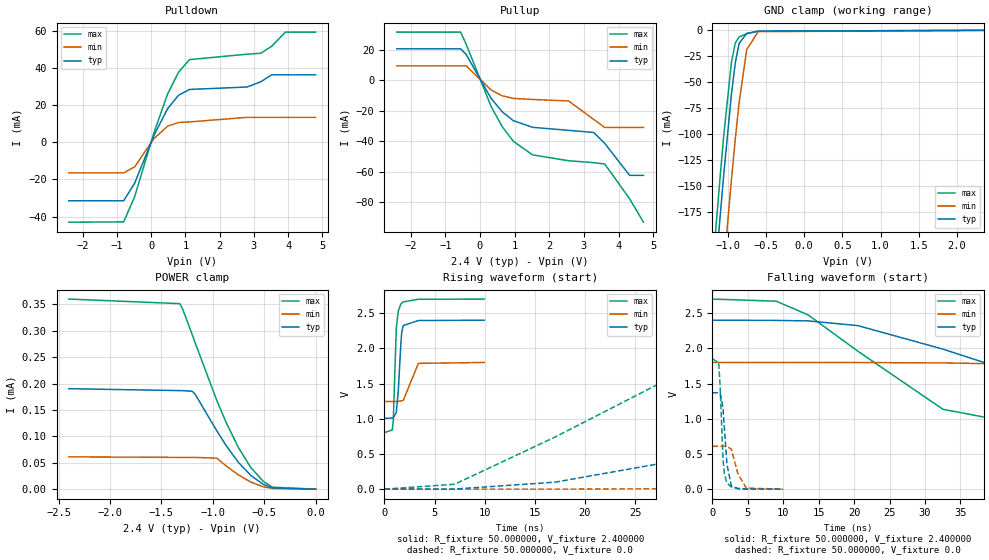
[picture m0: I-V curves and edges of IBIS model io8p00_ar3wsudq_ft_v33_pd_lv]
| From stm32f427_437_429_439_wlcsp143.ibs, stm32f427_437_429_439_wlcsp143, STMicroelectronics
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|   Model io8p00_ar3wsudq_ft_v33_pd_lv
[Model]  io8p00_ar3wsudq_ft_v33_pd_lv
Model_type I/O
Polarity   Non-Inverting
Enable   Active-Low
Vinl =   0.720000V
Vinh =   1.680000V
Vmeas =  1.200000V
Cref =   50.000000pF
Rref =   100.000000M
Vref =   0.0V
C_comp   3.737300pF   3.690400pF   3.817400pF
[Temperature Range]   25.000000   0.125000k   -40.000000
[Pullup Reference]   2.400000V   1.800000V   2.700000V
[Pulldown Reference]   0.0V   0.0V   0.0V
[POWER Clamp Reference]   2.400000V   1.800000V   2.700000V
[GND Clamp Reference]   0.0V   0.0V   0.0V
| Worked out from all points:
|   slope of the pulldown table from 0 to 0.36 V, typ, clamps not added: 25 ohm
|   slope of the pullup table from 0 to 0.36 V, typ, clamps not added: 27.7 ohm
|   GND clamp passes 1 mA (typ) near -0.62 V on its own axis
|   rising waveform, R_fixture 50.000000, V_fixture 2.400000: 20-80 % time 349ps typ, 697ps min, 262ps max; typ from 1 V to 2.4 V
|   rising waveform, R_fixture 50.000000, V_fixture 0.0: 20-80 % time 30.9ns typ, 81.8ns min, 14.6ns max; typ from 0 V to 1.37 V
|   falling waveform, R_fixture 50.000000, V_fixture 2.400000: 20-80 % time 28.8ns typ, 81.1ns min, 15.9ns max; typ from 2.4 V to 1 V
|   falling waveform, R_fixture 50.000000, V_fixture 0.0: 20-80 % time 598ps typ, 1.08ns min, 460ps max; typ from 1.37 V to 0 V
[Pulldown]
|Voltage   I(typ)   I(min)   I(max)
-2.4V     -31.47mA   -16.45mA   -43.01mA
-800mV    -31.47mA   -16.45mA   -42.85mA
-480mV    -21.98mA   -13.17mA   -29.2mA
80mV      3.63mA     1.966mA    5.014mA
480mV     18.15mA    8.738mA    26.02mA
800mV     25.38mA    10.72mA    37.77mA
1.12V     28.53mA    11.02mA    44.6mA
2.8V      29.84mA    13.49mA    47.53mA
3.2V      32.65mA    13.49mA    48.04mA
3.52V     36.4mA     13.49mA    51.82mA
3.92V     36.4mA     13.49mA    59.44mA
4.8V      36.4mA     13.49mA    59.44mA
[Pullup]
|Voltage   I(typ)   I(min)   I(max)
-2.4V     20.88mA    9.66mA     31.89mA
-560mV    20.88mA    9.66mA     31.89mA
-400mV    17.28mA    9.66mA     24.06mA
320mV     -11.75mA   -6.207mA   -17.08mA
640mV     -20.52mA   -10.1mA    -30.35mA
960mV     -26.47mA   -11.82mA   -40.02mA
1.52V     -30.88mA   -12.51mA   -49.05mA
2.56V     -32.88mA   -13.52mA   -52.9mA
3.28V     -34.25mA   -25.62mA   -54.18mA
3.6V      -41.44mA   -30.97mA   -55.03mA
4.32V     -62.55mA   -30.97mA   -77.98mA
4.72V     -62.55mA   -30.97mA   -93.4mA
[GND_clamp]
|Voltage   I(typ)   I(min)   I(max)
-2.4V     -1.437A    -1.518A    -1.411A
-1.25V    -315.9mA   -407.2mA   -278.2mA
-1.2V     -270.1mA   -361.3mA   -232.1mA
-1.15V    -225mA     -316mA     -186.8mA
-1.1V     -180.9mA   -271.3mA   -142.7mA
-1.05V    -138.2mA   -227.5mA   -100.5mA
-950mV    -61.14mA   -143.6mA   -30.44mA
-900mV    -31.24mA   -104.7mA   -12.15mA
-850mV    -12.5mA    -69.41mA   -6.236mA
-750mV    -2.91mA    -18.35mA   -3.195mA
-600mV    -761.5uA   -1.227mA   -751.9uA
2.35V     58.09uA    37.93uA    67.25uA
[POWER_clamp]
|Voltage   I(typ)   I(min)   I(max)
-2.4V     190.2uA    61.19uA    359.9uA
-1.32V    186.6uA    60.14uA    351.2uA
-1.29V    186.5uA    60.13uA    339.6uA
-1.2V     185.4uA    60.11uA    292.6uA
-1.17V    179.2uA    60.11uA    276.3uA
-960mV    110.2uA    58.62uA    167.5uA
-870mV    82.44uA    43.99uA    126.3uA
-750mV    50.58uA    26.92uA    78.64uA
-630mV    25.94uA    13.41uA    41.02uA
-510mV    9.22uA     4.527uA    14.97uA
-420mV    2.425uA    1.38uA     3.75uA
0V        0A         0A         0A
[Ramp]
| variable   typ   min   max
dV/dt_r  0.82164/30.91891n   0.36271/83.80163n   1.11042/14.59118n
dV/dt_f  0.83676/28.74717n   0.32712/81.50714n   1.13681/15.90763n
R_load = 50.000000
[Rising Waveform]
R_fixture= 50.000000
V_fixture= 2.400000
V_fixture_min= 1.800000
V_fixture_max= 2.700000
|time   V(typ)   V(min)   V(max)
0s        1.005V     1.245V     804.1mV
780.8ps   1.01V      1.245V     840.3mV
880.9ps   1.014V     1.245V     966.4mV
1.181ns   1.089V     1.245V     2.284V
1.381ns   1.4V       1.245V     2.531V
1.642ns   2.075V     1.252V     2.629V
1.722ns   2.227V     1.255V     2.641V
1.882ns   2.323V     1.261V     2.659V
3.383ns   2.394V     1.786V     2.696V
9.97ns    2.399V     1.799V     2.699V
[Rising Waveform]
R_fixture= 50.000000
V_fixture= 0.0
V_fixture_min= 0.0
V_fixture_max= 0.0
|time   V(typ)   V(min)   V(max)
0s        9.761nV    346.6nV    28.47nV
7.007ns   1.54mV     -64.27uV   70.11mV
17.02ns   99.44mV    83.53uV    740.5mV
28.03ns   376.7mV    6.55mV     1.543V
34.53ns   556.3mV    13.9mV     1.715V
42.04ns   772.7mV    39.34mV    1.788V
59.56ns   1.171V     98.7mV     1.837V
79.08ns   1.312V     190.1mV    1.847V
153.2ns   1.367V     509.6mV    1.851V
249.2ns   1.369V     608.5mV    1.851V
[Falling Waveform]
R_fixture= 50.000000
V_fixture= 2.400000
V_fixture_min= 1.800000
V_fixture_max= 2.700000
|time   V(typ)   V(min)   V(max)
0s        2.399V     1.799V     2.699V
9.009ns   2.396V     1.798V     2.669V
13.51ns   2.389V     1.798V     2.474V
20.52ns   2.322V     1.798V     1.959V
32.53ns   1.988V     1.793V     1.134V
44.54ns   1.595V     1.771V     904.7mV
58.06ns   1.268V     1.726V     851.9mV
82.58ns   1.086V     1.593V     820.1mV
156.2ns   1.012V     1.324V     804.6mV
249.2ns   1.005V     1.245V     804.1mV
[Falling Waveform]
R_fixture= 50.000000
V_fixture= 0.0
V_fixture_min= 0.0
V_fixture_max= 0.0
|time   V(typ)   V(min)   V(max)
0s        1.369V     608.5mV    1.851V
900.9ps   1.37V      608.3mV    1.796V
1.101ns   1.366V     608.2mV    1.449V
1.502ns   1.15V      607.9mV    430mV
1.702ns   857.3mV    608.1mV    212.3mV
2.062ns   350.1mV    607.9mV    85.53mV
2.683ns   43.62mV    566.1mV    31.54mV
3.584ns   7.834mV    224.6mV    10.48mV
4.785ns   2.189mV    14.68mV    3.209mV
9.97ns    9.761nV    346.6nV    28.47nV
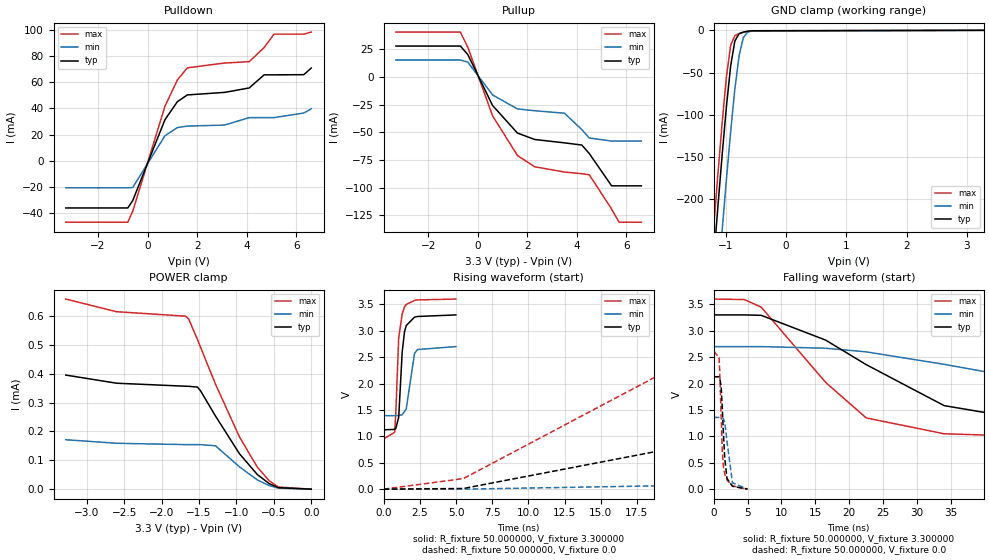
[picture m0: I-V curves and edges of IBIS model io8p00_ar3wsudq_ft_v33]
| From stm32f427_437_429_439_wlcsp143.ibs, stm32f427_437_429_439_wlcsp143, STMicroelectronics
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|   Model io8p00_ar3wsudq_ft_v33
[Model]  io8p00_ar3wsudq_ft_v33
Model_type I/O
Polarity   Non-Inverting
Enable   Active-Low
Vinl =   0.990000V
Vinh =   2.310000V
Vmeas =  1.650000V
Cref =   50.000000pF
Rref =   100.000000M
Vref =   0.0V
C_comp   3.857500pF   3.762100pF   3.941700pF
[Temperature Range]   25.000000   0.125000k   -40.000000
[Pullup Reference]   3.300000V   2.700000V   3.600000V
[Pulldown Reference]   0.0V   0.0V   0.0V
[POWER Clamp Reference]   3.300000V   2.700000V   3.600000V
[GND Clamp Reference]   0.0V   0.0V   0.0V
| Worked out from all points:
|   slope of the pulldown table from 0 to 0.495 V, typ, clamps not added: 20.9 ohm
|   slope of the pullup table from 0 to 0.495 V, typ, clamps not added: 22.6 ohm
|   GND clamp passes 1 mA (typ) near -0.62 V on its own axis
|   rising waveform, R_fixture 50.000000, V_fixture 3.300000: 20-80 % time 277ps typ, 397ps min, 273ps max; typ from 1.12 V to 3.3 V
|   rising waveform, R_fixture 50.000000, V_fixture 0.0: 20-80 % time 19.7ns typ, 51.8ns min, 10.4ns max; typ from 0 V to 2.13 V
|   falling waveform, R_fixture 50.000000, V_fixture 3.300000: 20-80 % time 18.7ns typ, 38.4ns min, 11.3ns max; typ from 3.3 V to 1.12 V
|   falling waveform, R_fixture 50.000000, V_fixture 0.0: 20-80 % time 513ps typ, 709ps min, 438ps max; typ from 2.13 V to 0 V
[Pulldown]
|Voltage   I(typ)   I(min)   I(max)
-3.3V     -36.18mA   -20.77mA   -47.07mA
-800mV    -36.18mA   -20.77mA   -47.07mA
-600mV    -30.5mA    -20.52mA   -38.69mA
700mV     31.4mA     19.11mA    41.71mA
1.2V      45.15mA    25.37mA    61.75mA
1.6V      50.35mA    26.5mA     71.06mA
3.1V      52.28mA    27.26mA    74.76mA
4.1V      55.7mA     32.99mA    75.8mA
4.7V      65.72mA    32.99mA    86.64mA
5.1V      65.72mA    32.99mA    96.89mA
6.3V      65.85mA    36.5mA     96.89mA
6.6V      70.91mA    39.71mA    98.45mA
[Pullup]
|Voltage   I(typ)   I(min)   I(max)
-3.3V     28.03mA    15.43mA    40.67mA
-700mV    28.03mA    15.43mA    40.67mA
-400mV    20.31mA    13.47mA    26.93mA
600mV     -25.77mA   -16.23mA   -35.14mA
1.6V      -50.64mA   -28.81mA   -70.96mA
2.3V      -56.49mA   -30.48mA   -81.16mA
3.5V      -59.53mA   -32.72mA   -85.92mA
4.2V      -61.52mA   -47.6mA    -87.46mA
4.5V      -69.21mA   -55.14mA   -88.43mA
5.4V      -98.4mA    -57.9mA    -119.4mA
5.7V      -98.4mA    -57.9mA    -131.3mA
6.6V      -98.4mA    -57.9mA    -131.3mA
[GND_clamp]
|Voltage   I(typ)   I(min)   I(max)
-3.3V     -2.333A    -2.407A    -2.313A
-1.2V     -270.2mA   -361.4mA   -232.1mA
-1.13V    -207.3mA   -298.1mA   -169mA
-1.06V    -146.7mA   -236.2mA   -108.8mA
-990mV    -90.18mA   -176.4mA   -54.96mA
-920mV    -42.21mA   -120mA     -17.68mA
-850mV    -12.57mA   -69.47mA   -6.265mA
-780mV    -3.971mA   -30.01mA   -3.886mA
-710mV    -2.1mA     -8.615mA   -2.382mA
-640mV    -1.148mA   -2.283mA   -1.22mA
-570mV    -524uA     -821.5uA   -476.8uA
3.28V     0A         0A         0A
[POWER_clamp]
|Voltage   I(typ)   I(min)   I(max)
-3.28V    395.3uA    171.3uA    658.7uA
-2.6V     367.1uA    159uA      614.9uA
-1.68V    356.7uA    154.4uA    599.4uA
-1.64V    356.5uA    154.4uA    590.8uA
-1.52V    353.6uA    154.3uA    518.3uA
-1.48V    341.1uA    154.2uA    492.3uA
-1.28V    253.6uA    150.4uA    364.2uA
-960mV    123.1uA    77.55uA    181.6uA
-720mV    50.52uA    32.03uA    76.18uA
-560mV    18.94uA    12.27uA    28.65uA
-440mV    5.104uA    3.69uA     7.327uA
0V        0A         0A         0A
[Ramp]
| variable   typ   min   max
dV/dt_r  1.27746/19.65175n   0.81588/51.88811n   1.56732/10.37905n
dV/dt_f  1.30614/18.70701n   0.78516/38.53888n   1.58789/11.29546n
R_load = 50.000000
[Rising Waveform]
R_fixture= 50.000000
V_fixture= 3.300000
V_fixture_min= 2.700000
V_fixture_max= 3.600000
|time   V(typ)   V(min)   V(max)
0s        1.124V     1.392V     953.5mV
760.8ps   1.132V     1.392V     1.076V
840.8ps   1.151V     1.391V     1.456V
1.041ns   1.364V     1.395V     2.868V
1.281ns   2.596V     1.409V     3.319V
1.441ns   2.981V     1.47V      3.453V
1.562ns   3.099V     1.521V     3.499V
2.132ns   3.257V     2.57V      3.573V
2.332ns   3.27V      2.644V     3.584V
4.985ns   3.3V       2.7V       3.6V
[Rising Waveform]
R_fixture= 50.000000
V_fixture= 0.0
V_fixture_min= 0.0
V_fixture_max= 0.0
|time   V(typ)   V(min)   V(max)
0s        123nV      341.2nV    642.2nV
5.506ns   12.51mV    -98.27uV   200.2mV
19.02ns   723.2mV    63.71mV    2.159V
24.52ns   1.102V     131.1mV    2.43V
32.03ns   1.585V     254.6mV    2.545V
40.04ns   1.897V     386.3mV    2.579V
55.06ns   2.058V     671.8mV    2.605V
87.09ns   2.117V     1.114V     2.612V
117.6ns   2.129V     1.302V     2.612V
249.2ns   2.129V     1.359V     2.612V
[Falling Waveform]
R_fixture= 50.000000
V_fixture= 3.300000
V_fixture_min= 2.700000
V_fixture_max= 3.600000
|time   V(typ)   V(min)   V(max)
0s        3.3V       2.7V       3.6V
4.505ns   3.3V       2.7V       3.591V
7.007ns   3.292V     2.7V       3.446V
16.52ns   2.823V     2.669V     2.022V
22.52ns   2.358V     2.6V       1.349V
34.03ns   1.582V     2.364V     1.049V
49.55ns   1.246V     2.005V     988.1mV
63.06ns   1.182V     1.721V     967.3mV
90.59ns   1.144V     1.508V     956.1mV
249.2ns   1.124V     1.392V     953.5mV
[Falling Waveform]
R_fixture= 50.000000
V_fixture= 0.0
V_fixture_min= 0.0
V_fixture_max= 0.0
|time   V(typ)   V(min)   V(max)
0s        2.129V     1.359V     2.612V
780.8ps   2.127V     1.358V     2.49V
860.9ps   2.119V     1.358V     2.294V
1.091ns   1.943V     1.358V     1.362V
1.261ns   1.524V     1.354V     724.3mV
1.411ns   1.094V     1.342V     441mV
1.622ns   576.2mV    1.263V     285.2mV
1.962ns   200.1mV    894.1mV    172.1mV
2.763ns   54.16mV    120.1mV    64.24mV
4.985ns   123nV      341.2nV    642.2nV
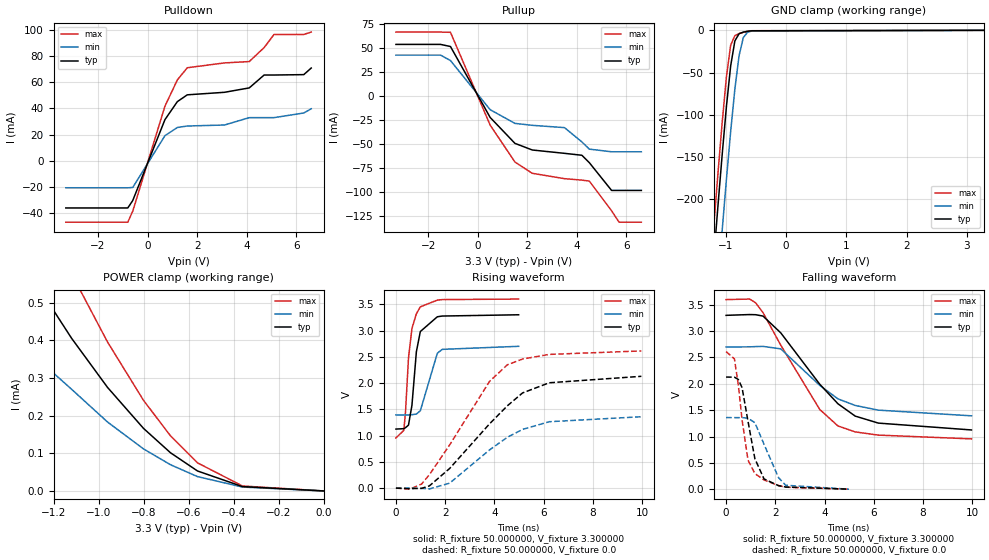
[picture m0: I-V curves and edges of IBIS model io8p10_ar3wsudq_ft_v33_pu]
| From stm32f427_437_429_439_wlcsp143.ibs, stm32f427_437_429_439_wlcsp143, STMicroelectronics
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|   Model io8p10_ar3wsudq_ft_v33_pu
[Model]  io8p10_ar3wsudq_ft_v33_pu
Model_type I/O
Polarity   Non-Inverting
Enable   Active-Low
Vinl =   0.990000V
Vinh =   2.310000V
Vmeas =  1.650000V
Cref =   40.000000pF
Rref =   100.000000M
Vref =   0.0V
C_comp   3.857500pF   3.760500pF   3.941700pF
[Temperature Range]   25.000000   0.125000k   -40.000000
[Pullup Reference]   3.300000V   2.700000V   3.600000V
[Pulldown Reference]   0.0V   0.0V   0.0V
[POWER Clamp Reference]   3.300000V   2.700000V   3.600000V
[GND Clamp Reference]   0.0V   0.0V   0.0V
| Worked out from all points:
|   slope of the pulldown table from 0 to 0.495 V, typ, clamps not added: 20.9 ohm
|   slope of the pullup table from 0 to 0.495 V, typ, clamps not added: 22.6 ohm
|   GND clamp passes 1 mA (typ) near -0.62 V on its own axis
|   POWER clamp passes 1 mA (typ) near -1.88 V on its own axis
|   rising waveform, R_fixture 50.000000, V_fixture 3.300000: 20-80 % time 276ps typ, 399ps min, 273ps max; typ from 1.12 V to 3.3 V
|   rising waveform, R_fixture 50.000000, V_fixture 0.0: 20-80 % time 2.56ns typ, 2.3ns min, 2.13ns max; typ from 0.001 V to 2.13 V
|   falling waveform, R_fixture 50.000000, V_fixture 3.300000: 20-80 % time 2.28ns typ, 2.12ns min, 2.02ns max; typ from 3.3 V to 1.12 V
|   falling waveform, R_fixture 50.000000, V_fixture 0.0: 20-80 % time 517ps typ, 710ps min, 442ps max; typ from 2.13 V to 0.001 V
[Pulldown]
|Voltage   I(typ)   I(min)   I(max)
-3.3V     -36.18mA   -20.77mA   -47.07mA
-800mV    -36.18mA   -20.77mA   -47.07mA
-600mV    -30.5mA    -20.52mA   -38.69mA
700mV     31.4mA     19.11mA    41.71mA
1.2V      45.15mA    25.37mA    61.75mA
1.6V      50.35mA    26.5mA     71.06mA
3.1V      52.28mA    27.26mA    74.76mA
4.1V      55.65mA    32.9mA     75.79mA
4.7V      65.5mA     32.9mA     86.49mA
5.1V      65.5mA     32.9mA     96.53mA
6.3V      65.8mA     36.47mA    96.53mA
6.6V      70.85mA    39.68mA    98.34mA
[Pullup]
|Voltage   I(typ)   I(min)   I(max)
-3.3V     54.04mA    42.87mA    66.88mA
-1.5V     54.04mA    42.87mA    66.88mA
-1.1V     51.84mA    37.21mA    66.66mA
500mV     -22.06mA   -14mA      -30.03mA
1.5V      -49.1mA    -28.3mA    -68.56mA
2.2V      -56.04mA   -30.32mA   -80.35mA
3.5V      -59.52mA   -32.72mA   -85.91mA
4.2V      -61.52mA   -47.6mA    -87.45mA
4.5V      -69.2mA    -55.14mA   -88.43mA
5.4V      -98.2mA    -57.9mA    -119.4mA
5.7V      -98.2mA    -57.9mA    -131.3mA
6.6V      -98.2mA    -57.9mA    -131.3mA
[GND_clamp]
|Voltage   I(typ)   I(min)   I(max)
-3.3V     -2.333A    -2.407A    -2.313A
-1.2V     -270.2mA   -361.4mA   -232.1mA
-1.13V    -207.3mA   -298.1mA   -169mA
-1.06V    -146.7mA   -236.2mA   -108.8mA
-990mV    -90.18mA   -176.4mA   -54.96mA
-920mV    -42.21mA   -120mA     -17.68mA
-850mV    -12.57mA   -69.47mA   -6.265mA
-780mV    -3.971mA   -30.01mA   -3.886mA
-710mV    -2.1mA     -8.615mA   -2.382mA
-640mV    -1.148mA   -2.283mA   -1.22mA
-570mV    -524uA     -821.5uA   -476.8uA
3.28V     0A         0A         0A
[POWER_clamp]
|Voltage   I(typ)   I(min)   I(max)
-3.28V    1.18mA     571.5uA    1.791mA
-3.08V    1.154mA    558.1uA    1.753mA
-1.84V    973.4uA    557.7uA    1.433mA
-1.32V    593.1uA    370.2uA    831.6uA
-1.28V    553.9uA    355.9uA    778.7uA
-1.12V    406uA      270.4uA    577.3uA
-960mV    275.2uA    183.2uA    395.9uA
-800mV    166.2uA    111.7uA    240.7uA
-680mV    101.4uA    69.6uA     146.3uA
-560mV    53.02uA    38.04uA    74.62uA
-360mV    11.49uA    10.29uA    13.1uA
0V        0A         0A         0A
[Ramp]
| variable   typ   min   max
dV/dt_r  1.26865/2.56356n   0.81309/2.32076n   1.56544/2.13478n
dV/dt_f  1.28424/2.27464n   0.77712/2.11344n   1.57500/2.02473n
R_load = 50.000000
[Rising Waveform]
R_fixture= 50.000000
V_fixture= 3.300000
V_fixture_min= 2.700000
V_fixture_max= 3.600000
|time   V(typ)   V(min)   V(max)
0s        1.125V     1.393V     955.5mV
320.3ps   1.133V     1.393V     1.1V
390.4ps   1.152V     1.393V     1.457V
510.5ps   1.201V     1.394V     2.481V
650.7ps   1.578V     1.399V     3.039V
830.8ps   2.596V     1.411V     3.319V
991ps     2.981V     1.473V     3.451V
1.682ns   3.262V     2.568V     3.579V
1.882ns   3.276V     2.642V     3.589V
4.985ns   3.3V       2.7V       3.599V
[Rising Waveform]
R_fixture= 50.000000
V_fixture= 0.0
V_fixture_min= 0.0
V_fixture_max= 0.0
|time   V(typ)   V(min)   V(max)
0s        1.284mV    1.127mV    1.85mV
560.6ps   -8.608mV   984.2uV    -18.37mV
1.041ns   -3.407mV   -3.558mV   78.58mV
1.361ns   44.45mV    -13.92mV   256.9mV
2.182ns   375.2mV    95.85mV    823.6mV
3.804ns   1.225V     728.9mV    2.033V
4.525ns   1.567V     968.2mV    2.348V
5.145ns   1.813V     1.119V     2.458V
6.226ns   2.006V     1.265V     2.546V
9.97ns    2.129V     1.36V      2.612V
[Falling Waveform]
R_fixture= 50.000000
V_fixture= 3.300000
V_fixture_min= 2.700000
V_fixture_max= 3.600000
|time   V(typ)   V(min)   V(max)
0s        3.3V       2.7V       3.599V
961ps     3.315V     2.702V     3.609V
1.201ns   3.312V     2.707V     3.538V
1.502ns   3.286V     2.711V     3.352V
2.222ns   2.968V     2.664V     2.734V
3.804ns   1.994V     1.972V     1.515V
4.545ns   1.622V     1.715V     1.201V
5.245ns   1.388V     1.59V      1.088V
6.186ns   1.255V     1.501V     1.027V
9.97ns    1.125V     1.393V     955.5mV
[Falling Waveform]
R_fixture= 50.000000
V_fixture= 0.0
V_fixture_min= 0.0
V_fixture_max= 0.0
|time   V(typ)   V(min)   V(max)
0s        2.129V     1.36V      2.612V
340.3ps   2.126V     1.359V     2.474V
500.5ps   2.082V     1.359V     1.971V
650.7ps   1.927V     1.359V     1.316V
890.9ps   1.293V     1.348V     553.2mV
1.171ns   578.3mV    1.263V     297.1mV
1.542ns   196mV      853.8mV    175.2mV
2.132ns   67.97mV    220.1mV    69.64mV
2.422ns   41.74mV    74.93mV    38.22mV
4.985ns   1.284mV    1.127mV    1.85mV
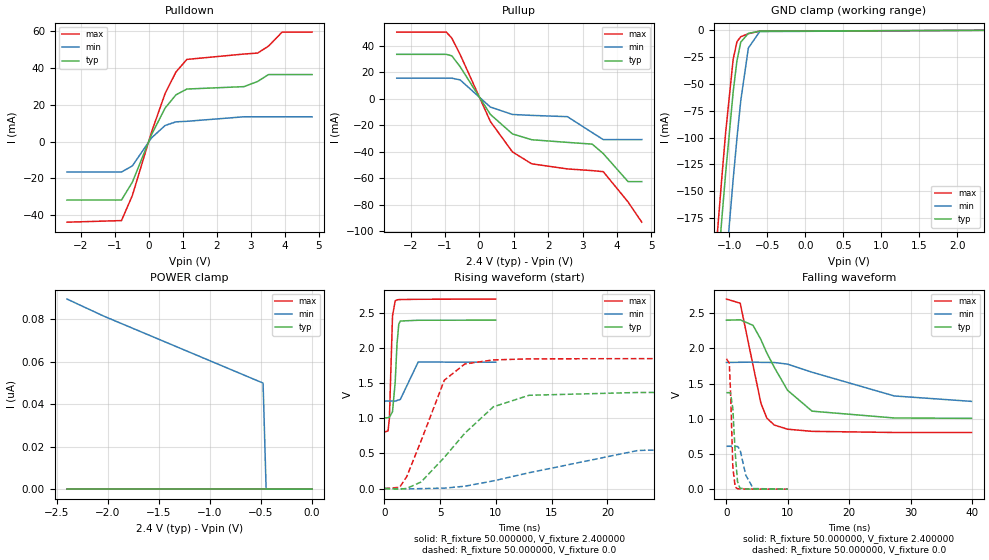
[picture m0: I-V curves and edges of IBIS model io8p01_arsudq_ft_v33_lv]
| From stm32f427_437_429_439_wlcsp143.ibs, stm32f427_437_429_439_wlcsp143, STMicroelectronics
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|   Model io8p01_arsudq_ft_v33_lv
[Model]  io8p01_arsudq_ft_v33_lv
Model_type I/O
Polarity   Non-Inverting
Enable   Active-Low
Vinl =   0.720000V
Vinh =   1.680000V
Vmeas =  1.200000V
Cref =   50.000000pF
Rref =   100.000000M
Vref =   0.0V
C_comp   2.238700pF   2.180600pF   2.332300pF
[Temperature Range]   25.000000   0.125000k   -40.000000
[Pullup Reference]   2.400000V   1.800000V   2.700000V
[Pulldown Reference]   0.0V   0.0V   0.0V
[POWER Clamp Reference]   2.400000V   1.800000V   2.700000V
[GND Clamp Reference]   0.0V   0.0V   0.0V
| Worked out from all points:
|   slope of the pulldown table from 0 to 0.36 V, typ, clamps not added: 25 ohm
|   slope of the pullup table from 0 to 0.36 V, typ, clamps not added: 27.7 ohm
|   GND clamp passes 1 mA (typ) near -0.62 V on its own axis
|   rising waveform, R_fixture 50.000000, V_fixture 2.400000: 20-80 % time 302ps typ, 741ps min, 199ps max; typ from 1.01 V to 2.4 V
|   rising waveform, R_fixture 50.000000, V_fixture 0.0: 20-80 % time 4.9ns typ, 9.96ns min, 2.66ns max; typ from 0 V to 1.37 V
|   falling waveform, R_fixture 50.000000, V_fixture 2.400000: 20-80 % time 5.51ns typ, 12.6ns min, 2.64ns max; typ from 2.4 V to 1.01 V
|   falling waveform, R_fixture 50.000000, V_fixture 0.0: 20-80 % time 534ps typ, 1.03ns min, 386ps max; typ from 1.37 V to 0 V
[Pulldown]
|Voltage   I(typ)   I(min)   I(max)
-2.4V     -31.73mA   -16.51mA   -43.74mA
-800mV    -31.73mA   -16.51mA   -42.87mA
-480mV    -21.98mA   -13.17mA   -29.21mA
80mV      3.63mA     1.966mA    5.014mA
480mV     18.16mA    8.738mA    26.02mA
800mV     25.38mA    10.72mA    37.77mA
1.12V     28.53mA    11.02mA    44.6mA
2.8V      29.84mA    13.47mA    47.53mA
3.2V      32.64mA    13.47mA    48.05mA
3.52V     36.39mA    13.47mA    51.83mA
3.92V     36.39mA    13.47mA    59.44mA
4.8V      36.39mA    13.47mA    59.44mA
[Pullup]
|Voltage   I(typ)   I(min)   I(max)
-2.4V     33.56mA    15.56mA    50.34mA
-960mV    33.56mA    15.56mA    50.34mA
-800mV    32.44mA    15.56mA    45.79mA
-560mV    24.29mA    14.3mA     33.55mA
320mV     -11.75mA   -6.207mA   -17.08mA
960mV     -26.47mA   -11.82mA   -40.02mA
1.52V     -30.88mA   -12.51mA   -49.05mA
2.56V     -32.88mA   -13.48mA   -52.9mA
3.28V     -34.19mA   -25.51mA   -54.18mA
3.6V      -41.31mA   -30.75mA   -54.97mA
4.32V     -62.47mA   -30.75mA   -77.8mA
4.72V     -62.47mA   -30.75mA   -93.1mA
[GND_clamp]
|Voltage   I(typ)   I(min)   I(max)
-2.4V     -1.424A    -1.508A    -1.394A
-1.25V    -311.2mA   -401.9mA   -273.3mA
-1.2V     -265.4mA   -356.1mA   -227.2mA
-1.15V    -220.4mA   -310.8mA   -181.9mA
-1.1V     -176.3mA   -266.2mA   -137.9mA
-1.05V    -133.8mA   -222.5mA   -95.87mA
-950mV    -57.3mA    -138.9mA   -26.98mA
-900mV    -28.27mA   -100.4mA   -10.59mA
-850mV    -11.01mA   -65.54mA   -5.958mA
-750mV    -2.834mA   -16.5mA    -3.178mA
-600mV    -750uA     -1.164mA   -738.3uA
2.35V     0A         0A         0A
[POWER_clamp]
|Voltage   I(typ)   I(min)   I(max)
-2.4V     0A         89.62nA    0A
-2.04V    0A         81.57nA    0A
-480mV    0A         50.01nA    0A
-450mV    0A         0A         0A
0V        0A         0A         0A
[Ramp]
| variable   typ   min   max
dV/dt_r  0.82230/4.90012n   0.36466/9.97943n   1.11102/2.65313n
dV/dt_f  0.83742/5.51561n   0.32238/12.65743n   1.13729/2.63895n
R_load = 50.000000
[Rising Waveform]
R_fixture= 50.000000
V_fixture= 2.400000
V_fixture_min= 1.800000
V_fixture_max= 2.700000
|time   V(typ)   V(min)   V(max)
0s        1.006V     1.247V     804.9mV
320.3ps   1.01V      1.247V     823.1mV
440.4ps   1.016V     1.247V     998.4mV
720.7ps   1.095V     1.247V     2.461V
961ps     1.515V     1.246V     2.674V
1.121ns   2.055V     1.255V     2.689V
1.281ns   2.341V     1.263V     2.692V
1.421ns   2.387V     1.27V      2.693V
3.023ns   2.398V     1.803V     2.697V
9.97ns    2.4V       1.8V       2.7V
[Rising Waveform]
R_fixture= 50.000000
V_fixture= 0.0
V_fixture_min= 0.0
V_fixture_max= 0.0
|time   V(typ)   V(min)   V(max)
0s        85.02uV    35.48uV    197.3uV
1.361ns   -8.671mV   -381.4uV   17.59mV
2.002ns   2.237mV    -5.156mV   171.2mV
3.283ns   93.41mV    -544.3uV   679.4mV
5.365ns   443mV      5.672mV    1.543V
7.207ns   788.6mV    33.23mV    1.775V
9.77ns    1.165V     109.4mV    1.833V
12.97ns   1.329V     225.1mV    1.848V
22.74ns   1.369V     542.9mV    1.851V
39.88ns   1.37V      609.1mV    1.851V
[Falling Waveform]
R_fixture= 50.000000
V_fixture= 2.400000
V_fixture_min= 1.800000
V_fixture_max= 2.700000
|time   V(typ)   V(min)   V(max)
0s        2.4V       1.8V       2.7V
2.242ns   2.405V     1.802V     2.641V
4.324ns   2.327V     1.804V     1.761V
5.606ns   2.125V     1.801V     1.222V
6.567ns   1.936V     1.8V       1.01V
7.768ns   1.733V     1.799V     911.5mV
9.93ns    1.406V     1.776V     851.8mV
13.93ns   1.108V     1.661V     821.1mV
27.31ns   1.011V     1.324V     805mV
39.88ns   1.006V     1.247V     804.9mV
[Falling Waveform]
R_fixture= 50.000000
V_fixture= 0.0
V_fixture_min= 0.0
V_fixture_max= 0.0
|time   V(typ)   V(min)   V(max)
0s        1.37V      609.1mV    1.851V
460.5ps   1.371V     609mV      1.79V
660.7ps   1.366V     608.9mV    1.398V
1.041ns   1.145V     608.6mV    311.2mV
1.421ns   522.3mV    609.5mV    31.05mV
1.802ns   107.2mV    606.2mV    6.965mV
2.202ns   14.25mV    565mV      3.617mV
3.143ns   1.993mV    199.7mV    2.02mV
4.364ns   1.129mV    8.676mV    1.136mV
9.97ns    85.02uV    35.48uV    197.3uV
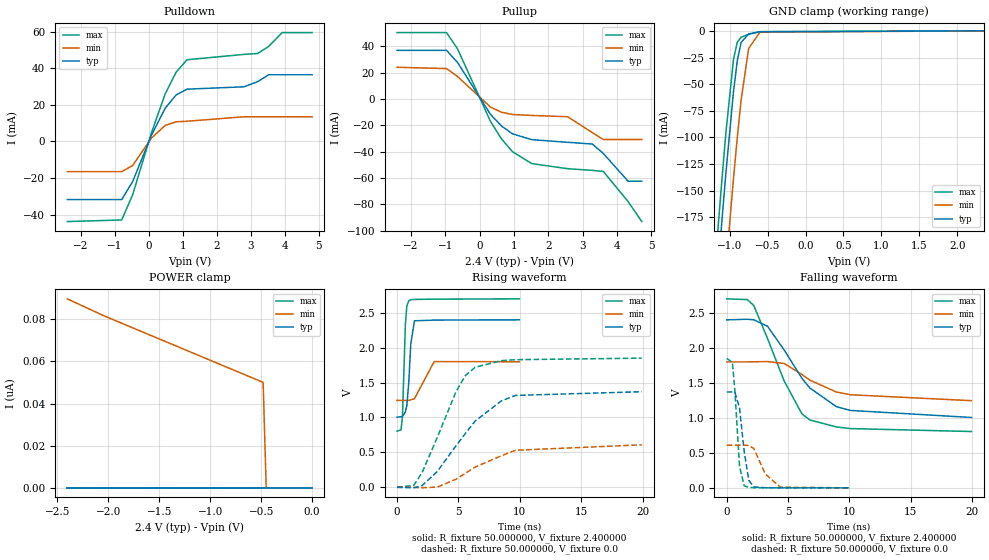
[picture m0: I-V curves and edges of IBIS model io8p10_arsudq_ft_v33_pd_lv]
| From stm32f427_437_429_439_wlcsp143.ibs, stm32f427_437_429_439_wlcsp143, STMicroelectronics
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|   Model io8p10_arsudq_ft_v33_pd_lv
[Model]  io8p10_arsudq_ft_v33_pd_lv
Model_type I/O
Polarity   Non-Inverting
Enable   Active-Low
Vinl =   0.720000V
Vinh =   1.680000V
Vmeas =  1.200000V
Cref =   40.000000pF
Rref =   100.000000M
Vref =   0.0V
C_comp   2.238700pF   2.180600pF   2.332300pF
[Temperature Range]   25.000000   0.125000k   -40.000000
[Pullup Reference]   2.400000V   1.800000V   2.700000V
[Pulldown Reference]   0.0V   0.0V   0.0V
[POWER Clamp Reference]   2.400000V   1.800000V   2.700000V
[GND Clamp Reference]   0.0V   0.0V   0.0V
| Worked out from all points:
|   slope of the pulldown table from 0 to 0.36 V, typ, clamps not added: 25 ohm
|   slope of the pullup table from 0 to 0.36 V, typ, clamps not added: 27.7 ohm
|   GND clamp passes 1 mA (typ) near -0.62 V on its own axis
|   rising waveform, R_fixture 50.000000, V_fixture 2.400000: 20-80 % time 303ps typ, 746ps min, 199ps max; typ from 1 V to 2.4 V
|   rising waveform, R_fixture 50.000000, V_fixture 0.0: 20-80 % time 3.77ns typ, 4.16ns min, 2.69ns max; typ from 0 V to 1.37 V
|   falling waveform, R_fixture 50.000000, V_fixture 2.400000: 20-80 % time 3.57ns typ, 3.55ns min, 2.74ns max; typ from 2.4 V to 1 V
|   falling waveform, R_fixture 50.000000, V_fixture 0.0: 20-80 % time 534ps typ, 1.04ns min, 386ps max; typ from 1.37 V to 0 V
[Pulldown]
|Voltage   I(typ)   I(min)   I(max)
-2.4V     -31.73mA   -16.51mA   -43.74mA
-800mV    -31.73mA   -16.51mA   -42.87mA
-480mV    -21.98mA   -13.17mA   -29.2mA
80mV      3.63mA     1.966mA    5.014mA
480mV     18.15mA    8.738mA    26.02mA
800mV     25.38mA    10.72mA    37.77mA
1.12V     28.53mA    11.02mA    44.6mA
2.8V      29.84mA    13.47mA    47.53mA
3.2V      32.64mA    13.47mA    48.04mA
3.52V     36.39mA    13.47mA    51.82mA
3.92V     36.39mA    13.47mA    59.43mA
4.8V      36.39mA    13.47mA    59.43mA
[Pullup]
|Voltage   I(typ)   I(min)   I(max)
-2.4V     36.88mA    24.03mA    50.34mA
-960mV    36.88mA    23.04mA    50.34mA
-640mV    27.65mA    17.03mA    37.99mA
320mV     -11.75mA   -6.207mA   -17.08mA
640mV     -20.52mA   -10.1mA    -30.35mA
960mV     -26.47mA   -11.82mA   -40.02mA
1.52V     -30.88mA   -12.51mA   -49.05mA
2.56V     -32.88mA   -13.48mA   -52.9mA
3.28V     -34.19mA   -25.5mA    -54.18mA
3.6V      -41.31mA   -30.74mA   -54.97mA
4.32V     -62.39mA   -30.74mA   -77.8mA
4.72V     -62.39mA   -30.74mA   -93mA
[GND_clamp]
|Voltage   I(typ)   I(min)   I(max)
-2.4V     -1.424A    -1.508A    -1.394A
-1.25V    -311.2mA   -401.9mA   -273.3mA
-1.2V     -265.4mA   -356.1mA   -227.2mA
-1.15V    -220.4mA   -310.8mA   -181.9mA
-1.1V     -176.3mA   -266.2mA   -137.9mA
-1.05V    -133.8mA   -222.5mA   -95.87mA
-950mV    -57.3mA    -138.9mA   -26.99mA
-900mV    -28.28mA   -100.4mA   -10.6mA
-850mV    -11.02mA   -65.54mA   -5.972mA
-750mV    -2.846mA   -16.51mA   -3.192mA
-600mV    -761.3uA   -1.173mA   -751.9uA
2.35V     58.09uA    37.92uA    67.25uA
[POWER_clamp]
|Voltage   I(typ)   I(min)   I(max)
-2.4V     0A         89.62nA    0A
-2.04V    0A         81.57nA    0A
-480mV    0A         50.01nA    0A
-450mV    0A         0A         0A
0V        0A         0A         0A
[Ramp]
| variable   typ   min   max
dV/dt_r  0.82152/3.76780n   0.36550/4.16535n   1.11354/2.69964n
dV/dt_f  0.83376/3.57769n   0.33414/3.59897n   1.13623/2.74074n
R_load = 50.000000
[Rising Waveform]
R_fixture= 50.000000
V_fixture= 2.400000
V_fixture_min= 1.800000
V_fixture_max= 2.700000
|time   V(typ)   V(min)   V(max)
0s        1.005V     1.245V     804.5mV
320.3ps   1.01V      1.245V     822.5mV
440.4ps   1.015V     1.245V     1.001V
680.7ps   1.08V      1.245V     2.331V
800.8ps   1.171V     1.245V     2.598V
961ps     1.513V     1.245V     2.672V
1.121ns   2.054V     1.253V     2.687V
1.421ns   2.385V     1.269V     2.691V
3.023ns   2.395V     1.8V       2.695V
9.97ns    2.399V     1.799V     2.699V
[Rising Waveform]
R_fixture= 50.000000
V_fixture= 0.0
V_fixture_min= 0.0
V_fixture_max= 0.0
|time   V(typ)   V(min)   V(max)
0s        75.03uV    35.24uV    234.9uV
1.361ns   -7.739mV   -507.1uV   28.08mV
2.042ns   23.59mV    -6.464mV   210.7mV
3.283ns   227.4mV    3.255mV    716.1mV
4.805ns   595.4mV    116mV      1.37V
5.566ns   770.1mV    200.9mV    1.601V
6.366ns   948.7mV    290.4mV    1.719V
8.488ns   1.237V     450.2mV    1.814V
9.65ns    1.316V     530.7mV    1.828V
19.94ns   1.369V     608.5mV    1.85V
[Falling Waveform]
R_fixture= 50.000000
V_fixture= 2.400000
V_fixture_min= 1.800000
V_fixture_max= 2.700000
|time   V(typ)   V(min)   V(max)
0s        2.399V     1.799V     2.699V
1.682ns   2.408V     1.799V     2.689V
2.202ns   2.4V       1.801V     2.604V
3.323ns   2.308V     1.803V     2.133V
4.685ns   1.967V     1.776V     1.524V
6.126ns   1.565V     1.619V     1.056V
6.767ns   1.427V     1.538V     969.7mV
8.929ns   1.16V      1.369V     870.1mV
10.05ns   1.106V     1.33V      846.5mV
19.94ns   1.005V     1.245V     804.5mV
[Falling Waveform]
R_fixture= 50.000000
V_fixture= 0.0
V_fixture_min= 0.0
V_fixture_max= 0.0
|time   V(typ)   V(min)   V(max)
0s        1.369V     608.5mV    1.85V
460.5ps   1.37V      608.3mV    1.789V
660.7ps   1.365V     608.2mV    1.395V
1.041ns   1.144V     608mV      311.2mV
1.421ns   520.2mV    608.9mV    29mV
1.802ns   105.6mV    604.9mV    5.493mV
2.202ns   13.52mV    562.8mV    2.496mV
3.143ns   1.822mV    198.3mV    1.459mV
4.364ns   959.6uV    9.504mV    935.4uV
9.97ns    75.03uV    35.24uV    234.9uV
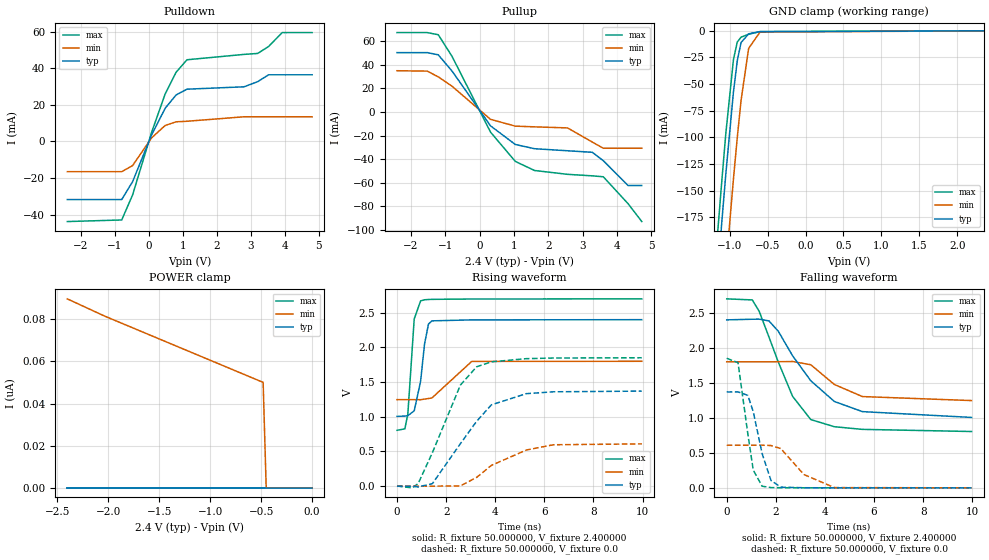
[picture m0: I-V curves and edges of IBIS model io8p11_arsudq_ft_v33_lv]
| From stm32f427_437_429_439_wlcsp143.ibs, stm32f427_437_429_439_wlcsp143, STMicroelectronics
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|   Model io8p11_arsudq_ft_v33_lv
[Model]  io8p11_arsudq_ft_v33_lv
Model_type I/O
Polarity   Non-Inverting
Enable   Active-Low
Vinl =   0.720000V
Vinh =   1.680000V
Vmeas =  1.200000V
Cref =   30.000000pF
Rref =   100.000000M
Vref =   0.0V
C_comp   2.238700pF   2.180600pF   2.332300pF
[Temperature Range]   25.000000   0.125000k   -40.000000
[Pullup Reference]   2.400000V   1.800000V   2.700000V
[Pulldown Reference]   0.0V   0.0V   0.0V
[POWER Clamp Reference]   2.400000V   1.800000V   2.700000V
[GND Clamp Reference]   0.0V   0.0V   0.0V
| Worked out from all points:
|   slope of the pulldown table from 0 to 0.36 V, typ, clamps not added: 25 ohm
|   slope of the pullup table from 0 to 0.36 V, typ, clamps not added: 27.7 ohm
|   GND clamp passes 1 mA (typ) near -0.62 V on its own axis
|   rising waveform, R_fixture 50.000000, V_fixture 2.400000: 20-80 % time 304ps typ, 753ps min, 197ps max; typ from 1.01 V to 2.4 V
|   rising waveform, R_fixture 50.000000, V_fixture 0.0: 20-80 % time 1.7ns typ, 1.57ns min, 1.32ns max; typ from 0 V to 1.37 V
|   falling waveform, R_fixture 50.000000, V_fixture 2.400000: 20-80 % time 1.93ns typ, 1.44ns min, 1.38ns max; typ from 2.4 V to 1.01 V
|   falling waveform, R_fixture 50.000000, V_fixture 0.0: 20-80 % time 535ps typ, 997ps min, 390ps max; typ from 1.37 V to 0 V
[Pulldown]
|Voltage   I(typ)   I(min)   I(max)
-2.4V     -31.73mA   -16.51mA   -43.74mA
-800mV    -31.73mA   -16.51mA   -42.87mA
-480mV    -21.98mA   -13.17mA   -29.21mA
80mV      3.63mA     1.966mA    5.014mA
480mV     18.16mA    8.738mA    26.02mA
800mV     25.38mA    10.72mA    37.77mA
1.12V     28.53mA    11.02mA    44.6mA
2.8V      29.84mA    13.47mA    47.53mA
3.2V      32.64mA    13.47mA    48.05mA
3.52V     36.39mA    13.47mA    51.83mA
3.92V     36.39mA    13.47mA    59.44mA
4.8V      36.39mA    13.47mA    59.44mA
[Pullup]
|Voltage   I(typ)   I(min)   I(max)
-2.4V     50.45mA    35.08mA    67.47mA
-1.52V    50.45mA    34.74mA    67.47mA
-1.2V     48.6mA     29.87mA    65.63mA
-800mV    34.81mA    21.93mA    47.29mA
320mV     -11.75mA   -6.207mA   -17.08mA
1.04V     -27.54mA   -11.97mA   -41.91mA
1.6V      -31.14mA   -12.58mA   -49.63mA
2.56V     -32.88mA   -13.48mA   -52.9mA
3.28V     -34.19mA   -25.5mA    -54.18mA
3.6V      -41.31mA   -30.74mA   -54.97mA
4.32V     -62.39mA   -30.74mA   -77.8mA
4.72V     -62.39mA   -30.74mA   -93mA
[GND_clamp]
|Voltage   I(typ)   I(min)   I(max)
-2.4V     -1.424A    -1.508A    -1.394A
-1.25V    -311.2mA   -401.9mA   -273.3mA
-1.2V     -265.4mA   -356.1mA   -227.2mA
-1.15V    -220.4mA   -310.8mA   -181.9mA
-1.1V     -176.3mA   -266.2mA   -137.9mA
-1.05V    -133.8mA   -222.5mA   -95.87mA
-950mV    -57.3mA    -138.9mA   -26.98mA
-900mV    -28.27mA   -100.4mA   -10.59mA
-850mV    -11.01mA   -65.54mA   -5.958mA
-750mV    -2.834mA   -16.5mA    -3.178mA
-600mV    -750uA     -1.164mA   -738.3uA
2.35V     0A         0A         0A
[POWER_clamp]
|Voltage   I(typ)   I(min)   I(max)
-2.4V     0A         89.62nA    0A
-2.04V    0A         81.57nA    0A
-480mV    0A         50.01nA    0A
-450mV    0A         0A         0A
0V        0A         0A         0A
[Ramp]
| variable   typ   min   max
dV/dt_r  0.82188/1.69587n   0.36891/1.63504n   1.11222/1.31799n
dV/dt_f  0.83652/1.93802n   0.33210/1.44193n   1.13632/1.38141n
R_load = 50.000000
[Rising Waveform]
R_fixture= 50.000000
V_fixture= 2.400000
V_fixture_min= 1.800000
V_fixture_max= 2.700000
|time   V(typ)   V(min)   V(max)
0s        1.006V     1.247V     804.9mV
320.3ps   1.01V      1.247V     826.5mV
440.4ps   1.016V     1.247V     1.039V
700.7ps   1.086V     1.247V     2.411V
961ps     1.512V     1.246V     2.671V
1.121ns   2.051V     1.255V     2.687V
1.281ns   2.336V     1.263V     2.691V
1.421ns   2.383V     1.271V     2.693V
3.043ns   2.397V     1.798V     2.698V
9.97ns    2.4V       1.8V       2.7V
[Rising Waveform]
R_fixture= 50.000000
V_fixture= 0.0
V_fixture_min= 0.0
V_fixture_max= 0.0
|time   V(typ)   V(min)   V(max)
0s        75.44uV    35uV       229.7uV
620.6ps   -2.456mV   18.45uV    -24.79mV
860.9ps   -11.41mV   62.07uV    36.42mV
1.441ns   35.93mV    -774.6uV   483mV
2.583ns   612.8mV    3.807mV    1.458V
3.243ns   935.1mV    125.6mV    1.721V
3.844ns   1.172V     299.2mV    1.792V
5.265ns   1.333V     520.3mV    1.838V
6.366ns   1.36V      596.4mV    1.847V
9.97ns    1.37V      609.1mV    1.851V
[Falling Waveform]
R_fixture= 50.000000
V_fixture= 2.400000
V_fixture_min= 1.800000
V_fixture_max= 2.700000
|time   V(typ)   V(min)   V(max)
0s        2.4V       1.8V       2.7V
1.041ns   2.409V     1.8V       2.685V
1.321ns   2.41V      1.8V       2.523V
1.722ns   2.385V     1.8V       2.153V
2.102ns   2.236V     1.802V     1.796V
2.683ns   1.887V     1.805V     1.307V
3.423ns   1.53V      1.759V     975.8mV
4.384ns   1.234V     1.477V     873.3mV
5.526ns   1.089V     1.304V     835.5mV
9.97ns    1.006V     1.247V     804.9mV
[Falling Waveform]
R_fixture= 50.000000
V_fixture= 0.0
V_fixture_min= 0.0
V_fixture_max= 0.0
|time   V(typ)   V(min)   V(max)
0s        1.37V      609.1mV    1.851V
460.5ps   1.371V     609mV      1.788V
860.9ps   1.321V     608.8mV    767.7mV
1.081ns   1.088V     608.7mV    252.8mV
1.441ns   490.1mV    609.6mV    23.51mV
1.802ns   106mV      604.6mV    3.648mV
2.202ns   9.859mV    561.3mV    1.961mV
3.143ns   1.587mV    190.4mV    1.152mV
4.384ns   780.8uV    3.86mV     738.3uV
9.97ns    75.44uV    35uV       229.7uV
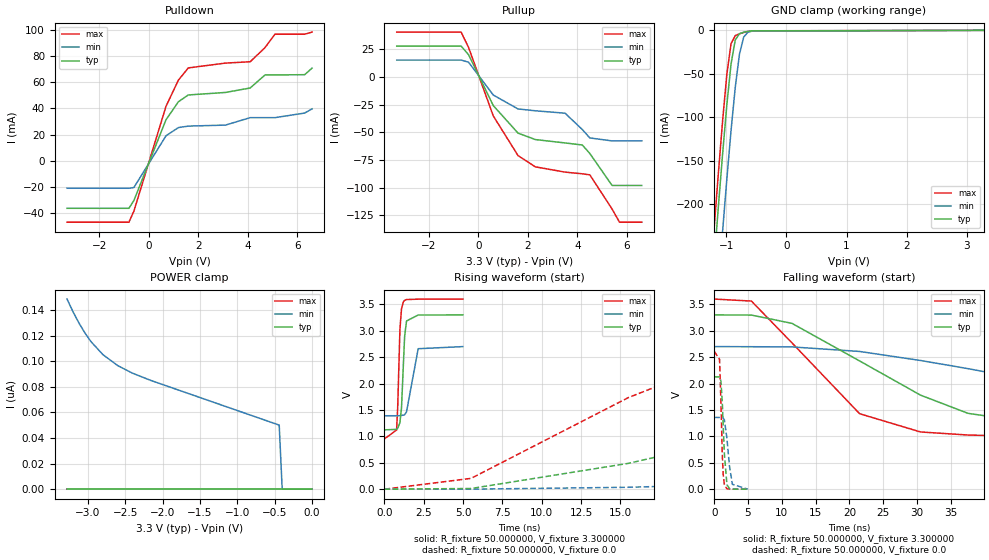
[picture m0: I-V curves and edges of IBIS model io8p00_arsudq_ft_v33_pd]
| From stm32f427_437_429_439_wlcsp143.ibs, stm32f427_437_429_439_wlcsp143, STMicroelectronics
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|   Model io8p00_arsudq_ft_v33_pd
[Model]  io8p00_arsudq_ft_v33_pd
Model_type I/O
Polarity   Non-Inverting
Enable   Active-Low
Vinl =   0.990000V
Vinh =   2.310000V
Vmeas =  1.650000V
Cref =   50.000000pF
Rref =   100.000000M
Vref =   0.0V
C_comp   2.292100pF   2.219400pF   2.369900pF
[Temperature Range]   25.000000   0.125000k   -40.000000
[Pullup Reference]   3.300000V   2.700000V   3.600000V
[Pulldown Reference]   0.0V   0.0V   0.0V
[POWER Clamp Reference]   3.300000V   2.700000V   3.600000V
[GND Clamp Reference]   0.0V   0.0V   0.0V
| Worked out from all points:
|   slope of the pulldown table from 0 to 0.495 V, typ, clamps not added: 20.9 ohm
|   slope of the pullup table from 0 to 0.495 V, typ, clamps not added: 22.6 ohm
|   GND clamp passes 1 mA (typ) near -0.62 V on its own axis
|   rising waveform, R_fixture 50.000000, V_fixture 3.300000: 20-80 % time 191ps typ, 344ps min, 161ps max; typ from 1.12 V to 3.3 V
|   rising waveform, R_fixture 50.000000, V_fixture 0.0: 20-80 % time 19.7ns typ, 51.8ns min, 10.4ns max; typ from 0 V to 2.13 V
|   falling waveform, R_fixture 50.000000, V_fixture 3.300000: 20-80 % time 18.7ns typ, 39.1ns min, 11.4ns max; typ from 3.3 V to 1.12 V
|   falling waveform, R_fixture 50.000000, V_fixture 0.0: 20-80 % time 433ps typ, 651ps min, 337ps max; typ from 2.13 V to 0 V
[Pulldown]
|Voltage   I(typ)   I(min)   I(max)
-3.3V     -36.46mA   -21.1mA    -47.09mA
-800mV    -36.46mA   -21.1mA    -47.09mA
-600mV    -30.5mA    -20.54mA   -38.69mA
700mV     31.4mA     19.11mA    41.71mA
1.2V      45.15mA    25.37mA    61.75mA
1.6V      50.35mA    26.5mA     71.06mA
3.1V      52.27mA    27.26mA    74.75mA
4.1V      55.69mA    32.97mA    75.8mA
4.7V      65.7mA     32.97mA    86.63mA
5.1V      65.7mA     32.97mA    96.89mA
6.3V      65.87mA    36.5mA     96.89mA
6.6V      70.93mA    39.71mA    98.5mA
[Pullup]
|Voltage   I(typ)   I(min)   I(max)
-3.3V     28.03mA    15.43mA    40.69mA
-700mV    28.03mA    15.43mA    40.69mA
-400mV    20.31mA    13.47mA    26.93mA
600mV     -25.77mA   -16.23mA   -35.13mA
1.6V      -50.64mA   -28.81mA   -70.96mA
2.3V      -56.49mA   -30.48mA   -81.16mA
3.5V      -59.53mA   -32.65mA   -85.92mA
4.2V      -61.43mA   -47.47mA   -87.46mA
4.5V      -69.06mA   -55.01mA   -88.38mA
5.4V      -98mA      -57.7mA    -119.3mA
5.7V      -98mA      -57.7mA    -131.2mA
6.6V      -98mA      -57.7mA    -131.2mA
[GND_clamp]
|Voltage   I(typ)   I(min)   I(max)
-3.3V     -2.314A    -2.394A    -2.288A
-1.2V     -265.5mA   -356.1mA   -227.2mA
-1.13V    -202.7mA   -292.9mA   -164.1mA
-1.06V    -142.2mA   -231.2mA   -104.1mA
-990mV    -85.98mA   -171.6mA   -50.73mA
-920mV    -38.81mA   -115.5mA   -15.29mA
-850mV    -11.09mA   -65.61mA   -6.016mA
-780mV    -3.793mA   -27.42mA   -3.89mA
-710mV    -2.098mA   -7.698mA   -2.396mA
-640mV    -1.159mA   -2.127mA   -1.234mA
-570mV    -535.1uA   -807.4uA   -490.2uA
3.28V     81.28uA    57.87uA    93.98uA
[POWER_clamp]
|Voltage   I(typ)   I(min)   I(max)
-3.28V    0A         148.5nA    0A
-3.2V     0A         138.6nA    0A
-3.12V    0A         129.7nA    0A
-3.04V    0A         122nA      0A
-2.96V    0A         115.3nA    0A
-2.8V     0A         105.1nA    0A
-2.6V     0A         96.44nA    0A
-2.4V     0A         90.52nA    0A
-2.16V    0A         84.97nA    0A
-440mV    0A         50.04nA    0A
-400mV    0A         0A         0A
0V        0A         0A         0A
[Ramp]
| variable   typ   min   max
dV/dt_r  1.27668/19.67233n   0.81528/51.88624n   1.56654/10.37508n
dV/dt_f  1.30596/18.64574n   0.78534/39.22600n   1.58741/11.41067n
R_load = 50.000000
[Rising Waveform]
R_fixture= 50.000000
V_fixture= 3.300000
V_fixture_min= 2.700000
V_fixture_max= 3.600000
|time   V(typ)   V(min)   V(max)
0s        1.123V     1.39V      953.1mV
770.8ps   1.132V     1.39V      1.12V
840.8ps   1.154V     1.39V      1.557V
981ps     1.257V     1.392V     3.023V
1.081ns   1.535V     1.396V     3.41V
1.201ns   2.361V     1.402V     3.547V
1.281ns   2.895V     1.409V     3.575V
1.401ns   3.184V     1.463V     3.59V
2.142ns   3.297V     2.659V     3.597V
4.985ns   3.299V     2.699V     3.599V
[Rising Waveform]
R_fixture= 50.000000
V_fixture= 0.0
V_fixture_min= 0.0
V_fixture_max= 0.0
|time   V(typ)   V(min)   V(max)
0s        120.4nV    240.1nV    640.2nV
5.506ns   12.32mV    -92.65uV   204.6mV
15.52ns   489.3mV    35.77mV    1.736V
19.52ns   762.6mV    68.3mV     2.202V
33.03ns   1.649V     271.8mV    2.55V
40.04ns   1.896V     387.2mV    2.577V
54.55ns   2.054V     662.9mV    2.604V
87.09ns   2.115V     1.113V     2.611V
117.1ns   2.127V     1.298V     2.611V
249.2ns   2.128V     1.358V     2.611V
[Falling Waveform]
R_fixture= 50.000000
V_fixture= 3.300000
V_fixture_min= 2.700000
V_fixture_max= 3.600000
|time   V(typ)   V(min)   V(max)
0s        3.299V     2.699V     3.599V
5.506ns   3.296V     2.697V     3.561V
11.51ns   3.139V     2.693V     2.769V
21.52ns   2.427V     2.607V     1.428V
30.53ns   1.78V      2.436V     1.083V
37.54ns   1.436V     2.282V     1.025V
46.05ns   1.276V     2.077V     997.9mV
65.07ns   1.178V     1.693V     967.6mV
84.58ns   1.148V     1.532V     957mV
249.2ns   1.123V     1.39V      953.1mV
[Falling Waveform]
R_fixture= 50.000000
V_fixture= 0.0
V_fixture_min= 0.0
V_fixture_max= 0.0
|time   V(typ)   V(min)   V(max)
0s        2.128V     1.358V     2.611V
790.8ps   2.124V     1.357V     2.459V
1.001ns   2.045V     1.357V     1.62V
1.211ns   1.602V     1.356V     608.3mV
1.341ns   1.174V     1.345V     260.5mV
1.512ns   661.7mV    1.311V     82.65mV
1.882ns   85.4mV     962.6mV    7.695mV
2.272ns   9.748mV    426mV      1.061mV
2.693ns   1.83mV     91.97mV    74.93uV
4.985ns   120.4nV    240.1nV    640.2nV
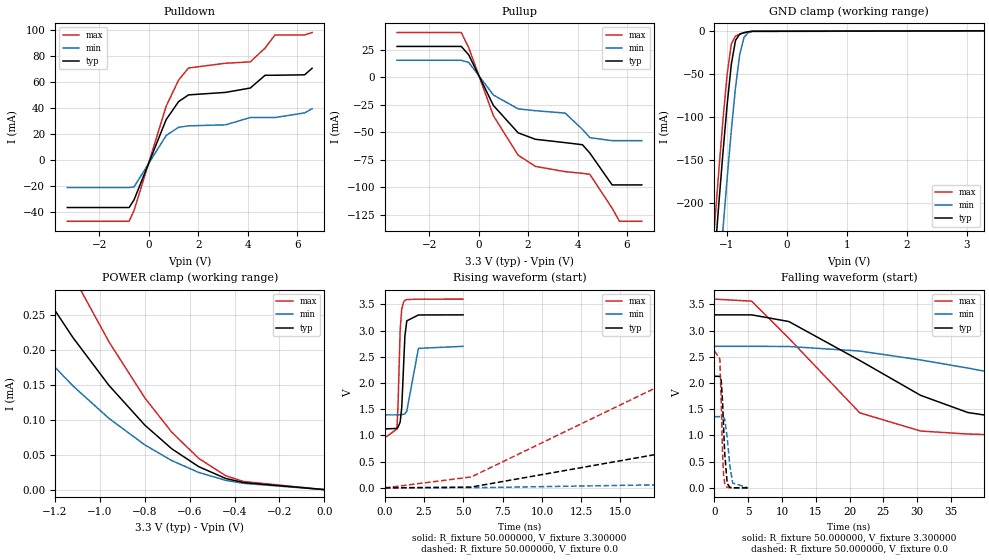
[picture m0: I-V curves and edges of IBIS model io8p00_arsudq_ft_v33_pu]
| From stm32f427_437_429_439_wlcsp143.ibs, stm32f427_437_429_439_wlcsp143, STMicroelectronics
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|   Model io8p00_arsudq_ft_v33_pu
[Model]  io8p00_arsudq_ft_v33_pu
Model_type I/O
Polarity   Non-Inverting
Enable   Active-Low
Vinl =   0.990000V
Vinh =   2.310000V
Vmeas =  1.650000V
Cref =   50.000000pF
Rref =   100.000000M
Vref =   0.0V
C_comp   2.292100pF   2.219400pF   2.369900pF
[Temperature Range]   25.000000   0.125000k   -40.000000
[Pullup Reference]   3.300000V   2.700000V   3.600000V
[Pulldown Reference]   0.0V   0.0V   0.0V
[POWER Clamp Reference]   3.300000V   2.700000V   3.600000V
[GND Clamp Reference]   0.0V   0.0V   0.0V
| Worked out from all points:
|   slope of the pulldown table from 0 to 0.495 V, typ, clamps not added: 20.9 ohm
|   slope of the pullup table from 0 to 0.495 V, typ, clamps not added: 22.6 ohm
|   GND clamp passes 1 mA (typ) near -0.62 V on its own axis
|   rising waveform, R_fixture 50.000000, V_fixture 3.300000: 20-80 % time 190ps typ, 344ps min, 160ps max; typ from 1.12 V to 3.3 V
|   rising waveform, R_fixture 50.000000, V_fixture 0.0: 20-80 % time 19.7ns typ, 51.8ns min, 10.4ns max; typ from 0.001 V to 2.13 V
|   falling waveform, R_fixture 50.000000, V_fixture 3.300000: 20-80 % time 18.4ns typ, 39.3ns min, 11.4ns max; typ from 3.3 V to 1.12 V
|   falling waveform, R_fixture 50.000000, V_fixture 0.0: 20-80 % time 433ps typ, 651ps min, 336ps max; typ from 2.13 V to 0.001 V
[Pulldown]
|Voltage   I(typ)   I(min)   I(max)
-3.3V     -36.46mA   -21.09mA   -47.09mA
-800mV    -36.46mA   -21.09mA   -47.09mA
-600mV    -30.5mA    -20.55mA   -38.69mA
700mV     31.4mA     19.11mA    41.71mA
1.2V      45.15mA    25.37mA    61.75mA
1.6V      50.35mA    26.5mA     71.06mA
3.1V      52.28mA    27.26mA    74.76mA
4.1V      55.64mA    32.89mA    75.8mA
4.7V      65.5mA     32.89mA    86.49mA
5.1V      65.5mA     32.89mA    96.54mA
6.3V      65.83mA    36.48mA    96.54mA
6.6V      70.88mA    39.69mA    98.4mA
[Pullup]
|Voltage   I(typ)   I(min)   I(max)
-3.3V     28.01mA    15.42mA    40.63mA
-700mV    28.01mA    15.42mA    40.63mA
-400mV    20.31mA    13.47mA    26.93mA
600mV     -25.77mA   -16.23mA   -35.13mA
1.6V      -50.64mA   -28.8mA    -70.96mA
2.3V      -56.49mA   -30.48mA   -81.16mA
3.5V      -59.52mA   -32.65mA   -85.91mA
4.2V      -61.43mA   -47.46mA   -87.45mA
4.5V      -69.06mA   -55.01mA   -88.37mA
5.4V      -98mA      -57.7mA    -119.2mA
5.7V      -98mA      -57.7mA    -131.1mA
6.6V      -98mA      -57.7mA    -131.1mA
[GND_clamp]
|Voltage   I(typ)   I(min)   I(max)
-3.3V     -2.315A    -2.394A    -2.288A
-1.2V     -265.5mA   -356.1mA   -227.2mA
-1.13V    -202.6mA   -292.9mA   -164.1mA
-1.06V    -142.2mA   -231.2mA   -104.1mA
-990mV    -85.98mA   -171.6mA   -50.72mA
-920mV    -38.8mA    -115.5mA   -15.28mA
-850mV    -11.08mA   -65.6mA    -6.001mA
-780mV    -3.782mA   -27.42mA   -3.876mA
-710mV    -2.086mA   -7.69mA    -2.381mA
-640mV    -1.147mA   -2.118mA   -1.22mA
-570mV    -523.9uA   -798.4uA   -476.8uA
3.28V     0A         0A         0A
[POWER_clamp]
|Voltage   I(typ)   I(min)   I(max)
-3.28V    785.2uA    403.2uA    1.133mA
-1.56V    448.2uA    307.3uA    613.5uA
-1.32V    315.9uA    216.2uA    438.6uA
-1.28V    295.2uA    201.9uA    411uA
-1.12V    217.7uA    148.5uA    306.1uA
-960mV    149.4uA    102.1uA    211.9uA
-800mV    92.4uA     64.03uA    131.4uA
-680mV    58.5uA     41.61uA    82.28uA
-560mV    32.91uA    24.62uA    44.81uA
-440mV    16uA       13.27uA    19.94uA
-360mV    10.09uA    8.954uA    11.61uA
0V        0A         0A         0A
[Ramp]
| variable   typ   min   max
dV/dt_r  1.27711/19.67173n   0.81585/51.86660n   1.56688/10.40391n
dV/dt_f  1.30668/18.36963n   0.78438/39.41635n   1.58713/11.35679n
R_load = 50.000000
[Rising Waveform]
R_fixture= 50.000000
V_fixture= 3.300000
V_fixture_min= 2.700000
V_fixture_max= 3.600000
|time   V(typ)   V(min)   V(max)
0s        1.125V     1.393V     954.7mV
770.8ps   1.134V     1.393V     1.122V
840.8ps   1.156V     1.393V     1.56V
981ps     1.259V     1.394V     3.028V
1.081ns   1.538V     1.399V     3.414V
1.201ns   2.364V     1.405V     3.549V
1.281ns   2.898V     1.411V     3.577V
1.401ns   3.186V     1.466V     3.592V
2.142ns   3.298V     2.661V     3.599V
4.985ns   3.3V       2.7V       3.6V
[Rising Waveform]
R_fixture= 50.000000
V_fixture= 0.0
V_fixture_min= 0.0
V_fixture_max= 0.0
|time   V(typ)   V(min)   V(max)
0s        1.089mV    1.043mV    1.137mV
5.506ns   16.31mV    2.83mV     209.4mV
19.02ns   731.2mV    67.1mV     2.166V
24.52ns   1.112V     134.4mV    2.432V
32.53ns   1.626V     266.3mV    2.548V
40.04ns   1.899V     390mV      2.579V
53.55ns   2.051V     646.6mV    2.605V
86.59ns   2.116V     1.111V     2.612V
117.1ns   2.129V     1.301V     2.613V
249.2ns   2.13V      1.36V      2.613V
[Falling Waveform]
R_fixture= 50.000000
V_fixture= 3.300000
V_fixture_min= 2.700000
V_fixture_max= 3.600000
|time   V(typ)   V(min)   V(max)
0s        3.3V       2.7V       3.6V
5.506ns   3.3V       2.7V       3.561V
11.01ns   3.173V     2.697V     2.854V
21.52ns   2.43V      2.61V      1.431V
30.53ns   1.765V     2.44V      1.085V
37.54ns   1.437V     2.285V     1.027V
45.55ns   1.284V     2.09V      1.001V
64.06ns   1.182V     1.709V     970.2mV
85.09ns   1.147V     1.532V     958.7mV
249.2ns   1.125V     1.393V     954.7mV
[Falling Waveform]
R_fixture= 50.000000
V_fixture= 0.0
V_fixture_min= 0.0
V_fixture_max= 0.0
|time   V(typ)   V(min)   V(max)
0s        2.13V      1.36V      2.613V
790.8ps   2.126V     1.359V     2.461V
1.001ns   2.046V     1.359V     1.619V
1.211ns   1.603V     1.358V     607.4mV
1.341ns   1.175V     1.347V     260.4mV
1.512ns   662.1mV    1.313V     83.27mV
1.882ns   86.39mV    963.8mV    8.87mV
2.272ns   10.83mV    427.1mV    2.162mV
2.693ns   2.932mV    93.36mV    1.232mV
4.985ns   1.089mV    1.043mV    1.137mV
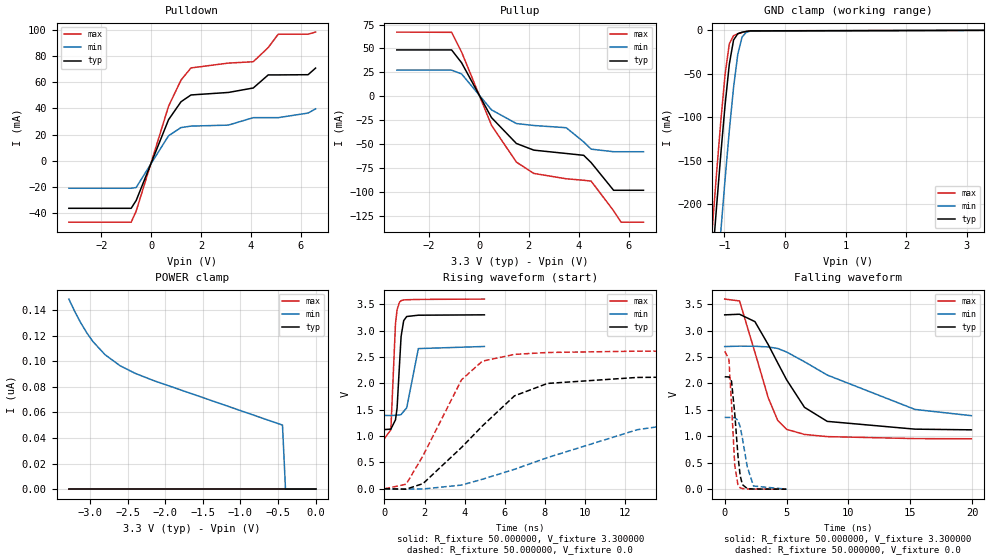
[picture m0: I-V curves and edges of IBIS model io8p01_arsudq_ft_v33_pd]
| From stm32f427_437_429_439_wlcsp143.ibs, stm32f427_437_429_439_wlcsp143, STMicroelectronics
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|   Model io8p01_arsudq_ft_v33_pd
[Model]  io8p01_arsudq_ft_v33_pd
Model_type I/O
Polarity   Non-Inverting
Enable   Active-Low
Vinl =   0.990000V
Vinh =   2.310000V
Vmeas =  1.650000V
Cref =   50.000000pF
Rref =   100.000000M
Vref =   0.0V
C_comp   2.292100pF   2.219400pF   2.369900pF
[Temperature Range]   25.000000   0.125000k   -40.000000
[Pullup Reference]   3.300000V   2.700000V   3.600000V
[Pulldown Reference]   0.0V   0.0V   0.0V
[POWER Clamp Reference]   3.300000V   2.700000V   3.600000V
[GND Clamp Reference]   0.0V   0.0V   0.0V
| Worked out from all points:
|   slope of the pulldown table from 0 to 0.495 V, typ, clamps not added: 20.9 ohm
|   slope of the pullup table from 0 to 0.495 V, typ, clamps not added: 22.6 ohm
|   GND clamp passes 1 mA (typ) near -0.62 V on its own axis
|   rising waveform, R_fixture 50.000000, V_fixture 3.300000: 20-80 % time 191ps typ, 344ps min, 162ps max; typ from 1.12 V to 3.3 V
|   rising waveform, R_fixture 50.000000, V_fixture 0.0: 20-80 % time 3.33ns typ, 6.63ns min, 2.1ns max; typ from 0 V to 2.13 V
|   falling waveform, R_fixture 50.000000, V_fixture 3.300000: 20-80 % time 3.18ns typ, 7.05ns min, 2.02ns max; typ from 3.3 V to 1.12 V
|   falling waveform, R_fixture 50.000000, V_fixture 0.0: 20-80 % time 434ps typ, 650ps min, 337ps max; typ from 2.13 V to 0 V
[Pulldown]
|Voltage   I(typ)   I(min)   I(max)
-3.3V     -36.46mA   -21.1mA    -47.09mA
-800mV    -36.46mA   -21.1mA    -47.09mA
-600mV    -30.5mA    -20.54mA   -38.69mA
700mV     31.4mA     19.11mA    41.71mA
1.2V      45.15mA    25.37mA    61.75mA
1.6V      50.35mA    26.5mA     71.06mA
3.1V      52.27mA    27.26mA    74.75mA
4.1V      55.69mA    32.97mA    75.8mA
4.7V      65.7mA     32.97mA    86.63mA
5.1V      65.7mA     32.97mA    96.89mA
6.3V      65.87mA    36.5mA     96.89mA
6.6V      70.93mA    39.71mA    98.5mA
[Pullup]
|Voltage   I(typ)   I(min)   I(max)
-3.3V     48.5mA     27.42mA    67.11mA
-1.1V     48.5mA     27.42mA    66.85mA
-700mV    35.13mA    23.47mA    46.35mA
500mV     -22.07mA   -14mA      -30.03mA
1.5V      -49.1mA    -28.3mA    -68.56mA
2.2V      -56.04mA   -30.32mA   -80.35mA
3.5V      -59.53mA   -32.65mA   -85.92mA
4.2V      -61.43mA   -47.47mA   -87.46mA
4.5V      -69.06mA   -55.01mA   -88.38mA
5.4V      -97.9mA    -57.7mA    -119.3mA
5.7V      -97.9mA    -57.7mA    -131.2mA
6.6V      -97.9mA    -57.7mA    -131.2mA
[GND_clamp]
|Voltage   I(typ)   I(min)   I(max)
-3.3V     -2.314A    -2.394A    -2.288A
-1.2V     -265.5mA   -356.1mA   -227.2mA
-1.13V    -202.7mA   -292.9mA   -164.1mA
-1.06V    -142.2mA   -231.2mA   -104.1mA
-990mV    -85.98mA   -171.6mA   -50.73mA
-920mV    -38.81mA   -115.5mA   -15.29mA
-850mV    -11.09mA   -65.61mA   -6.016mA
-780mV    -3.793mA   -27.42mA   -3.89mA
-710mV    -2.098mA   -7.698mA   -2.396mA
-640mV    -1.159mA   -2.127mA   -1.234mA
-570mV    -535.1uA   -807.4uA   -490.2uA
3.28V     81.28uA    57.87uA    93.98uA
[POWER_clamp]
|Voltage   I(typ)   I(min)   I(max)
-3.28V    0A         148.5nA    0A
-3.2V     0A         138.6nA    0A
-3.12V    0A         129.7nA    0A
-3.04V    0A         122nA      0A
-2.96V    0A         115.3nA    0A
-2.8V     0A         105.1nA    0A
-2.6V     0A         96.44nA    0A
-2.4V     0A         90.52nA    0A
-2.16V    0A         84.97nA    0A
-440mV    0A         50.04nA    0A
-400mV    0A         0A         0A
0V        0A         0A         0A
[Ramp]
| variable   typ   min   max
dV/dt_r  1.27692/3.32542n   0.80034/6.65666n   1.56636/2.09448n
dV/dt_f  1.30230/3.18469n   0.74388/7.04330n   1.58741/2.02192n
R_load = 50.000000
[Rising Waveform]
R_fixture= 50.000000
V_fixture= 3.300000
V_fixture_min= 2.700000
V_fixture_max= 3.600000
|time   V(typ)   V(min)   V(max)
0s        1.123V     1.391V     953.8mV
320.3ps   1.132V     1.39V      1.121V
550.6ps   1.308V     1.393V     3.129V
630.6ps   1.532V     1.396V     3.399V
750.8ps   2.357V     1.402V     3.538V
830.8ps   2.89V      1.409V     3.567V
961ps     3.19V      1.468V     3.582V
1.111ns   3.267V     1.537V     3.585V
1.692ns   3.292V     2.659V     3.591V
4.985ns   3.299V     2.699V     3.598V
[Rising Waveform]
R_fixture= 50.000000
V_fixture= 0.0
V_fixture_min= 0.0
V_fixture_max= 0.0
|time   V(typ)   V(min)   V(max)
0s        195.8uV    84.5uV     747.4uV
1.081ns   -6.551mV   -5.321mV   86.62mV
1.922ns   98.61mV    -3.131mV   625.6mV
3.844ns   784.1mV    70.93mV    2.067V
4.885ns   1.192V     181.5mV    2.421V
6.486ns   1.763V     370.1mV    2.549V
8.128ns   1.998V     591.5mV    2.585V
12.61ns   2.112V     1.121V     2.61V
15.54ns   2.121V     1.282V     2.611V
19.94ns   2.127V     1.358V     2.611V
[Falling Waveform]
R_fixture= 50.000000
V_fixture= 3.300000
V_fixture_min= 2.700000
V_fixture_max= 3.600000
|time   V(typ)   V(min)   V(max)
0s        3.299V     2.699V     3.598V
1.201ns   3.311V     2.707V     3.562V
2.442ns   3.171V     2.705V     2.591V
3.524ns   2.733V     2.692V     1.726V
4.284ns   2.39V      2.663V     1.302V
5.005ns   2.07V      2.596V     1.132V
6.446ns   1.549V     2.412V     1.036V
8.288ns   1.283V     2.16V      994.6mV
15.38ns   1.136V     1.509V     957mV
19.94ns   1.123V     1.391V     953.8mV
[Falling Waveform]
R_fixture= 50.000000
V_fixture= 0.0
V_fixture_min= 0.0
V_fixture_max= 0.0
|time   V(typ)   V(min)   V(max)
0s        2.127V     1.358V     2.611V
340.3ps   2.124V     1.357V     2.457V
550.6ps   2.044V     1.357V     1.621V
810.8ps   1.436V     1.352V     454.1mV
1.071ns   634.6mV    1.305V     80.38mV
1.251ns   257.7mV    1.183V     26.57mV
1.431ns   86.4mV     961.7mV    12.02mV
1.822ns   11mV       425.2mV    4.445mV
2.332ns   2.397mV    59.28mV    2.315mV
4.985ns   195.8uV    84.5uV     747.4uV
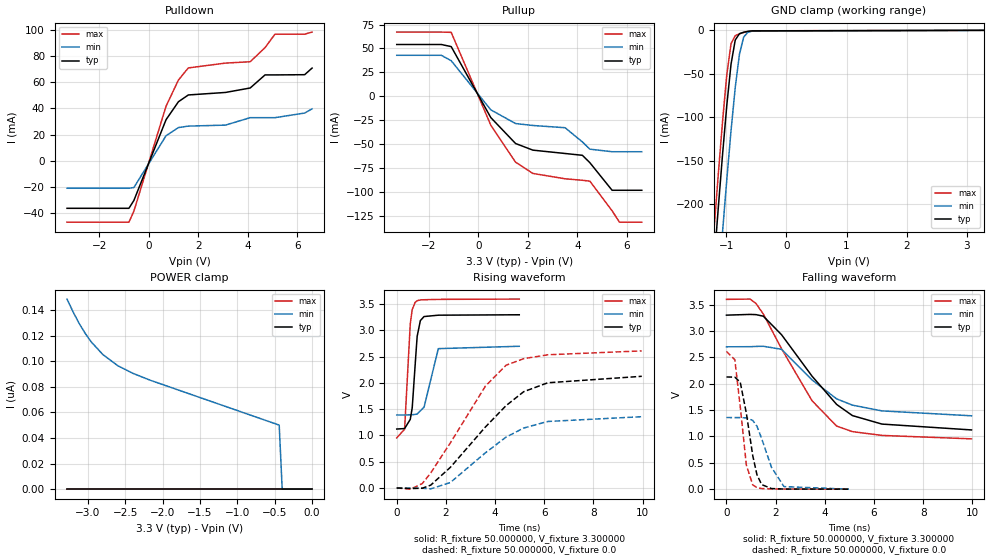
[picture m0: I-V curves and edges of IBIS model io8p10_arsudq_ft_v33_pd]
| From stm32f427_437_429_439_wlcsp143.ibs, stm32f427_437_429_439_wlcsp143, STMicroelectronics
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|   Model io8p10_arsudq_ft_v33_pd
[Model]  io8p10_arsudq_ft_v33_pd
Model_type I/O
Polarity   Non-Inverting
Enable   Active-Low
Vinl =   0.990000V
Vinh =   2.310000V
Vmeas =  1.650000V
Cref =   40.000000pF
Rref =   100.000000M
Vref =   0.0V
C_comp   2.292100pF   2.219400pF   2.369900pF
[Temperature Range]   25.000000   0.125000k   -40.000000
[Pullup Reference]   3.300000V   2.700000V   3.600000V
[Pulldown Reference]   0.0V   0.0V   0.0V
[POWER Clamp Reference]   3.300000V   2.700000V   3.600000V
[GND Clamp Reference]   0.0V   0.0V   0.0V
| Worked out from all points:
|   slope of the pulldown table from 0 to 0.495 V, typ, clamps not added: 20.9 ohm
|   slope of the pullup table from 0 to 0.495 V, typ, clamps not added: 22.6 ohm
|   GND clamp passes 1 mA (typ) near -0.62 V on its own axis
|   rising waveform, R_fixture 50.000000, V_fixture 3.300000: 20-80 % time 191ps typ, 347ps min, 162ps max; typ from 1.12 V to 3.3 V
|   rising waveform, R_fixture 50.000000, V_fixture 0.0: 20-80 % time 2.5ns typ, 2.23ns min, 2.11ns max; typ from 0 V to 2.13 V
|   falling waveform, R_fixture 50.000000, V_fixture 3.300000: 20-80 % time 2.25ns typ, 2.08ns min, 2ns max; typ from 3.3 V to 1.12 V
|   falling waveform, R_fixture 50.000000, V_fixture 0.0: 20-80 % time 434ps typ, 651ps min, 337ps max; typ from 2.13 V to 0 V
[Pulldown]
|Voltage   I(typ)   I(min)   I(max)
-3.3V     -36.46mA   -21.1mA    -47.09mA
-800mV    -36.46mA   -21.1mA    -47.09mA
-600mV    -30.5mA    -20.54mA   -38.69mA
700mV     31.4mA     19.11mA    41.71mA
1.2V      45.15mA    25.37mA    61.75mA
1.6V      50.35mA    26.5mA     71.06mA
3.1V      52.27mA    27.26mA    74.75mA
4.1V      55.69mA    32.97mA    75.8mA
4.7V      65.7mA     32.97mA    86.63mA
5.1V      65.7mA     32.97mA    96.89mA
6.3V      65.87mA    36.5mA     96.89mA
6.6V      70.93mA    39.71mA    98.5mA
[Pullup]
|Voltage   I(typ)   I(min)   I(max)
-3.3V     54.18mA    42.91mA    67.11mA
-1.5V     54.18mA    42.91mA    67.11mA
-1.1V     51.95mA    37.26mA    66.85mA
500mV     -22.07mA   -14mA      -30.03mA
1.5V      -49.1mA    -28.3mA    -68.56mA
2.2V      -56.04mA   -30.32mA   -80.35mA
3.5V      -59.53mA   -32.65mA   -85.92mA
4.2V      -61.43mA   -47.47mA   -87.46mA
4.5V      -69.06mA   -55.01mA   -88.38mA
5.4V      -97.9mA    -57.7mA    -119.3mA
5.7V      -97.9mA    -57.7mA    -131.2mA
6.6V      -97.9mA    -57.7mA    -131.2mA
[GND_clamp]
|Voltage   I(typ)   I(min)   I(max)
-3.3V     -2.314A    -2.394A    -2.288A
-1.2V     -265.5mA   -356.1mA   -227.2mA
-1.13V    -202.7mA   -292.9mA   -164.1mA
-1.06V    -142.2mA   -231.2mA   -104.1mA
-990mV    -85.98mA   -171.6mA   -50.73mA
-920mV    -38.81mA   -115.5mA   -15.29mA
-850mV    -11.09mA   -65.61mA   -6.016mA
-780mV    -3.793mA   -27.42mA   -3.89mA
-710mV    -2.098mA   -7.698mA   -2.396mA
-640mV    -1.159mA   -2.127mA   -1.234mA
-570mV    -535.1uA   -807.4uA   -490.2uA
3.28V     81.28uA    57.87uA    93.98uA
[POWER_clamp]
|Voltage   I(typ)   I(min)   I(max)
-3.28V    0A         148.5nA    0A
-3.2V     0A         138.6nA    0A
-3.12V    0A         129.7nA    0A
-3.04V    0A         122nA      0A
-2.96V    0A         115.3nA    0A
-2.8V     0A         105.1nA    0A
-2.6V     0A         96.44nA    0A
-2.4V     0A         90.52nA    0A
-2.16V    0A         84.97nA    0A
-440mV    0A         50.04nA    0A
-400mV    0A         0A         0A
0V        0A         0A         0A
[Ramp]
| variable   typ   min   max
dV/dt_r  1.26888/2.50918n   0.81174/2.23457n   1.56432/2.11078n
dV/dt_f  1.28538/2.23859n   0.77994/2.08031n   1.57565/2.00680n
R_load = 50.000000
[Rising Waveform]
R_fixture= 50.000000
V_fixture= 3.300000
V_fixture_min= 2.700000
V_fixture_max= 3.600000
|time   V(typ)   V(min)   V(max)
0s        1.123V     1.391V     953.8mV
320.3ps   1.132V     1.39V      1.121V
550.6ps   1.307V     1.393V     3.128V
630.6ps   1.53V      1.396V     3.399V
750.8ps   2.355V     1.402V     3.538V
830.8ps   2.888V     1.409V     3.566V
961ps     3.188V     1.469V     3.582V
1.111ns   3.265V     1.538V     3.585V
1.692ns   3.291V     2.654V     3.592V
4.985ns   3.299V     2.699V     3.598V
[Rising Waveform]
R_fixture= 50.000000
V_fixture= 0.0
V_fixture_min= 0.0
V_fixture_max= 0.0
|time   V(typ)   V(min)   V(max)
0s        195.2uV    84.8uV     739.8uV
560.6ps   -10.5mV    -67.49uV   -22.18mV
1.041ns   -4.656mV   -5.015mV   84.83mV
1.381ns   54.17mV    -16.96mV   285.3mV
2.182ns   393.7mV    104.5mV    859.9mV
3.604ns   1.16V      669mV      1.938V
4.444ns   1.567V     968mV      2.337V
5.165ns   1.834V     1.142V     2.463V
6.146ns   2.004V     1.267V     2.537V
9.97ns    2.127V     1.358V     2.611V
[Falling Waveform]
R_fixture= 50.000000
V_fixture= 3.300000
V_fixture_min= 2.700000
V_fixture_max= 3.600000
|time   V(typ)   V(min)   V(max)
0s        3.299V     2.699V     3.598V
961ps     3.313V     2.701V     3.604V
1.201ns   3.309V     2.706V     3.521V
1.502ns   3.279V     2.709V     3.318V
2.242ns   2.928V     2.652V     2.662V
3.483ns   2.142V     2.07V      1.676V
4.484ns   1.606V     1.712V     1.196V
5.125ns   1.395V     1.593V     1.091V
6.326ns   1.234V     1.484V     1.019V
9.97ns    1.123V     1.391V     953.8mV
[Falling Waveform]
R_fixture= 50.000000
V_fixture= 0.0
V_fixture_min= 0.0
V_fixture_max= 0.0
|time   V(typ)   V(min)   V(max)
0s        2.127V     1.358V     2.611V
340.3ps   2.124V     1.357V     2.455V
560.6ps   2.029V     1.357V     1.569V
810.8ps   1.437V     1.351V     454.2mV
1.071ns   634.1mV    1.304V     80.48mV
1.241ns   273.9mV    1.195V     28.32mV
1.431ns   87.45mV    961.3mV    11.98mV
1.832ns   11.59mV    414.6mV    4.249mV
2.342ns   2.491mV    48.81mV    2.105mV
4.985ns   195.2uV    84.8uV     739.8uV
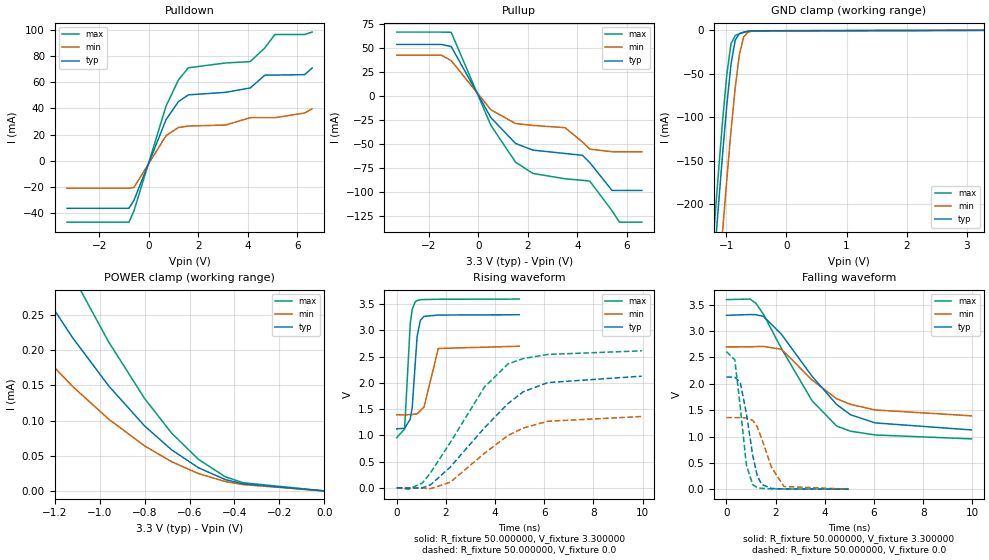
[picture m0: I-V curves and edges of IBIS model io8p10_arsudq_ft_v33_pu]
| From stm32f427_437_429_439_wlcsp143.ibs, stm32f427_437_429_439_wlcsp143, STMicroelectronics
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|   Model io8p10_arsudq_ft_v33_pu
[Model]  io8p10_arsudq_ft_v33_pu
Model_type I/O
Polarity   Non-Inverting
Enable   Active-Low
Vinl =   0.990000V
Vinh =   2.310000V
Vmeas =  1.650000V
Cref =   40.000000pF
Rref =   100.000000M
Vref =   0.0V
C_comp   2.292100pF   2.219400pF   2.369900pF
[Temperature Range]   25.000000   0.125000k   -40.000000
[Pullup Reference]   3.300000V   2.700000V   3.600000V
[Pulldown Reference]   0.0V   0.0V   0.0V
[POWER Clamp Reference]   3.300000V   2.700000V   3.600000V
[GND Clamp Reference]   0.0V   0.0V   0.0V
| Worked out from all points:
|   slope of the pulldown table from 0 to 0.495 V, typ, clamps not added: 20.9 ohm
|   slope of the pullup table from 0 to 0.495 V, typ, clamps not added: 22.6 ohm
|   GND clamp passes 1 mA (typ) near -0.62 V on its own axis
|   rising waveform, R_fixture 50.000000, V_fixture 3.300000: 20-80 % time 190ps typ, 346ps min, 161ps max; typ from 1.12 V to 3.3 V
|   rising waveform, R_fixture 50.000000, V_fixture 0.0: 20-80 % time 2.51ns typ, 2.23ns min, 2.11ns max; typ from 0.001 V to 2.13 V
|   falling waveform, R_fixture 50.000000, V_fixture 3.300000: 20-80 % time 2.25ns typ, 2.08ns min, 2.01ns max; typ from 3.3 V to 1.12 V
|   falling waveform, R_fixture 50.000000, V_fixture 0.0: 20-80 % time 435ps typ, 653ps min, 337ps max; typ from 2.13 V to 0.001 V
[Pulldown]
|Voltage   I(typ)   I(min)   I(max)
-3.3V     -36.46mA   -21.09mA   -47.09mA
-800mV    -36.46mA   -21.09mA   -47.09mA
-600mV    -30.5mA    -20.55mA   -38.69mA
700mV     31.4mA     19.11mA    41.71mA
1.2V      45.15mA    25.37mA    61.75mA
1.6V      50.35mA    26.5mA     71.06mA
3.1V      52.28mA    27.26mA    74.76mA
4.1V      55.64mA    32.89mA    75.8mA
4.7V      65.5mA     32.89mA    86.49mA
5.1V      65.5mA     32.89mA    96.54mA
6.3V      65.83mA    36.48mA    96.54mA
6.6V      70.88mA    39.69mA    98.4mA
[Pullup]
|Voltage   I(typ)   I(min)   I(max)
-3.3V     54.05mA    42.87mA    66.91mA
-1.5V     54.05mA    42.87mA    66.91mA
-1.1V     51.85mA    37.2mA     66.69mA
500mV     -22.06mA   -14mA      -30.03mA
1.5V      -49.1mA    -28.3mA    -68.56mA
2.2V      -56.04mA   -30.32mA   -80.35mA
3.5V      -59.52mA   -32.65mA   -85.91mA
4.2V      -61.43mA   -47.47mA   -87.45mA
4.5V      -69.06mA   -55.01mA   -88.37mA
5.4V      -98mA      -57.7mA    -119.2mA
5.7V      -98mA      -57.7mA    -131.1mA
6.6V      -98mA      -57.7mA    -131.1mA
[GND_clamp]
|Voltage   I(typ)   I(min)   I(max)
-3.3V     -2.314A    -2.394A    -2.288A
-1.2V     -265.5mA   -356.1mA   -227.2mA
-1.13V    -202.6mA   -292.9mA   -164.1mA
-1.06V    -142.2mA   -231.2mA   -104.1mA
-990mV    -85.98mA   -171.6mA   -50.72mA
-920mV    -38.8mA    -115.5mA   -15.28mA
-850mV    -11.08mA   -65.6mA    -6.001mA
-780mV    -3.782mA   -27.42mA   -3.876mA
-710mV    -2.086mA   -7.69mA    -2.381mA
-640mV    -1.147mA   -2.118mA   -1.22mA
-570mV    -523.9uA   -798.4uA   -476.8uA
3.28V     0A         0A         0A
[POWER_clamp]
|Voltage   I(typ)   I(min)   I(max)
-3.28V    785.2uA    403.2uA    1.133mA
-1.56V    448.2uA    307.3uA    613.5uA
-1.32V    315.9uA    216.2uA    438.6uA
-1.28V    295.2uA    201.9uA    411uA
-1.12V    217.7uA    148.5uA    306.1uA
-960mV    149.4uA    102.1uA    211.9uA
-800mV    92.4uA     64.03uA    131.4uA
-680mV    58.5uA     41.61uA    82.28uA
-560mV    32.91uA    24.62uA    44.81uA
-440mV    16uA       13.27uA    19.94uA
-360mV    10.09uA    8.954uA    11.61uA
0V        0A         0A         0A
[Ramp]
| variable   typ   min   max
dV/dt_r  1.26937/2.51284n   0.81237/2.23849n   1.56550/2.11727n
dV/dt_f  1.28490/2.24146n   0.77904/2.08084n   1.57531/2.00629n
R_load = 50.000000
[Rising Waveform]
R_fixture= 50.000000
V_fixture= 3.300000
V_fixture_min= 2.700000
V_fixture_max= 3.600000
|time   V(typ)   V(min)   V(max)
0s        1.125V     1.393V     955.5mV
320.3ps   1.134V     1.393V     1.123V
550.6ps   1.31V      1.395V     3.136V
630.6ps   1.533V     1.399V     3.405V
750.8ps   2.36V      1.405V     3.544V
830.8ps   2.894V     1.411V     3.572V
961ps     3.193V     1.472V     3.587V
1.111ns   3.269V     1.541V     3.59V
1.692ns   3.294V     2.657V     3.595V
4.985ns   3.3V       2.7V       3.599V
[Rising Waveform]
R_fixture= 50.000000
V_fixture= 0.0
V_fixture_min= 0.0
V_fixture_max= 0.0
|time   V(typ)   V(min)   V(max)
0s        1.283mV    1.128mV    1.875mV
480.5ps   -4.269mV   1.244mV    -25.68mV
1.041ns   -784.9uV   -3.901mV   90.41mV
1.381ns   58.53mV    -15.27mV   291.2mV
2.182ns   398.4mV    108.1mV    866.1mV
3.564ns   1.142V     656.4mV    1.919V
4.525ns   1.606V     997.8mV    2.362V
5.145ns   1.831V     1.14V      2.464V
6.146ns   2.006V     1.269V     2.543V
9.97ns    2.129V     1.36V      2.612V
[Falling Waveform]
R_fixture= 50.000000
V_fixture= 3.300000
V_fixture_min= 2.700000
V_fixture_max= 3.600000
|time   V(typ)   V(min)   V(max)
0s        3.3V       2.7V       3.599V
961ps     3.315V     2.702V     3.609V
1.201ns   3.312V     2.707V     3.527V
1.502ns   3.282V     2.711V     3.322V
2.242ns   2.937V     2.655V     2.667V
3.483ns   2.144V     2.073V     1.68V
4.484ns   1.608V     1.716V     1.199V
5.045ns   1.414V     1.611V     1.102V
6.046ns   1.259V     1.505V     1.03V
9.97ns    1.125V     1.393V     955.5mV
[Falling Waveform]
R_fixture= 50.000000
V_fixture= 0.0
V_fixture_min= 0.0
V_fixture_max= 0.0
|time   V(typ)   V(min)   V(max)
0s        2.129V     1.36V      2.612V
340.3ps   2.126V     1.359V     2.457V
560.6ps   2.03V      1.359V     1.57V
810.8ps   1.439V     1.353V     457.1mV
1.071ns   636.5mV    1.306V     84.91mV
1.251ns   262.2mV    1.185V     31.46mV
1.431ns   91.06mV    963mV      16.78mV
1.832ns   15.3mV     416.9mV    7.953mV
2.342ns   5.006mV    51.68mV    4.519mV
4.985ns   1.283mV    1.128mV    1.875mV
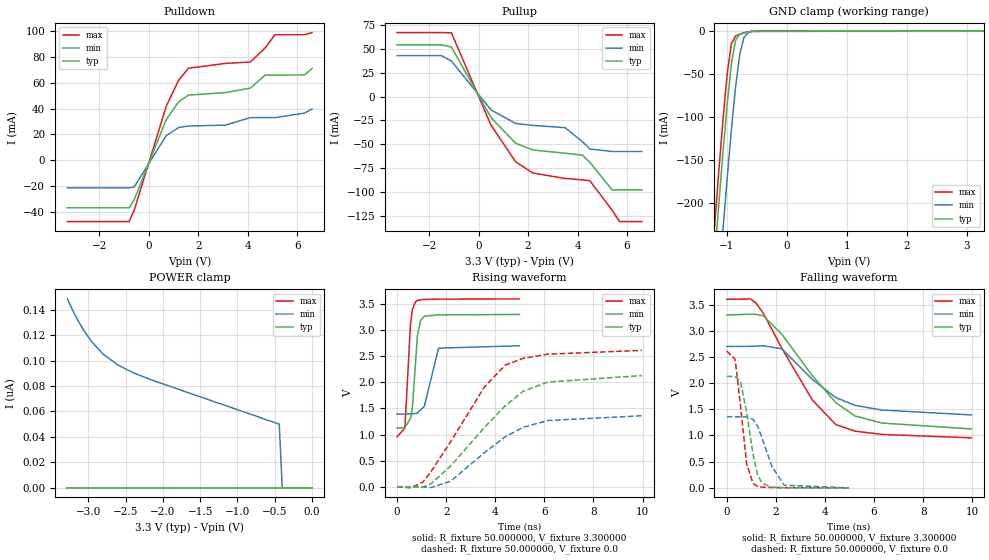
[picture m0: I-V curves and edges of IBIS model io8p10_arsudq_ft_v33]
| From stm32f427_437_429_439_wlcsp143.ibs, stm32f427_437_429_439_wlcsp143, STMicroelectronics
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|   Model io8p10_arsudq_ft_v33
[Model]  io8p10_arsudq_ft_v33
Model_type I/O
Polarity   Non-Inverting
Enable   Active-Low
Vinl =   0.990000V
Vinh =   2.310000V
Vmeas =  1.650000V
Cref =   40.000000pF
Rref =   100.000000M
Vref =   0.0V
C_comp   2.292100pF   2.219400pF   2.369900pF
[Temperature Range]   25.000000   0.125000k   -40.000000
[Pullup Reference]   3.300000V   2.700000V   3.600000V
[Pulldown Reference]   0.0V   0.0V   0.0V
[POWER Clamp Reference]   3.300000V   2.700000V   3.600000V
[GND Clamp Reference]   0.0V   0.0V   0.0V
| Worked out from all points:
|   slope of the pulldown table from 0 to 0.495 V, typ, clamps not added: 20.9 ohm
|   slope of the pullup table from 0 to 0.495 V, typ, clamps not added: 22.6 ohm
|   GND clamp passes 1 mA (typ) near -0.62 V on its own axis
|   rising waveform, R_fixture 50.000000, V_fixture 3.300000: 20-80 % time 191ps typ, 346ps min, 162ps max; typ from 1.12 V to 3.3 V
|   rising waveform, R_fixture 50.000000, V_fixture 0.0: 20-80 % time 2.51ns typ, 2.23ns min, 2.11ns max; typ from 0 V to 2.13 V
|   falling waveform, R_fixture 50.000000, V_fixture 3.300000: 20-80 % time 2.24ns typ, 2.08ns min, 2.04ns max; typ from 3.3 V to 1.12 V
|   falling waveform, R_fixture 50.000000, V_fixture 0.0: 20-80 % time 435ps typ, 652ps min, 337ps max; typ from 2.13 V to 0 V
[Pulldown]
|Voltage   I(typ)   I(min)   I(max)
-3.3V     -36.46mA   -21.09mA   -47.09mA
-800mV    -36.46mA   -21.09mA   -47.09mA
-600mV    -30.5mA    -20.54mA   -38.69mA
700mV     31.4mA     19.11mA    41.71mA
1.2V      45.15mA    25.37mA    61.75mA
1.6V      50.35mA    26.5mA     71.06mA
3.1V      52.28mA    27.26mA    74.76mA
4.1V      55.7mA     32.97mA    75.81mA
4.7V      65.71mA    32.97mA    86.64mA
5.1V      65.71mA    32.97mA    96.9mA
6.3V      65.88mA    36.51mA    96.9mA
6.6V      70.94mA    39.72mA    98.51mA
[Pullup]
|Voltage   I(typ)   I(min)   I(max)
-3.3V     54.18mA    42.91mA    67.12mA
-1.5V     54.18mA    42.91mA    67.12mA
-1.1V     51.96mA    37.26mA    66.85mA
500mV     -22.07mA   -14mA      -30.03mA
1.5V      -49.1mA    -28.3mA    -68.56mA
2.2V      -56.05mA   -30.32mA   -80.35mA
3.5V      -59.53mA   -32.65mA   -85.92mA
4.2V      -61.43mA   -47.47mA   -87.46mA
4.5V      -69.06mA   -55.01mA   -88.38mA
5.4V      -98mA      -57.7mA    -119.3mA
5.7V      -98mA      -57.7mA    -131.2mA
6.6V      -98mA      -57.7mA    -131.2mA
[GND_clamp]
|Voltage   I(typ)   I(min)   I(max)
-3.3V     -2.314A    -2.394A    -2.288A
-1.2V     -265.5mA   -356.1mA   -227.2mA
-1.13V    -202.6mA   -292.9mA   -164.1mA
-1.06V    -142.2mA   -231.2mA   -104.1mA
-990mV    -85.98mA   -171.6mA   -50.72mA
-920mV    -38.8mA    -115.5mA   -15.28mA
-850mV    -11.08mA   -65.6mA    -6.001mA
-780mV    -3.782mA   -27.42mA   -3.876mA
-710mV    -2.086mA   -7.69mA    -2.381mA
-640mV    -1.147mA   -2.118mA   -1.22mA
-570mV    -523.9uA   -798.4uA   -476.8uA
3.28V     0A         0A         0A
[POWER_clamp]
|Voltage   I(typ)   I(min)   I(max)
-3.28V    0A         148.5nA    0A
-3.2V     0A         138.6nA    0A
-3.12V    0A         129.7nA    0A
-3.04V    0A         122nA      0A
-2.96V    0A         115.3nA    0A
-2.8V     0A         105.1nA    0A
-2.6V     0A         96.44nA    0A
-2.4V     0A         90.52nA    0A
-2.16V    0A         84.97nA    0A
-440mV    0A         50.04nA    0A
-400mV    0A         0A         0A
0V        0A         0A         0A
[Ramp]
| variable   typ   min   max
dV/dt_r  1.26960/2.50946n   0.81234/2.23693n   1.56552/2.11472n
dV/dt_f  1.28568/2.23663n   0.77982/2.08098n   1.57611/2.03887n
R_load = 50.000000
[Rising Waveform]
R_fixture= 50.000000
V_fixture= 3.300000
V_fixture_min= 2.700000
V_fixture_max= 3.600000
|time   V(typ)   V(min)   V(max)
0s        1.124V     1.392V     954.2mV
320.3ps   1.133V     1.392V     1.122V
550.6ps   1.308V     1.394V     3.13V
630.6ps   1.531V     1.398V     3.4V
750.8ps   2.356V     1.403V     3.54V
830.8ps   2.89V      1.41V      3.568V
961ps     3.19V      1.47V      3.583V
1.111ns   3.267V     1.539V     3.587V
1.692ns   3.293V     2.655V     3.594V
4.985ns   3.3V       2.7V       3.599V
[Rising Waveform]
R_fixture= 50.000000
V_fixture= 0.0
V_fixture_min= 0.0
V_fixture_max= 0.0
|time   V(typ)   V(min)   V(max)
0s        194.8uV    84.8uV     739.9uV
560.6ps   -10.5mV    -67.39uV   -22.19mV
1.041ns   -4.663mV   -5.016mV   84.85mV
1.381ns   54.16mV    -16.97mV   285.4mV
2.182ns   393.8mV    104.5mV    860.3mV
3.564ns   1.138V     652.9mV    1.914V
4.404ns   1.55V      954.8mV    2.328V
5.145ns   1.83V      1.139V     2.461V
6.146ns   2.005V     1.268V     2.539V
9.97ns    2.129V     1.359V     2.612V
[Falling Waveform]
R_fixture= 50.000000
V_fixture= 3.300000
V_fixture_min= 2.700000
V_fixture_max= 3.600000
|time   V(typ)   V(min)   V(max)
0s        3.3V       2.7V       3.599V
961ps     3.315V     2.702V     3.608V
1.201ns   3.312V     2.707V     3.526V
1.502ns   3.282V     2.711V     3.323V
2.242ns   2.932V     2.654V     2.667V
3.483ns   2.145V     2.073V     1.679V
4.444ns   1.625V     1.722V     1.207V
5.225ns   1.373V     1.576V     1.083V
6.306ns   1.238V     1.486V     1.021V
9.97ns    1.124V     1.392V     954.2mV
[Falling Waveform]
R_fixture= 50.000000
V_fixture= 0.0
V_fixture_min= 0.0
V_fixture_max= 0.0
|time   V(typ)   V(min)   V(max)
0s        2.129V     1.359V     2.612V
340.3ps   2.125V     1.358V     2.457V
560.6ps   2.03V      1.358V     1.572V
810.8ps   1.439V     1.352V     457.7mV
1.071ns   636.6mV    1.305V     83.51mV
1.251ns   261mV      1.184V     29.37mV
1.431ns   89.56mV    962.6mV    14.32mV
1.832ns   13.23mV    416mV      5.676mV
2.342ns   3.295mV    49.88mV    2.776mV
4.985ns   194.8uV    84.8uV     739.9uV
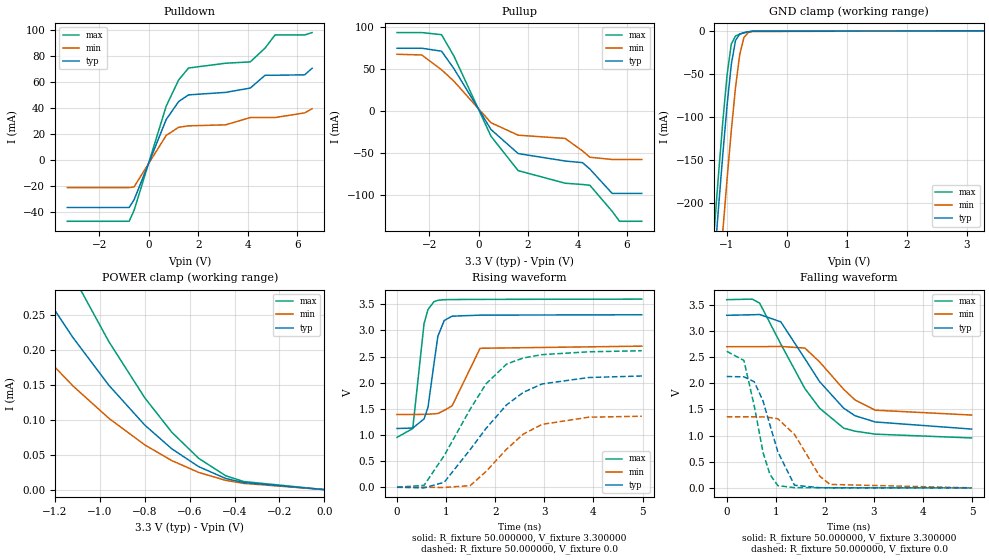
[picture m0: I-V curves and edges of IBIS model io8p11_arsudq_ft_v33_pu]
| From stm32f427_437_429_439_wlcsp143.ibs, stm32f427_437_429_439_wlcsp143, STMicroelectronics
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|   Model io8p11_arsudq_ft_v33_pu
[Model]  io8p11_arsudq_ft_v33_pu
Model_type I/O
Polarity   Non-Inverting
Enable   Active-Low
Vinl =   0.990000V
Vinh =   2.310000V
Vmeas =  1.650000V
Cref =   30.000000pF
Rref =   100.000000M
Vref =   0.0V
C_comp   2.292100pF   2.219400pF   2.369900pF
[Temperature Range]   25.000000   0.125000k   -40.000000
[Pullup Reference]   3.300000V   2.700000V   3.600000V
[Pulldown Reference]   0.0V   0.0V   0.0V
[POWER Clamp Reference]   3.300000V   2.700000V   3.600000V
[GND Clamp Reference]   0.0V   0.0V   0.0V
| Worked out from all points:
|   slope of the pulldown table from 0 to 0.495 V, typ, clamps not added: 20.9 ohm
|   slope of the pullup table from 0 to 0.495 V, typ, clamps not added: 22.6 ohm
|   GND clamp passes 1 mA (typ) near -0.62 V on its own axis
|   rising waveform, R_fixture 50.000000, V_fixture 3.300000: 20-80 % time 191ps typ, 343ps min, 162ps max; typ from 1.12 V to 3.3 V
|   rising waveform, R_fixture 50.000000, V_fixture 0.0: 20-80 % time 1.14ns typ, 932ps min, 1ns max; typ from 0.001 V to 2.13 V
|   falling waveform, R_fixture 50.000000, V_fixture 3.300000: 20-80 % time 1ns typ, 804ps min, 996ps max; typ from 3.3 V to 1.12 V
|   falling waveform, R_fixture 50.000000, V_fixture 0.0: 20-80 % time 416ps typ, 531ps min, 331ps max; typ from 2.13 V to 0.001 V
[Pulldown]
|Voltage   I(typ)   I(min)   I(max)
-3.3V     -36.46mA   -21.09mA   -47.09mA
-800mV    -36.46mA   -21.09mA   -47.09mA
-600mV    -30.5mA    -20.55mA   -38.69mA
700mV     31.4mA     19.11mA    41.71mA
1.2V      45.15mA    25.37mA    61.75mA
1.6V      50.35mA    26.5mA     71.06mA
3.1V      52.28mA    27.26mA    74.76mA
4.1V      55.64mA    32.89mA    75.8mA
4.7V      65.5mA     32.89mA    86.49mA
5.1V      65.5mA     32.89mA    96.54mA
6.3V      65.83mA    36.48mA    96.54mA
6.6V      70.88mA    39.69mA    98.4mA
[Pullup]
|Voltage   I(typ)   I(min)   I(max)
-3.3V     74.6mA     67.42mA    93.23mA
-2.3V     74.6mA     66.59mA    93.23mA
-1.5V     71.11mA    49mA       90.72mA
-1V       50.42mA    35.44mA    65.37mA
500mV     -22.06mA   -14mA      -30.03mA
1.6V      -50.64mA   -28.81mA   -70.96mA
3.5V      -59.52mA   -32.65mA   -85.91mA
4.2V      -61.43mA   -47.47mA   -87.45mA
4.5V      -69.06mA   -55.01mA   -88.37mA
5.4V      -98mA      -57.7mA    -119.3mA
5.7V      -98mA      -57.7mA    -131.2mA
6.6V      -98mA      -57.7mA    -131.2mA
[GND_clamp]
|Voltage   I(typ)   I(min)   I(max)
-3.3V     -2.314A    -2.394A    -2.288A
-1.2V     -265.5mA   -356.1mA   -227.2mA
-1.13V    -202.6mA   -292.9mA   -164.1mA
-1.06V    -142.2mA   -231.2mA   -104.1mA
-990mV    -85.98mA   -171.6mA   -50.72mA
-920mV    -38.8mA    -115.5mA   -15.28mA
-850mV    -11.08mA   -65.6mA    -6.001mA
-780mV    -3.782mA   -27.42mA   -3.876mA
-710mV    -2.086mA   -7.69mA    -2.381mA
-640mV    -1.147mA   -2.118mA   -1.22mA
-570mV    -523.9uA   -798.4uA   -476.8uA
3.28V     0A         0A         0A
[POWER_clamp]
|Voltage   I(typ)   I(min)   I(max)
-3.28V    785.2uA    403.2uA    1.133mA
-1.56V    448.2uA    307.3uA    613.5uA
-1.32V    315.9uA    216.2uA    438.6uA
-1.28V    295.2uA    201.9uA    411uA
-1.12V    217.7uA    148.5uA    306.1uA
-960mV    149.4uA    102.1uA    211.9uA
-800mV    92.4uA     64.03uA    131.4uA
-680mV    58.5uA     41.61uA    82.28uA
-560mV    32.91uA    24.62uA    44.81uA
-440mV    16uA       13.27uA    19.94uA
-360mV    10.09uA    8.954uA    11.61uA
0V        0A         0A         0A
[Ramp]
| variable   typ   min   max
dV/dt_r  1.26661/1.13051n   0.80985/0.92830n   1.56238/1.00124n
dV/dt_f  1.28280/0.99100n   0.77766/0.79586n   1.57213/0.99435n
R_load = 50.000000
[Rising Waveform]
R_fixture= 50.000000
V_fixture= 3.300000
V_fixture_min= 2.700000
V_fixture_max= 3.600000
|time   V(typ)   V(min)   V(max)
0s        1.125V     1.393V     955.5mV
320.3ps   1.134V     1.393V     1.124V
550.6ps   1.308V     1.395V     3.132V
630.6ps   1.529V     1.399V     3.4V
750.8ps   2.353V     1.405V     3.549V
830.8ps   2.885V     1.412V     3.577V
961ps     3.19V      1.472V     3.588V
1.121ns   3.273V     1.557V     3.591V
1.692ns   3.293V     2.659V     3.594V
4.985ns   3.3V       2.7V       3.599V
[Rising Waveform]
R_fixture= 50.000000
V_fixture= 0.0
V_fixture_min= 0.0
V_fixture_max= 0.0
|time   V(typ)   V(min)   V(max)
0s        1.299mV    1.126mV    1.768mV
550.6ps   -10.07mV   920.5uV    38.02mV
961ps     96.81mV    -3.153mV   607.5mV
1.491ns   723.2mV    32.86mV    1.497V
1.812ns   1.125V     301.8mV    1.978V
2.232ns   1.578V     730.5mV    2.358V
2.573ns   1.817V     1.018V     2.474V
2.953ns   1.977V     1.204V     2.537V
3.904ns   2.1V       1.341V     2.592V
4.985ns   2.129V     1.36V      2.612V
[Falling Waveform]
R_fixture= 50.000000
V_fixture= 3.300000
V_fixture_min= 2.700000
V_fixture_max= 3.600000
|time   V(typ)   V(min)   V(max)
0s        3.3V       2.7V       3.599V
520.5ps   3.31V      2.7V       3.609V
670.7ps   3.315V     2.7V       3.532V
1.101ns   3.175V     2.705V     2.751V
1.592ns   2.47V      2.673V     1.898V
1.892ns   2.031V     2.408V     1.523V
2.382ns   1.524V     1.885V     1.142V
2.613ns   1.38V      1.682V     1.085V
3.023ns   1.261V     1.486V     1.028V
4.985ns   1.125V     1.393V     955.5mV
[Falling Waveform]
R_fixture= 50.000000
V_fixture= 0.0
V_fixture_min= 0.0
V_fixture_max= 0.0
|time   V(typ)   V(min)   V(max)
0s        2.129V     1.36V      2.612V
350.4ps   2.124V     1.359V     2.436V
560.6ps   2.029V     1.359V     1.566V
740.7ps   1.659V     1.358V     674.5mV
880.9ps   1.2V       1.344V     256.4mV
1.041ns   690.5mV    1.322V     43.51mV
1.381ns   50.99mV    1.022V     4.881mV
1.892ns   4.1mV      226.9mV    3.225mV
2.102ns   3.224mV    66.79mV    3mV
4.985ns   1.299mV    1.126mV    1.768mV
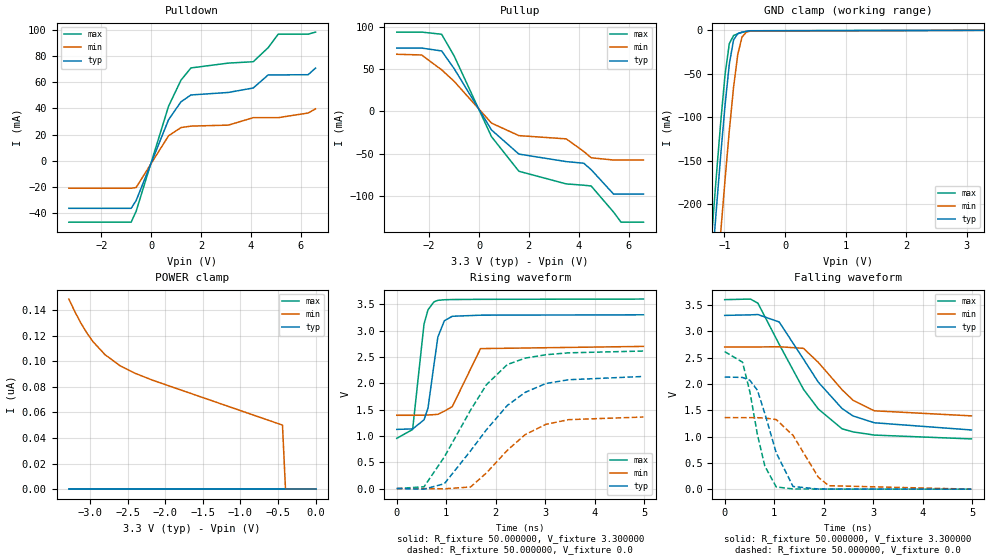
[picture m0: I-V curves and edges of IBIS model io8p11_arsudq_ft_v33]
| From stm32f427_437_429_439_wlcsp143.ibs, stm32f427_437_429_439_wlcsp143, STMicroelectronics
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|   Model io8p11_arsudq_ft_v33
[Model]  io8p11_arsudq_ft_v33
Model_type I/O
Polarity   Non-Inverting
Enable   Active-Low
Vinl =   0.990000V
Vinh =   2.310000V
Vmeas =  1.650000V
Cref =   30.000000pF
Rref =   100.000000M
Vref =   0.0V
C_comp   2.292100pF   2.219400pF   2.369900pF
[Temperature Range]   25.000000   0.125000k   -40.000000
[Pullup Reference]   3.300000V   2.700000V   3.600000V
[Pulldown Reference]   0.0V   0.0V   0.0V
[POWER Clamp Reference]   3.300000V   2.700000V   3.600000V
[GND Clamp Reference]   0.0V   0.0V   0.0V
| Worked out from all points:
|   slope of the pulldown table from 0 to 0.495 V, typ, clamps not added: 20.9 ohm
|   slope of the pullup table from 0 to 0.495 V, typ, clamps not added: 22.6 ohm
|   GND clamp passes 1 mA (typ) near -0.62 V on its own axis
|   rising waveform, R_fixture 50.000000, V_fixture 3.300000: 20-80 % time 192ps typ, 344ps min, 163ps max; typ from 1.12 V to 3.3 V
|   rising waveform, R_fixture 50.000000, V_fixture 0.0: 20-80 % time 1.13ns typ, 940ps min, 1ns max; typ from 0 V to 2.13 V
|   falling waveform, R_fixture 50.000000, V_fixture 3.300000: 20-80 % time 1ns typ, 800ps min, 996ps max; typ from 3.3 V to 1.12 V
|   falling waveform, R_fixture 50.000000, V_fixture 0.0: 20-80 % time 415ps typ, 530ps min, 333ps max; typ from 2.13 V to 0 V
[Pulldown]
|Voltage   I(typ)   I(min)   I(max)
-3.3V     -36.46mA   -21.09mA   -47.09mA
-800mV    -36.46mA   -21.09mA   -47.09mA
-600mV    -30.5mA    -20.54mA   -38.69mA
700mV     31.4mA     19.11mA    41.71mA
1.2V      45.15mA    25.37mA    61.75mA
1.6V      50.35mA    26.5mA     71.06mA
3.1V      52.28mA    27.26mA    74.76mA
4.1V      55.7mA     32.97mA    75.81mA
4.7V      65.71mA    32.97mA    86.64mA
5.1V      65.71mA    32.97mA    96.9mA
6.3V      65.88mA    36.51mA    96.9mA
6.6V      70.94mA    39.72mA    98.51mA
[Pullup]
|Voltage   I(typ)   I(min)   I(max)
-3.3V     74.74mA    67.41mA    93.64mA
-2.3V     74.74mA    66.57mA    93.64mA
-1.5V     71.36mA    49mA       91.06mA
-1V       50.51mA    35.49mA    65.51mA
500mV     -22.07mA   -14mA      -30.03mA
1.6V      -50.64mA   -28.81mA   -70.96mA
3.5V      -59.53mA   -32.65mA   -85.92mA
4.2V      -61.43mA   -47.47mA   -87.46mA
4.5V      -69.06mA   -55.01mA   -88.38mA
5.4V      -98mA      -57.7mA    -119.3mA
5.7V      -98mA      -57.7mA    -131.2mA
6.6V      -98mA      -57.7mA    -131.2mA
[GND_clamp]
|Voltage   I(typ)   I(min)   I(max)
-3.3V     -2.314A    -2.394A    -2.288A
-1.2V     -265.5mA   -356.1mA   -227.2mA
-1.13V    -202.6mA   -292.9mA   -164.1mA
-1.06V    -142.2mA   -231.2mA   -104.1mA
-990mV    -85.98mA   -171.6mA   -50.72mA
-920mV    -38.8mA    -115.5mA   -15.28mA
-850mV    -11.08mA   -65.6mA    -6.001mA
-780mV    -3.782mA   -27.42mA   -3.876mA
-710mV    -2.086mA   -7.69mA    -2.381mA
-640mV    -1.147mA   -2.118mA   -1.22mA
-570mV    -523.9uA   -798.4uA   -476.8uA
3.28V     0A         0A         0A
[POWER_clamp]
|Voltage   I(typ)   I(min)   I(max)
-3.28V    0A         148.5nA    0A
-3.2V     0A         138.6nA    0A
-3.12V    0A         129.7nA    0A
-3.04V    0A         122nA      0A
-2.96V    0A         115.3nA    0A
-2.8V     0A         105.1nA    0A
-2.6V     0A         96.44nA    0A
-2.4V     0A         90.52nA    0A
-2.16V    0A         84.97nA    0A
-440mV    0A         50.04nA    0A
-400mV    0A         0A         0A
0V        0A         0A         0A
[Ramp]
| variable   typ   min   max
dV/dt_r  1.26672/1.12429n   0.80970/0.93528n   1.56264/1.00109n
dV/dt_f  1.28346/0.99070n   0.77808/0.79187n   1.57283/0.99427n
R_load = 50.000000
[Rising Waveform]
R_fixture= 50.000000
V_fixture= 3.300000
V_fixture_min= 2.700000
V_fixture_max= 3.600000
|time   V(typ)   V(min)   V(max)
0s        1.124V     1.392V     954.2mV
320.3ps   1.133V     1.392V     1.122V
550.6ps   1.306V     1.394V     3.125V
630.6ps   1.527V     1.398V     3.394V
750.8ps   2.35V      1.404V     3.546V
830.8ps   2.881V     1.41V      3.575V
961ps     3.187V     1.47V      3.586V
1.121ns   3.272V     1.556V     3.59V
1.692ns   3.293V     2.658V     3.594V
4.985ns   3.3V       2.7V       3.599V
[Rising Waveform]
R_fixture= 50.000000
V_fixture= 0.0
V_fixture_min= 0.0
V_fixture_max= 0.0
|time   V(typ)   V(min)   V(max)
0s        211.3uV    82.92uV    632.2uV
550.6ps   -11.3mV    -125.6uV   33.62mV
961ps     92.15mV    -4.258mV   600.1mV
1.491ns   716.4mV    30.14mV    1.49V
1.812ns   1.118V     297.2mV    1.973V
2.232ns   1.577V     724.9mV    2.355V
2.593ns   1.827V     1.024V     2.477V
3.013ns   1.995V     1.22V      2.542V
3.473ns   2.067V     1.309V     2.578V
4.985ns   2.129V     1.359V     2.612V
[Falling Waveform]
R_fixture= 50.000000
V_fixture= 3.300000
V_fixture_min= 2.700000
V_fixture_max= 3.600000
|time   V(typ)   V(min)   V(max)
0s        3.3V       2.7V       3.599V
520.5ps   3.31V      2.7V       3.61V
670.7ps   3.316V     2.7V       3.532V
1.101ns   3.175V     2.705V     2.751V
1.592ns   2.469V     2.674V     1.897V
1.892ns   2.031V     2.407V     1.522V
2.372ns   1.531V     1.888V     1.146V
2.593ns   1.39V      1.688V     1.088V
3.023ns   1.261V     1.488V     1.027V
4.985ns   1.124V     1.392V     954.2mV
[Falling Waveform]
R_fixture= 50.000000
V_fixture= 0.0
V_fixture_min= 0.0
V_fixture_max= 0.0
|time   V(typ)   V(min)   V(max)
0s        2.129V     1.359V     2.612V
360.4ps   2.122V     1.358V     2.411V
510.5ps   2.066V     1.358V     1.841V
660.7ps   1.879V     1.357V     1.039V
810.8ps   1.438V     1.351V     437.9mV
1.041ns   690.7mV    1.321V     42.65mV
1.381ns   50.06mV    1.021V     3.996mV
1.892ns   3.193mV    225.9mV    2.275mV
2.102ns   2.302mV    65.5mV     2.032mV
4.985ns   211.3uV    82.92uV    632.2uV
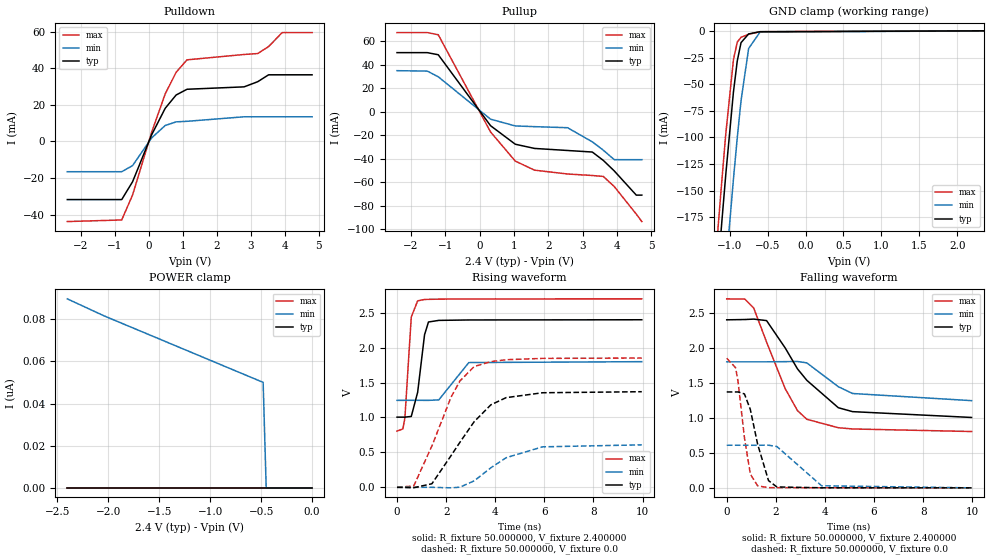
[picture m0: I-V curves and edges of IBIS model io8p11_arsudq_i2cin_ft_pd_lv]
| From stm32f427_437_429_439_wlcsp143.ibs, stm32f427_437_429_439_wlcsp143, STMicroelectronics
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|   Model io8p11_arsudq_i2cin_ft_pd_lv
[Model]  io8p11_arsudq_i2cin_ft_pd_lv
Model_type I/O
Polarity   Non-Inverting
Enable   Active-Low
Vinl =   0.720000V
Vinh =   1.680000V
Vmeas =  1.200000V
Cref =   30.000000pF
Rref =   100.000000M
Vref =   0.0V
C_comp   2.230300pF   2.174000pF   2.332300pF
[Temperature Range]   25.000000   0.125000k   -40.000000
[Pullup Reference]   2.400000V   1.800000V   2.700000V
[Pulldown Reference]   0.0V   0.0V   0.0V
[POWER Clamp Reference]   2.400000V   1.800000V   2.700000V
[GND Clamp Reference]   0.0V   0.0V   0.0V
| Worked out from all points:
|   slope of the pulldown table from 0 to 0.36 V, typ, clamps not added: 25 ohm
|   slope of the pullup table from 0 to 0.36 V, typ, clamps not added: 27.7 ohm
|   GND clamp passes 1 mA (typ) near -0.62 V on its own axis
|   rising waveform, R_fixture 50.000000, V_fixture 2.400000: 20-80 % time 284ps typ, 605ps min, 184ps max; typ from 1 V to 2.4 V
|   rising waveform, R_fixture 50.000000, V_fixture 0.0: 20-80 % time 1.7ns typ, 1.69ns min, 1.31ns max; typ from 0 V to 1.37 V
|   falling waveform, R_fixture 50.000000, V_fixture 2.400000: 20-80 % time 1.81ns typ, 1.28ns min, 1.38ns max; typ from 2.4 V to 1 V
|   falling waveform, R_fixture 50.000000, V_fixture 0.0: 20-80 % time 534ps typ, 922ps min, 383ps max; typ from 1.37 V to 0 V
[Pulldown]
|Voltage   I(typ)   I(min)   I(max)
-2.4V     -31.73mA   -16.51mA   -43.74mA
-800mV    -31.73mA   -16.51mA   -42.87mA
-480mV    -21.98mA   -13.17mA   -29.2mA
80mV      3.63mA     1.966mA    5.014mA
480mV     18.15mA    8.738mA    26.02mA
800mV     25.38mA    10.72mA    37.77mA
1.12V     28.53mA    11.02mA    44.6mA
2.8V      29.84mA    13.49mA    47.53mA
3.2V      32.65mA    13.49mA    48.04mA
3.52V     36.42mA    13.49mA    51.83mA
3.92V     36.42mA    13.49mA    59.49mA
4.8V      36.42mA    13.49mA    59.49mA
[Pullup]
|Voltage   I(typ)   I(min)   I(max)
-2.4V     50.45mA    35.08mA    67.53mA
-1.52V    50.45mA    34.74mA    67.53mA
-1.2V     48.64mA    29.87mA    65.68mA
320mV     -11.75mA   -6.207mA   -17.08mA
1.04V     -27.54mA   -11.97mA   -41.91mA
1.6V      -31.13mA   -12.58mA   -49.63mA
2.56V     -32.88mA   -13.48mA   -52.9mA
3.28V     -34.19mA   -25.52mA   -54.18mA
3.6V      -41.31mA   -32.62mA   -54.97mA
3.92V     -50.32mA   -40.7mA    -63.63mA
4.56V     -70.9mA    -40.7mA    -87.07mA
4.72V     -70.9mA    -40.7mA    -93.4mA
[GND_clamp]
|Voltage   I(typ)   I(min)   I(max)
-2.4V     -1.424A    -1.508A    -1.393A
-1.25V    -311.2mA   -401.9mA   -273.3mA
-1.2V     -265.4mA   -356.1mA   -227.2mA
-1.15V    -220.4mA   -310.8mA   -181.9mA
-1.1V     -176.3mA   -266.2mA   -137.9mA
-1.05V    -133.8mA   -222.5mA   -95.87mA
-950mV    -57.3mA    -138.9mA   -26.99mA
-900mV    -28.28mA   -100.4mA   -10.6mA
-850mV    -11.02mA   -65.54mA   -5.972mA
-750mV    -2.846mA   -16.51mA   -3.192mA
-600mV    -761.3uA   -1.173mA   -751.9uA
2.35V     58.09uA    37.92uA    67.25uA
[POWER_clamp]
|Voltage   I(typ)   I(min)   I(max)
-2.4V     0A         89.62nA    0A
-2.04V    0A         81.57nA    0A
-480mV    0A         50.01nA    0A
-450mV    0A         0A         0A
0V        0A         0A         0A
[Ramp]
| variable   typ   min   max
dV/dt_r  0.82104/1.69531n   0.36368/1.67298n   1.11036/1.31213n
dV/dt_f  0.83256/1.80268n   0.33300/1.30012n   1.13522/1.37457n
R_load = 50.000000
[Rising Waveform]
R_fixture= 50.000000
V_fixture= 2.400000
V_fixture_min= 1.800000
V_fixture_max= 2.700000
|time   V(typ)   V(min)   V(max)
0s        1.005V     1.245V     804.2mV
240.2ps   1.005V     1.245V     837.3mV
320.3ps   1.005V     1.246V     992.8mV
580.6ps   1.015V     1.246V     2.439V
840.8ps   1.361V     1.246V     2.67V
1.121ns   2.184V     1.245V     2.689V
1.281ns   2.367V     1.245V     2.691V
1.702ns   2.39V      1.252V     2.694V
2.923ns   2.396V     1.786V     2.697V
9.97ns    2.399V     1.799V     2.698V
[Rising Waveform]
R_fixture= 50.000000
V_fixture= 0.0
V_fixture_min= 0.0
V_fixture_max= 0.0
|time   V(typ)   V(min)   V(max)
0s        169.9uV    66.45uV    532.9uV
680.7ps   -5.552mV   52.83uV    19.4mV
1.421ns   51.52mV    131.2uV    592.7mV
2.202ns   454.7mV    -7.203mV   1.292V
2.563ns   645.7mV    2.343mV    1.523V
3.143ns   940.2mV    93.01mV    1.729V
3.824ns   1.182V     280.4mV    1.8V
4.444ns   1.284V     424.2mV    1.827V
5.926ns   1.354V     579.9mV    1.846V
9.97ns    1.369V     608.3mV    1.851V
[Falling Waveform]
R_fixture= 50.000000
V_fixture= 2.400000
V_fixture_min= 1.800000
V_fixture_max= 2.700000
|time   V(typ)   V(min)   V(max)
0s        2.399V     1.799V     2.698V
740.7ps   2.403V     1.799V     2.695V
1.101ns   2.409V     1.799V     2.565V
1.622ns   2.388V     1.799V     2.082V
2.382ns   1.997V     1.802V     1.416V
2.883ns   1.698V     1.804V     1.102V
3.263ns   1.535V     1.784V     978.9mV
4.545ns   1.144V     1.444V     858.4mV
5.125ns   1.088V     1.347V     840.8mV
9.97ns    1.005V     1.245V     804.2mV
[Falling Waveform]
R_fixture= 50.000000
V_fixture= 0.0
V_fixture_min= 0.0
V_fixture_max= 0.0
|time   V(typ)   V(min)   V(max)
0s        1.369V     608.3mV    1.851V
360.4ps   1.369V     608.4mV    1.715V
460.5ps   1.369V     608.3mV    1.519V
720.7ps   1.341V     608.3mV    718.2mV
961ps     1.119V     608.1mV    197.2mV
1.261ns   619.6mV    608mV      28.02mV
1.702ns   103.3mV    609mV      2.832mV
2.042ns   12.76mV    589.7mV    2.038mV
3.864ns   1.017mV    29.84mV    1.276mV
9.97ns    169.9uV    66.45uV    532.9uV
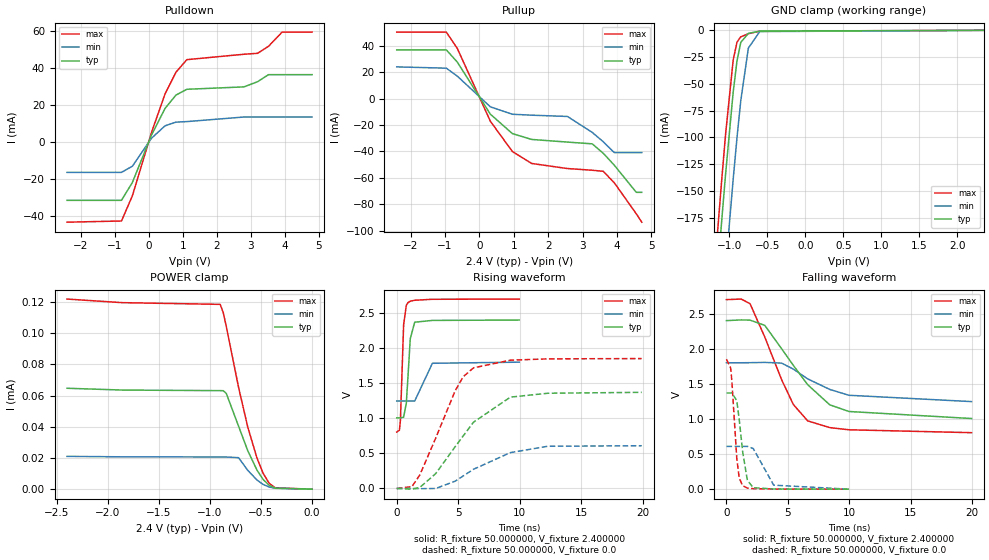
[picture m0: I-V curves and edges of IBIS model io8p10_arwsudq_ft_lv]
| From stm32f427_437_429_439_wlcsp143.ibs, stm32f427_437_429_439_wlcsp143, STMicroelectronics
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|   Model io8p10_arwsudq_ft_lv
[Model]  io8p10_arwsudq_ft_lv
Model_type I/O
Polarity   Non-Inverting
Enable   Active-Low
Vinl =   0.720000V
Vinh =   1.680000V
Vmeas =  1.200000V
Cref =   40.000000pF
Rref =   100.000000M
Vref =   0.0V
C_comp   2.828000pF   2.774700pF   2.917100pF
[Temperature Range]   25.000000   0.125000k   -40.000000
[Pullup Reference]   2.400000V   1.800000V   2.700000V
[Pulldown Reference]   0.0V   0.0V   0.0V
[POWER Clamp Reference]   2.400000V   1.800000V   2.700000V
[GND Clamp Reference]   0.0V   0.0V   0.0V
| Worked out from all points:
|   slope of the pulldown table from 0 to 0.36 V, typ, clamps not added: 25 ohm
|   slope of the pullup table from 0 to 0.36 V, typ, clamps not added: 27.7 ohm
|   GND clamp passes 1 mA (typ) near -0.62 V on its own axis
|   rising waveform, R_fixture 50.000000, V_fixture 2.400000: 20-80 % time 291ps typ, 617ps min, 206ps max; typ from 1.01 V to 2.4 V
|   rising waveform, R_fixture 50.000000, V_fixture 0.0: 20-80 % time 3.81ns typ, 3.99ns min, 2.68ns max; typ from 0 V to 1.37 V
|   falling waveform, R_fixture 50.000000, V_fixture 2.400000: 20-80 % time 3.84ns typ, 3.97ns min, 2.74ns max; typ from 2.4 V to 1.01 V
|   falling waveform, R_fixture 50.000000, V_fixture 0.0: 20-80 % time 548ps typ, 1.01ns min, 410ps max; typ from 1.37 V to 0 V
[Pulldown]
|Voltage   I(typ)   I(min)   I(max)
-2.4V     -31.67mA   -16.51mA   -43.52mA
-800mV    -31.67mA   -16.51mA   -42.87mA
-480mV    -21.98mA   -13.17mA   -29.21mA
80mV      3.63mA     1.966mA    5.013mA
480mV     18.16mA    8.738mA    26.02mA
800mV     25.38mA    10.72mA    37.77mA
1.12V     28.53mA    11.02mA    44.6mA
2.8V      29.84mA    13.5mA     47.53mA
3.2V      32.66mA    13.5mA     48.04mA
3.52V     36.46mA    13.5mA     51.85mA
3.92V     36.46mA    13.5mA     59.54mA
4.8V      36.46mA    13.5mA     59.54mA
[Pullup]
|Voltage   I(typ)   I(min)   I(max)
-2.4V     36.92mA    24.04mA    50.37mA
-960mV    36.92mA    23.06mA    50.37mA
-640mV    27.65mA    17.04mA    37.98mA
320mV     -11.75mA   -6.207mA   -17.08mA
960mV     -26.47mA   -11.82mA   -40.02mA
1.52V     -30.88mA   -12.51mA   -49.05mA
2.56V     -32.88mA   -13.49mA   -52.9mA
3.28V     -34.2mA    -25.53mA   -54.18mA
3.6V      -41.33mA   -32.62mA   -54.99mA
3.92V     -50.33mA   -40.8mA    -63.66mA
4.56V     -70.9mA    -40.8mA    -87.12mA
4.72V     -70.9mA    -40.8mA    -93.5mA
[GND_clamp]
|Voltage   I(typ)   I(min)   I(max)
-2.4V     -1.425A    -1.509A    -1.395A
-1.25V    -311.8mA   -402mA     -274.5mA
-1.2V     -266mA     -356.2mA   -228.4mA
-1.15V    -220.9mA   -310.9mA   -183.1mA
-1.1V     -176.9mA   -266.3mA   -139mA
-1.05V    -134.3mA   -222.6mA   -97.01mA
-950mV    -57.81mA   -139.1mA   -27.86mA
-900mV    -28.73mA   -100.5mA   -11.04mA
-850mV    -11.29mA   -65.69mA   -6.054mA
-750mV    -2.852mA   -16.6mA    -3.179mA
-600mV    -750uA     -1.167mA   -738.5uA
2.35V     0A         0A         0A
[POWER_clamp]
|Voltage   I(typ)   I(min)   I(max)
-2.4V     64.71uA    21.03uA    121.9uA
-1.86V    63.55uA    20.74uA    119.6uA
-900mV    63.18uA    20.63uA    118.5uA
-870mV    63.14uA    20.63uA    113.2uA
-840mV    61.36uA    20.62uA    104.3uA
-720mV    40.37uA    20.18uA    65.28uA
-630mV    24.69uA    12.08uA    39.85uA
-540mV    12.26uA    5.907uA    20uA
-480mV    6.236uA    3.061uA    10.23uA
-420mV    2.4uA      1.365uA    3.726uA
-360mV    667.9nA    564nA      839.6nA
0V        0A         0A         0A
[Ramp]
| variable   typ   min   max
dV/dt_r  0.82212/3.80705n   0.36571/3.99442n   1.11311/2.68906n
dV/dt_f  0.83358/3.84105n   0.33264/4.02532n   1.13655/2.74517n
R_load = 50.000000
[Rising Waveform]
R_fixture= 50.000000
V_fixture= 2.400000
V_fixture_min= 1.800000
V_fixture_max= 2.700000
|time   V(typ)   V(min)   V(max)
0s        1.006V     1.247V     804.5mV
220.2ps   1.006V     1.247V     830.3mV
300.3ps   1.006V     1.247V     975.3mV
560.6ps   1.016V     1.247V     2.334V
780.8ps   1.218V     1.247V     2.611V
920.9ps   1.611V     1.247V     2.65V
1.101ns   2.134V     1.247V     2.668V
1.461ns   2.369V     1.246V     2.682V
2.903ns   2.395V     1.784V     2.696V
9.97ns    2.4V       1.8V       2.699V
[Rising Waveform]
R_fixture= 50.000000
V_fixture= 0.0
V_fixture_min= 0.0
V_fixture_max= 0.0
|time   V(typ)   V(min)   V(max)
0s        171uV      66.46uV    601.9uV
1.241ns   -9.652mV   180.7uV    26.67mV
1.882ns   15.55mV    -3.26mV    194.6mV
3.163ns   210.3mV    79.57uV    715mV
4.765ns   597.5mV    105.1mV    1.396V
5.405ns   747.8mV    178.1mV    1.592V
6.246ns   944.7mV    273.8mV    1.719V
9.249ns   1.302V     511.2mV    1.828V
12.29ns   1.357V     601.9mV    1.847V
19.94ns   1.37V      609mV      1.851V
[Falling Waveform]
R_fixture= 50.000000
V_fixture= 2.400000
V_fixture_min= 1.800000
V_fixture_max= 2.700000
|time   V(typ)   V(min)   V(max)
0s        2.4V       1.8V       2.699V
1.201ns   2.41V      1.8V       2.707V
1.922ns   2.407V     1.801V     2.641V
3.123ns   2.332V     1.805V     2.164V
4.484ns   2.001V     1.795V     1.561V
5.445ns   1.762V     1.71V      1.205V
6.607ns   1.488V     1.571V     972.7mV
8.408ns   1.201V     1.42V      876.6mV
9.97ns    1.106V     1.337V     845.6mV
19.94ns   1.006V     1.247V     804.5mV
[Falling Waveform]
R_fixture= 50.000000
V_fixture= 0.0
V_fixture_min= 0.0
V_fixture_max= 0.0
|time   V(typ)   V(min)   V(max)
0s        1.37V      609mV      1.851V
340.3ps   1.37V      609mV      1.729V
440.4ps   1.37V      609mV      1.542V
840.8ps   1.261V     608.8mV    438.8mV
1.041ns   990.2mV    608.6mV    156.8mV
1.321ns   531mV      608.7mV    49.05mV
1.702ns   126.2mV    609.5mV    16.04mV
2.182ns   21.09mV    578.2mV    7.157mV
3.844ns   2.63mV     56.77mV    2.119mV
9.97ns    171uV      66.46uV    601.9uV
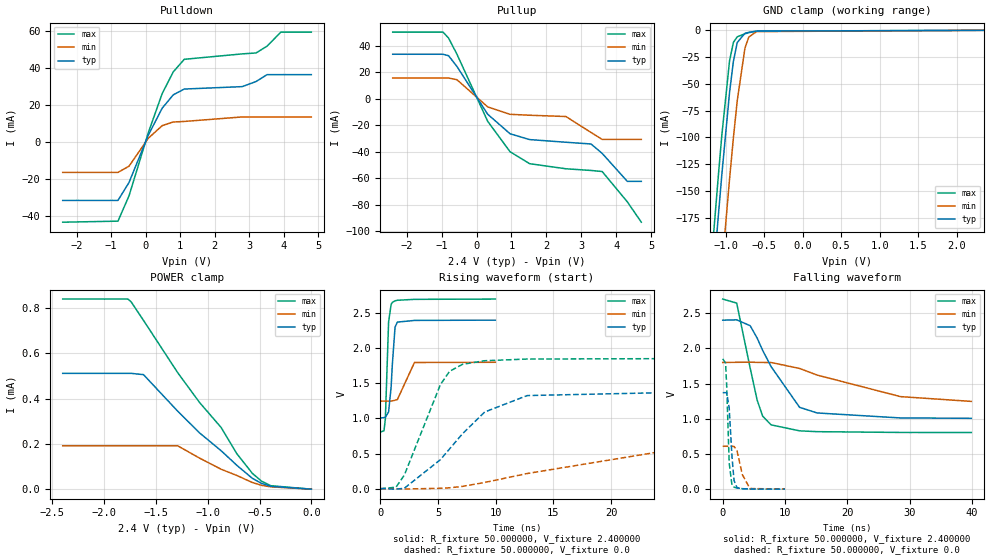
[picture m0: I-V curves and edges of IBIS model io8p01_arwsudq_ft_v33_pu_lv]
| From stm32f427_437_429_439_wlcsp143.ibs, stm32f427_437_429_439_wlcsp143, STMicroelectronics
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|   Model io8p01_arwsudq_ft_v33_pu_lv
[Model]  io8p01_arwsudq_ft_v33_pu_lv
Model_type I/O
Polarity   Non-Inverting
Enable   Active-Low
Vinl =   0.720000V
Vinh =   1.680000V
Vmeas =  1.200000V
Cref =   50.000000pF
Rref =   100.000000M
Vref =   0.0V
C_comp   2.828400pF   2.771400pF   2.910300pF
[Temperature Range]   25.000000   0.125000k   -40.000000
[Pullup Reference]   2.400000V   1.800000V   2.700000V
[Pulldown Reference]   0.0V   0.0V   0.0V
[POWER Clamp Reference]   2.400000V   1.800000V   2.700000V
[GND Clamp Reference]   0.0V   0.0V   0.0V
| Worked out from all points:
|   slope of the pulldown table from 0 to 0.36 V, typ, clamps not added: 25 ohm
|   slope of the pullup table from 0 to 0.36 V, typ, clamps not added: 27.7 ohm
|   GND clamp passes 1 mA (typ) near -0.62 V on its own axis
|   rising waveform, R_fixture 50.000000, V_fixture 2.400000: 20-80 % time 323ps typ, 711ps min, 221ps max; typ from 1.01 V to 2.4 V
|   rising waveform, R_fixture 50.000000, V_fixture 0.0: 20-80 % time 4.72ns typ, 12.1ns min, 2.67ns max; typ from 0.001 V to 1.37 V
|   falling waveform, R_fixture 50.000000, V_fixture 2.400000: 20-80 % time 5.51ns typ, 13.1ns min, 2.68ns max; typ from 2.4 V to 1.01 V
|   falling waveform, R_fixture 50.000000, V_fixture 0.0: 20-80 % time 553ps typ, 1.05ns min, 408ps max; typ from 1.37 V to 0.001 V
[Pulldown]
|Voltage   I(typ)   I(min)   I(max)
-2.4V     -31.66mA   -16.51mA   -43.42mA
-800mV    -31.66mA   -16.51mA   -42.86mA
-480mV    -21.98mA   -13.17mA   -29.21mA
80mV      3.63mA     1.966mA    5.014mA
480mV     18.16mA    8.738mA    26.02mA
800mV     25.38mA    10.72mA    37.77mA
1.12V     28.53mA    11.02mA    44.6mA
2.8V      29.84mA    13.46mA    47.53mA
3.2V      32.6mA     13.46mA    48.03mA
3.52V     36.33mA    13.46mA    51.75mA
3.92V     36.33mA    13.46mA    59.31mA
4.8V      36.33mA    13.46mA    59.31mA
[Pullup]
|Voltage   I(typ)   I(min)   I(max)
-2.4V     33.5mA     15.56mA    50.22mA
-960mV    33.5mA     15.56mA    50.22mA
-800mV    32.39mA    15.56mA    45.7mA
-560mV    24.27mA    14.3mA     33.51mA
320mV     -11.75mA   -6.207mA   -17.08mA
960mV     -26.47mA   -11.82mA   -40.02mA
1.52V     -30.88mA   -12.51mA   -49.05mA
2.56V     -32.88mA   -13.48mA   -52.9mA
3.28V     -34.2mA    -25.51mA   -54.17mA
3.6V      -41.33mA   -30.75mA   -54.99mA
4.32V     -62.42mA   -30.75mA   -77.88mA
4.72V     -62.42mA   -30.75mA   -93.2mA
[GND_clamp]
|Voltage   I(typ)   I(min)   I(max)
-2.4V     -1.428A    -1.51A     -1.401A
-1.2V     -266.4mA   -356.3mA   -229.4mA
-1.15V    -221.3mA   -311mA     -184.1mA
-1.1V     -177.3mA   -266.4mA   -140mA
-1.05V    -134.8mA   -222.7mA   -97.97mA
-950mV    -58.22mA   -139.2mA   -28.55mA
-900mV    -29.03mA   -100.6mA   -11.27mA
-850mV    -11.41mA   -65.77mA   -6.067mA
-750mV    -2.852mA   -16.63mA   -3.179mA
-700mV    -1.914mA   -6.318mA   -2.181mA
-600mV    -750uA     -1.167mA   -738.3uA
2.35V     0A         0A         0A
[POWER_clamp]
|Voltage   I(typ)   I(min)   I(max)
-2.4V     511uA      191.4uA    838.7uA
-1.77V    511uA      191.4uA    838.7uA
-1.74V    511uA      191.4uA    826.9uA
-1.62V    505.2uA    191.4uA    744.6uA
-1.29V    344.1uA    191.4uA    514uA
-1.08V    248.7uA    137.3uA    383.1uA
-870mV    169.3uA    87.75uA    271.7uA
-720mV    105.7uA    60.5uA     157.1uA
-570mV    47.98uA    29.54uA    70.06uA
-480mV    25.17uA    16.94uA    35.08uA
-390mV    12.49uA    10.17uA    15.15uA
0V        0A         0A         0A
[Ramp]
| variable   typ   min   max
dV/dt_r  0.82213/4.71909n   0.38211/12.87722n   1.11071/2.67150n
dV/dt_f  0.83634/5.51810n   0.32208/13.14629n   1.13674/2.68016n
R_load = 50.000000
[Rising Waveform]
R_fixture= 50.000000
V_fixture= 2.400000
V_fixture_min= 1.800000
V_fixture_max= 2.700000
|time   V(typ)   V(min)   V(max)
0s        1.007V     1.247V     806mV
320.3ps   1.012V     1.247V     824.8mV
440.4ps   1.017V     1.247V     993.2mV
720.7ps   1.093V     1.247V     2.373V
940.9ps   1.447V     1.247V     2.624V
1.041ns   1.758V     1.25V      2.652V
1.281ns   2.301V     1.26V      2.675V
1.481ns   2.372V     1.269V     2.683V
2.963ns   2.396V     1.797V     2.696V
9.97ns    2.4V       1.8V       2.7V
[Rising Waveform]
R_fixture= 50.000000
V_fixture= 0.0
V_fixture_min= 0.0
V_fixture_max= 0.0
|time   V(typ)   V(min)   V(max)
0s        966.8uV    875.4uV    1.111mV
1.361ns   -6.412mV   487.1uV    20.92mV
2.082ns   6.104mV    -4.762mV   192.3mV
5.205ns   412.5mV    6.246mV    1.48V
6.006ns   566.7mV    13mV       1.671V
7.127ns   782.5mV    33.2mV     1.771V
9.049ns   1.092V     88.99mV    1.822V
12.73ns   1.326V     216.3mV    1.846V
25.23ns   1.37V      553.3mV    1.852V
39.88ns   1.371V     610.3mV    1.852V
[Falling Waveform]
R_fixture= 50.000000
V_fixture= 2.400000
V_fixture_min= 1.800000
V_fixture_max= 2.700000
|time   V(typ)   V(min)   V(max)
0s        2.4V       1.8V       2.7V
2.242ns   2.405V     1.802V     2.643V
4.404ns   2.322V     1.804V     1.721V
5.526ns   2.146V     1.801V     1.265V
6.406ns   1.972V     1.8V       1.038V
7.768ns   1.74V      1.799V     913.8mV
12.33ns   1.163V     1.715V     829.1mV
15.14ns   1.083V     1.621V     817.3mV
28.51ns   1.012V     1.315V     806.2mV
39.88ns   1.007V     1.247V     806mV
[Falling Waveform]
R_fixture= 50.000000
V_fixture= 0.0
V_fixture_min= 0.0
V_fixture_max= 0.0
|time   V(typ)   V(min)   V(max)
0s        1.371V     610.3mV    1.852V
460.5ps   1.371V     610.1mV    1.791V
640.6ps   1.368V     610mV      1.462V
1.041ns   1.154V     609.8mV    370.3mV
1.481ns   470.5mV    610.9mV    61.25mV
1.822ns   122.7mV    607.5mV    29.46mV
2.302ns   21.19mV    544.3mV    16.32mV
3.143ns   6.538mV    208.3mV    7.662mV
4.364ns   4.133mV    10.42mV    3.164mV
9.97ns    966.8uV    875.4uV    1.111mV
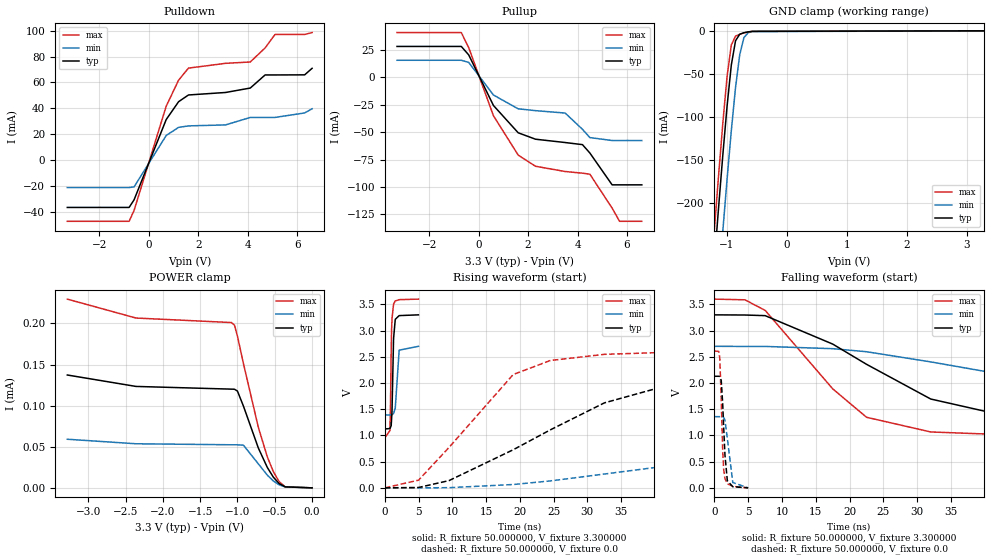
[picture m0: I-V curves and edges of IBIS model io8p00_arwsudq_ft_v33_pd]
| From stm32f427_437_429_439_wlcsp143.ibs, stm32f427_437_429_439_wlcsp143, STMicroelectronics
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|   Model io8p00_arwsudq_ft_v33_pd
[Model]  io8p00_arwsudq_ft_v33_pd
Model_type I/O
Polarity   Non-Inverting
Enable   Active-Low
Vinl =   0.990000V
Vinh =   2.310000V
Vmeas =  1.650000V
Cref =   50.000000pF
Rref =   100.000000M
Vref =   0.0V
C_comp   2.911600pF   2.826500pF   2.975800pF
[Temperature Range]   25.000000   0.125000k   -40.000000
[Pullup Reference]   3.300000V   2.700000V   3.600000V
[Pulldown Reference]   0.0V   0.0V   0.0V
[POWER Clamp Reference]   3.300000V   2.700000V   3.600000V
[GND Clamp Reference]   0.0V   0.0V   0.0V
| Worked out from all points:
|   slope of the pulldown table from 0 to 0.495 V, typ, clamps not added: 20.9 ohm
|   slope of the pullup table from 0 to 0.495 V, typ, clamps not added: 22.6 ohm
|   GND clamp passes 1 mA (typ) near -0.62 V on its own axis
|   rising waveform, R_fixture 50.000000, V_fixture 3.300000: 20-80 % time 220ps typ, 367ps min, 188ps max; typ from 1.12 V to 3.3 V
|   rising waveform, R_fixture 50.000000, V_fixture 0.0: 20-80 % time 19.7ns typ, 51.6ns min, 10.4ns max; typ from 0 V to 2.13 V
|   falling waveform, R_fixture 50.000000, V_fixture 3.300000: 20-80 % time 18.6ns typ, 38.4ns min, 11.4ns max; typ from 3.3 V to 1.12 V
|   falling waveform, R_fixture 50.000000, V_fixture 0.0: 20-80 % time 462ps typ, 671ps min, 373ps max; typ from 2.13 V to 0 V
[Pulldown]
|Voltage   I(typ)   I(min)   I(max)
-3.3V     -36.38mA   -21.07mA   -47.08mA
-800mV    -36.38mA   -21.07mA   -47.08mA
-600mV    -30.5mA    -20.54mA   -38.69mA
700mV     31.4mA     19.11mA    41.71mA
1.2V      45.15mA    25.37mA    61.75mA
1.6V      50.35mA    26.5mA     71.06mA
3.1V      52.27mA    27.26mA    74.75mA
4.1V      55.7mA     33.02mA    75.8mA
4.7V      65.79mA    33.02mA    86.63mA
5.1V      65.79mA    33.02mA    97.02mA
6.3V      65.87mA    36.5mA     97.02mA
6.6V      70.92mA    39.71mA    98.48mA
[Pullup]
|Voltage   I(typ)   I(min)   I(max)
-3.3V     28.03mA    15.43mA    40.67mA
-700mV    28.03mA    15.43mA    40.67mA
-400mV    20.31mA    13.47mA    26.93mA
600mV     -25.77mA   -16.23mA   -35.13mA
1.6V      -50.64mA   -28.81mA   -70.96mA
2.3V      -56.49mA   -30.48mA   -81.16mA
3.5V      -59.53mA   -32.66mA   -85.92mA
4.2V      -61.45mA   -47.47mA   -87.46mA
4.5V      -69.1mA    -55.02mA   -88.4mA
5.4V      -98.1mA    -57.7mA    -119.3mA
5.7V      -98.1mA    -57.7mA    -131.3mA
6.6V      -98.1mA    -57.7mA    -131.3mA
[GND_clamp]
|Voltage   I(typ)   I(min)   I(max)
-3.3V     -2.32A     -2.397A    -2.297A
-1.2V     -266.4mA   -356.3mA   -229.4mA
-1.13V    -203.6mA   -293.1mA   -166.3mA
-1.06V    -143.2mA   -231.4mA   -106.2mA
-990mV    -86.95mA   -171.8mA   -52.65mA
-920mV    -39.66mA   -115.8mA   -16.37mA
-850mV    -11.5mA    -65.84mA   -6.125mA
-780mV    -3.846mA   -27.59mA   -3.894mA
-710mV    -2.102mA   -7.761mA   -2.396mA
-640mV    -1.159mA   -2.138mA   -1.234mA
-570mV    -535.1uA   -809uA     -490.2uA
3.28V     81.28uA    57.87uA    93.98uA
[POWER_clamp]
|Voltage   I(typ)   I(min)   I(max)
-3.28V    137.3uA    59.14uA    229.6uA
-2.36V    123.4uA    53.65uA    206.6uA
-1.08V    120.1uA    52.41uA    201.1uA
-1.04V    120uA      52.41uA    198uA
-1V       117.7uA    52.4uA     184.5uA
-920mV    99.46uA    51.91uA    151.2uA
-720mV    48.42uA    29.12uA    73.51uA
-600mV    24.82uA    15.47uA    37.72uA
-520mV    13.1uA     8.45uA     19.84uA
-440mV    5.058uA    3.61uA     7.276uA
-360mV    1.193uA    1.129uA    1.311uA
0V        0A         0A         0A
[Ramp]
| variable   typ   min   max
dV/dt_r  1.27686/19.65481n   0.81522/51.74264n   1.56654/10.38495n
dV/dt_f  1.30566/18.61545n   0.78504/38.46390n   1.58746/11.43225n
R_load = 50.000000
[Rising Waveform]
R_fixture= 50.000000
V_fixture= 3.300000
V_fixture_min= 2.700000
V_fixture_max= 3.600000
|time   V(typ)   V(min)   V(max)
0s        1.123V     1.39V      953.1mV
760.8ps   1.131V     1.39V      1.092V
840.8ps   1.152V     1.39V      1.531V
951ps     1.187V     1.39V      2.645V
1.011ns   1.324V     1.393V     3.025V
1.071ns   1.469V     1.395V     3.225V
1.301ns   2.848V     1.417V     3.506V
1.552ns   3.213V     1.52V      3.564V
2.132ns   3.285V     2.626V     3.589V
4.985ns   3.299V     2.699V     3.599V
[Rising Waveform]
R_fixture= 50.000000
V_fixture= 0.0
V_fixture_min= 0.0
V_fixture_max= 0.0
|time   V(typ)   V(min)   V(max)
0s        121nV      271.2nV    640.7nV
5.005ns   7.052mV    -122.2uV   146.9mV
9.51ns    138.2mV    3.283mV    770.1mV
19.02ns   726.4mV    63.78mV    2.161V
24.52ns   1.106V     132.2mV    2.429V
32.53ns   1.621V     263.5mV    2.546V
40.54ns   1.906V     396.6mV    2.579V
55.56ns   2.059V     687mV      2.604V
108.6ns   2.124V     1.267V     2.611V
249.2ns   2.128V     1.358V     2.611V
[Falling Waveform]
R_fixture= 50.000000
V_fixture= 3.300000
V_fixture_min= 2.700000
V_fixture_max= 3.600000
|time   V(typ)   V(min)   V(max)
0s        3.299V     2.699V     3.599V
4.505ns   3.296V     2.697V     3.586V
7.508ns   3.284V     2.697V     3.384V
17.52ns   2.741V     2.654V     1.887V
22.52ns   2.356V     2.596V     1.346V
32.03ns   1.694V     2.402V     1.066V
46.55ns   1.272V     2.074V     996.6mV
63.06ns   1.182V     1.718V     968.3mV
84.58ns   1.144V     1.534V     955.7mV
249.2ns   1.123V     1.39V      953.1mV
[Falling Waveform]
R_fixture= 50.000000
V_fixture= 0.0
V_fixture_min= 0.0
V_fixture_max= 0.0
|time   V(typ)   V(min)   V(max)
0s        2.128V     1.358V     2.611V
640.6ps   2.128V     1.357V     2.601V
790.8ps   2.124V     1.357V     2.463V
1.001ns   2.046V     1.357V     1.674V
1.221ns   1.592V     1.355V     693.5mV
1.361ns   1.156V     1.344V     348.8mV
1.552ns   624.3mV    1.289V     174.4mV
1.902ns   136.3mV    944.3mV    79.81mV
2.713ns   21.71mV    102.3mV    28.39mV
4.985ns   121nV      271.2nV    640.7nV
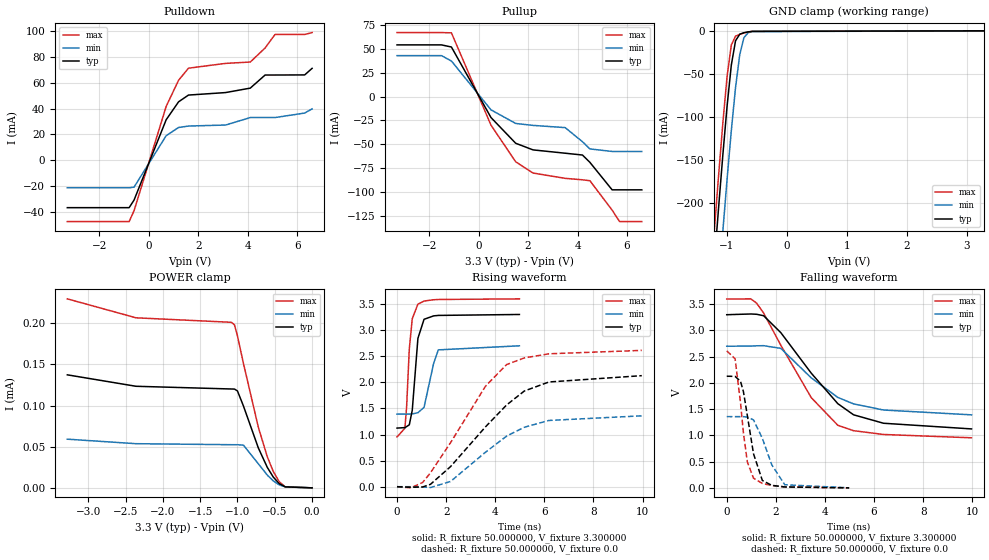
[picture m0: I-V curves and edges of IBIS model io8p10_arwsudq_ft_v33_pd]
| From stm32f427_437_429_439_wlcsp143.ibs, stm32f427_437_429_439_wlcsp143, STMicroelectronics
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|   Model io8p10_arwsudq_ft_v33_pd
[Model]  io8p10_arwsudq_ft_v33_pd
Model_type I/O
Polarity   Non-Inverting
Enable   Active-Low
Vinl =   0.990000V
Vinh =   2.310000V
Vmeas =  1.650000V
Cref =   40.000000pF
Rref =   100.000000M
Vref =   0.0V
C_comp   2.911600pF   2.823500pF   2.988000pF
[Temperature Range]   25.000000   0.125000k   -40.000000
[Pullup Reference]   3.300000V   2.700000V   3.600000V
[Pulldown Reference]   0.0V   0.0V   0.0V
[POWER Clamp Reference]   3.300000V   2.700000V   3.600000V
[GND Clamp Reference]   0.0V   0.0V   0.0V
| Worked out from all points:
|   slope of the pulldown table from 0 to 0.495 V, typ, clamps not added: 20.9 ohm
|   slope of the pullup table from 0 to 0.495 V, typ, clamps not added: 22.6 ohm
|   GND clamp passes 1 mA (typ) near -0.62 V on its own axis
|   rising waveform, R_fixture 50.000000, V_fixture 3.300000: 20-80 % time 220ps typ, 370ps min, 189ps max; typ from 1.12 V to 3.3 V
|   rising waveform, R_fixture 50.000000, V_fixture 0.0: 20-80 % time 2.51ns typ, 2.25ns min, 2.11ns max; typ from 0 V to 2.13 V
|   falling waveform, R_fixture 50.000000, V_fixture 3.300000: 20-80 % time 2.26ns typ, 2.15ns min, 2.03ns max; typ from 3.3 V to 1.12 V
|   falling waveform, R_fixture 50.000000, V_fixture 0.0: 20-80 % time 464ps typ, 672ps min, 371ps max; typ from 2.13 V to 0 V
[Pulldown]
|Voltage   I(typ)   I(min)   I(max)
-3.3V     -36.38mA   -21.07mA   -47.08mA
-800mV    -36.38mA   -21.07mA   -47.08mA
-600mV    -30.5mA    -20.54mA   -38.69mA
700mV     31.4mA     19.11mA    41.71mA
1.2V      45.15mA    25.37mA    61.75mA
1.6V      50.35mA    26.5mA     71.06mA
3.1V      52.27mA    27.26mA    74.75mA
4.1V      55.7mA     33.02mA    75.8mA
4.7V      65.79mA    33.02mA    86.63mA
5.1V      65.79mA    33.02mA    97.02mA
6.3V      65.87mA    36.5mA     97.02mA
6.6V      70.92mA    39.71mA    98.48mA
[Pullup]
|Voltage   I(typ)   I(min)   I(max)
-3.3V     54.2mA     42.91mA    67.13mA
-1.5V     54.2mA     42.91mA    67.13mA
-1.1V     51.97mA    37.28mA    66.86mA
500mV     -22.07mA   -14mA      -30.03mA
1.5V      -49.1mA    -28.3mA    -68.56mA
2.2V      -56.04mA   -30.32mA   -80.35mA
3.5V      -59.53mA   -32.66mA   -85.92mA
4.2V      -61.45mA   -47.47mA   -87.46mA
4.5V      -69.1mA    -55.02mA   -88.4mA
5.4V      -98mA      -57.7mA    -119.3mA
5.7V      -98mA      -57.7mA    -131.3mA
6.6V      -98mA      -57.7mA    -131.3mA
[GND_clamp]
|Voltage   I(typ)   I(min)   I(max)
-3.3V     -2.32A     -2.397A    -2.297A
-1.2V     -266.4mA   -356.3mA   -229.4mA
-1.13V    -203.6mA   -293.1mA   -166.3mA
-1.06V    -143.2mA   -231.4mA   -106.2mA
-990mV    -86.95mA   -171.8mA   -52.65mA
-920mV    -39.66mA   -115.8mA   -16.37mA
-850mV    -11.5mA    -65.84mA   -6.125mA
-780mV    -3.846mA   -27.59mA   -3.894mA
-710mV    -2.102mA   -7.761mA   -2.396mA
-640mV    -1.159mA   -2.138mA   -1.234mA
-570mV    -535.1uA   -809uA     -490.2uA
3.28V     81.28uA    57.87uA    93.98uA
[POWER_clamp]
|Voltage   I(typ)   I(min)   I(max)
-3.28V    137.3uA    59.14uA    229.6uA
-2.36V    123.4uA    53.65uA    206.6uA
-1.08V    120.1uA    52.41uA    201.1uA
-1.04V    120uA      52.41uA    198uA
-1V       117.7uA    52.4uA     184.5uA
-920mV    99.46uA    51.91uA    151.2uA
-720mV    48.42uA    29.12uA    73.51uA
-600mV    24.82uA    15.47uA    37.72uA
-520mV    13.1uA     8.45uA     19.84uA
-440mV    5.058uA    3.61uA     7.276uA
-360mV    1.193uA    1.129uA    1.311uA
0V        0A         0A         0A
[Ramp]
| variable   typ   min   max
dV/dt_r  1.26876/2.51669n   0.81150/2.25931n   1.56516/2.12126n
dV/dt_f  1.28508/2.25366n   0.77856/2.15032n   1.57558/2.03137n
R_load = 50.000000
[Rising Waveform]
R_fixture= 50.000000
V_fixture= 3.300000
V_fixture_min= 2.700000
V_fixture_max= 3.600000
|time   V(typ)   V(min)   V(max)
0s        1.123V     1.391V     953.8mV
320.3ps   1.132V     1.39V      1.12V
390.4ps   1.152V     1.39V      1.528V
500.5ps   1.186V     1.39V      2.64V
620.6ps   1.464V     1.395V     3.218V
850.9ps   2.842V     1.417V     3.497V
1.101ns   3.207V     1.521V     3.556V
1.491ns   3.272V     2.362V     3.581V
1.682ns   3.281V     2.621V     3.586V
4.985ns   3.299V     2.699V     3.598V
[Rising Waveform]
R_fixture= 50.000000
V_fixture= 0.0
V_fixture_min= 0.0
V_fixture_max= 0.0
|time   V(typ)   V(min)   V(max)
0s        198.7uV    84.69uV    714.9uV
560.6ps   -10.43mV   -60.37uV   -21.76mV
1.041ns   -5.662mV   -4.935mV   80.91mV
1.361ns   45.49mV    -16.25mV   265.1mV
2.182ns   385.7mV    100.6mV    844.8mV
3.604ns   1.147V     661.6mV    1.926V
4.464ns   1.566V     969.2mV    2.34V
5.185ns   1.833V     1.139V     2.467V
6.186ns   2.006V     1.269V     2.546V
9.97ns    2.127V     1.358V     2.611V
[Falling Waveform]
R_fixture= 50.000000
V_fixture= 3.300000
V_fixture_min= 2.700000
V_fixture_max= 3.600000
|time   V(typ)   V(min)   V(max)
0s        3.299V     2.699V     3.598V
981ps     3.313V     2.701V     3.601V
1.221ns   3.307V     2.707V     3.518V
1.502ns   3.28V      2.709V     3.331V
2.202ns   2.958V     2.658V     2.718V
3.443ns   2.185V     2.095V     1.719V
4.525ns   1.604V     1.723V     1.192V
5.165ns   1.392V     1.6V       1.089V
6.386ns   1.231V     1.483V     1.017V
9.97ns    1.123V     1.391V     953.8mV
[Falling Waveform]
R_fixture= 50.000000
V_fixture= 0.0
V_fixture_min= 0.0
V_fixture_max= 0.0
|time   V(typ)   V(min)   V(max)
0s        2.127V     1.358V     2.611V
340.3ps   2.124V     1.357V     2.459V
560.6ps   2.031V     1.357V     1.627V
680.7ps   1.832V     1.356V     1.043V
840.8ps   1.374V     1.349V     491.3mV
1.091ns   649.2mV    1.294V     184.4mV
1.451ns   140.9mV    943.6mV    83.59mV
1.832ns   48.53mV    440.9mV    44.37mV
2.362ns   16.82mV    59.14mV    17.8mV
4.985ns   198.7uV    84.69uV    714.9uV
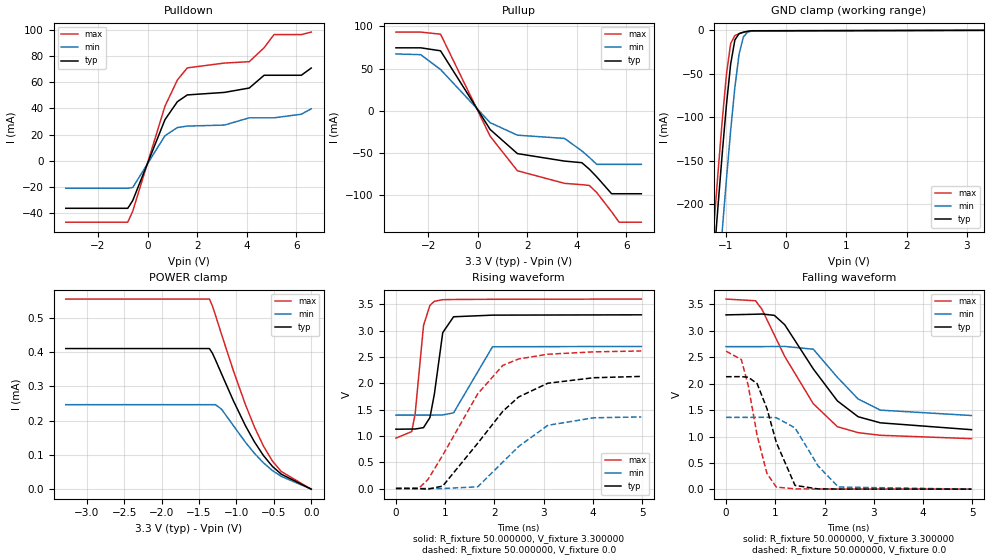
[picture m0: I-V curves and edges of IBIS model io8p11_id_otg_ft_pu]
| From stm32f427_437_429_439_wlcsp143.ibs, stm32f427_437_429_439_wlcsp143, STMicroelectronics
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|   Model io8p11_id_otg_ft_pu
[Model]  io8p11_id_otg_ft_pu
Model_type I/O
Polarity   Non-Inverting
Enable   Active-Low
Vinl =   0.990000V
Vinh =   2.310000V
Vmeas =  1.650000V
Cref =   30.000000pF
Rref =   100.000000M
Vref =   0.0V
C_comp   2.283100pF   2.214400pF   2.357400pF
[Temperature Range]   25.000000   0.125000k   -40.000000
[Pullup Reference]   3.300000V   2.700000V   3.600000V
[Pulldown Reference]   0.0V   0.0V   0.0V
[POWER Clamp Reference]   3.300000V   2.700000V   3.600000V
[GND Clamp Reference]   0.0V   0.0V   0.0V
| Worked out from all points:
|   slope of the pulldown table from 0 to 0.495 V, typ, clamps not added: 20.9 ohm
|   slope of the pullup table from 0 to 0.495 V, typ, clamps not added: 22.6 ohm
|   GND clamp passes 1 mA (typ) near -0.62 V on its own axis
|   rising waveform, R_fixture 50.000000, V_fixture 3.300000: 20-80 % time 196ps typ, 343ps min, 160ps max; typ from 1.13 V to 3.3 V
|   rising waveform, R_fixture 50.000000, V_fixture 0.0: 20-80 % time 1.13ns typ, 969ps min, 1ns max; typ from 0.005 V to 2.13 V
|   falling waveform, R_fixture 50.000000, V_fixture 3.300000: 20-80 % time 1.01ns typ, 790ps min, 984ps max; typ from 3.3 V to 1.13 V
|   falling waveform, R_fixture 50.000000, V_fixture 0.0: 20-80 % time 417ps typ, 536ps min, 333ps max; typ from 2.13 V to 0.005 V
[Pulldown]
|Voltage   I(typ)   I(min)   I(max)
-3.3V     -36.46mA   -21.09mA   -47.09mA
-800mV    -36.46mA   -21.09mA   -47.09mA
-600mV    -30.5mA    -20.54mA   -38.69mA
700mV     31.4mA     19.11mA    41.71mA
1.2V      45.15mA    25.37mA    61.75mA
1.6V      50.35mA    26.5mA     71.05mA
3.1V      52.28mA    27.26mA    74.75mA
4.1V      55.64mA    32.83mA    75.8mA
4.7V      65.4mA     32.83mA    86.49mA
5.1V      65.4mA     32.83mA    96.56mA
6.2V      65.4mA     35.57mA    96.56mA
6.6V      70.92mA    39.71mA    98.46mA
[Pullup]
|Voltage   I(typ)   I(min)   I(max)
-3.3V     74.7mA     67.42mA    93.33mA
-2.3V     74.7mA     66.58mA    93.33mA
-1.5V     71.17mA    49mA       90.85mA
500mV     -22.06mA   -13.99mA   -30.02mA
1.6V      -50.63mA   -28.8mA    -70.94mA
3.5V      -59.51mA   -32.64mA   -85.89mA
4.2V      -61.41mA   -47.47mA   -87.43mA
4.5V      -69.05mA   -55.11mA   -88.35mA
4.8V      -78.2mA    -63.4mA    -96.8mA
5.4V      -98.2mA    -63.4mA    -119.5mA
5.7V      -98.2mA    -63.4mA    -131.9mA
6.6V      -98.2mA    -63.4mA    -131.9mA
[GND_clamp]
|Voltage   I(typ)   I(min)   I(max)
-3.3V     -2.316A    -2.396A    -2.289A
-1.2V     -265.5mA   -356.1mA   -227.2mA
-1.13V    -202.7mA   -292.9mA   -164.1mA
-1.06V    -142.2mA   -231.2mA   -104.1mA
-990mV    -85.98mA   -171.6mA   -50.73mA
-920mV    -38.81mA   -115.5mA   -15.3mA
-850mV    -11.1mA    -65.61mA   -6.021mA
-780mV    -3.796mA   -27.43mA   -3.892mA
-710mV    -2.096mA   -7.699mA   -2.393mA
-640mV    -1.154mA   -2.125mA   -1.227mA
-570mV    -528.1uA   -803.6uA   -480.7uA
3.28V     0A         0A         0A
[POWER_clamp]
|Voltage   I(typ)   I(min)   I(max)
-3.28V    410.1uA    246.5uA    554.5uA
-1.36V    410.1uA    246.5uA    554.5uA
-1.32V    396.3uA    246.5uA    534.1uA
-1.28V    377.3uA    246.5uA    507.5uA
-1.2V     337.1uA    233.5uA    452.5uA
-1.04V    257.7uA    185.3uA    345.3uA
-880mV    185.4uA    137uA      247uA
-760mV    138.3uA    104.8uA    181.8uA
-640mV    98.44uA    77.14uA    126.4uA
-520mV    66.65uA    54.47uA    82.45uA
-400mV    43.68uA    37.32uA    51.43uA
0V        0A         0A         0A
[Ramp]
| variable   typ   min   max
dV/dt_r  1.26036/1.11787n   0.80586/0.96032n   1.55901/0.99901n
dV/dt_f  1.27386/0.99597n   0.77610/0.78717n   1.56673/0.97708n
R_load = 50.000000
[Rising Waveform]
R_fixture= 50.000000
V_fixture= 3.300000
V_fixture_min= 2.700000
V_fixture_max= 3.600000
|time   V(typ)   V(min)   V(max)
0s        1.129V     1.397V     959.6mV
320.3ps   1.132V     1.397V     1.084V
390.4ps   1.133V     1.397V     1.42V
560.6ps   1.159V     1.397V     3.097V
690.7ps   1.35V      1.397V     3.48V
780.8ps   1.796V     1.397V     3.557V
951ps     2.962V     1.4V       3.587V
1.171ns   3.263V     1.44V      3.591V
1.962ns   3.294V     2.694V     3.595V
4.985ns   3.3V       2.7V       3.599V
[Rising Waveform]
R_fixture= 50.000000
V_fixture= 0.0
V_fixture_min= 0.0
V_fixture_max= 0.0
|time   V(typ)   V(min)   V(max)
0s        4.839mV    4.389mV    5.393mV
470.5ps   1.735mV    4.328mV    12.4mV
650.7ps   -8.846mV   4.391mV    174.7mV
951ps     50.38mV    3.2mV      635.9mV
1.662ns   863.2mV    35.9mV     1.801V
2.172ns   1.47V      506.4mV    2.341V
2.492ns   1.741V     800.9mV    2.462V
3.083ns   2.001V     1.202V     2.552V
4.014ns   2.106V     1.346V     2.597V
4.985ns   2.131V     1.362V     2.614V
[Falling Waveform]
R_fixture= 50.000000
V_fixture= 3.300000
V_fixture_min= 2.700000
V_fixture_max= 3.600000
|time   V(typ)   V(min)   V(max)
0s        3.3V       2.7V       3.599V
600.6ps   3.312V     2.7V       3.567V
730.7ps   3.316V     2.7V       3.403V
981ps     3.291V     2.701V     2.92V
1.191ns   3.115V     2.704V     2.515V
1.772ns   2.278V     2.651V     1.62V
2.262ns   1.673V     2.119V     1.185V
2.683ns   1.374V     1.709V     1.073V
3.133ns   1.259V     1.499V     1.023V
4.985ns   1.129V     1.397V     959.6mV
[Falling Waveform]
R_fixture= 50.000000
V_fixture= 0.0
V_fixture_min= 0.0
V_fixture_max= 0.0
|time   V(typ)   V(min)   V(max)
0s        2.131V     1.362V     2.614V
310.3ps   2.132V     1.362V     2.455V
450.5ps   2.121V     1.362V     1.963V
630.6ps   2.001V     1.362V     1.025V
830.8ps   1.528V     1.364V     301.6mV
1.021ns   887.2mV    1.356V     44.08mV
1.401ns   75.18mV    1.163V     9.139mV
1.872ns   8.945mV    441.1mV    7.354mV
2.282ns   6.876mV    44.94mV    6.756mV
4.985ns   4.839mV    4.389mV    5.393mV
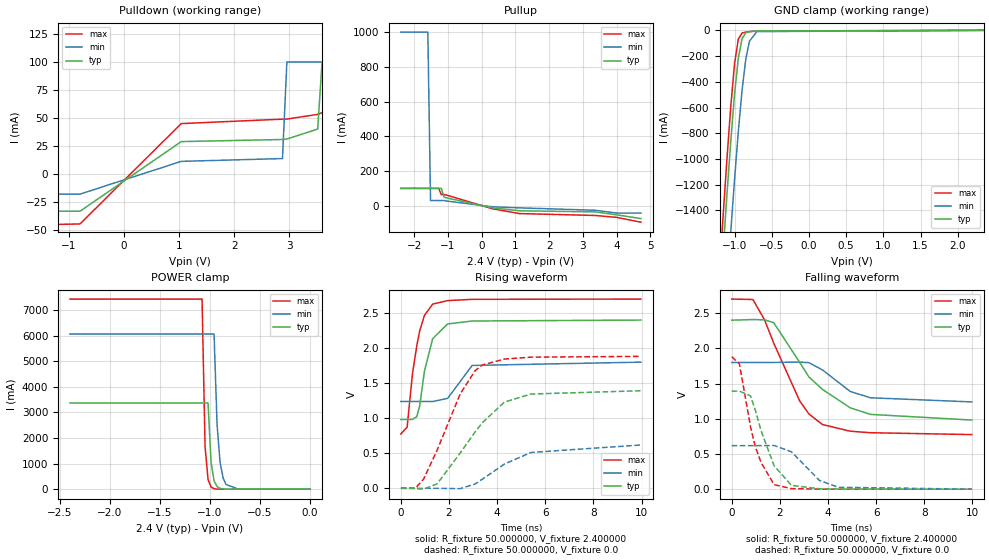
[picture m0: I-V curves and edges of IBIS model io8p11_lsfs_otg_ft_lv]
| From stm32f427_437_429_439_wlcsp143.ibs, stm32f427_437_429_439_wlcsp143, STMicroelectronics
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|   Model io8p11_lsfs_otg_ft_lv
[Model]  io8p11_lsfs_otg_ft_lv
Model_type I/O
Polarity   Non-Inverting
Enable   Active-Low
Vinl =   0.720000V
Vinh =   1.680000V
Vmeas =  1.200000V
Cref =   30.000000pF
Rref =   100.000000M
Vref =   0.0V
C_comp   7.971100pF   7.737700pF   8.264100pF
[Temperature Range]   25.000000   0.125000k   -40.000000
[Pullup Reference]   2.400000V   1.800000V   2.700000V
[Pulldown Reference]   0.0V   0.0V   0.0V
[POWER Clamp Reference]   2.400000V   1.800000V   2.700000V
[GND Clamp Reference]   0.0V   0.0V   0.0V
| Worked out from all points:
|   slope of the pulldown table from 0 to 0.36 V, typ, clamps not added: 24.1 ohm
|   slope of the pullup table from 0 to 0.36 V, typ, clamps not added: 26.8 ohm
|   GND clamp passes 1 mA (typ) near -0.52 V on its own axis
|   POWER clamp passes 1 mA (typ) near -0.81 V on its own axis
|   rising waveform, R_fixture 50.000000, V_fixture 2.400000: 20-80 % time 480ps typ, 591ps min, 481ps max; typ from 0.981 V to 2.4 V
|   rising waveform, R_fixture 50.000000, V_fixture 0.0: 20-80 % time 1.81ns typ, 1.82ns min, 1.43ns max; typ from 0 V to 1.39 V
|   falling waveform, R_fixture 50.000000, V_fixture 2.400000: 20-80 % time 1.98ns typ, 1.47ns min, 1.53ns max; typ from 2.4 V to 0.981 V
|   falling waveform, R_fixture 50.000000, V_fixture 0.0: 20-80 % time 864ps typ, 1.06ns min, 755ps max; typ from 1.39 V to 0 V
[Pulldown]
|Voltage   I(typ)   I(min)   I(max)
-2.4V     -33.44mA   -18.12mA   -46.52mA
-800mV    -33.44mA   -18.12mA   -44.78mA
1.04V     28.81mA    11.14mA    44.91mA
2.88V     30.71mA    13.65mA    48.89mA
2.96V     31.11mA    100mA      48.94mA
3.52V     40mA       100mA      53.15mA
3.6V      100mA      100mA      54.66mA
3.92V     100mA      100mA      60mA
4V        100mA      100mA      100mA
4.4V      100mA      100mA      100mA
4.48V     100mA      100mA      1A
4.8V      100mA      100mA      1A
[Pullup]
|Voltage   I(typ)   I(min)   I(max)
-2.4V     100mA      1A         100mA
-1.6V     100mA      1A         100mA
-1.52V    100mA      30mA       100mA
-1.28V    100mA      30mA       100mA
-1.2V     100mA      30mA       64mA
-1.12V    50mA       30mA       64mA
-1.04V    44.9mA     27mA       61.1mA
320mV     -12.14mA   -6.322mA   -17.91mA
1.12V     -29.18mA   -12.28mA   -45.16mA
3.36V     -35.34mA   -26.1mA    -56.1mA
4V        -52.4mA    -42mA      -67mA
4.72V     -74mA      -42mA      -94.8mA
[GND_clamp]
|Voltage   I(typ)   I(min)   I(max)
-2.4V     -9.765A    -9.942A    -9.572A
-1.2V     -2.124A    -2.851A    -1.855A
-1.15V    -1.682A    -2.408A    -1.408A
-1.1V     -1.256A    -1.975A    -979.8mA
-1.05V    -854.9mA   -1.556A    -584.5mA
-1V       -496.5mA   -1.158A    -257.5mA
-950mV    -217.7mA   -789.6mA   -69.52mA
-900mV    -65.57mA   -469.8mA   -21.5mA
-850mV    -19.64mA   -226.4mA   -13.56mA
-800mV    -9.753mA   -84.21mA   -10.47mA
-700mV    -4.923mA   -9.884mA   -5.807mA
2.35V     0A         0A         0A
[POWER_clamp]
|Voltage   I(typ)   I(min)   I(max)
-2.4V     3.365A     6.064A     7.43A
-1.08V    3.365A     6.064A     7.43A
-1.05V    3.365A     6.064A     1.669A
-1.02V    3.365A     6.064A     375mA
-990mV    1.047A     6.064A     84.24mA
-960mV    325.6mA    6.064A     18.93mA
-930mV    101.3mA    2.529A     4.252mA
-900mV    31.51mA    1.055A     955.2uA
-870mV    9.804mA    440.1mA    214.6uA
-840mV    3.05mA     183.6mA    74uA
-720mV    28.58uA    5.557mA    74uA
0V        0A         0A         0A
[Ramp]
| variable   typ   min   max
dV/dt_r  0.83454/1.81098n   0.36936/1.81412n   1.12842/1.42755n
dV/dt_f  0.84826/1.98515n   0.33504/1.46610n   1.15338/1.53062n
R_load = 50.000000
[Rising Waveform]
R_fixture= 50.000000
V_fixture= 2.400000
V_fixture_min= 1.800000
V_fixture_max= 2.700000
|time   V(typ)   V(min)   V(max)
0s        981.5mV    1.239V     775.1mV
260.3ps   981.1mV    1.239V     872.8mV
480.5ps   983.1mV    1.239V     1.63V
660.7ps   1.022V     1.239V     2.033V
780.8ps   1.174V     1.239V     2.245V
981ps     1.675V     1.239V     2.468V
1.321ns   2.135V     1.238V     2.628V
1.942ns   2.345V     1.283V     2.678V
2.963ns   2.387V     1.753V     2.696V
9.97ns    2.4V       1.8V       2.7V
[Rising Waveform]
R_fixture= 50.000000
V_fixture= 0.0
V_fixture_min= 0.0
V_fixture_max= 0.0
|time   V(typ)   V(min)   V(max)
0s        15.64uV    7.251uV    -171.9uV
600.6ps   -3.263mV   4.315uV    1.324mV
940.9ps   -12.43mV   24.09uV    129.4mV
1.502ns   61.97mV    -112.4uV   541.2mV
2.462ns   502.5mV    -5.532mV   1.345V
3.083ns   804.3mV    61.72mV    1.678V
3.383ns   935.6mV    130mV      1.759V
4.304ns   1.231V     346.6mV    1.844V
5.405ns   1.345V     511.4mV    1.871V
9.97ns    1.392V     617.9mV    1.882V
[Falling Waveform]
R_fixture= 50.000000
V_fixture= 2.400000
V_fixture_min= 1.800000
V_fixture_max= 2.700000
|time   V(typ)   V(min)   V(max)
0s        2.4V       1.8V       2.7V
880.9ps   2.409V     1.8V       2.694V
1.361ns   2.405V     1.8V       2.407V
1.742ns   2.366V     1.8V       2.077V
2.823ns   1.802V     1.805V     1.253V
3.203ns   1.596V     1.797V     1.07V
3.764ns   1.418V     1.695V     918.3mV
4.925ns   1.155V     1.387V     823mV
5.766ns   1.062V     1.298V     801.6mV
9.97ns    981.5mV    1.239V     775.1mV
[Falling Waveform]
R_fixture= 50.000000
V_fixture= 0.0
V_fixture_min= 0.0
V_fixture_max= 0.0
|time   V(typ)   V(min)   V(max)
0s        1.392V     617.9mV    1.882V
320.3ps   1.393V     617.9mV    1.78V
780.8ps   1.325V     617.9mV    887.8mV
981ps     1.122V     617.7mV    602.2mV
1.221ns   829.7mV    617.7mV    377.7mV
1.762ns   331.3mV    620.4mV    63.54mV
2.482ns   53.54mV    530.2mV    7.805mV
3.644ns   5.245mV    123.6mV    344.5uV
4.424ns   1.615mV    26.44mV    318uV
9.97ns    15.64uV    7.251uV    -171.9uV
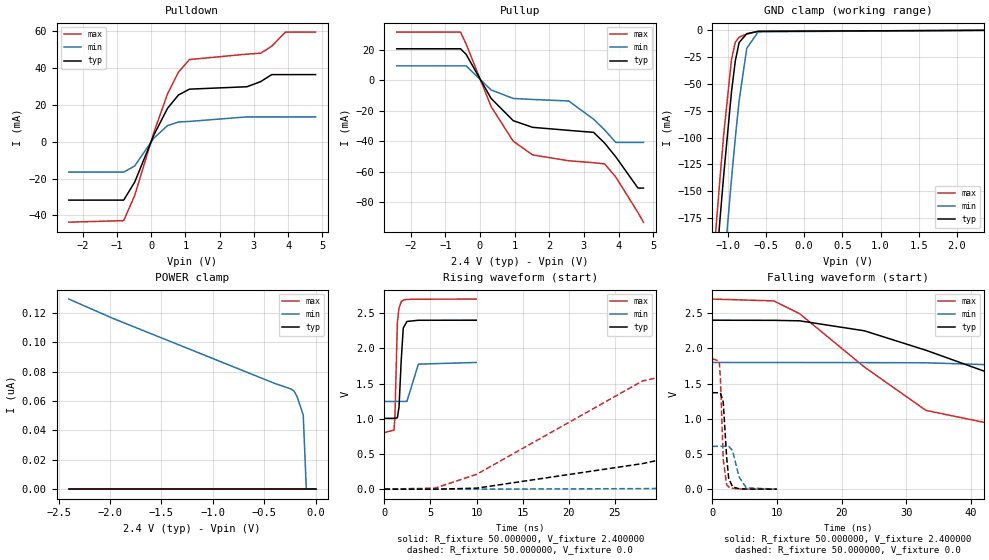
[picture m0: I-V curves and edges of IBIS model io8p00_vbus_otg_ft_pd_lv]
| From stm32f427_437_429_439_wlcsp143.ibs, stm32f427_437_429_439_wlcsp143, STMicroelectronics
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|   Model io8p00_vbus_otg_ft_pd_lv
[Model]  io8p00_vbus_otg_ft_pd_lv
Model_type I/O
Polarity   Non-Inverting
Enable   Active-Low
Vinl =   0.720000V
Vinh =   1.680000V
Vmeas =  1.200000V
Cref =   50.000000pF
Rref =   100.000000M
Vref =   0.0V
C_comp   3.193600pF   3.100000pF   3.332000pF
[Temperature Range]   25.000000   0.125000k   -40.000000
[Pullup Reference]   2.400000V   1.800000V   2.700000V
[Pulldown Reference]   0.0V   0.0V   0.0V
[POWER Clamp Reference]   2.400000V   1.800000V   2.700000V
[GND Clamp Reference]   0.0V   0.0V   0.0V
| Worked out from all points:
|   slope of the pulldown table from 0 to 0.36 V, typ, clamps not added: 25 ohm
|   slope of the pullup table from 0 to 0.36 V, typ, clamps not added: 27.7 ohm
|   GND clamp passes 1 mA (typ) near -0.61 V on its own axis
|   rising waveform, R_fixture 50.000000, V_fixture 2.400000: 20-80 % time 308ps typ, 629ps min, 213ps max; typ from 1 V to 2.4 V
|   rising waveform, R_fixture 50.000000, V_fixture 0.0: 20-80 % time 30.9ns typ, 73.2ns min, 14.3ns max; typ from 0 V to 1.37 V
|   falling waveform, R_fixture 50.000000, V_fixture 2.400000: 20-80 % time 29.2ns typ, 72.4ns min, 15.9ns max; typ from 2.4 V to 1 V
|   falling waveform, R_fixture 50.000000, V_fixture 0.0: 20-80 % time 573ps typ, 1.04ns min, 435ps max; typ from 1.37 V to 0 V
[Pulldown]
|Voltage   I(typ)   I(min)   I(max)
-2.4V     -31.69mA   -16.5mA    -43.66mA
-800mV    -31.69mA   -16.5mA    -42.82mA
-480mV    -21.96mA   -13.17mA   -29.19mA
80mV      3.63mA     1.966mA    5.014mA
480mV     18.15mA    8.738mA    26.02mA
800mV     25.38mA    10.72mA    37.77mA
1.12V     28.53mA    11.02mA    44.6mA
2.8V      29.84mA    13.49mA    47.53mA
3.2V      32.65mA    13.49mA    48.04mA
3.52V     36.42mA    13.49mA    51.83mA
3.92V     36.42mA    13.49mA    59.49mA
4.8V      36.42mA    13.49mA    59.49mA
[Pullup]
|Voltage   I(typ)   I(min)   I(max)
-2.4V     20.89mA    9.659mA    31.9mA
-560mV    20.89mA    9.659mA    31.9mA
-400mV    17.28mA    9.659mA    24.07mA
320mV     -11.75mA   -6.207mA   -17.08mA
960mV     -26.47mA   -11.82mA   -40.02mA
1.52V     -30.88mA   -12.51mA   -49.05mA
2.56V     -32.88mA   -13.49mA   -52.9mA
3.28V     -34.19mA   -25.52mA   -54.18mA
3.6V      -41.31mA   -32.61mA   -54.99mA
3.92V     -50.32mA   -40.8mA    -63.62mA
4.56V     -70.9mA    -40.8mA    -87.08mA
4.72V     -70.9mA    -40.8mA    -93.4mA
[GND_clamp]
|Voltage   I(typ)   I(min)   I(max)
-2.4V     -1.425A    -1.509A    -1.394A
-1.25V    -311.3mA   -401.9mA   -273.4mA
-1.2V     -265.5mA   -356.1mA   -227.3mA
-1.15V    -220.5mA   -310.9mA   -182mA
-1.1V     -176.4mA   -266.2mA   -138mA
-1.05V    -133.9mA   -222.5mA   -96.06mA
-950mV    -57.51mA   -139mA     -27.36mA
-900mV    -28.55mA   -100.5mA   -11.04mA
-850mV    -11.34mA   -65.68mA   -6.337mA
-750mV    -3.08mA    -16.7mA    -3.439mA
-600mV    -875.9uA   -1.303mA   -865.8uA
2.35V     58.09uA    37.92uA    67.25uA
[POWER_clamp]
|Voltage   I(typ)   I(min)   I(max)
-2.4V     0A         129.4nA    0A
-1.98V    0A         116.5nA    0A
-390mV    0A         71.78nA    0A
-240mV    0A         68.22nA    0A
-210mV    0A         66.81nA    0A
-180mV    0A         62.95nA    0A
-120mV    0A         50.47nA    0A
-90mV     0A         0A         0A
0V        0A         0A         0A
[Ramp]
| variable   typ   min   max
dV/dt_r  0.82260/30.94244n   0.36140/74.97211n   1.11030/14.32896n
dV/dt_f  0.83676/29.17719n   0.32730/74.00893n   1.13690/15.88912n
R_load = 50.000000
[Rising Waveform]
R_fixture= 50.000000
V_fixture= 2.400000
V_fixture_min= 1.800000
V_fixture_max= 2.700000
|time   V(typ)   V(min)   V(max)
0s        1.005V     1.245V     804.1mV
1.041ns   1.005V     1.245V     837.6mV
1.141ns   1.005V     1.246V     1.038V
1.401ns   1.014V     1.246V     2.36V
1.582ns   1.161V     1.246V     2.571V
1.822ns   1.827V     1.246V     2.661V
2.042ns   2.287V     1.245V     2.685V
2.442ns   2.381V     1.247V     2.694V
3.684ns   2.398V     1.775V     2.697V
9.97ns    2.399V     1.799V     2.699V
[Rising Waveform]
R_fixture= 50.000000
V_fixture= 0.0
V_fixture_min= 0.0
V_fixture_max= 0.0
|time   V(typ)   V(min)   V(max)
0s        6.131nV    367.2nV    2.475nV
5.506ns   -152.7uV   -164.9uV   14.98mV
10.01ns   13.97mV    -63.46uV   210.4mV
28.03ns   362.8mV    7.604mV    1.537V
34.03ns   533.3mV    17.5mV     1.705V
41.04ns   755.7mV    29.04mV    1.78V
60.56ns   1.184V     78.77mV    1.835V
80.58ns   1.317V     190.3mV    1.849V
149.6ns   1.367V     510.1mV    1.851V
249.2ns   1.369V     608.5mV    1.851V
[Falling Waveform]
R_fixture= 50.000000
V_fixture= 2.400000
V_fixture_min= 1.800000
V_fixture_max= 2.700000
|time   V(typ)   V(min)   V(max)
0s        2.399V     1.799V     2.699V
9.51ns    2.397V     1.798V     2.673V
13.51ns   2.39V      1.798V     2.49V
23.52ns   2.248V     1.797V     1.733V
33.03ns   1.972V     1.794V     1.118V
44.04ns   1.609V     1.763V     910mV
59.56ns   1.247V     1.712V     849mV
87.09ns   1.073V     1.557V     817mV
137.6ns   1.017V     1.35V      805.4mV
249.2ns   1.005V     1.245V     804.1mV
[Falling Waveform]
R_fixture= 50.000000
V_fixture= 0.0
V_fixture_min= 0.0
V_fixture_max= 0.0
|time   V(typ)   V(min)   V(max)
0s        1.369V     608.5mV    1.851V
1.061ns   1.369V     608.4mV    1.819V
1.241ns   1.369V     608.4mV    1.583V
1.682ns   1.236V     608.2mV    421.6mV
2.202ns   462.8mV    608.3mV    66.22mV
2.523ns   155.8mV    609.2mV    30.85mV
3.123ns   31.84mV    546.8mV    11.48mV
4.124ns   6.454mV    173.6mV    2.831mV
5.245ns   1.556mV    18.75mV    236.3uV
9.97ns    6.131nV    367.2nV    2.475nV
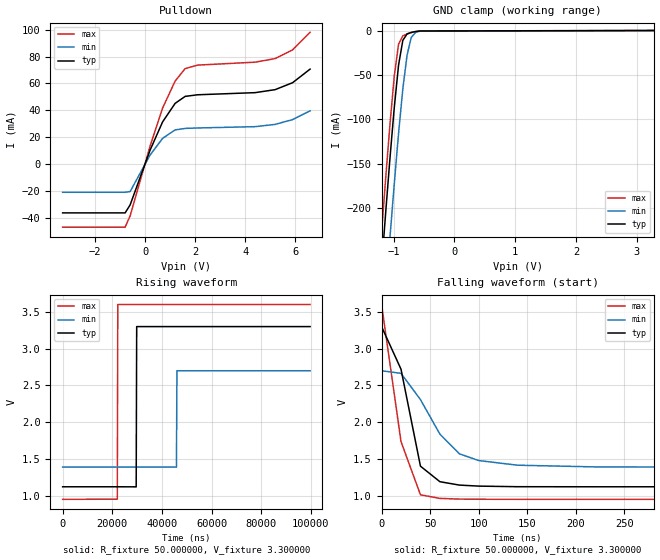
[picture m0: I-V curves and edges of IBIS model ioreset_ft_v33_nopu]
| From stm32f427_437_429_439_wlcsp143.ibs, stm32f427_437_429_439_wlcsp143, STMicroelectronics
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|   Model ioreset_ft_v33_nopu
[Model]  ioreset_ft_v33_nopu
Model_type I/O_open_drain
Polarity   Inverting
Enable   Active-High
Vinl =   0.990000V
Vinh =   2.310000V
Vmeas =  1.650000V
Cref =   1.0000000000000001E-7F
Rref =   1.000000k
Vref =   3.300000V
C_comp   2.072900pF   1.973900pF   2.107400pF
[Temperature Range]   25.000000   0.125000k   -40.000000
[Pullup Reference]   3.300000V   2.700000V   3.600000V
[Pulldown Reference]   0.0V   0.0V   0.0V
[POWER Clamp Reference]   3.300000V   2.700000V   3.600000V
[GND Clamp Reference]   0.0V   0.0V   0.0V
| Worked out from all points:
|   slope of the pulldown table from 0 to 0.495 V, typ, clamps not added: 20.9 ohm
|   GND clamp passes 1 mA (typ) near -0.62 V on its own axis
|   rising waveform, R_fixture 50.000000, V_fixture 3.300000: 20-80 % time 120ns typ, 120ns min, 120ns max; typ from 1.12 V to 3.3 V
|   falling waveform, R_fixture 50.000000, V_fixture 3.300000: 20-80 % time 22.6ns typ, 41.3ns min, 21.4ns max; typ from 3.3 V to 1.12 V
[Pulldown]
|Voltage   I(typ)   I(min)   I(max)
-3.3V     -36.46mA   -21.09mA   -47.09mA
-800mV    -36.46mA   -21.09mA   -47.09mA
-600mV    -30.5mA    -20.54mA   -38.69mA
200mV     10.38mA    6.711mA    13.48mA
700mV     31.4mA     19.11mA    41.71mA
1.2V      45.15mA    25.37mA    61.75mA
1.6V      50.35mA    26.5mA     71.06mA
2.1V      51.56mA    26.83mA    73.67mA
4.4V      53.15mA    27.8mA     75.86mA
5.2V      55.37mA    29.49mA    78.52mA
5.9V      60.56mA    33.07mA    85.02mA
6.6V      70.69mA    39.59mA    98.1mA
[GND_clamp]
|Voltage   I(typ)   I(min)   I(max)
-3.3V     -2.311A    -2.392A    -2.282A
-1.2V     -265.5mA   -356.1mA   -227.2mA
-1.13V    -202.7mA   -292.9mA   -164.1mA
-1.06V    -142.2mA   -231.2mA   -104.1mA
-990mV    -85.98mA   -171.6mA   -50.72mA
-920mV    -38.8mA    -115.5mA   -15.28mA
-850mV    -11.08mA   -65.61mA   -6.001mA
-780mV    -3.782mA   -27.42mA   -3.876mA
-710mV    -2.086mA   -7.69mA    -2.381mA
-640mV    -1.147mA   -2.118mA   -1.22mA
-570mV    -523.9uA   -798.4uA   -476.8uA
3.28V     0A         0A         0A
[POWER_clamp]
|Voltage   I(typ)   I(min)   I(max)
-3.28V    0A         0A         0A
0V        0A         0A         0A
[Ramp]
| variable   typ   min   max
dV/dt_r  1.30584/59.99724n   0.78504/59.98166n   1.58792/60.04583n
dV/dt_f  1.30584/60.25193n   0.78504/64.35809n   1.58792/60.02291n
R_load = 50.000000
[Rising Waveform]
R_fixture= 50.000000
V_fixture= 3.300000
V_fixture_min= 2.700000
V_fixture_max= 3.600000
|time   V(typ)   V(min)   V(max)
0s        1.124V     1.392V     953.5mV
22.02us   1.124V     1.392V     955.5mV
22.22us   1.124V     1.392V     3.6V
29.63us   1.123V     1.392V     3.6V
29.83us   3.3V       1.392V     3.6V
45.85us   3.3V       1.391V     3.6V
46.05us   3.3V       2.7V       3.6V
99.7us    3.3V       2.7V       3.6V
[Falling Waveform]
R_fixture= 50.000000
V_fixture= 3.300000
V_fixture_min= 2.700000
V_fixture_max= 3.600000
|time   V(typ)   V(min)   V(max)
0s        3.3V       2.7V       3.6V
20.02ns   2.721V     2.665V     1.738V
40.04ns   1.404V     2.308V     1.015V
60.06ns   1.193V     1.839V     966.3mV
80.08ns   1.147V     1.572V     956.6mV
100.1ns   1.133V     1.48V      954.5mV
140.1ns   1.125V     1.417V     953.6mV
220.2ns   1.124V     1.394V     953.5mV
320.3ns   1.124V     1.392V     953.5mV
9.97us    1.124V     1.392V     953.5mV
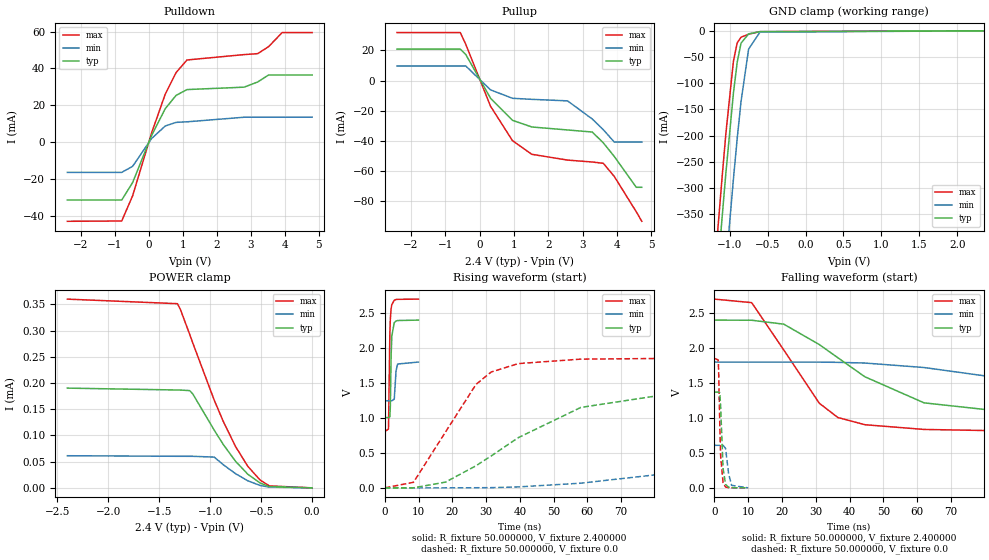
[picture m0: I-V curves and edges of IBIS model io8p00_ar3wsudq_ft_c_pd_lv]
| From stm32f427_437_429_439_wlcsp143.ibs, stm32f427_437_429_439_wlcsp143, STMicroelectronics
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|   Model io8p00_ar3wsudq_ft_c_pd_lv
[Model]  io8p00_ar3wsudq_ft_c_pd_lv
Model_type I/O
Polarity   Non-Inverting
Enable   Active-Low
Vinl =   0.720000V
Vinh =   1.680000V
Vmeas =  1.200000V
Cref =   50.000000pF
Rref =   100.000000M
Vref =   0.0V
C_comp   5.917500pF   5.759700pF   6.094700pF
[Temperature Range]   25.000000   0.125000k   -40.000000
[Pullup Reference]   2.400000V   1.800000V   2.700000V
[Pulldown Reference]   0.0V   0.0V   0.0V
[POWER Clamp Reference]   2.400000V   1.800000V   2.700000V
[GND Clamp Reference]   0.0V   0.0V   0.0V
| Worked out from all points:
|   slope of the pulldown table from 0 to 0.36 V, typ, clamps not added: 25 ohm
|   slope of the pullup table from 0 to 0.36 V, typ, clamps not added: 27.7 ohm
|   GND clamp passes 1 mA (typ) near -0.56 V on its own axis
|   rising waveform, R_fixture 50.000000, V_fixture 2.400000: 20-80 % time 337ps typ, 395ps min, 351ps max; typ from 1 V to 2.4 V
|   rising waveform, R_fixture 50.000000, V_fixture 0.0: 20-80 % time 29.2ns typ, 72.3ns min, 14.2ns max; typ from 0 V to 1.37 V
|   falling waveform, R_fixture 50.000000, V_fixture 2.400000: 20-80 % time 28.2ns typ, 58.9ns min, 15.4ns max; typ from 2.4 V to 1 V
|   falling waveform, R_fixture 50.000000, V_fixture 0.0: 20-80 % time 678ps typ, 1.01ns min, 579ps max; typ from 1.37 V to 0 V
[Pulldown]
|Voltage   I(typ)   I(min)   I(max)
-2.4V     -31.47mA   -16.45mA   -43.01mA
-800mV    -31.47mA   -16.45mA   -42.85mA
-480mV    -21.98mA   -13.17mA   -29.21mA
80mV      3.63mA     1.966mA    5.014mA
480mV     18.15mA    8.738mA    26.02mA
800mV     25.38mA    10.72mA    37.77mA
1.12V     28.53mA    11.02mA    44.6mA
2.8V      29.84mA    13.51mA    47.53mA
3.2V      32.66mA    13.51mA    48.04mA
3.52V     36.44mA    13.51mA    51.84mA
3.92V     36.44mA    13.51mA    59.49mA
4.8V      36.44mA    13.51mA    59.49mA
[Pullup]
|Voltage   I(typ)   I(min)   I(max)
-2.4V     20.89mA    9.66mA     31.89mA
-560mV    20.89mA    9.66mA     31.89mA
-400mV    17.28mA    9.66mA     24.06mA
320mV     -11.75mA   -6.207mA   -17.08mA
960mV     -26.47mA   -11.82mA   -40.02mA
1.52V     -30.88mA   -12.51mA   -49.05mA
2.56V     -32.88mA   -13.52mA   -52.9mA
3.28V     -34.25mA   -25.6mA    -54.18mA
3.6V      -41.44mA   -32.7mA    -55.03mA
3.92V     -50.5mA    -40.9mA    -63.79mA
4.56V     -71mA      -40.9mA    -87.3mA
4.72V     -71mA      -40.9mA    -93.6mA
[GND_clamp]
|Voltage   I(typ)   I(min)   I(max)
-2.4V     -2.854A    -3.022A    -2.793A
-1.25V    -627.1mA   -809.1mA   -551.5mA
-1.2V     -535.5mA   -717.4mA   -459.3mA
-1.15V    -445.4mA   -626.8mA   -368.7mA
-1.1V     -357.2mA   -537.5mA   -280.5mA
-1.05V    -272mA     -449.9mA   -196.4mA
-950mV    -118.4mA   -282.5mA   -57.42mA
-900mV    -59.51mA   -205.1mA   -22.74mA
-850mV    -23.51mA   -134.9mA   -12.19mA
-750mV    -5.744mA   -34.86mA   -6.372mA
-600mV    -1.511mA   -2.391mA   -1.49mA
2.35V     58.09uA    37.93uA    67.25uA
[POWER_clamp]
|Voltage   I(typ)   I(min)   I(max)
-2.4V     190.2uA    61.28uA    359.9uA
-1.32V    186.6uA    60.21uA    351.2uA
-1.29V    186.5uA    60.2uA     339.6uA
-1.2V     185.4uA    60.18uA    292.6uA
-1.17V    179.2uA    60.17uA    276.3uA
-960mV    110.2uA    58.68uA    167.5uA
-870mV    82.45uA    44.05uA    126.3uA
-750mV    50.58uA    26.98uA    78.64uA
-630mV    25.95uA    13.47uA    41.02uA
-510mV    9.222uA    4.578uA    14.97uA
-420mV    2.426uA    1.429uA    3.75uA
0V        0A         0A         0A
[Ramp]
| variable   typ   min   max
dV/dt_r  0.82158/29.12216n   0.36047/72.33748n   1.11042/14.21107n
dV/dt_f  0.83640/28.15888n   0.32676/59.32167n   1.13692/15.36709n
R_load = 50.000000
[Rising Waveform]
R_fixture= 50.000000
V_fixture= 2.400000
V_fixture_min= 1.800000
V_fixture_max= 2.700000
|time   V(typ)   V(min)   V(max)
0s        1.005V     1.245V     804.1mV
1.101ns   1.005V     1.245V     840.6mV
1.502ns   1.016V     1.246V     2.211V
1.642ns   1.154V     1.246V     2.408V
1.882ns   1.899V     1.246V     2.564V
2.082ns   2.172V     1.245V     2.619V
2.803ns   2.363V     1.268V     2.683V
3.343ns   2.385V     1.676V     2.694V
3.804ns   2.393V     1.771V     2.696V
9.97ns    2.399V     1.799V     2.699V
[Rising Waveform]
R_fixture= 50.000000
V_fixture= 0.0
V_fixture_min= 0.0
V_fixture_max= 0.0
|time   V(typ)   V(min)   V(max)
0s        9.694nV    598.2nV    3.699nV
8.509ns   248uV      -64.88uV   79.53mV
18.02ns   82.62mV    33.72uV    801.1mV
27.03ns   316.4mV    1.687mV    1.48V
31.53ns   456.5mV    2.896mV    1.657V
39.54ns   717.8mV    13.48mV    1.777V
58.06ns   1.15V      66.62mV    1.841V
81.08ns   1.319V     191.2mV    1.85V
152.2ns   1.369V     515.6mV    1.851V
249.2ns   1.369V     608.5mV    1.851V
[Falling Waveform]
R_fixture= 50.000000
V_fixture= 2.400000
V_fixture_min= 1.800000
V_fixture_max= 2.700000
|time   V(typ)   V(min)   V(max)
0s        2.399V     1.799V     2.699V
11.01ns   2.397V     1.798V     2.649V
20.52ns   2.341V     1.798V     1.972V
31.03ns   2.05V      1.798V     1.211V
36.54ns   1.861V     1.795V     1.006V
44.54ns   1.589V     1.785V     903mV
62.06ns   1.216V     1.721V     835.5mV
91.59ns   1.06V      1.525V     810.1mV
140.1ns   1.013V     1.324V     804.5mV
249.2ns   1.005V     1.245V     804.1mV
[Falling Waveform]
R_fixture= 50.000000
V_fixture= 0.0
V_fixture_min= 0.0
V_fixture_max= 0.0
|time   V(typ)   V(min)   V(max)
0s        1.369V     608.5mV    1.851V
1.101ns   1.369V     608.4mV    1.829V
1.241ns   1.37V      608.4mV    1.653V
1.582ns   1.363V     608.4mV    882.3mV
1.822ns   1.158V     608.1mV    452.8mV
2.543ns   277.7mV    609.7mV    73.36mV
3.283ns   49.14mV    563.2mV    12.77mV
4.184ns   8.416mV    201mV      2.61mV
5.065ns   2.287mV    35.72mV    796.1uV
9.97ns    9.694nV    598.2nV    3.699nV
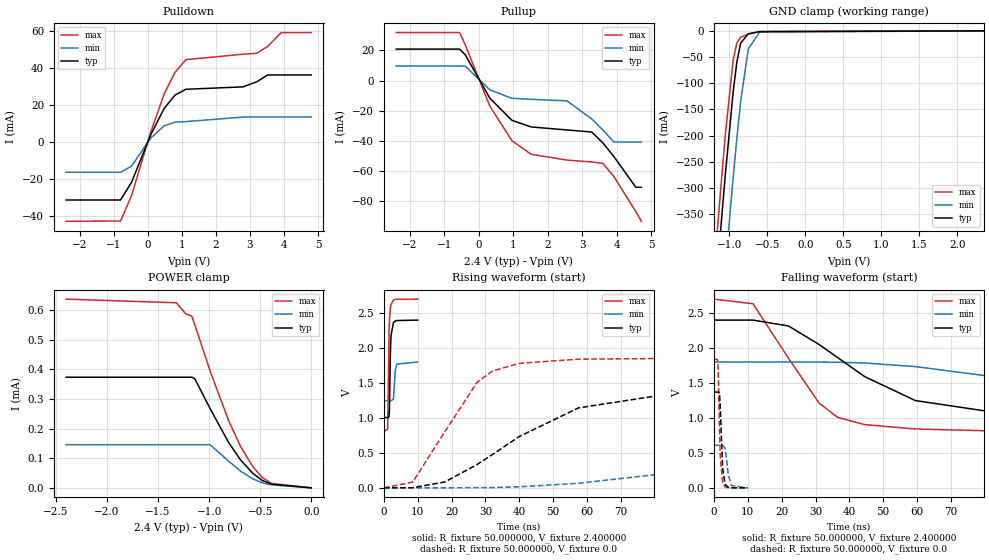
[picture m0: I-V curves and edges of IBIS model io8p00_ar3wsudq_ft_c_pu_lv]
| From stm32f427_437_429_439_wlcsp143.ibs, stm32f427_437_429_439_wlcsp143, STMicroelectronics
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|   Model io8p00_ar3wsudq_ft_c_pu_lv
[Model]  io8p00_ar3wsudq_ft_c_pu_lv
Model_type I/O
Polarity   Non-Inverting
Enable   Active-Low
Vinl =   0.720000V
Vinh =   1.680000V
Vmeas =  1.200000V
Cref =   50.000000pF
Rref =   100.000000M
Vref =   0.0V
C_comp   5.917500pF   5.759700pF   6.094700pF
[Temperature Range]   25.000000   0.125000k   -40.000000
[Pullup Reference]   2.400000V   1.800000V   2.700000V
[Pulldown Reference]   0.0V   0.0V   0.0V
[POWER Clamp Reference]   2.400000V   1.800000V   2.700000V
[GND Clamp Reference]   0.0V   0.0V   0.0V
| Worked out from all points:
|   slope of the pulldown table from 0 to 0.36 V, typ, clamps not added: 25 ohm
|   slope of the pullup table from 0 to 0.36 V, typ, clamps not added: 27.7 ohm
|   GND clamp passes 1 mA (typ) near -0.56 V on its own axis
|   rising waveform, R_fixture 50.000000, V_fixture 2.400000: 20-80 % time 337ps typ, 396ps min, 351ps max; typ from 1.01 V to 2.4 V
|   rising waveform, R_fixture 50.000000, V_fixture 0.0: 20-80 % time 29.2ns typ, 72.4ns min, 14.2ns max; typ from 0.001 V to 1.37 V
|   falling waveform, R_fixture 50.000000, V_fixture 2.400000: 20-80 % time 28.2ns typ, 59.3ns min, 15.4ns max; typ from 2.4 V to 1.01 V
|   falling waveform, R_fixture 50.000000, V_fixture 0.0: 20-80 % time 679ps typ, 1.02ns min, 579ps max; typ from 1.37 V to 0.001 V
[Pulldown]
|Voltage   I(typ)   I(min)   I(max)
-2.4V     -31.47mA   -16.45mA   -43.01mA
-800mV    -31.47mA   -16.45mA   -42.85mA
-480mV    -21.98mA   -13.17mA   -29.21mA
80mV      3.63mA     1.966mA    5.014mA
480mV     18.16mA    8.738mA    26.02mA
800mV     25.38mA    10.72mA    37.77mA
1.12V     28.53mA    11.02mA    44.6mA
2.8V      29.84mA    13.47mA    47.53mA
3.2V      32.6mA     13.47mA    48.03mA
3.52V     36.29mA    13.47mA    51.75mA
3.92V     36.29mA    13.47mA    59.26mA
4.8V      36.29mA    13.47mA    59.26mA
[Pullup]
|Voltage   I(typ)   I(min)   I(max)
-2.4V     20.87mA    9.66mA     31.87mA
-560mV    20.87mA    9.66mA     31.87mA
-400mV    17.27mA    9.66mA     24.06mA
320mV     -11.75mA   -6.207mA   -17.08mA
960mV     -26.47mA   -11.82mA   -40.02mA
1.52V     -30.88mA   -12.51mA   -49.05mA
2.56V     -32.88mA   -13.52mA   -52.9mA
3.28V     -34.25mA   -25.6mA    -54.17mA
3.6V      -41.44mA   -32.8mA    -55.02mA
3.92V     -50.5mA    -40.9mA    -63.79mA
4.56V     -71mA      -40.9mA    -87.2mA
4.72V     -71mA      -40.9mA    -93.6mA
[GND_clamp]
|Voltage   I(typ)   I(min)   I(max)
-2.4V     -2.854A    -3.023A    -2.793A
-1.25V    -627.1mA   -809.1mA   -551.5mA
-1.2V     -535.5mA   -717.4mA   -459.3mA
-1.15V    -445.4mA   -626.8mA   -368.7mA
-1.1V     -357.2mA   -537.5mA   -280.5mA
-1.05V    -272mA     -449.9mA   -196.4mA
-950mV    -118.4mA   -282.5mA   -57.41mA
-900mV    -59.51mA   -205.1mA   -22.73mA
-850mV    -23.5mA    -134.9mA   -12.18mA
-750mV    -5.732mA   -34.85mA   -6.358mA
-600mV    -1.5mA     -2.382mA   -1.477mA
2.35V     0A         0A         0A
[POWER_clamp]
|Voltage   I(typ)   I(min)   I(max)
-2.4V     373.1uA    145.5uA    636.5uA
-1.32V    373.1uA    145.5uA    624.2uA
-1.23V    373.1uA    145.5uA    587.2uA
-1.17V    373.1uA    145.5uA    579uA
-1.14V    368.3uA    145.5uA    550.7uA
-990mV    267.3uA    145.5uA    393.9uA
-810mV    153.6uA    90.35uA    227.7uA
-690mV    93.37uA    56.03uA    138.2uA
-570mV    48.37uA    29.99uA    70.44uA
-480mV    25.27uA    17.09uA    35.17uA
-390mV    12.5uA     10.23uA    15.16uA
0V        0A         0A         0A
[Ramp]
| variable   typ   min   max
dV/dt_r  0.82207/29.12084n   0.36106/72.41985n   1.11083/14.21718n
dV/dt_f  0.83574/28.17069n   0.32616/59.46250n   1.13660/15.36748n
R_load = 50.000000
[Rising Waveform]
R_fixture= 50.000000
V_fixture= 2.400000
V_fixture_min= 1.800000
V_fixture_max= 2.700000
|time   V(typ)   V(min)   V(max)
0s        1.007V     1.247V     805.7mV
1.101ns   1.007V     1.247V     842.2mV
1.502ns   1.018V     1.247V     2.214V
1.642ns   1.157V     1.248V     2.41V
1.882ns   1.901V     1.247V     2.566V
2.082ns   2.174V     1.247V     2.621V
2.803ns   2.364V     1.27V      2.685V
3.343ns   2.386V     1.678V     2.696V
3.804ns   2.394V     1.772V     2.698V
9.97ns    2.4V       1.8V       2.7V
[Rising Waveform]
R_fixture= 50.000000
V_fixture= 0.0
V_fixture_min= 0.0
V_fixture_max= 0.0
|time   V(typ)   V(min)   V(max)
0s        880.4uV    840.5uV    911.2uV
8.509ns   3.187mV    1.874mV    83.16mV
18.02ns   85.46mV    1.973mV    804.4mV
27.53ns   334.3mV    3.753mV    1.51V
32.03ns   475.2mV    4.955mV    1.671V
40.04ns   735.9mV    16.15mV    1.782V
57.56ns   1.145V     66.4mV     1.841V
81.58ns   1.323V     196mV      1.851V
151.7ns   1.371V     516.2mV    1.852V
249.2ns   1.371V     610.3mV    1.852V
[Falling Waveform]
R_fixture= 50.000000
V_fixture= 2.400000
V_fixture_min= 1.800000
V_fixture_max= 2.700000
|time   V(typ)   V(min)   V(max)
0s        2.4V       1.8V       2.7V
11.51ns   2.4V       1.8V       2.634V
22.02ns   2.316V     1.8V       1.854V
31.03ns   2.052V     1.8V       1.214V
36.54ns   1.864V     1.797V     1.009V
44.54ns   1.592V     1.787V     905mV
59.56ns   1.249V     1.735V     842.7mV
81.58ns   1.091V     1.597V     816mV
136.6ns   1.017V     1.334V     806.2mV
249.2ns   1.007V     1.247V     805.7mV
[Falling Waveform]
R_fixture= 50.000000
V_fixture= 0.0
V_fixture_min= 0.0
V_fixture_max= 0.0
|time   V(typ)   V(min)   V(max)
0s        1.371V     610.3mV    1.852V
1.101ns   1.37V      610.2mV    1.83V
1.241ns   1.372V     610.2mV    1.655V
1.582ns   1.365V     610.2mV    883.5mV
1.822ns   1.159V     609.9mV    453.7mV
2.543ns   279.2mV    611.5mV    74.23mV
3.283ns   50.11mV    564.8mV    13.67mV
4.184ns   9.273mV    202mV      3.516mV
5.085ns   3.119mV    35.36mV    1.685mV
9.97ns    880.4uV    840.5uV    911.2uV
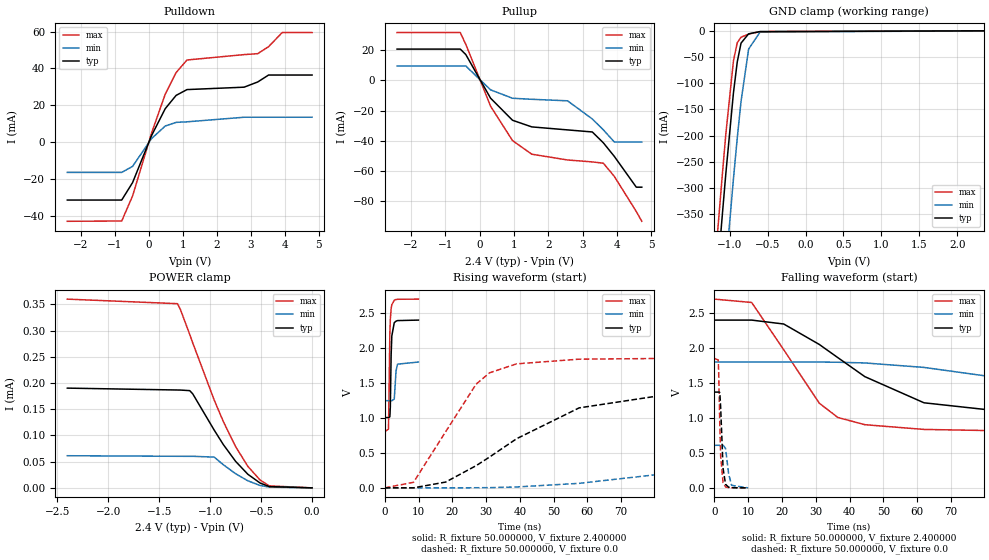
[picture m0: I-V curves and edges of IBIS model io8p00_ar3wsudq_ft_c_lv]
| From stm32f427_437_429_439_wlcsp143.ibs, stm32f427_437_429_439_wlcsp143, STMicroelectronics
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|   Model io8p00_ar3wsudq_ft_c_lv
[Model]  io8p00_ar3wsudq_ft_c_lv
Model_type I/O
Polarity   Non-Inverting
Enable   Active-Low
Vinl =   0.720000V
Vinh =   1.680000V
Vmeas =  1.200000V
Cref =   50.000000pF
Rref =   100.000000M
Vref =   0.0V
C_comp   5.917500pF   5.759700pF   6.094700pF
[Temperature Range]   25.000000   0.125000k   -40.000000
[Pullup Reference]   2.400000V   1.800000V   2.700000V
[Pulldown Reference]   0.0V   0.0V   0.0V
[POWER Clamp Reference]   2.400000V   1.800000V   2.700000V
[GND Clamp Reference]   0.0V   0.0V   0.0V
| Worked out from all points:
|   slope of the pulldown table from 0 to 0.36 V, typ, clamps not added: 25 ohm
|   slope of the pullup table from 0 to 0.36 V, typ, clamps not added: 27.7 ohm
|   GND clamp passes 1 mA (typ) near -0.56 V on its own axis
|   rising waveform, R_fixture 50.000000, V_fixture 2.400000: 20-80 % time 339ps typ, 396ps min, 352ps max; typ from 1.01 V to 2.4 V
|   rising waveform, R_fixture 50.000000, V_fixture 0.0: 20-80 % time 29.1ns typ, 72.3ns min, 14.2ns max; typ from 0 V to 1.37 V
|   falling waveform, R_fixture 50.000000, V_fixture 2.400000: 20-80 % time 28.2ns typ, 58.9ns min, 15.4ns max; typ from 2.4 V to 1.01 V
|   falling waveform, R_fixture 50.000000, V_fixture 0.0: 20-80 % time 680ps typ, 1.02ns min, 581ps max; typ from 1.37 V to 0 V
[Pulldown]
|Voltage   I(typ)   I(min)   I(max)
-2.4V     -31.47mA   -16.45mA   -43.01mA
-800mV    -31.47mA   -16.45mA   -42.85mA
-480mV    -21.98mA   -13.17mA   -29.21mA
80mV      3.63mA     1.966mA    5.014mA
480mV     18.16mA    8.738mA    26.02mA
800mV     25.38mA    10.72mA    37.77mA
1.12V     28.53mA    11.02mA    44.6mA
2.8V      29.84mA    13.51mA    47.53mA
3.2V      32.66mA    13.51mA    48.04mA
3.52V     36.44mA    13.51mA    51.84mA
3.92V     36.44mA    13.51mA    59.5mA
4.8V      36.44mA    13.51mA    59.5mA
[Pullup]
|Voltage   I(typ)   I(min)   I(max)
-2.4V     20.89mA    9.661mA    31.89mA
-560mV    20.89mA    9.661mA    31.89mA
-400mV    17.28mA    9.661mA    24.06mA
320mV     -11.75mA   -6.207mA   -17.08mA
960mV     -26.47mA   -11.82mA   -40.02mA
1.52V     -30.88mA   -12.51mA   -49.05mA
2.56V     -32.88mA   -13.52mA   -52.9mA
3.28V     -34.25mA   -25.6mA    -54.18mA
3.6V      -41.44mA   -32.8mA    -55.02mA
3.92V     -50.5mA    -40.9mA    -63.79mA
4.56V     -71mA      -40.9mA    -87.2mA
4.72V     -71mA      -40.9mA    -93.7mA
[GND_clamp]
|Voltage   I(typ)   I(min)   I(max)
-2.4V     -2.854A    -3.023A    -2.793A
-1.25V    -627.1mA   -809.1mA   -551.5mA
-1.2V     -535.5mA   -717.4mA   -459.3mA
-1.15V    -445.4mA   -626.8mA   -368.7mA
-1.1V     -357.2mA   -537.5mA   -280.5mA
-1.05V    -272mA     -449.9mA   -196.4mA
-950mV    -118.4mA   -282.5mA   -57.41mA
-900mV    -59.51mA   -205.1mA   -22.73mA
-850mV    -23.5mA    -134.9mA   -12.18mA
-750mV    -5.732mA   -34.85mA   -6.358mA
-600mV    -1.5mA     -2.382mA   -1.477mA
2.35V     0A         0A         0A
[POWER_clamp]
|Voltage   I(typ)   I(min)   I(max)
-2.4V     190.2uA    61.28uA    359.9uA
-1.32V    186.6uA    60.21uA    351.2uA
-1.29V    186.5uA    60.2uA     339.6uA
-1.2V     185.4uA    60.18uA    292.6uA
-1.17V    179.2uA    60.17uA    276.3uA
-960mV    110.2uA    58.68uA    167.5uA
-870mV    82.45uA    44.05uA    126.3uA
-750mV    50.58uA    26.98uA    78.64uA
-630mV    25.95uA    13.47uA    41.02uA
-510mV    9.222uA    4.578uA    14.97uA
-420mV    2.426uA    1.429uA    3.75uA
0V        0A         0A         0A
[Ramp]
| variable   typ   min   max
dV/dt_r  0.82218/29.10515n   0.36085/72.34260n   1.11108/14.20236n
dV/dt_f  0.83652/28.14765n   0.32652/59.26000n   1.13727/15.35425n
R_load = 50.000000
[Rising Waveform]
R_fixture= 50.000000
V_fixture= 2.400000
V_fixture_min= 1.800000
V_fixture_max= 2.700000
|time   V(typ)   V(min)   V(max)
0s        1.006V     1.247V     804.6mV
1.101ns   1.006V     1.247V     841mV
1.502ns   1.016V     1.247V     2.211V
1.642ns   1.155V     1.247V     2.407V
1.882ns   1.899V     1.247V     2.564V
2.082ns   2.172V     1.246V     2.619V
2.803ns   2.363V     1.27V      2.684V
3.343ns   2.385V     1.677V     2.695V
3.784ns   2.393V     1.77V      2.698V
9.97ns    2.4V       1.8V       2.7V
[Rising Waveform]
R_fixture= 50.000000
V_fixture= 0.0
V_fixture_min= 0.0
V_fixture_max= 0.0
|time   V(typ)   V(min)   V(max)
0s        9.788nV    603.1nV    3.742nV
8.509ns   247.7uV    -65.41uV   79.56mV
18.02ns   82.67mV    33.72uV    801.9mV
27.03ns   316.6mV    1.688mV    1.482V
31.03ns   440.8mV    2.763mV    1.646V
39.04ns   702.7mV    12.72mV    1.774V
57.56ns   1.144V     64.57mV    1.841V
82.08ns   1.323V     197.4mV    1.851V
151.7ns   1.37V      514.9mV    1.852V
249.2ns   1.37V      609.1mV    1.852V
[Falling Waveform]
R_fixture= 50.000000
V_fixture= 2.400000
V_fixture_min= 1.800000
V_fixture_max= 2.700000
|time   V(typ)   V(min)   V(max)
0s        2.4V       1.8V       2.7V
11.01ns   2.4V       1.8V       2.652V
20.52ns   2.344V     1.8V       1.975V
31.03ns   2.052V     1.8V       1.212V
36.54ns   1.863V     1.797V     1.007V
44.54ns   1.591V     1.787V     903.6mV
62.06ns   1.217V     1.723V     836mV
91.59ns   1.061V     1.526V     810.6mV
140.1ns   1.014V     1.326V     804.9mV
249.2ns   1.006V     1.247V     804.6mV
[Falling Waveform]
R_fixture= 50.000000
V_fixture= 0.0
V_fixture_min= 0.0
V_fixture_max= 0.0
|time   V(typ)   V(min)   V(max)
0s        1.37V      609.1mV    1.852V
1.101ns   1.37V      609mV      1.83V
1.241ns   1.371V     609.1mV    1.655V
1.582ns   1.364V     609.1mV    884.4mV
1.822ns   1.159V     608.7mV    454.8mV
2.543ns   279.2mV    610.3mV    75.1mV
3.283ns   50.31mV    563.8mV    13.88mV
4.184ns   9.128mV    201.6mV    3.216mV
5.065ns   2.725mV    36.16mV    1.121mV
9.97ns    9.788nV    603.1nV    3.742nV
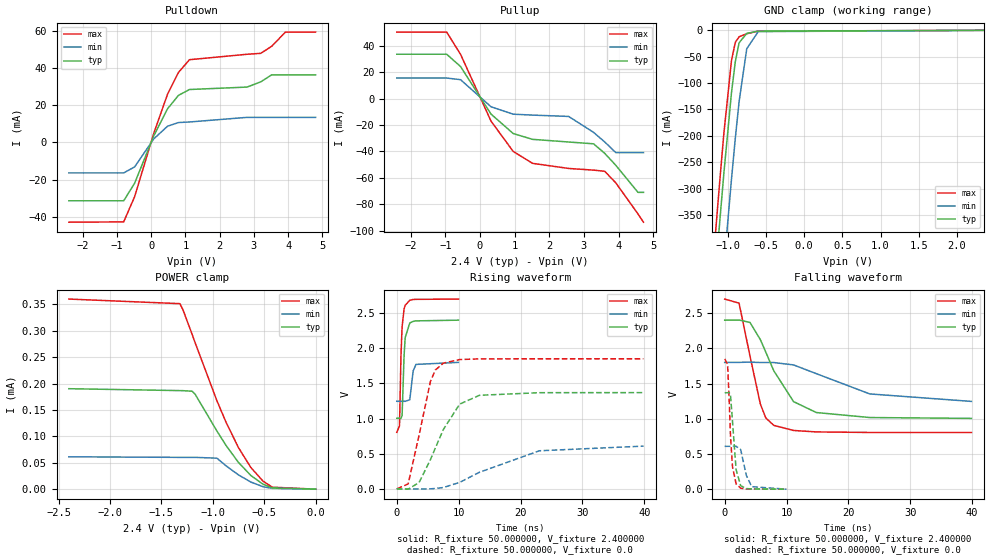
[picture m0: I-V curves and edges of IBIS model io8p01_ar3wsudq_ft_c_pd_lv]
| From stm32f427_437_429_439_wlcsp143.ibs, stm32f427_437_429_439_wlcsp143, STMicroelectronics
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|   Model io8p01_ar3wsudq_ft_c_pd_lv
[Model]  io8p01_ar3wsudq_ft_c_pd_lv
Model_type I/O
Polarity   Non-Inverting
Enable   Active-Low
Vinl =   0.720000V
Vinh =   1.680000V
Vmeas =  1.200000V
Cref =   50.000000pF
Rref =   100.000000M
Vref =   0.0V
C_comp   5.917500pF   5.759700pF   6.094700pF
[Temperature Range]   25.000000   0.125000k   -40.000000
[Pullup Reference]   2.400000V   1.800000V   2.700000V
[Pulldown Reference]   0.0V   0.0V   0.0V
[POWER Clamp Reference]   2.400000V   1.800000V   2.700000V
[GND Clamp Reference]   0.0V   0.0V   0.0V
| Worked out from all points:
|   slope of the pulldown table from 0 to 0.36 V, typ, clamps not added: 25 ohm
|   slope of the pullup table from 0 to 0.36 V, typ, clamps not added: 27.7 ohm
|   GND clamp passes 1 mA (typ) near -0.56 V on its own axis
|   rising waveform, R_fixture 50.000000, V_fixture 2.400000: 20-80 % time 340ps typ, 396ps min, 354ps max; typ from 1 V to 2.4 V
|   rising waveform, R_fixture 50.000000, V_fixture 0.0: 20-80 % time 4.4ns typ, 9.16ns min, 2.57ns max; typ from 0 V to 1.37 V
|   falling waveform, R_fixture 50.000000, V_fixture 2.400000: 20-80 % time 4.92ns typ, 9.69ns min, 2.66ns max; typ from 2.4 V to 1 V
|   falling waveform, R_fixture 50.000000, V_fixture 0.0: 20-80 % time 679ps typ, 1.02ns min, 580ps max; typ from 1.37 V to 0 V
[Pulldown]
|Voltage   I(typ)   I(min)   I(max)
-2.4V     -31.47mA   -16.45mA   -43.01mA
-800mV    -31.47mA   -16.45mA   -42.85mA
-480mV    -21.98mA   -13.17mA   -29.21mA
80mV      3.63mA     1.966mA    5.014mA
480mV     18.15mA    8.738mA    26.02mA
800mV     25.38mA    10.72mA    37.77mA
1.12V     28.53mA    11.02mA    44.6mA
2.8V      29.84mA    13.51mA    47.53mA
3.2V      32.66mA    13.51mA    48.04mA
3.52V     36.44mA    13.51mA    51.84mA
3.92V     36.44mA    13.51mA    59.49mA
4.8V      36.44mA    13.51mA    59.49mA
[Pullup]
|Voltage   I(typ)   I(min)   I(max)
-2.4V     33.58mA    15.57mA    50.35mA
-960mV    33.58mA    15.57mA    50.35mA
-560mV    24.28mA    14.31mA    33.53mA
320mV     -11.75mA   -6.207mA   -17.08mA
960mV     -26.47mA   -11.82mA   -40.02mA
1.52V     -30.88mA   -12.51mA   -49.05mA
2.56V     -32.88mA   -13.52mA   -52.9mA
3.28V     -34.25mA   -25.6mA    -54.18mA
3.6V      -41.44mA   -32.8mA    -55.03mA
3.92V     -50.5mA    -40.9mA    -63.79mA
4.56V     -71mA      -40.9mA    -87.3mA
4.72V     -71mA      -40.9mA    -93.6mA
[GND_clamp]
|Voltage   I(typ)   I(min)   I(max)
-2.4V     -2.854A    -3.022A    -2.792A
-1.25V    -627.1mA   -809.1mA   -551.5mA
-1.2V     -535.5mA   -717.4mA   -459.3mA
-1.15V    -445.4mA   -626.8mA   -368.7mA
-1.1V     -357.2mA   -537.5mA   -280.5mA
-1.05V    -272mA     -449.9mA   -196.4mA
-950mV    -118.4mA   -282.5mA   -57.42mA
-900mV    -59.51mA   -205.1mA   -22.74mA
-850mV    -23.51mA   -134.9mA   -12.19mA
-750mV    -5.744mA   -34.86mA   -6.372mA
-600mV    -1.511mA   -2.391mA   -1.49mA
2.35V     58.09uA    37.93uA    67.25uA
[POWER_clamp]
|Voltage   I(typ)   I(min)   I(max)
-2.4V     190.2uA    61.28uA    359.9uA
-1.32V    186.6uA    60.21uA    351.2uA
-1.29V    186.5uA    60.2uA     339.6uA
-1.2V     185.4uA    60.18uA    292.6uA
-1.17V    179.2uA    60.17uA    276.3uA
-960mV    110.2uA    58.68uA    167.5uA
-870mV    82.45uA    44.05uA    126.3uA
-750mV    50.58uA    26.98uA    78.64uA
-630mV    25.95uA    13.47uA    41.02uA
-510mV    9.222uA    4.578uA    14.97uA
-420mV    2.426uA    1.429uA    3.75uA
0V        0A         0A         0A
[Ramp]
| variable   typ   min   max
dV/dt_r  0.82152/4.39387n   0.36406/9.15504n   1.11042/2.57235n
dV/dt_f  0.83628/4.91360n   0.32208/9.65457n   1.13692/2.65702n
R_load = 50.000000
[Rising Waveform]
R_fixture= 50.000000
V_fixture= 2.400000
V_fixture_min= 1.800000
V_fixture_max= 2.700000
|time   V(typ)   V(min)   V(max)
0s        1.005V     1.246V     804.6mV
440.4ps   1.005V     1.245V     896.3mV
680.7ps   1.001V     1.246V     1.905V
860.9ps   1.046V     1.246V     2.306V
1.181ns   1.898V     1.246V     2.559V
1.361ns   2.152V     1.245V     2.61V
2.102ns   2.359V     1.268V     2.683V
2.643ns   2.381V     1.676V     2.693V
3.103ns   2.389V     1.77V      2.695V
9.97ns    2.399V     1.799V     2.699V
[Rising Waveform]
R_fixture= 50.000000
V_fixture= 0.0
V_fixture_min= 0.0
V_fixture_max= 0.0
|time   V(typ)   V(min)   V(max)
0s        197.6uV    95.59uV    300.6uV
1.842ns   -3.586mV   -66.58uV   71.02mV
3.604ns   91mV       -1.361mV   764.2mV
5.445ns   417.1mV    959uV      1.529V
6.246ns   584.3mV    6.918mV    1.691V
7.528ns   844.2mV    19.55mV    1.788V
10.17ns   1.206V     93.09mV    1.839V
13.37ns   1.331V     236.7mV    1.849V
23.06ns   1.368V     542.3mV    1.85V
39.88ns   1.369V     608.4mV    1.85V
[Falling Waveform]
R_fixture= 50.000000
V_fixture= 2.400000
V_fixture_min= 1.800000
V_fixture_max= 2.700000
|time   V(typ)   V(min)   V(max)
0s        2.399V     1.799V     2.699V
2.322ns   2.401V     1.8V       2.641V
4.084ns   2.368V     1.804V     1.892V
5.766ns   2.123V     1.798V     1.208V
6.647ns   1.945V     1.798V     1.011V
7.928ns   1.682V     1.798V     906.1mV
11.13ns   1.243V     1.764V     833.5mV
14.81ns   1.088V     1.64V      812.8mV
23.46ns   1.017V     1.352V     805.1mV
39.88ns   1.005V     1.246V     804.6mV
[Falling Waveform]
R_fixture= 50.000000
V_fixture= 0.0
V_fixture_min= 0.0
V_fixture_max= 0.0
|time   V(typ)   V(min)   V(max)
0s        1.369V     608.4mV    1.85V
460.5ps   1.369V     608.4mV    1.775V
700.7ps   1.375V     608.4mV    1.323V
940.9ps   1.333V     608.4mV    748.1mV
1.261ns   961mV      607.9mV    317.5mV
1.842ns   277.5mV    609.7mV    75.02mV
2.583ns   49.94mV    561.9mV    13.96mV
3.504ns   9.369mV    194.6mV    2.181mV
4.364ns   3.236mV    35.71mV    949.1uV
9.97ns    197.6uV    95.59uV    300.6uV
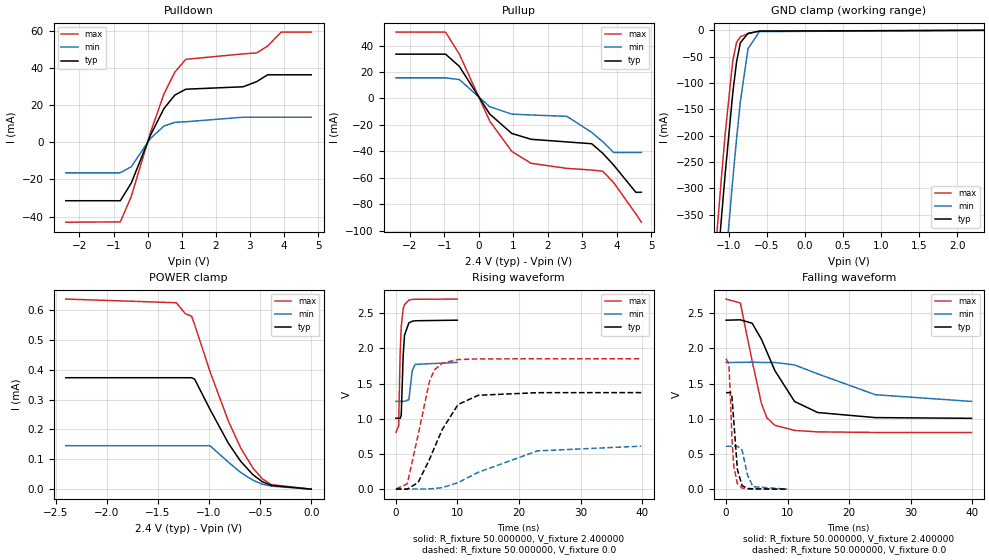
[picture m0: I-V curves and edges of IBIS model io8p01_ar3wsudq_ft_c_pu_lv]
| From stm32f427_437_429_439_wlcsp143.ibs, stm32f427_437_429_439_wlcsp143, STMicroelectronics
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|   Model io8p01_ar3wsudq_ft_c_pu_lv
[Model]  io8p01_ar3wsudq_ft_c_pu_lv
Model_type I/O
Polarity   Non-Inverting
Enable   Active-Low
Vinl =   0.720000V
Vinh =   1.680000V
Vmeas =  1.200000V
Cref =   50.000000pF
Rref =   100.000000M
Vref =   0.0V
C_comp   5.917500pF   5.759700pF   6.094700pF
[Temperature Range]   25.000000   0.125000k   -40.000000
[Pullup Reference]   2.400000V   1.800000V   2.700000V
[Pulldown Reference]   0.0V   0.0V   0.0V
[POWER Clamp Reference]   2.400000V   1.800000V   2.700000V
[GND Clamp Reference]   0.0V   0.0V   0.0V
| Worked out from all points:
|   slope of the pulldown table from 0 to 0.36 V, typ, clamps not added: 25 ohm
|   slope of the pullup table from 0 to 0.36 V, typ, clamps not added: 27.7 ohm
|   GND clamp passes 1 mA (typ) near -0.56 V on its own axis
|   rising waveform, R_fixture 50.000000, V_fixture 2.400000: 20-80 % time 338ps typ, 396ps min, 352ps max; typ from 1.01 V to 2.4 V
|   rising waveform, R_fixture 50.000000, V_fixture 0.0: 20-80 % time 4.4ns typ, 9.18ns min, 2.58ns max; typ from 0.001 V to 1.37 V
|   falling waveform, R_fixture 50.000000, V_fixture 2.400000: 20-80 % time 4.92ns typ, 9.7ns min, 2.66ns max; typ from 2.4 V to 1.01 V
|   falling waveform, R_fixture 50.000000, V_fixture 0.0: 20-80 % time 682ps typ, 1.02ns min, 582ps max; typ from 1.37 V to 0.001 V
[Pulldown]
|Voltage   I(typ)   I(min)   I(max)
-2.4V     -31.47mA   -16.45mA   -43.01mA
-800mV    -31.47mA   -16.45mA   -42.85mA
-480mV    -21.98mA   -13.17mA   -29.21mA
80mV      3.63mA     1.966mA    5.014mA
480mV     18.16mA    8.738mA    26.02mA
800mV     25.38mA    10.72mA    37.77mA
1.12V     28.53mA    11.02mA    44.6mA
2.8V      29.84mA    13.47mA    47.53mA
3.2V      32.6mA     13.47mA    48.03mA
3.52V     36.29mA    13.47mA    51.75mA
3.92V     36.29mA    13.47mA    59.26mA
4.8V      36.29mA    13.47mA    59.26mA
[Pullup]
|Voltage   I(typ)   I(min)   I(max)
-2.4V     33.5mA     15.56mA    50.2mA
-960mV    33.5mA     15.56mA    50.2mA
-560mV    24.27mA    14.3mA     33.51mA
320mV     -11.75mA   -6.207mA   -17.08mA
960mV     -26.47mA   -11.82mA   -40.02mA
1.52V     -30.88mA   -12.51mA   -49.05mA
2.56V     -32.88mA   -13.52mA   -52.9mA
3.28V     -34.25mA   -25.7mA    -54.17mA
3.6V      -41.44mA   -32.7mA    -55.02mA
3.92V     -50.5mA    -40.9mA    -63.79mA
4.56V     -71mA      -40.9mA    -87.3mA
4.72V     -71mA      -40.9mA    -93.6mA
[GND_clamp]
|Voltage   I(typ)   I(min)   I(max)
-2.4V     -2.854A    -3.022A    -2.793A
-1.25V    -627.1mA   -809.1mA   -551.5mA
-1.2V     -535.5mA   -717.4mA   -459.3mA
-1.15V    -445.4mA   -626.8mA   -368.7mA
-1.1V     -357.2mA   -537.5mA   -280.5mA
-1.05V    -272mA     -449.9mA   -196.4mA
-950mV    -118.4mA   -282.5mA   -57.41mA
-900mV    -59.51mA   -205.1mA   -22.73mA
-850mV    -23.5mA    -134.9mA   -12.18mA
-750mV    -5.732mA   -34.85mA   -6.358mA
-600mV    -1.5mA     -2.382mA   -1.477mA
2.35V     0A         0A         0A
[POWER_clamp]
|Voltage   I(typ)   I(min)   I(max)
-2.4V     373.1uA    145.5uA    636.5uA
-1.32V    373.1uA    145.5uA    624.2uA
-1.23V    373.1uA    145.5uA    587.2uA
-1.17V    373.1uA    145.5uA    579uA
-1.14V    368.3uA    145.5uA    550.7uA
-990mV    267.3uA    145.5uA    393.9uA
-810mV    153.6uA    90.35uA    227.7uA
-690mV    93.37uA    56.03uA    138.2uA
-570mV    48.37uA    29.99uA    70.44uA
-480mV    25.27uA    17.09uA    35.17uA
-390mV    12.5uA     10.23uA    15.16uA
0V        0A         0A         0A
[Ramp]
| variable   typ   min   max
dV/dt_r  0.82207/4.39719n   0.36465/9.17219n   1.11077/2.57514n
dV/dt_f  0.83562/4.91230n   0.32142/9.66827n   1.13660/2.65626n
R_load = 50.000000
[Rising Waveform]
R_fixture= 50.000000
V_fixture= 2.400000
V_fixture_min= 1.800000
V_fixture_max= 2.700000
|time   V(typ)   V(min)   V(max)
0s        1.007V     1.247V     806.2mV
440.4ps   1.007V     1.247V     898.1mV
680.7ps   1.003V     1.247V     1.909V
860.9ps   1.048V     1.247V     2.31V
1.181ns   1.901V     1.247V     2.563V
1.401ns   2.188V     1.247V     2.621V
2.102ns   2.362V     1.27V      2.685V
2.643ns   2.384V     1.678V     2.695V
3.103ns   2.392V     1.772V     2.697V
9.97ns    2.4V       1.8V       2.7V
[Rising Waveform]
R_fixture= 50.000000
V_fixture= 0.0
V_fixture_min= 0.0
V_fixture_max= 0.0
|time   V(typ)   V(min)   V(max)
0s        1.078mV    935.5uV    1.211mV
1.842ns   -850.9uV   770.3uV    75.05mV
3.604ns   94.09mV    516uV      767.4mV
5.445ns   419.9mV    2.888mV    1.531V
6.246ns   586.9mV    8.778mV    1.693V
7.528ns   846.7mV    21.26mV    1.789V
10.09ns   1.201V     92.1mV     1.84V
13.37ns   1.333V     238.4mV    1.85V
22.98ns   1.37V      542.9mV    1.851V
39.88ns   1.371V     610.2mV    1.852V
[Falling Waveform]
R_fixture= 50.000000
V_fixture= 2.400000
V_fixture_min= 1.800000
V_fixture_max= 2.700000
|time   V(typ)   V(min)   V(max)
0s        2.4V       1.8V       2.7V
2.322ns   2.405V     1.801V     2.645V
4.244ns   2.357V     1.805V     1.819V
5.766ns   2.126V     1.8V       1.211V
6.647ns   1.948V     1.8V       1.013V
7.928ns   1.685V     1.8V       907.9mV
11.13ns   1.246V     1.765V     835.1mV
14.89ns   1.089V     1.638V     814.2mV
24.26ns   1.017V     1.342V     806.5mV
39.88ns   1.007V     1.247V     806.2mV
[Falling Waveform]
R_fixture= 50.000000
V_fixture= 0.0
V_fixture_min= 0.0
V_fixture_max= 0.0
|time   V(typ)   V(min)   V(max)
0s        1.371V     610.2mV    1.852V
460.5ps   1.371V     610.2mV    1.776V
700.7ps   1.377V     610.2mV    1.325V
940.9ps   1.335V     610.2mV    751mV
1.261ns   962.6mV    609.7mV    320.7mV
1.842ns   280.5mV    611.5mV    78.73mV
2.603ns   50.61mV    556.4mV    17.27mV
3.483ns   11.71mV    201.5mV    4.074mV
4.384ns   5.797mV    35.54mV    2.145mV
9.97ns    1.078mV    935.5uV    1.211mV
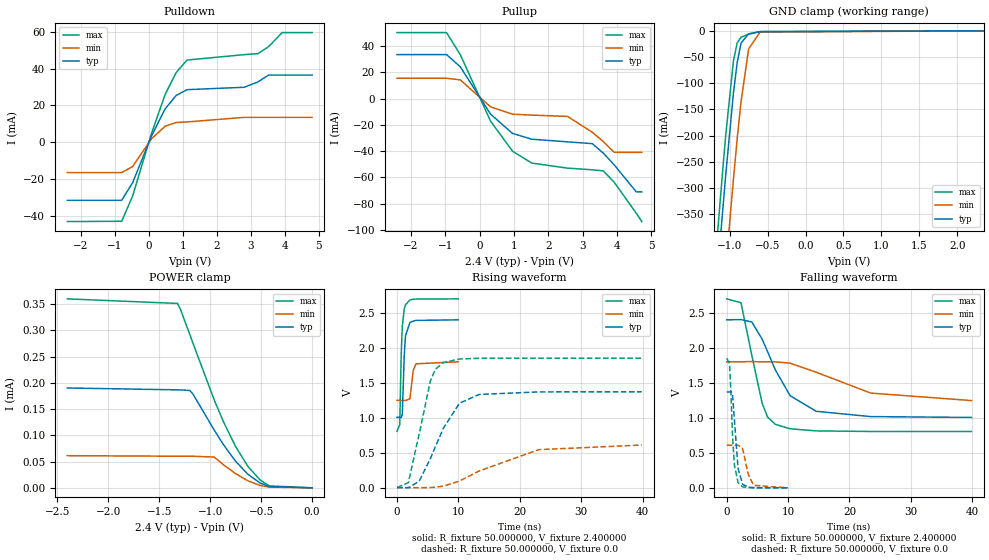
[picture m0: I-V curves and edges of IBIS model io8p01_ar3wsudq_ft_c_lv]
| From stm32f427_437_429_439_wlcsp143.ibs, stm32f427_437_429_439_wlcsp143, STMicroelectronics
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|   Model io8p01_ar3wsudq_ft_c_lv
[Model]  io8p01_ar3wsudq_ft_c_lv
Model_type I/O
Polarity   Non-Inverting
Enable   Active-Low
Vinl =   0.720000V
Vinh =   1.680000V
Vmeas =  1.200000V
Cref =   50.000000pF
Rref =   100.000000M
Vref =   0.0V
C_comp   5.917500pF   5.759700pF   6.094700pF
[Temperature Range]   25.000000   0.125000k   -40.000000
[Pullup Reference]   2.400000V   1.800000V   2.700000V
[Pulldown Reference]   0.0V   0.0V   0.0V
[POWER Clamp Reference]   2.400000V   1.800000V   2.700000V
[GND Clamp Reference]   0.0V   0.0V   0.0V
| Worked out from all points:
|   slope of the pulldown table from 0 to 0.36 V, typ, clamps not added: 25 ohm
|   slope of the pullup table from 0 to 0.36 V, typ, clamps not added: 27.7 ohm
|   GND clamp passes 1 mA (typ) near -0.56 V on its own axis
|   rising waveform, R_fixture 50.000000, V_fixture 2.400000: 20-80 % time 340ps typ, 396ps min, 354ps max; typ from 1.01 V to 2.4 V
|   rising waveform, R_fixture 50.000000, V_fixture 0.0: 20-80 % time 4.4ns typ, 9.17ns min, 2.57ns max; typ from 0 V to 1.37 V
|   falling waveform, R_fixture 50.000000, V_fixture 2.400000: 20-80 % time 4.92ns typ, 9.67ns min, 2.66ns max; typ from 2.4 V to 1.01 V
|   falling waveform, R_fixture 50.000000, V_fixture 0.0: 20-80 % time 680ps typ, 1.02ns min, 581ps max; typ from 1.37 V to 0 V
[Pulldown]
|Voltage   I(typ)   I(min)   I(max)
-2.4V     -31.47mA   -16.45mA   -43.01mA
-800mV    -31.47mA   -16.45mA   -42.85mA
-480mV    -21.98mA   -13.17mA   -29.21mA
80mV      3.63mA     1.966mA    5.014mA
480mV     18.16mA    8.738mA    26.02mA
800mV     25.38mA    10.72mA    37.77mA
1.12V     28.53mA    11.02mA    44.6mA
2.8V      29.84mA    13.51mA    47.53mA
3.2V      32.66mA    13.51mA    48.04mA
3.52V     36.44mA    13.51mA    51.84mA
3.92V     36.44mA    13.51mA    59.5mA
4.8V      36.44mA    13.51mA    59.5mA
[Pullup]
|Voltage   I(typ)   I(min)   I(max)
-2.4V     33.58mA    15.57mA    50.35mA
-960mV    33.58mA    15.57mA    50.35mA
-560mV    24.29mA    14.31mA    33.53mA
320mV     -11.75mA   -6.207mA   -17.08mA
960mV     -26.47mA   -11.82mA   -40.02mA
1.52V     -30.88mA   -12.51mA   -49.05mA
2.56V     -32.88mA   -13.52mA   -52.9mA
3.28V     -34.25mA   -25.6mA    -54.18mA
3.6V      -41.44mA   -32.7mA    -55.02mA
3.92V     -50.5mA    -40.9mA    -63.79mA
4.56V     -71mA      -40.9mA    -87.3mA
4.72V     -71mA      -40.9mA    -93.6mA
[GND_clamp]
|Voltage   I(typ)   I(min)   I(max)
-2.4V     -2.854A    -3.022A    -2.793A
-1.25V    -627.1mA   -809.1mA   -551.5mA
-1.2V     -535.5mA   -717.4mA   -459.3mA
-1.15V    -445.4mA   -626.8mA   -368.7mA
-1.1V     -357.2mA   -537.5mA   -280.5mA
-1.05V    -272mA     -449.9mA   -196.4mA
-950mV    -118.4mA   -282.5mA   -57.41mA
-900mV    -59.51mA   -205.1mA   -22.73mA
-850mV    -23.5mA    -134.9mA   -12.18mA
-750mV    -5.732mA   -34.85mA   -6.358mA
-600mV    -1.5mA     -2.382mA   -1.477mA
2.35V     0A         0A         0A
[POWER_clamp]
|Voltage   I(typ)   I(min)   I(max)
-2.4V     190.2uA    61.28uA    359.9uA
-1.32V    186.6uA    60.21uA    351.2uA
-1.29V    186.5uA    60.2uA     339.6uA
-1.2V     185.4uA    60.18uA    292.6uA
-1.17V    179.2uA    60.17uA    276.3uA
-960mV    110.2uA    58.68uA    167.5uA
-870mV    82.45uA    44.05uA    126.3uA
-750mV    50.58uA    26.98uA    78.64uA
-630mV    25.95uA    13.47uA    41.02uA
-510mV    9.222uA    4.578uA    14.97uA
-420mV    2.426uA    1.429uA    3.75uA
0V        0A         0A         0A
[Ramp]
| variable   typ   min   max
dV/dt_r  0.82218/4.39437n   0.36443/9.15814n   1.11108/2.57214n
dV/dt_f  0.83634/4.91183n   0.32184/9.64014n   1.13726/2.65505n
R_load = 50.000000
[Rising Waveform]
R_fixture= 50.000000
V_fixture= 2.400000
V_fixture_min= 1.800000
V_fixture_max= 2.700000
|time   V(typ)   V(min)   V(max)
0s        1.006V     1.247V     805mV
440.4ps   1.006V     1.247V     896.8mV
680.7ps   1.002V     1.247V     1.906V
860.9ps   1.047V     1.247V     2.307V
1.181ns   1.899V     1.247V     2.56V
1.381ns   2.171V     1.246V     2.615V
2.102ns   2.361V     1.27V      2.685V
2.643ns   2.383V     1.677V     2.695V
3.103ns   2.392V     1.771V     2.697V
9.97ns    2.4V       1.8V       2.7V
[Rising Waveform]
R_fixture= 50.000000
V_fixture= 0.0
V_fixture_min= 0.0
V_fixture_max= 0.0
|time   V(typ)   V(min)   V(max)
0s        197.4uV    95.52uV    300.6uV
1.842ns   -3.591mV   -66.54uV   71.02mV
3.604ns   91mV       -1.364mV   764.4mV
5.445ns   417.2mV    956.9uV    1.53V
6.246ns   584.5mV    6.918mV    1.692V
7.528ns   844.7mV    19.55mV    1.789V
10.17ns   1.207V     93.12mV    1.84V
13.37ns   1.332V     236.9mV    1.85V
23.06ns   1.369V     542.7mV    1.851V
39.88ns   1.37V      609mV      1.851V
[Falling Waveform]
R_fixture= 50.000000
V_fixture= 2.400000
V_fixture_min= 1.800000
V_fixture_max= 2.700000
|time   V(typ)   V(min)   V(max)
0s        2.4V       1.8V       2.7V
2.322ns   2.404V     1.801V     2.645V
4.084ns   2.37V      1.805V     1.895V
5.766ns   2.126V     1.8V       1.21V
6.647ns   1.947V     1.8V       1.012V
7.928ns   1.684V     1.8V       906.8mV
10.33ns   1.316V     1.781V     844mV
14.57ns   1.094V     1.652V     813.8mV
23.46ns   1.018V     1.354V     805.5mV
39.88ns   1.006V     1.247V     805mV
[Falling Waveform]
R_fixture= 50.000000
V_fixture= 0.0
V_fixture_min= 0.0
V_fixture_max= 0.0
|time   V(typ)   V(min)   V(max)
0s        1.37V      609mV      1.851V
460.5ps   1.37V      609mV      1.776V
700.7ps   1.376V     609.1mV    1.325V
940.9ps   1.334V     609mV      750.1mV
1.261ns   962.3mV    608.5mV    319.6mV
1.842ns   279mV      610.3mV    76.85mV
2.583ns   51.19mV    562.6mV    15.23mV
3.504ns   9.754mV    195.2mV    2.45mV
4.364ns   3.607mV    36.17mV    1.036mV
9.97ns    197.4uV    95.52uV    300.6uV
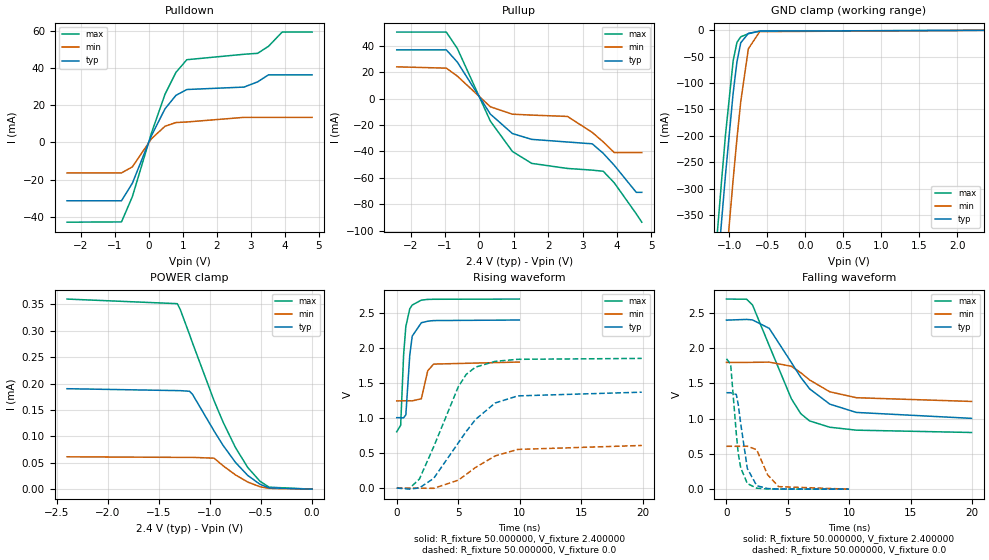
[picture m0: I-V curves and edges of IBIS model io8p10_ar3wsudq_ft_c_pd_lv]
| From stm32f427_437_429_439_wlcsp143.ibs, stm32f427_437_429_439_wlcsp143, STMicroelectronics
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|   Model io8p10_ar3wsudq_ft_c_pd_lv
[Model]  io8p10_ar3wsudq_ft_c_pd_lv
Model_type I/O
Polarity   Non-Inverting
Enable   Active-Low
Vinl =   0.720000V
Vinh =   1.680000V
Vmeas =  1.200000V
Cref =   40.000000pF
Rref =   100.000000M
Vref =   0.0V
C_comp   5.917500pF   5.759700pF   6.094700pF
[Temperature Range]   25.000000   0.125000k   -40.000000
[Pullup Reference]   2.400000V   1.800000V   2.700000V
[Pulldown Reference]   0.0V   0.0V   0.0V
[POWER Clamp Reference]   2.400000V   1.800000V   2.700000V
[GND Clamp Reference]   0.0V   0.0V   0.0V
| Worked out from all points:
|   slope of the pulldown table from 0 to 0.36 V, typ, clamps not added: 25 ohm
|   slope of the pullup table from 0 to 0.36 V, typ, clamps not added: 27.7 ohm
|   GND clamp passes 1 mA (typ) near -0.56 V on its own axis
|   rising waveform, R_fixture 50.000000, V_fixture 2.400000: 20-80 % time 340ps typ, 400ps min, 354ps max; typ from 1 V to 2.4 V
|   rising waveform, R_fixture 50.000000, V_fixture 0.0: 20-80 % time 3.47ns typ, 3.35ns min, 2.61ns max; typ from 0 V to 1.37 V
|   falling waveform, R_fixture 50.000000, V_fixture 2.400000: 20-80 % time 3.55ns typ, 3.07ns min, 2.72ns max; typ from 2.4 V to 1 V
|   falling waveform, R_fixture 50.000000, V_fixture 0.0: 20-80 % time 679ps typ, 1.02ns min, 580ps max; typ from 1.37 V to 0 V
[Pulldown]
|Voltage   I(typ)   I(min)   I(max)
-2.4V     -31.47mA   -16.45mA   -43.01mA
-800mV    -31.47mA   -16.45mA   -42.85mA
-480mV    -21.98mA   -13.17mA   -29.21mA
80mV      3.63mA     1.966mA    5.014mA
480mV     18.15mA    8.738mA    26.02mA
800mV     25.38mA    10.72mA    37.77mA
1.12V     28.53mA    11.02mA    44.6mA
2.8V      29.84mA    13.51mA    47.53mA
3.2V      32.66mA    13.51mA    48.04mA
3.52V     36.44mA    13.51mA    51.84mA
3.92V     36.44mA    13.51mA    59.49mA
4.8V      36.44mA    13.51mA    59.49mA
[Pullup]
|Voltage   I(typ)   I(min)   I(max)
-2.4V     36.91mA    24.04mA    50.35mA
-960mV    36.91mA    23.05mA    50.35mA
-640mV    27.65mA    17.04mA    37.98mA
320mV     -11.75mA   -6.207mA   -17.08mA
960mV     -26.47mA   -11.82mA   -40.02mA
1.52V     -30.88mA   -12.51mA   -49.05mA
2.56V     -32.88mA   -13.52mA   -52.9mA
3.28V     -34.25mA   -25.6mA    -54.18mA
3.6V      -41.44mA   -32.8mA    -55.03mA
3.92V     -50.5mA    -40.9mA    -63.79mA
4.56V     -71mA      -40.9mA    -87.3mA
4.72V     -71mA      -40.9mA    -93.6mA
[GND_clamp]
|Voltage   I(typ)   I(min)   I(max)
-2.4V     -2.854A    -3.022A    -2.792A
-1.25V    -627.1mA   -809.1mA   -551.5mA
-1.2V     -535.5mA   -717.4mA   -459.3mA
-1.15V    -445.4mA   -626.8mA   -368.7mA
-1.1V     -357.2mA   -537.5mA   -280.5mA
-1.05V    -272mA     -449.9mA   -196.4mA
-950mV    -118.4mA   -282.5mA   -57.42mA
-900mV    -59.51mA   -205.1mA   -22.74mA
-850mV    -23.51mA   -134.9mA   -12.19mA
-750mV    -5.744mA   -34.86mA   -6.372mA
-600mV    -1.511mA   -2.391mA   -1.49mA
2.35V     58.09uA    37.93uA    67.25uA
[POWER_clamp]
|Voltage   I(typ)   I(min)   I(max)
-2.4V     190.2uA    61.28uA    359.9uA
-1.32V    186.6uA    60.21uA    351.2uA
-1.29V    186.5uA    60.2uA     339.6uA
-1.2V     185.4uA    60.18uA    292.6uA
-1.17V    179.2uA    60.17uA    276.3uA
-960mV    110.2uA    58.68uA    167.5uA
-870mV    82.45uA    44.05uA    126.3uA
-750mV    50.58uA    26.98uA    78.64uA
-630mV    25.95uA    13.47uA    41.02uA
-510mV    9.222uA    4.578uA    14.97uA
-420mV    2.426uA    1.429uA    3.75uA
0V        0A         0A         0A
[Ramp]
| variable   typ   min   max
dV/dt_r  0.82134/3.46518n   0.36485/3.34794n   1.11042/2.60991n
dV/dt_f  0.83274/3.53656n   0.33138/3.06265n   1.13576/2.71024n
R_load = 50.000000
[Rising Waveform]
R_fixture= 50.000000
V_fixture= 2.400000
V_fixture_min= 1.800000
V_fixture_max= 2.700000
|time   V(typ)   V(min)   V(max)
0s        1.005V     1.245V     804.5mV
320.3ps   1.005V     1.245V     896.8mV
560.6ps   1.002V     1.246V     1.906V
740.7ps   1.046V     1.246V     2.306V
1.061ns   1.897V     1.246V     2.559V
1.261ns   2.169V     1.245V     2.613V
2.002ns   2.36V      1.275V     2.683V
2.523ns   2.382V     1.675V     2.693V
3.003ns   2.391V     1.77V      2.695V
9.97ns    2.399V     1.799V     2.698V
[Rising Waveform]
R_fixture= 50.000000
V_fixture= 0.0
V_fixture_min= 0.0
V_fixture_max= 0.0
|time   V(typ)   V(min)   V(max)
0s        176.4uV    74.42uV    719.2uV
1.041ns   -15.39mV   84.88uV    -2.46mV
1.842ns   2.733mV    -1.521mV   127.9mV
3.003ns   137.8mV    -3.586mV   588.2mV
5.005ns   644mV      113.1mV    1.444V
5.646ns   806.3mV    194mV      1.622V
6.406ns   978.6mV    294.1mV    1.726V
8.008ns   1.215V     459.3mV    1.809V
9.85ns    1.316V     551.9mV    1.838V
19.94ns   1.369V     608.4mV    1.851V
[Falling Waveform]
R_fixture= 50.000000
V_fixture= 2.400000
V_fixture_min= 1.800000
V_fixture_max= 2.700000
|time   V(typ)   V(min)   V(max)
0s        2.399V     1.799V     2.698V
1.642ns   2.409V     1.799V     2.696V
2.122ns   2.402V     1.8V       2.614V
3.483ns   2.282V     1.803V     2.036V
5.285ns   1.797V     1.744V     1.282V
6.046ns   1.588V     1.653V     1.072V
6.767ns   1.424V     1.55V      968.5mV
8.408ns   1.207V     1.382V     879mV
10.57ns   1.089V     1.298V     837.4mV
19.94ns   1.005V     1.245V     804.5mV
[Falling Waveform]
R_fixture= 50.000000
V_fixture= 0.0
V_fixture_min= 0.0
V_fixture_max= 0.0
|time   V(typ)   V(min)   V(max)
0s        1.369V     608.4mV    1.851V
340.3ps   1.369V     608.4mV    1.775V
800.8ps   1.344V     608.4mV    790.7mV
961ps     1.202V     608.2mV    504.5mV
1.161ns   929.9mV    607.9mV    302.5mV
1.702ns   291.6mV    609.5mV    79.24mV
2.462ns   50.35mV    559.6mV    14.05mV
3.343ns   9.003mV    205.7mV    2.348mV
4.244ns   1.989mV    36.11mV    1.326mV
9.97ns    176.4uV    74.42uV    719.2uV
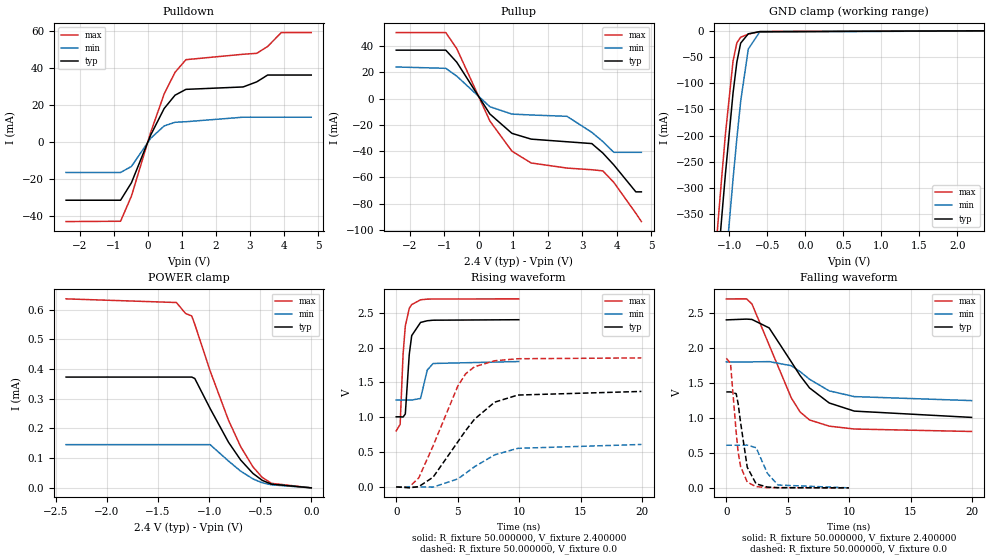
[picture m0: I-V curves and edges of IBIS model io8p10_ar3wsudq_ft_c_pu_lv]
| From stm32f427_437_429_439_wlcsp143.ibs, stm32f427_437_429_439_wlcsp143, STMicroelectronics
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|   Model io8p10_ar3wsudq_ft_c_pu_lv
[Model]  io8p10_ar3wsudq_ft_c_pu_lv
Model_type I/O
Polarity   Non-Inverting
Enable   Active-Low
Vinl =   0.720000V
Vinh =   1.680000V
Vmeas =  1.200000V
Cref =   40.000000pF
Rref =   100.000000M
Vref =   0.0V
C_comp   5.917500pF   5.759700pF   6.094700pF
[Temperature Range]   25.000000   0.125000k   -40.000000
[Pullup Reference]   2.400000V   1.800000V   2.700000V
[Pulldown Reference]   0.0V   0.0V   0.0V
[POWER Clamp Reference]   2.400000V   1.800000V   2.700000V
[GND Clamp Reference]   0.0V   0.0V   0.0V
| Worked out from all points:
|   slope of the pulldown table from 0 to 0.36 V, typ, clamps not added: 25 ohm
|   slope of the pullup table from 0 to 0.36 V, typ, clamps not added: 27.7 ohm
|   GND clamp passes 1 mA (typ) near -0.56 V on its own axis
|   rising waveform, R_fixture 50.000000, V_fixture 2.400000: 20-80 % time 339ps typ, 399ps min, 352ps max; typ from 1.01 V to 2.4 V
|   rising waveform, R_fixture 50.000000, V_fixture 0.0: 20-80 % time 3.47ns typ, 3.36ns min, 2.62ns max; typ from 0.001 V to 1.37 V
|   falling waveform, R_fixture 50.000000, V_fixture 2.400000: 20-80 % time 3.55ns typ, 3.07ns min, 2.71ns max; typ from 2.4 V to 1.01 V
|   falling waveform, R_fixture 50.000000, V_fixture 0.0: 20-80 % time 682ps typ, 1.02ns min, 582ps max; typ from 1.37 V to 0.001 V
[Pulldown]
|Voltage   I(typ)   I(min)   I(max)
-2.4V     -31.47mA   -16.45mA   -43.01mA
-800mV    -31.47mA   -16.45mA   -42.85mA
-480mV    -21.98mA   -13.17mA   -29.21mA
80mV      3.63mA     1.966mA    5.014mA
480mV     18.16mA    8.738mA    26.02mA
800mV     25.38mA    10.72mA    37.77mA
1.12V     28.53mA    11.02mA    44.6mA
2.8V      29.84mA    13.47mA    47.53mA
3.2V      32.6mA     13.47mA    48.03mA
3.52V     36.29mA    13.47mA    51.75mA
3.92V     36.29mA    13.47mA    59.26mA
4.8V      36.29mA    13.47mA    59.26mA
[Pullup]
|Voltage   I(typ)   I(min)   I(max)
-2.4V     36.82mA    24.03mA    50.2mA
-960mV    36.82mA    23mA       50.2mA
-640mV    27.62mA    17.03mA    37.94mA
320mV     -11.75mA   -6.207mA   -17.08mA
960mV     -26.47mA   -11.82mA   -40.02mA
1.52V     -30.88mA   -12.51mA   -49.05mA
2.56V     -32.88mA   -13.52mA   -52.9mA
3.28V     -34.25mA   -25.7mA    -54.17mA
3.6V      -41.44mA   -32.7mA    -55.02mA
3.92V     -50.5mA    -40.9mA    -63.79mA
4.56V     -71mA      -40.9mA    -87.3mA
4.72V     -71mA      -40.9mA    -93.6mA
[GND_clamp]
|Voltage   I(typ)   I(min)   I(max)
-2.4V     -2.854A    -3.022A    -2.793A
-1.25V    -627.1mA   -809.1mA   -551.5mA
-1.2V     -535.5mA   -717.4mA   -459.3mA
-1.15V    -445.4mA   -626.8mA   -368.7mA
-1.1V     -357.2mA   -537.5mA   -280.5mA
-1.05V    -272mA     -449.9mA   -196.4mA
-950mV    -118.4mA   -282.5mA   -57.41mA
-900mV    -59.51mA   -205.1mA   -22.73mA
-850mV    -23.5mA    -134.9mA   -12.18mA
-750mV    -5.732mA   -34.85mA   -6.358mA
-600mV    -1.5mA     -2.382mA   -1.477mA
2.35V     0A         0A         0A
[POWER_clamp]
|Voltage   I(typ)   I(min)   I(max)
-2.4V     373.1uA    145.5uA    636.5uA
-1.32V    373.1uA    145.5uA    624.2uA
-1.23V    373.1uA    145.5uA    587.2uA
-1.17V    373.1uA    145.5uA    579uA
-1.14V    368.3uA    145.5uA    550.7uA
-990mV    267.3uA    145.5uA    393.9uA
-810mV    153.6uA    90.35uA    227.7uA
-690mV    93.37uA    56.03uA    138.2uA
-570mV    48.37uA    29.99uA    70.44uA
-480mV    25.27uA    17.09uA    35.17uA
-390mV    12.5uA     10.23uA    15.16uA
0V        0A         0A         0A
[Ramp]
| variable   typ   min   max
dV/dt_r  0.82189/3.46895n   0.36545/3.35866n   1.11077/2.61238n
dV/dt_f  0.83208/3.53264n   0.33084/3.05249n   1.13543/2.70968n
R_load = 50.000000
[Rising Waveform]
R_fixture= 50.000000
V_fixture= 2.400000
V_fixture_min= 1.800000
V_fixture_max= 2.700000
|time   V(typ)   V(min)   V(max)
0s        1.007V     1.247V     806mV
320.3ps   1.007V     1.247V     898.6mV
560.6ps   1.004V     1.247V     1.91V
740.7ps   1.048V     1.247V     2.31V
1.061ns   1.901V     1.247V     2.563V
1.261ns   2.172V     1.247V     2.617V
1.982ns   2.361V     1.271V     2.686V
2.523ns   2.385V     1.677V     2.695V
3.003ns   2.393V     1.772V     2.697V
9.97ns    2.4V       1.8V       2.699V
[Rising Waveform]
R_fixture= 50.000000
V_fixture= 0.0
V_fixture_min= 0.0
V_fixture_max= 0.0
|time   V(typ)   V(min)   V(max)
0s        1.057mV    914.2uV    1.629mV
1.081ns   -12.22mV   935.1uV    3.873mV
1.842ns   5.791mV    -672.8uV   132mV
3.003ns   141.1mV    -1.782mV   591.8mV
5.005ns   646.5mV    115.3mV    1.446V
5.646ns   808.6mV    196.1mV    1.624V
6.366ns   972.5mV    290.9mV    1.725V
8.008ns   1.217V     461.2mV    1.811V
9.89ns    1.319V     554.5mV    1.84V
19.94ns   1.371V     610.2mV    1.852V
[Falling Waveform]
R_fixture= 50.000000
V_fixture= 2.400000
V_fixture_min= 1.800000
V_fixture_max= 2.700000
|time   V(typ)   V(min)   V(max)
0s        2.4V       1.8V       2.699V
1.642ns   2.411V     1.8V       2.7V
2.082ns   2.406V     1.8V       2.628V
3.483ns   2.285V     1.804V     2.04V
5.285ns   1.8V       1.745V     1.285V
6.006ns   1.603V     1.66V      1.083V
6.767ns   1.428V     1.552V     970.7mV
8.368ns   1.213V     1.386V     882.2mV
10.41ns   1.097V     1.304V     841.1mV
19.94ns   1.007V     1.247V     806mV
[Falling Waveform]
R_fixture= 50.000000
V_fixture= 0.0
V_fixture_min= 0.0
V_fixture_max= 0.0
|time   V(typ)   V(min)   V(max)
0s        1.371V     610.2mV    1.852V
340.3ps   1.371V     610.2mV    1.777V
800.8ps   1.346V     610.2mV    793.5mV
961ps     1.203V     610mV      507.6mV
1.161ns   931.5mV    609.7mV    305.7mV
1.702ns   294.7mV    611.2mV    82.92mV
2.422ns   57.86mV    574.6mV    18.49mV
3.343ns   11.82mV    207.4mV    4.006mV
4.204ns   3.718mV    41.06mV    2.532mV
9.97ns    1.057mV    914.2uV    1.629mV
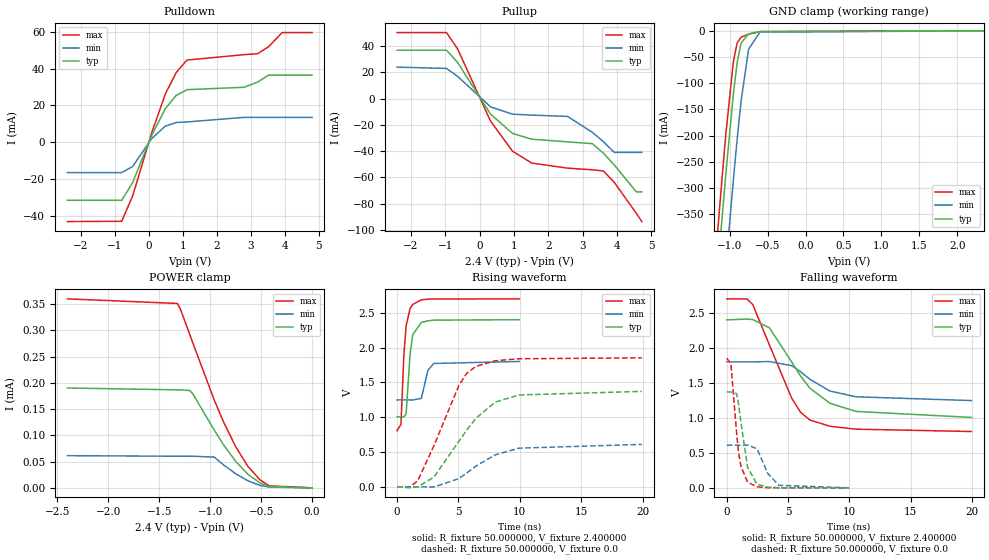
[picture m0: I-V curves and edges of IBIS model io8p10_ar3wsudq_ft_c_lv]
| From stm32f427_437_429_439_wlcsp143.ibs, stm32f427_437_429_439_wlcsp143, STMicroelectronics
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|   Model io8p10_ar3wsudq_ft_c_lv
[Model]  io8p10_ar3wsudq_ft_c_lv
Model_type I/O
Polarity   Non-Inverting
Enable   Active-Low
Vinl =   0.720000V
Vinh =   1.680000V
Vmeas =  1.200000V
Cref =   40.000000pF
Rref =   100.000000M
Vref =   0.0V
C_comp   5.917500pF   5.759700pF   6.094700pF
[Temperature Range]   25.000000   0.125000k   -40.000000
[Pullup Reference]   2.400000V   1.800000V   2.700000V
[Pulldown Reference]   0.0V   0.0V   0.0V
[POWER Clamp Reference]   2.400000V   1.800000V   2.700000V
[GND Clamp Reference]   0.0V   0.0V   0.0V
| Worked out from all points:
|   slope of the pulldown table from 0 to 0.36 V, typ, clamps not added: 25 ohm
|   slope of the pullup table from 0 to 0.36 V, typ, clamps not added: 27.7 ohm
|   GND clamp passes 1 mA (typ) near -0.56 V on its own axis
|   rising waveform, R_fixture 50.000000, V_fixture 2.400000: 20-80 % time 340ps typ, 400ps min, 354ps max; typ from 1.01 V to 2.4 V
|   rising waveform, R_fixture 50.000000, V_fixture 0.0: 20-80 % time 3.47ns typ, 3.36ns min, 2.61ns max; typ from 0 V to 1.37 V
|   falling waveform, R_fixture 50.000000, V_fixture 2.400000: 20-80 % time 3.55ns typ, 3.07ns min, 2.71ns max; typ from 2.4 V to 1.01 V
|   falling waveform, R_fixture 50.000000, V_fixture 0.0: 20-80 % time 681ps typ, 1.02ns min, 581ps max; typ from 1.37 V to 0 V
[Pulldown]
|Voltage   I(typ)   I(min)   I(max)
-2.4V     -31.47mA   -16.45mA   -43.01mA
-800mV    -31.47mA   -16.45mA   -42.85mA
-480mV    -21.98mA   -13.17mA   -29.21mA
80mV      3.63mA     1.966mA    5.014mA
480mV     18.16mA    8.738mA    26.02mA
800mV     25.38mA    10.72mA    37.77mA
1.12V     28.53mA    11.02mA    44.6mA
2.8V      29.84mA    13.51mA    47.53mA
3.2V      32.66mA    13.51mA    48.04mA
3.52V     36.44mA    13.51mA    51.84mA
3.92V     36.44mA    13.51mA    59.5mA
4.8V      36.44mA    13.51mA    59.5mA
[Pullup]
|Voltage   I(typ)   I(min)   I(max)
-2.4V     36.92mA    24.04mA    50.35mA
-960mV    36.92mA    23.05mA    50.35mA
-640mV    27.65mA    17.04mA    37.98mA
320mV     -11.75mA   -6.207mA   -17.08mA
960mV     -26.47mA   -11.82mA   -40.02mA
1.52V     -30.88mA   -12.51mA   -49.05mA
2.56V     -32.88mA   -13.52mA   -52.9mA
3.28V     -34.25mA   -25.6mA    -54.18mA
3.6V      -41.44mA   -32.7mA    -55.02mA
3.92V     -50.5mA    -40.9mA    -63.79mA
4.56V     -71mA      -40.9mA    -87.3mA
4.72V     -71mA      -40.9mA    -93.6mA
[GND_clamp]
|Voltage   I(typ)   I(min)   I(max)
-2.4V     -2.854A    -3.022A    -2.793A
-1.25V    -627.1mA   -809.1mA   -551.5mA
-1.2V     -535.5mA   -717.4mA   -459.3mA
-1.15V    -445.4mA   -626.8mA   -368.7mA
-1.1V     -357.2mA   -537.5mA   -280.5mA
-1.05V    -272mA     -449.9mA   -196.4mA
-950mV    -118.4mA   -282.5mA   -57.41mA
-900mV    -59.51mA   -205.1mA   -22.73mA
-850mV    -23.5mA    -134.9mA   -12.18mA
-750mV    -5.732mA   -34.85mA   -6.358mA
-600mV    -1.5mA     -2.382mA   -1.477mA
2.35V     0A         0A         0A
[POWER_clamp]
|Voltage   I(typ)   I(min)   I(max)
-2.4V     190.2uA    61.28uA    359.9uA
-1.32V    186.6uA    60.21uA    351.2uA
-1.29V    186.5uA    60.2uA     339.6uA
-1.2V     185.4uA    60.18uA    292.6uA
-1.17V    179.2uA    60.17uA    276.3uA
-960mV    110.2uA    58.68uA    167.5uA
-870mV    82.45uA    44.05uA    126.3uA
-750mV    50.58uA    26.98uA    78.64uA
-630mV    25.95uA    13.47uA    41.02uA
-510mV    9.222uA    4.578uA    14.97uA
-420mV    2.426uA    1.429uA    3.75uA
0V        0A         0A         0A
[Ramp]
| variable   typ   min   max
dV/dt_r  0.82200/3.46624n   0.36523/3.35142n   1.11108/2.60942n
dV/dt_f  0.83286/3.53455n   0.33120/3.06193n   1.13611/2.70869n
R_load = 50.000000
[Rising Waveform]
R_fixture= 50.000000
V_fixture= 2.400000
V_fixture_min= 1.800000
V_fixture_max= 2.700000
|time   V(typ)   V(min)   V(max)
0s        1.006V     1.247V     804.9mV
320.3ps   1.006V     1.247V     897.3mV
560.6ps   1.002V     1.247V     1.907V
740.7ps   1.046V     1.247V     2.307V
1.061ns   1.899V     1.247V     2.56V
1.281ns   2.185V     1.246V     2.619V
1.982ns   2.36V      1.27V      2.685V
2.523ns   2.384V     1.676V     2.695V
3.003ns   2.393V     1.771V     2.697V
9.97ns    2.4V       1.8V       2.699V
[Rising Waveform]
R_fixture= 50.000000
V_fixture= 0.0
V_fixture_min= 0.0
V_fixture_max= 0.0
|time   V(typ)   V(min)   V(max)
0s        176.2uV    74.35uV    719.2uV
1.041ns   -15.39mV   84.87uV    -2.467mV
1.682ns   -1.965mV   -125.2uV   84.86mV
3.003ns   137.8mV    -3.59mV    588.3mV
5.045ns   654.7mV    117.8mV    1.458V
5.686ns   816.3mV    199.4mV    1.631V
6.446ns   987.3mV    299.3mV    1.731V
8.008ns   1.216V     459.5mV    1.81V
9.93ns    1.319V     554.3mV    1.839V
19.94ns   1.37V      609mV      1.852V
[Falling Waveform]
R_fixture= 50.000000
V_fixture= 2.400000
V_fixture_min= 1.800000
V_fixture_max= 2.700000
|time   V(typ)   V(min)   V(max)
0s        2.4V       1.8V       2.699V
1.642ns   2.411V     1.8V       2.7V
2.122ns   2.405V     1.8V       2.618V
3.483ns   2.285V     1.804V     2.039V
5.285ns   1.8V       1.746V     1.284V
6.006ns   1.601V     1.66V      1.082V
6.767ns   1.425V     1.552V     969.7mV
8.408ns   1.208V     1.383V     880mV
10.53ns   1.092V     1.301V     838.4mV
19.94ns   1.006V     1.247V     804.9mV
[Falling Waveform]
R_fixture= 50.000000
V_fixture= 0.0
V_fixture_min= 0.0
V_fixture_max= 0.0
|time   V(typ)   V(min)   V(max)
0s        1.37V      609mV      1.852V
340.3ps   1.37V      609mV      1.776V
800.8ps   1.345V     609mV      792.7mV
961ps     1.203V     608.8mV    506.6mV
1.161ns   931.3mV    608.5mV    304.6mV
1.702ns   293.1mV    610.1mV    81.07mV
2.462ns   51.53mV    560.2mV    15.07mV
3.343ns   9.8mV      206.3mV    2.59mV
4.244ns   2.23mV     36.59mV    1.409mV
9.97ns    176.2uV    74.35uV    719.2uV
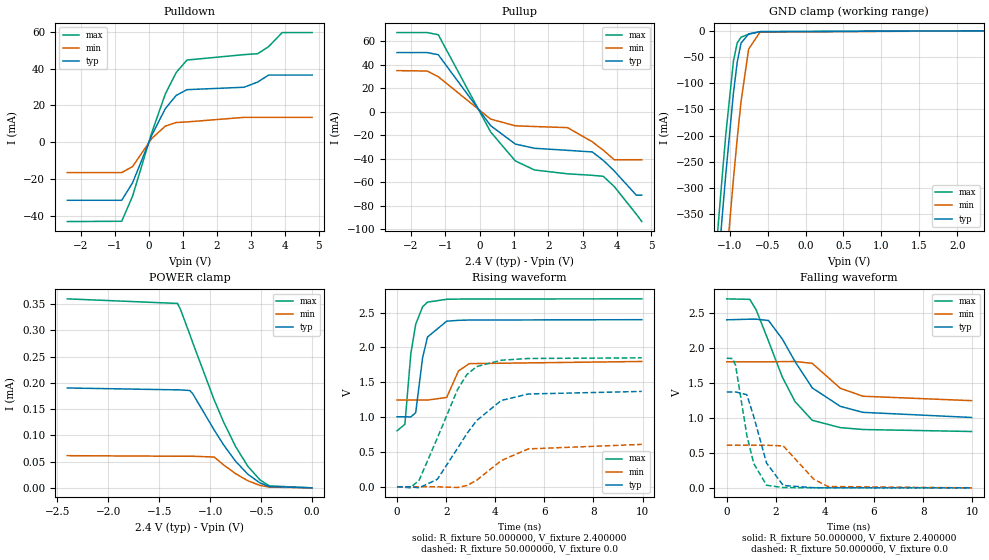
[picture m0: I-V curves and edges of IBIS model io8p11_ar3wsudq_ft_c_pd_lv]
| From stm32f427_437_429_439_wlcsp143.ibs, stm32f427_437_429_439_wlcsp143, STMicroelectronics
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|   Model io8p11_ar3wsudq_ft_c_pd_lv
[Model]  io8p11_ar3wsudq_ft_c_pd_lv
Model_type I/O
Polarity   Non-Inverting
Enable   Active-Low
Vinl =   0.720000V
Vinh =   1.680000V
Vmeas =  1.200000V
Cref =   30.000000pF
Rref =   100.000000M
Vref =   0.0V
C_comp   5.917500pF   5.759700pF   6.094700pF
[Temperature Range]   25.000000   0.125000k   -40.000000
[Pullup Reference]   2.400000V   1.800000V   2.700000V
[Pulldown Reference]   0.0V   0.0V   0.0V
[POWER Clamp Reference]   2.400000V   1.800000V   2.700000V
[GND Clamp Reference]   0.0V   0.0V   0.0V
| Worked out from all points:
|   slope of the pulldown table from 0 to 0.36 V, typ, clamps not added: 25 ohm
|   slope of the pullup table from 0 to 0.36 V, typ, clamps not added: 27.7 ohm
|   GND clamp passes 1 mA (typ) near -0.56 V on its own axis
|   rising waveform, R_fixture 50.000000, V_fixture 2.400000: 20-80 % time 343ps typ, 406ps min, 356ps max; typ from 1 V to 2.4 V
|   rising waveform, R_fixture 50.000000, V_fixture 0.0: 20-80 % time 1.65ns typ, 1.48ns min, 1.31ns max; typ from 0 V to 1.37 V
|   falling waveform, R_fixture 50.000000, V_fixture 2.400000: 20-80 % time 1.66ns typ, 1.22ns min, 1.4ns max; typ from 2.4 V to 1 V
|   falling waveform, R_fixture 50.000000, V_fixture 0.0: 20-80 % time 673ps typ, 909ps min, 578ps max; typ from 1.37 V to 0 V
[Pulldown]
|Voltage   I(typ)   I(min)   I(max)
-2.4V     -31.47mA   -16.45mA   -43.01mA
-800mV    -31.47mA   -16.45mA   -42.85mA
-480mV    -21.98mA   -13.17mA   -29.21mA
80mV      3.63mA     1.966mA    5.014mA
480mV     18.15mA    8.738mA    26.02mA
800mV     25.38mA    10.72mA    37.77mA
1.12V     28.53mA    11.02mA    44.6mA
2.8V      29.84mA    13.51mA    47.53mA
3.2V      32.66mA    13.51mA    48.04mA
3.52V     36.44mA    13.51mA    51.84mA
3.92V     36.44mA    13.51mA    59.49mA
4.8V      36.44mA    13.51mA    59.49mA
[Pullup]
|Voltage   I(typ)   I(min)   I(max)
-2.4V     50.45mA    35.08mA    67.51mA
-1.52V    50.45mA    34.74mA    67.51mA
-1.2V     48.64mA    29.87mA    65.66mA
320mV     -11.75mA   -6.207mA   -17.08mA
1.04V     -27.53mA   -11.97mA   -41.91mA
1.6V      -31.13mA   -12.58mA   -49.63mA
2.56V     -32.88mA   -13.52mA   -52.9mA
3.28V     -34.25mA   -25.6mA    -54.18mA
3.6V      -41.44mA   -32.8mA    -55.03mA
3.92V     -50.5mA    -40.9mA    -63.79mA
4.56V     -71.1mA    -40.9mA    -87.3mA
4.72V     -71.1mA    -40.9mA    -93.6mA
[GND_clamp]
|Voltage   I(typ)   I(min)   I(max)
-2.4V     -2.853A    -3.022A    -2.792A
-1.25V    -627.1mA   -809.1mA   -551.5mA
-1.2V     -535.5mA   -717.4mA   -459.3mA
-1.15V    -445.4mA   -626.8mA   -368.7mA
-1.1V     -357.2mA   -537.5mA   -280.5mA
-1.05V    -272mA     -449.9mA   -196.4mA
-950mV    -118.4mA   -282.5mA   -57.42mA
-900mV    -59.51mA   -205.1mA   -22.74mA
-850mV    -23.51mA   -134.9mA   -12.19mA
-750mV    -5.744mA   -34.86mA   -6.372mA
-600mV    -1.511mA   -2.391mA   -1.49mA
2.35V     58.09uA    37.93uA    67.25uA
[POWER_clamp]
|Voltage   I(typ)   I(min)   I(max)
-2.4V     190.2uA    61.28uA    359.9uA
-1.32V    186.6uA    60.21uA    351.2uA
-1.29V    186.5uA    60.2uA     339.6uA
-1.2V     185.4uA    60.18uA    292.6uA
-1.17V    179.2uA    60.17uA    276.3uA
-960mV    110.2uA    58.68uA    167.5uA
-870mV    82.45uA    44.05uA    126.3uA
-750mV    50.58uA    26.98uA    78.64uA
-630mV    25.95uA    13.47uA    41.02uA
-510mV    9.222uA    4.578uA    14.97uA
-420mV    2.426uA    1.429uA    3.75uA
0V        0A         0A         0A
[Ramp]
| variable   typ   min   max
dV/dt_r  0.82092/1.64691n   0.36361/1.47228n   1.11030/1.31007n
dV/dt_f  0.83190/1.64502n   0.33138/1.21879n   1.13518/1.39742n
R_load = 50.000000
[Rising Waveform]
R_fixture= 50.000000
V_fixture= 2.400000
V_fixture_min= 1.800000
V_fixture_max= 2.700000
|time   V(typ)   V(min)   V(max)
0s        1.005V     1.245V     804.5mV
320.3ps   1.005V     1.245V     896.2mV
560.6ps   1.002V     1.246V     1.904V
760.8ps   1.064V     1.246V     2.332V
1.041ns   1.852V     1.246V     2.584V
1.241ns   2.15V      1.245V     2.651V
2.022ns   2.377V     1.282V     2.692V
2.503ns   2.39V      1.663V     2.695V
2.943ns   2.394V     1.768V     2.696V
9.97ns    2.399V     1.799V     2.698V
[Rising Waveform]
R_fixture= 50.000000
V_fixture= 0.0
V_fixture_min= 0.0
V_fixture_max= 0.0
|time   V(typ)   V(min)   V(max)
0s        173uV      72.57uV    803.3uV
540.5ps   -582.6uV   49.99uV    -14.97mV
900.9ps   -15.59mV   58.79uV    94.38mV
1.642ns   106.9mV    -91.91uV   699.8mV
2.462ns   550.2mV    -10.39mV   1.393V
2.843ns   761.9mV    16.84mV    1.611V
3.243ns   950.1mV    93.38mV    1.725V
4.244ns   1.239V     375.6mV    1.817V
5.345ns   1.332V     543.7mV    1.842V
9.97ns    1.369V     608.3mV    1.851V
[Falling Waveform]
R_fixture= 50.000000
V_fixture= 2.400000
V_fixture_min= 1.800000
V_fixture_max= 2.700000
|time   V(typ)   V(min)   V(max)
0s        2.399V     1.799V     2.698V
940.9ps   2.408V     1.799V     2.691V
1.201ns   2.408V     1.799V     2.54V
1.702ns   2.389V     1.799V     2.095V
2.262ns   2.126V     1.802V     1.583V
2.783ns   1.803V     1.804V     1.231V
3.483ns   1.427V     1.777V     964.6mV
4.625ns   1.164V     1.422V     860mV
5.546ns   1.078V     1.308V     833mV
9.97ns    1.005V     1.245V     804.5mV
[Falling Waveform]
R_fixture= 50.000000
V_fixture= 0.0
V_fixture_min= 0.0
V_fixture_max= 0.0
|time   V(typ)   V(min)   V(max)
0s        1.369V     608.3mV    1.851V
240.2ps   1.369V     608.4mV    1.845V
360.4ps   1.369V     608.4mV    1.749V
820.8ps   1.33V      608.3mV    746.7mV
1.101ns   1.018V     608mV      346.7mV
1.622ns   354.2mV    608.8mV    37.35mV
2.302ns   34.14mV    598.7mV    3.793mV
3.544ns   2.095mV    123.7mV    1.655mV
4.124ns   1.341mV    18.8mV     1.361mV
9.97ns    173uV      72.57uV    803.3uV
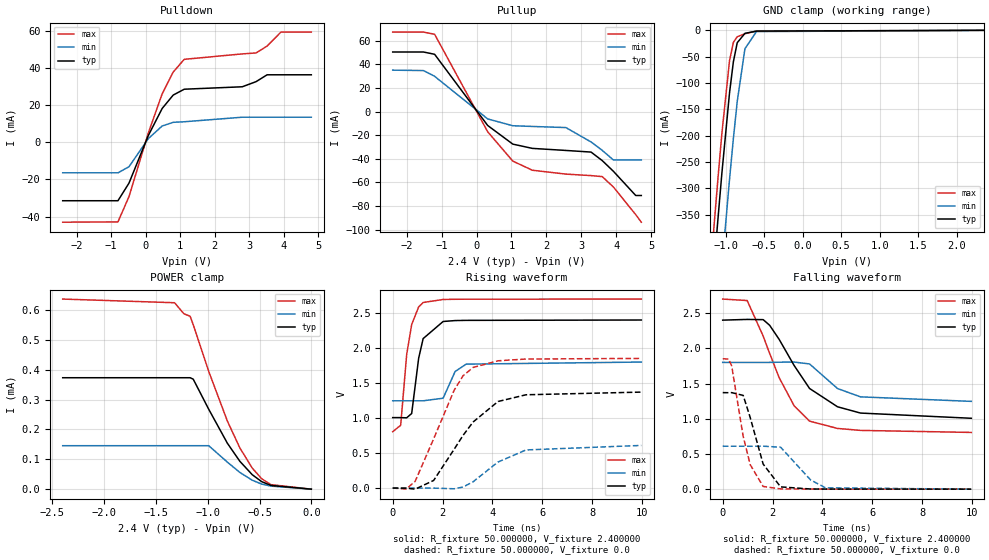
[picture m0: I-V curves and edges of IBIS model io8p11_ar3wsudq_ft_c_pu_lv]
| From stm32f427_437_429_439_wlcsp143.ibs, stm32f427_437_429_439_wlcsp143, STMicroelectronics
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|   Model io8p11_ar3wsudq_ft_c_pu_lv
[Model]  io8p11_ar3wsudq_ft_c_pu_lv
Model_type I/O
Polarity   Non-Inverting
Enable   Active-Low
Vinl =   0.720000V
Vinh =   1.680000V
Vmeas =  1.200000V
Cref =   30.000000pF
Rref =   100.000000M
Vref =   0.0V
C_comp   5.917500pF   5.759700pF   6.094700pF
[Temperature Range]   25.000000   0.125000k   -40.000000
[Pullup Reference]   2.400000V   1.800000V   2.700000V
[Pulldown Reference]   0.0V   0.0V   0.0V
[POWER Clamp Reference]   2.400000V   1.800000V   2.700000V
[GND Clamp Reference]   0.0V   0.0V   0.0V
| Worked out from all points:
|   slope of the pulldown table from 0 to 0.36 V, typ, clamps not added: 25 ohm
|   slope of the pullup table from 0 to 0.36 V, typ, clamps not added: 27.7 ohm
|   GND clamp passes 1 mA (typ) near -0.56 V on its own axis
|   rising waveform, R_fixture 50.000000, V_fixture 2.400000: 20-80 % time 341ps typ, 404ps min, 354ps max; typ from 1.01 V to 2.4 V
|   rising waveform, R_fixture 50.000000, V_fixture 0.0: 20-80 % time 1.65ns typ, 1.48ns min, 1.31ns max; typ from 0.001 V to 1.37 V
|   falling waveform, R_fixture 50.000000, V_fixture 2.400000: 20-80 % time 1.66ns typ, 1.22ns min, 1.4ns max; typ from 2.4 V to 1.01 V
|   falling waveform, R_fixture 50.000000, V_fixture 0.0: 20-80 % time 676ps typ, 913ps min, 580ps max; typ from 1.37 V to 0.001 V
[Pulldown]
|Voltage   I(typ)   I(min)   I(max)
-2.4V     -31.47mA   -16.45mA   -43.01mA
-800mV    -31.47mA   -16.45mA   -42.85mA
-480mV    -21.98mA   -13.17mA   -29.21mA
80mV      3.63mA     1.966mA    5.014mA
480mV     18.16mA    8.738mA    26.02mA
800mV     25.38mA    10.72mA    37.77mA
1.12V     28.53mA    11.02mA    44.6mA
2.8V      29.84mA    13.47mA    47.53mA
3.2V      32.6mA     13.47mA    48.03mA
3.52V     36.29mA    13.47mA    51.75mA
3.92V     36.29mA    13.47mA    59.26mA
4.8V      36.29mA    13.47mA    59.26mA
[Pullup]
|Voltage   I(typ)   I(min)   I(max)
-2.4V     50.45mA    35.08mA    67.3mA
-1.52V    50.45mA    34.74mA    67.3mA
-1.2V     48.51mA    29.88mA    65.47mA
320mV     -11.75mA   -6.207mA   -17.08mA
1.04V     -27.53mA   -11.97mA   -41.91mA
1.6V      -31.13mA   -12.57mA   -49.63mA
2.56V     -32.88mA   -13.52mA   -52.9mA
3.28V     -34.25mA   -25.7mA    -54.17mA
3.6V      -41.44mA   -32.8mA    -55.02mA
3.92V     -50.5mA    -40.9mA    -63.79mA
4.56V     -71mA      -40.9mA    -87.2mA
4.72V     -71mA      -40.9mA    -93.6mA
[GND_clamp]
|Voltage   I(typ)   I(min)   I(max)
-2.4V     -2.854A    -3.022A    -2.792A
-1.25V    -627.1mA   -809.1mA   -551.5mA
-1.2V     -535.5mA   -717.4mA   -459.3mA
-1.15V    -445.4mA   -626.8mA   -368.7mA
-1.1V     -357.2mA   -537.5mA   -280.5mA
-1.05V    -272mA     -449.9mA   -196.4mA
-950mV    -118.4mA   -282.5mA   -57.41mA
-900mV    -59.51mA   -205.1mA   -22.73mA
-850mV    -23.5mA    -134.9mA   -12.18mA
-750mV    -5.732mA   -34.85mA   -6.358mA
-600mV    -1.5mA     -2.382mA   -1.477mA
2.35V     0A         0A         0A
[POWER_clamp]
|Voltage   I(typ)   I(min)   I(max)
-2.4V     373.1uA    145.5uA    636.5uA
-1.32V    373.1uA    145.5uA    624.2uA
-1.23V    373.1uA    145.5uA    587.2uA
-1.17V    373.1uA    145.5uA    579uA
-1.14V    368.3uA    145.5uA    550.7uA
-990mV    267.3uA    145.5uA    393.9uA
-810mV    153.6uA    90.35uA    227.7uA
-690mV    93.37uA    56.03uA    138.2uA
-570mV    48.37uA    29.99uA    70.44uA
-480mV    25.27uA    17.09uA    35.17uA
-390mV    12.5uA     10.23uA    15.16uA
0V        0A         0A         0A
[Ramp]
| variable   typ   min   max
dV/dt_r  0.82147/1.65031n   0.36418/1.47592n   1.11071/1.31221n
dV/dt_f  0.83118/1.64351n   0.33084/1.21972n   1.13486/1.39748n
R_load = 50.000000
[Rising Waveform]
R_fixture= 50.000000
V_fixture= 2.400000
V_fixture_min= 1.800000
V_fixture_max= 2.700000
|time   V(typ)   V(min)   V(max)
0s        1.007V     1.247V     806.1mV
320.3ps   1.007V     1.247V     898mV
560.6ps   1.004V     1.247V     1.909V
760.8ps   1.066V     1.247V     2.336V
1.041ns   1.855V     1.247V     2.587V
1.221ns   2.135V     1.247V     2.65V
2.022ns   2.379V     1.284V     2.693V
2.503ns   2.392V     1.665V     2.696V
2.943ns   2.395V     1.77V      2.697V
9.97ns    2.4V       1.8V       2.699V
[Rising Waveform]
R_fixture= 50.000000
V_fixture= 0.0
V_fixture_min= 0.0
V_fixture_max= 0.0
|time   V(typ)   V(min)   V(max)
0s        1.053mV    912.4uV    1.713mV
540.5ps   301.1uV    889.9uV    -12.61mV
900.9ps   -14.28mV   898.6uV    98.35mV
1.642ns   110.4mV    746uV      704.5mV
2.462ns   554mV      -8.933mV   1.396V
2.823ns   754.4mV    16.14mV    1.605V
3.223ns   944.1mV    91.24mV    1.723V
4.224ns   1.237V     373.1mV    1.818V
5.345ns   1.333V     545.5mV    1.843V
9.97ns    1.371V     610.1mV    1.852V
[Falling Waveform]
R_fixture= 50.000000
V_fixture= 2.400000
V_fixture_min= 1.800000
V_fixture_max= 2.700000
|time   V(typ)   V(min)   V(max)
0s        2.4V       1.8V       2.699V
981ps     2.41V      1.8V       2.678V
1.622ns   2.407V     1.8V       2.174V
1.882ns   2.327V     1.8V       1.928V
2.262ns   2.128V     1.803V     1.585V
2.863ns   1.757V     1.805V     1.185V
3.483ns   1.43V      1.778V     966.7mV
4.605ns   1.17V      1.429V     862.7mV
5.526ns   1.081V     1.311V     835mV
9.97ns    1.007V     1.247V     806.1mV
[Falling Waveform]
R_fixture= 50.000000
V_fixture= 0.0
V_fixture_min= 0.0
V_fixture_max= 0.0
|time   V(typ)   V(min)   V(max)
0s        1.371V     610.1mV    1.852V
240.2ps   1.37V      610.2mV    1.847V
360.4ps   1.371V     610.2mV    1.75V
820.8ps   1.332V     610.1mV    749.7mV
1.101ns   1.02V      609.8mV    349.8mV
1.622ns   357.3mV    610.6mV    39.22mV
2.322ns   33.15mV    596.7mV    4.816mV
3.524ns   3.153mV    131.9mV    2.644mV
4.124ns   2.299mV    19.96mV    2.311mV
9.97ns    1.053mV    912.4uV    1.713mV
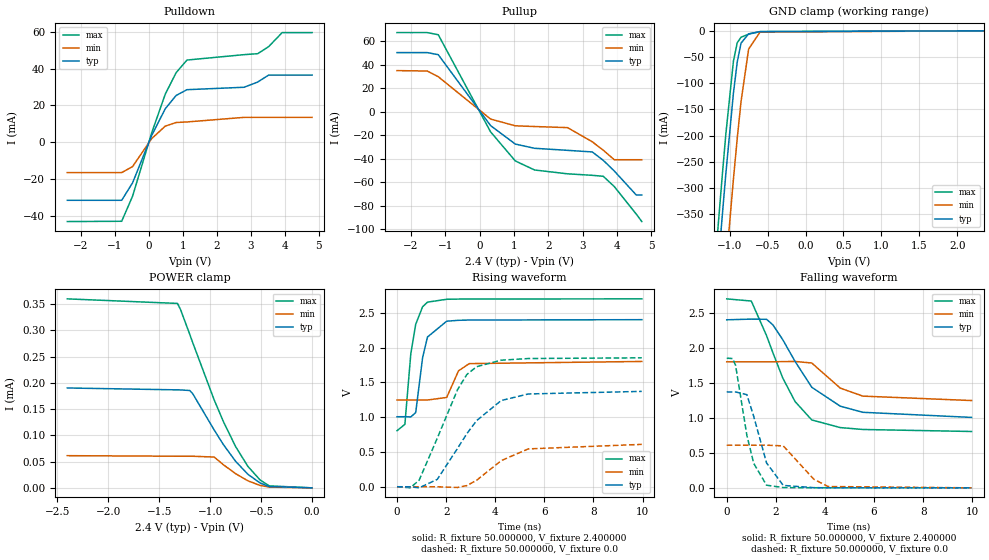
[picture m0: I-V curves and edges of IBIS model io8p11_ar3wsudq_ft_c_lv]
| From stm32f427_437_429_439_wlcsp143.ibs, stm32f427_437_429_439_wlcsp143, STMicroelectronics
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|   Model io8p11_ar3wsudq_ft_c_lv
[Model]  io8p11_ar3wsudq_ft_c_lv
Model_type I/O
Polarity   Non-Inverting
Enable   Active-Low
Vinl =   0.720000V
Vinh =   1.680000V
Vmeas =  1.200000V
Cref =   30.000000pF
Rref =   100.000000M
Vref =   0.0V
C_comp   5.917500pF   5.759700pF   6.094700pF
[Temperature Range]   25.000000   0.125000k   -40.000000
[Pullup Reference]   2.400000V   1.800000V   2.700000V
[Pulldown Reference]   0.0V   0.0V   0.0V
[POWER Clamp Reference]   2.400000V   1.800000V   2.700000V
[GND Clamp Reference]   0.0V   0.0V   0.0V
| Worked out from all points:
|   slope of the pulldown table from 0 to 0.36 V, typ, clamps not added: 25 ohm
|   slope of the pullup table from 0 to 0.36 V, typ, clamps not added: 27.7 ohm
|   GND clamp passes 1 mA (typ) near -0.56 V on its own axis
|   rising waveform, R_fixture 50.000000, V_fixture 2.400000: 20-80 % time 343ps typ, 405ps min, 356ps max; typ from 1.01 V to 2.4 V
|   rising waveform, R_fixture 50.000000, V_fixture 0.0: 20-80 % time 1.65ns typ, 1.48ns min, 1.31ns max; typ from 0 V to 1.37 V
|   falling waveform, R_fixture 50.000000, V_fixture 2.400000: 20-80 % time 1.66ns typ, 1.23ns min, 1.4ns max; typ from 2.4 V to 1.01 V
|   falling waveform, R_fixture 50.000000, V_fixture 0.0: 20-80 % time 675ps typ, 911ps min, 579ps max; typ from 1.37 V to 0 V
[Pulldown]
|Voltage   I(typ)   I(min)   I(max)
-2.4V     -31.47mA   -16.45mA   -43.01mA
-800mV    -31.47mA   -16.45mA   -42.85mA
-480mV    -21.98mA   -13.17mA   -29.21mA
80mV      3.63mA     1.966mA    5.014mA
480mV     18.16mA    8.738mA    26.02mA
800mV     25.38mA    10.72mA    37.77mA
1.12V     28.53mA    11.02mA    44.6mA
2.8V      29.84mA    13.51mA    47.53mA
3.2V      32.66mA    13.51mA    48.04mA
3.52V     36.44mA    13.51mA    51.84mA
3.92V     36.44mA    13.51mA    59.5mA
4.8V      36.44mA    13.51mA    59.5mA
[Pullup]
|Voltage   I(typ)   I(min)   I(max)
-2.4V     50.45mA    35.09mA    67.51mA
-1.52V    50.45mA    34.74mA    67.51mA
-1.2V     48.65mA    29.87mA    65.66mA
320mV     -11.75mA   -6.207mA   -17.08mA
1.04V     -27.54mA   -11.97mA   -41.91mA
1.6V      -31.14mA   -12.58mA   -49.63mA
2.56V     -32.88mA   -13.52mA   -52.9mA
3.28V     -34.25mA   -25.6mA    -54.18mA
3.6V      -41.44mA   -32.8mA    -55.02mA
3.92V     -50.5mA    -40.9mA    -63.79mA
4.56V     -71mA      -40.9mA    -87.3mA
4.72V     -71mA      -40.9mA    -93.6mA
[GND_clamp]
|Voltage   I(typ)   I(min)   I(max)
-2.4V     -2.854A    -3.022A    -2.792A
-1.25V    -627.1mA   -809.1mA   -551.5mA
-1.2V     -535.5mA   -717.4mA   -459.3mA
-1.15V    -445.4mA   -626.8mA   -368.7mA
-1.1V     -357.2mA   -537.5mA   -280.5mA
-1.05V    -272mA     -449.9mA   -196.4mA
-950mV    -118.4mA   -282.5mA   -57.41mA
-900mV    -59.51mA   -205.1mA   -22.73mA
-850mV    -23.5mA    -134.9mA   -12.18mA
-750mV    -5.732mA   -34.85mA   -6.358mA
-600mV    -1.5mA     -2.382mA   -1.477mA
2.35V     0A         0A         0A
[POWER_clamp]
|Voltage   I(typ)   I(min)   I(max)
-2.4V     190.2uA    61.28uA    359.9uA
-1.32V    186.6uA    60.21uA    351.2uA
-1.29V    186.5uA    60.2uA     339.6uA
-1.2V     185.4uA    60.18uA    292.6uA
-1.17V    179.2uA    60.17uA    276.3uA
-960mV    110.2uA    58.68uA    167.5uA
-870mV    82.45uA    44.05uA    126.3uA
-750mV    50.58uA    26.98uA    78.64uA
-630mV    25.95uA    13.47uA    41.02uA
-510mV    9.222uA    4.578uA    14.97uA
-420mV    2.426uA    1.429uA    3.75uA
0V        0A         0A         0A
[Ramp]
| variable   typ   min   max
dV/dt_r  0.82152/1.64783n   0.36394/1.47410n   1.11096/1.31054n
dV/dt_f  0.83190/1.64491n   0.33114/1.22038n   1.13552/1.39713n
R_load = 50.000000
[Rising Waveform]
R_fixture= 50.000000
V_fixture= 2.400000
V_fixture_min= 1.800000
V_fixture_max= 2.700000
|time   V(typ)   V(min)   V(max)
0s        1.006V     1.247V     805mV
320.3ps   1.006V     1.247V     896.7mV
560.6ps   1.003V     1.247V     1.906V
760.8ps   1.065V     1.247V     2.333V
1.041ns   1.853V     1.247V     2.585V
1.241ns   2.151V     1.246V     2.652V
2.022ns   2.378V     1.283V     2.693V
2.503ns   2.391V     1.665V     2.696V
2.943ns   2.395V     1.769V     2.697V
9.97ns    2.4V       1.8V       2.699V
[Rising Waveform]
R_fixture= 50.000000
V_fixture= 0.0
V_fixture_min= 0.0
V_fixture_max= 0.0
|time   V(typ)   V(min)   V(max)
0s        172.9uV    72.5uV     803.3uV
540.5ps   -582.6uV   49.94uV    -14.98mV
900.9ps   -15.59mV   58.78uV    94.37mV
1.642ns   106.9mV    -91.84uV   699.8mV
2.462ns   550.3mV    -10.39mV   1.393V
2.843ns   762.1mV    16.84mV    1.612V
3.243ns   950.4mV    93.38mV    1.725V
4.244ns   1.239V     375.6mV    1.818V
5.345ns   1.333V     543.9mV    1.842V
9.97ns    1.37V      609mV      1.852V
[Falling Waveform]
R_fixture= 50.000000
V_fixture= 2.400000
V_fixture_min= 1.800000
V_fixture_max= 2.700000
|time   V(typ)   V(min)   V(max)
0s        2.4V       1.8V       2.699V
1.001ns   2.41V      1.8V       2.668V
1.622ns   2.407V     1.8V       2.174V
1.882ns   2.327V     1.8V       1.928V
2.282ns   2.116V     1.803V     1.569V
2.783ns   1.806V     1.805V     1.233V
3.463ns   1.437V     1.783V     969.7mV
4.625ns   1.166V     1.424V     860.8mV
5.546ns   1.079V     1.31V      833.6mV
9.97ns    1.006V     1.247V     805mV
[Falling Waveform]
R_fixture= 50.000000
V_fixture= 0.0
V_fixture_min= 0.0
V_fixture_max= 0.0
|time   V(typ)   V(min)   V(max)
0s        1.37V      609mV      1.852V
240.2ps   1.37V      609mV      1.847V
360.4ps   1.37V      609mV      1.75V
820.8ps   1.331V     608.9mV    748.8mV
1.101ns   1.019V     608.7mV    348.7mV
1.622ns   355.7mV    609.5mV    38.26mV
2.302ns   34.92mV    599.3mV    4.098mV
3.544ns   2.284mV    124.3mV    1.761mV
4.124ns   1.465mV    19.09mV    1.428mV
9.97ns    172.9uV    72.5uV     803.3uV
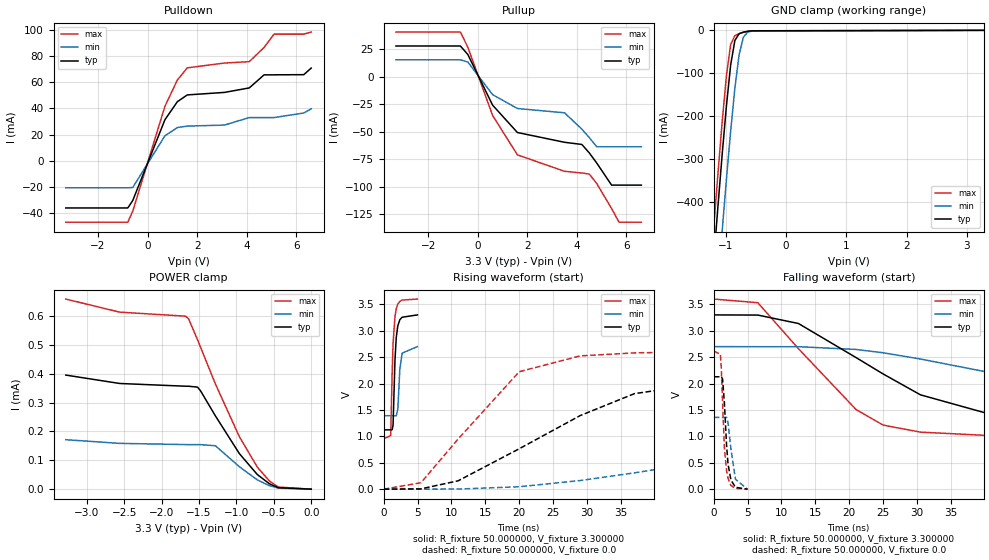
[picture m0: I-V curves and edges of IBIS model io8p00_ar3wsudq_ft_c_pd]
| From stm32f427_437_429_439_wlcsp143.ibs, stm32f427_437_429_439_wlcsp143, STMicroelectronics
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|   Model io8p00_ar3wsudq_ft_c_pd
[Model]  io8p00_ar3wsudq_ft_c_pd
Model_type I/O
Polarity   Non-Inverting
Enable   Active-Low
Vinl =   0.990000V
Vinh =   2.310000V
Vmeas =  1.650000V
Cref =   50.000000pF
Rref =   100.000000M
Vref =   0.0V
C_comp   5.986400pF   5.818600pF   6.191500pF
[Temperature Range]   25.000000   0.125000k   -40.000000
[Pullup Reference]   3.300000V   2.700000V   3.600000V
[Pulldown Reference]   0.0V   0.0V   0.0V
[POWER Clamp Reference]   3.300000V   2.700000V   3.600000V
[GND Clamp Reference]   0.0V   0.0V   0.0V
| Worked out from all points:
|   slope of the pulldown table from 0 to 0.495 V, typ, clamps not added: 20.9 ohm
|   slope of the pullup table from 0 to 0.495 V, typ, clamps not added: 22.6 ohm
|   GND clamp passes 1 mA (typ) near -0.56 V on its own axis
|   rising waveform, R_fixture 50.000000, V_fixture 3.300000: 20-80 % time 369ps typ, 351ps min, 392ps max; typ from 1.12 V to 3.3 V
|   rising waveform, R_fixture 50.000000, V_fixture 0.0: 20-80 % time 19.2ns typ, 45.2ns min, 10.2ns max; typ from 0 V to 2.13 V
|   falling waveform, R_fixture 50.000000, V_fixture 3.300000: 20-80 % time 18.2ns typ, 37.1ns min, 11.3ns max; typ from 3.3 V to 1.12 V
|   falling waveform, R_fixture 50.000000, V_fixture 0.0: 20-80 % time 609ps typ, 776ps min, 542ps max; typ from 2.13 V to 0 V
[Pulldown]
|Voltage   I(typ)   I(min)   I(max)
-3.3V     -36.18mA   -20.77mA   -47.07mA
-800mV    -36.18mA   -20.77mA   -47.07mA
-600mV    -30.5mA    -20.52mA   -38.69mA
700mV     31.4mA     19.11mA    41.71mA
1.2V      45.15mA    25.37mA    61.75mA
1.6V      50.35mA    26.5mA     71.06mA
3.1V      52.27mA    27.26mA    74.75mA
4.1V      55.7mA     33.01mA    75.8mA
4.7V      65.73mA    33.01mA    86.69mA
5.1V      65.73mA    33.01mA    96.89mA
6.3V      65.85mA    36.49mA    96.89mA
6.6V      70.9mA     39.7mA     98.44mA
[Pullup]
|Voltage   I(typ)   I(min)   I(max)
-3.3V     28.03mA    15.43mA    40.67mA
-700mV    28.03mA    15.43mA    40.67mA
-400mV    20.31mA    13.47mA    26.93mA
600mV     -25.77mA   -16.23mA   -35.13mA
1.6V      -50.64mA   -28.81mA   -70.96mA
3.5V      -59.53mA   -32.72mA   -85.92mA
4.2V      -61.52mA   -47.6mA    -87.46mA
4.5V      -69.21mA   -55.3mA    -88.43mA
4.8V      -78.4mA    -63.6mA    -97.01mA
5.4V      -98.5mA    -63.6mA    -119.8mA
5.7V      -98.5mA    -63.6mA    -132.2mA
6.6V      -98.5mA    -63.6mA    -132.2mA
[GND_clamp]
|Voltage   I(typ)   I(min)   I(max)
-3.3V     -4.641A    -4.8A      -4.589A
-1.2V     -535.6mA   -717.5mA   -459.3mA
-1.13V    -409.9mA   -591mA     -333.1mA
-1.06V    -288.9mA   -467.4mA   -212.9mA
-990mV    -176.2mA   -348mA     -105.7mA
-920mV    -81.01mA   -235.5mA   -32.97mA
-850mV    -23.67mA   -135.1mA   -12.28mA
-780mV    -7.764mA   -57.43mA   -7.776mA
-710mV    -4.197mA   -16.31mA   -4.777mA
-640mV    -2.307mA   -4.41mA    -2.453mA
-570mV    -1.059mA   -1.629mA   -967uA
3.28V     81.28uA    57.87uA    93.98uA
[POWER_clamp]
|Voltage   I(typ)   I(min)   I(max)
-3.28V    395.3uA    171.4uA    658.7uA
-2.56V    366.2uA    158.7uA    613.4uA
-1.68V    356.7uA    154.5uA    599.4uA
-1.64V    356.6uA    154.5uA    590.8uA
-1.52V    353.6uA    154.3uA    518.3uA
-1.48V    341.1uA    154.3uA    492.3uA
-1.28V    253.6uA    150.4uA    364.2uA
-960mV    123.1uA    77.62uA    181.6uA
-720mV    50.52uA    32.09uA    76.18uA
-560mV    18.94uA    12.32uA    28.65uA
-440mV    5.105uA    3.74uA     7.327uA
0V        0A         0A         0A
[Ramp]
| variable   typ   min   max
dV/dt_r  1.27680/19.16830n   0.81450/45.16563n   1.56648/10.21799n
dV/dt_f  1.30548/18.22539n   0.78468/37.05043n   1.58744/11.28150n
R_load = 50.000000
[Rising Waveform]
R_fixture= 50.000000
V_fixture= 3.300000
V_fixture_min= 2.700000
V_fixture_max= 3.600000
|time   V(typ)   V(min)   V(max)
0s        1.123V     1.39V      953.1mV
1.041ns   1.123V     1.391V     1.014V
1.261ns   1.126V     1.391V     2.232V
1.391ns   1.213V     1.391V     2.757V
1.672ns   2.442V     1.388V     3.266V
1.862ns   2.872V     1.39V      3.418V
2.092ns   3.093V     1.511V     3.503V
2.392ns   3.208V     2.273V     3.554V
2.733ns   3.255V     2.576V     3.58V
4.985ns   3.299V     2.699V     3.599V
[Rising Waveform]
R_fixture= 50.000000
V_fixture= 0.0
V_fixture_min= 0.0
V_fixture_max= 0.0
|time   V(typ)   V(min)   V(max)
0s        11.29nV    567.1nV    7.392nV
5.506ns   5.682mV    -139uV     121.1mV
11.01ns   158.4mV    1.712mV    950.6mV
20.02ns   764.4mV    45.79mV    2.223V
29.03ns   1.393V     163.1mV    2.523V
37.04ns   1.808V     308.3mV    2.58V
48.05ns   2.014V     534.5mV    2.604V
71.07ns   2.108V     969.2mV    2.61V
98.6ns    2.126V     1.234V     2.611V
249.2ns   2.128V     1.358V     2.611V
[Falling Waveform]
R_fixture= 50.000000
V_fixture= 3.300000
V_fixture_min= 2.700000
V_fixture_max= 3.600000
|time   V(typ)   V(min)   V(max)
0s        3.299V     2.699V     3.599V
6.507ns   3.296V     2.697V     3.53V
12.51ns   3.136V     2.697V     2.659V
21.02ns   2.491V     2.645V     1.507V
25.03ns   2.18V      2.582V     1.212V
30.53ns   1.786V     2.464V     1.08V
44.04ns   1.304V     2.126V     992.8mV
63.06ns   1.181V     1.72V      963.1mV
84.08ns   1.143V     1.537V     955.5mV
249.2ns   1.123V     1.39V      953.1mV
[Falling Waveform]
R_fixture= 50.000000
V_fixture= 0.0
V_fixture_min= 0.0
V_fixture_max= 0.0
|time   V(typ)   V(min)   V(max)
0s        2.128V     1.358V     2.611V
971ps     2.128V     1.358V     2.559V
1.101ns   2.132V     1.357V     2.315V
1.301ns   2.083V     1.357V     1.636V
1.572ns   1.623V     1.359V     772.8mV
1.882ns   845.5mV    1.362V     352.8mV
2.102ns   476.8mV    1.265V     205.9mV
2.533ns   173mV      759mV      69.7mV
3.203ns   35.57mV    188.4mV    13.98mV
4.985ns   11.29nV    567.1nV    7.392nV
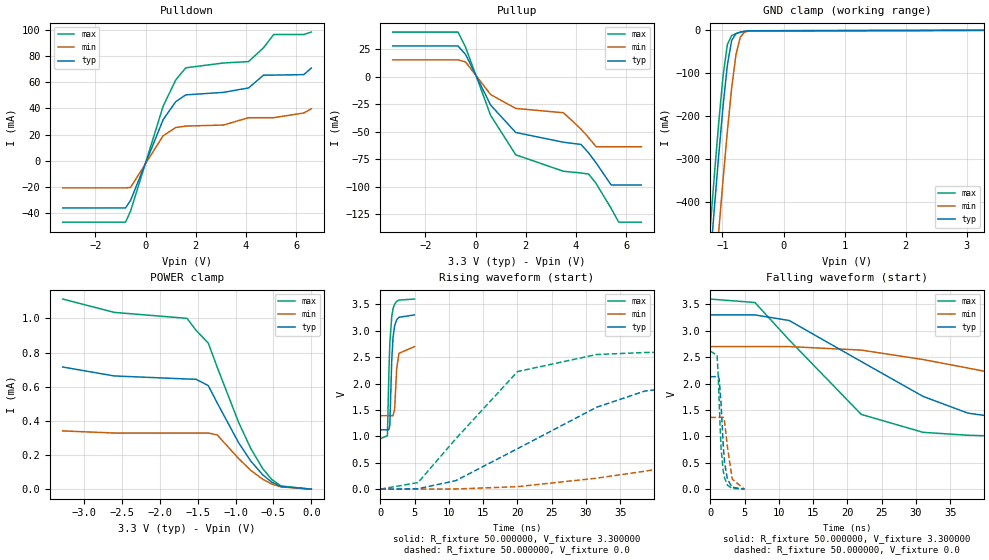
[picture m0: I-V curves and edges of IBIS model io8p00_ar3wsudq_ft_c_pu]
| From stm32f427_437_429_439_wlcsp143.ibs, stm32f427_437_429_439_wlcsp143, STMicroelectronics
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|   Model io8p00_ar3wsudq_ft_c_pu
[Model]  io8p00_ar3wsudq_ft_c_pu
Model_type I/O
Polarity   Non-Inverting
Enable   Active-Low
Vinl =   0.990000V
Vinh =   2.310000V
Vmeas =  1.650000V
Cref =   50.000000pF
Rref =   100.000000M
Vref =   0.0V
C_comp   5.986400pF   5.818600pF   6.191500pF
[Temperature Range]   25.000000   0.125000k   -40.000000
[Pullup Reference]   3.300000V   2.700000V   3.600000V
[Pulldown Reference]   0.0V   0.0V   0.0V
[POWER Clamp Reference]   3.300000V   2.700000V   3.600000V
[GND Clamp Reference]   0.0V   0.0V   0.0V
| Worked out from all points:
|   slope of the pulldown table from 0 to 0.495 V, typ, clamps not added: 20.9 ohm
|   slope of the pullup table from 0 to 0.495 V, typ, clamps not added: 22.6 ohm
|   GND clamp passes 1 mA (typ) near -0.57 V on its own axis
|   rising waveform, R_fixture 50.000000, V_fixture 3.300000: 20-80 % time 369ps typ, 351ps min, 391ps max; typ from 1.12 V to 3.3 V
|   rising waveform, R_fixture 50.000000, V_fixture 0.0: 20-80 % time 19.2ns typ, 45.2ns min, 10.2ns max; typ from 0.001 V to 2.13 V
|   falling waveform, R_fixture 50.000000, V_fixture 3.300000: 20-80 % time 18.2ns typ, 37.1ns min, 11.3ns max; typ from 3.3 V to 1.12 V
|   falling waveform, R_fixture 50.000000, V_fixture 0.0: 20-80 % time 608ps typ, 778ps min, 541ps max; typ from 2.13 V to 0.001 V
[Pulldown]
|Voltage   I(typ)   I(min)   I(max)
-3.3V     -36.18mA   -20.77mA   -47.07mA
-800mV    -36.18mA   -20.77mA   -47.07mA
-600mV    -30.5mA    -20.52mA   -38.69mA
700mV     31.4mA     19.11mA    41.71mA
1.2V      45.15mA    25.37mA    61.75mA
1.6V      50.35mA    26.5mA     71.06mA
3.1V      52.28mA    27.26mA    74.76mA
4.1V      55.65mA    32.89mA    75.79mA
4.7V      65.5mA     32.89mA    86.49mA
5.1V      65.5mA     32.89mA    96.55mA
6.3V      65.83mA    36.49mA    96.55mA
6.6V      70.88mA    39.7mA     98.4mA
[Pullup]
|Voltage   I(typ)   I(min)   I(max)
-3.3V     28mA       15.42mA    40.61mA
-700mV    28mA       15.42mA    40.61mA
-400mV    20.3mA     13.47mA    26.92mA
600mV     -25.77mA   -16.23mA   -35.13mA
1.6V      -50.64mA   -28.8mA    -70.96mA
3.5V      -59.52mA   -32.72mA   -85.91mA
4.2V      -61.52mA   -47.6mA    -87.45mA
4.5V      -69.2mA    -55.3mA    -88.42mA
4.8V      -78.3mA    -63.6mA    -97mA
5.4V      -98.4mA    -63.6mA    -119.7mA
5.7V      -98.4mA    -63.6mA    -132.2mA
6.6V      -98.4mA    -63.6mA    -132.2mA
[GND_clamp]
|Voltage   I(typ)   I(min)   I(max)
-3.3V     -4.643A    -4.801A    -4.591A
-1.2V     -535.6mA   -717.5mA   -459.3mA
-1.13V    -409.9mA   -591mA     -333.1mA
-1.06V    -288.9mA   -467.4mA   -212.9mA
-990mV    -176.2mA   -348mA     -105.7mA
-920mV    -81.01mA   -235.5mA   -32.96mA
-850mV    -23.66mA   -135.1mA   -12.27mA
-780mV    -7.753mA   -57.42mA   -7.762mA
-710mV    -4.185mA   -16.31mA   -4.763mA
-640mV    -2.295mA   -4.401mA   -2.439mA
-570mV    -1.048mA   -1.62mA    -953.6uA
3.28V     0A         0A         0A
[POWER_clamp]
|Voltage   I(typ)   I(min)   I(max)
-3.28V    715.1uA    341uA      1.113mA
-2.6V     662.9uA    328.8uA    1.035mA
-1.64V    645uA      328.8uA    1mA
-1.52V    643.3uA    328.8uA    929.5uA
-1.36V    606.3uA    328.8uA    855.6uA
-1.24V    503.7uA    316.9uA    712.3uA
-960mV    272.5uA    179.5uA    391.9uA
-800mV    165.2uA    110.4uA    239.2uA
-640mV    83.2uA     57.63uA    119.3uA
-520mV    40.52uA    29.88uA    56.09uA
-400mV    15.54uA    13.34uA    18.7uA
0V        0A         0A         0A
[Ramp]
| variable   typ   min   max
dV/dt_r  1.27723/19.17243n   0.81507/45.18225n   1.56682/10.22055n
dV/dt_f  1.30506/18.21905n   0.78378/37.01751n   1.58715/11.28001n
R_load = 50.000000
[Rising Waveform]
R_fixture= 50.000000
V_fixture= 3.300000
V_fixture_min= 2.700000
V_fixture_max= 3.600000
|time   V(typ)   V(min)   V(max)
0s        1.125V     1.393V     954.7mV
1.041ns   1.125V     1.393V     1.015V
1.261ns   1.128V     1.393V     2.234V
1.391ns   1.215V     1.393V     2.76V
1.672ns   2.445V     1.391V     3.268V
1.862ns   2.874V     1.393V     3.42V
2.092ns   3.095V     1.514V     3.504V
2.392ns   3.209V     2.276V     3.556V
2.723ns   3.255V     2.573V     3.581V
4.985ns   3.3V       2.7V       3.6V
[Rising Waveform]
R_fixture= 50.000000
V_fixture= 0.0
V_fixture_min= 0.0
V_fixture_max= 0.0
|time   V(typ)   V(min)   V(max)
0s        1.088mV    1.044mV    1.136mV
5.506ns   9.732mV    2.781mV    125.9mV
11.01ns   162.3mV    4.548mV    955mV
20.02ns   768mV      48.59mV    2.228V
31.53ns   1.551V     208.5mV    2.55V
38.54ns   1.857V     340.6mV    2.588V
48.05ns   2.016V     537.2mV    2.606V
71.07ns   2.11V      971.8mV    2.612V
97.1ns    2.128V     1.227V     2.613V
249.2ns   2.13V      1.36V      2.613V
[Falling Waveform]
R_fixture= 50.000000
V_fixture= 3.300000
V_fixture_min= 2.700000
V_fixture_max= 3.600000
|time   V(typ)   V(min)   V(max)
0s        3.3V       2.7V       3.6V
6.507ns   3.3V       2.7V       3.535V
11.51ns   3.194V     2.7V       2.825V
22.02ns   2.417V     2.634V     1.416V
31.03ns   1.757V     2.455V     1.077V
37.54ns   1.442V     2.295V     1.022V
46.05ns   1.282V     2.077V     989.3mV
63.06ns   1.183V     1.722V     964.8mV
83.08ns   1.146V     1.545V     957.4mV
249.2ns   1.125V     1.393V     954.7mV
[Falling Waveform]
R_fixture= 50.000000
V_fixture= 0.0
V_fixture_min= 0.0
V_fixture_max= 0.0
|time   V(typ)   V(min)   V(max)
0s        2.13V      1.36V      2.613V
991ps     2.131V     1.36V      2.538V
1.181ns   2.133V     1.359V     2.089V
1.301ns   2.085V     1.359V     1.636V
1.572ns   1.624V     1.361V     772.8mV
1.882ns   846.2mV    1.364V     353.2mV
2.082ns   502.4mV    1.282V     217.1mV
2.503ns   186.2mV    797.6mV    76.87mV
3.203ns   37.14mV    189.7mV    14.82mV
4.985ns   1.088mV    1.044mV    1.136mV
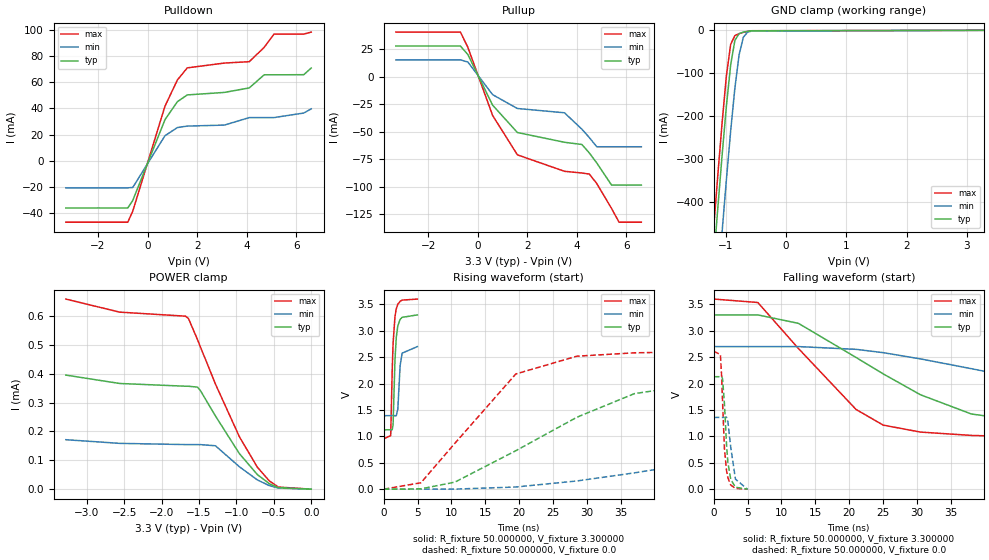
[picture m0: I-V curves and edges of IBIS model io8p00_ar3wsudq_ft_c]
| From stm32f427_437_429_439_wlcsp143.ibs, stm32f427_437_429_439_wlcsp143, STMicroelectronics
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|   Model io8p00_ar3wsudq_ft_c
[Model]  io8p00_ar3wsudq_ft_c
Model_type I/O
Polarity   Non-Inverting
Enable   Active-Low
Vinl =   0.990000V
Vinh =   2.310000V
Vmeas =  1.650000V
Cref =   50.000000pF
Rref =   100.000000M
Vref =   0.0V
C_comp   5.986400pF   5.818600pF   6.191500pF
[Temperature Range]   25.000000   0.125000k   -40.000000
[Pullup Reference]   3.300000V   2.700000V   3.600000V
[Pulldown Reference]   0.0V   0.0V   0.0V
[POWER Clamp Reference]   3.300000V   2.700000V   3.600000V
[GND Clamp Reference]   0.0V   0.0V   0.0V
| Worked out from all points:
|   slope of the pulldown table from 0 to 0.495 V, typ, clamps not added: 20.9 ohm
|   slope of the pullup table from 0 to 0.495 V, typ, clamps not added: 22.6 ohm
|   GND clamp passes 1 mA (typ) near -0.57 V on its own axis
|   rising waveform, R_fixture 50.000000, V_fixture 3.300000: 20-80 % time 371ps typ, 352ps min, 393ps max; typ from 1.12 V to 3.3 V
|   rising waveform, R_fixture 50.000000, V_fixture 0.0: 20-80 % time 19.2ns typ, 45.2ns min, 10.2ns max; typ from 0 V to 2.13 V
|   falling waveform, R_fixture 50.000000, V_fixture 3.300000: 20-80 % time 18.2ns typ, 37ns min, 11.3ns max; typ from 3.3 V to 1.12 V
|   falling waveform, R_fixture 50.000000, V_fixture 0.0: 20-80 % time 609ps typ, 778ps min, 544ps max; typ from 2.13 V to 0 V
[Pulldown]
|Voltage   I(typ)   I(min)   I(max)
-3.3V     -36.18mA   -20.77mA   -47.07mA
-800mV    -36.18mA   -20.77mA   -47.07mA
-600mV    -30.5mA    -20.52mA   -38.69mA
700mV     31.4mA     19.11mA    41.71mA
1.2V      45.15mA    25.37mA    61.75mA
1.6V      50.35mA    26.5mA     71.06mA
3.1V      52.28mA    27.26mA    74.75mA
4.1V      55.71mA    33.01mA    75.8mA
4.7V      65.73mA    33.01mA    86.69mA
5.1V      65.73mA    33.01mA    96.9mA
6.3V      65.85mA    36.5mA     96.9mA
6.6V      70.91mA    39.71mA    98.45mA
[Pullup]
|Voltage   I(typ)   I(min)   I(max)
-3.3V     28.03mA    15.43mA    40.67mA
-700mV    28.03mA    15.43mA    40.67mA
-400mV    20.31mA    13.47mA    26.93mA
600mV     -25.77mA   -16.23mA   -35.14mA
1.6V      -50.64mA   -28.81mA   -70.96mA
3.5V      -59.53mA   -32.72mA   -85.92mA
4.2V      -61.52mA   -47.6mA    -87.46mA
4.5V      -69.2mA    -55.2mA    -88.43mA
4.8V      -78.3mA    -63.6mA    -97.01mA
5.4V      -98.5mA    -63.6mA    -119.8mA
5.7V      -98.5mA    -63.6mA    -132.2mA
6.6V      -98.5mA    -63.6mA    -132.2mA
[GND_clamp]
|Voltage   I(typ)   I(min)   I(max)
-3.3V     -4.643A    -4.801A    -4.591A
-1.2V     -535.6mA   -717.5mA   -459.3mA
-1.13V    -409.9mA   -591mA     -333.1mA
-1.06V    -288.9mA   -467.4mA   -212.9mA
-990mV    -176.2mA   -348mA     -105.7mA
-920mV    -81.01mA   -235.5mA   -32.96mA
-850mV    -23.66mA   -135.1mA   -12.27mA
-780mV    -7.753mA   -57.42mA   -7.762mA
-710mV    -4.185mA   -16.31mA   -4.763mA
-640mV    -2.295mA   -4.401mA   -2.439mA
-570mV    -1.048mA   -1.62mA    -953.6uA
3.28V     0A         0A         0A
[POWER_clamp]
|Voltage   I(typ)   I(min)   I(max)
-3.28V    395.3uA    171.4uA    658.7uA
-2.56V    366.2uA    158.7uA    613.4uA
-1.68V    356.7uA    154.5uA    599.4uA
-1.64V    356.6uA    154.5uA    590.8uA
-1.52V    353.6uA    154.3uA    518.3uA
-1.48V    341.1uA    154.3uA    492.3uA
-1.28V    253.6uA    150.4uA    364.2uA
-960mV    123.1uA    77.62uA    181.6uA
-720mV    50.52uA    32.09uA    76.18uA
-560mV    18.94uA    12.32uA    28.65uA
-440mV    5.105uA    3.74uA     7.327uA
0V        0A         0A         0A
[Ramp]
| variable   typ   min   max
dV/dt_r  1.27752/19.15627n   0.81516/45.15472n   1.56726/10.21029n
dV/dt_f  1.30584/18.21091n   0.78456/37.02258n   1.58791/11.27038n
R_load = 50.000000
[Rising Waveform]
R_fixture= 50.000000
V_fixture= 3.300000
V_fixture_min= 2.700000
V_fixture_max= 3.600000
|time   V(typ)   V(min)   V(max)
0s        1.124V     1.392V     953.5mV
1.041ns   1.124V     1.392V     1.014V
1.261ns   1.126V     1.392V     2.231V
1.391ns   1.214V     1.392V     2.756V
1.672ns   2.442V     1.39V      3.265V
1.862ns   2.871V     1.391V     3.416V
2.092ns   3.093V     1.512V     3.502V
2.432ns   3.215V     2.34V      3.558V
2.733ns   3.254V     2.576V     3.58V
4.985ns   3.3V       2.7V       3.6V
[Rising Waveform]
R_fixture= 50.000000
V_fixture= 0.0
V_fixture_min= 0.0
V_fixture_max= 0.0
|time   V(typ)   V(min)   V(max)
0s        11.41nV    571.6nV    7.475nV
5.506ns   5.681mV    -141uV     121.1mV
10.51ns   132.6mV    750.4uV    866.8mV
19.52ns   727.8mV    40.87mV    2.181V
28.53ns   1.361V     155.1mV    2.518V
37.04ns   1.809V     308.6mV    2.582V
47.55ns   2.01V      524.2mV    2.605V
71.07ns   2.11V      970mV      2.612V
98.6ns    2.127V     1.235V     2.612V
249.2ns   2.129V     1.359V     2.612V
[Falling Waveform]
R_fixture= 50.000000
V_fixture= 3.300000
V_fixture_min= 2.700000
V_fixture_max= 3.600000
|time   V(typ)   V(min)   V(max)
0s        3.3V       2.7V       3.6V
6.507ns   3.3V       2.7V       3.535V
12.51ns   3.14V      2.7V       2.663V
21.02ns   2.494V     2.648V     1.509V
25.03ns   2.183V     2.585V     1.213V
30.53ns   1.788V     2.467V     1.081V
38.04ns   1.424V     2.282V     1.018V
46.05ns   1.281V     2.077V     988mV
83.08ns   1.144V     1.544V     956.2mV
249.2ns   1.124V     1.392V     953.5mV
[Falling Waveform]
R_fixture= 50.000000
V_fixture= 0.0
V_fixture_min= 0.0
V_fixture_max= 0.0
|time   V(typ)   V(min)   V(max)
0s        2.129V     1.359V     2.612V
981ps     2.13V      1.359V     2.549V
1.181ns   2.133V     1.358V     2.09V
1.301ns   2.085V     1.358V     1.639V
1.572ns   1.624V     1.36V      775.4mV
1.882ns   847.3mV    1.363V     355.3mV
2.082ns   503.4mV    1.281V     218.8mV
2.503ns   186.9mV    797.6mV    77.75mV
3.203ns   37.1mV     189.1mV    14.76mV
4.985ns   11.41nV    571.6nV    7.475nV
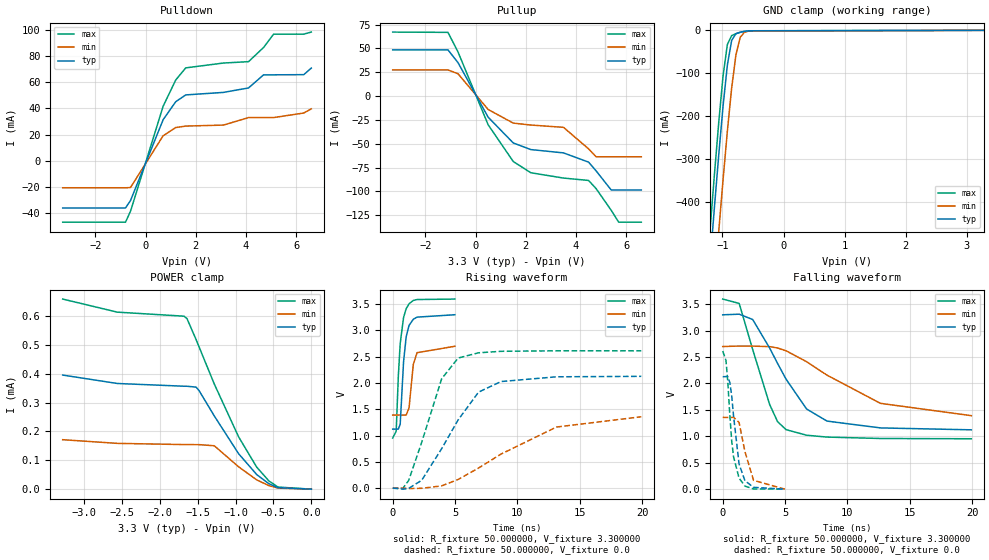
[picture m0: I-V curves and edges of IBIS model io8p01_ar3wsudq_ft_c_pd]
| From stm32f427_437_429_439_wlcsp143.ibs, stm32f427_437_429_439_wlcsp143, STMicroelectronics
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|   Model io8p01_ar3wsudq_ft_c_pd
[Model]  io8p01_ar3wsudq_ft_c_pd
Model_type I/O
Polarity   Non-Inverting
Enable   Active-Low
Vinl =   0.990000V
Vinh =   2.310000V
Vmeas =  1.650000V
Cref =   50.000000pF
Rref =   100.000000M
Vref =   0.0V
C_comp   5.986400pF   5.818600pF   6.191500pF
[Temperature Range]   25.000000   0.125000k   -40.000000
[Pullup Reference]   3.300000V   2.700000V   3.600000V
[Pulldown Reference]   0.0V   0.0V   0.0V
[POWER Clamp Reference]   3.300000V   2.700000V   3.600000V
[GND Clamp Reference]   0.0V   0.0V   0.0V
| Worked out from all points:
|   slope of the pulldown table from 0 to 0.495 V, typ, clamps not added: 20.9 ohm
|   slope of the pullup table from 0 to 0.495 V, typ, clamps not added: 22.6 ohm
|   GND clamp passes 1 mA (typ) near -0.56 V on its own axis
|   rising waveform, R_fixture 50.000000, V_fixture 3.300000: 20-80 % time 372ps typ, 353ps min, 396ps max; typ from 1.12 V to 3.3 V
|   rising waveform, R_fixture 50.000000, V_fixture 0.0: 20-80 % time 3.26ns typ, 6.14ns min, 2.07ns max; typ from 0 V to 2.13 V
|   falling waveform, R_fixture 50.000000, V_fixture 3.300000: 20-80 % time 3.24ns typ, 5.73ns min, 2.04ns max; typ from 3.3 V to 1.12 V
|   falling waveform, R_fixture 50.000000, V_fixture 0.0: 20-80 % time 610ps typ, 780ps min, 544ps max; typ from 2.13 V to 0 V
[Pulldown]
|Voltage   I(typ)   I(min)   I(max)
-3.3V     -36.18mA   -20.77mA   -47.07mA
-800mV    -36.18mA   -20.77mA   -47.07mA
-600mV    -30.5mA    -20.52mA   -38.69mA
700mV     31.4mA     19.11mA    41.71mA
1.2V      45.15mA    25.37mA    61.75mA
1.6V      50.35mA    26.5mA     71.06mA
3.1V      52.27mA    27.26mA    74.75mA
4.1V      55.7mA     33.01mA    75.8mA
4.7V      65.73mA    33.01mA    86.69mA
5.1V      65.73mA    33.01mA    96.89mA
6.3V      65.85mA    36.49mA    96.89mA
6.6V      70.9mA     39.7mA     98.44mA
[Pullup]
|Voltage   I(typ)   I(min)   I(max)
-3.3V     48.54mA    27.45mA    67.15mA
-1.1V     48.54mA    27.45mA    66.87mA
-700mV    35.13mA    23.48mA    46.33mA
500mV     -22.07mA   -14mA      -30.03mA
1.5V      -49.1mA    -28.3mA    -68.56mA
2.2V      -56.04mA   -30.32mA   -80.35mA
3.5V      -59.53mA   -32.72mA   -85.92mA
4.5V      -69.21mA   -55.3mA    -88.43mA
4.8V      -78.4mA    -63.6mA    -97.01mA
5.4V      -98.4mA    -63.6mA    -119.7mA
5.7V      -98.4mA    -63.6mA    -132.2mA
6.6V      -98.4mA    -63.6mA    -132.2mA
[GND_clamp]
|Voltage   I(typ)   I(min)   I(max)
-3.3V     -4.64A     -4.798A    -4.587A
-1.2V     -535.6mA   -717.5mA   -459.3mA
-1.13V    -409.9mA   -591mA     -333.1mA
-1.06V    -288.9mA   -467.4mA   -212.9mA
-990mV    -176.2mA   -348mA     -105.7mA
-920mV    -81.01mA   -235.5mA   -32.97mA
-850mV    -23.67mA   -135.1mA   -12.28mA
-780mV    -7.764mA   -57.43mA   -7.776mA
-710mV    -4.197mA   -16.31mA   -4.777mA
-640mV    -2.307mA   -4.41mA    -2.453mA
-570mV    -1.059mA   -1.629mA   -967uA
3.28V     81.28uA    57.87uA    93.98uA
[POWER_clamp]
|Voltage   I(typ)   I(min)   I(max)
-3.28V    395.3uA    171.4uA    658.7uA
-2.56V    366.2uA    158.7uA    613.4uA
-1.68V    356.7uA    154.5uA    599.4uA
-1.64V    356.6uA    154.5uA    590.8uA
-1.52V    353.6uA    154.3uA    518.3uA
-1.48V    341.1uA    154.3uA    492.3uA
-1.28V    253.6uA    150.4uA    364.2uA
-960mV    123.1uA    77.62uA    181.6uA
-720mV    50.52uA    32.09uA    76.18uA
-560mV    18.94uA    12.32uA    28.65uA
-440mV    5.105uA    3.74uA     7.327uA
0V        0A         0A         0A
[Ramp]
| variable   typ   min   max
dV/dt_r  1.27668/3.25905n   0.79650/6.09934n   1.56648/2.07059n
dV/dt_f  1.30176/3.22887n   0.73860/5.65160n   1.58724/2.03217n
R_load = 50.000000
[Rising Waveform]
R_fixture= 50.000000
V_fixture= 3.300000
V_fixture_min= 2.700000
V_fixture_max= 3.600000
|time   V(typ)   V(min)   V(max)
0s        1.123V     1.391V     953.8mV
280.3ps   1.123V     1.391V     1.083V
450.5ps   1.123V     1.391V     2.127V
600.6ps   1.214V     1.391V     2.752V
870.9ps   2.404V     1.389V     3.247V
1.081ns   2.882V     1.391V     3.415V
1.311ns   3.095V     1.527V     3.507V
1.652ns   3.213V     2.353V     3.571V
1.952ns   3.253V     2.577V     3.588V
4.985ns   3.299V     2.699V     3.597V
[Rising Waveform]
R_fixture= 50.000000
V_fixture= 0.0
V_fixture_min= 0.0
V_fixture_max= 0.0
|time   V(typ)   V(min)   V(max)
0s        312.9uV    185uV      1.351mV
840.8ps   -19.44mV   612.2uV    5.36mV
1.281ns   -4.756mV   -7.752mV   146.3mV
2.322ns   148.6mV    -2.834mV   868.6mV
3.924ns   749.8mV    43.08mV    2.08V
5.245ns   1.297V     164.7mV    2.475V
6.887ns   1.827V     382.4mV    2.575V
8.689ns   2.028V     648.3mV    2.603V
13.13ns   2.118V     1.162V     2.613V
19.94ns   2.127V     1.358V     2.613V
[Falling Waveform]
R_fixture= 50.000000
V_fixture= 3.300000
V_fixture_min= 2.700000
V_fixture_max= 3.600000
|time   V(typ)   V(min)   V(max)
0s        3.299V     2.699V     3.597V
1.321ns   3.311V     2.708V     3.515V
2.402ns   3.211V     2.707V     2.644V
3.764ns   2.67V      2.697V     1.603V
4.404ns   2.378V     2.671V     1.276V
5.085ns   2.08V      2.618V     1.126V
6.727ns   1.517V     2.412V     1.021V
8.368ns   1.288V     2.157V     985.6mV
12.65ns   1.159V     1.624V     959mV
19.94ns   1.123V     1.391V     953.8mV
[Falling Waveform]
R_fixture= 50.000000
V_fixture= 0.0
V_fixture_min= 0.0
V_fixture_max= 0.0
|time   V(typ)   V(min)   V(max)
0s        2.127V     1.358V     2.613V
260.3ps   2.13V      1.357V     2.437V
400.4ps   2.13V      1.357V     2.059V
570.6ps   2.02V      1.357V     1.403V
720.7ps   1.767V     1.358V     915.4mV
870.9ps   1.383V     1.361V     611.9mV
1.311ns   478.4mV    1.263V     210mV
1.782ns   160.5mV    711.8mV    58.51mV
2.472ns   34.39mV    167.6mV    4.261mV
4.985ns   312.9uV    185uV      1.351mV
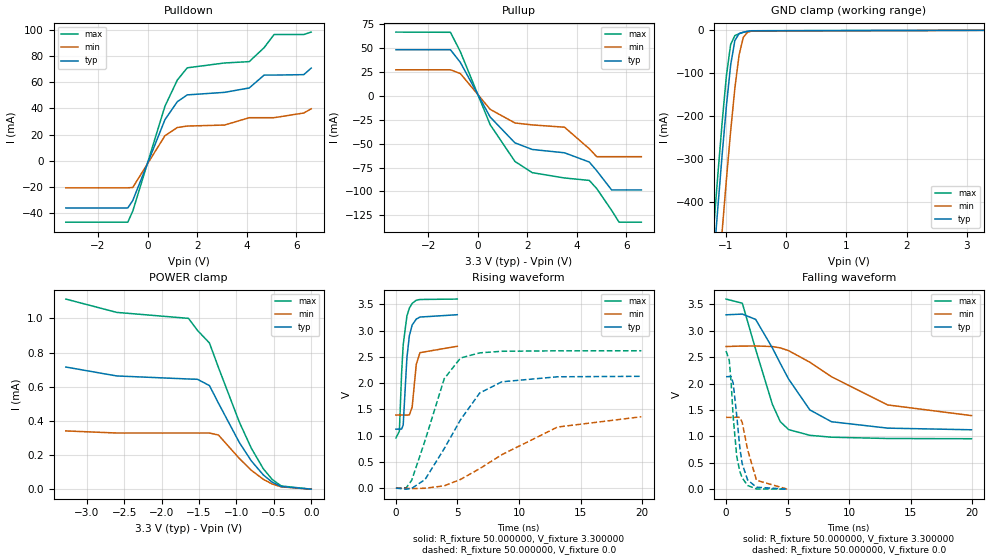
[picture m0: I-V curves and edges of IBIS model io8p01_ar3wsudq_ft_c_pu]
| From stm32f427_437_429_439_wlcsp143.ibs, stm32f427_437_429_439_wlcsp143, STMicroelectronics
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|   Model io8p01_ar3wsudq_ft_c_pu
[Model]  io8p01_ar3wsudq_ft_c_pu
Model_type I/O
Polarity   Non-Inverting
Enable   Active-Low
Vinl =   0.990000V
Vinh =   2.310000V
Vmeas =  1.650000V
Cref =   50.000000pF
Rref =   100.000000M
Vref =   0.0V
C_comp   5.986400pF   5.818600pF   6.191500pF
[Temperature Range]   25.000000   0.125000k   -40.000000
[Pullup Reference]   3.300000V   2.700000V   3.600000V
[Pulldown Reference]   0.0V   0.0V   0.0V
[POWER Clamp Reference]   3.300000V   2.700000V   3.600000V
[GND Clamp Reference]   0.0V   0.0V   0.0V
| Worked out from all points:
|   slope of the pulldown table from 0 to 0.495 V, typ, clamps not added: 20.9 ohm
|   slope of the pullup table from 0 to 0.495 V, typ, clamps not added: 22.6 ohm
|   GND clamp passes 1 mA (typ) near -0.57 V on its own axis
|   rising waveform, R_fixture 50.000000, V_fixture 3.300000: 20-80 % time 371ps typ, 352ps min, 393ps max; typ from 1.12 V to 3.3 V
|   rising waveform, R_fixture 50.000000, V_fixture 0.0: 20-80 % time 3.27ns typ, 6.15ns min, 2.07ns max; typ from 0.001 V to 2.13 V
|   falling waveform, R_fixture 50.000000, V_fixture 3.300000: 20-80 % time 3.23ns typ, 5.71ns min, 2.03ns max; typ from 3.3 V to 1.12 V
|   falling waveform, R_fixture 50.000000, V_fixture 0.0: 20-80 % time 612ps typ, 781ps min, 546ps max; typ from 2.13 V to 0.001 V
[Pulldown]
|Voltage   I(typ)   I(min)   I(max)
-3.3V     -36.18mA   -20.77mA   -47.07mA
-800mV    -36.18mA   -20.77mA   -47.07mA
-600mV    -30.5mA    -20.52mA   -38.69mA
700mV     31.4mA     19.11mA    41.71mA
1.2V      45.15mA    25.37mA    61.75mA
1.6V      50.35mA    26.5mA     71.06mA
3.1V      52.28mA    27.26mA    74.76mA
4.1V      55.65mA    32.89mA    75.79mA
4.7V      65.5mA     32.89mA    86.49mA
5.1V      65.5mA     32.89mA    96.55mA
6.3V      65.83mA    36.49mA    96.55mA
6.6V      70.88mA    39.7mA     98.4mA
[Pullup]
|Voltage   I(typ)   I(min)   I(max)
-3.3V     48.39mA    27.39mA    66.88mA
-1.1V     48.39mA    27.39mA    66.66mA
-700mV    35.09mA    23.45mA    46.27mA
500mV     -22.06mA   -14mA      -30.03mA
1.5V      -49.1mA    -28.3mA    -68.56mA
2.2V      -56.04mA   -30.32mA   -80.35mA
3.5V      -59.52mA   -32.72mA   -85.91mA
4.5V      -69.2mA    -55.3mA    -88.42mA
4.8V      -78.3mA    -63.6mA    -97mA
5.4V      -98.4mA    -63.6mA    -119.8mA
5.7V      -98.4mA    -63.6mA    -132.2mA
6.6V      -98.4mA    -63.6mA    -132.2mA
[GND_clamp]
|Voltage   I(typ)   I(min)   I(max)
-3.3V     -4.641A    -4.8A      -4.589A
-1.2V     -535.6mA   -717.5mA   -459.3mA
-1.13V    -409.9mA   -591mA     -333.1mA
-1.06V    -288.9mA   -467.4mA   -212.9mA
-990mV    -176.2mA   -348mA     -105.7mA
-920mV    -81.01mA   -235.5mA   -32.96mA
-850mV    -23.66mA   -135.1mA   -12.27mA
-780mV    -7.753mA   -57.42mA   -7.762mA
-710mV    -4.185mA   -16.31mA   -4.763mA
-640mV    -2.295mA   -4.401mA   -2.439mA
-570mV    -1.048mA   -1.62mA    -953.6uA
3.28V     0A         0A         0A
[POWER_clamp]
|Voltage   I(typ)   I(min)   I(max)
-3.28V    715.1uA    341uA      1.113mA
-2.6V     662.9uA    328.8uA    1.035mA
-1.64V    645uA      328.8uA    1mA
-1.52V    643.3uA    328.8uA    929.5uA
-1.36V    606.3uA    328.8uA    855.6uA
-1.24V    503.7uA    316.9uA    712.3uA
-960mV    272.5uA    179.5uA    391.9uA
-800mV    165.2uA    110.4uA    239.2uA
-640mV    83.2uA     57.63uA    119.3uA
-520mV    40.52uA    29.88uA    56.09uA
-400mV    15.54uA    13.34uA    18.7uA
0V        0A         0A         0A
[Ramp]
| variable   typ   min   max
dV/dt_r  1.27711/3.26263n   0.79713/6.10702n   1.56682/2.07286n
dV/dt_f  1.30128/3.22846n   0.73764/5.63163n   1.58694/2.03143n
R_load = 50.000000
[Rising Waveform]
R_fixture= 50.000000
V_fixture= 3.300000
V_fixture_min= 2.700000
V_fixture_max= 3.600000
|time   V(typ)   V(min)   V(max)
0s        1.125V     1.393V     955.5mV
280.3ps   1.125V     1.393V     1.085V
460.5ps   1.126V     1.393V     2.183V
590.6ps   1.201V     1.393V     2.727V
890.9ps   2.478V     1.391V     3.274V
1.091ns   2.9V       1.395V     3.425V
1.321ns   3.105V     1.546V     3.516V
1.652ns   3.217V     2.355V     3.576V
1.952ns   3.256V     2.579V     3.59V
4.985ns   3.3V       2.7V       3.598V
[Rising Waveform]
R_fixture= 50.000000
V_fixture= 0.0
V_fixture_min= 0.0
V_fixture_max= 0.0
|time   V(typ)   V(min)   V(max)
0s        1.401mV    1.228mV    2.485mV
840.8ps   -17.07mV   1.653mV    9.912mV
1.281ns   -1.173mV   -6.63mV    151.7mV
2.362ns   164.5mV    269.5uV    904.1mV
3.924ns   753.6mV    46.2mV     2.083V
5.245ns   1.301V     167.8mV    2.477V
6.807ns   1.812V     373.6mV    2.575V
8.609ns   2.025V     639.3mV    2.605V
13.13ns   2.12V      1.164V     2.614V
19.94ns   2.129V     1.36V      2.615V
[Falling Waveform]
R_fixture= 50.000000
V_fixture= 3.300000
V_fixture_min= 2.700000
V_fixture_max= 3.600000
|time   V(typ)   V(min)   V(max)
0s        3.3V       2.7V       3.598V
1.321ns   3.314V     2.709V     3.52V
2.402ns   3.214V     2.71V      2.648V
3.764ns   2.674V     2.7V       1.607V
4.404ns   2.382V     2.674V     1.279V
5.085ns   2.084V     2.621V     1.128V
6.807ns   1.501V     2.403V     1.02V
8.569ns   1.277V     2.128V     984.2mV
13.13ns   1.156V     1.595V     959.9mV
19.94ns   1.125V     1.393V     955.5mV
[Falling Waveform]
R_fixture= 50.000000
V_fixture= 0.0
V_fixture_min= 0.0
V_fixture_max= 0.0
|time   V(typ)   V(min)   V(max)
0s        2.129V     1.36V      2.615V
260.3ps   2.132V     1.36V      2.439V
410.4ps   2.13V      1.359V     2.027V
580.6ps   2.008V     1.359V     1.367V
870.9ps   1.385V     1.363V     615.1mV
1.121ns   785.4mV    1.359V     335.3mV
1.311ns   481.2mV    1.265V     214.3mV
1.752ns   175.2mV    748.4mV    70.45mV
2.472ns   38.18mV    169.2mV    6.01mV
4.985ns   1.401mV    1.228mV    2.485mV
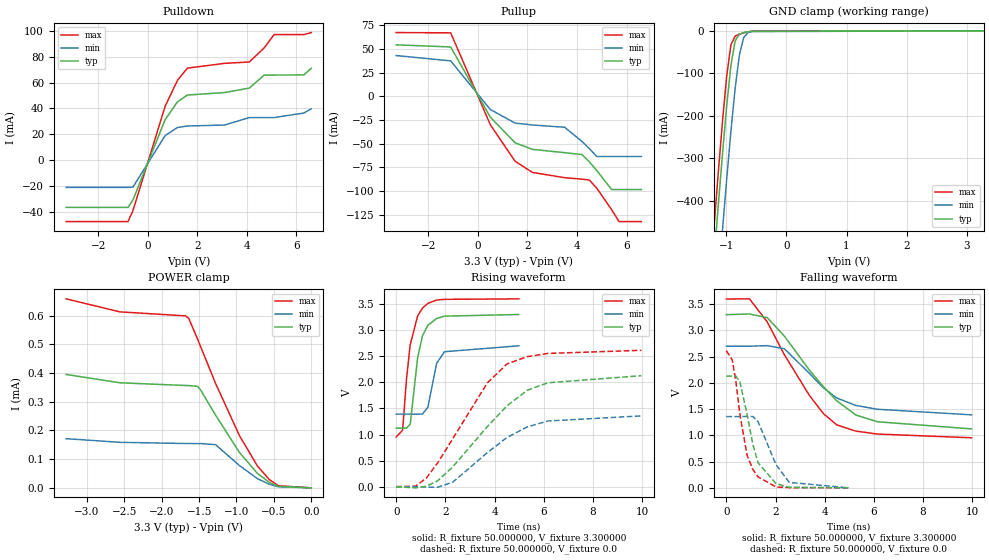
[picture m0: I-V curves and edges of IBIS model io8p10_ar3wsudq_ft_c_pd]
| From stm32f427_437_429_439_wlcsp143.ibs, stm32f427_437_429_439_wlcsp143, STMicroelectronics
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|   Model io8p10_ar3wsudq_ft_c_pd
[Model]  io8p10_ar3wsudq_ft_c_pd
Model_type I/O
Polarity   Non-Inverting
Enable   Active-Low
Vinl =   0.990000V
Vinh =   2.310000V
Vmeas =  1.650000V
Cref =   40.000000pF
Rref =   100.000000M
Vref =   0.0V
C_comp   5.986400pF   5.818600pF   6.191500pF
[Temperature Range]   25.000000   0.125000k   -40.000000
[Pullup Reference]   3.300000V   2.700000V   3.600000V
[Pulldown Reference]   0.0V   0.0V   0.0V
[POWER Clamp Reference]   3.300000V   2.700000V   3.600000V
[GND Clamp Reference]   0.0V   0.0V   0.0V
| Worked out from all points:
|   slope of the pulldown table from 0 to 0.495 V, typ, clamps not added: 20.9 ohm
|   slope of the pullup table from 0 to 0.495 V, typ, clamps not added: 22.6 ohm
|   GND clamp passes 1 mA (typ) near -0.56 V on its own axis
|   rising waveform, R_fixture 50.000000, V_fixture 3.300000: 20-80 % time 373ps typ, 357ps min, 396ps max; typ from 1.12 V to 3.3 V
|   rising waveform, R_fixture 50.000000, V_fixture 0.0: 20-80 % time 2.49ns typ, 2.21ns min, 2.1ns max; typ from 0 V to 2.13 V
|   falling waveform, R_fixture 50.000000, V_fixture 3.300000: 20-80 % time 2.31ns typ, 1.87ns min, 2.05ns max; typ from 3.3 V to 1.12 V
|   falling waveform, R_fixture 50.000000, V_fixture 0.0: 20-80 % time 610ps typ, 773ps min, 544ps max; typ from 2.13 V to 0 V
[Pulldown]
|Voltage   I(typ)   I(min)   I(max)
-3.3V     -36.18mA   -20.77mA   -47.07mA
-800mV    -36.18mA   -20.77mA   -47.07mA
-600mV    -30.5mA    -20.52mA   -38.69mA
700mV     31.4mA     19.11mA    41.71mA
1.2V      45.15mA    25.37mA    61.75mA
1.6V      50.35mA    26.5mA     71.06mA
3.1V      52.27mA    27.26mA    74.75mA
4.1V      55.7mA     33.01mA    75.8mA
4.7V      65.73mA    33.01mA    86.69mA
5.1V      65.73mA    33.01mA    96.89mA
6.3V      65.85mA    36.49mA    96.89mA
6.6V      70.9mA     39.7mA     98.44mA
[Pullup]
|Voltage   I(typ)   I(min)   I(max)
-3.3V     54.22mA    42.91mA    67.15mA
-1.1V     51.98mA    37.3mA     66.87mA
500mV     -22.07mA   -14mA      -30.03mA
1.5V      -49.1mA    -28.3mA    -68.56mA
2.2V      -56.04mA   -30.32mA   -80.35mA
3.5V      -59.53mA   -32.72mA   -85.92mA
4.2V      -61.52mA   -47.6mA    -87.46mA
4.5V      -69.21mA   -55.3mA    -88.43mA
4.8V      -78.4mA    -63.6mA    -97.01mA
5.4V      -98.4mA    -63.6mA    -119.7mA
5.7V      -98.4mA    -63.6mA    -132.2mA
6.6V      -98.4mA    -63.6mA    -132.2mA
[GND_clamp]
|Voltage   I(typ)   I(min)   I(max)
-3.3V     -4.64A     -4.798A    -4.587A
-1.2V     -535.6mA   -717.5mA   -459.3mA
-1.13V    -409.9mA   -591mA     -333.1mA
-1.06V    -288.9mA   -467.4mA   -212.9mA
-990mV    -176.2mA   -348mA     -105.7mA
-920mV    -81.01mA   -235.5mA   -32.97mA
-850mV    -23.67mA   -135.1mA   -12.28mA
-780mV    -7.764mA   -57.43mA   -7.776mA
-710mV    -4.197mA   -16.31mA   -4.777mA
-640mV    -2.307mA   -4.41mA    -2.453mA
-570mV    -1.059mA   -1.629mA   -967uA
3.28V     81.28uA    57.87uA    93.98uA
[POWER_clamp]
|Voltage   I(typ)   I(min)   I(max)
-3.28V    395.3uA    171.4uA    658.7uA
-2.56V    366.2uA    158.7uA    613.4uA
-1.68V    356.7uA    154.5uA    599.4uA
-1.64V    356.6uA    154.5uA    590.8uA
-1.52V    353.6uA    154.3uA    518.3uA
-1.48V    341.1uA    154.3uA    492.3uA
-1.28V    253.6uA    150.4uA    364.2uA
-960mV    123.1uA    77.62uA    181.6uA
-720mV    50.52uA    32.09uA    76.18uA
-560mV    18.94uA    12.32uA    28.65uA
-440mV    5.105uA    3.74uA     7.327uA
0V        0A         0A         0A
[Ramp]
| variable   typ   min   max
dV/dt_r  1.26558/2.47141n   0.80916/2.19314n   1.56264/2.09239n
dV/dt_f  1.28178/2.29139n   0.77406/1.84706n   1.57402/2.04333n
R_load = 50.000000
[Rising Waveform]
R_fixture= 50.000000
V_fixture= 3.300000
V_fixture_min= 2.700000
V_fixture_max= 3.600000
|time   V(typ)   V(min)   V(max)
0s        1.123V     1.391V     953.8mV
260.3ps   1.123V     1.391V     1.083V
420.4ps   1.122V     1.391V     2.076V
570.6ps   1.198V     1.391V     2.722V
870.9ps   2.473V     1.388V     3.27V
1.071ns   2.895V     1.393V     3.422V
1.291ns   3.094V     1.527V     3.513V
1.642ns   3.222V     2.363V     3.575V
1.962ns   3.267V     2.586V     3.589V
4.985ns   3.299V     2.699V     3.598V
[Rising Waveform]
R_fixture= 50.000000
V_fixture= 0.0
V_fixture_min= 0.0
V_fixture_max= 0.0
|time   V(typ)   V(min)   V(max)
0s        322.2uV    176.5uV    1.509mV
780.8ps   -21.06mV   554.8uV    9.834mV
1.221ns   7.978mV    -7.78mV    162.9mV
1.682ns   111.6mV    -10.02mV   454.6mV
2.302ns   382.1mV    88.1mV     921.9mV
3.704ns   1.152V     651.9mV    1.987V
4.505ns   1.549V     943.8mV    2.353V
5.325ns   1.847V     1.146V     2.491V
6.166ns   1.991V     1.259V     2.553V
9.97ns    2.127V     1.357V     2.613V
[Falling Waveform]
R_fixture= 50.000000
V_fixture= 3.300000
V_fixture_min= 2.700000
V_fixture_max= 3.600000
|time   V(typ)   V(min)   V(max)
0s        3.299V     2.699V     3.598V
940.9ps   3.312V     2.698V     3.6V
1.662ns   3.243V     2.709V     3.162V
2.362ns   2.89V      2.65V      2.534V
3.383ns   2.239V     2.177V     1.757V
3.944ns   1.93V      1.906V     1.416V
4.484ns   1.661V     1.714V     1.202V
5.265ns   1.388V     1.57V      1.081V
6.146ns   1.259V     1.497V     1.025V
9.97ns    1.123V     1.391V     953.8mV
[Falling Waveform]
R_fixture= 50.000000
V_fixture= 0.0
V_fixture_min= 0.0
V_fixture_max= 0.0
|time   V(typ)   V(min)   V(max)
0s        2.127V     1.357V     2.613V
240.2ps   2.13V      1.357V     2.437V
390.4ps   2.128V     1.357V     2.026V
550.6ps   2.02V      1.357V     1.403V
840.8ps   1.409V     1.361V     628mV
1.081ns   824.1mV    1.359V     348mV
1.291ns   478.6mV    1.261V     210mV
2.022ns   79.8mV     440mV      16.12mV
2.563ns   11.61mV    104mV      3.623mV
4.985ns   322.2uV    176.5uV    1.509mV
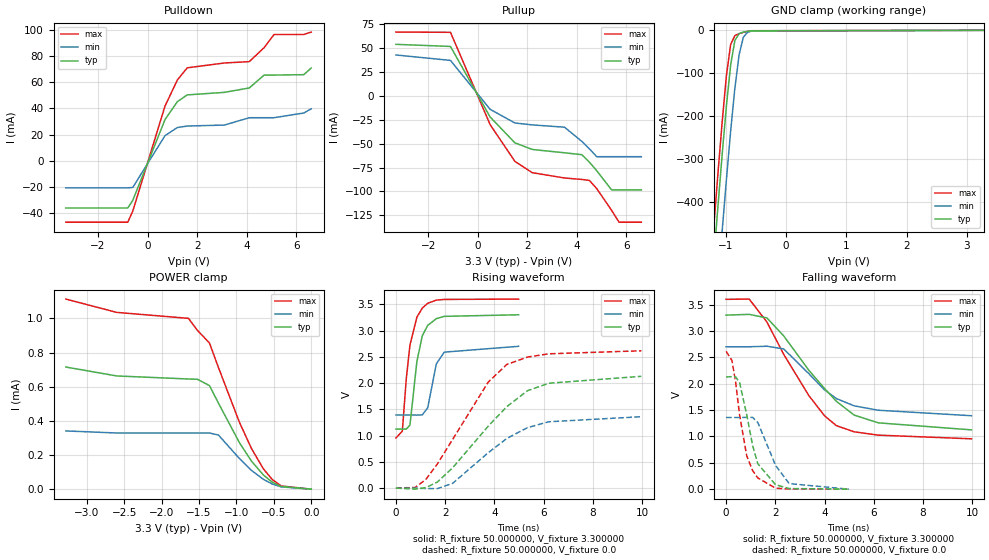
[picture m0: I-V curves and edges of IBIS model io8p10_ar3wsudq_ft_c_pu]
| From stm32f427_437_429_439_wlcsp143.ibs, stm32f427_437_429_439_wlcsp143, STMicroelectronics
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|   Model io8p10_ar3wsudq_ft_c_pu
[Model]  io8p10_ar3wsudq_ft_c_pu
Model_type I/O
Polarity   Non-Inverting
Enable   Active-Low
Vinl =   0.990000V
Vinh =   2.310000V
Vmeas =  1.650000V
Cref =   40.000000pF
Rref =   100.000000M
Vref =   0.0V
C_comp   5.986400pF   5.818600pF   6.191500pF
[Temperature Range]   25.000000   0.125000k   -40.000000
[Pullup Reference]   3.300000V   2.700000V   3.600000V
[Pulldown Reference]   0.0V   0.0V   0.0V
[POWER Clamp Reference]   3.300000V   2.700000V   3.600000V
[GND Clamp Reference]   0.0V   0.0V   0.0V
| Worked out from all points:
|   slope of the pulldown table from 0 to 0.495 V, typ, clamps not added: 20.9 ohm
|   slope of the pullup table from 0 to 0.495 V, typ, clamps not added: 22.6 ohm
|   GND clamp passes 1 mA (typ) near -0.57 V on its own axis
|   rising waveform, R_fixture 50.000000, V_fixture 3.300000: 20-80 % time 371ps typ, 355ps min, 394ps max; typ from 1.12 V to 3.3 V
|   rising waveform, R_fixture 50.000000, V_fixture 0.0: 20-80 % time 2.49ns typ, 2.21ns min, 2.1ns max; typ from 0.001 V to 2.13 V
|   falling waveform, R_fixture 50.000000, V_fixture 3.300000: 20-80 % time 2.31ns typ, 1.88ns min, 2.05ns max; typ from 3.3 V to 1.12 V
|   falling waveform, R_fixture 50.000000, V_fixture 0.0: 20-80 % time 612ps typ, 775ps min, 546ps max; typ from 2.13 V to 0.001 V
[Pulldown]
|Voltage   I(typ)   I(min)   I(max)
-3.3V     -36.18mA   -20.77mA   -47.07mA
-800mV    -36.18mA   -20.77mA   -47.07mA
-600mV    -30.5mA    -20.52mA   -38.69mA
700mV     31.4mA     19.11mA    41.71mA
1.2V      45.15mA    25.37mA    61.75mA
1.6V      50.35mA    26.5mA     71.06mA
3.1V      52.28mA    27.26mA    74.76mA
4.1V      55.65mA    32.89mA    75.79mA
4.7V      65.5mA     32.89mA    86.49mA
5.1V      65.5mA     32.89mA    96.55mA
6.3V      65.83mA    36.49mA    96.55mA
6.6V      70.88mA    39.7mA     98.4mA
[Pullup]
|Voltage   I(typ)   I(min)   I(max)
-3.3V     54.05mA    42.9mA     66.88mA
-1.1V     51.84mA    37.22mA    66.66mA
500mV     -22.06mA   -14mA      -30.03mA
1.5V      -49.1mA    -28.3mA    -68.56mA
2.2V      -56.04mA   -30.32mA   -80.35mA
3.5V      -59.52mA   -32.72mA   -85.91mA
4.2V      -61.52mA   -47.6mA    -87.45mA
4.5V      -69.2mA    -55.3mA    -88.42mA
4.8V      -78.3mA    -63.6mA    -97mA
5.4V      -98.4mA    -63.6mA    -119.8mA
5.7V      -98.4mA    -63.6mA    -132.2mA
6.6V      -98.4mA    -63.6mA    -132.2mA
[GND_clamp]
|Voltage   I(typ)   I(min)   I(max)
-3.3V     -4.641A    -4.8A      -4.589A
-1.2V     -535.6mA   -717.5mA   -459.3mA
-1.13V    -409.9mA   -591mA     -333.1mA
-1.06V    -288.9mA   -467.4mA   -212.9mA
-990mV    -176.2mA   -348mA     -105.7mA
-920mV    -81.01mA   -235.5mA   -32.96mA
-850mV    -23.66mA   -135.1mA   -12.27mA
-780mV    -7.753mA   -57.42mA   -7.762mA
-710mV    -4.185mA   -16.31mA   -4.763mA
-640mV    -2.295mA   -4.401mA   -2.439mA
-570mV    -1.048mA   -1.62mA    -953.6uA
3.28V     0A         0A         0A
[POWER_clamp]
|Voltage   I(typ)   I(min)   I(max)
-3.28V    715.1uA    341uA      1.113mA
-2.6V     662.9uA    328.8uA    1.035mA
-1.64V    645uA      328.8uA    1mA
-1.52V    643.3uA    328.8uA    929.5uA
-1.36V    606.3uA    328.8uA    855.6uA
-1.24V    503.7uA    316.9uA    712.3uA
-960mV    272.5uA    179.5uA    391.9uA
-800mV    165.2uA    110.4uA    239.2uA
-640mV    83.2uA     57.63uA    119.3uA
-520mV    40.52uA    29.88uA    56.09uA
-400mV    15.54uA    13.34uA    18.7uA
0V        0A         0A         0A
[Ramp]
| variable   typ   min   max
dV/dt_r  1.26607/2.47492n   0.80979/2.19793n   1.56298/2.09463n
dV/dt_f  1.28130/2.29096n   0.77316/1.85282n   1.57370/2.04261n
R_load = 50.000000
[Rising Waveform]
R_fixture= 50.000000
V_fixture= 3.300000
V_fixture_min= 2.700000
V_fixture_max= 3.600000
|time   V(typ)   V(min)   V(max)
0s        1.125V     1.393V     955.5mV
260.3ps   1.125V     1.393V     1.085V
420.4ps   1.124V     1.393V     2.08V
570.6ps   1.2V       1.393V     2.727V
850.9ps   2.409V     1.391V     3.253V
1.071ns   2.9V       1.395V     3.427V
1.291ns   3.098V     1.53V      3.518V
1.642ns   3.226V     2.366V     3.579V
1.962ns   3.27V      2.589V     3.592V
4.985ns   3.3V       2.7V       3.599V
[Rising Waveform]
R_fixture= 50.000000
V_fixture= 0.0
V_fixture_min= 0.0
V_fixture_max= 0.0
|time   V(typ)   V(min)   V(max)
0s        1.41mV     1.22mV     2.644mV
780.8ps   -18.79mV   1.596mV    14.29mV
1.221ns   11.7mV     -6.665mV   168.4mV
1.682ns   116mV      -7.75mV    460.1mV
2.302ns   386.9mV    91.54mV    926.7mV
3.744ns   1.177V     672.1mV    2.016V
4.505ns   1.552V     946.3mV    2.355V
5.345ns   1.855V     1.152V     2.495V
6.206ns   1.997V     1.264V     2.557V
9.97ns    2.129V     1.36V      2.615V
[Falling Waveform]
R_fixture= 50.000000
V_fixture= 3.300000
V_fixture_min= 2.700000
V_fixture_max= 3.600000
|time   V(typ)   V(min)   V(max)
0s        3.3V       2.7V       3.599V
940.9ps   3.314V     2.7V       3.604V
1.662ns   3.246V     2.71V      3.167V
2.342ns   2.906V     2.659V     2.557V
3.363ns   2.255V     2.19V      1.775V
4.004ns   1.908V     1.881V     1.39V
4.484ns   1.665V     1.718V     1.205V
5.205ns   1.405V     1.58V      1.088V
6.186ns   1.258V     1.497V     1.025V
9.97ns    1.125V     1.393V     955.5mV
[Falling Waveform]
R_fixture= 50.000000
V_fixture= 0.0
V_fixture_min= 0.0
V_fixture_max= 0.0
|time   V(typ)   V(min)   V(max)
0s        2.129V     1.36V      2.615V
240.2ps   2.132V     1.359V     2.439V
390.4ps   2.13V      1.359V     2.027V
550.6ps   2.022V     1.359V     1.405V
840.8ps   1.411V     1.363V     631.1mV
1.081ns   826.6mV    1.361V     351.9mV
1.291ns   481.6mV    1.263V     214.3mV
2.012ns   85.81mV    451.9mV    19.59mV
2.563ns   13.07mV    106.5mV    5.161mV
4.985ns   1.41mV     1.22mV     2.644mV
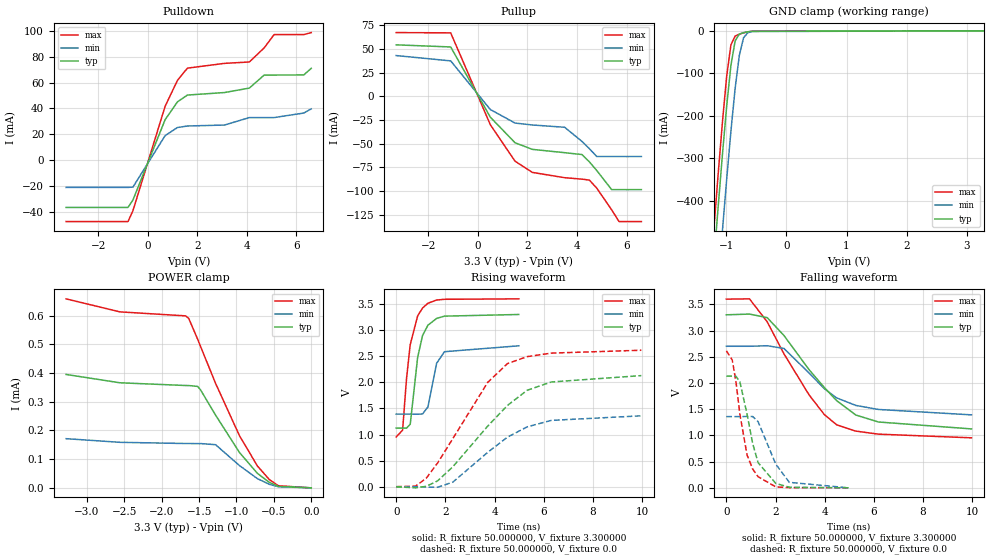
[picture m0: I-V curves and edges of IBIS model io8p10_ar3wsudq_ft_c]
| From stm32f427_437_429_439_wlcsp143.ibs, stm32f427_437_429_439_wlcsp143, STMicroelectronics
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|   Model io8p10_ar3wsudq_ft_c
[Model]  io8p10_ar3wsudq_ft_c
Model_type I/O
Polarity   Non-Inverting
Enable   Active-Low
Vinl =   0.990000V
Vinh =   2.310000V
Vmeas =  1.650000V
Cref =   40.000000pF
Rref =   100.000000M
Vref =   0.0V
C_comp   5.986400pF   5.818600pF   6.191500pF
[Temperature Range]   25.000000   0.125000k   -40.000000
[Pullup Reference]   3.300000V   2.700000V   3.600000V
[Pulldown Reference]   0.0V   0.0V   0.0V
[POWER Clamp Reference]   3.300000V   2.700000V   3.600000V
[GND Clamp Reference]   0.0V   0.0V   0.0V
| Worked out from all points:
|   slope of the pulldown table from 0 to 0.495 V, typ, clamps not added: 20.9 ohm
|   slope of the pullup table from 0 to 0.495 V, typ, clamps not added: 22.6 ohm
|   GND clamp passes 1 mA (typ) near -0.57 V on its own axis
|   rising waveform, R_fixture 50.000000, V_fixture 3.300000: 20-80 % time 372ps typ, 356ps min, 396ps max; typ from 1.12 V to 3.3 V
|   rising waveform, R_fixture 50.000000, V_fixture 0.0: 20-80 % time 2.49ns typ, 2.21ns min, 2.1ns max; typ from 0 V to 2.13 V
|   falling waveform, R_fixture 50.000000, V_fixture 3.300000: 20-80 % time 2.31ns typ, 1.87ns min, 2.05ns max; typ from 3.3 V to 1.12 V
|   falling waveform, R_fixture 50.000000, V_fixture 0.0: 20-80 % time 612ps typ, 774ps min, 546ps max; typ from 2.13 V to 0 V
[Pulldown]
|Voltage   I(typ)   I(min)   I(max)
-3.3V     -36.18mA   -20.77mA   -47.07mA
-800mV    -36.18mA   -20.77mA   -47.07mA
-600mV    -30.5mA    -20.52mA   -38.69mA
700mV     31.4mA     19.11mA    41.71mA
1.2V      45.15mA    25.37mA    61.75mA
1.6V      50.35mA    26.5mA     71.06mA
3.1V      52.28mA    27.26mA    74.75mA
4.1V      55.71mA    33.01mA    75.8mA
4.7V      65.73mA    33.01mA    86.69mA
5.1V      65.73mA    33.01mA    96.9mA
6.3V      65.85mA    36.5mA     96.9mA
6.6V      70.91mA    39.71mA    98.45mA
[Pullup]
|Voltage   I(typ)   I(min)   I(max)
-3.3V     54.22mA    42.91mA    67.16mA
-1.1V     51.99mA    37.3mA     66.87mA
500mV     -22.07mA   -14mA      -30.03mA
1.5V      -49.1mA    -28.3mA    -68.56mA
2.2V      -56.05mA   -30.32mA   -80.35mA
3.5V      -59.53mA   -32.72mA   -85.92mA
4.2V      -61.52mA   -47.6mA    -87.46mA
4.5V      -69.2mA    -55.3mA    -88.43mA
4.8V      -78.4mA    -63.6mA    -97.01mA
5.4V      -98.5mA    -63.6mA    -119.8mA
5.7V      -98.5mA    -63.6mA    -132.2mA
6.6V      -98.5mA    -63.6mA    -132.2mA
[GND_clamp]
|Voltage   I(typ)   I(min)   I(max)
-3.3V     -4.641A    -4.8A      -4.589A
-1.2V     -535.6mA   -717.5mA   -459.3mA
-1.13V    -409.9mA   -591mA     -333.1mA
-1.06V    -288.9mA   -467.4mA   -212.9mA
-990mV    -176.2mA   -348mA     -105.7mA
-920mV    -81.01mA   -235.5mA   -32.96mA
-850mV    -23.66mA   -135.1mA   -12.27mA
-780mV    -7.753mA   -57.42mA   -7.762mA
-710mV    -4.185mA   -16.31mA   -4.763mA
-640mV    -2.295mA   -4.401mA   -2.439mA
-570mV    -1.048mA   -1.62mA    -953.6uA
3.28V     0A         0A         0A
[POWER_clamp]
|Voltage   I(typ)   I(min)   I(max)
-3.28V    395.3uA    171.4uA    658.7uA
-2.56V    366.2uA    158.7uA    613.4uA
-1.68V    356.7uA    154.5uA    599.4uA
-1.64V    356.6uA    154.5uA    590.8uA
-1.52V    353.6uA    154.3uA    518.3uA
-1.48V    341.1uA    154.3uA    492.3uA
-1.28V    253.6uA    150.4uA    364.2uA
-960mV    123.1uA    77.62uA    181.6uA
-720mV    50.52uA    32.09uA    76.18uA
-560mV    18.94uA    12.32uA    28.65uA
-440mV    5.105uA    3.74uA     7.327uA
0V        0A         0A         0A
[Ramp]
| variable   typ   min   max
dV/dt_r  1.26624/2.47128n   0.80976/2.19475n   1.56342/2.09231n
dV/dt_f  1.28208/2.29051n   0.77382/1.84661n   1.57447/2.04234n
R_load = 50.000000
[Rising Waveform]
R_fixture= 50.000000
V_fixture= 3.300000
V_fixture_min= 2.700000
V_fixture_max= 3.600000
|time   V(typ)   V(min)   V(max)
0s        1.124V     1.392V     954.2mV
260.3ps   1.124V     1.392V     1.084V
420.4ps   1.123V     1.392V     2.077V
570.6ps   1.198V     1.392V     2.723V
870.9ps   2.475V     1.39V      3.271V
1.071ns   2.897V     1.394V     3.424V
1.291ns   3.095V     1.529V     3.515V
1.642ns   3.224V     2.364V     3.577V
1.962ns   3.268V     2.587V     3.591V
4.985ns   3.3V       2.7V       3.599V
[Rising Waveform]
R_fixture= 50.000000
V_fixture= 0.0
V_fixture_min= 0.0
V_fixture_max= 0.0
|time   V(typ)   V(min)   V(max)
0s        322.2uV    176.4uV    1.509mV
780.8ps   -21.06mV   554.8uV    9.827mV
1.221ns   7.972mV    -7.781mV   162.8mV
1.682ns   111.6mV    -10.02mV   454.6mV
2.302ns   382.1mV    88.1mV     922mV
3.724ns   1.163V     660.3mV    2.001V
4.525ns   1.558V     950.2mV    2.359V
5.325ns   1.848V     1.147V     2.492V
6.306ns   2.007V     1.271V     2.56V
9.97ns    2.129V     1.359V     2.615V
[Falling Waveform]
R_fixture= 50.000000
V_fixture= 3.300000
V_fixture_min= 2.700000
V_fixture_max= 3.600000
|time   V(typ)   V(min)   V(max)
0s        3.3V       2.7V       3.599V
940.9ps   3.314V     2.7V       3.604V
1.662ns   3.246V     2.71V      3.167V
2.342ns   2.906V     2.659V     2.557V
3.363ns   2.255V     2.19V      1.774V
3.984ns   1.915V     1.892V     1.398V
4.484ns   1.664V     1.716V     1.203V
5.265ns   1.389V     1.572V     1.082V
6.186ns   1.256V     1.495V     1.024V
9.97ns    1.124V     1.392V     954.2mV
[Falling Waveform]
R_fixture= 50.000000
V_fixture= 0.0
V_fixture_min= 0.0
V_fixture_max= 0.0
|time   V(typ)   V(min)   V(max)
0s        2.129V     1.359V     2.615V
240.2ps   2.132V     1.359V     2.439V
390.4ps   2.129V     1.358V     2.028V
550.6ps   2.022V     1.358V     1.406V
840.8ps   1.411V     1.362V     630.8mV
1.071ns   847.5mV    1.361V     359.4mV
1.291ns   480.8mV    1.262V     212.8mV
2.012ns   84.02mV    450.4mV    17.88mV
2.563ns   11.78mV    104.9mV    3.926mV
4.985ns   322.2uV    176.4uV    1.509mV
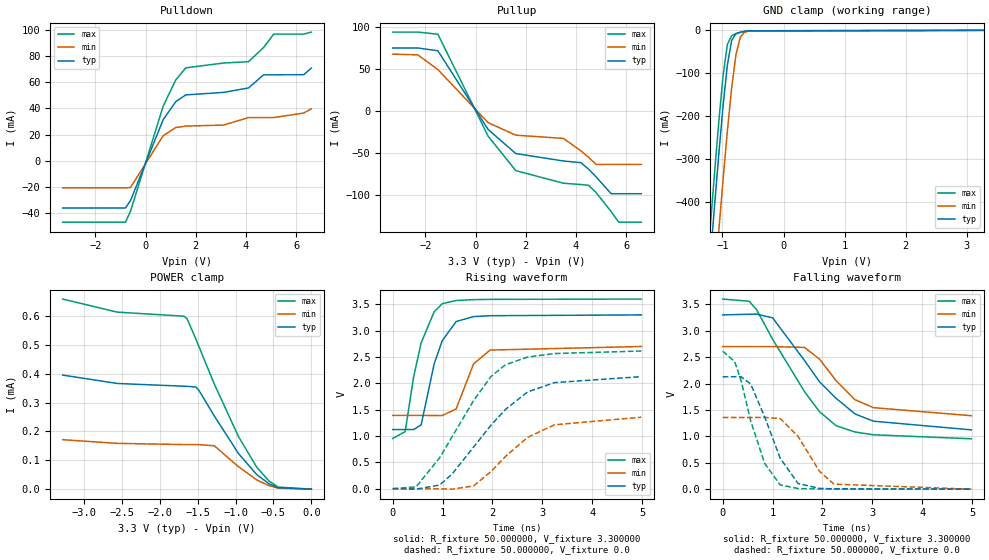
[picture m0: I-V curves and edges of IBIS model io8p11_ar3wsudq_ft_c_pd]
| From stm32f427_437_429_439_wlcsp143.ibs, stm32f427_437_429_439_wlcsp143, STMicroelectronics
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|   Model io8p11_ar3wsudq_ft_c_pd
[Model]  io8p11_ar3wsudq_ft_c_pd
Model_type I/O
Polarity   Non-Inverting
Enable   Active-Low
Vinl =   0.990000V
Vinh =   2.310000V
Vmeas =  1.650000V
Cref =   30.000000pF
Rref =   100.000000M
Vref =   0.0V
C_comp   5.986400pF   5.818600pF   6.191500pF
[Temperature Range]   25.000000   0.125000k   -40.000000
[Pullup Reference]   3.300000V   2.700000V   3.600000V
[Pulldown Reference]   0.0V   0.0V   0.0V
[POWER Clamp Reference]   3.300000V   2.700000V   3.600000V
[GND Clamp Reference]   0.0V   0.0V   0.0V
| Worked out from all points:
|   slope of the pulldown table from 0 to 0.495 V, typ, clamps not added: 20.9 ohm
|   slope of the pullup table from 0 to 0.495 V, typ, clamps not added: 22.6 ohm
|   GND clamp passes 1 mA (typ) near -0.56 V on its own axis
|   rising waveform, R_fixture 50.000000, V_fixture 3.300000: 20-80 % time 356ps typ, 328ps min, 367ps max; typ from 1.12 V to 3.3 V
|   rising waveform, R_fixture 50.000000, V_fixture 0.0: 20-80 % time 1.17ns typ, 993ps min, 1.03ns max; typ from 0 V to 2.13 V
|   falling waveform, R_fixture 50.000000, V_fixture 3.300000: 20-80 % time 1.12ns typ, 765ps min, 1.05ns max; typ from 3.3 V to 1.12 V
|   falling waveform, R_fixture 50.000000, V_fixture 0.0: 20-80 % time 519ps typ, 550ps min, 467ps max; typ from 2.13 V to 0 V
[Pulldown]
|Voltage   I(typ)   I(min)   I(max)
-3.3V     -36.18mA   -20.77mA   -47.07mA
-800mV    -36.18mA   -20.77mA   -47.07mA
-600mV    -30.5mA    -20.52mA   -38.69mA
700mV     31.4mA     19.11mA    41.71mA
1.2V      45.15mA    25.37mA    61.75mA
1.6V      50.35mA    26.5mA     71.06mA
3.1V      52.27mA    27.26mA    74.75mA
4.1V      55.7mA     33.01mA    75.8mA
4.7V      65.73mA    33.01mA    86.69mA
5.1V      65.73mA    33.01mA    96.89mA
6.3V      65.85mA    36.49mA    96.89mA
6.6V      70.9mA     39.7mA     98.44mA
[Pullup]
|Voltage   I(typ)   I(min)   I(max)
-3.3V     74.74mA    67.41mA    93.6mA
-2.3V     74.74mA    66.57mA    93.6mA
-1.5V     71.36mA    49.01mA    91.03mA
500mV     -22.07mA   -14mA      -30.03mA
1.6V      -50.64mA   -28.81mA   -70.96mA
3.5V      -59.53mA   -32.72mA   -85.92mA
4.2V      -61.52mA   -47.6mA    -87.46mA
4.5V      -69.21mA   -55.2mA    -88.43mA
4.8V      -78.4mA    -63.6mA    -97.01mA
5.4V      -98.4mA    -63.6mA    -119.7mA
5.7V      -98.4mA    -63.6mA    -132.2mA
6.6V      -98.4mA    -63.6mA    -132.2mA
[GND_clamp]
|Voltage   I(typ)   I(min)   I(max)
-3.3V     -4.638A    -4.798A    -4.585A
-1.2V     -535.6mA   -717.5mA   -459.3mA
-1.13V    -409.9mA   -591mA     -333.1mA
-1.06V    -288.9mA   -467.4mA   -212.9mA
-990mV    -176.2mA   -348mA     -105.7mA
-920mV    -81.01mA   -235.5mA   -32.97mA
-850mV    -23.67mA   -135.1mA   -12.28mA
-780mV    -7.764mA   -57.43mA   -7.776mA
-710mV    -4.197mA   -16.31mA   -4.777mA
-640mV    -2.307mA   -4.41mA    -2.453mA
-570mV    -1.059mA   -1.629mA   -967uA
3.28V     81.28uA    57.87uA    93.98uA
[POWER_clamp]
|Voltage   I(typ)   I(min)   I(max)
-3.28V    395.3uA    171.4uA    658.7uA
-2.56V    366.2uA    158.7uA    613.4uA
-1.68V    356.7uA    154.5uA    599.4uA
-1.64V    356.6uA    154.5uA    590.8uA
-1.52V    353.6uA    154.3uA    518.3uA
-1.48V    341.1uA    154.3uA    492.3uA
-1.28V    253.6uA    150.4uA    364.2uA
-960mV    123.1uA    77.62uA    181.6uA
-720mV    50.52uA    32.09uA    76.18uA
-560mV    18.94uA    12.32uA    28.65uA
-440mV    5.105uA    3.74uA     7.327uA
0V        0A         0A         0A
[Ramp]
| variable   typ   min   max
dV/dt_r  1.25598/1.14686n   0.79380/0.96168n   1.55832/1.02862n
dV/dt_f  1.27212/1.09351n   0.75858/0.73132n   1.56790/1.04466n
R_load = 50.000000
[Rising Waveform]
R_fixture= 50.000000
V_fixture= 3.300000
V_fixture_min= 2.700000
V_fixture_max= 3.600000
|time   V(typ)   V(min)   V(max)
0s        1.123V     1.391V     953.8mV
250.2ps   1.123V     1.391V     1.084V
420.4ps   1.123V     1.391V     2.128V
570.6ps   1.213V     1.391V     2.767V
830.8ps   2.367V     1.389V     3.358V
991ps     2.805V     1.388V     3.511V
1.271ns   3.172V     1.513V     3.572V
1.622ns   3.267V     2.37V      3.588V
1.952ns   3.283V     2.631V     3.593V
4.985ns   3.299V     2.699V     3.599V
[Rising Waveform]
R_fixture= 50.000000
V_fixture= 0.0
V_fixture_min= 0.0
V_fixture_max= 0.0
|time   V(typ)   V(min)   V(max)
0s        339.1uV    172.8uV    1.049mV
470.5ps   -8.129mV   183.2uV    36.26mV
940.9ps   69.48mV    -804.8uV   586.2mV
1.191ns   278mV      -8.777mV   987.3mV
1.622ns   790.9mV    52.59mV    1.672V
1.972ns   1.207V     327.6mV    2.131V
2.262ns   1.506V     613.7mV    2.353V
2.703ns   1.836V     972.9mV    2.498V
3.243ns   2.013V     1.213V     2.565V
4.985ns   2.127V     1.357V     2.613V
[Falling Waveform]
R_fixture= 50.000000
V_fixture= 3.300000
V_fixture_min= 2.700000
V_fixture_max= 3.600000
|time   V(typ)   V(min)   V(max)
0s        3.299V     2.699V     3.599V
530.5ps   3.312V     2.699V     3.558V
680.7ps   3.314V     2.698V     3.396V
1.001ns   3.243V     2.7V       2.838V
1.642ns   2.433V     2.683V     1.844V
1.942ns   2.033V     2.461V     1.467V
2.272ns   1.722V     2.056V     1.203V
2.653ns   1.424V     1.693V     1.083V
3.023ns   1.287V     1.543V     1.03V
4.985ns   1.123V     1.391V     953.8mV
[Falling Waveform]
R_fixture= 50.000000
V_fixture= 0.0
V_fixture_min= 0.0
V_fixture_max= 0.0
|time   V(typ)   V(min)   V(max)
0s        2.127V     1.357V     2.613V
240.2ps   2.13V      1.357V     2.414V
370.4ps   2.128V     1.357V     2.051V
560.6ps   1.992V     1.357V     1.292V
840.8ps   1.37V      1.36V      489.3mV
1.151ns   589.9mV    1.337V     80.93mV
1.512ns   106.4mV    998.5mV    12mV
1.942ns   15.04mV    335.1mV    4.494mV
2.232ns   6.432mV    95.55mV    3.251mV
4.985ns   339.1uV    172.8uV    1.049mV
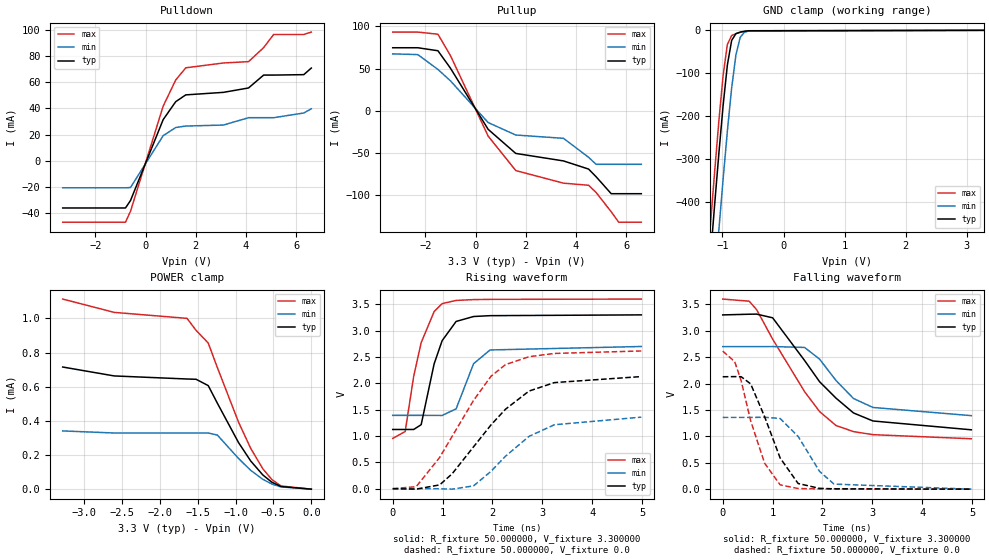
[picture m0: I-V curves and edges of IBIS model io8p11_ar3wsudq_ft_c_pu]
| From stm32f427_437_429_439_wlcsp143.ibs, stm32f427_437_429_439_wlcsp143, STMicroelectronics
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|   Model io8p11_ar3wsudq_ft_c_pu
[Model]  io8p11_ar3wsudq_ft_c_pu
Model_type I/O
Polarity   Non-Inverting
Enable   Active-Low
Vinl =   0.990000V
Vinh =   2.310000V
Vmeas =  1.650000V
Cref =   30.000000pF
Rref =   100.000000M
Vref =   0.0V
C_comp   5.986400pF   5.818600pF   6.191500pF
[Temperature Range]   25.000000   0.125000k   -40.000000
[Pullup Reference]   3.300000V   2.700000V   3.600000V
[Pulldown Reference]   0.0V   0.0V   0.0V
[POWER Clamp Reference]   3.300000V   2.700000V   3.600000V
[GND Clamp Reference]   0.0V   0.0V   0.0V
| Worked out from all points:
|   slope of the pulldown table from 0 to 0.495 V, typ, clamps not added: 20.9 ohm
|   slope of the pullup table from 0 to 0.495 V, typ, clamps not added: 22.6 ohm
|   GND clamp passes 1 mA (typ) near -0.57 V on its own axis
|   rising waveform, R_fixture 50.000000, V_fixture 3.300000: 20-80 % time 354ps typ, 327ps min, 365ps max; typ from 1.12 V to 3.3 V
|   rising waveform, R_fixture 50.000000, V_fixture 0.0: 20-80 % time 1.17ns typ, 995ps min, 1.04ns max; typ from 0.001 V to 2.13 V
|   falling waveform, R_fixture 50.000000, V_fixture 3.300000: 20-80 % time 1.12ns typ, 765ps min, 1.06ns max; typ from 3.3 V to 1.12 V
|   falling waveform, R_fixture 50.000000, V_fixture 0.0: 20-80 % time 520ps typ, 550ps min, 468ps max; typ from 2.13 V to 0.001 V
[Pulldown]
|Voltage   I(typ)   I(min)   I(max)
-3.3V     -36.18mA   -20.77mA   -47.07mA
-800mV    -36.18mA   -20.77mA   -47.07mA
-600mV    -30.5mA    -20.52mA   -38.69mA
700mV     31.4mA     19.11mA    41.71mA
1.2V      45.15mA    25.37mA    61.75mA
1.6V      50.35mA    26.5mA     71.06mA
3.1V      52.28mA    27.26mA    74.76mA
4.1V      55.65mA    32.89mA    75.79mA
4.7V      65.5mA     32.89mA    86.49mA
5.1V      65.5mA     32.89mA    96.55mA
6.3V      65.83mA    36.49mA    96.55mA
6.6V      70.88mA    39.7mA     98.4mA
[Pullup]
|Voltage   I(typ)   I(min)   I(max)
-3.3V     74.71mA    67.42mA    93.28mA
-2.3V     74.71mA    66.58mA    93.28mA
-1.5V     71.15mA    49mA       90.77mA
-1V       50.42mA    35.45mA    65.35mA
500mV     -22.06mA   -14mA      -30.03mA
1.6V      -50.64mA   -28.81mA   -70.96mA
3.5V      -59.52mA   -32.72mA   -85.91mA
4.5V      -69.2mA    -55.2mA    -88.42mA
4.8V      -78.3mA    -63.6mA    -97mA
5.4V      -98.4mA    -63.6mA    -119.8mA
5.7V      -98.4mA    -63.6mA    -132.2mA
6.6V      -98.4mA    -63.6mA    -132.2mA
[GND_clamp]
|Voltage   I(typ)   I(min)   I(max)
-3.3V     -4.64A     -4.798A    -4.587A
-1.2V     -535.6mA   -717.5mA   -459.3mA
-1.13V    -409.9mA   -591mA     -333.1mA
-1.06V    -288.9mA   -467.4mA   -212.9mA
-990mV    -176.2mA   -348mA     -105.7mA
-920mV    -81.01mA   -235.5mA   -32.96mA
-850mV    -23.66mA   -135.1mA   -12.27mA
-780mV    -7.753mA   -57.42mA   -7.762mA
-710mV    -4.185mA   -16.31mA   -4.763mA
-640mV    -2.295mA   -4.401mA   -2.439mA
-570mV    -1.048mA   -1.62mA    -953.6uA
3.28V     0A         0A         0A
[POWER_clamp]
|Voltage   I(typ)   I(min)   I(max)
-3.28V    715.1uA    341uA      1.113mA
-2.6V     662.9uA    328.8uA    1.035mA
-1.64V    645uA      328.8uA    1mA
-1.52V    643.3uA    328.8uA    929.5uA
-1.36V    606.3uA    328.8uA    855.6uA
-1.24V    503.7uA    316.9uA    712.3uA
-960mV    272.5uA    179.5uA    391.9uA
-800mV    165.2uA    110.4uA    239.2uA
-640mV    83.2uA     57.63uA    119.3uA
-520mV    40.52uA    29.88uA    56.09uA
-400mV    15.54uA    13.34uA    18.7uA
0V        0A         0A         0A
[Ramp]
| variable   typ   min   max
dV/dt_r  1.25641/1.14829n   0.79425/0.96288n   1.55872/1.02961n
dV/dt_f  1.27164/1.09370n   0.75774/0.73226n   1.56755/1.04470n
R_load = 50.000000
[Rising Waveform]
R_fixture= 50.000000
V_fixture= 3.300000
V_fixture_min= 2.700000
V_fixture_max= 3.600000
|time   V(typ)   V(min)   V(max)
0s        1.125V     1.393V     955.4mV
250.2ps   1.125V     1.393V     1.086V
420.4ps   1.125V     1.393V     2.133V
570.6ps   1.216V     1.393V     2.773V
830.8ps   2.371V     1.392V     3.363V
991ps     2.81V      1.391V     3.514V
1.271ns   3.175V     1.516V     3.574V
1.622ns   3.269V     2.374V     3.59V
1.952ns   3.285V     2.634V     3.594V
4.985ns   3.3V       2.7V       3.6V
[Rising Waveform]
R_fixture= 50.000000
V_fixture= 0.0
V_fixture_min= 0.0
V_fixture_max= 0.0
|time   V(typ)   V(min)   V(max)
0s        1.427mV    1.216mV    2.187mV
470.5ps   -6.997mV   1.226mV    39.91mV
940.9ps   73.34mV    243.2uV    592.9mV
1.191ns   283.2mV    -7.654mV   994mV
1.622ns   797mV      55.4mV     1.678V
1.972ns   1.213V     331.9mV    2.136V
2.262ns   1.51V      618.1mV    2.356V
2.733ns   1.854V     994.2mV    2.506V
3.243ns   2.015V     1.215V     2.568V
4.985ns   2.129V     1.359V     2.615V
[Falling Waveform]
R_fixture= 50.000000
V_fixture= 3.300000
V_fixture_min= 2.700000
V_fixture_max= 3.600000
|time   V(typ)   V(min)   V(max)
0s        3.3V       2.7V       3.6V
530.5ps   3.313V     2.7V       3.56V
680.7ps   3.315V     2.7V       3.399V
1.001ns   3.245V     2.701V     2.842V
1.642ns   2.437V     2.684V     1.847V
1.942ns   2.036V     2.463V     1.471V
2.272ns   1.724V     2.058V     1.206V
2.623ns   1.444V     1.717V     1.091V
3.013ns   1.292V     1.548V     1.033V
4.985ns   1.125V     1.393V     955.4mV
[Falling Waveform]
R_fixture= 50.000000
V_fixture= 0.0
V_fixture_min= 0.0
V_fixture_max= 0.0
|time   V(typ)   V(min)   V(max)
0s        2.129V     1.359V     2.615V
240.2ps   2.132V     1.359V     2.416V
370.4ps   2.13V      1.359V     2.052V
560.6ps   1.994V     1.359V     1.294V
840.8ps   1.372V     1.362V     492.1mV
1.151ns   592.6mV    1.339V     82.93mV
1.512ns   108.4mV    1V         13.43mV
1.942ns   16.41mV    337.2mV    5.764mV
2.232ns   7.687mV    97.22mV    4.469mV
4.985ns   1.427mV    1.216mV    2.187mV
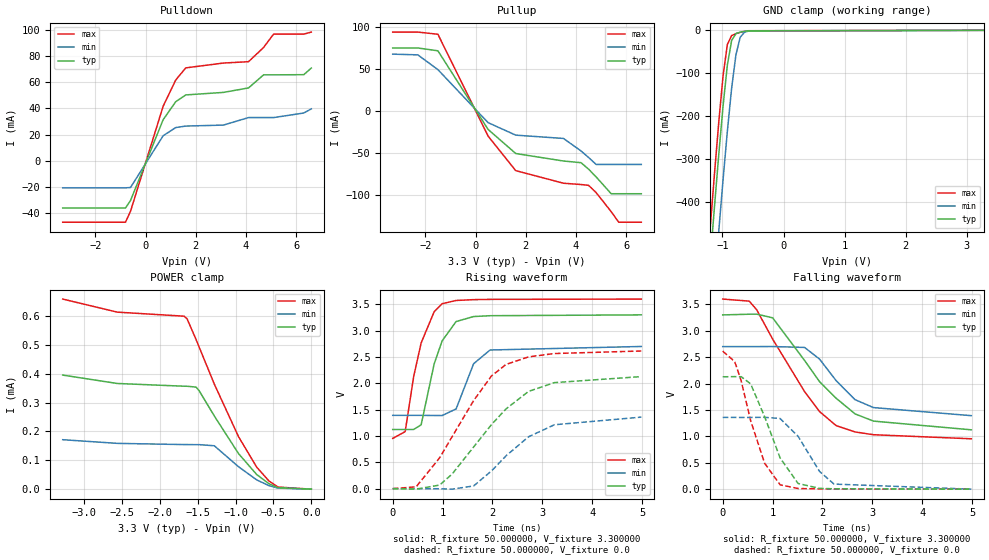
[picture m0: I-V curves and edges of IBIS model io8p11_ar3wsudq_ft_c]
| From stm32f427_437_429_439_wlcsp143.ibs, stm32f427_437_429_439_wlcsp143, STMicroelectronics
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|   Model io8p11_ar3wsudq_ft_c
[Model]  io8p11_ar3wsudq_ft_c
Model_type I/O
Polarity   Non-Inverting
Enable   Active-Low
Vinl =   0.990000V
Vinh =   2.310000V
Vmeas =  1.650000V
Cref =   30.000000pF
Rref =   100.000000M
Vref =   0.0V
C_comp   5.986400pF   5.818600pF   6.191500pF
[Temperature Range]   25.000000   0.125000k   -40.000000
[Pullup Reference]   3.300000V   2.700000V   3.600000V
[Pulldown Reference]   0.0V   0.0V   0.0V
[POWER Clamp Reference]   3.300000V   2.700000V   3.600000V
[GND Clamp Reference]   0.0V   0.0V   0.0V
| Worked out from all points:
|   slope of the pulldown table from 0 to 0.495 V, typ, clamps not added: 20.9 ohm
|   slope of the pullup table from 0 to 0.495 V, typ, clamps not added: 22.6 ohm
|   GND clamp passes 1 mA (typ) near -0.57 V on its own axis
|   rising waveform, R_fixture 50.000000, V_fixture 3.300000: 20-80 % time 356ps typ, 328ps min, 367ps max; typ from 1.12 V to 3.3 V
|   rising waveform, R_fixture 50.000000, V_fixture 0.0: 20-80 % time 1.17ns typ, 993ps min, 1.03ns max; typ from 0 V to 2.13 V
|   falling waveform, R_fixture 50.000000, V_fixture 3.300000: 20-80 % time 1.12ns typ, 766ps min, 1.06ns max; typ from 3.3 V to 1.12 V
|   falling waveform, R_fixture 50.000000, V_fixture 0.0: 20-80 % time 519ps typ, 550ps min, 468ps max; typ from 2.13 V to 0 V
[Pulldown]
|Voltage   I(typ)   I(min)   I(max)
-3.3V     -36.18mA   -20.77mA   -47.07mA
-800mV    -36.18mA   -20.77mA   -47.07mA
-600mV    -30.5mA    -20.52mA   -38.69mA
700mV     31.4mA     19.11mA    41.71mA
1.2V      45.15mA    25.37mA    61.75mA
1.6V      50.35mA    26.5mA     71.06mA
3.1V      52.28mA    27.26mA    74.75mA
4.1V      55.71mA    33.01mA    75.8mA
4.7V      65.73mA    33.01mA    86.69mA
5.1V      65.73mA    33.01mA    96.9mA
6.3V      65.85mA    36.5mA     96.9mA
6.6V      70.91mA    39.71mA    98.45mA
[Pullup]
|Voltage   I(typ)   I(min)   I(max)
-3.3V     74.74mA    67.41mA    93.61mA
-2.3V     74.74mA    66.57mA    93.61mA
-1.5V     71.37mA    49.01mA    91.04mA
500mV     -22.07mA   -14mA      -30.03mA
1.6V      -50.64mA   -28.81mA   -70.96mA
3.5V      -59.53mA   -32.72mA   -85.92mA
4.2V      -61.52mA   -47.6mA    -87.46mA
4.5V      -69.2mA    -55.3mA    -88.43mA
4.8V      -78.4mA    -63.6mA    -97.01mA
5.4V      -98.4mA    -63.6mA    -119.7mA
5.7V      -98.4mA    -63.6mA    -132.2mA
6.6V      -98.4mA    -63.6mA    -132.2mA
[GND_clamp]
|Voltage   I(typ)   I(min)   I(max)
-3.3V     -4.64A     -4.798A    -4.587A
-1.2V     -535.6mA   -717.5mA   -459.3mA
-1.13V    -409.9mA   -591mA     -333.1mA
-1.06V    -288.9mA   -467.4mA   -212.9mA
-990mV    -176.2mA   -348mA     -105.7mA
-920mV    -81.01mA   -235.5mA   -32.96mA
-850mV    -23.66mA   -135.1mA   -12.27mA
-780mV    -7.753mA   -57.42mA   -7.762mA
-710mV    -4.185mA   -16.31mA   -4.763mA
-640mV    -2.295mA   -4.401mA   -2.439mA
-570mV    -1.048mA   -1.62mA    -953.6uA
3.28V     0A         0A         0A
[POWER_clamp]
|Voltage   I(typ)   I(min)   I(max)
-3.28V    395.3uA    171.4uA    658.7uA
-2.56V    366.2uA    158.7uA    613.4uA
-1.68V    356.7uA    154.5uA    599.4uA
-1.64V    356.6uA    154.5uA    590.8uA
-1.52V    353.6uA    154.3uA    518.3uA
-1.48V    341.1uA    154.3uA    492.3uA
-1.28V    253.6uA    150.4uA    364.2uA
-960mV    123.1uA    77.62uA    181.6uA
-720mV    50.52uA    32.09uA    76.18uA
-560mV    18.94uA    12.32uA    28.65uA
-440mV    5.105uA    3.74uA     7.327uA
0V        0A         0A         0A
[Ramp]
| variable   typ   min   max
dV/dt_r  1.25646/1.14729n   0.79404/0.96209n   1.55898/1.02898n
dV/dt_f  1.27218/1.09382n   0.75828/0.73252n   1.56823/1.04470n
R_load = 50.000000
[Rising Waveform]
R_fixture= 50.000000
V_fixture= 3.300000
V_fixture_min= 2.700000
V_fixture_max= 3.600000
|time   V(typ)   V(min)   V(max)
0s        1.124V     1.392V     954.2mV
250.2ps   1.124V     1.392V     1.084V
420.4ps   1.124V     1.392V     2.129V
570.6ps   1.214V     1.392V     2.768V
830.8ps   2.368V     1.39V      3.359V
991ps     2.806V     1.389V     3.512V
1.271ns   3.173V     1.514V     3.573V
1.622ns   3.268V     2.372V     3.589V
1.952ns   3.284V     2.633V     3.594V
4.985ns   3.3V       2.7V       3.6V
[Rising Waveform]
R_fixture= 50.000000
V_fixture= 0.0
V_fixture_min= 0.0
V_fixture_max= 0.0
|time   V(typ)   V(min)   V(max)
0s        339.1uV    172.7uV    1.049mV
470.5ps   -8.131mV   183.2uV    36.26mV
940.9ps   69.48mV    -805.1uV   586.2mV
1.191ns   278mV      -8.78mV    987.4mV
1.622ns   791mV      52.6mV     1.672V
1.982ns   1.219V     337.5mV    2.142V
2.272ns   1.515V     623.6mV    2.359V
2.723ns   1.847V     985.5mV    2.503V
3.243ns   2.014V     1.214V     2.566V
4.985ns   2.128V     1.359V     2.614V
[Falling Waveform]
R_fixture= 50.000000
V_fixture= 3.300000
V_fixture_min= 2.700000
V_fixture_max= 3.600000
|time   V(typ)   V(min)   V(max)
0s        3.3V       2.7V       3.6V
530.5ps   3.313V     2.7V       3.561V
680.7ps   3.315V     2.7V       3.399V
1.001ns   3.245V     2.701V     2.842V
1.642ns   2.437V     2.684V     1.847V
1.942ns   2.036V     2.463V     1.47V
2.272ns   1.724V     2.058V     1.205V
2.653ns   1.426V     1.695V     1.084V
3.023ns   1.289V     1.545V     1.031V
4.985ns   1.124V     1.392V     954.2mV
[Falling Waveform]
R_fixture= 50.000000
V_fixture= 0.0
V_fixture_min= 0.0
V_fixture_max= 0.0
|time   V(typ)   V(min)   V(max)
0s        2.128V     1.359V     2.614V
240.2ps   2.131V     1.359V     2.416V
370.4ps   2.13V      1.358V     2.053V
560.6ps   1.994V     1.358V     1.295V
840.8ps   1.372V     1.361V     491.7mV
1.151ns   591.9mV    1.338V     82.18mV
1.512ns   107.5mV    999.7mV    12.59mV
1.942ns   15.56mV    336.1mV    4.846mV
2.232ns   6.802mV    96.15mV    3.505mV
4.985ns   339.1uV    172.7uV    1.049mV
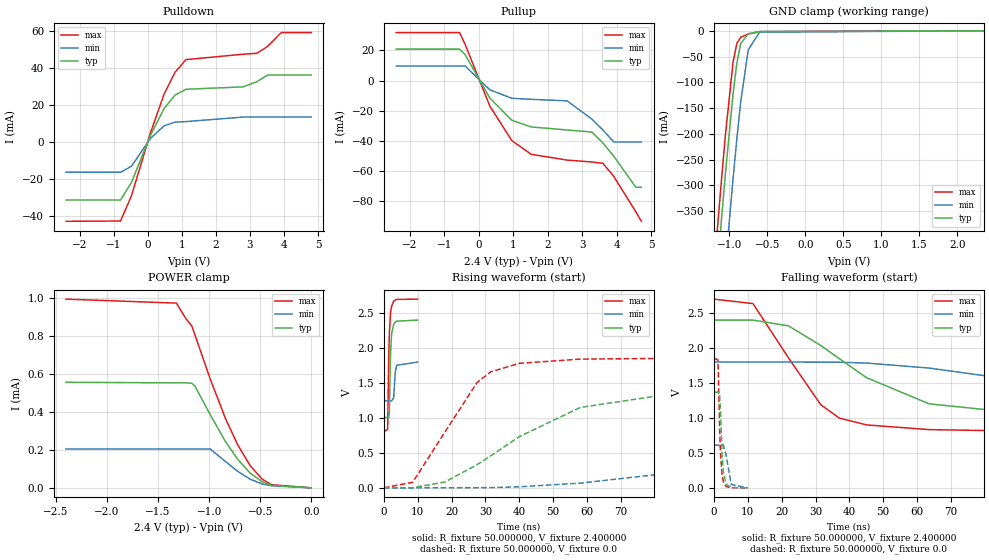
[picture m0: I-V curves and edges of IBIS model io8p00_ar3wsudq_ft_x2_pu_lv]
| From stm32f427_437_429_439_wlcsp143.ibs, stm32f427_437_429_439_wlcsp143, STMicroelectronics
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|   Model io8p00_ar3wsudq_ft_x2_pu_lv
[Model]  io8p00_ar3wsudq_ft_x2_pu_lv
Model_type I/O
Polarity   Non-Inverting
Enable   Active-Low
Vinl =   0.720000V
Vinh =   1.680000V
Vmeas =  1.200000V
Cref =   50.000000pF
Rref =   100.000000M
Vref =   0.0V
C_comp   7.427100pF   7.257100pF   7.608500pF
[Temperature Range]   25.000000   0.125000k   -40.000000
[Pullup Reference]   2.400000V   1.800000V   2.700000V
[Pulldown Reference]   0.0V   0.0V   0.0V
[POWER Clamp Reference]   2.400000V   1.800000V   2.700000V
[GND Clamp Reference]   0.0V   0.0V   0.0V
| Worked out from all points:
|   slope of the pulldown table from 0 to 0.36 V, typ, clamps not added: 25 ohm
|   slope of the pullup table from 0 to 0.36 V, typ, clamps not added: 27.7 ohm
|   GND clamp passes 1 mA (typ) near -0.56 V on its own axis
|   rising waveform, R_fixture 50.000000, V_fixture 2.400000: 20-80 % time 423ps typ, 454ps min, 454ps max; typ from 1.01 V to 2.4 V
|   rising waveform, R_fixture 50.000000, V_fixture 0.0: 20-80 % time 29.2ns typ, 72.4ns min, 14.2ns max; typ from 0.001 V to 1.37 V
|   falling waveform, R_fixture 50.000000, V_fixture 2.400000: 20-80 % time 28.2ns typ, 59.3ns min, 15.4ns max; typ from 2.4 V to 1.01 V
|   falling waveform, R_fixture 50.000000, V_fixture 0.0: 20-80 % time 773ps typ, 1.08ns min, 689ps max; typ from 1.37 V to 0.001 V
[Pulldown]
|Voltage   I(typ)   I(min)   I(max)
-2.4V     -31.47mA   -16.45mA   -43.01mA
-800mV    -31.47mA   -16.45mA   -42.85mA
-480mV    -21.98mA   -13.17mA   -29.21mA
80mV      3.63mA     1.966mA    5.014mA
480mV     18.16mA    8.738mA    26.02mA
800mV     25.38mA    10.72mA    37.77mA
1.12V     28.53mA    11.02mA    44.6mA
2.8V      29.84mA    13.47mA    47.53mA
3.2V      32.6mA     13.47mA    48.03mA
3.52V     36.29mA    13.47mA    51.75mA
3.92V     36.29mA    13.47mA    59.26mA
4.8V      36.29mA    13.47mA    59.26mA
[Pullup]
|Voltage   I(typ)   I(min)   I(max)
-2.4V     20.87mA    9.66mA     31.87mA
-560mV    20.87mA    9.66mA     31.87mA
-400mV    17.27mA    9.66mA     24.06mA
320mV     -11.75mA   -6.207mA   -17.08mA
960mV     -26.47mA   -11.82mA   -40.02mA
1.52V     -30.88mA   -12.51mA   -49.05mA
2.56V     -32.88mA   -13.52mA   -52.9mA
3.28V     -34.25mA   -25.6mA    -54.17mA
3.6V      -41.44mA   -32.8mA    -55.02mA
3.92V     -50.4mA    -40.9mA    -63.79mA
4.56V     -71mA      -40.9mA    -87.3mA
4.72V     -71mA      -40.9mA    -93.6mA
[GND_clamp]
|Voltage   I(typ)   I(min)   I(max)
-2.4V     -2.86A     -3.029A    -2.798A
-1.25V    -631.9mA   -814.4mA   -556.4mA
-1.2V     -540.2mA   -722.7mA   -464.2mA
-1.15V    -450mA     -632mA     -373.5mA
-1.1V     -361.8mA   -542.6mA   -285.3mA
-1.05V    -276.4mA   -454.9mA   -201.1mA
-950mV    -122.3mA   -287.2mA   -60.86mA
-900mV    -62.47mA   -209.5mA   -24.29mA
-850mV    -24.99mA   -138.8mA   -12.44mA
-750mV    -5.796mA   -36.69mA   -6.36mA
-600mV    -1.5mA     -2.436mA   -1.477mA
2.35V     0A         0A         0A
[POWER_clamp]
|Voltage   I(typ)   I(min)   I(max)
-2.4V     557.3uA    205.5uA    996.4uA
-1.32V    554.4uA    205.5uA    975.4uA
-1.23V    554.4uA    205.5uA    896uA
-1.17V    552.4uA    205.5uA    855.2uA
-1.14V    538.7uA    205.5uA    810.7uA
-990mV    387.4uA    205.5uA    576uA
-840mV    244.7uA    139.3uA    366.5uA
-720mV    150.8uA    87.02uA    226.9uA
-600mV    79.14uA    46.29uA    118.6uA
-480mV    31.63uA    20.18uA    45.53uA
-390mV    13.82uA    11.06uA    17.04uA
0V        0A         0A         0A
[Ramp]
| variable   typ   min   max
dV/dt_r  0.82207/29.13519n   0.36105/72.42800n   1.11083/14.22736n
dV/dt_f  0.83574/28.19476n   0.32616/59.48833n   1.13660/15.37098n
R_load = 50.000000
[Rising Waveform]
R_fixture= 50.000000
V_fixture= 2.400000
V_fixture_min= 1.800000
V_fixture_max= 2.700000
|time   V(typ)   V(min)   V(max)
0s        1.007V     1.247V     805.7mV
1.101ns   1.007V     1.247V     838.1mV
1.401ns   1.004V     1.247V     1.829V
1.582ns   1.058V     1.247V     2.198V
1.942ns   1.916V     1.247V     2.501V
2.262ns   2.205V     1.245V     2.597V
2.863ns   2.337V     1.286V     2.67V
3.343ns   2.37V      1.65V      2.689V
3.784ns   2.385V     1.754V     2.696V
9.97ns    2.4V       1.8V       2.7V
[Rising Waveform]
R_fixture= 50.000000
V_fixture= 0.0
V_fixture_min= 0.0
V_fixture_max= 0.0
|time   V(typ)   V(min)   V(max)
0s        880.4uV    840.6uV    911.2uV
8.509ns   3.173mV    1.871mV    80.42mV
18.02ns   84.36mV    1.972mV    798.1mV
27.53ns   332.4mV    3.729mV    1.506V
31.53ns   457mV      4.784mV    1.659V
40.04ns   733.6mV    16.02mV    1.782V
58.06ns   1.151V     68.2mV     1.842V
82.08ns   1.324V     198.6mV    1.852V
151.7ns   1.371V     516mV      1.852V
249.2ns   1.371V     610.3mV    1.852V
[Falling Waveform]
R_fixture= 50.000000
V_fixture= 2.400000
V_fixture_min= 1.800000
V_fixture_max= 2.700000
|time   V(typ)   V(min)   V(max)
0s        2.4V       1.8V       2.7V
11.51ns   2.4V       1.8V       2.636V
22.02ns   2.317V     1.8V       1.859V
31.53ns   2.038V     1.799V     1.191V
37.04ns   1.849V     1.797V     999mV
45.05ns   1.578V     1.786V     901.4mV
63.56ns   1.203V     1.714V     834mV
92.09ns   1.061V     1.525V     811.5mV
136.6ns   1.017V     1.334V     806.2mV
249.2ns   1.007V     1.247V     805.7mV
[Falling Waveform]
R_fixture= 50.000000
V_fixture= 0.0
V_fixture_min= 0.0
V_fixture_max= 0.0
|time   V(typ)   V(min)   V(max)
0s        1.371V     610.3mV    1.852V
1.101ns   1.37V      610.2mV    1.833V
1.241ns   1.371V     610.2mV    1.673V
1.582ns   1.366V     610.2mV    971.4mV
1.862ns   1.132V     609.9mV    514.6mV
2.362ns   505.6mV    609.9mV    190.4mV
2.743ns   235.2mV    615.5mV    86.65mV
3.544ns   52.8mV     469.9mV    19.98mV
5.085ns   5.875mV    49mV       2.687mV
9.97ns    880.4uV    840.6uV    911.2uV
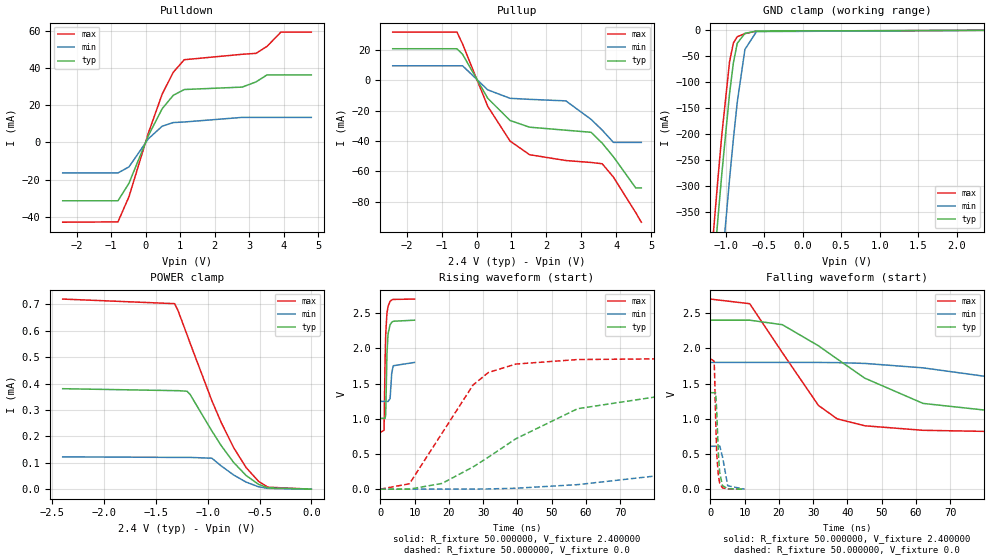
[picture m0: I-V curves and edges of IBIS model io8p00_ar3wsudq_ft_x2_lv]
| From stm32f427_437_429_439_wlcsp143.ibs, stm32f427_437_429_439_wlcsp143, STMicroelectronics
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|   Model io8p00_ar3wsudq_ft_x2_lv
[Model]  io8p00_ar3wsudq_ft_x2_lv
Model_type I/O
Polarity   Non-Inverting
Enable   Active-Low
Vinl =   0.720000V
Vinh =   1.680000V
Vmeas =  1.200000V
Cref =   50.000000pF
Rref =   100.000000M
Vref =   0.0V
C_comp   7.427100pF   7.257100pF   7.608500pF
[Temperature Range]   25.000000   0.125000k   -40.000000
[Pullup Reference]   2.400000V   1.800000V   2.700000V
[Pulldown Reference]   0.0V   0.0V   0.0V
[POWER Clamp Reference]   2.400000V   1.800000V   2.700000V
[GND Clamp Reference]   0.0V   0.0V   0.0V
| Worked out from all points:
|   slope of the pulldown table from 0 to 0.36 V, typ, clamps not added: 25 ohm
|   slope of the pullup table from 0 to 0.36 V, typ, clamps not added: 27.7 ohm
|   GND clamp passes 1 mA (typ) near -0.56 V on its own axis
|   rising waveform, R_fixture 50.000000, V_fixture 2.400000: 20-80 % time 425ps typ, 455ps min, 456ps max; typ from 1.01 V to 2.4 V
|   rising waveform, R_fixture 50.000000, V_fixture 0.0: 20-80 % time 29.1ns typ, 72.3ns min, 14.2ns max; typ from 0 V to 1.37 V
|   falling waveform, R_fixture 50.000000, V_fixture 2.400000: 20-80 % time 28.2ns typ, 58.9ns min, 15.4ns max; typ from 2.4 V to 1.01 V
|   falling waveform, R_fixture 50.000000, V_fixture 0.0: 20-80 % time 774ps typ, 1.08ns min, 691ps max; typ from 1.37 V to 0 V
[Pulldown]
|Voltage   I(typ)   I(min)   I(max)
-2.4V     -31.47mA   -16.45mA   -43.01mA
-800mV    -31.47mA   -16.45mA   -42.85mA
-480mV    -21.98mA   -13.17mA   -29.21mA
80mV      3.63mA     1.966mA    5.014mA
480mV     18.16mA    8.738mA    26.02mA
800mV     25.38mA    10.72mA    37.77mA
1.12V     28.53mA    11.02mA    44.6mA
2.8V      29.84mA    13.51mA    47.53mA
3.2V      32.66mA    13.51mA    48.04mA
3.52V     36.44mA    13.51mA    51.84mA
3.92V     36.44mA    13.51mA    59.5mA
4.8V      36.44mA    13.51mA    59.5mA
[Pullup]
|Voltage   I(typ)   I(min)   I(max)
-2.4V     20.89mA    9.661mA    31.89mA
-560mV    20.89mA    9.661mA    31.89mA
-400mV    17.28mA    9.661mA    24.06mA
320mV     -11.75mA   -6.207mA   -17.08mA
960mV     -26.47mA   -11.82mA   -40.02mA
1.52V     -30.88mA   -12.51mA   -49.05mA
2.56V     -32.88mA   -13.52mA   -52.9mA
3.28V     -34.25mA   -25.7mA    -54.18mA
3.6V      -41.44mA   -32.8mA    -55.03mA
3.92V     -50.4mA    -40.9mA    -63.8mA
4.56V     -71mA      -40.9mA    -87.3mA
4.72V     -71mA      -40.9mA    -93.6mA
[GND_clamp]
|Voltage   I(typ)   I(min)   I(max)
-2.4V     -2.86A     -3.029A    -2.798A
-1.25V    -631.9mA   -814.4mA   -556.4mA
-1.2V     -540.2mA   -722.7mA   -464.2mA
-1.15V    -450mA     -632mA     -373.5mA
-1.1V     -361.8mA   -542.6mA   -285.3mA
-1.05V    -276.4mA   -454.9mA   -201.1mA
-950mV    -122.3mA   -287.2mA   -60.86mA
-900mV    -62.47mA   -209.5mA   -24.29mA
-850mV    -24.99mA   -138.8mA   -12.44mA
-750mV    -5.796mA   -36.69mA   -6.36mA
-600mV    -1.5mA     -2.436mA   -1.477mA
2.35V     0A         0A         0A
[POWER_clamp]
|Voltage   I(typ)   I(min)   I(max)
-2.4V     380.4uA    122.4uA    719.8uA
-1.32V    373.1uA    120.3uA    702.4uA
-1.29V    373.1uA    120.3uA    679.3uA
-1.2V     370.8uA    120.2uA    585.1uA
-1.17V    358.5uA    120.2uA    552.5uA
-960mV    220.5uA    117.2uA    335uA
-870mV    164.9uA    87.99uA    252.6uA
-750mV    101.2uA    53.84uA    157.3uA
-630mV    51.89uA    26.83uA    82.04uA
-510mV    18.44uA    9.055uA    29.95uA
-420mV    4.85uA     2.76uA     7.499uA
0V        0A         0A         0A
[Ramp]
| variable   typ   min   max
dV/dt_r  0.82218/29.12139n   0.36085/72.35014n   1.11108/14.21279n
dV/dt_f  0.83652/28.17147n   0.32652/59.28958n   1.13727/15.35826n
R_load = 50.000000
[Rising Waveform]
R_fixture= 50.000000
V_fixture= 2.400000
V_fixture_min= 1.800000
V_fixture_max= 2.700000
|time   V(typ)   V(min)   V(max)
0s        1.006V     1.247V     804.6mV
1.101ns   1.006V     1.247V     836.9mV
1.401ns   1.003V     1.247V     1.826V
1.582ns   1.057V     1.247V     2.195V
1.942ns   1.913V     1.247V     2.499V
2.262ns   2.203V     1.245V     2.595V
2.863ns   2.336V     1.286V     2.669V
3.343ns   2.369V     1.649V     2.688V
3.784ns   2.385V     1.753V     2.695V
9.97ns    2.4V       1.8V       2.7V
[Rising Waveform]
R_fixture= 50.000000
V_fixture= 0.0
V_fixture_min= 0.0
V_fixture_max= 0.0
|time   V(typ)   V(min)   V(max)
0s        11.79nV    703.6nV    4.752nV
8.509ns   234uV      -67.61uV   76.81mV
18.02ns   81.57mV    32.44uV    795.6mV
27.03ns   314.8mV    1.666mV    1.478V
31.53ns   454.8mV    2.86mV     1.657V
39.54ns   716.1mV    13.36mV    1.777V
57.56ns   1.143V     64.27mV    1.841V
82.08ns   1.323V     197mV      1.851V
151.7ns   1.37V      514.6mV    1.852V
249.2ns   1.37V      609.1mV    1.852V
[Falling Waveform]
R_fixture= 50.000000
V_fixture= 2.400000
V_fixture_min= 1.800000
V_fixture_max= 2.700000
|time   V(typ)   V(min)   V(max)
0s        2.4V       1.8V       2.7V
11.51ns   2.4V       1.8V       2.634V
21.02ns   2.336V     1.8V       1.939V
31.53ns   2.037V     1.8V       1.19V
37.04ns   1.848V     1.797V     997.6mV
45.05ns   1.577V     1.786V     900.2mV
62.06ns   1.218V     1.723V     836.1mV
92.09ns   1.06V      1.523V     810.4mV
139.6ns   1.014V     1.327V     805mV
249.2ns   1.006V     1.247V     804.6mV
[Falling Waveform]
R_fixture= 50.000000
V_fixture= 0.0
V_fixture_min= 0.0
V_fixture_max= 0.0
|time   V(typ)   V(min)   V(max)
0s        1.37V      609.1mV    1.852V
1.121ns   1.37V      609mV      1.82V
1.241ns   1.371V     609.1mV    1.673V
1.582ns   1.365V     609.1mV    972.1mV
1.862ns   1.132V     608.7mV    515.7mV
2.362ns   505.4mV    608.7mV    191.5mV
2.743ns   235.4mV    614.3mV    87.41mV
3.564ns   51.02mV    460.6mV    19.38mV
5.085ns   5.481mV    48.39mV    2.153mV
9.97ns    11.79nV    703.6nV    4.752nV
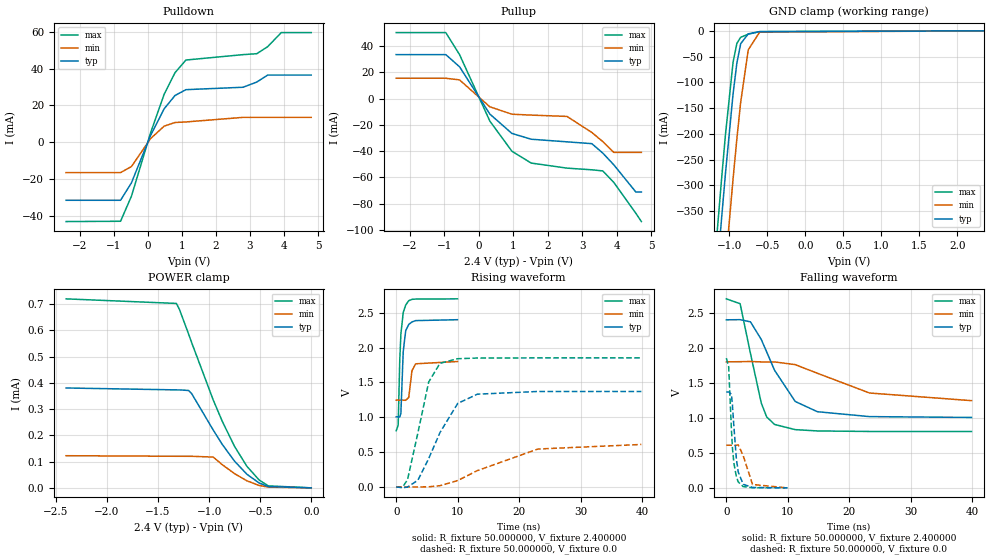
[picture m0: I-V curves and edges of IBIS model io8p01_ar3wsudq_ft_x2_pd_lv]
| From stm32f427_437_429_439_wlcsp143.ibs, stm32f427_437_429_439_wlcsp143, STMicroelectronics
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|   Model io8p01_ar3wsudq_ft_x2_pd_lv
[Model]  io8p01_ar3wsudq_ft_x2_pd_lv
Model_type I/O
Polarity   Non-Inverting
Enable   Active-Low
Vinl =   0.720000V
Vinh =   1.680000V
Vmeas =  1.200000V
Cref =   50.000000pF
Rref =   100.000000M
Vref =   0.0V
C_comp   7.427500pF   7.257100pF   7.608500pF
[Temperature Range]   25.000000   0.125000k   -40.000000
[Pullup Reference]   2.400000V   1.800000V   2.700000V
[Pulldown Reference]   0.0V   0.0V   0.0V
[POWER Clamp Reference]   2.400000V   1.800000V   2.700000V
[GND Clamp Reference]   0.0V   0.0V   0.0V
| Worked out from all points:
|   slope of the pulldown table from 0 to 0.36 V, typ, clamps not added: 25 ohm
|   slope of the pullup table from 0 to 0.36 V, typ, clamps not added: 27.7 ohm
|   GND clamp passes 1 mA (typ) near -0.56 V on its own axis
|   rising waveform, R_fixture 50.000000, V_fixture 2.400000: 20-80 % time 426ps typ, 454ps min, 459ps max; typ from 1 V to 2.4 V
|   rising waveform, R_fixture 50.000000, V_fixture 0.0: 20-80 % time 4.43ns typ, 9.2ns min, 2.6ns max; typ from 0 V to 1.37 V
|   falling waveform, R_fixture 50.000000, V_fixture 2.400000: 20-80 % time 4.99ns typ, 9.69ns min, 2.7ns max; typ from 2.4 V to 1 V
|   falling waveform, R_fixture 50.000000, V_fixture 0.0: 20-80 % time 772ps typ, 1.08ns min, 691ps max; typ from 1.37 V to 0 V
[Pulldown]
|Voltage   I(typ)   I(min)   I(max)
-2.4V     -31.47mA   -16.45mA   -43.01mA
-800mV    -31.47mA   -16.45mA   -42.85mA
-480mV    -21.98mA   -13.17mA   -29.21mA
80mV      3.63mA     1.966mA    5.014mA
480mV     18.15mA    8.738mA    26.02mA
800mV     25.38mA    10.72mA    37.77mA
1.12V     28.53mA    11.02mA    44.6mA
2.8V      29.84mA    13.51mA    47.53mA
3.2V      32.66mA    13.51mA    48.03mA
3.52V     36.44mA    13.51mA    51.84mA
3.92V     36.44mA    13.51mA    59.49mA
4.8V      36.44mA    13.51mA    59.49mA
[Pullup]
|Voltage   I(typ)   I(min)   I(max)
-2.4V     33.58mA    15.57mA    50.35mA
-960mV    33.58mA    15.57mA    50.35mA
-560mV    24.28mA    14.31mA    33.53mA
320mV     -11.75mA   -6.207mA   -17.08mA
960mV     -26.47mA   -11.82mA   -40.02mA
1.52V     -30.88mA   -12.51mA   -49.05mA
2.56V     -32.88mA   -13.52mA   -52.9mA
3.28V     -34.25mA   -25.7mA    -54.18mA
3.6V      -41.44mA   -32.7mA    -55.03mA
3.92V     -50.4mA    -40.9mA    -63.8mA
4.56V     -71.1mA    -40.9mA    -87.3mA
4.72V     -71.1mA    -40.9mA    -93.6mA
[GND_clamp]
|Voltage   I(typ)   I(min)   I(max)
-2.4V     -2.859A    -3.029A    -2.798A
-1.25V    -631.9mA   -814.4mA   -556.4mA
-1.2V     -540.2mA   -722.7mA   -464.2mA
-1.15V    -450mA     -632mA     -373.5mA
-1.1V     -361.8mA   -542.6mA   -285.3mA
-1.05V    -276.4mA   -454.9mA   -201.1mA
-950mV    -122.3mA   -287.2mA   -60.87mA
-900mV    -62.48mA   -209.5mA   -24.3mA
-850mV    -25mA      -138.8mA   -12.46mA
-750mV    -5.808mA   -36.7mA    -6.375mA
-600mV    -1.512mA   -2.445mA   -1.49mA
2.35V     58.09uA    37.93uA    67.25uA
[POWER_clamp]
|Voltage   I(typ)   I(min)   I(max)
-2.4V     380.4uA    122.4uA    719.8uA
-1.32V    373.1uA    120.3uA    702.4uA
-1.29V    373.1uA    120.3uA    679.3uA
-1.2V     370.8uA    120.2uA    585.1uA
-1.17V    358.5uA    120.2uA    552.5uA
-960mV    220.5uA    117.2uA    335uA
-870mV    164.9uA    87.99uA    252.6uA
-750mV    101.2uA    53.84uA    157.3uA
-630mV    51.89uA    26.83uA    82.04uA
-510mV    18.44uA    9.055uA    29.95uA
-420mV    4.85uA     2.76uA     7.499uA
0V        0A         0A         0A
[Ramp]
| variable   typ   min   max
dV/dt_r  0.82152/4.42537n   0.36401/9.19338n   1.11042/2.60319n
dV/dt_f  0.83628/4.98325n   0.32202/9.65114n   1.13692/2.69356n
R_load = 50.000000
[Rising Waveform]
R_fixture= 50.000000
V_fixture= 2.400000
V_fixture_min= 1.800000
V_fixture_max= 2.700000
|time   V(typ)   V(min)   V(max)
0s        1.005V     1.245V     804.5mV
320.3ps   1.005V     1.245V     886mV
580.6ps   1.002V     1.246V     1.824V
760.8ps   1.056V     1.246V     2.191V
1.141ns   1.942V     1.245V     2.502V
1.542ns   2.24V      1.242V     2.609V
2.042ns   2.332V     1.284V     2.672V
2.563ns   2.367V     1.667V     2.691V
3.163ns   2.386V     1.766V     2.695V
9.97ns    2.399V     1.799V     2.698V
[Rising Waveform]
R_fixture= 50.000000
V_fixture= 0.0
V_fixture_min= 0.0
V_fixture_max= 0.0
|time   V(typ)   V(min)   V(max)
0s        178.3uV    77.23uV    694.6uV
1.041ns   -14.18mV   82.72uV    -3.44mV
1.842ns   -2.941mV   -1.228mV   103.6mV
3.524ns   95.33mV    -1.383mV   773mV
5.285ns   405.3mV    851.6uV    1.505V
7.127ns   780.7mV    16.44mV    1.774V
10.01ns   1.198V     90.92mV    1.839V
13.21ns   1.33V      233.5mV    1.849V
23.06ns   1.369V     543mV      1.851V
39.88ns   1.369V     608.4mV    1.851V
[Falling Waveform]
R_fixture= 50.000000
V_fixture= 2.400000
V_fixture_min= 1.800000
V_fixture_max= 2.700000
|time   V(typ)   V(min)   V(max)
0s        2.399V     1.799V     2.698V
2.242ns   2.401V     1.801V     2.629V
3.924ns   2.37V      1.804V     1.92V
5.686ns   2.118V     1.798V     1.21V
6.567ns   1.94V      1.798V     1.012V
7.848ns   1.678V     1.798V     905.3mV
11.21ns   1.233V     1.759V     831.3mV
14.81ns   1.087V     1.636V     812.4mV
23.3ns    1.017V     1.354V     805mV
39.88ns   1.005V     1.245V     804.5mV
[Falling Waveform]
R_fixture= 50.000000
V_fixture= 0.0
V_fixture_min= 0.0
V_fixture_max= 0.0
|time   V(typ)   V(min)   V(max)
0s        1.369V     608.4mV    1.851V
380.4ps   1.369V     608.4mV    1.734V
820.8ps   1.337V     608.4mV    844.1mV
1.001ns   1.175V     608.1mV    559.7mV
1.241ns   860.5mV    607.8mV    346.2mV
1.642ns   408.7mV    608.8mV    156mV
1.942ns   225.4mV    614mV      84.75mV
2.743ns   50.86mV    459mV      17.71mV
4.264ns   5.795mV    47.86mV    1.477mV
9.97ns    178.3uV    77.23uV    694.6uV
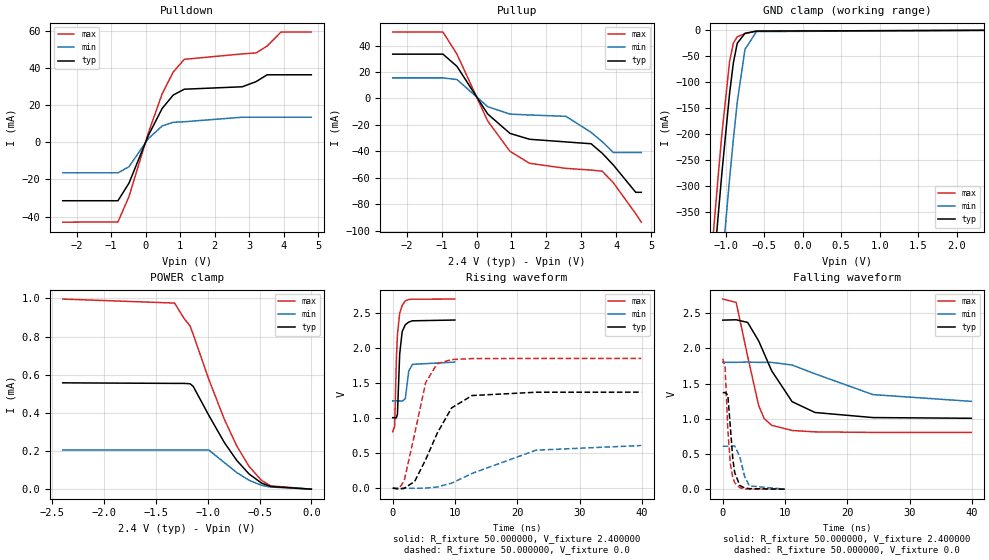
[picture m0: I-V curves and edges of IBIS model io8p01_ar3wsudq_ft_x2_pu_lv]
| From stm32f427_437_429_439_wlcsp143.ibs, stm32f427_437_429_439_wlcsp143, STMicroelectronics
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|   Model io8p01_ar3wsudq_ft_x2_pu_lv
[Model]  io8p01_ar3wsudq_ft_x2_pu_lv
Model_type I/O
Polarity   Non-Inverting
Enable   Active-Low
Vinl =   0.720000V
Vinh =   1.680000V
Vmeas =  1.200000V
Cref =   50.000000pF
Rref =   100.000000M
Vref =   0.0V
C_comp   7.427500pF   7.257100pF   7.608500pF
[Temperature Range]   25.000000   0.125000k   -40.000000
[Pullup Reference]   2.400000V   1.800000V   2.700000V
[Pulldown Reference]   0.0V   0.0V   0.0V
[POWER Clamp Reference]   2.400000V   1.800000V   2.700000V
[GND Clamp Reference]   0.0V   0.0V   0.0V
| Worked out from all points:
|   slope of the pulldown table from 0 to 0.36 V, typ, clamps not added: 25 ohm
|   slope of the pullup table from 0 to 0.36 V, typ, clamps not added: 27.7 ohm
|   GND clamp passes 1 mA (typ) near -0.56 V on its own axis
|   rising waveform, R_fixture 50.000000, V_fixture 2.400000: 20-80 % time 424ps typ, 453ps min, 456ps max; typ from 1.01 V to 2.4 V
|   rising waveform, R_fixture 50.000000, V_fixture 0.0: 20-80 % time 4.44ns typ, 9.22ns min, 2.61ns max; typ from 0.001 V to 1.37 V
|   falling waveform, R_fixture 50.000000, V_fixture 2.400000: 20-80 % time 4.99ns typ, 9.73ns min, 2.7ns max; typ from 2.4 V to 1.01 V
|   falling waveform, R_fixture 50.000000, V_fixture 0.0: 20-80 % time 776ps typ, 1.08ns min, 694ps max; typ from 1.37 V to 0.001 V
[Pulldown]
|Voltage   I(typ)   I(min)   I(max)
-2.4V     -31.47mA   -16.45mA   -43.01mA
-800mV    -31.47mA   -16.45mA   -42.85mA
-480mV    -21.98mA   -13.17mA   -29.21mA
80mV      3.63mA     1.966mA    5.014mA
480mV     18.16mA    8.738mA    26.02mA
800mV     25.38mA    10.72mA    37.77mA
1.12V     28.53mA    11.02mA    44.6mA
2.8V      29.84mA    13.47mA    47.53mA
3.2V      32.6mA     13.47mA    48.03mA
3.52V     36.29mA    13.47mA    51.75mA
3.92V     36.29mA    13.47mA    59.26mA
4.8V      36.29mA    13.47mA    59.26mA
[Pullup]
|Voltage   I(typ)   I(min)   I(max)
-2.4V     33.5mA     15.56mA    50.2mA
-960mV    33.5mA     15.56mA    50.2mA
-560mV    24.27mA    14.3mA     33.51mA
320mV     -11.75mA   -6.207mA   -17.08mA
960mV     -26.47mA   -11.82mA   -40.02mA
1.52V     -30.88mA   -12.51mA   -49.05mA
2.56V     -32.88mA   -13.52mA   -52.9mA
3.28V     -34.25mA   -25.6mA    -54.17mA
3.6V      -41.44mA   -32.7mA    -55.02mA
3.92V     -50.4mA    -40.9mA    -63.79mA
4.56V     -71mA      -40.9mA    -87.2mA
4.72V     -71mA      -40.9mA    -93.6mA
[GND_clamp]
|Voltage   I(typ)   I(min)   I(max)
-2.4V     -2.859A    -3.029A    -2.798A
-1.25V    -631.9mA   -814.4mA   -556.4mA
-1.2V     -540.2mA   -722.7mA   -464.2mA
-1.15V    -450mA     -632mA     -373.5mA
-1.1V     -361.8mA   -542.6mA   -285.3mA
-1.05V    -276.4mA   -454.9mA   -201.1mA
-950mV    -122.3mA   -287.2mA   -60.86mA
-900mV    -62.47mA   -209.5mA   -24.29mA
-850mV    -24.99mA   -138.8mA   -12.44mA
-750mV    -5.796mA   -36.69mA   -6.36mA
-600mV    -1.5mA     -2.436mA   -1.477mA
2.35V     0A         0A         0A
[POWER_clamp]
|Voltage   I(typ)   I(min)   I(max)
-2.4V     557.3uA    205.5uA    996.4uA
-1.32V    554.4uA    205.5uA    975.4uA
-1.23V    554.4uA    205.5uA    896uA
-1.17V    552.4uA    205.5uA    855.2uA
-1.14V    538.7uA    205.5uA    810.7uA
-990mV    387.4uA    205.5uA    576uA
-840mV    244.7uA    139.3uA    366.5uA
-720mV    150.8uA    87.02uA    226.9uA
-600mV    79.14uA    46.29uA    118.6uA
-480mV    31.63uA    20.18uA    45.53uA
-390mV    13.82uA    11.06uA    17.04uA
0V        0A         0A         0A
[Ramp]
| variable   typ   min   max
dV/dt_r  0.82207/4.43120n   0.36460/9.21047n   1.11077/2.60581n
dV/dt_f  0.83562/4.98379n   0.32136/9.68518n   1.13660/2.69449n
R_load = 50.000000
[Rising Waveform]
R_fixture= 50.000000
V_fixture= 2.400000
V_fixture_min= 1.800000
V_fixture_max= 2.700000
|time   V(typ)   V(min)   V(max)
0s        1.007V     1.247V     806mV
320.3ps   1.007V     1.247V     887.8mV
580.6ps   1.004V     1.247V     1.828V
760.8ps   1.059V     1.247V     2.196V
1.121ns   1.915V     1.247V     2.497V
1.522ns   2.236V     1.244V     2.609V
2.022ns   2.333V     1.279V     2.673V
2.563ns   2.37V      1.668V     2.693V
3.163ns   2.389V     1.768V     2.697V
9.97ns    2.4V       1.8V       2.699V
[Rising Waveform]
R_fixture= 50.000000
V_fixture= 0.0
V_fixture_min= 0.0
V_fixture_max= 0.0
|time   V(typ)   V(min)   V(max)
0s        1.058mV    917.1uV    1.605mV
1.041ns   -12.47mV   922.5uV    -113uV
1.842ns   -200.2uV   -381.9uV   107.5mV
3.524ns   98.37mV    478.2uV    776.1mV
5.285ns   408.1mV    2.777mV    1.508V
7.127ns   783.2mV    18.14mV    1.776V
9.449ns   1.147V     73.1mV     1.836V
12.73ns   1.323V     212.4mV    1.85V
22.98ns   1.37V      543.6mV    1.852V
39.88ns   1.371V     610.2mV    1.852V
[Falling Waveform]
R_fixture= 50.000000
V_fixture= 2.400000
V_fixture_min= 1.800000
V_fixture_max= 2.700000
|time   V(typ)   V(min)   V(max)
0s        2.4V       1.8V       2.699V
2.162ns   2.405V     1.801V     2.651V
4.004ns   2.367V     1.805V     1.885V
5.766ns   2.105V     1.8V       1.188V
6.647ns   1.927V     1.8V       1.003V
7.848ns   1.682V     1.8V       907.2mV
11.13ns   1.243V     1.763V     833.7mV
14.81ns   1.089V     1.638V     814mV
24.1ns    1.017V     1.343V     806.4mV
39.88ns   1.007V     1.247V     806mV
[Falling Waveform]
R_fixture= 50.000000
V_fixture= 0.0
V_fixture_min= 0.0
V_fixture_max= 0.0
|time   V(typ)   V(min)   V(max)
0s        1.371V     610.2mV    1.852V
380.4ps   1.371V     610.2mV    1.736V
820.8ps   1.339V     610.2mV    846.9mV
1.221ns   889.2mV    609.6mV    363mV
1.622ns   428.9mV    610.4mV    165.9mV
1.922ns   237mV      615.3mV    91.92mV
2.743ns   53.66mV    460.3mV    20.96mV
3.504ns   18.78mV    183.9mV    4.701mV
4.284ns   8.261mV    47.52mV    2.678mV
9.97ns    1.058mV    917.1uV    1.605mV
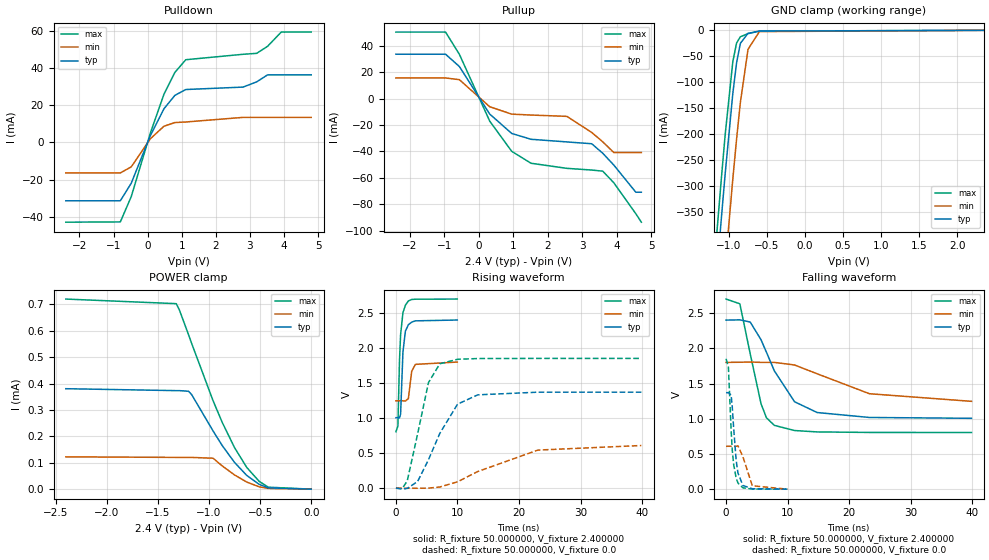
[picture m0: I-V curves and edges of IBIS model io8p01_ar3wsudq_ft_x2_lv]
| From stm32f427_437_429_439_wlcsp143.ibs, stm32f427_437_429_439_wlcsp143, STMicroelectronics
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|   Model io8p01_ar3wsudq_ft_x2_lv
[Model]  io8p01_ar3wsudq_ft_x2_lv
Model_type I/O
Polarity   Non-Inverting
Enable   Active-Low
Vinl =   0.720000V
Vinh =   1.680000V
Vmeas =  1.200000V
Cref =   50.000000pF
Rref =   100.000000M
Vref =   0.0V
C_comp   7.427500pF   7.257100pF   7.608500pF
[Temperature Range]   25.000000   0.125000k   -40.000000
[Pullup Reference]   2.400000V   1.800000V   2.700000V
[Pulldown Reference]   0.0V   0.0V   0.0V
[POWER Clamp Reference]   2.400000V   1.800000V   2.700000V
[GND Clamp Reference]   0.0V   0.0V   0.0V
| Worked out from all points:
|   slope of the pulldown table from 0 to 0.36 V, typ, clamps not added: 25 ohm
|   slope of the pullup table from 0 to 0.36 V, typ, clamps not added: 27.7 ohm
|   GND clamp passes 1 mA (typ) near -0.56 V on its own axis
|   rising waveform, R_fixture 50.000000, V_fixture 2.400000: 20-80 % time 426ps typ, 455ps min, 459ps max; typ from 1.01 V to 2.4 V
|   rising waveform, R_fixture 50.000000, V_fixture 0.0: 20-80 % time 4.43ns typ, 9.21ns min, 2.6ns max; typ from 0 V to 1.37 V
|   falling waveform, R_fixture 50.000000, V_fixture 2.400000: 20-80 % time 4.98ns typ, 9.68ns min, 2.7ns max; typ from 2.4 V to 1.01 V
|   falling waveform, R_fixture 50.000000, V_fixture 0.0: 20-80 % time 775ps typ, 1.08ns min, 694ps max; typ from 1.37 V to 0 V
[Pulldown]
|Voltage   I(typ)   I(min)   I(max)
-2.4V     -31.47mA   -16.45mA   -43.01mA
-800mV    -31.47mA   -16.45mA   -42.85mA
-480mV    -21.98mA   -13.17mA   -29.21mA
80mV      3.63mA     1.966mA    5.014mA
480mV     18.16mA    8.738mA    26.02mA
800mV     25.38mA    10.72mA    37.77mA
1.12V     28.53mA    11.02mA    44.6mA
2.8V      29.84mA    13.51mA    47.53mA
3.2V      32.66mA    13.51mA    48.04mA
3.52V     36.44mA    13.51mA    51.84mA
3.92V     36.44mA    13.51mA    59.5mA
4.8V      36.44mA    13.51mA    59.5mA
[Pullup]
|Voltage   I(typ)   I(min)   I(max)
-2.4V     33.58mA    15.57mA    50.35mA
-960mV    33.58mA    15.57mA    50.35mA
-560mV    24.29mA    14.31mA    33.54mA
320mV     -11.75mA   -6.207mA   -17.08mA
960mV     -26.47mA   -11.82mA   -40.02mA
1.52V     -30.88mA   -12.51mA   -49.05mA
2.56V     -32.88mA   -13.52mA   -52.9mA
3.28V     -34.25mA   -25.7mA    -54.18mA
3.6V      -41.44mA   -32.8mA    -55.03mA
3.92V     -50.4mA    -40.9mA    -63.8mA
4.56V     -71mA      -40.9mA    -87.3mA
4.72V     -71mA      -40.9mA    -93.7mA
[GND_clamp]
|Voltage   I(typ)   I(min)   I(max)
-2.4V     -2.859A    -3.029A    -2.798A
-1.25V    -631.9mA   -814.4mA   -556.4mA
-1.2V     -540.2mA   -722.7mA   -464.2mA
-1.15V    -450mA     -632mA     -373.5mA
-1.1V     -361.8mA   -542.6mA   -285.3mA
-1.05V    -276.4mA   -454.9mA   -201.1mA
-950mV    -122.3mA   -287.2mA   -60.86mA
-900mV    -62.47mA   -209.5mA   -24.29mA
-850mV    -24.99mA   -138.8mA   -12.44mA
-750mV    -5.796mA   -36.69mA   -6.36mA
-600mV    -1.5mA     -2.436mA   -1.477mA
2.35V     0A         0A         0A
[POWER_clamp]
|Voltage   I(typ)   I(min)   I(max)
-2.4V     380.4uA    122.4uA    719.8uA
-1.32V    373.1uA    120.3uA    702.4uA
-1.29V    373.1uA    120.3uA    679.3uA
-1.2V     370.8uA    120.2uA    585.1uA
-1.17V    358.5uA    120.2uA    552.5uA
-960mV    220.5uA    117.2uA    335uA
-870mV    164.9uA    87.99uA    252.6uA
-750mV    101.2uA    53.84uA    157.3uA
-630mV    51.89uA    26.83uA    82.04uA
-510mV    18.44uA    9.055uA    29.95uA
-420mV    4.85uA     2.76uA     7.499uA
0V        0A         0A         0A
[Ramp]
| variable   typ   min   max
dV/dt_r  0.82218/4.42510n   0.36439/9.19652n   1.11108/2.60300n
dV/dt_f  0.83634/4.98020n   0.32178/9.64092n   1.13726/2.69201n
R_load = 50.000000
[Rising Waveform]
R_fixture= 50.000000
V_fixture= 2.400000
V_fixture_min= 1.800000
V_fixture_max= 2.700000
|time   V(typ)   V(min)   V(max)
0s        1.006V     1.247V     804.9mV
320.3ps   1.006V     1.247V     886.5mV
580.6ps   1.003V     1.247V     1.825V
760.8ps   1.057V     1.247V     2.193V
1.141ns   1.944V     1.247V     2.504V
1.542ns   2.242V     1.244V     2.611V
2.022ns   2.332V     1.279V     2.672V
2.563ns   2.37V      1.668V     2.693V
3.163ns   2.388V     1.767V     2.697V
9.97ns    2.4V       1.8V       2.699V
[Rising Waveform]
R_fixture= 50.000000
V_fixture= 0.0
V_fixture_min= 0.0
V_fixture_max= 0.0
|time   V(typ)   V(min)   V(max)
0s        178.1uV    77.17uV    694.6uV
1.041ns   -14.18mV   82.71uV    -3.447mV
1.842ns   -2.946mV   -1.228mV   103.6mV
3.524ns   95.33mV    -1.386mV   773.2mV
5.285ns   405.4mV    849.4uV    1.506V
7.127ns   781.1mV    16.44mV    1.775V
10.01ns   1.199V     90.94mV    1.84V
13.29ns   1.332V     237.4mV    1.85V
23.06ns   1.37V      543.5mV    1.852V
39.88ns   1.37V      609mV      1.852V
[Falling Waveform]
R_fixture= 50.000000
V_fixture= 2.400000
V_fixture_min= 1.800000
V_fixture_max= 2.700000
|time   V(typ)   V(min)   V(max)
0s        2.4V       1.8V       2.699V
2.242ns   2.404V     1.802V     2.632V
3.924ns   2.373V     1.805V     1.923V
5.686ns   2.121V     1.8V       1.212V
6.567ns   1.943V     1.8V       1.013V
7.848ns   1.68V      1.8V       906.1mV
11.13ns   1.241V     1.763V     832.5mV
14.81ns   1.088V     1.638V     812.9mV
23.3ns    1.018V     1.355V     805.4mV
39.88ns   1.006V     1.247V     804.9mV
[Falling Waveform]
R_fixture= 50.000000
V_fixture= 0.0
V_fixture_min= 0.0
V_fixture_max= 0.0
|time   V(typ)   V(min)   V(max)
0s        1.37V      609mV      1.852V
380.4ps   1.37V      609.1mV    1.735V
820.8ps   1.338V     609mV      846.1mV
1.001ns   1.177V     608.8mV    561.8mV
1.241ns   861.9mV    608.5mV    348.3mV
1.642ns   410.2mV    609.4mV    157.9mV
1.942ns   226.9mV    614.6mV    86.21mV
2.743ns   51.94mV    459.6mV    18.71mV
4.264ns   6.213mV    48.33mV    1.575mV
9.97ns    178.1uV    77.17uV    694.6uV
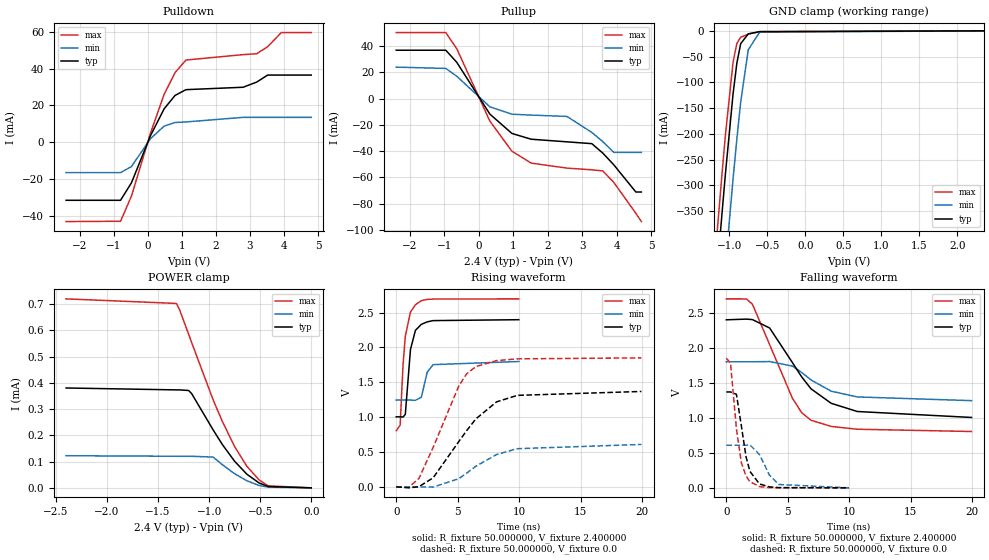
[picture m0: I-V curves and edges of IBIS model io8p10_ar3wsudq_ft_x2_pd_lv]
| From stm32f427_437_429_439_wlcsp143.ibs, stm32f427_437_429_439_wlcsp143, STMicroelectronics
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|   Model io8p10_ar3wsudq_ft_x2_pd_lv
[Model]  io8p10_ar3wsudq_ft_x2_pd_lv
Model_type I/O
Polarity   Non-Inverting
Enable   Active-Low
Vinl =   0.720000V
Vinh =   1.680000V
Vmeas =  1.200000V
Cref =   40.000000pF
Rref =   100.000000M
Vref =   0.0V
C_comp   7.427500pF   7.257100pF   7.608500pF
[Temperature Range]   25.000000   0.125000k   -40.000000
[Pullup Reference]   2.400000V   1.800000V   2.700000V
[Pulldown Reference]   0.0V   0.0V   0.0V
[POWER Clamp Reference]   2.400000V   1.800000V   2.700000V
[GND Clamp Reference]   0.0V   0.0V   0.0V
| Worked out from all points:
|   slope of the pulldown table from 0 to 0.36 V, typ, clamps not added: 25 ohm
|   slope of the pullup table from 0 to 0.36 V, typ, clamps not added: 27.7 ohm
|   GND clamp passes 1 mA (typ) near -0.56 V on its own axis
|   rising waveform, R_fixture 50.000000, V_fixture 2.400000: 20-80 % time 427ps typ, 463ps min, 459ps max; typ from 1 V to 2.4 V
|   rising waveform, R_fixture 50.000000, V_fixture 0.0: 20-80 % time 3.51ns typ, 3.4ns min, 2.64ns max; typ from 0 V to 1.37 V
|   falling waveform, R_fixture 50.000000, V_fixture 2.400000: 20-80 % time 3.61ns typ, 3.11ns min, 2.75ns max; typ from 2.4 V to 1 V
|   falling waveform, R_fixture 50.000000, V_fixture 0.0: 20-80 % time 772ps typ, 1.08ns min, 691ps max; typ from 1.37 V to 0 V
[Pulldown]
|Voltage   I(typ)   I(min)   I(max)
-2.4V     -31.47mA   -16.45mA   -43.01mA
-800mV    -31.47mA   -16.45mA   -42.85mA
-480mV    -21.98mA   -13.17mA   -29.21mA
80mV      3.63mA     1.966mA    5.014mA
480mV     18.15mA    8.738mA    26.02mA
800mV     25.38mA    10.72mA    37.77mA
1.12V     28.53mA    11.02mA    44.6mA
2.8V      29.84mA    13.51mA    47.53mA
3.2V      32.66mA    13.51mA    48.03mA
3.52V     36.44mA    13.51mA    51.84mA
3.92V     36.44mA    13.51mA    59.49mA
4.8V      36.44mA    13.51mA    59.49mA
[Pullup]
|Voltage   I(typ)   I(min)   I(max)
-2.4V     36.91mA    24.04mA    50.35mA
-960mV    36.91mA    23.05mA    50.35mA
-640mV    27.65mA    17.04mA    37.98mA
320mV     -11.75mA   -6.207mA   -17.08mA
960mV     -26.47mA   -11.82mA   -40.02mA
1.52V     -30.88mA   -12.51mA   -49.05mA
2.56V     -32.88mA   -13.52mA   -52.9mA
3.28V     -34.25mA   -25.7mA    -54.18mA
3.6V      -41.44mA   -32.7mA    -55.03mA
3.92V     -50.4mA    -40.9mA    -63.8mA
4.56V     -71.1mA    -40.9mA    -87.3mA
4.72V     -71.1mA    -40.9mA    -93.6mA
[GND_clamp]
|Voltage   I(typ)   I(min)   I(max)
-2.4V     -2.859A    -3.029A    -2.798A
-1.25V    -631.9mA   -814.4mA   -556.4mA
-1.2V     -540.2mA   -722.7mA   -464.2mA
-1.15V    -450mA     -632mA     -373.5mA
-1.1V     -361.8mA   -542.6mA   -285.3mA
-1.05V    -276.4mA   -454.9mA   -201.1mA
-950mV    -122.3mA   -287.2mA   -60.87mA
-900mV    -62.48mA   -209.5mA   -24.3mA
-850mV    -25mA      -138.8mA   -12.46mA
-750mV    -5.808mA   -36.7mA    -6.375mA
-600mV    -1.512mA   -2.445mA   -1.49mA
2.35V     58.09uA    37.93uA    67.25uA
[POWER_clamp]
|Voltage   I(typ)   I(min)   I(max)
-2.4V     380.4uA    122.4uA    719.8uA
-1.32V    373.1uA    120.3uA    702.4uA
-1.29V    373.1uA    120.3uA    679.3uA
-1.2V     370.8uA    120.2uA    585.1uA
-1.17V    358.5uA    120.2uA    552.5uA
-960mV    220.5uA    117.2uA    335uA
-870mV    164.9uA    87.99uA    252.6uA
-750mV    101.2uA    53.84uA    157.3uA
-630mV    51.89uA    26.83uA    82.04uA
-510mV    18.44uA    9.055uA    29.95uA
-420mV    4.85uA     2.76uA     7.499uA
0V        0A         0A         0A
[Ramp]
| variable   typ   min   max
dV/dt_r  0.82134/3.50657n   0.36482/3.39495n   1.11036/2.64028n
dV/dt_f  0.83268/3.59884n   0.33138/3.10094n   1.13573/2.74662n
R_load = 50.000000
[Rising Waveform]
R_fixture= 50.000000
V_fixture= 2.400000
V_fixture_min= 1.800000
V_fixture_max= 2.700000
|time   V(typ)   V(min)   V(max)
0s        1.005V     1.245V     804.5mV
320.3ps   1.005V     1.245V     886.5mV
560.6ps   1.002V     1.246V     1.765V
740.7ps   1.041V     1.246V     2.162V
1.161ns   1.972V     1.245V     2.51V
1.562ns   2.246V     1.242V     2.613V
2.042ns   2.332V     1.285V     2.673V
2.523ns   2.368V     1.647V     2.69V
3.003ns   2.386V     1.754V     2.695V
9.97ns    2.399V     1.799V     2.698V
[Rising Waveform]
R_fixture= 50.000000
V_fixture= 0.0
V_fixture_min= 0.0
V_fixture_max= 0.0
|time   V(typ)   V(min)   V(max)
0s        178.6uV    77.11uV    688.2uV
1.041ns   -14.42mV   82.06uV    -3.235mV
1.842ns   1.89mV     -1.373mV   118.5mV
3.003ns   129.1mV    -3.867mV   565.6mV
5.085ns   648.7mV    116.7mV    1.445V
5.726ns   806mV      197.1mV    1.622V
6.486ns   976.7mV    296.1mV    1.727V
8.168ns   1.22V      464.4mV    1.812V
9.85ns    1.313V     547.4mV    1.837V
19.94ns   1.369V     608.4mV    1.851V
[Falling Waveform]
R_fixture= 50.000000
V_fixture= 2.400000
V_fixture_min= 1.800000
V_fixture_max= 2.700000
|time   V(typ)   V(min)   V(max)
0s        2.399V     1.799V     2.698V
1.642ns   2.409V     1.799V     2.697V
2.122ns   2.402V     1.8V       2.622V
3.524ns   2.282V     1.803V     2.044V
5.365ns   1.791V     1.739V     1.283V
6.126ns   1.585V     1.648V     1.073V
6.887ns   1.414V     1.541V     964.8mV
8.529ns   1.207V     1.38V      877.1mV
10.65ns   1.09V      1.298V     836.9mV
19.94ns   1.005V     1.245V     804.5mV
[Falling Waveform]
R_fixture= 50.000000
V_fixture= 0.0
V_fixture_min= 0.0
V_fixture_max= 0.0
|time   V(typ)   V(min)   V(max)
0s        1.369V     608.4mV    1.851V
340.3ps   1.369V     608.4mV    1.782V
820.8ps   1.336V     608.3mV    843.8mV
1.221ns   886.8mV    607.9mV    359.7mV
1.602ns   443.9mV    608.5mV    169.2mV
1.922ns   234.3mV    613mV      88.07mV
2.703ns   54.81mV    474.5mV    17.17mV
3.504ns   13.68mV    182.3mV    2.651mV
4.264ns   3.279mV    47.94mV    1.423mV
9.97ns    178.6uV    77.11uV    688.2uV
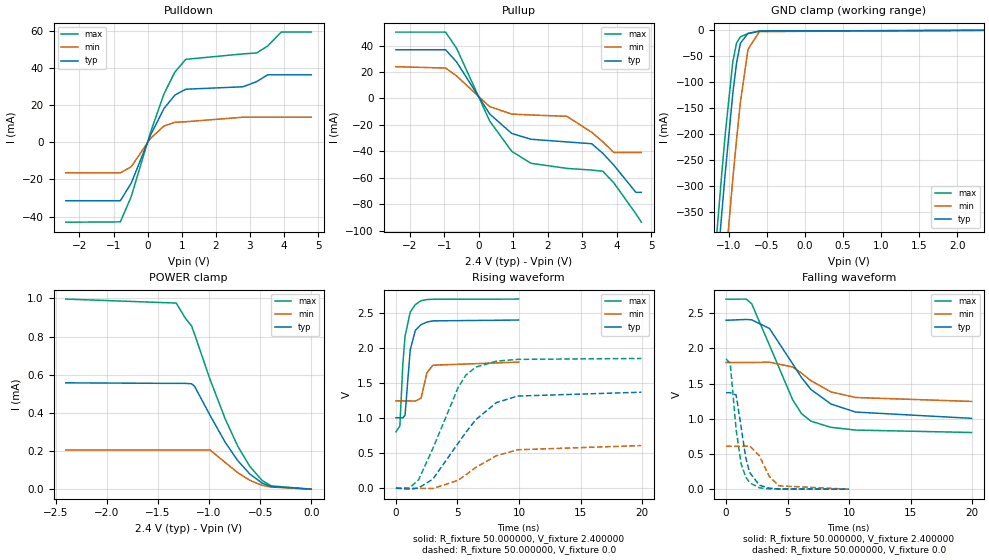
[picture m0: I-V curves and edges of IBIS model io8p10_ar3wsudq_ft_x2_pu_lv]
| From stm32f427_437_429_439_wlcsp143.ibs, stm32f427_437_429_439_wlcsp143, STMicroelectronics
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|   Model io8p10_ar3wsudq_ft_x2_pu_lv
[Model]  io8p10_ar3wsudq_ft_x2_pu_lv
Model_type I/O
Polarity   Non-Inverting
Enable   Active-Low
Vinl =   0.720000V
Vinh =   1.680000V
Vmeas =  1.200000V
Cref =   40.000000pF
Rref =   100.000000M
Vref =   0.0V
C_comp   7.427500pF   7.257100pF   7.608500pF
[Temperature Range]   25.000000   0.125000k   -40.000000
[Pullup Reference]   2.400000V   1.800000V   2.700000V
[Pulldown Reference]   0.0V   0.0V   0.0V
[POWER Clamp Reference]   2.400000V   1.800000V   2.700000V
[GND Clamp Reference]   0.0V   0.0V   0.0V
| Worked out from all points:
|   slope of the pulldown table from 0 to 0.36 V, typ, clamps not added: 25 ohm
|   slope of the pullup table from 0 to 0.36 V, typ, clamps not added: 27.7 ohm
|   GND clamp passes 1 mA (typ) near -0.56 V on its own axis
|   rising waveform, R_fixture 50.000000, V_fixture 2.400000: 20-80 % time 425ps typ, 460ps min, 456ps max; typ from 1.01 V to 2.4 V
|   rising waveform, R_fixture 50.000000, V_fixture 0.0: 20-80 % time 3.51ns typ, 3.41ns min, 2.65ns max; typ from 0.001 V to 1.37 V
|   falling waveform, R_fixture 50.000000, V_fixture 2.400000: 20-80 % time 3.61ns typ, 3.11ns min, 2.75ns max; typ from 2.4 V to 1.01 V
|   falling waveform, R_fixture 50.000000, V_fixture 0.0: 20-80 % time 777ps typ, 1.09ns min, 695ps max; typ from 1.37 V to 0.001 V
[Pulldown]
|Voltage   I(typ)   I(min)   I(max)
-2.4V     -31.47mA   -16.45mA   -43.01mA
-800mV    -31.47mA   -16.45mA   -42.85mA
-480mV    -21.98mA   -13.17mA   -29.21mA
80mV      3.63mA     1.966mA    5.014mA
480mV     18.16mA    8.738mA    26.02mA
800mV     25.38mA    10.72mA    37.77mA
1.12V     28.53mA    11.02mA    44.6mA
2.8V      29.84mA    13.47mA    47.53mA
3.2V      32.6mA     13.47mA    48.03mA
3.52V     36.29mA    13.47mA    51.75mA
3.92V     36.29mA    13.47mA    59.26mA
4.8V      36.29mA    13.47mA    59.26mA
[Pullup]
|Voltage   I(typ)   I(min)   I(max)
-2.4V     36.82mA    24.03mA    50.2mA
-960mV    36.82mA    23mA       50.2mA
-640mV    27.62mA    17.03mA    37.94mA
320mV     -11.75mA   -6.207mA   -17.08mA
960mV     -26.47mA   -11.82mA   -40.02mA
1.52V     -30.88mA   -12.51mA   -49.05mA
2.56V     -32.88mA   -13.52mA   -52.9mA
3.28V     -34.25mA   -25.6mA    -54.17mA
3.6V      -41.44mA   -32.7mA    -55.02mA
3.92V     -50.4mA    -40.9mA    -63.79mA
4.56V     -71mA      -40.9mA    -87.2mA
4.72V     -71mA      -40.9mA    -93.6mA
[GND_clamp]
|Voltage   I(typ)   I(min)   I(max)
-2.4V     -2.859A    -3.029A    -2.798A
-1.25V    -631.9mA   -814.4mA   -556.4mA
-1.2V     -540.2mA   -722.7mA   -464.2mA
-1.15V    -450mA     -632mA     -373.5mA
-1.1V     -361.8mA   -542.6mA   -285.3mA
-1.05V    -276.4mA   -454.9mA   -201.1mA
-950mV    -122.3mA   -287.2mA   -60.86mA
-900mV    -62.47mA   -209.5mA   -24.29mA
-850mV    -24.99mA   -138.8mA   -12.44mA
-750mV    -5.796mA   -36.69mA   -6.36mA
-600mV    -1.5mA     -2.436mA   -1.477mA
2.35V     0A         0A         0A
[POWER_clamp]
|Voltage   I(typ)   I(min)   I(max)
-2.4V     557.3uA    205.5uA    996.4uA
-1.32V    554.4uA    205.5uA    975.4uA
-1.23V    554.4uA    205.5uA    896uA
-1.17V    552.4uA    205.5uA    855.2uA
-1.14V    538.7uA    205.5uA    810.7uA
-990mV    387.4uA    205.5uA    576uA
-840mV    244.7uA    139.3uA    366.5uA
-720mV    150.8uA    87.02uA    226.9uA
-600mV    79.14uA    46.29uA    118.6uA
-480mV    31.63uA    20.18uA    45.53uA
-390mV    13.82uA    11.06uA    17.04uA
0V        0A         0A         0A
[Ramp]
| variable   typ   min   max
dV/dt_r  0.82189/3.50924n   0.36542/3.40505n   1.11077/2.64305n
dV/dt_f  0.83202/3.59545n   0.33078/3.09970n   1.13542/2.74718n
R_load = 50.000000
[Rising Waveform]
R_fixture= 50.000000
V_fixture= 2.400000
V_fixture_min= 1.800000
V_fixture_max= 2.700000
|time   V(typ)   V(min)   V(max)
0s        1.007V     1.247V     806.1mV
320.3ps   1.007V     1.247V     888.2mV
560.6ps   1.004V     1.247V     1.769V
740.7ps   1.043V     1.247V     2.166V
1.161ns   1.975V     1.247V     2.514V
1.582ns   2.255V     1.244V     2.621V
2.042ns   2.335V     1.287V     2.676V
2.523ns   2.371V     1.649V     2.692V
3.003ns   2.388V     1.756V     2.696V
9.97ns    2.4V       1.8V       2.699V
[Rising Waveform]
R_fixture= 50.000000
V_fixture= 0.0
V_fixture_min= 0.0
V_fixture_max= 0.0
|time   V(typ)   V(min)   V(max)
0s        1.059mV    916.9uV    1.598mV
1.081ns   -11.57mV   931.5uV    2.741mV
1.842ns   4.849mV    -525.8uV   122.5mV
3.003ns   132.3mV    -2.11mV    569.2mV
5.045ns   640.8mV    114.3mV    1.434V
5.686ns   798.8mV    193.9mV    1.616V
6.486ns   979.1mV    298.1mV    1.729V
8.168ns   1.223V     465.9mV    1.814V
9.89ns    1.316V     550.4mV    1.839V
19.94ns   1.371V     610.2mV    1.852V
[Falling Waveform]
R_fixture= 50.000000
V_fixture= 2.400000
V_fixture_min= 1.800000
V_fixture_max= 2.700000
|time   V(typ)   V(min)   V(max)
0s        2.4V       1.8V       2.699V
1.642ns   2.411V     1.8V       2.701V
2.082ns   2.406V     1.8V       2.635V
3.524ns   2.284V     1.804V     2.047V
5.405ns   1.783V     1.737V     1.273V
6.126ns   1.588V     1.649V     1.075V
6.887ns   1.418V     1.543V     967mV
8.529ns   1.21V      1.382V     879.2mV
10.53ns   1.096V     1.303V     840.1mV
19.94ns   1.007V     1.247V     806.1mV
[Falling Waveform]
R_fixture= 50.000000
V_fixture= 0.0
V_fixture_min= 0.0
V_fixture_max= 0.0
|time   V(typ)   V(min)   V(max)
0s        1.371V     610.2mV    1.852V
340.3ps   1.371V     610.2mV    1.784V
820.8ps   1.338V     610.1mV    846.7mV
1.221ns   888.5mV    609.7mV    362.9mV
1.602ns   446.9mV    610.3mV    172.8mV
1.922ns   237.1mV    614.8mV    91.79mV
2.703ns   57.82mV    476.1mV    20.17mV
3.504ns   16.15mV    184.3mV    4.168mV
4.284ns   4.749mV    48.25mV    2.588mV
9.97ns    1.059mV    916.9uV    1.598mV
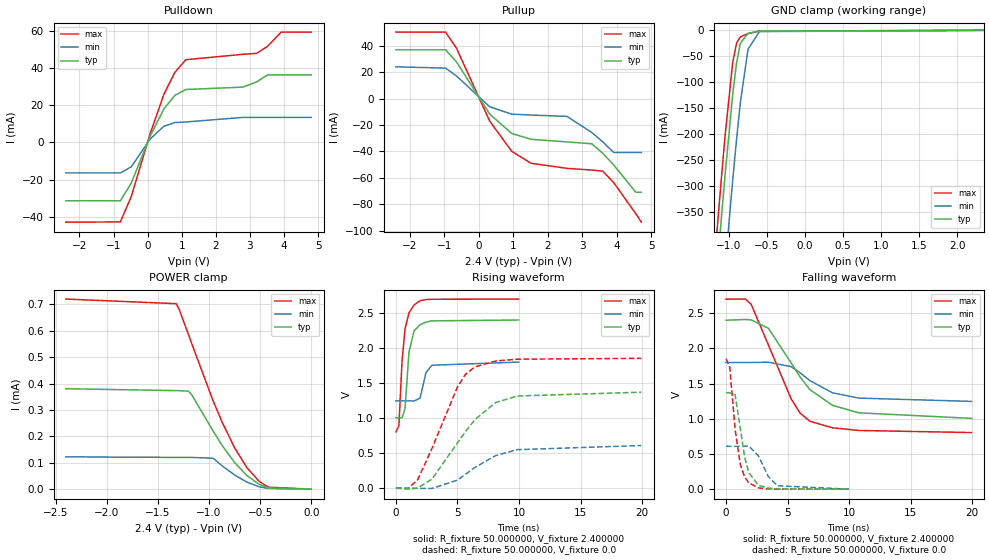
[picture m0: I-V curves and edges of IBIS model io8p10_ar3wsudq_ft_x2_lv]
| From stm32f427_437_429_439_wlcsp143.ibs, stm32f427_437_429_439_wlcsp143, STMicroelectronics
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|   Model io8p10_ar3wsudq_ft_x2_lv
[Model]  io8p10_ar3wsudq_ft_x2_lv
Model_type I/O
Polarity   Non-Inverting
Enable   Active-Low
Vinl =   0.720000V
Vinh =   1.680000V
Vmeas =  1.200000V
Cref =   40.000000pF
Rref =   100.000000M
Vref =   0.0V
C_comp   7.427500pF   7.257100pF   7.608500pF
[Temperature Range]   25.000000   0.125000k   -40.000000
[Pullup Reference]   2.400000V   1.800000V   2.700000V
[Pulldown Reference]   0.0V   0.0V   0.0V
[POWER Clamp Reference]   2.400000V   1.800000V   2.700000V
[GND Clamp Reference]   0.0V   0.0V   0.0V
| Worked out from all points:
|   slope of the pulldown table from 0 to 0.36 V, typ, clamps not added: 25 ohm
|   slope of the pullup table from 0 to 0.36 V, typ, clamps not added: 27.7 ohm
|   GND clamp passes 1 mA (typ) near -0.56 V on its own axis
|   rising waveform, R_fixture 50.000000, V_fixture 2.400000: 20-80 % time 427ps typ, 461ps min, 459ps max; typ from 1.01 V to 2.4 V
|   rising waveform, R_fixture 50.000000, V_fixture 0.0: 20-80 % time 3.51ns typ, 3.4ns min, 2.64ns max; typ from 0 V to 1.37 V
|   falling waveform, R_fixture 50.000000, V_fixture 2.400000: 20-80 % time 3.61ns typ, 3.12ns min, 2.75ns max; typ from 2.4 V to 1.01 V
|   falling waveform, R_fixture 50.000000, V_fixture 0.0: 20-80 % time 776ps typ, 1.09ns min, 694ps max; typ from 1.37 V to 0 V
[Pulldown]
|Voltage   I(typ)   I(min)   I(max)
-2.4V     -31.47mA   -16.45mA   -43.01mA
-800mV    -31.47mA   -16.45mA   -42.85mA
-480mV    -21.98mA   -13.17mA   -29.21mA
80mV      3.63mA     1.966mA    5.014mA
480mV     18.16mA    8.738mA    26.02mA
800mV     25.38mA    10.72mA    37.77mA
1.12V     28.53mA    11.02mA    44.6mA
2.8V      29.84mA    13.51mA    47.53mA
3.2V      32.66mA    13.51mA    48.04mA
3.52V     36.44mA    13.51mA    51.84mA
3.92V     36.44mA    13.51mA    59.5mA
4.8V      36.44mA    13.51mA    59.5mA
[Pullup]
|Voltage   I(typ)   I(min)   I(max)
-2.4V     36.92mA    24.04mA    50.35mA
-960mV    36.92mA    23.05mA    50.35mA
-640mV    27.65mA    17.04mA    37.98mA
320mV     -11.75mA   -6.207mA   -17.08mA
960mV     -26.47mA   -11.82mA   -40.02mA
1.52V     -30.88mA   -12.51mA   -49.05mA
2.56V     -32.88mA   -13.52mA   -52.9mA
3.28V     -34.25mA   -25.7mA    -54.18mA
3.6V      -41.44mA   -32.8mA    -55.03mA
3.92V     -50.4mA    -40.9mA    -63.8mA
4.56V     -71mA      -40.9mA    -87.3mA
4.72V     -71mA      -40.9mA    -93.7mA
[GND_clamp]
|Voltage   I(typ)   I(min)   I(max)
-2.4V     -2.859A    -3.029A    -2.798A
-1.25V    -631.9mA   -814.4mA   -556.4mA
-1.2V     -540.2mA   -722.7mA   -464.2mA
-1.15V    -450mA     -632mA     -373.5mA
-1.1V     -361.8mA   -542.6mA   -285.3mA
-1.05V    -276.4mA   -454.9mA   -201.1mA
-950mV    -122.3mA   -287.2mA   -60.86mA
-900mV    -62.47mA   -209.5mA   -24.29mA
-850mV    -24.99mA   -138.8mA   -12.44mA
-750mV    -5.796mA   -36.69mA   -6.36mA
-600mV    -1.5mA     -2.436mA   -1.477mA
2.35V     0A         0A         0A
[POWER_clamp]
|Voltage   I(typ)   I(min)   I(max)
-2.4V     380.4uA    122.4uA    719.8uA
-1.32V    373.1uA    120.3uA    702.4uA
-1.29V    373.1uA    120.3uA    679.3uA
-1.2V     370.8uA    120.2uA    585.1uA
-1.17V    358.5uA    120.2uA    552.5uA
-960mV    220.5uA    117.2uA    335uA
-870mV    164.9uA    87.99uA    252.6uA
-750mV    101.2uA    53.84uA    157.3uA
-630mV    51.89uA    26.83uA    82.04uA
-510mV    18.44uA    9.055uA    29.95uA
-420mV    4.85uA     2.76uA     7.499uA
0V        0A         0A         0A
[Ramp]
| variable   typ   min   max
dV/dt_r  0.82194/3.50788n   0.36520/3.39835n   1.11102/2.64008n
dV/dt_f  0.83274/3.59627n   0.33114/3.10150n   1.13608/2.74534n
R_load = 50.000000
[Rising Waveform]
R_fixture= 50.000000
V_fixture= 2.400000
V_fixture_min= 1.800000
V_fixture_max= 2.700000
|time   V(typ)   V(min)   V(max)
0s        1.006V     1.247V     804.2mV
240.2ps   1.006V     1.247V     887mV
500.5ps   1.003V     1.247V     1.825V
740.7ps   1.138V     1.247V     2.272V
1.061ns   1.944V     1.247V     2.503V
1.481ns   2.247V     1.244V     2.615V
1.962ns   2.334V     1.286V     2.675V
2.442ns   2.37V      1.649V     2.692V
2.923ns   2.388V     1.755V     2.696V
9.97ns    2.4V       1.8V       2.699V
[Rising Waveform]
R_fixture= 50.000000
V_fixture= 0.0
V_fixture_min= 0.0
V_fixture_max= 0.0
|time   V(typ)   V(min)   V(max)
0s        159.7uV    69.85uV    936.5uV
1.001ns   -13.4mV    91.81uV    -592.6uV
1.762ns   1.884mV    -1.373mV   118.6mV
2.923ns   129.1mV    -3.871mV   566.2mV
5.005ns   648.8mV    116.7mV    1.447V
5.646ns   806.2mV    197.1mV    1.624V
6.406ns   977.1mV    296.1mV    1.73V
8.088ns   1.221V     464.6mV    1.815V
9.85ns    1.316V     550.3mV    1.841V
19.94ns   1.37V      609mV      1.853V
[Falling Waveform]
R_fixture= 50.000000
V_fixture= 2.400000
V_fixture_min= 1.800000
V_fixture_max= 2.700000
|time   V(typ)   V(min)   V(max)
0s        2.4V       1.8V       2.699V
1.562ns   2.411V     1.8V       2.701V
2.042ns   2.405V     1.8V       2.626V
3.443ns   2.285V     1.804V     2.047V
5.285ns   1.794V     1.741V     1.285V
6.006ns   1.597V     1.655V     1.082V
6.807ns   1.415V     1.543V     965.3mV
8.649ns   1.191V     1.369V     871.9mV
10.77ns   1.085V     1.294V     834.3mV
19.94ns   1.006V     1.247V     804.2mV
[Falling Waveform]
R_fixture= 50.000000
V_fixture= 0.0
V_fixture_min= 0.0
V_fixture_max= 0.0
|time   V(typ)   V(min)   V(max)
0s        1.37V      609mV      1.853V
300.3ps   1.37V      609mV      1.734V
740.7ps   1.337V     609mV      846mV
1.161ns   861.2mV    608.5mV    348.4mV
1.502ns   464.3mV    609.1mV    178.5mV
1.842ns   235.7mV    613.6mV    90.06mV
2.623ns   56.02mV    475.1mV    18.28mV
3.423ns   14.34mV    182.9mV    3.113mV
4.184ns   3.466mV    48.43mV    1.766mV
9.97ns    159.7uV    69.85uV    936.5uV
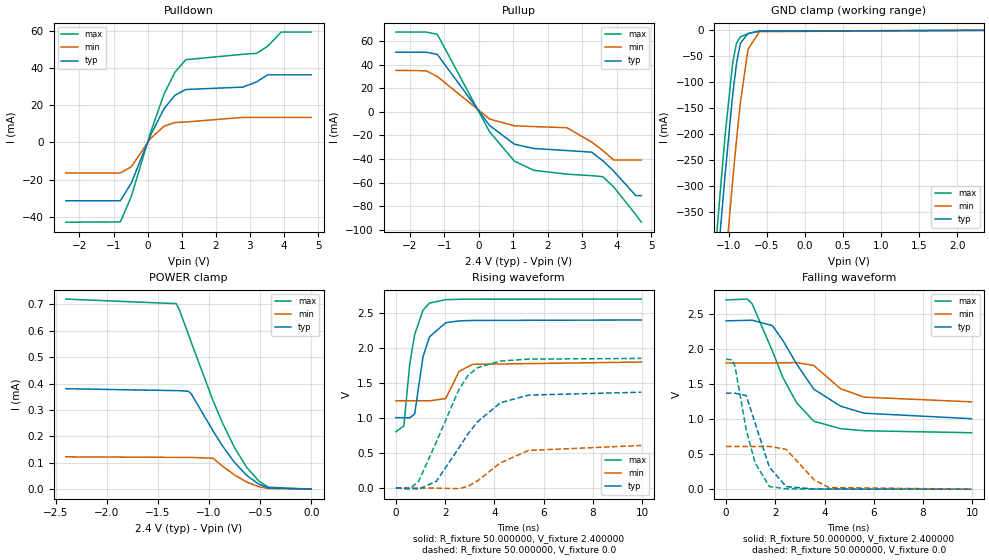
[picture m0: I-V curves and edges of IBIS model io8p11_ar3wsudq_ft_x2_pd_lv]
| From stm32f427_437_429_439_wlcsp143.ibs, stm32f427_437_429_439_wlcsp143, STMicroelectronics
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|   Model io8p11_ar3wsudq_ft_x2_pd_lv
[Model]  io8p11_ar3wsudq_ft_x2_pd_lv
Model_type I/O
Polarity   Non-Inverting
Enable   Active-Low
Vinl =   0.720000V
Vinh =   1.680000V
Vmeas =  1.200000V
Cref =   30.000000pF
Rref =   100.000000M
Vref =   0.0V
C_comp   7.427500pF   7.257100pF   7.608500pF
[Temperature Range]   25.000000   0.125000k   -40.000000
[Pullup Reference]   2.400000V   1.800000V   2.700000V
[Pulldown Reference]   0.0V   0.0V   0.0V
[POWER Clamp Reference]   2.400000V   1.800000V   2.700000V
[GND Clamp Reference]   0.0V   0.0V   0.0V
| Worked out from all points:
|   slope of the pulldown table from 0 to 0.36 V, typ, clamps not added: 25 ohm
|   slope of the pullup table from 0 to 0.36 V, typ, clamps not added: 27.7 ohm
|   GND clamp passes 1 mA (typ) near -0.56 V on its own axis
|   rising waveform, R_fixture 50.000000, V_fixture 2.400000: 20-80 % time 431ps typ, 462ps min, 453ps max; typ from 1 V to 2.4 V
|   rising waveform, R_fixture 50.000000, V_fixture 0.0: 20-80 % time 1.71ns typ, 1.53ns min, 1.36ns max; typ from 0 V to 1.37 V
|   falling waveform, R_fixture 50.000000, V_fixture 2.400000: 20-80 % time 1.72ns typ, 1.3ns min, 1.45ns max; typ from 2.4 V to 1 V
|   falling waveform, R_fixture 50.000000, V_fixture 0.0: 20-80 % time 755ps typ, 949ps min, 674ps max; typ from 1.37 V to 0 V
[Pulldown]
|Voltage   I(typ)   I(min)   I(max)
-2.4V     -31.47mA   -16.45mA   -43.01mA
-800mV    -31.47mA   -16.45mA   -42.85mA
-480mV    -21.98mA   -13.17mA   -29.21mA
80mV      3.63mA     1.966mA    5.014mA
480mV     18.15mA    8.738mA    26.02mA
800mV     25.38mA    10.72mA    37.77mA
1.12V     28.53mA    11.02mA    44.6mA
2.8V      29.84mA    13.51mA    47.53mA
3.2V      32.66mA    13.51mA    48.03mA
3.52V     36.44mA    13.51mA    51.84mA
3.92V     36.44mA    13.51mA    59.49mA
4.8V      36.44mA    13.51mA    59.49mA
[Pullup]
|Voltage   I(typ)   I(min)   I(max)
-2.4V     50.45mA    35.08mA    67.51mA
-1.52V    50.45mA    34.74mA    67.51mA
-1.2V     48.64mA    29.87mA    65.66mA
320mV     -11.75mA   -6.207mA   -17.08mA
1.04V     -27.53mA   -11.97mA   -41.91mA
1.6V      -31.13mA   -12.58mA   -49.63mA
2.56V     -32.88mA   -13.52mA   -52.9mA
3.28V     -34.25mA   -25.7mA    -54.18mA
3.6V      -41.44mA   -32.8mA    -55.03mA
3.92V     -50.4mA    -40.9mA    -63.8mA
4.56V     -71.1mA    -40.9mA    -87.3mA
4.72V     -71.1mA    -40.9mA    -93.6mA
[GND_clamp]
|Voltage   I(typ)   I(min)   I(max)
-2.4V     -2.859A    -3.028A    -2.797A
-1.25V    -631.9mA   -814.4mA   -556.4mA
-1.2V     -540.2mA   -722.7mA   -464.2mA
-1.15V    -450mA     -632mA     -373.5mA
-1.1V     -361.8mA   -542.6mA   -285.3mA
-1.05V    -276.4mA   -454.9mA   -201.1mA
-950mV    -122.3mA   -287.2mA   -60.87mA
-900mV    -62.48mA   -209.5mA   -24.3mA
-850mV    -25mA      -138.8mA   -12.46mA
-750mV    -5.808mA   -36.7mA    -6.375mA
-600mV    -1.512mA   -2.445mA   -1.49mA
2.35V     58.09uA    37.93uA    67.25uA
[POWER_clamp]
|Voltage   I(typ)   I(min)   I(max)
-2.4V     380.4uA    122.4uA    719.8uA
-1.32V    373.1uA    120.3uA    702.4uA
-1.29V    373.1uA    120.3uA    679.3uA
-1.2V     370.8uA    120.2uA    585.1uA
-1.17V    358.5uA    120.2uA    552.5uA
-960mV    220.5uA    117.2uA    335uA
-870mV    164.9uA    87.99uA    252.6uA
-750mV    101.2uA    53.84uA    157.3uA
-630mV    51.89uA    26.83uA    82.04uA
-510mV    18.44uA    9.055uA    29.95uA
-420mV    4.85uA     2.76uA     7.499uA
0V        0A         0A         0A
[Ramp]
| variable   typ   min   max
dV/dt_r  0.82086/1.70696n   0.36307/1.51971n   1.11030/1.35582n
dV/dt_f  0.83148/1.70642n   0.33114/1.29158n   1.13513/1.44722n
R_load = 50.000000
[Rising Waveform]
R_fixture= 50.000000
V_fixture= 2.400000
V_fixture_min= 1.800000
V_fixture_max= 2.700000
|time   V(typ)   V(min)   V(max)
0s        1.005V     1.245V     804.5mV
320.3ps   1.005V     1.245V     886.1mV
560.6ps   1.002V     1.246V     1.765V
760.8ps   1.057V     1.246V     2.191V
1.101ns   1.876V     1.245V     2.539V
1.361ns   2.157V     1.245V     2.64V
2.022ns   2.36V      1.278V     2.689V
2.563ns   2.386V     1.664V     2.695V
3.103ns   2.393V     1.766V     2.697V
9.97ns    2.399V     1.799V     2.698V
[Rising Waveform]
R_fixture= 50.000000
V_fixture= 0.0
V_fixture_min= 0.0
V_fixture_max= 0.0
|time   V(typ)   V(min)   V(max)
0s        175.3uV    75.15uV    767.3uV
540.5ps   -475uV     50.81uV    -14.29mV
920.9ps   -15.25mV   60.52uV    94.12mV
1.642ns   96.39mV    -60.55uV   659mV
2.543ns   566.5mV    -7.994mV   1.395V
2.923ns   771.5mV    24.47mV    1.606V
3.323ns   949.3mV    105.3mV    1.72V
4.244ns   1.218V     359.8mV    1.813V
5.385ns   1.327V     537.2mV    1.841V
9.97ns    1.369V     608.4mV    1.851V
[Falling Waveform]
R_fixture= 50.000000
V_fixture= 2.400000
V_fixture_min= 1.800000
V_fixture_max= 2.700000
|time   V(typ)   V(min)   V(max)
0s        2.399V     1.799V     2.698V
860.9ps   2.407V     1.799V     2.71V
1.061ns   2.409V     1.799V     2.642V
1.882ns   2.332V     1.799V     1.971V
2.302ns   2.123V     1.802V     1.597V
2.863ns   1.786V     1.804V     1.233V
3.564ns   1.426V     1.763V     968.9mV
4.645ns   1.184V     1.433V     862.9mV
5.606ns   1.083V     1.312V     833mV
9.97ns    1.005V     1.245V     804.5mV
[Falling Waveform]
R_fixture= 50.000000
V_fixture= 0.0
V_fixture_min= 0.0
V_fixture_max= 0.0
|time   V(typ)   V(min)   V(max)
0s        1.369V     608.4mV    1.851V
240.2ps   1.369V     608.4mV    1.846V
360.4ps   1.369V     608.4mV    1.758V
820.8ps   1.334V     608.3mV    842.4mV
1.181ns   939.7mV    608mV      376.1mV
1.762ns   311.8mV    609.8mV    37.13mV
2.442ns   36.43mV    567.7mV    4.882mV
3.584ns   3.129mV    131.2mV    1.813mV
4.184ns   1.827mV    23.15mV    1.39mV
9.97ns    175.3uV    75.15uV    767.3uV
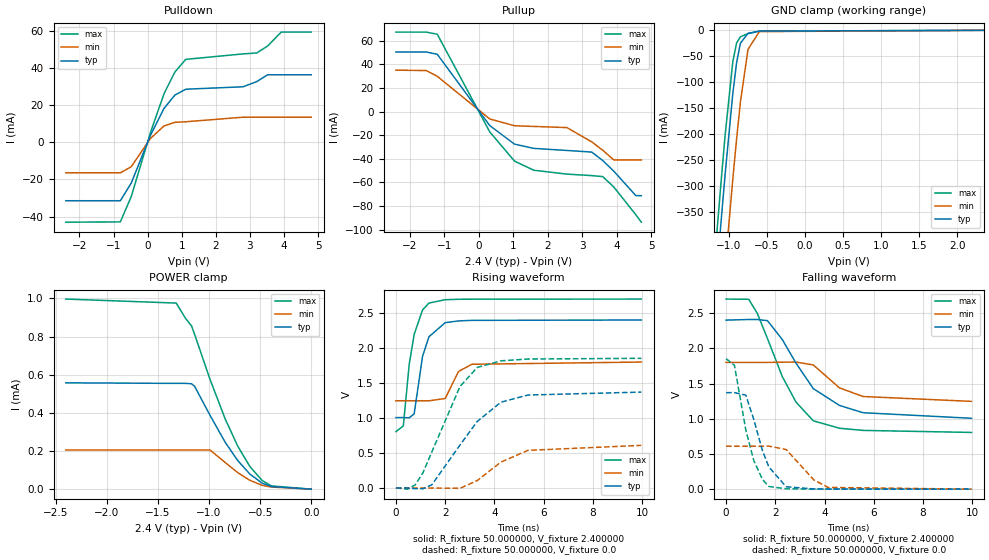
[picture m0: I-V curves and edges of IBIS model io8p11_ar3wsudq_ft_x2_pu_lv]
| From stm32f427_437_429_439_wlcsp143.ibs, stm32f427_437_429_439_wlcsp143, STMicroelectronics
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|   Model io8p11_ar3wsudq_ft_x2_pu_lv
[Model]  io8p11_ar3wsudq_ft_x2_pu_lv
Model_type I/O
Polarity   Non-Inverting
Enable   Active-Low
Vinl =   0.720000V
Vinh =   1.680000V
Vmeas =  1.200000V
Cref =   30.000000pF
Rref =   100.000000M
Vref =   0.0V
C_comp   7.427500pF   7.257100pF   7.608500pF
[Temperature Range]   25.000000   0.125000k   -40.000000
[Pullup Reference]   2.400000V   1.800000V   2.700000V
[Pulldown Reference]   0.0V   0.0V   0.0V
[POWER Clamp Reference]   2.400000V   1.800000V   2.700000V
[GND Clamp Reference]   0.0V   0.0V   0.0V
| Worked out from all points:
|   slope of the pulldown table from 0 to 0.36 V, typ, clamps not added: 25 ohm
|   slope of the pullup table from 0 to 0.36 V, typ, clamps not added: 27.7 ohm
|   GND clamp passes 1 mA (typ) near -0.56 V on its own axis
|   rising waveform, R_fixture 50.000000, V_fixture 2.400000: 20-80 % time 428ps typ, 460ps min, 450ps max; typ from 1.01 V to 2.4 V
|   rising waveform, R_fixture 50.000000, V_fixture 0.0: 20-80 % time 1.71ns typ, 1.53ns min, 1.36ns max; typ from 0.001 V to 1.37 V
|   falling waveform, R_fixture 50.000000, V_fixture 2.400000: 20-80 % time 1.72ns typ, 1.3ns min, 1.45ns max; typ from 2.4 V to 1.01 V
|   falling waveform, R_fixture 50.000000, V_fixture 0.0: 20-80 % time 757ps typ, 953ps min, 677ps max; typ from 1.37 V to 0.001 V
[Pulldown]
|Voltage   I(typ)   I(min)   I(max)
-2.4V     -31.47mA   -16.45mA   -43.01mA
-800mV    -31.47mA   -16.45mA   -42.85mA
-480mV    -21.98mA   -13.17mA   -29.21mA
80mV      3.63mA     1.966mA    5.014mA
480mV     18.16mA    8.738mA    26.02mA
800mV     25.38mA    10.72mA    37.77mA
1.12V     28.53mA    11.02mA    44.6mA
2.8V      29.84mA    13.47mA    47.53mA
3.2V      32.6mA     13.47mA    48.03mA
3.52V     36.29mA    13.47mA    51.75mA
3.92V     36.29mA    13.47mA    59.26mA
4.8V      36.29mA    13.47mA    59.26mA
[Pullup]
|Voltage   I(typ)   I(min)   I(max)
-2.4V     50.45mA    35.08mA    67.3mA
-1.52V    50.45mA    34.74mA    67.3mA
-1.2V     48.51mA    29.87mA    65.47mA
320mV     -11.75mA   -6.207mA   -17.08mA
1.04V     -27.53mA   -11.97mA   -41.91mA
1.6V      -31.13mA   -12.57mA   -49.63mA
2.56V     -32.88mA   -13.52mA   -52.9mA
3.28V     -34.25mA   -25.6mA    -54.17mA
3.6V      -41.44mA   -32.7mA    -55.02mA
3.92V     -50.4mA    -40.9mA    -63.79mA
4.56V     -71.1mA    -40.9mA    -87.3mA
4.72V     -71.1mA    -40.9mA    -93.6mA
[GND_clamp]
|Voltage   I(typ)   I(min)   I(max)
-2.4V     -2.859A    -3.029A    -2.798A
-1.25V    -631.9mA   -814.4mA   -556.4mA
-1.2V     -540.2mA   -722.7mA   -464.2mA
-1.15V    -450mA     -632mA     -373.5mA
-1.1V     -361.8mA   -542.6mA   -285.3mA
-1.05V    -276.4mA   -454.9mA   -201.1mA
-950mV    -122.3mA   -287.2mA   -60.86mA
-900mV    -62.47mA   -209.5mA   -24.29mA
-850mV    -24.99mA   -138.8mA   -12.44mA
-750mV    -5.796mA   -36.69mA   -6.36mA
-600mV    -1.5mA     -2.436mA   -1.477mA
2.35V     0A         0A         0A
[POWER_clamp]
|Voltage   I(typ)   I(min)   I(max)
-2.4V     557.3uA    205.5uA    996.4uA
-1.32V    554.4uA    205.5uA    975.4uA
-1.23V    554.4uA    205.5uA    896uA
-1.17V    552.4uA    205.5uA    855.2uA
-1.14V    538.7uA    205.5uA    810.7uA
-990mV    387.4uA    205.5uA    576uA
-840mV    244.7uA    139.3uA    366.5uA
-720mV    150.8uA    87.02uA    226.9uA
-600mV    79.14uA    46.29uA    118.6uA
-480mV    31.63uA    20.18uA    45.53uA
-390mV    13.82uA    11.06uA    17.04uA
0V        0A         0A         0A
[Ramp]
| variable   typ   min   max
dV/dt_r  0.82141/1.70915n   0.36362/1.52316n   1.11071/1.35783n
dV/dt_f  0.83082/1.70510n   0.33054/1.29047n   1.13480/1.44708n
R_load = 50.000000
[Rising Waveform]
R_fixture= 50.000000
V_fixture= 2.400000
V_fixture_min= 1.800000
V_fixture_max= 2.700000
|time   V(typ)   V(min)   V(max)
0s        1.007V     1.247V     806mV
300.3ps   1.007V     1.247V     887.8mV
540.5ps   1.004V     1.247V     1.769V
740.7ps   1.059V     1.247V     2.195V
1.081ns   1.88V      1.247V     2.543V
1.341ns   2.161V     1.246V     2.642V
2.002ns   2.362V     1.28V      2.69V
2.543ns   2.387V     1.666V     2.696V
3.083ns   2.395V     1.768V     2.697V
9.97ns    2.4V       1.8V       2.699V
[Rising Waveform]
R_fixture= 50.000000
V_fixture= 0.0
V_fixture_min= 0.0
V_fixture_max= 0.0
|time   V(typ)   V(min)   V(max)
0s        1.048mV    913.2uV    1.774mV
480.5ps   1.082mV    890.8uV    -15.07mV
780.8ps   -8.219mV   890.5uV    44.92mV
1.101ns   -8.95mV    951uV      221.4mV
1.461ns   48.43mV    1.105mV    518mV
2.603ns   615.1mV    -2.737mV   1.451V
3.303ns   951.8mV    107.9mV    1.723V
4.264ns   1.227V     371mV      1.817V
5.365ns   1.329V     539mV      1.843V
9.97ns    1.371V     610.2mV    1.853V
[Falling Waveform]
R_fixture= 50.000000
V_fixture= 2.400000
V_fixture_min= 1.800000
V_fixture_max= 2.700000
|time   V(typ)   V(min)   V(max)
0s        2.4V       1.8V       2.699V
920.9ps   2.409V     1.8V       2.696V
1.261ns   2.409V     1.8V       2.502V
1.682ns   2.393V     1.8V       2.14V
2.282ns   2.126V     1.803V     1.601V
2.843ns   1.789V     1.805V     1.236V
3.544ns   1.428V     1.764V     971.1mV
4.605ns   1.19V      1.439V     865.7mV
5.566ns   1.086V     1.316V     834.9mV
9.97ns    1.007V     1.247V     806mV
[Falling Waveform]
R_fixture= 50.000000
V_fixture= 0.0
V_fixture_min= 0.0
V_fixture_max= 0.0
|time   V(typ)   V(min)   V(max)
0s        1.371V     610.2mV    1.853V
340.3ps   1.371V     610.2mV    1.759V
800.8ps   1.336V     610.1mV    845.3mV
1.121ns   996.9mV    609.9mV    414.3mV
1.481ns   545.7mV    610.1mV    136.5mV
1.742ns   314.6mV    611.6mV    39.06mV
2.442ns   35.4mV     563.6mV    5.958mV
3.564ns   4.142mV    133.2mV    2.882mV
4.144ns   2.821mV    25.71mV    2.447mV
9.97ns    1.048mV    913.2uV    1.774mV
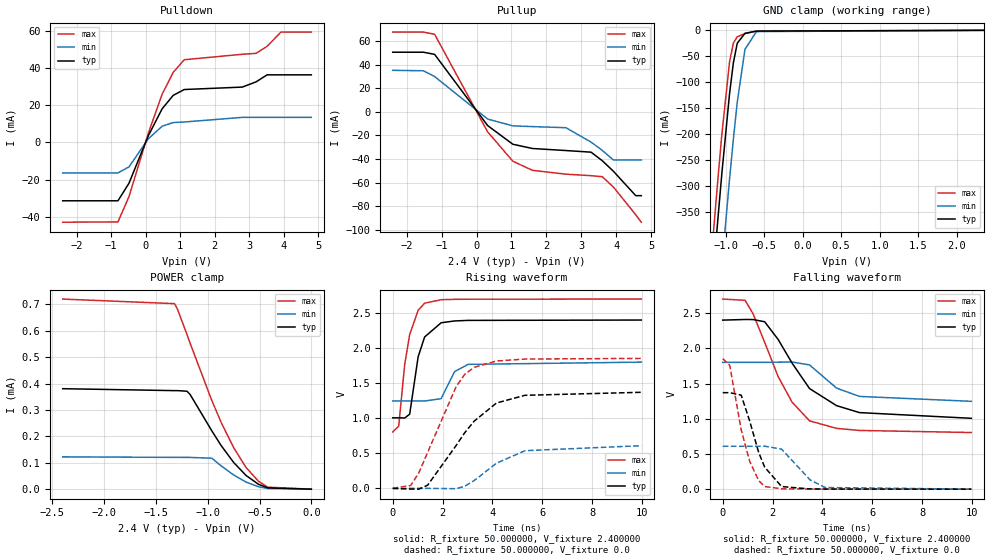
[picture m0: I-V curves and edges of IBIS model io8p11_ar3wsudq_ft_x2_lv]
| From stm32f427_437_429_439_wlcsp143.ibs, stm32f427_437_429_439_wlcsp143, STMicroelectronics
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|   Model io8p11_ar3wsudq_ft_x2_lv
[Model]  io8p11_ar3wsudq_ft_x2_lv
Model_type I/O
Polarity   Non-Inverting
Enable   Active-Low
Vinl =   0.720000V
Vinh =   1.680000V
Vmeas =  1.200000V
Cref =   30.000000pF
Rref =   100.000000M
Vref =   0.0V
C_comp   7.427500pF   7.257100pF   7.608500pF
[Temperature Range]   25.000000   0.125000k   -40.000000
[Pullup Reference]   2.400000V   1.800000V   2.700000V
[Pulldown Reference]   0.0V   0.0V   0.0V
[POWER Clamp Reference]   2.400000V   1.800000V   2.700000V
[GND Clamp Reference]   0.0V   0.0V   0.0V
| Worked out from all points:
|   slope of the pulldown table from 0 to 0.36 V, typ, clamps not added: 25 ohm
|   slope of the pullup table from 0 to 0.36 V, typ, clamps not added: 27.7 ohm
|   GND clamp passes 1 mA (typ) near -0.56 V on its own axis
|   rising waveform, R_fixture 50.000000, V_fixture 2.400000: 20-80 % time 430ps typ, 461ps min, 453ps max; typ from 1.01 V to 2.4 V
|   rising waveform, R_fixture 50.000000, V_fixture 0.0: 20-80 % time 1.71ns typ, 1.53ns min, 1.36ns max; typ from 0 V to 1.37 V
|   falling waveform, R_fixture 50.000000, V_fixture 2.400000: 20-80 % time 1.72ns typ, 1.3ns min, 1.45ns max; typ from 2.4 V to 1.01 V
|   falling waveform, R_fixture 50.000000, V_fixture 0.0: 20-80 % time 756ps typ, 950ps min, 676ps max; typ from 1.37 V to 0 V
[Pulldown]
|Voltage   I(typ)   I(min)   I(max)
-2.4V     -31.47mA   -16.45mA   -43.01mA
-800mV    -31.47mA   -16.45mA   -42.85mA
-480mV    -21.98mA   -13.17mA   -29.21mA
80mV      3.63mA     1.966mA    5.014mA
480mV     18.16mA    8.738mA    26.02mA
800mV     25.38mA    10.72mA    37.77mA
1.12V     28.53mA    11.02mA    44.6mA
2.8V      29.84mA    13.51mA    47.53mA
3.2V      32.66mA    13.51mA    48.04mA
3.52V     36.44mA    13.51mA    51.84mA
3.92V     36.44mA    13.51mA    59.5mA
4.8V      36.44mA    13.51mA    59.5mA
[Pullup]
|Voltage   I(typ)   I(min)   I(max)
-2.4V     50.45mA    35.09mA    67.51mA
-1.52V    50.45mA    34.74mA    67.51mA
-1.2V     48.65mA    29.87mA    65.66mA
320mV     -11.75mA   -6.207mA   -17.08mA
1.04V     -27.54mA   -11.97mA   -41.91mA
1.6V      -31.14mA   -12.58mA   -49.63mA
2.56V     -32.88mA   -13.52mA   -52.9mA
3.28V     -34.25mA   -25.7mA    -54.18mA
3.6V      -41.44mA   -32.7mA    -55.03mA
3.92V     -50.4mA    -40.9mA    -63.8mA
4.56V     -71.1mA    -40.9mA    -87.3mA
4.72V     -71.1mA    -40.9mA    -93.6mA
[GND_clamp]
|Voltage   I(typ)   I(min)   I(max)
-2.4V     -2.859A    -3.029A    -2.798A
-1.25V    -631.9mA   -814.4mA   -556.4mA
-1.2V     -540.2mA   -722.7mA   -464.2mA
-1.15V    -450mA     -632mA     -373.5mA
-1.1V     -361.8mA   -542.6mA   -285.3mA
-1.05V    -276.4mA   -454.9mA   -201.1mA
-950mV    -122.3mA   -287.2mA   -60.86mA
-900mV    -62.47mA   -209.5mA   -24.29mA
-850mV    -24.99mA   -138.8mA   -12.44mA
-750mV    -5.796mA   -36.69mA   -6.36mA
-600mV    -1.5mA     -2.436mA   -1.477mA
2.35V     0A         0A         0A
[POWER_clamp]
|Voltage   I(typ)   I(min)   I(max)
-2.4V     380.4uA    122.4uA    719.8uA
-1.32V    373.1uA    120.3uA    702.4uA
-1.29V    373.1uA    120.3uA    679.3uA
-1.2V     370.8uA    120.2uA    585.1uA
-1.17V    358.5uA    120.2uA    552.5uA
-960mV    220.5uA    117.2uA    335uA
-870mV    164.9uA    87.99uA    252.6uA
-750mV    101.2uA    53.84uA    157.3uA
-630mV    51.89uA    26.83uA    82.04uA
-510mV    18.44uA    9.055uA    29.95uA
-420mV    4.85uA     2.76uA     7.499uA
0V        0A         0A         0A
[Ramp]
| variable   typ   min   max
dV/dt_r  0.82146/1.70836n   0.36338/1.52136n   1.11096/1.35635n
dV/dt_f  0.83154/1.70705n   0.33084/1.29246n   1.13546/1.44710n
R_load = 50.000000
[Rising Waveform]
R_fixture= 50.000000
V_fixture= 2.400000
V_fixture_min= 1.800000
V_fixture_max= 2.700000
|time   V(typ)   V(min)   V(max)
0s        1.006V     1.247V     804.3mV
240.2ps   1.006V     1.247V     886.6mV
480.5ps   1.003V     1.247V     1.766V
680.7ps   1.058V     1.247V     2.192V
1.021ns   1.878V     1.247V     2.54V
1.281ns   2.159V     1.246V     2.64V
1.942ns   2.361V     1.279V     2.69V
2.482ns   2.387V     1.665V     2.695V
3.023ns   2.395V     1.768V     2.697V
9.97ns    2.4V       1.8V       2.699V
[Rising Waveform]
R_fixture= 50.000000
V_fixture= 0.0
V_fixture_min= 0.0
V_fixture_max= 0.0
|time   V(typ)   V(min)   V(max)
0s        161.7uV    68.36uV    673.1uV
720.7ps   -9.221mV   50.6uV     41.42mV
1.041ns   -10.99mV   111.6uV    217.1mV
1.401ns   45.47mV    267.1uV    513.6mV
2.543ns   611.5mV    -4.381mV   1.45V
2.883ns   791.2mV    29.78mV    1.624V
3.263ns   957.4mV    110.6mV    1.726V
4.164ns   1.218V     359.8mV    1.816V
5.305ns   1.327V     537.3mV    1.844V
9.97ns    1.37V      609mV      1.853V
[Falling Waveform]
R_fixture= 50.000000
V_fixture= 2.400000
V_fixture_min= 1.800000
V_fixture_max= 2.700000
|time   V(typ)   V(min)   V(max)
0s        2.4V       1.8V       2.699V
900.9ps   2.409V     1.8V       2.681V
1.221ns   2.408V     1.8V       2.487V
1.682ns   2.377V     1.8V       2.085V
2.222ns   2.126V     1.803V     1.6V
2.783ns   1.789V     1.805V     1.235V
3.483ns   1.428V     1.764V     969.7mV
4.565ns   1.186V     1.435V     863.1mV
5.485ns   1.087V     1.317V     833.6mV
9.97ns    1.006V     1.247V     804.3mV
[Falling Waveform]
R_fixture= 50.000000
V_fixture= 0.0
V_fixture_min= 0.0
V_fixture_max= 0.0
|time   V(typ)   V(min)   V(max)
0s        1.37V      609mV      1.853V
280.3ps   1.37V      609mV      1.759V
740.7ps   1.335V     609mV      844.3mV
1.081ns   968.8mV    608.7mV    395.3mV
1.441ns   522.7mV    608.9mV    123.2mV
1.682ns   313.2mV    610.5mV    37.93mV
2.362ns   37.14mV    568.4mV    5.076mV
3.504ns   3.317mV    131.7mV    1.828mV
4.104ns   1.95mV     23.44mV    1.365mV
9.97ns    161.7uV    68.36uV    673.1uV
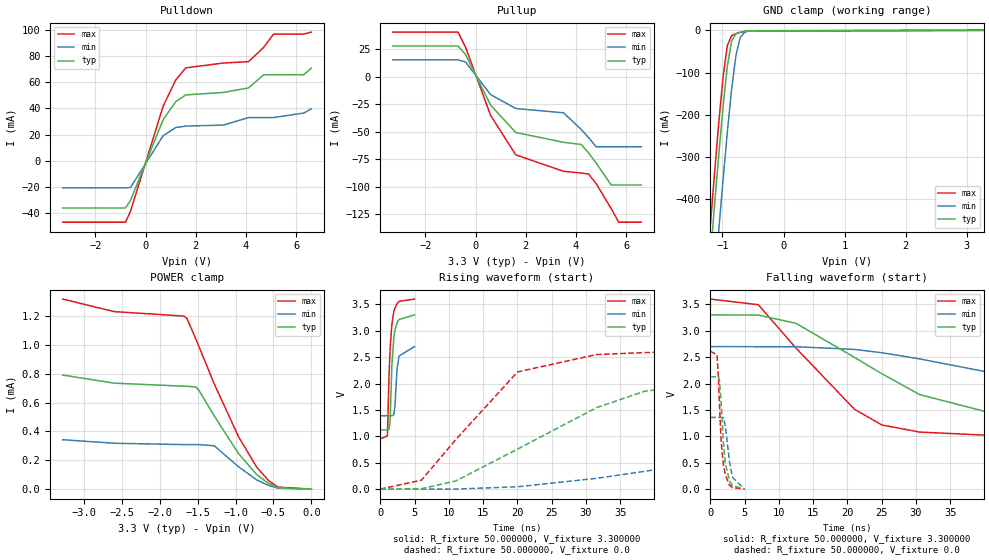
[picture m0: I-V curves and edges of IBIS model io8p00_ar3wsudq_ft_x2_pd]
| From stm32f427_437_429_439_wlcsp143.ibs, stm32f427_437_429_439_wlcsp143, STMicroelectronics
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|   Model io8p00_ar3wsudq_ft_x2_pd
[Model]  io8p00_ar3wsudq_ft_x2_pd
Model_type I/O
Polarity   Non-Inverting
Enable   Active-Low
Vinl =   0.990000V
Vinh =   2.310000V
Vmeas =  1.650000V
Cref =   50.000000pF
Rref =   100.000000M
Vref =   0.0V
C_comp   7.528700pF   7.342900pF   7.752900pF
[Temperature Range]   25.000000   0.125000k   -40.000000
[Pullup Reference]   3.300000V   2.700000V   3.600000V
[Pulldown Reference]   0.0V   0.0V   0.0V
[POWER Clamp Reference]   3.300000V   2.700000V   3.600000V
[GND Clamp Reference]   0.0V   0.0V   0.0V
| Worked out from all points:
|   slope of the pulldown table from 0 to 0.495 V, typ, clamps not added: 20.9 ohm
|   slope of the pullup table from 0 to 0.495 V, typ, clamps not added: 22.6 ohm
|   GND clamp passes 1 mA (typ) near -0.56 V on its own axis
|   rising waveform, R_fixture 50.000000, V_fixture 3.300000: 20-80 % time 477ps typ, 421ps min, 508ps max; typ from 1.12 V to 3.3 V
|   rising waveform, R_fixture 50.000000, V_fixture 0.0: 20-80 % time 19.2ns typ, 45.2ns min, 10.2ns max; typ from 0 V to 2.13 V
|   falling waveform, R_fixture 50.000000, V_fixture 3.300000: 20-80 % time 18.3ns typ, 37.2ns min, 11.3ns max; typ from 3.3 V to 1.12 V
|   falling waveform, R_fixture 50.000000, V_fixture 0.0: 20-80 % time 711ps typ, 846ps min, 657ps max; typ from 2.13 V to 0 V
[Pulldown]
|Voltage   I(typ)   I(min)   I(max)
-3.3V     -36.18mA   -20.77mA   -47.07mA
-800mV    -36.18mA   -20.77mA   -47.07mA
-600mV    -30.5mA    -20.52mA   -38.69mA
700mV     31.4mA     19.11mA    41.71mA
1.2V      45.15mA    25.37mA    61.75mA
1.6V      50.35mA    26.5mA     71.06mA
3.1V      52.27mA    27.26mA    74.75mA
4.1V      55.7mA     33.01mA    75.8mA
4.7V      65.73mA    33.01mA    86.69mA
5.1V      65.73mA    33.01mA    96.89mA
6.3V      65.85mA    36.49mA    96.89mA
6.6V      70.9mA     39.7mA     98.44mA
[Pullup]
|Voltage   I(typ)   I(min)   I(max)
-3.3V     28.03mA    15.43mA    40.67mA
-700mV    28.03mA    15.43mA    40.67mA
-400mV    20.31mA    13.47mA    26.93mA
600mV     -25.77mA   -16.23mA   -35.13mA
1.6V      -50.64mA   -28.81mA   -70.96mA
3.5V      -59.53mA   -32.72mA   -85.92mA
4.2V      -61.52mA   -47.7mA    -87.46mA
4.5V      -69.21mA   -55.3mA    -88.43mA
4.8V      -78.3mA    -63.6mA    -97.02mA
5.4V      -98.4mA    -63.6mA    -119.8mA
5.7V      -98.4mA    -63.6mA    -132.2mA
6.6V      -98.4mA    -63.6mA    -132.2mA
[GND_clamp]
|Voltage   I(typ)   I(min)   I(max)
-3.3V     -4.652A    -4.81A     -4.601A
-1.2V     -540.3mA   -722.7mA   -464.2mA
-1.13V    -414.5mA   -596.2mA   -338mA
-1.06V    -293.4mA   -472.4mA   -217.6mA
-990mV    -180.4mA   -352.9mA   -109.9mA
-920mV    -84.42mA   -240mA     -35.37mA
-850mV    -25.16mA   -138.9mA   -12.54mA
-780mV    -7.954mA   -60.02mA   -7.786mA
-710mV    -4.211mA   -17.24mA   -4.778mA
-640mV    -2.308mA   -4.575mA   -2.453mA
-570mV    -1.059mA   -1.652mA   -967uA
3.28V     81.28uA    57.88uA    93.98uA
[POWER_clamp]
|Voltage   I(typ)   I(min)   I(max)
-3.28V    790.5uA    342.5uA    1.317mA
-2.6V     734.3uA    318.1uA    1.23mA
-1.68V    713.4uA    308.8uA    1.199mA
-1.64V    713.1uA    308.7uA    1.182mA
-1.52V    707.2uA    308.5uA    1.037mA
-1.48V    682.1uA    308.4uA    984.7uA
-1.28V    507.2uA    300.7uA    728.4uA
-960mV    246.2uA    155.1uA    363.1uA
-720mV    101uA      64.07uA    152.4uA
-560mV    37.87uA    24.53uA    57.3uA
-440mV    10.21uA    7.381uA    14.65uA
0V        0A         0A         0A
[Ramp]
| variable   typ   min   max
dV/dt_r  1.27680/19.17704n   0.81450/45.18122n   1.56648/10.22686n
dV/dt_f  1.30548/18.24042n   0.78468/37.19795n   1.58744/11.28597n
R_load = 50.000000
[Rising Waveform]
R_fixture= 50.000000
V_fixture= 3.300000
V_fixture_min= 2.700000
V_fixture_max= 3.600000
|time   V(typ)   V(min)   V(max)
0s        1.123V     1.39V      953.1mV
1.041ns   1.123V     1.391V     1.007V
1.271ns   1.127V     1.391V     2.123V
1.431ns   1.29V      1.391V     2.66V
1.692ns   2.345V     1.388V     3.117V
1.962ns   2.85V      1.408V     3.353V
2.132ns   3.005V     1.559V     3.43V
2.442ns   3.148V     2.275V     3.513V
2.743ns   3.212V     2.523V     3.556V
4.985ns   3.299V     2.699V     3.599V
[Rising Waveform]
R_fixture= 50.000000
V_fixture= 0.0
V_fixture_min= 0.0
V_fixture_max= 0.0
|time   V(typ)   V(min)   V(max)
0s        13.7nV     662.2nV    9.262nV
6.006ns   9.289mV    -144.6uV   170mV
11.01ns   155.3mV    1.65mV     938.3mV
20.02ns   758.6mV    45.3mV     2.22V
31.53ns   1.543V     204.6mV    2.548V
38.54ns   1.853V     336.5mV    2.586V
48.05ns   2.014V     532.8mV    2.604V
71.07ns   2.108V     967.8mV    2.61V
98.6ns    2.126V     1.234V     2.611V
249.2ns   2.128V     1.358V     2.611V
[Falling Waveform]
R_fixture= 50.000000
V_fixture= 3.300000
V_fixture_min= 2.700000
V_fixture_max= 3.600000
|time   V(typ)   V(min)   V(max)
0s        3.299V     2.699V     3.599V
7.007ns   3.296V     2.697V     3.492V
12.51ns   3.139V     2.697V     2.669V
21.02ns   2.496V     2.646V     1.514V
25.03ns   2.185V     2.583V     1.215V
30.53ns   1.791V     2.466V     1.081V
45.55ns   1.286V     2.089V     989mV
63.06ns   1.181V     1.721V     963.1mV
83.58ns   1.143V     1.54V      955.6mV
249.2ns   1.123V     1.39V      953.1mV
[Falling Waveform]
R_fixture= 50.000000
V_fixture= 0.0
V_fixture_min= 0.0
V_fixture_max= 0.0
|time   V(typ)   V(min)   V(max)
0s        2.128V     1.358V     2.611V
991ps     2.129V     1.358V     2.543V
1.201ns   2.129V     1.357V     2.076V
1.331ns   2.063V     1.357V     1.624V
1.592ns   1.623V     1.359V     885mV
1.932ns   851.4mV    1.355V     448.4mV
2.192ns   492.3mV    1.195V     271.5mV
2.803ns   156.9mV    522.2mV    75mV
3.233ns   68.19mV    226mV      31.79mV
4.985ns   13.7nV     662.2nV    9.262nV
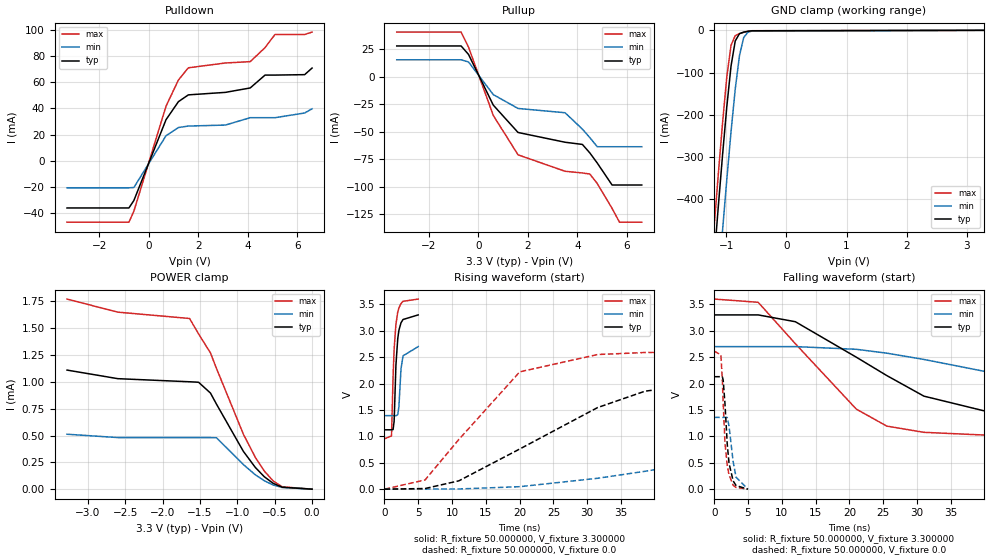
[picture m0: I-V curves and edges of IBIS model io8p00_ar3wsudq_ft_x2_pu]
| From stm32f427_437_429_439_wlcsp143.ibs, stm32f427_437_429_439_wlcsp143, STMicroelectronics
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|   Model io8p00_ar3wsudq_ft_x2_pu
[Model]  io8p00_ar3wsudq_ft_x2_pu
Model_type I/O
Polarity   Non-Inverting
Enable   Active-Low
Vinl =   0.990000V
Vinh =   2.310000V
Vmeas =  1.650000V
Cref =   50.000000pF
Rref =   100.000000M
Vref =   0.0V
C_comp   7.528700pF   7.342900pF   7.752900pF
[Temperature Range]   25.000000   0.125000k   -40.000000
[Pullup Reference]   3.300000V   2.700000V   3.600000V
[Pulldown Reference]   0.0V   0.0V   0.0V
[POWER Clamp Reference]   3.300000V   2.700000V   3.600000V
[GND Clamp Reference]   0.0V   0.0V   0.0V
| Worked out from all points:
|   slope of the pulldown table from 0 to 0.495 V, typ, clamps not added: 20.9 ohm
|   slope of the pullup table from 0 to 0.495 V, typ, clamps not added: 22.6 ohm
|   GND clamp passes 1 mA (typ) near -0.57 V on its own axis
|   POWER clamp passes 1 mA (typ) near -1.55 V on its own axis
|   rising waveform, R_fixture 50.000000, V_fixture 3.300000: 20-80 % time 476ps typ, 421ps min, 507ps max; typ from 1.12 V to 3.3 V
|   rising waveform, R_fixture 50.000000, V_fixture 0.0: 20-80 % time 19.2ns typ, 45.2ns min, 10.2ns max; typ from 0.001 V to 2.13 V
|   falling waveform, R_fixture 50.000000, V_fixture 3.300000: 20-80 % time 18.3ns typ, 37.2ns min, 11.3ns max; typ from 3.3 V to 1.12 V
|   falling waveform, R_fixture 50.000000, V_fixture 0.0: 20-80 % time 711ps typ, 847ps min, 657ps max; typ from 2.13 V to 0.001 V
[Pulldown]
|Voltage   I(typ)   I(min)   I(max)
-3.3V     -36.18mA   -20.77mA   -47.07mA
-800mV    -36.18mA   -20.77mA   -47.07mA
-600mV    -30.5mA    -20.52mA   -38.69mA
700mV     31.4mA     19.11mA    41.71mA
1.2V      45.15mA    25.37mA    61.75mA
1.6V      50.35mA    26.5mA     71.06mA
3.1V      52.28mA    27.26mA    74.76mA
4.1V      55.65mA    32.89mA    75.79mA
4.7V      65.5mA     32.89mA    86.49mA
5.1V      65.5mA     32.89mA    96.55mA
6.3V      65.83mA    36.49mA    96.55mA
6.6V      70.88mA    39.7mA     98.4mA
[Pullup]
|Voltage   I(typ)   I(min)   I(max)
-3.3V     28mA       15.42mA    40.61mA
-700mV    28mA       15.42mA    40.61mA
-400mV    20.3mA     13.47mA    26.92mA
600mV     -25.77mA   -16.23mA   -35.13mA
1.6V      -50.64mA   -28.8mA    -70.96mA
3.5V      -59.52mA   -32.71mA   -85.91mA
4.2V      -61.51mA   -47.6mA    -87.45mA
4.5V      -69.2mA    -55.3mA    -88.42mA
4.8V      -78.4mA    -63.6mA    -97mA
5.4V      -98.4mA    -63.6mA    -119.7mA
5.7V      -98.4mA    -63.6mA    -132.2mA
6.6V      -98.4mA    -63.6mA    -132.2mA
[GND_clamp]
|Voltage   I(typ)   I(min)   I(max)
-3.3V     -4.654A    -4.811A    -4.603A
-1.2V     -540.3mA   -722.7mA   -464.2mA
-1.13V    -414.5mA   -596.2mA   -338mA
-1.06V    -293.4mA   -472.4mA   -217.6mA
-990mV    -180.4mA   -352.9mA   -109.9mA
-920mV    -84.42mA   -240mA     -35.36mA
-850mV    -25.15mA   -138.9mA   -12.53mA
-780mV    -7.942mA   -60.01mA   -7.772mA
-710mV    -4.199mA   -17.23mA   -4.763mA
-640mV    -2.296mA   -4.566mA   -2.439mA
-570mV    -1.048mA   -1.643mA   -953.6uA
3.28V     0A         0A         0A
[POWER_clamp]
|Voltage   I(typ)   I(min)   I(max)
-3.28V    1.11mA     512.1uA    1.772mA
-2.6V     1.03mA     481uA      1.65mA
-1.64V    1.001mA    481uA      1.591mA
-1.52V    996.9uA    481uA      1.448mA
-1.36V    895.8uA    481uA      1.27mA
-1.28V    792.9uA    479.1uA    1.126mA
-920mV    352.7uA    229.7uA    512.9uA
-760mV    202.7uA    133.9uA    297uA
-640mV    116.1uA    78.59uA    169.1uA
-520mV    53.85uA    38.6uA     76.2uA
-400mV    18.17uA    15.42uA    22.14uA
0V        0A         0A         0A
[Ramp]
| variable   typ   min   max
dV/dt_r  1.27723/19.18068n   0.81507/45.18856n   1.56682/10.22827n
dV/dt_f  1.30506/18.23778n   0.78378/37.16817n   1.58716/11.28797n
R_load = 50.000000
[Rising Waveform]
R_fixture= 50.000000
V_fixture= 3.300000
V_fixture_min= 2.700000
V_fixture_max= 3.600000
|time   V(typ)   V(min)   V(max)
0s        1.125V     1.393V     954.7mV
1.041ns   1.125V     1.393V     1.009V
1.271ns   1.129V     1.393V     2.126V
1.431ns   1.292V     1.393V     2.662V
1.692ns   2.348V     1.391V     3.119V
1.962ns   2.852V     1.411V     3.355V
2.132ns   3.007V     1.562V     3.432V
2.442ns   3.15V      2.277V     3.515V
2.743ns   3.213V     2.525V     3.557V
4.985ns   3.3V       2.7V       3.6V
[Rising Waveform]
R_fixture= 50.000000
V_fixture= 0.0
V_fixture_min= 0.0
V_fixture_max= 0.0
|time   V(typ)   V(min)   V(max)
0s        1.088mV    1.044mV    1.136mV
6.006ns   13.37mV    2.773mV    175.7mV
11.01ns   159.1mV    4.555mV    942.7mV
20.02ns   762.2mV    48.18mV    2.223V
31.53ns   1.546V     207.3mV    2.55V
38.54ns   1.856V     339.2mV    2.588V
48.05ns   2.015V     535.5mV    2.606V
71.57ns   2.111V     977.9mV    2.612V
95.6ns    2.127V     1.219V     2.613V
249.2ns   2.13V      1.36V      2.613V
[Falling Waveform]
R_fixture= 50.000000
V_fixture= 3.300000
V_fixture_min= 2.700000
V_fixture_max= 3.600000
|time   V(typ)   V(min)   V(max)
0s        3.3V       2.7V       3.6V
6.507ns   3.3V       2.7V       3.539V
12.01ns   3.171V     2.7V       2.754V
21.02ns   2.5V       2.649V     1.517V
25.53ns   2.152V     2.576V     1.195V
31.03ns   1.762V     2.457V     1.077V
46.55ns   1.277V     2.066V     988.2mV
63.56ns   1.181V     1.717V     964.5mV
87.59ns   1.142V     1.523V     956.7mV
249.2ns   1.125V     1.393V     954.7mV
[Falling Waveform]
R_fixture= 50.000000
V_fixture= 0.0
V_fixture_min= 0.0
V_fixture_max= 0.0
|time   V(typ)   V(min)   V(max)
0s        2.13V      1.36V      2.613V
991ps     2.131V     1.36V      2.545V
1.201ns   2.131V     1.359V     2.076V
1.331ns   2.065V     1.359V     1.624V
1.592ns   1.624V     1.361V     885.2mV
1.932ns   852.3mV    1.357V     448.9mV
2.192ns   493.2mV    1.197V     272.3mV
2.803ns   158mV      523.7mV    76.01mV
3.233ns   69.23mV    227.5mV    32.85mV
4.985ns   1.088mV    1.044mV    1.136mV
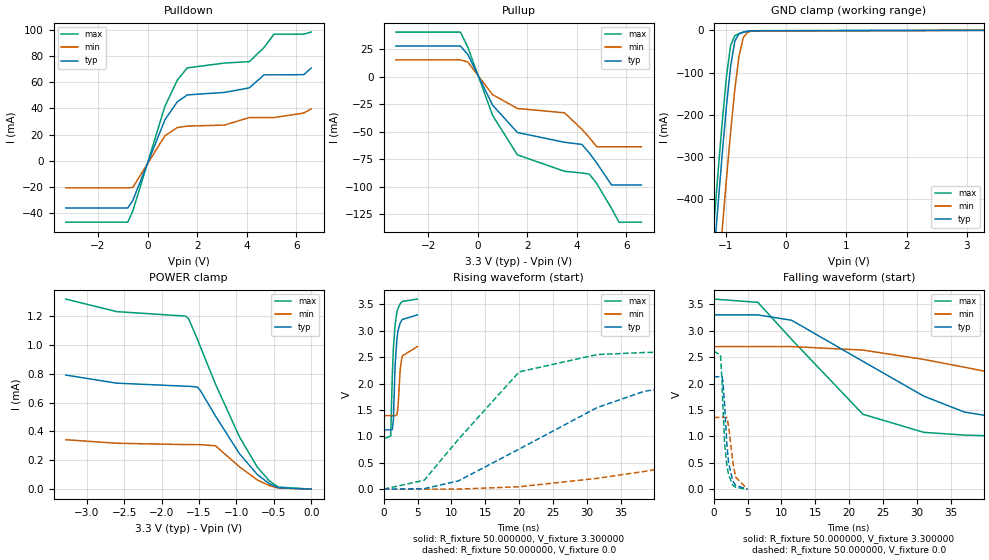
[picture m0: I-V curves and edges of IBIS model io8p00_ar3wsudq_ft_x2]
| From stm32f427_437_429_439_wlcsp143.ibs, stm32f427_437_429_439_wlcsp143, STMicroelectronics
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|   Model io8p00_ar3wsudq_ft_x2
[Model]  io8p00_ar3wsudq_ft_x2
Model_type I/O
Polarity   Non-Inverting
Enable   Active-Low
Vinl =   0.990000V
Vinh =   2.310000V
Vmeas =  1.650000V
Cref =   50.000000pF
Rref =   100.000000M
Vref =   0.0V
C_comp   7.528700pF   7.342900pF   7.752900pF
[Temperature Range]   25.000000   0.125000k   -40.000000
[Pullup Reference]   3.300000V   2.700000V   3.600000V
[Pulldown Reference]   0.0V   0.0V   0.0V
[POWER Clamp Reference]   3.300000V   2.700000V   3.600000V
[GND Clamp Reference]   0.0V   0.0V   0.0V
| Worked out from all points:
|   slope of the pulldown table from 0 to 0.495 V, typ, clamps not added: 20.9 ohm
|   slope of the pullup table from 0 to 0.495 V, typ, clamps not added: 22.6 ohm
|   GND clamp passes 1 mA (typ) near -0.57 V on its own axis
|   rising waveform, R_fixture 50.000000, V_fixture 3.300000: 20-80 % time 478ps typ, 422ps min, 509ps max; typ from 1.12 V to 3.3 V
|   rising waveform, R_fixture 50.000000, V_fixture 0.0: 20-80 % time 19.2ns typ, 45.2ns min, 10.2ns max; typ from 0 V to 2.13 V
|   falling waveform, R_fixture 50.000000, V_fixture 3.300000: 20-80 % time 18.2ns typ, 37.2ns min, 11.3ns max; typ from 3.3 V to 1.12 V
|   falling waveform, R_fixture 50.000000, V_fixture 0.0: 20-80 % time 712ps typ, 847ps min, 659ps max; typ from 2.13 V to 0 V
[Pulldown]
|Voltage   I(typ)   I(min)   I(max)
-3.3V     -36.18mA   -20.77mA   -47.07mA
-800mV    -36.18mA   -20.77mA   -47.07mA
-600mV    -30.5mA    -20.52mA   -38.69mA
700mV     31.4mA     19.11mA    41.71mA
1.2V      45.15mA    25.37mA    61.75mA
1.6V      50.35mA    26.5mA     71.06mA
3.1V      52.28mA    27.26mA    74.75mA
4.1V      55.71mA    33.01mA    75.8mA
4.7V      65.73mA    33.01mA    86.69mA
5.1V      65.73mA    33.01mA    96.9mA
6.3V      65.85mA    36.5mA     96.9mA
6.6V      70.91mA    39.71mA    98.45mA
[Pullup]
|Voltage   I(typ)   I(min)   I(max)
-3.3V     28.03mA    15.43mA    40.67mA
-700mV    28.03mA    15.43mA    40.67mA
-400mV    20.31mA    13.47mA    26.93mA
600mV     -25.77mA   -16.23mA   -35.14mA
1.6V      -50.64mA   -28.81mA   -70.96mA
3.5V      -59.53mA   -32.72mA   -85.92mA
4.2V      -61.52mA   -47.7mA    -87.46mA
4.5V      -69.21mA   -55.2mA    -88.43mA
4.8V      -78.4mA    -63.6mA    -97.02mA
5.4V      -98.4mA    -63.6mA    -119.8mA
5.7V      -98.4mA    -63.6mA    -132.2mA
6.6V      -98.4mA    -63.6mA    -132.2mA
[GND_clamp]
|Voltage   I(typ)   I(min)   I(max)
-3.3V     -4.654A    -4.811A    -4.603A
-1.2V     -540.3mA   -722.7mA   -464.2mA
-1.13V    -414.5mA   -596.2mA   -338mA
-1.06V    -293.4mA   -472.4mA   -217.6mA
-990mV    -180.4mA   -352.9mA   -109.9mA
-920mV    -84.42mA   -240mA     -35.36mA
-850mV    -25.15mA   -138.9mA   -12.53mA
-780mV    -7.942mA   -60.01mA   -7.772mA
-710mV    -4.199mA   -17.23mA   -4.763mA
-640mV    -2.296mA   -4.566mA   -2.439mA
-570mV    -1.048mA   -1.643mA   -953.6uA
3.28V     0A         0A         0A
[POWER_clamp]
|Voltage   I(typ)   I(min)   I(max)
-3.28V    790.5uA    342.5uA    1.317mA
-2.6V     734.3uA    318.1uA    1.23mA
-1.68V    713.4uA    308.8uA    1.199mA
-1.64V    713.1uA    308.7uA    1.182mA
-1.52V    707.2uA    308.5uA    1.037mA
-1.48V    682.1uA    308.4uA    984.7uA
-1.28V    507.2uA    300.7uA    728.4uA
-960mV    246.2uA    155.1uA    363.1uA
-720mV    101uA      64.07uA    152.4uA
-560mV    37.87uA    24.53uA    57.3uA
-440mV    10.21uA    7.381uA    14.65uA
0V        0A         0A         0A
[Ramp]
| variable   typ   min   max
dV/dt_r  1.27752/19.16649n   0.81510/45.16410n   1.56726/10.21885n
dV/dt_f  1.30584/18.22821n   0.78456/37.16855n   1.58792/11.27925n
R_load = 50.000000
[Rising Waveform]
R_fixture= 50.000000
V_fixture= 3.300000
V_fixture_min= 2.700000
V_fixture_max= 3.600000
|time   V(typ)   V(min)   V(max)
0s        1.124V     1.392V     953.5mV
1.041ns   1.124V     1.392V     1.007V
1.271ns   1.128V     1.392V     2.123V
1.431ns   1.291V     1.392V     2.659V
1.692ns   2.345V     1.389V     3.115V
1.962ns   2.849V     1.409V     3.352V
2.132ns   3.004V     1.561V     3.429V
2.442ns   3.148V     2.275V     3.512V
2.743ns   3.212V     2.524V     3.555V
4.985ns   3.3V       2.7V       3.6V
[Rising Waveform]
R_fixture= 50.000000
V_fixture= 0.0
V_fixture_min= 0.0
V_fixture_max= 0.0
|time   V(typ)   V(min)   V(max)
0s        13.81nV    666.6nV    9.346nV
6.006ns   9.29mV     -146.4uV   170.1mV
11.01ns   155.4mV    1.651mV    939mV
20.02ns   759.2mV    45.36mV    2.222V
31.53ns   1.545V     204.7mV    2.549V
38.54ns   1.855V     336.8mV    2.588V
48.05ns   2.015V     533.3mV    2.605V
71.07ns   2.11V      968.8mV    2.612V
98.6ns    2.127V     1.235V     2.612V
249.2ns   2.129V     1.359V     2.612V
[Falling Waveform]
R_fixture= 50.000000
V_fixture= 3.300000
V_fixture_min= 2.700000
V_fixture_max= 3.600000
|time   V(typ)   V(min)   V(max)
0s        3.3V       2.7V       3.6V
6.507ns   3.3V       2.7V       3.538V
11.51ns   3.198V     2.7V       2.834V
22.02ns   2.421V     2.634V     1.419V
31.03ns   1.761V     2.457V     1.076V
37.04ns   1.459V     2.309V     1.024V
45.55ns   1.287V     2.091V     989.4mV
63.06ns   1.182V     1.723V     963.5mV
83.08ns   1.144V     1.544V     956.2mV
249.2ns   1.124V     1.392V     953.5mV
[Falling Waveform]
R_fixture= 50.000000
V_fixture= 0.0
V_fixture_min= 0.0
V_fixture_max= 0.0
|time   V(typ)   V(min)   V(max)
0s        2.129V     1.359V     2.612V
991ps     2.13V      1.359V     2.544V
1.201ns   2.13V      1.358V     2.078V
1.331ns   2.064V     1.358V     1.627V
1.602ns   1.6V       1.361V     868.6mV
1.932ns   853mV      1.356V     450.8mV
2.192ns   493.8mV    1.196V     273.8mV
2.803ns   158.2mV    523.1mV    76.6mV
3.233ns   69.14mV    226.8mV    32.92mV
4.985ns   13.81nV    666.6nV    9.346nV
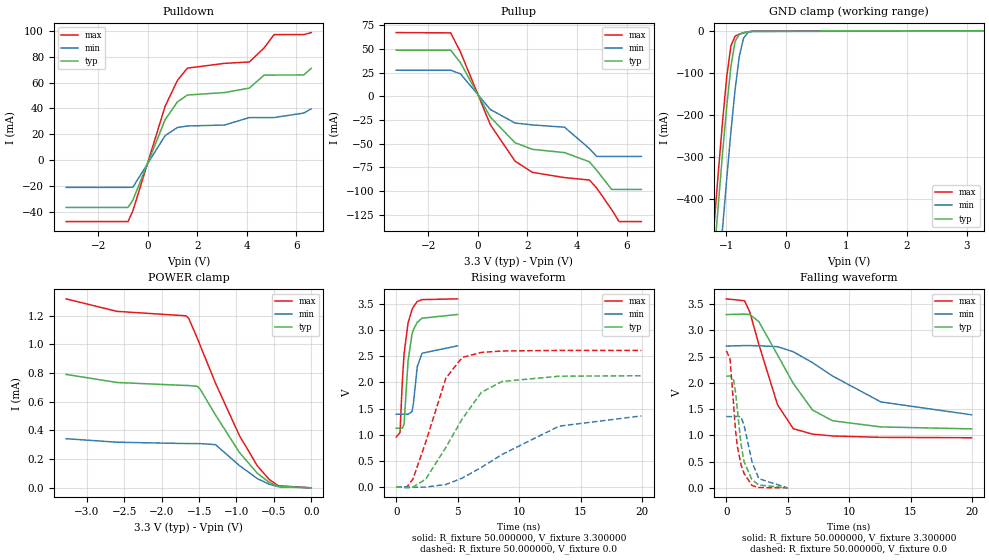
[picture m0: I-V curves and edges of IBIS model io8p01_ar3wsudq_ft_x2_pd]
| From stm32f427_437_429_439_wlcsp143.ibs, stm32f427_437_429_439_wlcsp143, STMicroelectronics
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|   Model io8p01_ar3wsudq_ft_x2_pd
[Model]  io8p01_ar3wsudq_ft_x2_pd
Model_type I/O
Polarity   Non-Inverting
Enable   Active-Low
Vinl =   0.990000V
Vinh =   2.310000V
Vmeas =  1.650000V
Cref =   50.000000pF
Rref =   100.000000M
Vref =   0.0V
C_comp   7.528300pF   7.342900pF   7.752900pF
[Temperature Range]   25.000000   0.125000k   -40.000000
[Pullup Reference]   3.300000V   2.700000V   3.600000V
[Pulldown Reference]   0.0V   0.0V   0.0V
[POWER Clamp Reference]   3.300000V   2.700000V   3.600000V
[GND Clamp Reference]   0.0V   0.0V   0.0V
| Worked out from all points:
|   slope of the pulldown table from 0 to 0.495 V, typ, clamps not added: 20.9 ohm
|   slope of the pullup table from 0 to 0.495 V, typ, clamps not added: 22.6 ohm
|   GND clamp passes 1 mA (typ) near -0.56 V on its own axis
|   rising waveform, R_fixture 50.000000, V_fixture 3.300000: 20-80 % time 481ps typ, 427ps min, 512ps max; typ from 1.12 V to 3.3 V
|   rising waveform, R_fixture 50.000000, V_fixture 0.0: 20-80 % time 3.29ns typ, 6.17ns min, 2.1ns max; typ from 0 V to 2.13 V
|   falling waveform, R_fixture 50.000000, V_fixture 3.300000: 20-80 % time 3.28ns typ, 5.74ns min, 2.08ns max; typ from 3.3 V to 1.12 V
|   falling waveform, R_fixture 50.000000, V_fixture 0.0: 20-80 % time 716ps typ, 860ps min, 660ps max; typ from 2.13 V to 0 V
[Pulldown]
|Voltage   I(typ)   I(min)   I(max)
-3.3V     -36.18mA   -20.77mA   -47.07mA
-800mV    -36.18mA   -20.77mA   -47.07mA
-600mV    -30.5mA    -20.52mA   -38.69mA
700mV     31.4mA     19.11mA    41.71mA
1.2V      45.15mA    25.37mA    61.75mA
1.6V      50.35mA    26.5mA     71.06mA
3.1V      52.27mA    27.26mA    74.75mA
4.1V      55.7mA     33.01mA    75.8mA
4.7V      65.73mA    33.01mA    86.69mA
5.1V      65.73mA    33.01mA    96.89mA
6.3V      65.85mA    36.49mA    96.89mA
6.6V      70.9mA     39.7mA     98.44mA
[Pullup]
|Voltage   I(typ)   I(min)   I(max)
-3.3V     48.54mA    27.45mA    67.15mA
-1.1V     48.54mA    27.45mA    66.87mA
-700mV    35.13mA    23.48mA    46.33mA
500mV     -22.07mA   -14mA      -30.03mA
1.5V      -49.1mA    -28.3mA    -68.56mA
2.2V      -56.04mA   -30.32mA   -80.35mA
3.5V      -59.53mA   -32.72mA   -85.92mA
4.5V      -69.21mA   -55.3mA    -88.43mA
4.8V      -78.3mA    -63.6mA    -97.02mA
5.4V      -98.4mA    -63.6mA    -119.7mA
5.7V      -98.4mA    -63.6mA    -132.3mA
6.6V      -98.4mA    -63.6mA    -132.3mA
[GND_clamp]
|Voltage   I(typ)   I(min)   I(max)
-3.3V     -4.651A    -4.809A    -4.599A
-1.2V     -540.3mA   -722.7mA   -464.2mA
-1.13V    -414.5mA   -596.2mA   -338mA
-1.06V    -293.4mA   -472.4mA   -217.6mA
-990mV    -180.4mA   -352.9mA   -109.9mA
-920mV    -84.42mA   -240mA     -35.37mA
-850mV    -25.16mA   -138.9mA   -12.54mA
-780mV    -7.954mA   -60.02mA   -7.786mA
-710mV    -4.211mA   -17.24mA   -4.778mA
-640mV    -2.308mA   -4.575mA   -2.453mA
-570mV    -1.059mA   -1.652mA   -967uA
3.28V     81.28uA    57.88uA    93.98uA
[POWER_clamp]
|Voltage   I(typ)   I(min)   I(max)
-3.28V    790.5uA    342.5uA    1.317mA
-2.6V     734.3uA    318.1uA    1.23mA
-1.68V    713.4uA    308.8uA    1.199mA
-1.64V    713.1uA    308.7uA    1.182mA
-1.52V    707.2uA    308.5uA    1.037mA
-1.48V    682.1uA    308.4uA    984.7uA
-1.28V    507.2uA    300.7uA    728.4uA
-960mV    246.2uA    155.1uA    363.1uA
-720mV    101uA      64.07uA    152.4uA
-560mV    37.87uA    24.53uA    57.3uA
-440mV    10.21uA    7.381uA    14.65uA
0V        0A         0A         0A
[Ramp]
| variable   typ   min   max
dV/dt_r  1.27662/3.28723n   0.79596/6.12338n   1.56648/2.10090n
dV/dt_f  1.30170/3.26880n   0.73758/5.66328n   1.58736/2.08140n
R_load = 50.000000
[Rising Waveform]
R_fixture= 50.000000
V_fixture= 3.300000
V_fixture_min= 2.700000
V_fixture_max= 3.600000
|time   V(typ)   V(min)   V(max)
0s        1.123V     1.391V     953.8mV
310.3ps   1.123V     1.391V     1.042V
500.5ps   1.124V     1.391V     2.034V
640.6ps   1.204V     1.391V     2.546V
961ps     2.4V       1.388V     3.134V
1.281ns   2.919V     1.441V     3.388V
1.391ns   3.007V     1.579V     3.443V
1.712ns   3.149V     2.299V     3.548V
2.102ns   3.228V     2.558V     3.584V
4.985ns   3.299V     2.699V     3.598V
[Rising Waveform]
R_fixture= 50.000000
V_fixture= 0.0
V_fixture_min= 0.0
V_fixture_max= 0.0
|time   V(typ)   V(min)   V(max)
0s        336.8uV    198.5uV    1.007mV
880.9ps   -18.3mV    582.2uV    3.408mV
1.361ns   -3.765mV   -8.428mV   150.9mV
2.402ns   148.7mV    -3.027mV   857.2mV
4.044ns   757.7mV    45.82mV    2.083V
5.365ns   1.299V     167.6mV    2.476V
6.927ns   1.809V     373.5mV    2.573V
8.609ns   2.017V     620.4mV    2.601V
13.25ns   2.118V     1.162V     2.611V
19.94ns   2.127V     1.358V     2.611V
[Falling Waveform]
R_fixture= 50.000000
V_fixture= 3.300000
V_fixture_min= 2.700000
V_fixture_max= 3.600000
|time   V(typ)   V(min)   V(max)
0s        3.299V     2.699V     3.598V
1.481ns   3.309V     2.709V     3.562V
1.922ns   3.298V     2.708V     3.338V
2.643ns   3.164V     2.705V     2.732V
4.164ns   2.531V     2.688V     1.583V
5.445ns   1.989V     2.591V     1.126V
7.007ns   1.482V     2.384V     1.023V
8.649ns   1.277V     2.128V     987.8mV
12.57ns   1.16V      1.636V     961.4mV
19.94ns   1.123V     1.391V     953.8mV
[Falling Waveform]
R_fixture= 50.000000
V_fixture= 0.0
V_fixture_min= 0.0
V_fixture_max= 0.0
|time   V(typ)   V(min)   V(max)
0s        2.127V     1.358V     2.611V
300.3ps   2.13V      1.357V     2.453V
590.6ps   2.052V     1.357V     1.589V
740.7ps   1.838V     1.358V     1.114V
900.9ps   1.477V     1.361V     781.6mV
1.191ns   834.8mV    1.352V     443.7mV
1.441ns   496mV      1.195V     276mV
2.092ns   150.9mV    491.2mV    44.21mV
2.643ns   53.84mV    174.2mV    5.71mV
4.985ns   336.8uV    198.5uV    1.007mV
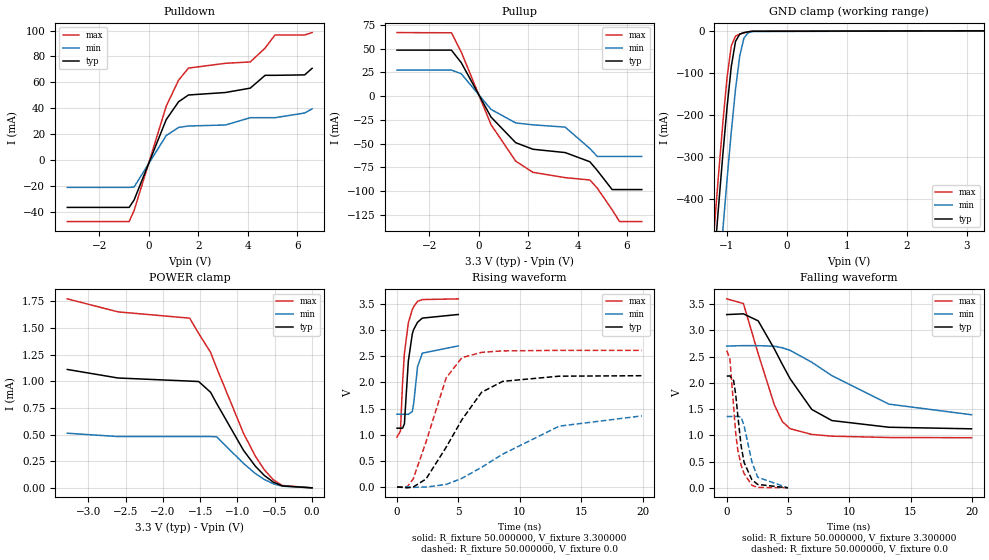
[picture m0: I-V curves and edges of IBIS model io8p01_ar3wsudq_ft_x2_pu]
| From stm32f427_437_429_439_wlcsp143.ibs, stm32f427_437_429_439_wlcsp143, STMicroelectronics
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|   Model io8p01_ar3wsudq_ft_x2_pu
[Model]  io8p01_ar3wsudq_ft_x2_pu
Model_type I/O
Polarity   Non-Inverting
Enable   Active-Low
Vinl =   0.990000V
Vinh =   2.310000V
Vmeas =  1.650000V
Cref =   50.000000pF
Rref =   100.000000M
Vref =   0.0V
C_comp   7.528300pF   7.342900pF   7.752900pF
[Temperature Range]   25.000000   0.125000k   -40.000000
[Pullup Reference]   3.300000V   2.700000V   3.600000V
[Pulldown Reference]   0.0V   0.0V   0.0V
[POWER Clamp Reference]   3.300000V   2.700000V   3.600000V
[GND Clamp Reference]   0.0V   0.0V   0.0V
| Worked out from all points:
|   slope of the pulldown table from 0 to 0.495 V, typ, clamps not added: 20.9 ohm
|   slope of the pullup table from 0 to 0.495 V, typ, clamps not added: 22.6 ohm
|   GND clamp passes 1 mA (typ) near -0.57 V on its own axis
|   POWER clamp passes 1 mA (typ) near -1.55 V on its own axis
|   rising waveform, R_fixture 50.000000, V_fixture 3.300000: 20-80 % time 479ps typ, 426ps min, 510ps max; typ from 1.12 V to 3.3 V
|   rising waveform, R_fixture 50.000000, V_fixture 0.0: 20-80 % time 3.29ns typ, 6.17ns min, 2.1ns max; typ from 0.001 V to 2.13 V
|   falling waveform, R_fixture 50.000000, V_fixture 3.300000: 20-80 % time 3.27ns typ, 5.72ns min, 2.06ns max; typ from 3.3 V to 1.12 V
|   falling waveform, R_fixture 50.000000, V_fixture 0.0: 20-80 % time 718ps typ, 861ps min, 663ps max; typ from 2.13 V to 0.001 V
[Pulldown]
|Voltage   I(typ)   I(min)   I(max)
-3.3V     -36.18mA   -20.77mA   -47.07mA
-800mV    -36.18mA   -20.77mA   -47.07mA
-600mV    -30.5mA    -20.52mA   -38.69mA
700mV     31.4mA     19.11mA    41.71mA
1.2V      45.15mA    25.37mA    61.75mA
1.6V      50.35mA    26.5mA     71.06mA
3.1V      52.28mA    27.26mA    74.76mA
4.1V      55.65mA    32.89mA    75.79mA
4.7V      65.5mA     32.89mA    86.49mA
5.1V      65.5mA     32.89mA    96.55mA
6.3V      65.83mA    36.49mA    96.55mA
6.6V      70.88mA    39.7mA     98.4mA
[Pullup]
|Voltage   I(typ)   I(min)   I(max)
-3.3V     48.39mA    27.39mA    66.88mA
-1.1V     48.39mA    27.39mA    66.66mA
-700mV    35.09mA    23.45mA    46.27mA
500mV     -22.06mA   -14mA      -30.03mA
1.5V      -49.1mA    -28.3mA    -68.56mA
2.2V      -56.04mA   -30.32mA   -80.35mA
3.5V      -59.52mA   -32.71mA   -85.91mA
4.5V      -69.2mA    -55.3mA    -88.42mA
4.8V      -78.4mA    -63.6mA    -97mA
5.4V      -98.5mA    -63.6mA    -119.8mA
5.7V      -98.5mA    -63.6mA    -132.2mA
6.6V      -98.5mA    -63.6mA    -132.2mA
[GND_clamp]
|Voltage   I(typ)   I(min)   I(max)
-3.3V     -4.652A    -4.81A     -4.601A
-1.2V     -540.3mA   -722.7mA   -464.2mA
-1.13V    -414.5mA   -596.2mA   -338mA
-1.06V    -293.4mA   -472.4mA   -217.6mA
-990mV    -180.4mA   -352.9mA   -109.9mA
-920mV    -84.42mA   -240mA     -35.36mA
-850mV    -25.15mA   -138.9mA   -12.53mA
-780mV    -7.942mA   -60.01mA   -7.772mA
-710mV    -4.199mA   -17.23mA   -4.763mA
-640mV    -2.296mA   -4.566mA   -2.439mA
-570mV    -1.048mA   -1.643mA   -953.6uA
3.28V     0A         0A         0A
[POWER_clamp]
|Voltage   I(typ)   I(min)   I(max)
-3.28V    1.11mA     512.1uA    1.772mA
-2.6V     1.03mA     481uA      1.65mA
-1.64V    1.001mA    481uA      1.591mA
-1.52V    996.9uA    481uA      1.448mA
-1.36V    895.8uA    481uA      1.27mA
-1.28V    792.9uA    479.1uA    1.126mA
-920mV    352.7uA    229.7uA    512.9uA
-760mV    202.7uA    133.9uA    297uA
-640mV    116.1uA    78.59uA    169.1uA
-520mV    53.85uA    38.6uA     76.2uA
-400mV    18.17uA    15.42uA    22.14uA
0V        0A         0A         0A
[Ramp]
| variable   typ   min   max
dV/dt_r  1.27717/3.29130n   0.79653/6.12952n   1.56682/2.10321n
dV/dt_f  1.30122/3.26800n   0.73656/5.63908n   1.58691/2.06258n
R_load = 50.000000
[Rising Waveform]
R_fixture= 50.000000
V_fixture= 3.300000
V_fixture_min= 2.700000
V_fixture_max= 3.600000
|time   V(typ)   V(min)   V(max)
0s        1.125V     1.393V     955.5mV
280.3ps   1.125V     1.393V     1.07V
450.5ps   1.125V     1.393V     1.992V
600.6ps   1.206V     1.393V     2.551V
920.9ps   2.405V     1.39V      3.139V
1.241ns   2.923V     1.444V     3.393V
1.351ns   3.011V     1.582V     3.448V
1.672ns   3.152V     2.302V     3.551V
2.062ns   3.231V     2.56V      3.586V
4.985ns   3.3V       2.7V       3.599V
[Rising Waveform]
R_fixture= 50.000000
V_fixture= 0.0
V_fixture_min= 0.0
V_fixture_max= 0.0
|time   V(typ)   V(min)   V(max)
0s        1.407mV    1.23mV     2.426mV
840.8ps   -16.06mV   1.623mV    7.699mV
1.321ns   -275.6uV   -7.279mV   156.4mV
2.362ns   153.1mV    -286.4uV   862.1mV
4.004ns   761.2mV    49.07mV    2.087V
5.285ns   1.287V     166mV      2.474V
6.887ns   1.812V     376.4mV    2.576V
8.609ns   2.021V     628.7mV    2.604V
13.21ns   2.12V      1.164V     2.614V
19.94ns   2.129V     1.36V      2.614V
[Falling Waveform]
R_fixture= 50.000000
V_fixture= 3.300000
V_fixture_min= 2.700000
V_fixture_max= 3.600000
|time   V(typ)   V(min)   V(max)
0s        3.3V       2.7V       3.599V
1.361ns   3.314V     2.709V     3.51V
2.563ns   3.18V      2.708V     2.554V
3.884ns   2.644V     2.698V     1.578V
4.525ns   2.354V     2.668V     1.264V
5.165ns   2.078V     2.618V     1.127V
6.927ns   1.494V     2.393V     1.018V
8.569ns   1.282V     2.137V     985.1mV
13.21ns   1.155V     1.595V     959.6mV
19.94ns   1.125V     1.393V     955.5mV
[Falling Waveform]
R_fixture= 50.000000
V_fixture= 0.0
V_fixture_min= 0.0
V_fixture_max= 0.0
|time   V(typ)   V(min)   V(max)
0s        2.129V     1.36V      2.614V
260.3ps   2.132V     1.36V      2.454V
560.6ps   2.044V     1.359V     1.555V
730.7ps   1.781V     1.36V      1.041V
900.9ps   1.381V     1.364V     723.6mV
1.171ns   801.8mV    1.349V     431.2mV
1.421ns   480.2mV    1.177V     269.9mV
2.052ns   154.2mV    493mV      49.71mV
2.523ns   66.31mV    203.3mV    8.949mV
4.985ns   1.407mV    1.23mV     2.426mV
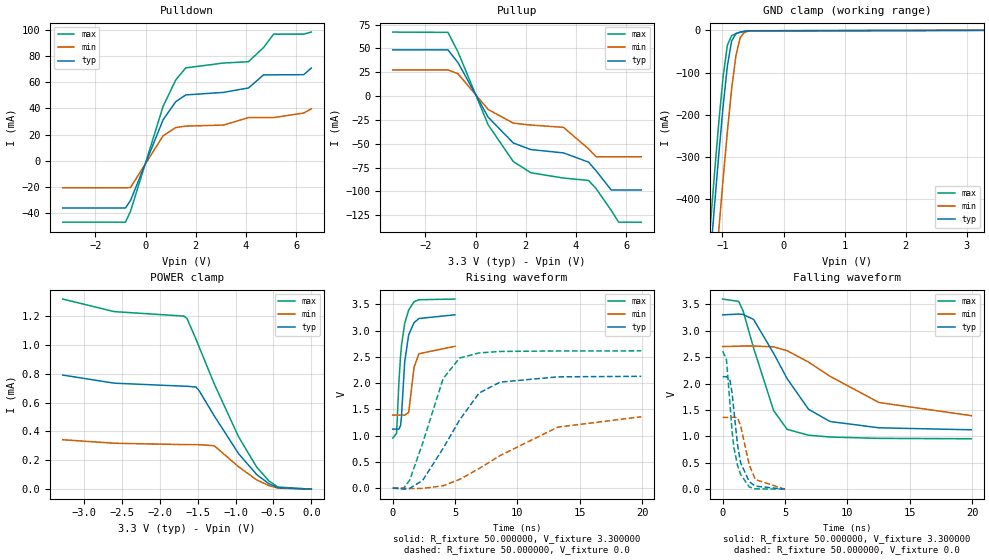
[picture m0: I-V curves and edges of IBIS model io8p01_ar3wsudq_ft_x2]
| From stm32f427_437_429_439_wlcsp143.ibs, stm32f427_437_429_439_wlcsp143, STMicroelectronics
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|   Model io8p01_ar3wsudq_ft_x2
[Model]  io8p01_ar3wsudq_ft_x2
Model_type I/O
Polarity   Non-Inverting
Enable   Active-Low
Vinl =   0.990000V
Vinh =   2.310000V
Vmeas =  1.650000V
Cref =   50.000000pF
Rref =   100.000000M
Vref =   0.0V
C_comp   7.528300pF   7.342900pF   7.752900pF
[Temperature Range]   25.000000   0.125000k   -40.000000
[Pullup Reference]   3.300000V   2.700000V   3.600000V
[Pulldown Reference]   0.0V   0.0V   0.0V
[POWER Clamp Reference]   3.300000V   2.700000V   3.600000V
[GND Clamp Reference]   0.0V   0.0V   0.0V
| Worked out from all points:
|   slope of the pulldown table from 0 to 0.495 V, typ, clamps not added: 20.9 ohm
|   slope of the pullup table from 0 to 0.495 V, typ, clamps not added: 22.6 ohm
|   GND clamp passes 1 mA (typ) near -0.57 V on its own axis
|   rising waveform, R_fixture 50.000000, V_fixture 3.300000: 20-80 % time 481ps typ, 427ps min, 512ps max; typ from 1.12 V to 3.3 V
|   rising waveform, R_fixture 50.000000, V_fixture 0.0: 20-80 % time 3.29ns typ, 6.17ns min, 2.1ns max; typ from 0 V to 2.13 V
|   falling waveform, R_fixture 50.000000, V_fixture 3.300000: 20-80 % time 3.27ns typ, 5.73ns min, 2.07ns max; typ from 3.3 V to 1.12 V
|   falling waveform, R_fixture 50.000000, V_fixture 0.0: 20-80 % time 718ps typ, 860ps min, 663ps max; typ from 2.13 V to 0 V
[Pulldown]
|Voltage   I(typ)   I(min)   I(max)
-3.3V     -36.18mA   -20.77mA   -47.07mA
-800mV    -36.18mA   -20.77mA   -47.07mA
-600mV    -30.5mA    -20.52mA   -38.69mA
700mV     31.4mA     19.11mA    41.71mA
1.2V      45.15mA    25.37mA    61.75mA
1.6V      50.35mA    26.5mA     71.06mA
3.1V      52.28mA    27.26mA    74.75mA
4.1V      55.71mA    33.01mA    75.8mA
4.7V      65.73mA    33.01mA    86.69mA
5.1V      65.73mA    33.01mA    96.9mA
6.3V      65.85mA    36.5mA     96.9mA
6.6V      70.91mA    39.71mA    98.45mA
[Pullup]
|Voltage   I(typ)   I(min)   I(max)
-3.3V     48.54mA    27.45mA    67.16mA
-1.1V     48.54mA    27.45mA    66.87mA
-700mV    35.13mA    23.48mA    46.33mA
500mV     -22.07mA   -14mA      -30.03mA
1.5V      -49.1mA    -28.3mA    -68.56mA
2.2V      -56.05mA   -30.32mA   -80.35mA
3.5V      -59.53mA   -32.72mA   -85.92mA
4.5V      -69.21mA   -55.3mA    -88.43mA
4.8V      -78.3mA    -63.6mA    -97.02mA
5.4V      -98.4mA    -63.6mA    -119.8mA
5.7V      -98.4mA    -63.6mA    -132.2mA
6.6V      -98.4mA    -63.6mA    -132.2mA
[GND_clamp]
|Voltage   I(typ)   I(min)   I(max)
-3.3V     -4.652A    -4.81A     -4.601A
-1.2V     -540.3mA   -722.7mA   -464.2mA
-1.13V    -414.5mA   -596.2mA   -338mA
-1.06V    -293.4mA   -472.4mA   -217.6mA
-990mV    -180.4mA   -352.9mA   -109.9mA
-920mV    -84.42mA   -240mA     -35.36mA
-850mV    -25.15mA   -138.9mA   -12.53mA
-780mV    -7.942mA   -60.01mA   -7.772mA
-710mV    -4.199mA   -17.23mA   -4.763mA
-640mV    -2.296mA   -4.566mA   -2.439mA
-570mV    -1.048mA   -1.643mA   -953.6uA
3.28V     0A         0A         0A
[POWER_clamp]
|Voltage   I(typ)   I(min)   I(max)
-3.28V    790.5uA    342.5uA    1.317mA
-2.6V     734.3uA    318.1uA    1.23mA
-1.68V    713.4uA    308.8uA    1.199mA
-1.64V    713.1uA    308.7uA    1.182mA
-1.52V    707.2uA    308.5uA    1.037mA
-1.48V    682.1uA    308.4uA    984.7uA
-1.28V    507.2uA    300.7uA    728.4uA
-960mV    246.2uA    155.1uA    363.1uA
-720mV    101uA      64.07uA    152.4uA
-560mV    37.87uA    24.53uA    57.3uA
-440mV    10.21uA    7.381uA    14.65uA
0V        0A         0A         0A
[Ramp]
| variable   typ   min   max
dV/dt_r  1.27734/3.28720n   0.79656/6.12344n   1.56726/2.10083n
dV/dt_f  1.30200/3.26711n   0.73728/5.65067n   1.58785/2.06629n
R_load = 50.000000
[Rising Waveform]
R_fixture= 50.000000
V_fixture= 3.300000
V_fixture_min= 2.700000
V_fixture_max= 3.600000
|time   V(typ)   V(min)   V(max)
0s        1.124V     1.392V     954.2mV
310.3ps   1.124V     1.392V     1.043V
500.5ps   1.125V     1.392V     2.035V
630.6ps   1.191V     1.392V     2.517V
700.7ps   1.359V     1.392V     2.704V
961ps     2.402V     1.389V     3.136V
1.281ns   2.92V      1.443V     3.39V
1.712ns   3.15V      2.3V       3.549V
2.102ns   3.229V     2.559V     3.586V
4.985ns   3.3V       2.7V       3.599V
[Rising Waveform]
R_fixture= 50.000000
V_fixture= 0.0
V_fixture_min= 0.0
V_fixture_max= 0.0
|time   V(typ)   V(min)   V(max)
0s        336.7uV    198.3uV    1.007mV
880.9ps   -18.3mV    582.2uV    3.401mV
1.361ns   -3.77mV    -8.429mV   150.9mV
2.402ns   148.7mV    -3.031mV   857.3mV
4.044ns   757.8mV    45.82mV    2.084V
5.365ns   1.299V     167.6mV    2.477V
6.927ns   1.81V      373.6mV    2.574V
8.609ns   2.018V     620.6mV    2.602V
13.25ns   2.119V     1.163V     2.612V
19.94ns   2.129V     1.359V     2.613V
[Falling Waveform]
R_fixture= 50.000000
V_fixture= 3.300000
V_fixture_min= 2.700000
V_fixture_max= 3.600000
|time   V(typ)   V(min)   V(max)
0s        3.3V       2.7V       3.599V
1.281ns   3.315V     2.707V     3.555V
1.642ns   3.308V     2.711V     3.371V
2.482ns   3.212V     2.71V      2.669V
4.084ns   2.571V     2.694V     1.488V
5.165ns   2.093V     2.622V     1.132V
6.887ns   1.512V     2.405V     1.022V
8.609ns   1.281V     2.137V     987.2mV
12.53ns   1.162V     1.641V     961.7mV
19.94ns   1.124V     1.392V     954.2mV
[Falling Waveform]
R_fixture= 50.000000
V_fixture= 0.0
V_fixture_min= 0.0
V_fixture_max= 0.0
|time   V(typ)   V(min)   V(max)
0s        2.129V     1.359V     2.613V
300.3ps   2.131V     1.359V     2.454V
590.6ps   2.054V     1.358V     1.591V
750.8ps   1.821V     1.359V     1.091V
900.9ps   1.479V     1.362V     784.3mV
1.191ns   837mV      1.353V     446.5mV
1.441ns   498.1mV    1.196V     278.6mV
2.132ns   141.4mV    457.8mV    41.26mV
2.623ns   57.19mV    181.5mV    5.935mV
4.985ns   336.7uV    198.3uV    1.007mV
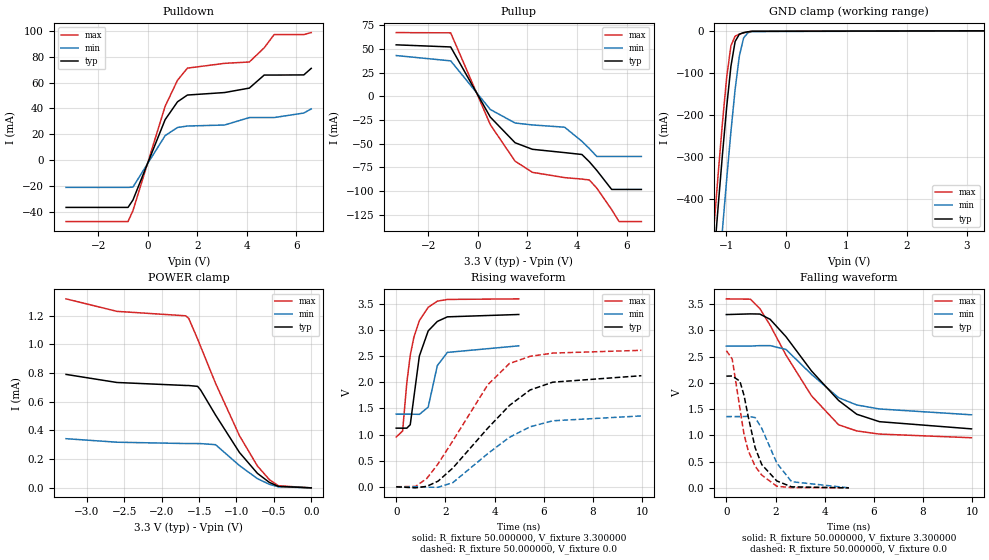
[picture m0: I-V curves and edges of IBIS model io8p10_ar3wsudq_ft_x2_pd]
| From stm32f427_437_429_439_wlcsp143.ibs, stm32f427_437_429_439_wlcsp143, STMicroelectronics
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|   Model io8p10_ar3wsudq_ft_x2_pd
[Model]  io8p10_ar3wsudq_ft_x2_pd
Model_type I/O
Polarity   Non-Inverting
Enable   Active-Low
Vinl =   0.990000V
Vinh =   2.310000V
Vmeas =  1.650000V
Cref =   40.000000pF
Rref =   100.000000M
Vref =   0.0V
C_comp   7.528700pF   7.342900pF   7.752900pF
[Temperature Range]   25.000000   0.125000k   -40.000000
[Pullup Reference]   3.300000V   2.700000V   3.600000V
[Pulldown Reference]   0.0V   0.0V   0.0V
[POWER Clamp Reference]   3.300000V   2.700000V   3.600000V
[GND Clamp Reference]   0.0V   0.0V   0.0V
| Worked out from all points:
|   slope of the pulldown table from 0 to 0.495 V, typ, clamps not added: 20.9 ohm
|   slope of the pullup table from 0 to 0.495 V, typ, clamps not added: 22.6 ohm
|   GND clamp passes 1 mA (typ) near -0.56 V on its own axis
|   rising waveform, R_fixture 50.000000, V_fixture 3.300000: 20-80 % time 482ps typ, 433ps min, 512ps max; typ from 1.12 V to 3.3 V
|   rising waveform, R_fixture 50.000000, V_fixture 0.0: 20-80 % time 2.52ns typ, 2.26ns min, 2.13ns max; typ from 0 V to 2.13 V
|   falling waveform, R_fixture 50.000000, V_fixture 3.300000: 20-80 % time 2.36ns typ, 1.93ns min, 2.08ns max; typ from 3.3 V to 1.12 V
|   falling waveform, R_fixture 50.000000, V_fixture 0.0: 20-80 % time 716ps typ, 843ps min, 660ps max; typ from 2.13 V to 0 V
[Pulldown]
|Voltage   I(typ)   I(min)   I(max)
-3.3V     -36.18mA   -20.77mA   -47.07mA
-800mV    -36.18mA   -20.77mA   -47.07mA
-600mV    -30.5mA    -20.52mA   -38.69mA
700mV     31.4mA     19.11mA    41.71mA
1.2V      45.15mA    25.37mA    61.75mA
1.6V      50.35mA    26.5mA     71.06mA
3.1V      52.27mA    27.26mA    74.75mA
4.1V      55.7mA     33.01mA    75.8mA
4.7V      65.73mA    33.01mA    86.69mA
5.1V      65.73mA    33.01mA    96.89mA
6.3V      65.85mA    36.49mA    96.89mA
6.6V      70.9mA     39.7mA     98.44mA
[Pullup]
|Voltage   I(typ)   I(min)   I(max)
-3.3V     54.22mA    42.91mA    67.15mA
-1.1V     51.98mA    37.3mA     66.87mA
500mV     -22.07mA   -14mA      -30.03mA
1.5V      -49.1mA    -28.3mA    -68.56mA
2.2V      -56.04mA   -30.32mA   -80.35mA
3.5V      -59.53mA   -32.72mA   -85.92mA
4.2V      -61.52mA   -47.6mA    -87.46mA
4.5V      -69.21mA   -55.3mA    -88.43mA
4.8V      -78.3mA    -63.6mA    -97.02mA
5.4V      -98.4mA    -63.6mA    -119.7mA
5.7V      -98.4mA    -63.6mA    -132.3mA
6.6V      -98.4mA    -63.6mA    -132.3mA
[GND_clamp]
|Voltage   I(typ)   I(min)   I(max)
-3.3V     -4.651A    -4.809A    -4.599A
-1.2V     -540.3mA   -722.7mA   -464.2mA
-1.13V    -414.5mA   -596.2mA   -338mA
-1.06V    -293.4mA   -472.4mA   -217.6mA
-990mV    -180.4mA   -352.9mA   -109.9mA
-920mV    -84.42mA   -240mA     -35.37mA
-850mV    -25.16mA   -138.9mA   -12.54mA
-780mV    -7.954mA   -60.02mA   -7.786mA
-710mV    -4.211mA   -17.24mA   -4.778mA
-640mV    -2.308mA   -4.575mA   -2.453mA
-570mV    -1.059mA   -1.652mA   -967uA
3.28V     81.28uA    57.88uA    93.98uA
[POWER_clamp]
|Voltage   I(typ)   I(min)   I(max)
-3.28V    790.5uA    342.5uA    1.317mA
-2.6V     734.3uA    318.1uA    1.23mA
-1.68V    713.4uA    308.8uA    1.199mA
-1.64V    713.1uA    308.7uA    1.182mA
-1.52V    707.2uA    308.5uA    1.037mA
-1.48V    682.1uA    308.4uA    984.7uA
-1.28V    507.2uA    300.7uA    728.4uA
-960mV    246.2uA    155.1uA    363.1uA
-720mV    101uA      64.07uA    152.4uA
-560mV    37.87uA    24.53uA    57.3uA
-440mV    10.21uA    7.381uA    14.65uA
0V        0A         0A         0A
[Ramp]
| variable   typ   min   max
dV/dt_r  1.26498/2.50517n   0.80832/2.24909n   1.56252/2.12224n
dV/dt_f  1.28118/2.33525n   0.77268/1.90268n   1.57381/2.07382n
R_load = 50.000000
[Rising Waveform]
R_fixture= 50.000000
V_fixture= 3.300000
V_fixture_min= 2.700000
V_fixture_max= 3.600000
|time   V(typ)   V(min)   V(max)
0s        1.123V     1.391V     953.8mV
260.3ps   1.123V     1.391V     1.069V
430.4ps   1.123V     1.391V     1.989V
570.6ps   1.189V     1.391V     2.516V
720.7ps   1.721V     1.39V      2.867V
940.9ps   2.502V     1.387V     3.18V
1.301ns   2.985V     1.526V     3.437V
1.672ns   3.166V     2.321V     3.554V
2.082ns   3.254V     2.573V     3.587V
4.985ns   3.299V     2.699V     3.598V
[Rising Waveform]
R_fixture= 50.000000
V_fixture= 0.0
V_fixture_min= 0.0
V_fixture_max= 0.0
|time   V(typ)   V(min)   V(max)
0s        324.9uV    179.1uV    1.453mV
780.8ps   -19.71mV   527.7uV    7.332mV
1.241ns   8.813mV    -7.849mV   157.8mV
1.702ns   107.9mV    -8.89mV    439.5mV
2.302ns   359.5mV    79.81mV    879.1mV
3.724ns   1.123V     635.1mV    1.954V
4.605ns   1.558V     947.6mV    2.36V
5.445ns   1.854V     1.149V     2.498V
6.366ns   2.003V     1.264V     2.56V
9.97ns    2.127V     1.357V     2.613V
[Falling Waveform]
R_fixture= 50.000000
V_fixture= 3.300000
V_fixture_min= 2.700000
V_fixture_max= 3.600000
|time   V(typ)   V(min)   V(max)
0s        3.299V     2.699V     3.598V
981ps     3.312V     2.699V     3.592V
1.361ns   3.309V     2.708V     3.415V
1.782ns   3.208V     2.708V     3.095V
2.422ns   2.88V      2.636V     2.531V
3.463ns   2.226V     2.161V     1.753V
4.565ns   1.664V     1.716V     1.201V
5.305ns   1.401V     1.578V     1.083V
6.226ns   1.26V      1.502V     1.024V
9.97ns    1.123V     1.391V     953.8mV
[Falling Waveform]
R_fixture= 50.000000
V_fixture= 0.0
V_fixture_min= 0.0
V_fixture_max= 0.0
|time   V(typ)   V(min)   V(max)
0s        2.127V     1.357V     2.613V
240.2ps   2.13V      1.357V     2.453V
550.6ps   2.031V     1.357V     1.519V
720.7ps   1.759V     1.358V     1.015V
890.9ps   1.355V     1.362V     706.4mV
1.171ns   765mV      1.338V     411.7mV
1.441ns   442.9mV    1.132V     243.4mV
2.052ns   131.7mV    473mV      30.42mV
2.653ns   19.29mV    117.5mV    4.56mV
4.985ns   324.9uV    179.1uV    1.453mV
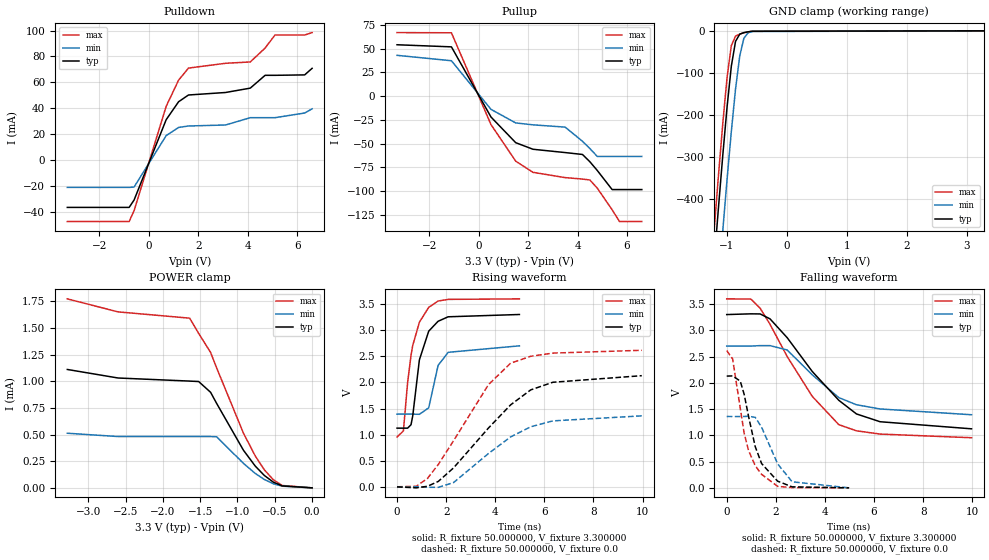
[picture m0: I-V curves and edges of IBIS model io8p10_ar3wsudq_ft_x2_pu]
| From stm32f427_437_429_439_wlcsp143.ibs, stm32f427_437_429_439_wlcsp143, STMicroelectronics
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|   Model io8p10_ar3wsudq_ft_x2_pu
[Model]  io8p10_ar3wsudq_ft_x2_pu
Model_type I/O
Polarity   Non-Inverting
Enable   Active-Low
Vinl =   0.990000V
Vinh =   2.310000V
Vmeas =  1.650000V
Cref =   40.000000pF
Rref =   100.000000M
Vref =   0.0V
C_comp   7.528700pF   7.342900pF   7.752900pF
[Temperature Range]   25.000000   0.125000k   -40.000000
[Pullup Reference]   3.300000V   2.700000V   3.600000V
[Pulldown Reference]   0.0V   0.0V   0.0V
[POWER Clamp Reference]   3.300000V   2.700000V   3.600000V
[GND Clamp Reference]   0.0V   0.0V   0.0V
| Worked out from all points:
|   slope of the pulldown table from 0 to 0.495 V, typ, clamps not added: 20.9 ohm
|   slope of the pullup table from 0 to 0.495 V, typ, clamps not added: 22.6 ohm
|   GND clamp passes 1 mA (typ) near -0.57 V on its own axis
|   POWER clamp passes 1 mA (typ) near -1.55 V on its own axis
|   rising waveform, R_fixture 50.000000, V_fixture 3.300000: 20-80 % time 479ps typ, 430ps min, 510ps max; typ from 1.12 V to 3.3 V
|   rising waveform, R_fixture 50.000000, V_fixture 0.0: 20-80 % time 2.52ns typ, 2.27ns min, 2.13ns max; typ from 0.001 V to 2.13 V
|   falling waveform, R_fixture 50.000000, V_fixture 3.300000: 20-80 % time 2.36ns typ, 1.93ns min, 2.08ns max; typ from 3.3 V to 1.12 V
|   falling waveform, R_fixture 50.000000, V_fixture 0.0: 20-80 % time 719ps typ, 846ps min, 663ps max; typ from 2.13 V to 0.001 V
[Pulldown]
|Voltage   I(typ)   I(min)   I(max)
-3.3V     -36.18mA   -20.77mA   -47.07mA
-800mV    -36.18mA   -20.77mA   -47.07mA
-600mV    -30.5mA    -20.52mA   -38.69mA
700mV     31.4mA     19.11mA    41.71mA
1.2V      45.15mA    25.37mA    61.75mA
1.6V      50.35mA    26.5mA     71.06mA
3.1V      52.28mA    27.26mA    74.76mA
4.1V      55.65mA    32.89mA    75.79mA
4.7V      65.5mA     32.89mA    86.49mA
5.1V      65.5mA     32.89mA    96.55mA
6.3V      65.83mA    36.49mA    96.55mA
6.6V      70.88mA    39.7mA     98.4mA
[Pullup]
|Voltage   I(typ)   I(min)   I(max)
-3.3V     54.05mA    42.9mA     66.88mA
-1.1V     51.84mA    37.22mA    66.66mA
500mV     -22.06mA   -14mA      -30.03mA
1.5V      -49.1mA    -28.3mA    -68.56mA
2.2V      -56.04mA   -30.32mA   -80.35mA
3.5V      -59.52mA   -32.71mA   -85.91mA
4.2V      -61.51mA   -47.6mA    -87.45mA
4.5V      -69.2mA    -55.3mA    -88.42mA
4.8V      -78.4mA    -63.6mA    -97mA
5.4V      -98.5mA    -63.6mA    -119.8mA
5.7V      -98.5mA    -63.6mA    -132.2mA
6.6V      -98.5mA    -63.6mA    -132.2mA
[GND_clamp]
|Voltage   I(typ)   I(min)   I(max)
-3.3V     -4.652A    -4.81A     -4.601A
-1.2V     -540.3mA   -722.7mA   -464.2mA
-1.13V    -414.5mA   -596.2mA   -338mA
-1.06V    -293.4mA   -472.4mA   -217.6mA
-990mV    -180.4mA   -352.9mA   -109.9mA
-920mV    -84.42mA   -240mA     -35.36mA
-850mV    -25.15mA   -138.9mA   -12.53mA
-780mV    -7.942mA   -60.01mA   -7.772mA
-710mV    -4.199mA   -17.23mA   -4.763mA
-640mV    -2.296mA   -4.566mA   -2.439mA
-570mV    -1.048mA   -1.643mA   -953.6uA
3.28V     0A         0A         0A
[POWER_clamp]
|Voltage   I(typ)   I(min)   I(max)
-3.28V    1.11mA     512.1uA    1.772mA
-2.6V     1.03mA     481uA      1.65mA
-1.64V    1.001mA    481uA      1.591mA
-1.52V    996.9uA    481uA      1.448mA
-1.36V    895.8uA    481uA      1.27mA
-1.28V    792.9uA    479.1uA    1.126mA
-920mV    352.7uA    229.7uA    512.9uA
-760mV    202.7uA    133.9uA    297uA
-640mV    116.1uA    78.59uA    169.1uA
-520mV    53.85uA    38.6uA     76.2uA
-400mV    18.17uA    15.42uA    22.14uA
0V        0A         0A         0A
[Ramp]
| variable   typ   min   max
dV/dt_r  1.26547/2.50866n   0.80895/2.25382n   1.56286/2.12449n
dV/dt_f  1.28070/2.33471n   0.77172/1.90493n   1.57348/2.07323n
R_load = 50.000000
[Rising Waveform]
R_fixture= 50.000000
V_fixture= 3.300000
V_fixture_min= 2.700000
V_fixture_max= 3.600000
|time   V(typ)   V(min)   V(max)
0s        1.125V     1.393V     955.4mV
260.3ps   1.125V     1.393V     1.071V
430.4ps   1.125V     1.393V     1.993V
570.6ps   1.191V     1.393V     2.521V
640.6ps   1.362V     1.393V     2.708V
910.9ps   2.432V     1.39V      3.152V
1.291ns   2.981V     1.514V     3.437V
1.672ns   3.17V      2.324V     3.557V
2.082ns   3.256V     2.576V     3.589V
4.985ns   3.3V       2.7V       3.599V
[Rising Waveform]
R_fixture= 50.000000
V_fixture= 0.0
V_fixture_min= 0.0
V_fixture_max= 0.0
|time   V(typ)   V(min)   V(max)
0s        1.413mV    1.222mV    2.588mV
780.8ps   -17.57mV   1.569mV    11.54mV
1.241ns   12.41mV    -6.727mV   163.2mV
1.682ns   105.6mV    -7.847mV   430.8mV
2.302ns   364.2mV    83.14mV    883.7mV
3.724ns   1.127V     638.8mV    1.957V
4.625ns   1.57V      956.2mV    2.368V
5.445ns   1.857V     1.151V     2.5V
6.346ns   2.003V     1.264V     2.561V
9.97ns    2.129V     1.36V      2.615V
[Falling Waveform]
R_fixture= 50.000000
V_fixture= 3.300000
V_fixture_min= 2.700000
V_fixture_max= 3.600000
|time   V(typ)   V(min)   V(max)
0s        3.3V       2.7V       3.599V
981ps     3.314V     2.7V       3.596V
1.361ns   3.312V     2.709V     3.42V
1.762ns   3.219V     2.709V     3.116V
2.462ns   2.86V      2.626V     2.501V
3.483ns   2.217V     2.153V     1.743V
4.565ns   1.668V     1.719V     1.204V
5.285ns   1.408V     1.583V     1.087V
6.246ns   1.26V      1.503V     1.025V
9.97ns    1.125V     1.393V     955.4mV
[Falling Waveform]
R_fixture= 50.000000
V_fixture= 0.0
V_fixture_min= 0.0
V_fixture_max= 0.0
|time   V(typ)   V(min)   V(max)
0s        2.129V     1.36V      2.615V
240.2ps   2.132V     1.359V     2.455V
550.6ps   2.033V     1.359V     1.52V
710.7ps   1.781V     1.36V      1.041V
890.9ps   1.357V     1.364V     709.5mV
1.161ns   784.6mV    1.344V     423.3mV
1.421ns   463mV      1.155V     258.1mV
2.072ns   128.6mV    458.6mV    29.19mV
2.663ns   20.26mV    116.6mV    6.213mV
4.985ns   1.413mV    1.222mV    2.588mV
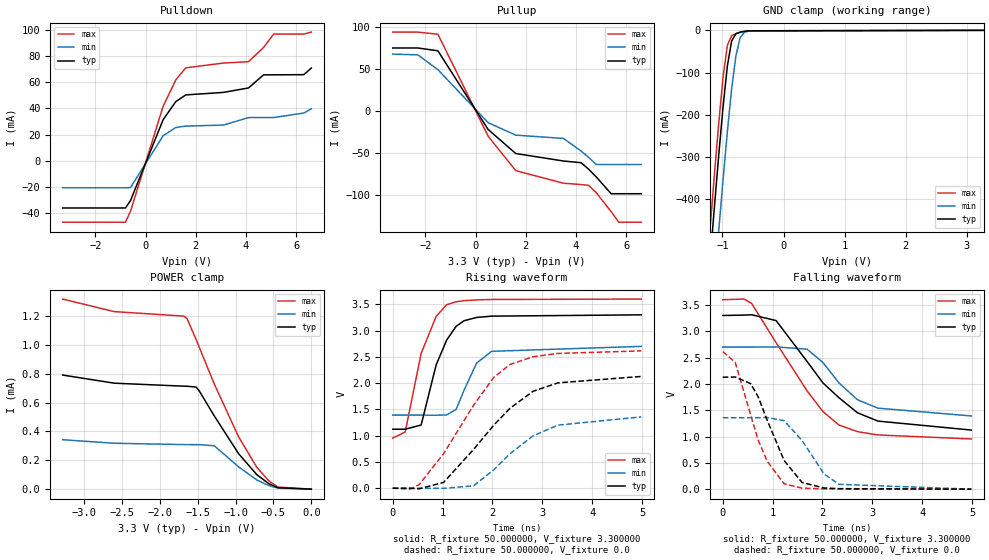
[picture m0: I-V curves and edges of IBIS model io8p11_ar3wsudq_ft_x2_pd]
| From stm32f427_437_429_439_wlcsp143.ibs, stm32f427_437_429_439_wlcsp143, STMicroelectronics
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|   Model io8p11_ar3wsudq_ft_x2_pd
[Model]  io8p11_ar3wsudq_ft_x2_pd
Model_type I/O
Polarity   Non-Inverting
Enable   Active-Low
Vinl =   0.990000V
Vinh =   2.310000V
Vmeas =  1.650000V
Cref =   30.000000pF
Rref =   100.000000M
Vref =   0.0V
C_comp   7.528700pF   7.342900pF   7.752900pF
[Temperature Range]   25.000000   0.125000k   -40.000000
[Pullup Reference]   3.300000V   2.700000V   3.600000V
[Pulldown Reference]   0.0V   0.0V   0.0V
[POWER Clamp Reference]   3.300000V   2.700000V   3.600000V
[GND Clamp Reference]   0.0V   0.0V   0.0V
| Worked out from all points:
|   slope of the pulldown table from 0 to 0.495 V, typ, clamps not added: 20.9 ohm
|   slope of the pullup table from 0 to 0.495 V, typ, clamps not added: 22.6 ohm
|   GND clamp passes 1 mA (typ) near -0.56 V on its own axis
|   rising waveform, R_fixture 50.000000, V_fixture 3.300000: 20-80 % time 433ps typ, 375ps min, 444ps max; typ from 1.12 V to 3.3 V
|   rising waveform, R_fixture 50.000000, V_fixture 0.0: 20-80 % time 1.22ns typ, 1.05ns min, 1.08ns max; typ from 0 V to 2.13 V
|   falling waveform, R_fixture 50.000000, V_fixture 3.300000: 20-80 % time 1.18ns typ, 813ps min, 1.1ns max; typ from 3.3 V to 1.12 V
|   falling waveform, R_fixture 50.000000, V_fixture 0.0: 20-80 % time 567ps typ, 581ps min, 523ps max; typ from 2.13 V to 0 V
[Pulldown]
|Voltage   I(typ)   I(min)   I(max)
-3.3V     -36.18mA   -20.77mA   -47.07mA
-800mV    -36.18mA   -20.77mA   -47.07mA
-600mV    -30.5mA    -20.52mA   -38.69mA
700mV     31.4mA     19.11mA    41.71mA
1.2V      45.15mA    25.37mA    61.75mA
1.6V      50.35mA    26.5mA     71.06mA
3.1V      52.27mA    27.26mA    74.75mA
4.1V      55.7mA     33.01mA    75.8mA
4.7V      65.73mA    33.01mA    86.69mA
5.1V      65.73mA    33.01mA    96.89mA
6.3V      65.85mA    36.49mA    96.89mA
6.6V      70.9mA     39.7mA     98.44mA
[Pullup]
|Voltage   I(typ)   I(min)   I(max)
-3.3V     74.74mA    67.41mA    93.6mA
-2.3V     74.74mA    66.57mA    93.6mA
-1.5V     71.36mA    49.01mA    91.03mA
500mV     -22.07mA   -14mA      -30.03mA
1.6V      -50.64mA   -28.81mA   -70.96mA
3.5V      -59.53mA   -32.72mA   -85.92mA
4.2V      -61.52mA   -47.6mA    -87.46mA
4.5V      -69.21mA   -55.2mA    -88.43mA
4.8V      -78.3mA    -63.6mA    -97.02mA
5.4V      -98.4mA    -63.6mA    -119.7mA
5.7V      -98.4mA    -63.6mA    -132.2mA
6.6V      -98.4mA    -63.6mA    -132.2mA
[GND_clamp]
|Voltage   I(typ)   I(min)   I(max)
-3.3V     -4.649A    -4.808A    -4.597A
-1.2V     -540.3mA   -722.7mA   -464.2mA
-1.13V    -414.5mA   -596.2mA   -338mA
-1.06V    -293.4mA   -472.4mA   -217.6mA
-990mV    -180.4mA   -352.9mA   -109.9mA
-920mV    -84.42mA   -240mA     -35.37mA
-850mV    -25.16mA   -138.9mA   -12.54mA
-780mV    -7.954mA   -60.02mA   -7.786mA
-710mV    -4.211mA   -17.24mA   -4.778mA
-640mV    -2.308mA   -4.575mA   -2.453mA
-570mV    -1.059mA   -1.652mA   -967uA
3.28V     81.28uA    57.88uA    93.98uA
[POWER_clamp]
|Voltage   I(typ)   I(min)   I(max)
-3.28V    790.5uA    342.5uA    1.317mA
-2.6V     734.3uA    318.1uA    1.23mA
-1.68V    713.4uA    308.8uA    1.199mA
-1.64V    713.1uA    308.7uA    1.182mA
-1.52V    707.2uA    308.5uA    1.037mA
-1.48V    682.1uA    308.4uA    984.7uA
-1.28V    507.2uA    300.7uA    728.4uA
-960mV    246.2uA    155.1uA    363.1uA
-720mV    101uA      64.07uA    152.4uA
-560mV    37.87uA    24.53uA    57.3uA
-440mV    10.21uA    7.381uA    14.65uA
0V        0A         0A         0A
[Ramp]
| variable   typ   min   max
dV/dt_r  1.25202/1.19319n   0.78504/1.00414n   1.55760/1.07167n
dV/dt_f  1.26834/1.14771n   0.74784/0.77296n   1.56691/1.08849n
R_load = 50.000000
[Rising Waveform]
R_fixture= 50.000000
V_fixture= 3.300000
V_fixture_min= 2.700000
V_fixture_max= 3.600000
|time   V(typ)   V(min)   V(max)
0s        1.123V     1.391V     953.8mV
250.2ps   1.123V     1.391V     1.069V
570.6ps   1.203V     1.391V     2.565V
870.9ps   2.346V     1.389V     3.27V
1.081ns   2.817V     1.395V     3.491V
1.271ns   3.08V      1.498V     3.547V
1.431ns   3.187V     1.866V     3.568V
1.682ns   3.249V     2.38V      3.583V
1.982ns   3.274V     2.605V     3.591V
4.985ns   3.299V     2.699V     3.599V
[Rising Waveform]
R_fixture= 50.000000
V_fixture= 0.0
V_fixture_min= 0.0
V_fixture_max= 0.0
|time   V(typ)   V(min)   V(max)
0s        339.4uV    175.3uV    1.051mV
340.3ps   -684.2uV   141.1uV    -17.61mV
530.5ps   -11.02mV   216.7uV    68.59mV
1.021ns   110.8mV    -2.483mV   658.2mV
1.622ns   739.1mV    46.3mV     1.581V
2.032ns   1.206V     356.1mV    2.114V
2.352ns   1.521V     656.3mV    2.354V
2.813ns   1.844V     997.3mV    2.502V
3.313ns   2.005V     1.201V     2.565V
4.985ns   2.127V     1.357V     2.613V
[Falling Waveform]
R_fixture= 50.000000
V_fixture= 3.300000
V_fixture_min= 2.700000
V_fixture_max= 3.600000
|time   V(typ)   V(min)   V(max)
0s        3.299V     2.699V     3.599V
430.4ps   3.306V     2.699V     3.611V
580.6ps   3.313V     2.699V     3.527V
1.071ns   3.202V     2.702V     2.782V
1.692ns   2.425V     2.659V     1.867V
2.012ns   2.016V     2.404V     1.472V
2.332ns   1.736V     2.017V     1.219V
2.703ns   1.451V     1.698V     1.092V
3.113ns   1.293V     1.539V     1.03V
4.985ns   1.123V     1.391V     953.8mV
[Falling Waveform]
R_fixture= 50.000000
V_fixture= 0.0
V_fixture_min= 0.0
V_fixture_max= 0.0
|time   V(typ)   V(min)   V(max)
0s        2.127V     1.357V     2.613V
250.2ps   2.13V      1.357V     2.41V
560.6ps   2.005V     1.357V     1.41V
710.7ps   1.756V     1.358V     933.5mV
890.9ps   1.312V     1.361V     532.3mV
1.231ns   544.8mV    1.302V     102.6mV
1.592ns   126.4mV    922.3mV    19.05mV
2.032ns   22.78mV    288.1mV    6.252mV
2.332ns   9.886mV    92.18mV    4.155mV
4.985ns   339.4uV    175.3uV    1.051mV
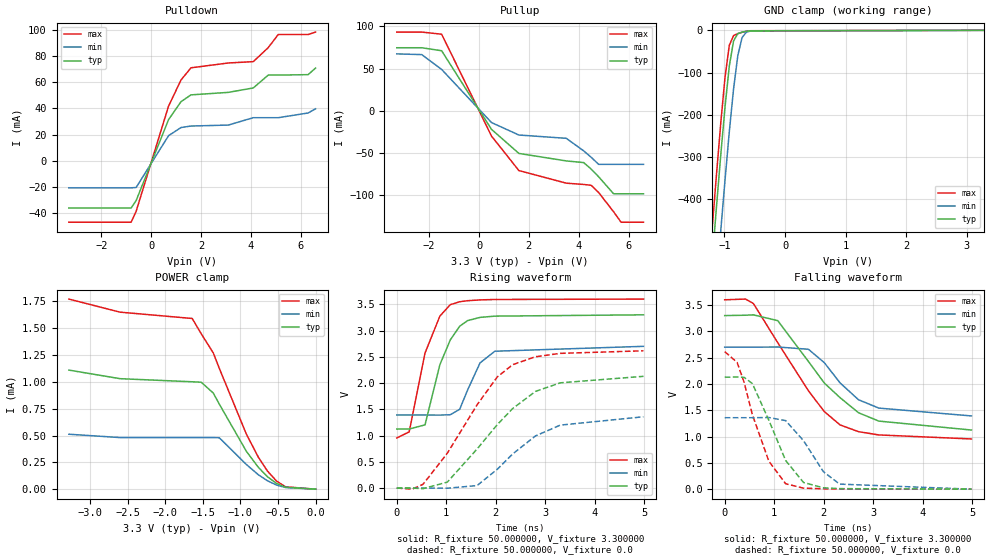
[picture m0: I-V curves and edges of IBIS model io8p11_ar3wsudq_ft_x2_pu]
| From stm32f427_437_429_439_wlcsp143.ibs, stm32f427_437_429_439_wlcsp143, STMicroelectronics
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|   Model io8p11_ar3wsudq_ft_x2_pu
[Model]  io8p11_ar3wsudq_ft_x2_pu
Model_type I/O
Polarity   Non-Inverting
Enable   Active-Low
Vinl =   0.990000V
Vinh =   2.310000V
Vmeas =  1.650000V
Cref =   30.000000pF
Rref =   100.000000M
Vref =   0.0V
C_comp   7.528700pF   7.342900pF   7.752900pF
[Temperature Range]   25.000000   0.125000k   -40.000000
[Pullup Reference]   3.300000V   2.700000V   3.600000V
[Pulldown Reference]   0.0V   0.0V   0.0V
[POWER Clamp Reference]   3.300000V   2.700000V   3.600000V
[GND Clamp Reference]   0.0V   0.0V   0.0V
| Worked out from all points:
|   slope of the pulldown table from 0 to 0.495 V, typ, clamps not added: 20.9 ohm
|   slope of the pullup table from 0 to 0.495 V, typ, clamps not added: 22.6 ohm
|   GND clamp passes 1 mA (typ) near -0.57 V on its own axis
|   POWER clamp passes 1 mA (typ) near -1.55 V on its own axis
|   rising waveform, R_fixture 50.000000, V_fixture 3.300000: 20-80 % time 430ps typ, 374ps min, 442ps max; typ from 1.12 V to 3.3 V
|   rising waveform, R_fixture 50.000000, V_fixture 0.0: 20-80 % time 1.22ns typ, 1.05ns min, 1.08ns max; typ from 0.001 V to 2.13 V
|   falling waveform, R_fixture 50.000000, V_fixture 3.300000: 20-80 % time 1.18ns typ, 813ps min, 1.1ns max; typ from 3.3 V to 1.12 V
|   falling waveform, R_fixture 50.000000, V_fixture 0.0: 20-80 % time 568ps typ, 582ps min, 524ps max; typ from 2.13 V to 0.001 V
[Pulldown]
|Voltage   I(typ)   I(min)   I(max)
-3.3V     -36.18mA   -20.77mA   -47.07mA
-800mV    -36.18mA   -20.77mA   -47.07mA
-600mV    -30.5mA    -20.52mA   -38.69mA
700mV     31.4mA     19.11mA    41.71mA
1.2V      45.15mA    25.37mA    61.75mA
1.6V      50.35mA    26.5mA     71.06mA
3.1V      52.28mA    27.26mA    74.76mA
4.1V      55.65mA    32.89mA    75.79mA
4.7V      65.5mA     32.89mA    86.49mA
5.1V      65.5mA     32.89mA    96.55mA
6.3V      65.83mA    36.49mA    96.55mA
6.6V      70.88mA    39.7mA     98.4mA
[Pullup]
|Voltage   I(typ)   I(min)   I(max)
-3.3V     74.71mA    67.42mA    93.28mA
-2.3V     74.71mA    66.58mA    93.28mA
-1.5V     71.15mA    49mA       90.77mA
500mV     -22.06mA   -14mA      -30.03mA
1.6V      -50.64mA   -28.81mA   -70.96mA
3.5V      -59.52mA   -32.71mA   -85.91mA
4.2V      -61.51mA   -47.6mA    -87.45mA
4.5V      -69.2mA    -55.2mA    -88.42mA
4.8V      -78.3mA    -63.6mA    -97mA
5.4V      -98.5mA    -63.6mA    -119.8mA
5.7V      -98.5mA    -63.6mA    -132.2mA
6.6V      -98.5mA    -63.6mA    -132.2mA
[GND_clamp]
|Voltage   I(typ)   I(min)   I(max)
-3.3V     -4.651A    -4.809A    -4.599A
-1.2V     -540.3mA   -722.7mA   -464.2mA
-1.13V    -414.5mA   -596.2mA   -338mA
-1.06V    -293.4mA   -472.4mA   -217.6mA
-990mV    -180.4mA   -352.9mA   -109.9mA
-920mV    -84.42mA   -240mA     -35.36mA
-850mV    -25.15mA   -138.9mA   -12.53mA
-780mV    -7.942mA   -60.01mA   -7.772mA
-710mV    -4.199mA   -17.23mA   -4.763mA
-640mV    -2.296mA   -4.566mA   -2.439mA
-570mV    -1.048mA   -1.643mA   -953.6uA
3.28V     0A         0A         0A
[POWER_clamp]
|Voltage   I(typ)   I(min)   I(max)
-3.28V    1.11mA     512.1uA    1.772mA
-2.6V     1.03mA     481uA      1.65mA
-1.64V    1.001mA    481uA      1.591mA
-1.52V    996.9uA    481uA      1.448mA
-1.36V    895.8uA    481uA      1.27mA
-1.28V    792.9uA    479.1uA    1.126mA
-920mV    352.7uA    229.7uA    512.9uA
-760mV    202.7uA    133.9uA    297uA
-640mV    116.1uA    78.59uA    169.1uA
-520mV    53.85uA    38.6uA     76.2uA
-400mV    18.17uA    15.42uA    22.14uA
0V        0A         0A         0A
[Ramp]
| variable   typ   min   max
dV/dt_r  1.25251/1.19454n   0.78549/1.00529n   1.55800/1.07277n
dV/dt_f  1.26780/1.14806n   0.74700/0.77365n   1.56656/1.08857n
R_load = 50.000000
[Rising Waveform]
R_fixture= 50.000000
V_fixture= 3.300000
V_fixture_min= 2.700000
V_fixture_max= 3.600000
|time   V(typ)   V(min)   V(max)
0s        1.125V     1.393V     955.4mV
250.2ps   1.125V     1.393V     1.071V
570.6ps   1.205V     1.393V     2.571V
870.9ps   2.351V     1.391V     3.276V
1.081ns   2.822V     1.398V     3.493V
1.271ns   3.083V     1.501V     3.549V
1.431ns   3.19V      1.869V     3.569V
1.682ns   3.251V     2.384V     3.584V
1.982ns   3.275V     2.607V     3.592V
4.985ns   3.3V       2.7V       3.6V
[Rising Waveform]
R_fixture= 50.000000
V_fixture= 0.0
V_fixture_min= 0.0
V_fixture_max= 0.0
|time   V(typ)   V(min)   V(max)
0s        1.427mV    1.218mV    2.188mV
310.3ps   1.312mV    1.184mV    -19.38mV
530.5ps   -9.848mV   1.259mV    72.77mV
1.021ns   114.7mV    -1.424mV   664.8mV
1.622ns   745mV      48.88mV    1.586V
2.032ns   1.211V     360.5mV    2.119V
2.342ns   1.516V     651.7mV    2.351V
2.803ns   1.842V     994.4mV    2.502V
3.303ns   2.005V     1.2V       2.566V
4.985ns   2.129V     1.359V     2.615V
[Falling Waveform]
R_fixture= 50.000000
V_fixture= 3.300000
V_fixture_min= 2.700000
V_fixture_max= 3.600000
|time   V(typ)   V(min)   V(max)
0s        3.3V       2.7V       3.6V
420.4ps   3.307V     2.7V       3.614V
580.6ps   3.314V     2.7V       3.529V
1.071ns   3.204V     2.703V     2.786V
1.692ns   2.428V     2.66V      1.871V
2.012ns   2.019V     2.406V     1.476V
2.332ns   1.739V     2.02V      1.222V
2.703ns   1.454V     1.701V     1.094V
3.113ns   1.295V     1.542V     1.032V
4.985ns   1.125V     1.393V     955.4mV
[Falling Waveform]
R_fixture= 50.000000
V_fixture= 0.0
V_fixture_min= 0.0
V_fixture_max= 0.0
|time   V(typ)   V(min)   V(max)
0s        2.129V     1.359V     2.615V
250.2ps   2.132V     1.359V     2.411V
390.4ps   2.127V     1.359V     2.038V
560.6ps   2.007V     1.359V     1.412V
890.9ps   1.314V     1.363V     535.1mV
1.231ns   547.4mV    1.304V     104.5mV
1.592ns   128.3mV    924.1mV    20.45mV
1.992ns   27.61mV    335.4mV    7.913mV
2.322ns   11.45mV    97.23mV    5.422mV
4.985ns   1.427mV    1.218mV    2.188mV
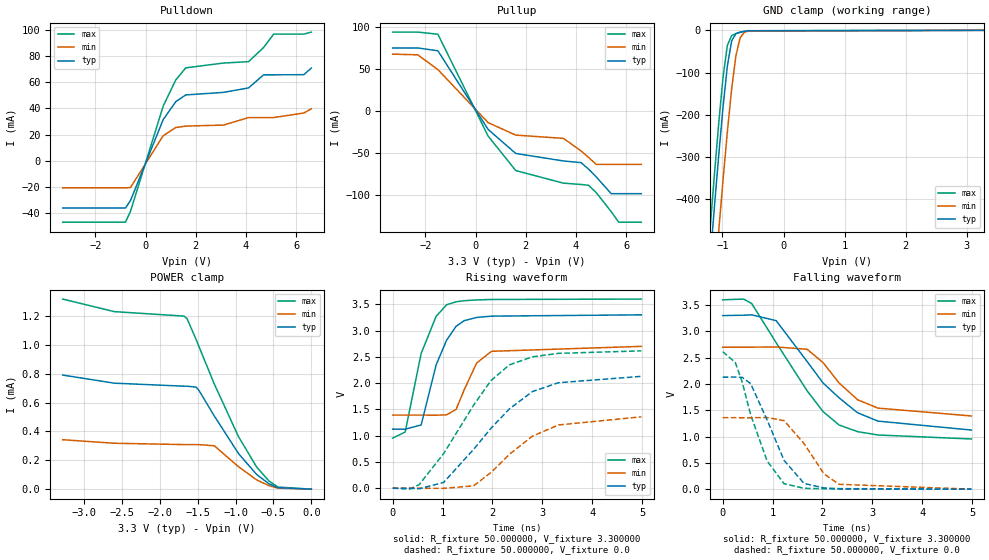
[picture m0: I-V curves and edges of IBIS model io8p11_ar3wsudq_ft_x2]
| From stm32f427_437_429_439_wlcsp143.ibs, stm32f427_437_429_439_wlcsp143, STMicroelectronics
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|   Model io8p11_ar3wsudq_ft_x2
[Model]  io8p11_ar3wsudq_ft_x2
Model_type I/O
Polarity   Non-Inverting
Enable   Active-Low
Vinl =   0.990000V
Vinh =   2.310000V
Vmeas =  1.650000V
Cref =   30.000000pF
Rref =   100.000000M
Vref =   0.0V
C_comp   7.528700pF   7.342900pF   7.752900pF
[Temperature Range]   25.000000   0.125000k   -40.000000
[Pullup Reference]   3.300000V   2.700000V   3.600000V
[Pulldown Reference]   0.0V   0.0V   0.0V
[POWER Clamp Reference]   3.300000V   2.700000V   3.600000V
[GND Clamp Reference]   0.0V   0.0V   0.0V
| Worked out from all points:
|   slope of the pulldown table from 0 to 0.495 V, typ, clamps not added: 20.9 ohm
|   slope of the pullup table from 0 to 0.495 V, typ, clamps not added: 22.6 ohm
|   GND clamp passes 1 mA (typ) near -0.57 V on its own axis
|   rising waveform, R_fixture 50.000000, V_fixture 3.300000: 20-80 % time 432ps typ, 375ps min, 444ps max; typ from 1.12 V to 3.3 V
|   rising waveform, R_fixture 50.000000, V_fixture 0.0: 20-80 % time 1.22ns typ, 1.05ns min, 1.08ns max; typ from 0 V to 2.13 V
|   falling waveform, R_fixture 50.000000, V_fixture 3.300000: 20-80 % time 1.18ns typ, 814ps min, 1.1ns max; typ from 3.3 V to 1.12 V
|   falling waveform, R_fixture 50.000000, V_fixture 0.0: 20-80 % time 567ps typ, 582ps min, 524ps max; typ from 2.13 V to 0 V
[Pulldown]
|Voltage   I(typ)   I(min)   I(max)
-3.3V     -36.18mA   -20.77mA   -47.07mA
-800mV    -36.18mA   -20.77mA   -47.07mA
-600mV    -30.5mA    -20.52mA   -38.69mA
700mV     31.4mA     19.11mA    41.71mA
1.2V      45.15mA    25.37mA    61.75mA
1.6V      50.35mA    26.5mA     71.06mA
3.1V      52.28mA    27.26mA    74.75mA
4.1V      55.71mA    33.01mA    75.8mA
4.7V      65.73mA    33.01mA    86.69mA
5.1V      65.73mA    33.01mA    96.9mA
6.3V      65.85mA    36.5mA     96.9mA
6.6V      70.91mA    39.71mA    98.45mA
[Pullup]
|Voltage   I(typ)   I(min)   I(max)
-3.3V     74.74mA    67.41mA    93.61mA
-2.3V     74.74mA    66.57mA    93.61mA
-1.5V     71.37mA    49.01mA    91.04mA
500mV     -22.07mA   -14mA      -30.03mA
1.6V      -50.64mA   -28.81mA   -70.96mA
3.5V      -59.53mA   -32.72mA   -85.92mA
4.2V      -61.52mA   -47.6mA    -87.46mA
4.5V      -69.21mA   -55.3mA    -88.43mA
4.8V      -78.3mA    -63.6mA    -97.02mA
5.4V      -98.4mA    -63.6mA    -119.7mA
5.7V      -98.4mA    -63.6mA    -132.3mA
6.6V      -98.4mA    -63.6mA    -132.3mA
[GND_clamp]
|Voltage   I(typ)   I(min)   I(max)
-3.3V     -4.651A    -4.809A    -4.599A
-1.2V     -540.3mA   -722.7mA   -464.2mA
-1.13V    -414.5mA   -596.2mA   -338mA
-1.06V    -293.4mA   -472.4mA   -217.6mA
-990mV    -180.4mA   -352.9mA   -109.9mA
-920mV    -84.42mA   -240mA     -35.36mA
-850mV    -25.15mA   -138.9mA   -12.53mA
-780mV    -7.942mA   -60.01mA   -7.772mA
-710mV    -4.199mA   -17.23mA   -4.763mA
-640mV    -2.296mA   -4.566mA   -2.439mA
-570mV    -1.048mA   -1.643mA   -953.6uA
3.28V     0A         0A         0A
[POWER_clamp]
|Voltage   I(typ)   I(min)   I(max)
-3.28V    790.5uA    342.5uA    1.317mA
-2.6V     734.3uA    318.1uA    1.23mA
-1.68V    713.4uA    308.8uA    1.199mA
-1.64V    713.1uA    308.7uA    1.182mA
-1.52V    707.2uA    308.5uA    1.037mA
-1.48V    682.1uA    308.4uA    984.7uA
-1.28V    507.2uA    300.7uA    728.4uA
-960mV    246.2uA    155.1uA    363.1uA
-720mV    101uA      64.07uA    152.4uA
-560mV    37.87uA    24.53uA    57.3uA
-440mV    10.21uA    7.381uA    14.65uA
0V        0A         0A         0A
[Ramp]
| variable   typ   min   max
dV/dt_r  1.25250/1.19351n   0.78528/1.00453n   1.55826/1.07196n
dV/dt_f  1.26840/1.14816n   0.74748/0.77402n   1.56724/1.08853n
R_load = 50.000000
[Rising Waveform]
R_fixture= 50.000000
V_fixture= 3.300000
V_fixture_min= 2.700000
V_fixture_max= 3.600000
|time   V(typ)   V(min)   V(max)
0s        1.124V     1.392V     954.2mV
250.2ps   1.124V     1.392V     1.069V
570.6ps   1.204V     1.392V     2.566V
870.9ps   2.348V     1.39V      3.271V
1.081ns   2.818V     1.397V     3.491V
1.271ns   3.081V     1.5V       3.548V
1.431ns   3.188V     1.867V     3.568V
1.682ns   3.25V      2.382V     3.584V
1.982ns   3.275V     2.606V     3.592V
4.985ns   3.3V       2.7V       3.6V
[Rising Waveform]
R_fixture= 50.000000
V_fixture= 0.0
V_fixture_min= 0.0
V_fixture_max= 0.0
|time   V(typ)   V(min)   V(max)
0s        339.4uV    175.2uV    1.051mV
340.3ps   -684.3uV   141.1uV    -17.61mV
530.5ps   -11.02mV   216.7uV    68.59mV
1.021ns   110.8mV    -2.484mV   658.3mV
1.622ns   739.3mV    46.31mV    1.581V
1.972ns   1.143V     300.4mV    2.051V
2.342ns   1.512V     647.7mV    2.349V
2.803ns   1.84V      991.9mV    2.501V
3.323ns   2.008V     1.204V     2.567V
4.985ns   2.129V     1.359V     2.614V
[Falling Waveform]
R_fixture= 50.000000
V_fixture= 3.300000
V_fixture_min= 2.700000
V_fixture_max= 3.600000
|time   V(typ)   V(min)   V(max)
0s        3.3V       2.7V       3.6V
420.4ps   3.307V     2.7V       3.614V
580.6ps   3.314V     2.7V       3.529V
1.071ns   3.204V     2.703V     2.786V
1.692ns   2.428V     2.66V      1.871V
2.012ns   2.019V     2.406V     1.475V
2.332ns   1.738V     2.02V      1.221V
2.703ns   1.453V     1.701V     1.094V
3.113ns   1.294V     1.541V     1.03V
4.985ns   1.124V     1.392V     954.2mV
[Falling Waveform]
R_fixture= 50.000000
V_fixture= 0.0
V_fixture_min= 0.0
V_fixture_max= 0.0
|time   V(typ)   V(min)   V(max)
0s        2.129V     1.359V     2.614V
250.2ps   2.131V     1.359V     2.411V
390.4ps   2.127V     1.358V     2.038V
560.6ps   2.006V     1.358V     1.413V
890.9ps   1.314V     1.362V     534.6mV
1.231ns   546.6mV    1.303V     103.8mV
1.632ns   108mV      865.1mV    16.65mV
2.032ns   23.33mV    289mV      6.591mV
2.332ns   10.26mV    92.74mV    4.406mV
4.985ns   339.4uV    175.2uV    1.051mV
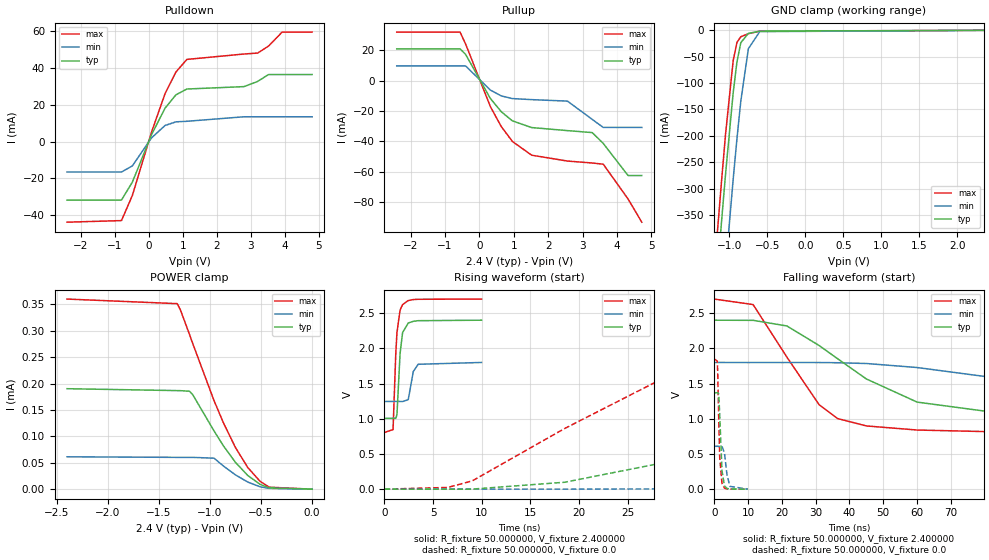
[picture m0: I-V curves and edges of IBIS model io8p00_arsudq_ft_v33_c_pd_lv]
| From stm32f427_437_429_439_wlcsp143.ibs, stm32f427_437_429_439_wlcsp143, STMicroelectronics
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|   Model io8p00_arsudq_ft_v33_c_pd_lv
[Model]  io8p00_arsudq_ft_v33_c_pd_lv
Model_type I/O
Polarity   Non-Inverting
Enable   Active-Low
Vinl =   0.720000V
Vinh =   1.680000V
Vmeas =  1.200000V
Cref =   50.000000pF
Rref =   100.000000M
Vref =   0.0V
C_comp   5.917600pF   5.759800pF   6.094800pF
[Temperature Range]   25.000000   0.125000k   -40.000000
[Pullup Reference]   2.400000V   1.800000V   2.700000V
[Pulldown Reference]   0.0V   0.0V   0.0V
[POWER Clamp Reference]   2.400000V   1.800000V   2.700000V
[GND Clamp Reference]   0.0V   0.0V   0.0V
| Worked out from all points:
|   slope of the pulldown table from 0 to 0.36 V, typ, clamps not added: 25 ohm
|   slope of the pullup table from 0 to 0.36 V, typ, clamps not added: 27.7 ohm
|   GND clamp passes 1 mA (typ) near -0.56 V on its own axis
|   rising waveform, R_fixture 50.000000, V_fixture 2.400000: 20-80 % time 337ps typ, 395ps min, 350ps max; typ from 1 V to 2.4 V
|   rising waveform, R_fixture 50.000000, V_fixture 0.0: 20-80 % time 29.1ns typ, 72.2ns min, 14.2ns max; typ from 0 V to 1.37 V
|   falling waveform, R_fixture 50.000000, V_fixture 2.400000: 20-80 % time 28.2ns typ, 59.2ns min, 15.4ns max; typ from 2.4 V to 1 V
|   falling waveform, R_fixture 50.000000, V_fixture 0.0: 20-80 % time 680ps typ, 1.02ns min, 579ps max; typ from 1.37 V to 0 V
[Pulldown]
|Voltage   I(typ)   I(min)   I(max)
-2.4V     -31.73mA   -16.51mA   -43.74mA
-800mV    -31.73mA   -16.51mA   -42.87mA
-480mV    -21.98mA   -13.17mA   -29.21mA
80mV      3.63mA     1.966mA    5.014mA
480mV     18.15mA    8.738mA    26.02mA
800mV     25.38mA    10.72mA    37.77mA
1.12V     28.53mA    11.02mA    44.6mA
2.8V      29.84mA    13.47mA    47.53mA
3.2V      32.64mA    13.47mA    48.04mA
3.52V     36.39mA    13.47mA    51.82mA
3.92V     36.39mA    13.47mA    59.43mA
4.8V      36.39mA    13.47mA    59.43mA
[Pullup]
|Voltage   I(typ)   I(min)   I(max)
-2.4V     20.89mA    9.659mA    31.9mA
-560mV    20.89mA    9.659mA    31.9mA
-400mV    17.28mA    9.659mA    24.07mA
320mV     -11.75mA   -6.207mA   -17.08mA
640mV     -20.52mA   -10.1mA    -30.35mA
960mV     -26.47mA   -11.82mA   -40.02mA
1.52V     -30.88mA   -12.51mA   -49.05mA
2.56V     -32.88mA   -13.48mA   -52.9mA
3.28V     -34.19mA   -25.5mA    -54.18mA
3.6V      -41.31mA   -30.8mA    -54.97mA
4.32V     -62.4mA    -30.8mA    -77.8mA
4.72V     -62.4mA    -30.8mA    -93.1mA
[GND_clamp]
|Voltage   I(typ)   I(min)   I(max)
-2.4V     -2.854A    -3.022A    -2.793A
-1.25V    -627.1mA   -809.1mA   -551.5mA
-1.2V     -535.5mA   -717.4mA   -459.3mA
-1.15V    -445.4mA   -626.8mA   -368.7mA
-1.1V     -357.2mA   -537.5mA   -280.5mA
-1.05V    -272mA     -449.9mA   -196.4mA
-950mV    -118.4mA   -282.5mA   -57.42mA
-900mV    -59.51mA   -205.1mA   -22.74mA
-850mV    -23.51mA   -134.9mA   -12.19mA
-750mV    -5.744mA   -34.86mA   -6.372mA
-600mV    -1.511mA   -2.391mA   -1.49mA
2.35V     58.09uA    37.93uA    67.25uA
[POWER_clamp]
|Voltage   I(typ)   I(min)   I(max)
-2.4V     190.2uA    61.28uA    359.9uA
-1.32V    186.6uA    60.21uA    351.2uA
-1.29V    186.5uA    60.2uA     339.6uA
-1.2V     185.4uA    60.18uA    292.6uA
-1.17V    179.2uA    60.17uA    276.3uA
-960mV    110.2uA    58.68uA    167.5uA
-870mV    82.45uA    44.05uA    126.3uA
-750mV    50.58uA    26.98uA    78.64uA
-630mV    25.95uA    13.47uA    41.02uA
-510mV    9.222uA    4.578uA    14.97uA
-420mV    2.426uA    1.429uA    3.749uA
0V        0A         0A         0A
[Ramp]
| variable   typ   min   max
dV/dt_r  0.82152/29.10185n   0.36049/72.26663n   1.11042/14.20171n
dV/dt_f  0.83640/28.16057n   0.32682/59.35375n   1.13692/15.35214n
R_load = 50.000000
[Rising Waveform]
R_fixture= 50.000000
V_fixture= 2.400000
V_fixture_min= 1.800000
V_fixture_max= 2.700000
|time   V(typ)   V(min)   V(max)
0s        1.005V     1.245V     804.1mV
880.9ps   1.005V     1.245V     846.4mV
1.161ns   1.006V     1.246V     1.926V
1.281ns   1.056V     1.246V     2.223V
1.602ns   1.926V     1.245V     2.542V
1.862ns   2.223V     1.244V     2.621V
2.442ns   2.359V     1.271V     2.678V
2.963ns   2.383V     1.671V     2.692V
3.463ns   2.392V     1.773V     2.696V
9.97ns    2.399V     1.799V     2.699V
[Rising Waveform]
R_fixture= 50.000000
V_fixture= 0.0
V_fixture_min= 0.0
V_fixture_max= 0.0
|time   V(typ)   V(min)   V(max)
0s        13.03nV    587nV      29.4nV
6.507ns   -119.7uV   -72.2uV    24.34mV
9.009ns   612.5uV    -61.81uV   116.7mV
18.52ns   98.18mV    101.6uV    861.5mV
28.53ns   371.5mV    3.474mV    1.566V
40.54ns   758mV      17.3mV     1.786V
57.56ns   1.147V     67.23mV    1.839V
80.58ns   1.319V     190.3mV    1.85V
150.2ns   1.369V     511.8mV    1.851V
249.2ns   1.369V     608.5mV    1.851V
[Falling Waveform]
R_fixture= 50.000000
V_fixture= 2.400000
V_fixture_min= 1.800000
V_fixture_max= 2.700000
|time   V(typ)   V(min)   V(max)
0s        2.399V     1.799V     2.699V
11.51ns   2.397V     1.798V     2.621V
21.52ns   2.317V     1.798V     1.874V
31.03ns   2.04V      1.798V     1.2V
36.54ns   1.851V     1.795V     1.002V
45.05ns   1.564V     1.784V     897.6mV
60.06ns   1.236V     1.727V     839.5mV
85.09ns   1.076V     1.568V     812.1mV
144.1ns   1.013V     1.316V     804.4mV
249.2ns   1.005V     1.245V     804.1mV
[Falling Waveform]
R_fixture= 50.000000
V_fixture= 0.0
V_fixture_min= 0.0
V_fixture_max= 0.0
|time   V(typ)   V(min)   V(max)
0s        1.369V     608.5mV    1.851V
920.9ps   1.369V     608.5mV    1.818V
1.041ns   1.371V     608.5mV    1.662V
1.341ns   1.353V     608.3mV    988.1mV
1.622ns   1.073V     607.8mV    458.2mV
2.302ns   262.5mV    612.4mV    81.94mV
3.043ns   46.63mV    509.5mV    14.59mV
3.784ns   10.61mV    206.9mV    3.436mV
4.645ns   2.884mV    39.56mV    1.064mV
9.97ns    13.03nV    587nV      29.4nV
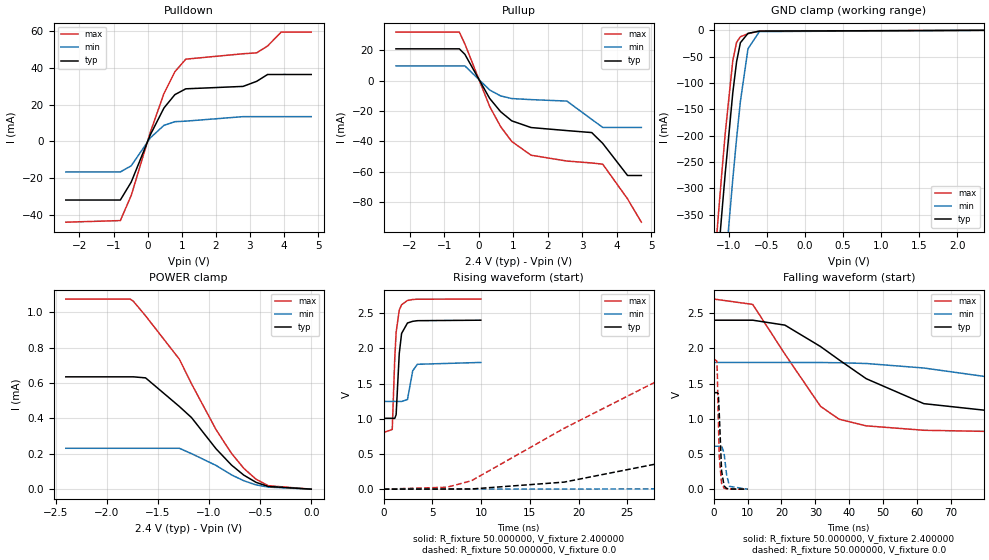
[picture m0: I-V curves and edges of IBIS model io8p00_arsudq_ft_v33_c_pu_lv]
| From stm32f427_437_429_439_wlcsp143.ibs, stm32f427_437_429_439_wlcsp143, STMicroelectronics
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|   Model io8p00_arsudq_ft_v33_c_pu_lv
[Model]  io8p00_arsudq_ft_v33_c_pu_lv
Model_type I/O
Polarity   Non-Inverting
Enable   Active-Low
Vinl =   0.720000V
Vinh =   1.680000V
Vmeas =  1.200000V
Cref =   50.000000pF
Rref =   100.000000M
Vref =   0.0V
C_comp   5.917600pF   5.759800pF   6.094800pF
[Temperature Range]   25.000000   0.125000k   -40.000000
[Pullup Reference]   2.400000V   1.800000V   2.700000V
[Pulldown Reference]   0.0V   0.0V   0.0V
[POWER Clamp Reference]   2.400000V   1.800000V   2.700000V
[GND Clamp Reference]   0.0V   0.0V   0.0V
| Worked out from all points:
|   slope of the pulldown table from 0 to 0.36 V, typ, clamps not added: 25 ohm
|   slope of the pullup table from 0 to 0.36 V, typ, clamps not added: 27.7 ohm
|   GND clamp passes 1 mA (typ) near -0.56 V on its own axis
|   rising waveform, R_fixture 50.000000, V_fixture 2.400000: 20-80 % time 336ps typ, 395ps min, 349ps max; typ from 1.01 V to 2.4 V
|   rising waveform, R_fixture 50.000000, V_fixture 0.0: 20-80 % time 29.1ns typ, 72.3ns min, 14.2ns max; typ from 0.001 V to 1.37 V
|   falling waveform, R_fixture 50.000000, V_fixture 2.400000: 20-80 % time 28.2ns typ, 58.9ns min, 15.4ns max; typ from 2.4 V to 1.01 V
|   falling waveform, R_fixture 50.000000, V_fixture 0.0: 20-80 % time 682ps typ, 1.02ns min, 579ps max; typ from 1.37 V to 0.001 V
[Pulldown]
|Voltage   I(typ)   I(min)   I(max)
-2.4V     -31.73mA   -16.51mA   -43.74mA
-800mV    -31.73mA   -16.51mA   -42.87mA
-480mV    -21.98mA   -13.17mA   -29.21mA
80mV      3.63mA     1.966mA    5.014mA
480mV     18.16mA    8.738mA    26.02mA
800mV     25.38mA    10.72mA    37.77mA
1.12V     28.53mA    11.02mA    44.6mA
2.8V      29.84mA    13.45mA    47.53mA
3.2V      32.59mA    13.45mA    48.03mA
3.52V     36.3mA     13.45mA    51.75mA
3.92V     36.3mA     13.45mA    59.27mA
4.8V      36.3mA     13.45mA    59.27mA
[Pullup]
|Voltage   I(typ)   I(min)   I(max)
-2.4V     20.87mA    9.659mA    31.88mA
-560mV    20.87mA    9.659mA    31.88mA
-400mV    17.27mA    9.659mA    24.06mA
320mV     -11.75mA   -6.207mA   -17.08mA
640mV     -20.52mA   -10.1mA    -30.35mA
960mV     -26.47mA   -11.82mA   -40.02mA
1.52V     -30.88mA   -12.51mA   -49.05mA
2.56V     -32.88mA   -13.48mA   -52.9mA
3.28V     -34.18mA   -25.5mA    -54.17mA
3.6V      -41.31mA   -30.8mA    -54.97mA
4.32V     -62.4mA    -30.8mA    -77.8mA
4.72V     -62.4mA    -30.8mA    -93.1mA
[GND_clamp]
|Voltage   I(typ)   I(min)   I(max)
-2.4V     -2.854A    -3.022A    -2.793A
-1.25V    -627.1mA   -809.1mA   -551.5mA
-1.2V     -535.5mA   -717.4mA   -459.3mA
-1.15V    -445.4mA   -626.8mA   -368.7mA
-1.1V     -357.2mA   -537.5mA   -280.5mA
-1.05V    -272mA     -449.9mA   -196.4mA
-950mV    -118.4mA   -282.5mA   -57.41mA
-900mV    -59.51mA   -205.1mA   -22.73mA
-850mV    -23.5mA    -134.9mA   -12.18mA
-750mV    -5.732mA   -34.85mA   -6.358mA
-600mV    -1.5mA     -2.382mA   -1.477mA
2.35V     0A         0A         0A
[POWER_clamp]
|Voltage   I(typ)   I(min)   I(max)
-2.4V     634.6uA    231uA      1.074mA
-1.77V    634.6uA    231uA      1.074mA
-1.74V    634.6uA    231uA      1.062mA
-1.62V    628.8uA    231uA      979.4uA
-1.29V    467.4uA    231uA      734.7uA
-1.17V    404uA      200.6uA    594.5uA
-930mV    227.6uA    133.8uA    335.6uA
-780mV    136.3uA    80.83uA    202.6uA
-660mV    79.46uA    47.68uA    118uA
-540mV    38.68uA    24.22uA    56.26uA
-420mV    15.19uA    11.75uA    19.49uA
0V        0A         0A         0A
[Ramp]
| variable   typ   min   max
dV/dt_r  0.82207/29.10543n   0.36106/72.34121n   1.11083/14.20682n
dV/dt_f  0.83574/28.16671n   0.32622/59.26000n   1.13660/15.35179n
R_load = 50.000000
[Rising Waveform]
R_fixture= 50.000000
V_fixture= 2.400000
V_fixture_min= 1.800000
V_fixture_max= 2.700000
|time   V(typ)   V(min)   V(max)
0s        1.007V     1.247V     805.7mV
880.9ps   1.007V     1.247V     848mV
1.141ns   1.006V     1.247V     1.86V
1.281ns   1.058V     1.247V     2.226V
1.602ns   1.928V     1.247V     2.545V
1.842ns   2.212V     1.246V     2.619V
2.442ns   2.36V      1.273V     2.68V
2.983ns   2.384V     1.682V     2.694V
3.463ns   2.393V     1.774V     2.698V
9.97ns    2.4V       1.8V       2.7V
[Rising Waveform]
R_fixture= 50.000000
V_fixture= 0.0
V_fixture_min= 0.0
V_fixture_max= 0.0
|time   V(typ)   V(min)   V(max)
0s        880.4uV    840.5uV    911.2uV
6.507ns   2.82mV     1.866mV    28.45mV
9.009ns   3.529mV    1.877mV    120.2mV
18.52ns   100.9mV    2.041mV    864.7mV
28.53ns   374.2mV    5.414mV    1.568V
40.54ns   760.5mV    19.2mV     1.788V
59.06ns   1.17V      74.28mV    1.843V
80.58ns   1.321V     192.1mV    1.851V
149.6ns   1.37V      512.3mV    1.852V
249.2ns   1.371V     610.3mV    1.852V
[Falling Waveform]
R_fixture= 50.000000
V_fixture= 2.400000
V_fixture_min= 1.800000
V_fixture_max= 2.700000
|time   V(typ)   V(min)   V(max)
0s        2.4V       1.8V       2.7V
11.51ns   2.4V       1.8V       2.624V
21.02ns   2.33V      1.8V       1.918V
31.53ns   2.026V     1.799V     1.177V
37.04ns   1.836V     1.796V     993.5mV
45.05ns   1.569V     1.785V     899.8mV
62.06ns   1.215V     1.721V     837mV
91.59ns   1.062V     1.524V     811.6mV
140.1ns   1.015V     1.325V     806.1mV
249.2ns   1.007V     1.247V     805.7mV
[Falling Waveform]
R_fixture= 50.000000
V_fixture= 0.0
V_fixture_min= 0.0
V_fixture_max= 0.0
|time   V(typ)   V(min)   V(max)
0s        1.371V     610.3mV    1.852V
920.9ps   1.371V     610.3mV    1.819V
1.041ns   1.373V     610.3mV    1.663V
1.341ns   1.355V     610.1mV    989.5mV
1.622ns   1.074V     609.6mV    459.5mV
2.302ns   264.1mV    614.2mV    82.85mV
3.043ns   47.61mV    510.9mV    15.47mV
3.784ns   11.26mV    207.9mV    4.325mV
4.645ns   3.735mV    40.75mV    1.962mV
9.97ns    880.4uV    840.5uV    911.2uV
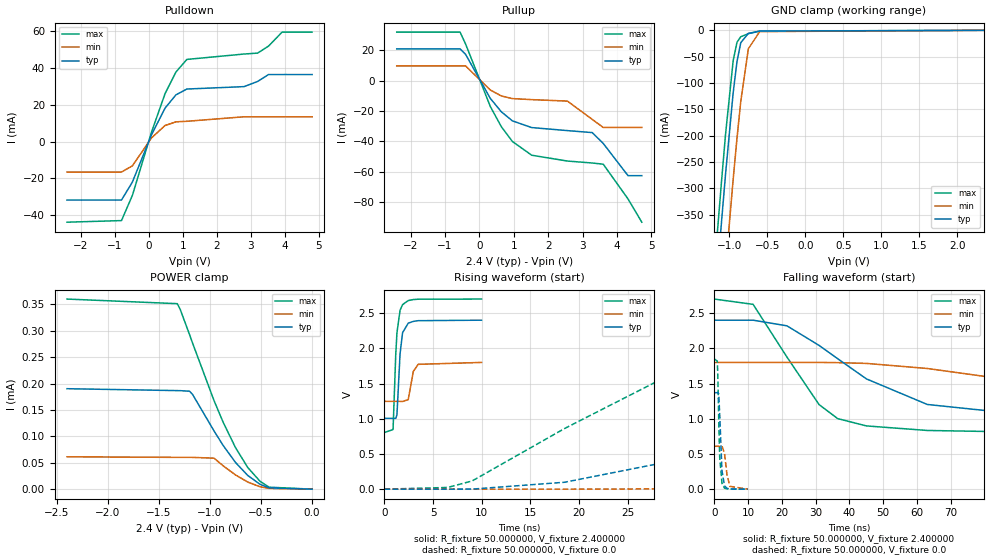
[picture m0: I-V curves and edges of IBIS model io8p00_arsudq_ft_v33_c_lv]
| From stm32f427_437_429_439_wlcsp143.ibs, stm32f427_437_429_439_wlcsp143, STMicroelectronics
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|   Model io8p00_arsudq_ft_v33_c_lv
[Model]  io8p00_arsudq_ft_v33_c_lv
Model_type I/O
Polarity   Non-Inverting
Enable   Active-Low
Vinl =   0.720000V
Vinh =   1.680000V
Vmeas =  1.200000V
Cref =   50.000000pF
Rref =   100.000000M
Vref =   0.0V
C_comp   5.917600pF   5.759800pF   6.094800pF
[Temperature Range]   25.000000   0.125000k   -40.000000
[Pullup Reference]   2.400000V   1.800000V   2.700000V
[Pulldown Reference]   0.0V   0.0V   0.0V
[POWER Clamp Reference]   2.400000V   1.800000V   2.700000V
[GND Clamp Reference]   0.0V   0.0V   0.0V
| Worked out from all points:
|   slope of the pulldown table from 0 to 0.36 V, typ, clamps not added: 25 ohm
|   slope of the pullup table from 0 to 0.36 V, typ, clamps not added: 27.7 ohm
|   GND clamp passes 1 mA (typ) near -0.56 V on its own axis
|   rising waveform, R_fixture 50.000000, V_fixture 2.400000: 20-80 % time 338ps typ, 396ps min, 350ps max; typ from 1.01 V to 2.4 V
|   rising waveform, R_fixture 50.000000, V_fixture 0.0: 20-80 % time 29.1ns typ, 72.2ns min, 14.2ns max; typ from 0 V to 1.37 V
|   falling waveform, R_fixture 50.000000, V_fixture 2.400000: 20-80 % time 28.2ns typ, 59ns min, 15.4ns max; typ from 2.4 V to 1.01 V
|   falling waveform, R_fixture 50.000000, V_fixture 0.0: 20-80 % time 682ps typ, 1.02ns min, 580ps max; typ from 1.37 V to 0 V
[Pulldown]
|Voltage   I(typ)   I(min)   I(max)
-2.4V     -31.73mA   -16.51mA   -43.74mA
-800mV    -31.73mA   -16.51mA   -42.87mA
-480mV    -21.98mA   -13.17mA   -29.21mA
80mV      3.63mA     1.966mA    5.014mA
480mV     18.16mA    8.738mA    26.02mA
800mV     25.38mA    10.72mA    37.77mA
1.12V     28.53mA    11.02mA    44.6mA
2.8V      29.84mA    13.47mA    47.53mA
3.2V      32.64mA    13.47mA    48.04mA
3.52V     36.39mA    13.47mA    51.83mA
3.92V     36.39mA    13.47mA    59.44mA
4.8V      36.39mA    13.47mA    59.44mA
[Pullup]
|Voltage   I(typ)   I(min)   I(max)
-2.4V     20.89mA    9.66mA     31.9mA
-560mV    20.89mA    9.66mA     31.9mA
-400mV    17.28mA    9.66mA     24.07mA
320mV     -11.75mA   -6.207mA   -17.08mA
640mV     -20.52mA   -10.1mA    -30.35mA
960mV     -26.47mA   -11.82mA   -40.02mA
1.52V     -30.88mA   -12.51mA   -49.05mA
2.56V     -32.88mA   -13.48mA   -52.9mA
3.28V     -34.19mA   -25.5mA    -54.18mA
3.6V      -41.31mA   -30.8mA    -54.97mA
4.32V     -62.5mA    -30.8mA    -77.8mA
4.72V     -62.5mA    -30.8mA    -93.1mA
[GND_clamp]
|Voltage   I(typ)   I(min)   I(max)
-2.4V     -2.854A    -3.022A    -2.793A
-1.25V    -627.1mA   -809.1mA   -551.5mA
-1.2V     -535.5mA   -717.4mA   -459.3mA
-1.15V    -445.4mA   -626.8mA   -368.7mA
-1.1V     -357.2mA   -537.5mA   -280.5mA
-1.05V    -272mA     -449.9mA   -196.4mA
-950mV    -118.4mA   -282.5mA   -57.41mA
-900mV    -59.51mA   -205.1mA   -22.73mA
-850mV    -23.5mA    -134.9mA   -12.18mA
-750mV    -5.732mA   -34.85mA   -6.358mA
-600mV    -1.5mA     -2.382mA   -1.477mA
2.35V     0A         0A         0A
[POWER_clamp]
|Voltage   I(typ)   I(min)   I(max)
-2.4V     190.2uA    61.28uA    359.9uA
-1.32V    186.6uA    60.21uA    351.2uA
-1.29V    186.5uA    60.2uA     339.6uA
-1.2V     185.4uA    60.18uA    292.6uA
-1.17V    179.2uA    60.17uA    276.3uA
-960mV    110.2uA    58.68uA    167.5uA
-870mV    82.45uA    44.05uA    126.3uA
-750mV    50.58uA    26.98uA    78.64uA
-630mV    25.95uA    13.47uA    41.02uA
-510mV    9.222uA    4.578uA    14.97uA
-420mV    2.426uA    1.429uA    3.749uA
0V        0A         0A         0A
[Ramp]
| variable   typ   min   max
dV/dt_r  0.82218/29.09026n   0.36085/72.26554n   1.11108/14.19304n
dV/dt_f  0.83652/28.15210n   0.32658/59.27333n   1.13727/15.34046n
R_load = 50.000000
[Rising Waveform]
R_fixture= 50.000000
V_fixture= 2.400000
V_fixture_min= 1.800000
V_fixture_max= 2.700000
|time   V(typ)   V(min)   V(max)
0s        1.006V     1.247V     804.6mV
880.9ps   1.006V     1.247V     846.8mV
1.161ns   1.006V     1.247V     1.926V
1.281ns   1.057V     1.247V     2.222V
1.602ns   1.926V     1.247V     2.542V
1.862ns   2.223V     1.245V     2.621V
2.442ns   2.358V     1.272V     2.679V
2.963ns   2.383V     1.672V     2.693V
3.463ns   2.393V     1.773V     2.698V
9.97ns    2.4V       1.8V       2.7V
[Rising Waveform]
R_fixture= 50.000000
V_fixture= 0.0
V_fixture_min= 0.0
V_fixture_max= 0.0
|time   V(typ)   V(min)   V(max)
0s        13.13nV    592nV      29.45nV
6.507ns   -120.4uV   -73.31uV   24.37mV
9.009ns   612.5uV    -62.24uV   116.7mV
18.52ns   98.24mV    101.6uV    862.3mV
28.53ns   371.9mV    3.477mV    1.567V
40.04ns   743.3mV    16.74mV    1.784V
57.56ns   1.148V     67.29mV    1.841V
80.58ns   1.32V      190.5mV    1.851V
150.2ns   1.37V      512.3mV    1.852V
249.2ns   1.37V      609.1mV    1.852V
[Falling Waveform]
R_fixture= 50.000000
V_fixture= 2.400000
V_fixture_min= 1.800000
V_fixture_max= 2.700000
|time   V(typ)   V(min)   V(max)
0s        2.4V       1.8V       2.7V
11.51ns   2.4V       1.8V       2.625V
21.52ns   2.32V      1.8V       1.877V
31.03ns   2.042V     1.8V       1.201V
36.54ns   1.853V     1.797V     1.002V
45.05ns   1.566V     1.786V     898.3mV
63.06ns   1.203V     1.714V     833.7mV
91.59ns   1.06V      1.525V     810.5mV
143.1ns   1.013V     1.319V     804.8mV
249.2ns   1.006V     1.247V     804.6mV
[Falling Waveform]
R_fixture= 50.000000
V_fixture= 0.0
V_fixture_min= 0.0
V_fixture_max= 0.0
|time   V(typ)   V(min)   V(max)
0s        1.37V      609.1mV    1.852V
920.9ps   1.37V      609.1mV    1.819V
1.041ns   1.372V     609.1mV    1.663V
1.341ns   1.354V     608.9mV    990.2mV
1.622ns   1.074V     608.4mV    460.3mV
2.302ns   264mV      613mV      83.74mV
3.043ns   47.76mV    510.1mV    15.75mV
3.784ns   11.31mV    207.5mV    4.136mV
4.645ns   3.359mV    40.02mV    1.455mV
9.97ns    13.13nV    592nV      29.45nV
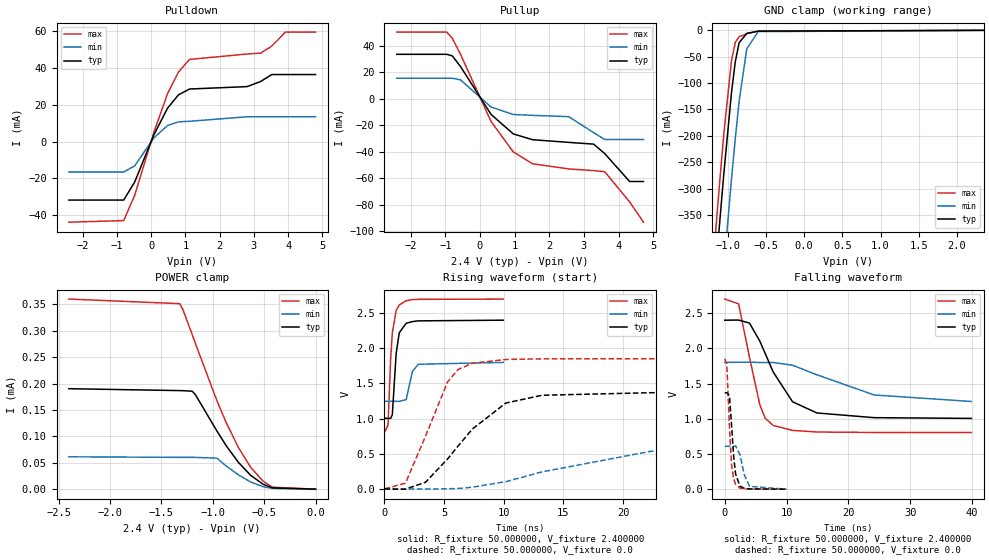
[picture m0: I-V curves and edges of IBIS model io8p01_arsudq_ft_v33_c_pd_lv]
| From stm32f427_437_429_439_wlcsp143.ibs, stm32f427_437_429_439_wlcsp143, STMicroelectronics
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|   Model io8p01_arsudq_ft_v33_c_pd_lv
[Model]  io8p01_arsudq_ft_v33_c_pd_lv
Model_type I/O
Polarity   Non-Inverting
Enable   Active-Low
Vinl =   0.720000V
Vinh =   1.680000V
Vmeas =  1.200000V
Cref =   50.000000pF
Rref =   100.000000M
Vref =   0.0V
C_comp   5.917600pF   5.759800pF   6.094800pF
[Temperature Range]   25.000000   0.125000k   -40.000000
[Pullup Reference]   2.400000V   1.800000V   2.700000V
[Pulldown Reference]   0.0V   0.0V   0.0V
[POWER Clamp Reference]   2.400000V   1.800000V   2.700000V
[GND Clamp Reference]   0.0V   0.0V   0.0V
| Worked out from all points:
|   slope of the pulldown table from 0 to 0.36 V, typ, clamps not added: 25 ohm
|   slope of the pullup table from 0 to 0.36 V, typ, clamps not added: 27.7 ohm
|   GND clamp passes 1 mA (typ) near -0.56 V on its own axis
|   rising waveform, R_fixture 50.000000, V_fixture 2.400000: 20-80 % time 339ps typ, 396ps min, 353ps max; typ from 1 V to 2.4 V
|   rising waveform, R_fixture 50.000000, V_fixture 0.0: 20-80 % time 4.38ns typ, 9.17ns min, 2.58ns max; typ from 0 V to 1.37 V
|   falling waveform, R_fixture 50.000000, V_fixture 2.400000: 20-80 % time 4.91ns typ, 9.73ns min, 2.66ns max; typ from 2.4 V to 1 V
|   falling waveform, R_fixture 50.000000, V_fixture 0.0: 20-80 % time 681ps typ, 1.02ns min, 580ps max; typ from 1.37 V to 0 V
[Pulldown]
|Voltage   I(typ)   I(min)   I(max)
-2.4V     -31.73mA   -16.51mA   -43.74mA
-800mV    -31.73mA   -16.51mA   -42.87mA
-480mV    -21.98mA   -13.17mA   -29.21mA
80mV      3.63mA     1.966mA    5.014mA
480mV     18.15mA    8.738mA    26.02mA
800mV     25.38mA    10.72mA    37.77mA
1.12V     28.53mA    11.02mA    44.6mA
2.8V      29.84mA    13.47mA    47.53mA
3.2V      32.64mA    13.47mA    48.04mA
3.52V     36.39mA    13.47mA    51.82mA
3.92V     36.39mA    13.47mA    59.43mA
4.8V      36.39mA    13.47mA    59.43mA
[Pullup]
|Voltage   I(typ)   I(min)   I(max)
-2.4V     33.56mA    15.56mA    50.33mA
-960mV    33.56mA    15.56mA    50.33mA
-800mV    32.44mA    15.56mA    45.79mA
-560mV    24.29mA    14.3mA     33.54mA
320mV     -11.75mA   -6.207mA   -17.08mA
960mV     -26.47mA   -11.82mA   -40.02mA
1.52V     -30.88mA   -12.51mA   -49.05mA
2.56V     -32.88mA   -13.48mA   -52.9mA
3.28V     -34.19mA   -25.5mA    -54.18mA
3.6V      -41.31mA   -30.7mA    -54.97mA
4.32V     -62.4mA    -30.7mA    -77.8mA
4.72V     -62.4mA    -30.7mA    -93.1mA
[GND_clamp]
|Voltage   I(typ)   I(min)   I(max)
-2.4V     -2.854A    -3.022A    -2.792A
-1.25V    -627.1mA   -809.1mA   -551.5mA
-1.2V     -535.5mA   -717.4mA   -459.3mA
-1.15V    -445.4mA   -626.8mA   -368.7mA
-1.1V     -357.2mA   -537.5mA   -280.5mA
-1.05V    -272mA     -449.9mA   -196.4mA
-950mV    -118.4mA   -282.5mA   -57.42mA
-900mV    -59.51mA   -205.1mA   -22.74mA
-850mV    -23.51mA   -134.9mA   -12.19mA
-750mV    -5.744mA   -34.86mA   -6.372mA
-600mV    -1.511mA   -2.391mA   -1.49mA
2.35V     58.09uA    37.93uA    67.25uA
[POWER_clamp]
|Voltage   I(typ)   I(min)   I(max)
-2.4V     190.2uA    61.28uA    359.9uA
-1.32V    186.6uA    60.21uA    351.2uA
-1.29V    186.5uA    60.2uA     339.6uA
-1.2V     185.4uA    60.18uA    292.6uA
-1.17V    179.2uA    60.17uA    276.3uA
-960mV    110.2uA    58.68uA    167.5uA
-870mV    82.45uA    44.05uA    126.3uA
-750mV    50.58uA    26.98uA    78.64uA
-630mV    25.95uA    13.47uA    41.02uA
-510mV    9.222uA    4.578uA    14.97uA
-420mV    2.426uA    1.429uA    3.749uA
0V        0A         0A         0A
[Ramp]
| variable   typ   min   max
dV/dt_r  0.82152/4.37962n   0.36417/9.16212n   1.11042/2.57241n
dV/dt_f  0.83628/4.91462n   0.32250/9.70324n   1.13692/2.65657n
R_load = 50.000000
[Rising Waveform]
R_fixture= 50.000000
V_fixture= 2.400000
V_fixture_min= 1.800000
V_fixture_max= 2.700000
|time   V(typ)   V(min)   V(max)
0s        1.005V     1.245V     804.3mV
300.3ps   1.004V     1.245V     907.4mV
520.5ps   1.003V     1.246V     1.855V
660.7ps   1.056V     1.246V     2.219V
981ps     1.924V     1.245V     2.537V
1.241ns   2.22V      1.244V     2.615V
1.822ns   2.355V     1.271V     2.676V
2.342ns   2.379V     1.671V     2.691V
2.843ns   2.389V     1.772V     2.695V
9.97ns    2.399V     1.799V     2.699V
[Rising Waveform]
R_fixture= 50.000000
V_fixture= 0.0
V_fixture_min= 0.0
V_fixture_max= 0.0
|time   V(typ)   V(min)   V(max)
0s        66.19uV    37.58uV    502.1uV
1.762ns   -2.766mV   -1.814mV   83.28mV
3.443ns   95.96mV    -1.185mV   751.2mV
5.285ns   425.2mV    2.753mV    1.52V
6.166ns   609.2mV    7.178mV    1.698V
7.367ns   851.7mV    25.55mV    1.787V
10.17ns   1.221V     103.8mV    1.841V
13.21ns   1.332V     243mV      1.849V
22.34ns   1.368V     536.1mV    1.851V
39.88ns   1.369V     608.5mV    1.851V
[Falling Waveform]
R_fixture= 50.000000
V_fixture= 2.400000
V_fixture_min= 1.800000
V_fixture_max= 2.700000
|time   V(typ)   V(min)   V(max)
0s        2.399V     1.799V     2.699V
2.242ns   2.401V     1.803V     2.632V
4.004ns   2.358V     1.803V     1.873V
5.686ns   2.101V     1.798V     1.196V
6.567ns   1.922V     1.798V     1.005V
7.848ns   1.662V     1.798V     904.1mV
10.97ns   1.241V     1.76V      834.2mV
14.89ns   1.082V     1.624V     811.8mV
24.18ns   1.015V     1.337V     804.6mV
39.88ns   1.005V     1.245V     804.3mV
[Falling Waveform]
R_fixture= 50.000000
V_fixture= 0.0
V_fixture_min= 0.0
V_fixture_max= 0.0
|time   V(typ)   V(min)   V(max)
0s        1.369V     608.5mV    1.851V
340.3ps   1.369V     608.5mV    1.78V
760.8ps   1.33V      608.2mV    891.5mV
1.121ns   892.6mV    607.7mV    337.4mV
1.461ns   453.9mV    608.8mV    145.2mV
1.762ns   216mV      614.5mV    68.9mV
2.462ns   43.4mV     490.7mV    15.15mV
3.163ns   11.88mV    206.3mV    3.674mV
4.024ns   3.666mV    39.51mV    1.295mV
9.97ns    66.19uV    37.58uV    502.1uV
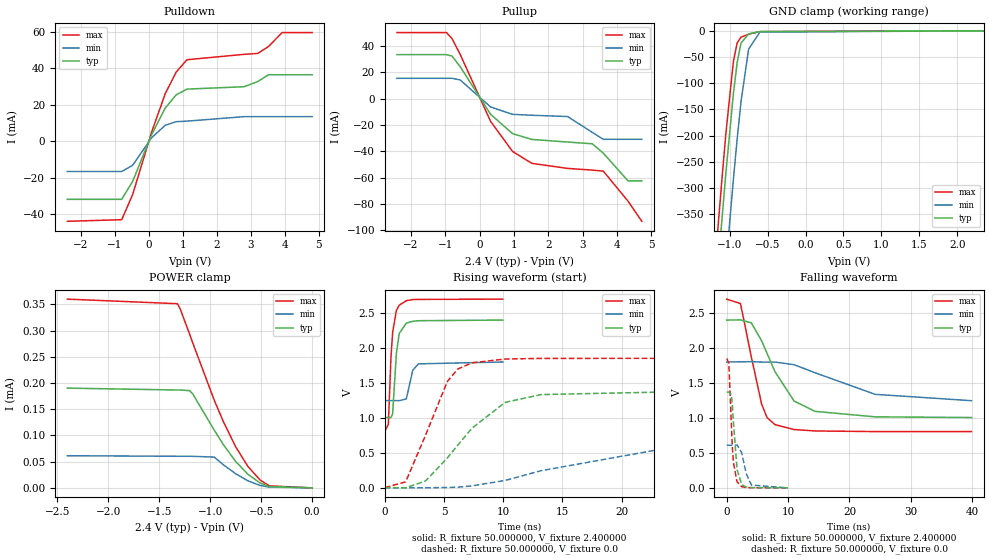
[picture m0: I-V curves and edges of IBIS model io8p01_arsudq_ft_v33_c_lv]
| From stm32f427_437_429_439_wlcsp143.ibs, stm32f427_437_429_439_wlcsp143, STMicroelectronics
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|   Model io8p01_arsudq_ft_v33_c_lv
[Model]  io8p01_arsudq_ft_v33_c_lv
Model_type I/O
Polarity   Non-Inverting
Enable   Active-Low
Vinl =   0.720000V
Vinh =   1.680000V
Vmeas =  1.200000V
Cref =   50.000000pF
Rref =   100.000000M
Vref =   0.0V
C_comp   5.917600pF   5.759800pF   6.094800pF
[Temperature Range]   25.000000   0.125000k   -40.000000
[Pullup Reference]   2.400000V   1.800000V   2.700000V
[Pulldown Reference]   0.0V   0.0V   0.0V
[POWER Clamp Reference]   2.400000V   1.800000V   2.700000V
[GND Clamp Reference]   0.0V   0.0V   0.0V
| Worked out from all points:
|   slope of the pulldown table from 0 to 0.36 V, typ, clamps not added: 25 ohm
|   slope of the pullup table from 0 to 0.36 V, typ, clamps not added: 27.7 ohm
|   GND clamp passes 1 mA (typ) near -0.56 V on its own axis
|   rising waveform, R_fixture 50.000000, V_fixture 2.400000: 20-80 % time 339ps typ, 396ps min, 352ps max; typ from 1.01 V to 2.4 V
|   rising waveform, R_fixture 50.000000, V_fixture 0.0: 20-80 % time 4.38ns typ, 9.17ns min, 2.58ns max; typ from 0 V to 1.37 V
|   falling waveform, R_fixture 50.000000, V_fixture 2.400000: 20-80 % time 4.92ns typ, 9.72ns min, 2.66ns max; typ from 2.4 V to 1.01 V
|   falling waveform, R_fixture 50.000000, V_fixture 0.0: 20-80 % time 682ps typ, 1.02ns min, 582ps max; typ from 1.37 V to 0 V
[Pulldown]
|Voltage   I(typ)   I(min)   I(max)
-2.4V     -31.73mA   -16.51mA   -43.74mA
-800mV    -31.73mA   -16.51mA   -42.87mA
-480mV    -21.98mA   -13.17mA   -29.21mA
80mV      3.63mA     1.966mA    5.014mA
480mV     18.16mA    8.738mA    26.02mA
800mV     25.38mA    10.72mA    37.77mA
1.12V     28.53mA    11.02mA    44.6mA
2.8V      29.84mA    13.47mA    47.53mA
3.2V      32.64mA    13.47mA    48.04mA
3.52V     36.39mA    13.47mA    51.83mA
3.92V     36.39mA    13.47mA    59.44mA
4.8V      36.39mA    13.47mA    59.44mA
[Pullup]
|Voltage   I(typ)   I(min)   I(max)
-2.4V     33.56mA    15.56mA    50.33mA
-960mV    33.56mA    15.56mA    50.33mA
-800mV    32.44mA    15.56mA    45.79mA
-560mV    24.29mA    14.3mA     33.55mA
320mV     -11.75mA   -6.207mA   -17.08mA
960mV     -26.47mA   -11.82mA   -40.02mA
1.52V     -30.88mA   -12.51mA   -49.05mA
2.56V     -32.88mA   -13.48mA   -52.9mA
3.28V     -34.19mA   -25.5mA    -54.18mA
3.6V      -41.31mA   -30.8mA    -54.97mA
4.32V     -62.4mA    -30.8mA    -77.8mA
4.72V     -62.4mA    -30.8mA    -93.1mA
[GND_clamp]
|Voltage   I(typ)   I(min)   I(max)
-2.4V     -2.854A    -3.022A    -2.793A
-1.25V    -627.1mA   -809.1mA   -551.5mA
-1.2V     -535.5mA   -717.4mA   -459.3mA
-1.15V    -445.4mA   -626.8mA   -368.7mA
-1.1V     -357.2mA   -537.5mA   -280.5mA
-1.05V    -272mA     -449.9mA   -196.4mA
-950mV    -118.4mA   -282.5mA   -57.41mA
-900mV    -59.51mA   -205.1mA   -22.73mA
-850mV    -23.5mA    -134.9mA   -12.18mA
-750mV    -5.732mA   -34.85mA   -6.358mA
-600mV    -1.5mA     -2.382mA   -1.477mA
2.35V     0A         0A         0A
[POWER_clamp]
|Voltage   I(typ)   I(min)   I(max)
-2.4V     190.2uA    61.28uA    359.9uA
-1.32V    186.6uA    60.21uA    351.2uA
-1.29V    186.5uA    60.2uA     339.6uA
-1.2V     185.4uA    60.18uA    292.6uA
-1.17V    179.2uA    60.17uA    276.3uA
-960mV    110.2uA    58.68uA    167.5uA
-870mV    82.45uA    44.05uA    126.3uA
-750mV    50.58uA    26.98uA    78.64uA
-630mV    25.95uA    13.47uA    41.02uA
-510mV    9.222uA    4.578uA    14.97uA
-420mV    2.426uA    1.429uA    3.749uA
0V        0A         0A         0A
[Ramp]
| variable   typ   min   max
dV/dt_r  0.82218/4.38033n   0.36454/9.16423n   1.11108/2.57222n
dV/dt_f  0.83640/4.91259n   0.32226/9.69737n   1.13727/2.65545n
R_load = 50.000000
[Rising Waveform]
R_fixture= 50.000000
V_fixture= 2.400000
V_fixture_min= 1.800000
V_fixture_max= 2.700000
|time   V(typ)   V(min)   V(max)
0s        1.006V     1.247V     804.7mV
300.3ps   1.005V     1.247V     907.9mV
520.5ps   1.004V     1.247V     1.856V
660.7ps   1.057V     1.247V     2.22V
981ps     1.925V     1.247V     2.538V
1.221ns   2.209V     1.245V     2.613V
1.822ns   2.357V     1.272V     2.678V
2.362ns   2.382V     1.681V     2.694V
2.843ns   2.391V     1.773V     2.696V
9.97ns    2.4V       1.8V       2.7V
[Rising Waveform]
R_fixture= 50.000000
V_fixture= 0.0
V_fixture_min= 0.0
V_fixture_max= 0.0
|time   V(typ)   V(min)   V(max)
0s        65.97uV    37.55uV    502.1uV
1.762ns   -2.771mV   -1.814mV   83.27mV
3.443ns   95.96mV    -1.188mV   751.4mV
5.285ns   425.3mV    2.751mV    1.521V
6.166ns   609.5mV    7.179mV    1.699V
7.367ns   852.2mV    25.55mV    1.788V
10.17ns   1.222V     103.8mV    1.842V
13.21ns   1.333V     243.1mV    1.851V
23.3ns    1.369V     549.9mV    1.852V
39.88ns   1.37V      609.1mV    1.852V
[Falling Waveform]
R_fixture= 50.000000
V_fixture= 2.400000
V_fixture_min= 1.800000
V_fixture_max= 2.700000
|time   V(typ)   V(min)   V(max)
0s        2.4V       1.8V       2.7V
2.242ns   2.403V     1.804V     2.636V
4.004ns   2.361V     1.805V     1.876V
5.686ns   2.104V     1.8V       1.198V
6.567ns   1.925V     1.8V       1.006V
7.848ns   1.664V     1.8V       904.8mV
10.97ns   1.242V     1.762V     834.7mV
14.41ns   1.094V     1.646V     814mV
24.18ns   1.016V     1.338V     805.1mV
39.88ns   1.006V     1.247V     804.7mV
[Falling Waveform]
R_fixture= 50.000000
V_fixture= 0.0
V_fixture_min= 0.0
V_fixture_max= 0.0
|time   V(typ)   V(min)   V(max)
0s        1.37V      609.1mV    1.852V
340.3ps   1.371V     609.1mV    1.782V
760.8ps   1.331V     608.8mV    893.6mV
920.9ps   1.176V     608.6mV    573mV
1.101ns   924.3mV    608.4mV    356.8mV
1.682ns   263.8mV    613mV      85.72mV
2.442ns   46.52mV    500.2mV    16.8mV
3.163ns   12.66mV    206.9mV    4.143mV
4.024ns   4.159mV    39.98mV    1.43mV
9.97ns    65.97uV    37.55uV    502.1uV
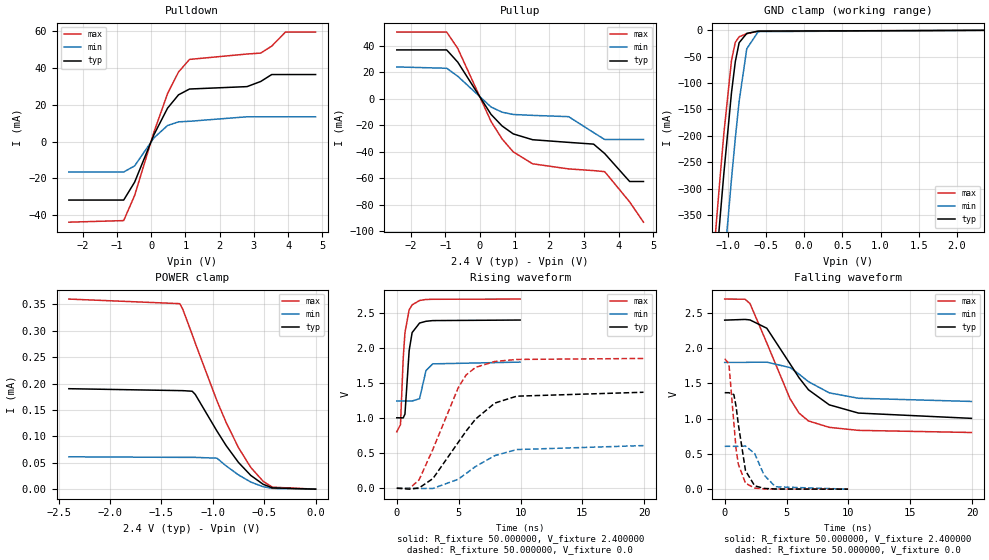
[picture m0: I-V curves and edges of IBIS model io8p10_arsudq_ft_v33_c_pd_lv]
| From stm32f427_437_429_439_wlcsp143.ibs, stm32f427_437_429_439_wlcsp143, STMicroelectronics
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|   Model io8p10_arsudq_ft_v33_c_pd_lv
[Model]  io8p10_arsudq_ft_v33_c_pd_lv
Model_type I/O
Polarity   Non-Inverting
Enable   Active-Low
Vinl =   0.720000V
Vinh =   1.680000V
Vmeas =  1.200000V
Cref =   40.000000pF
Rref =   100.000000M
Vref =   0.0V
C_comp   5.917600pF   5.759800pF   6.094800pF
[Temperature Range]   25.000000   0.125000k   -40.000000
[Pullup Reference]   2.400000V   1.800000V   2.700000V
[Pulldown Reference]   0.0V   0.0V   0.0V
[POWER Clamp Reference]   2.400000V   1.800000V   2.700000V
[GND Clamp Reference]   0.0V   0.0V   0.0V
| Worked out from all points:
|   slope of the pulldown table from 0 to 0.36 V, typ, clamps not added: 25 ohm
|   slope of the pullup table from 0 to 0.36 V, typ, clamps not added: 27.7 ohm
|   GND clamp passes 1 mA (typ) near -0.56 V on its own axis
|   rising waveform, R_fixture 50.000000, V_fixture 2.400000: 20-80 % time 340ps typ, 401ps min, 353ps max; typ from 1 V to 2.4 V
|   rising waveform, R_fixture 50.000000, V_fixture 0.0: 20-80 % time 3.47ns typ, 3.36ns min, 2.61ns max; typ from 0 V to 1.37 V
|   falling waveform, R_fixture 50.000000, V_fixture 2.400000: 20-80 % time 3.55ns typ, 3.08ns min, 2.71ns max; typ from 2.4 V to 1 V
|   falling waveform, R_fixture 50.000000, V_fixture 0.0: 20-80 % time 681ps typ, 1.02ns min, 580ps max; typ from 1.37 V to 0 V
[Pulldown]
|Voltage   I(typ)   I(min)   I(max)
-2.4V     -31.73mA   -16.51mA   -43.74mA
-800mV    -31.73mA   -16.51mA   -42.87mA
-480mV    -21.98mA   -13.17mA   -29.21mA
80mV      3.63mA     1.966mA    5.014mA
480mV     18.15mA    8.738mA    26.02mA
800mV     25.38mA    10.72mA    37.77mA
1.12V     28.53mA    11.02mA    44.6mA
2.8V      29.84mA    13.47mA    47.53mA
3.2V      32.64mA    13.47mA    48.04mA
3.52V     36.39mA    13.47mA    51.82mA
3.92V     36.39mA    13.47mA    59.43mA
4.8V      36.39mA    13.47mA    59.43mA
[Pullup]
|Voltage   I(typ)   I(min)   I(max)
-2.4V     36.88mA    24.03mA    50.33mA
-960mV    36.88mA    23.04mA    50.33mA
-640mV    27.65mA    17.03mA    37.99mA
320mV     -11.75mA   -6.207mA   -17.08mA
640mV     -20.52mA   -10.1mA    -30.35mA
960mV     -26.47mA   -11.82mA   -40.02mA
1.52V     -30.88mA   -12.51mA   -49.05mA
2.56V     -32.88mA   -13.48mA   -52.9mA
3.28V     -34.19mA   -25.5mA    -54.18mA
3.6V      -41.31mA   -30.7mA    -54.97mA
4.32V     -62.4mA    -30.7mA    -77.8mA
4.72V     -62.4mA    -30.7mA    -93.1mA
[GND_clamp]
|Voltage   I(typ)   I(min)   I(max)
-2.4V     -2.854A    -3.022A    -2.792A
-1.25V    -627.1mA   -809.1mA   -551.5mA
-1.2V     -535.5mA   -717.4mA   -459.3mA
-1.15V    -445.4mA   -626.8mA   -368.7mA
-1.1V     -357.2mA   -537.5mA   -280.5mA
-1.05V    -272mA     -449.9mA   -196.4mA
-950mV    -118.4mA   -282.5mA   -57.42mA
-900mV    -59.51mA   -205.1mA   -22.74mA
-850mV    -23.51mA   -134.9mA   -12.19mA
-750mV    -5.744mA   -34.86mA   -6.372mA
-600mV    -1.511mA   -2.391mA   -1.49mA
2.35V     58.09uA    37.93uA    67.25uA
[POWER_clamp]
|Voltage   I(typ)   I(min)   I(max)
-2.4V     190.2uA    61.28uA    359.9uA
-1.32V    186.6uA    60.21uA    351.2uA
-1.29V    186.5uA    60.2uA     339.6uA
-1.2V     185.4uA    60.18uA    292.6uA
-1.17V    179.2uA    60.17uA    276.3uA
-960mV    110.2uA    58.68uA    167.5uA
-870mV    82.45uA    44.05uA    126.3uA
-750mV    50.58uA    26.98uA    78.64uA
-630mV    25.95uA    13.47uA    41.02uA
-510mV    9.222uA    4.578uA    14.97uA
-420mV    2.426uA    1.429uA    3.749uA
0V        0A         0A         0A
[Ramp]
| variable   typ   min   max
dV/dt_r  0.82140/3.46618n   0.36492/3.35719n   1.11042/2.60985n
dV/dt_f  0.83304/3.53645n   0.33156/3.07356n   1.13584/2.71012n
R_load = 50.000000
[Rising Waveform]
R_fixture= 50.000000
V_fixture= 2.400000
V_fixture_min= 1.800000
V_fixture_max= 2.700000
|time   V(typ)   V(min)   V(max)
0s        1.005V     1.245V     804.3mV
300.3ps   1.004V     1.245V     907.9mV
520.5ps   1.004V     1.245V     1.856V
660.7ps   1.057V     1.246V     2.219V
1.001ns   1.964V     1.245V     2.546V
1.241ns   2.22V      1.244V     2.615V
1.842ns   2.356V     1.277V     2.678V
2.362ns   2.381V     1.679V     2.692V
2.903ns   2.391V     1.774V     2.695V
9.97ns    2.399V     1.799V     2.698V
[Rising Waveform]
R_fixture= 50.000000
V_fixture= 0.0
V_fixture_min= 0.0
V_fixture_max= 0.0
|time   V(typ)   V(min)   V(max)
0s        68.55uV    37.93uV    689.6uV
1.041ns   -13.08mV   132.4uV    -959.6uV
1.802ns   4.584mV    -3.035mV   120mV
2.923ns   138mV      -2.675mV   557.2mV
4.965ns   654mV      128.4mV    1.433V
5.606ns   815.5mV    210.9mV    1.616V
6.366ns   986.3mV    310.2mV    1.724V
7.928ns   1.215V     465.7mV    1.808V
9.69ns    1.313V     551.9mV    1.837V
19.94ns   1.369V     608.5mV    1.851V
[Falling Waveform]
R_fixture= 50.000000
V_fixture= 2.400000
V_fixture_min= 1.800000
V_fixture_max= 2.700000
|time   V(typ)   V(min)   V(max)
0s        2.399V     1.799V     2.698V
1.642ns   2.409V     1.799V     2.696V
2.042ns   2.402V     1.801V     2.635V
3.403ns   2.284V     1.803V     2.075V
5.285ns   1.778V     1.725V     1.282V
6.006ns   1.582V     1.633V     1.08V
6.767ns   1.411V     1.526V     968.5mV
8.448ns   1.197V     1.367V     877.4mV
10.81ns   1.08V      1.29V      834.6mV
19.94ns   1.005V     1.245V     804.3mV
[Falling Waveform]
R_fixture= 50.000000
V_fixture= 0.0
V_fixture_min= 0.0
V_fixture_max= 0.0
|time   V(typ)   V(min)   V(max)
0s        1.369V     608.5mV    1.851V
340.3ps   1.369V     608.5mV    1.78V
740.7ps   1.342V     608.2mV    938.7mV
920.9ps   1.174V     608mV      570.7mV
1.101ns   922.1mV    607.8mV    354.8mV
1.682ns   262.3mV    612mV      84.35mV
2.422ns   47.8mV     505.8mV    15.89mV
3.183ns   10.74mV    199.9mV    3.122mV
4.104ns   2.251mV    33.57mV    1.371mV
9.97ns    68.55uV    37.93uV    689.6uV
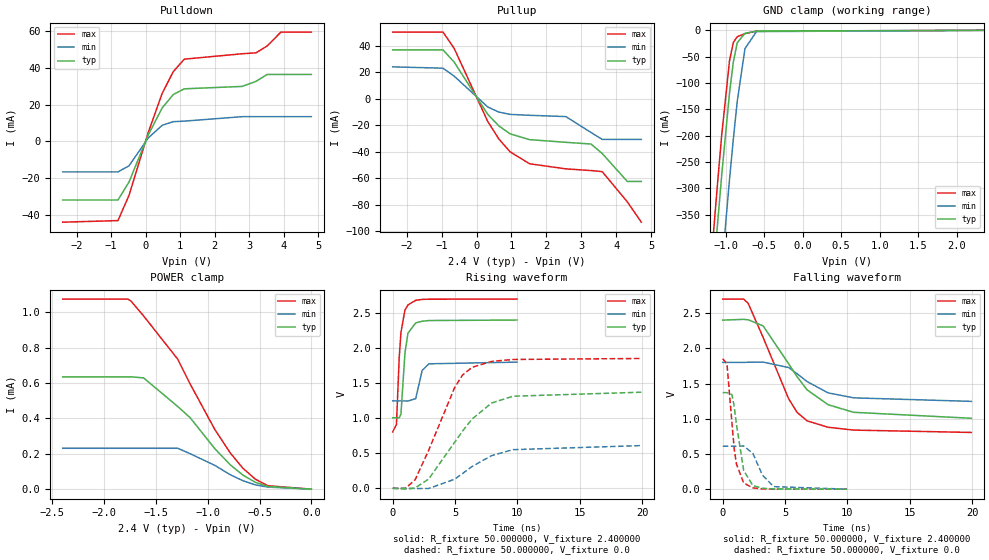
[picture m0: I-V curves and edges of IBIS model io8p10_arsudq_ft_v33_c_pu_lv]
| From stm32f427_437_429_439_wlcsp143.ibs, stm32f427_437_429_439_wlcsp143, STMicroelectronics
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|   Model io8p10_arsudq_ft_v33_c_pu_lv
[Model]  io8p10_arsudq_ft_v33_c_pu_lv
Model_type I/O
Polarity   Non-Inverting
Enable   Active-Low
Vinl =   0.720000V
Vinh =   1.680000V
Vmeas =  1.200000V
Cref =   40.000000pF
Rref =   100.000000M
Vref =   0.0V
C_comp   5.917600pF   5.759800pF   6.094800pF
[Temperature Range]   25.000000   0.125000k   -40.000000
[Pullup Reference]   2.400000V   1.800000V   2.700000V
[Pulldown Reference]   0.0V   0.0V   0.0V
[POWER Clamp Reference]   2.400000V   1.800000V   2.700000V
[GND Clamp Reference]   0.0V   0.0V   0.0V
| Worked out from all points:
|   slope of the pulldown table from 0 to 0.36 V, typ, clamps not added: 25 ohm
|   slope of the pullup table from 0 to 0.36 V, typ, clamps not added: 27.7 ohm
|   GND clamp passes 1 mA (typ) near -0.56 V on its own axis
|   rising waveform, R_fixture 50.000000, V_fixture 2.400000: 20-80 % time 338ps typ, 400ps min, 350ps max; typ from 1.01 V to 2.4 V
|   rising waveform, R_fixture 50.000000, V_fixture 0.0: 20-80 % time 3.47ns typ, 3.37ns min, 2.62ns max; typ from 0.001 V to 1.37 V
|   falling waveform, R_fixture 50.000000, V_fixture 2.400000: 20-80 % time 3.54ns typ, 3.08ns min, 2.71ns max; typ from 2.4 V to 1.01 V
|   falling waveform, R_fixture 50.000000, V_fixture 0.0: 20-80 % time 684ps typ, 1.03ns min, 583ps max; typ from 1.37 V to 0.001 V
[Pulldown]
|Voltage   I(typ)   I(min)   I(max)
-2.4V     -31.73mA   -16.51mA   -43.74mA
-800mV    -31.73mA   -16.51mA   -42.87mA
-480mV    -21.98mA   -13.17mA   -29.21mA
80mV      3.63mA     1.966mA    5.014mA
480mV     18.16mA    8.738mA    26.02mA
800mV     25.38mA    10.72mA    37.77mA
1.12V     28.53mA    11.02mA    44.6mA
2.8V      29.84mA    13.45mA    47.53mA
3.2V      32.59mA    13.45mA    48.03mA
3.52V     36.3mA     13.45mA    51.75mA
3.92V     36.3mA     13.45mA    59.27mA
4.8V      36.3mA     13.45mA    59.27mA
[Pullup]
|Voltage   I(typ)   I(min)   I(max)
-2.4V     36.81mA    24mA       50.22mA
-960mV    36.81mA    23.01mA    50.22mA
-640mV    27.62mA    17.02mA    37.96mA
320mV     -11.75mA   -6.207mA   -17.08mA
640mV     -20.52mA   -10.1mA    -30.35mA
960mV     -26.47mA   -11.82mA   -40.02mA
1.52V     -30.88mA   -12.51mA   -49.05mA
2.56V     -32.88mA   -13.48mA   -52.9mA
3.28V     -34.18mA   -25.5mA    -54.17mA
3.6V      -41.31mA   -30.7mA    -54.97mA
4.32V     -62.4mA    -30.7mA    -77.8mA
4.72V     -62.4mA    -30.7mA    -93.1mA
[GND_clamp]
|Voltage   I(typ)   I(min)   I(max)
-2.4V     -2.854A    -3.022A    -2.793A
-1.25V    -627.1mA   -809.1mA   -551.5mA
-1.2V     -535.5mA   -717.4mA   -459.3mA
-1.15V    -445.4mA   -626.8mA   -368.7mA
-1.1V     -357.2mA   -537.5mA   -280.5mA
-1.05V    -272mA     -449.9mA   -196.4mA
-950mV    -118.4mA   -282.5mA   -57.41mA
-900mV    -59.51mA   -205.1mA   -22.73mA
-850mV    -23.5mA    -134.9mA   -12.18mA
-750mV    -5.732mA   -34.85mA   -6.358mA
-600mV    -1.5mA     -2.382mA   -1.477mA
2.35V     0A         0A         0A
[POWER_clamp]
|Voltage   I(typ)   I(min)   I(max)
-2.4V     634.6uA    231uA      1.074mA
-1.77V    634.6uA    231uA      1.074mA
-1.74V    634.6uA    231uA      1.062mA
-1.62V    628.8uA    231uA      979.4uA
-1.29V    467.4uA    231uA      734.7uA
-1.17V    404uA      200.6uA    594.5uA
-930mV    227.6uA    133.8uA    335.6uA
-780mV    136.3uA    80.83uA    202.6uA
-660mV    79.46uA    47.68uA    118uA
-540mV    38.68uA    24.22uA    56.26uA
-420mV    15.19uA    11.75uA    19.49uA
0V        0A         0A         0A
[Ramp]
| variable   typ   min   max
dV/dt_r  0.82195/3.47088n   0.36551/3.36676n   1.11077/2.61270n
dV/dt_f  0.83238/3.53466n   0.33096/3.07272n   1.13554/2.71085n
R_load = 50.000000
[Rising Waveform]
R_fixture= 50.000000
V_fixture= 2.400000
V_fixture_min= 1.800000
V_fixture_max= 2.700000
|time   V(typ)   V(min)   V(max)
0s        1.007V     1.247V     805.8mV
300.3ps   1.006V     1.247V     909.8mV
520.5ps   1.006V     1.247V     1.861V
660.7ps   1.059V     1.247V     2.223V
981ps     1.927V     1.247V     2.541V
1.221ns   2.211V     1.246V     2.615V
1.842ns   2.359V     1.279V     2.681V
2.362ns   2.383V     1.681V     2.694V
2.903ns   2.393V     1.776V     2.697V
9.97ns    2.4V       1.8V       2.699V
[Rising Waveform]
R_fixture= 50.000000
V_fixture= 0.0
V_fixture_min= 0.0
V_fixture_max= 0.0
|time   V(typ)   V(min)   V(max)
0s        948.6uV    877.9uV    1.599mV
1.041ns   -11.03mV   971.5uV    2.48mV
1.802ns   7.423mV    -2.163mV   124.1mV
2.883ns   133mV      -1.312mV   543.2mV
4.965ns   656.5mV    130.7mV    1.436V
5.606ns   817.8mV    213mV      1.618V
6.366ns   988.6mV    312.3mV    1.726V
7.928ns   1.217V     467.2mV    1.81V
9.65ns    1.314V     552.3mV    1.838V
19.94ns   1.371V     610.3mV    1.852V
[Falling Waveform]
R_fixture= 50.000000
V_fixture= 2.400000
V_fixture_min= 1.800000
V_fixture_max= 2.700000
|time   V(typ)   V(min)   V(max)
0s        2.4V       1.8V       2.699V
1.682ns   2.411V     1.8V       2.699V
2.042ns   2.405V     1.802V     2.638V
3.243ns   2.318V     1.804V     2.154V
5.285ns   1.781V     1.727V     1.285V
5.966ns   1.597V     1.64V      1.091V
6.767ns   1.411V     1.528V     970.7mV
8.448ns   1.2V       1.368V     879.6mV
10.49ns   1.092V     1.297V     839.4mV
19.94ns   1.007V     1.247V     805.8mV
[Falling Waveform]
R_fixture= 50.000000
V_fixture= 0.0
V_fixture_min= 0.0
V_fixture_max= 0.0
|time   V(typ)   V(min)   V(max)
0s        1.371V     610.3mV    1.852V
340.3ps   1.371V     610.3mV    1.781V
740.7ps   1.343V     610mV      941.5mV
920.9ps   1.175V     609.8mV    574mV
1.101ns   923.7mV    609.6mV    358.1mV
1.682ns   265.5mV    613.8mV    88.01mV
2.422ns   50.7mV     507.4mV    19.32mV
3.183ns   13.27mV    201.6mV    4.995mV
4.084ns   3.967mV    36.99mV    2.597mV
9.97ns    948.6uV    877.9uV    1.599mV
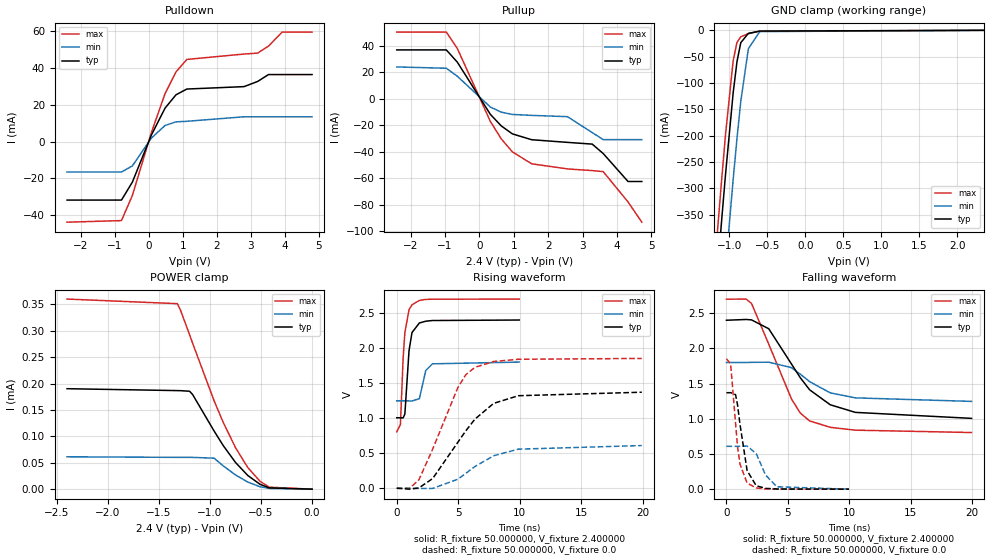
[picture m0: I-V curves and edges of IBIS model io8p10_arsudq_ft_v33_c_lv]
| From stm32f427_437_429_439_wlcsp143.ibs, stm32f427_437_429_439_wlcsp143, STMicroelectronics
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|   Model io8p10_arsudq_ft_v33_c_lv
[Model]  io8p10_arsudq_ft_v33_c_lv
Model_type I/O
Polarity   Non-Inverting
Enable   Active-Low
Vinl =   0.720000V
Vinh =   1.680000V
Vmeas =  1.200000V
Cref =   40.000000pF
Rref =   100.000000M
Vref =   0.0V
C_comp   5.917600pF   5.759800pF   6.094800pF
[Temperature Range]   25.000000   0.125000k   -40.000000
[Pullup Reference]   2.400000V   1.800000V   2.700000V
[Pulldown Reference]   0.0V   0.0V   0.0V
[POWER Clamp Reference]   2.400000V   1.800000V   2.700000V
[GND Clamp Reference]   0.0V   0.0V   0.0V
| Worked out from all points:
|   slope of the pulldown table from 0 to 0.36 V, typ, clamps not added: 25 ohm
|   slope of the pullup table from 0 to 0.36 V, typ, clamps not added: 27.7 ohm
|   GND clamp passes 1 mA (typ) near -0.56 V on its own axis
|   rising waveform, R_fixture 50.000000, V_fixture 2.400000: 20-80 % time 339ps typ, 401ps min, 352ps max; typ from 1.01 V to 2.4 V
|   rising waveform, R_fixture 50.000000, V_fixture 0.0: 20-80 % time 3.47ns typ, 3.36ns min, 2.61ns max; typ from 0 V to 1.37 V
|   falling waveform, R_fixture 50.000000, V_fixture 2.400000: 20-80 % time 3.55ns typ, 3.08ns min, 2.71ns max; typ from 2.4 V to 1.01 V
|   falling waveform, R_fixture 50.000000, V_fixture 0.0: 20-80 % time 683ps typ, 1.03ns min, 582ps max; typ from 1.37 V to 0 V
[Pulldown]
|Voltage   I(typ)   I(min)   I(max)
-2.4V     -31.73mA   -16.51mA   -43.74mA
-800mV    -31.73mA   -16.51mA   -42.87mA
-480mV    -21.98mA   -13.17mA   -29.21mA
80mV      3.63mA     1.966mA    5.014mA
480mV     18.16mA    8.738mA    26.02mA
800mV     25.38mA    10.72mA    37.77mA
1.12V     28.53mA    11.02mA    44.6mA
2.8V      29.84mA    13.47mA    47.53mA
3.2V      32.64mA    13.47mA    48.04mA
3.52V     36.39mA    13.47mA    51.83mA
3.92V     36.39mA    13.47mA    59.44mA
4.8V      36.39mA    13.47mA    59.44mA
[Pullup]
|Voltage   I(typ)   I(min)   I(max)
-2.4V     36.89mA    24.04mA    50.33mA
-960mV    36.89mA    23.04mA    50.33mA
-640mV    27.65mA    17.03mA    38mA
320mV     -11.75mA   -6.207mA   -17.08mA
640mV     -20.52mA   -10.1mA    -30.35mA
960mV     -26.47mA   -11.82mA   -40.02mA
1.52V     -30.88mA   -12.51mA   -49.05mA
2.56V     -32.88mA   -13.48mA   -52.9mA
3.28V     -34.19mA   -25.5mA    -54.18mA
3.6V      -41.31mA   -30.8mA    -54.97mA
4.32V     -62.4mA    -30.8mA    -77.8mA
4.72V     -62.4mA    -30.8mA    -93.1mA
[GND_clamp]
|Voltage   I(typ)   I(min)   I(max)
-2.4V     -2.854A    -3.022A    -2.793A
-1.25V    -627.1mA   -809.1mA   -551.5mA
-1.2V     -535.5mA   -717.4mA   -459.3mA
-1.15V    -445.4mA   -626.8mA   -368.7mA
-1.1V     -357.2mA   -537.5mA   -280.5mA
-1.05V    -272mA     -449.9mA   -196.4mA
-950mV    -118.4mA   -282.5mA   -57.41mA
-900mV    -59.51mA   -205.1mA   -22.73mA
-850mV    -23.5mA    -134.9mA   -12.18mA
-750mV    -5.732mA   -34.85mA   -6.358mA
-600mV    -1.5mA     -2.382mA   -1.477mA
2.35V     0A         0A         0A
[POWER_clamp]
|Voltage   I(typ)   I(min)   I(max)
-2.4V     190.2uA    61.28uA    359.9uA
-1.32V    186.6uA    60.21uA    351.2uA
-1.29V    186.5uA    60.2uA     339.6uA
-1.2V     185.4uA    60.18uA    292.6uA
-1.17V    179.2uA    60.17uA    276.3uA
-960mV    110.2uA    58.68uA    167.5uA
-870mV    82.45uA    44.05uA    126.3uA
-750mV    50.58uA    26.98uA    78.64uA
-630mV    25.95uA    13.47uA    41.02uA
-510mV    9.222uA    4.578uA    14.97uA
-420mV    2.426uA    1.429uA    3.749uA
0V        0A         0A         0A
[Ramp]
| variable   typ   min   max
dV/dt_r  0.82200/3.46683n   0.36530/3.36058n   1.11108/2.60966n
dV/dt_f  0.83316/3.53544n   0.33132/3.07553n   1.13621/2.70916n
R_load = 50.000000
[Rising Waveform]
R_fixture= 50.000000
V_fixture= 2.400000
V_fixture_min= 1.800000
V_fixture_max= 2.700000
|time   V(typ)   V(min)   V(max)
0s        1.006V     1.247V     804.7mV
300.3ps   1.005V     1.247V     908.4mV
520.5ps   1.004V     1.247V     1.857V
660.7ps   1.058V     1.247V     2.22V
1.001ns   1.965V     1.246V     2.548V
1.241ns   2.221V     1.245V     2.617V
1.842ns   2.358V     1.278V     2.68V
2.362ns   2.383V     1.68V      2.694V
2.903ns   2.393V     1.775V     2.697V
9.97ns    2.4V       1.8V       2.699V
[Rising Waveform]
R_fixture= 50.000000
V_fixture= 0.0
V_fixture_min= 0.0
V_fixture_max= 0.0
|time   V(typ)   V(min)   V(max)
0s        68.37uV    37.98uV    689.6uV
1.041ns   -13.08mV   132.4uV    -967.1uV
1.802ns   4.578mV    -3.035mV   120mV
2.923ns   138mV      -2.679mV   557.3mV
4.965ns   654.2mV    128.4mV    1.434V
5.606ns   815.8mV    210.9mV    1.617V
6.366ns   986.8mV    310.3mV    1.725V
7.888ns   1.211V     463.3mV    1.808V
9.89ns    1.32V      557.6mV    1.84V
19.94ns   1.37V      609.1mV    1.852V
[Falling Waveform]
R_fixture= 50.000000
V_fixture= 2.400000
V_fixture_min= 1.800000
V_fixture_max= 2.700000
|time   V(typ)   V(min)   V(max)
0s        2.4V       1.8V       2.699V
1.602ns   2.411V     1.8V       2.701V
2.042ns   2.405V     1.802V     2.639V
3.443ns   2.279V     1.804V     2.059V
5.285ns   1.78V      1.727V     1.284V
6.006ns   1.584V     1.634V     1.082V
6.767ns   1.412V     1.528V     969.6mV
8.448ns   1.199V     1.368V     878.7mV
10.49ns   1.091V     1.297V     838.2mV
19.94ns   1.006V     1.247V     804.7mV
[Falling Waveform]
R_fixture= 50.000000
V_fixture= 0.0
V_fixture_min= 0.0
V_fixture_max= 0.0
|time   V(typ)   V(min)   V(max)
0s        1.37V      609.1mV    1.852V
340.3ps   1.371V     609.1mV    1.781V
740.7ps   1.343V     608.9mV    940.8mV
900.9ps   1.198V     608.7mV    606mV
1.101ns   923.5mV    608.5mV    356.9mV
1.682ns   263.7mV    612.7mV    86.16mV
2.422ns   48.96mV    506.4mV    16.97mV
3.183ns   11.42mV    200.6mV    3.446mV
4.104ns   2.505mV    34.05mV    1.468mV
9.97ns    68.37uV    37.98uV    689.6uV
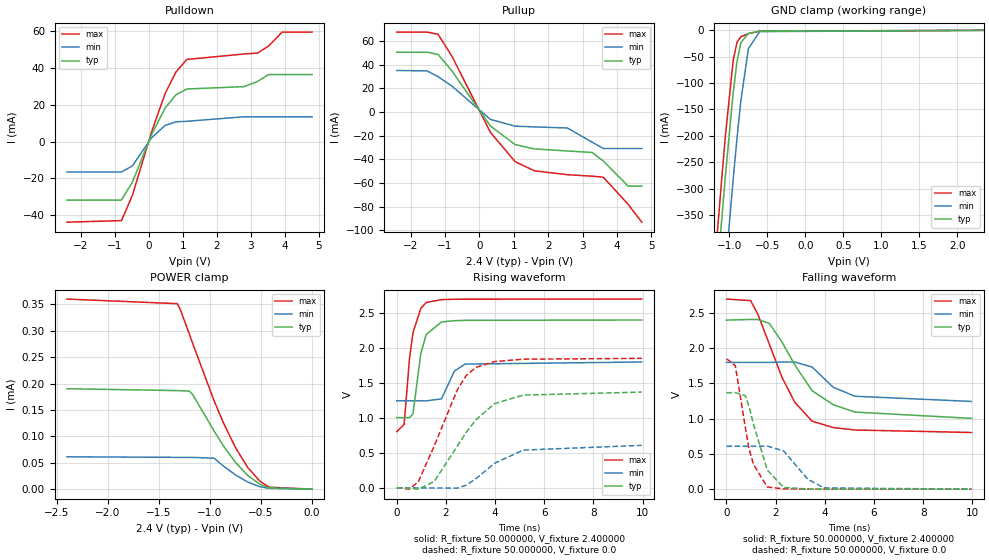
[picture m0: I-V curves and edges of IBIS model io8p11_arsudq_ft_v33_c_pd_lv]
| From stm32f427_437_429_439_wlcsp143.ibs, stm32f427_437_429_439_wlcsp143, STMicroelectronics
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|   Model io8p11_arsudq_ft_v33_c_pd_lv
[Model]  io8p11_arsudq_ft_v33_c_pd_lv
Model_type I/O
Polarity   Non-Inverting
Enable   Active-Low
Vinl =   0.720000V
Vinh =   1.680000V
Vmeas =  1.200000V
Cref =   30.000000pF
Rref =   100.000000M
Vref =   0.0V
C_comp   5.917600pF   5.759800pF   6.094800pF
[Temperature Range]   25.000000   0.125000k   -40.000000
[Pullup Reference]   2.400000V   1.800000V   2.700000V
[Pulldown Reference]   0.0V   0.0V   0.0V
[POWER Clamp Reference]   2.400000V   1.800000V   2.700000V
[GND Clamp Reference]   0.0V   0.0V   0.0V
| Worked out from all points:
|   slope of the pulldown table from 0 to 0.36 V, typ, clamps not added: 25 ohm
|   slope of the pullup table from 0 to 0.36 V, typ, clamps not added: 27.7 ohm
|   GND clamp passes 1 mA (typ) near -0.56 V on its own axis
|   rising waveform, R_fixture 50.000000, V_fixture 2.400000: 20-80 % time 343ps typ, 404ps min, 354ps max; typ from 1 V to 2.4 V
|   rising waveform, R_fixture 50.000000, V_fixture 0.0: 20-80 % time 1.65ns typ, 1.48ns min, 1.31ns max; typ from 0 V to 1.37 V
|   falling waveform, R_fixture 50.000000, V_fixture 2.400000: 20-80 % time 1.65ns typ, 1.22ns min, 1.4ns max; typ from 2.4 V to 1 V
|   falling waveform, R_fixture 50.000000, V_fixture 0.0: 20-80 % time 675ps typ, 913ps min, 578ps max; typ from 1.37 V to 0 V
[Pulldown]
|Voltage   I(typ)   I(min)   I(max)
-2.4V     -31.73mA   -16.51mA   -43.74mA
-800mV    -31.73mA   -16.51mA   -42.87mA
-480mV    -21.98mA   -13.17mA   -29.21mA
80mV      3.63mA     1.966mA    5.014mA
480mV     18.15mA    8.738mA    26.02mA
800mV     25.38mA    10.72mA    37.77mA
1.12V     28.53mA    11.02mA    44.6mA
2.8V      29.84mA    13.47mA    47.53mA
3.2V      32.64mA    13.47mA    48.04mA
3.52V     36.39mA    13.47mA    51.82mA
3.92V     36.39mA    13.47mA    59.43mA
4.8V      36.39mA    13.47mA    59.43mA
[Pullup]
|Voltage   I(typ)   I(min)   I(max)
-2.4V     50.45mA    35.08mA    67.47mA
-1.52V    50.45mA    34.74mA    67.47mA
-1.2V     48.6mA     29.87mA    65.62mA
-800mV    34.81mA    21.93mA    47.29mA
320mV     -11.75mA   -6.207mA   -17.08mA
1.04V     -27.53mA   -11.97mA   -41.91mA
1.6V      -31.13mA   -12.58mA   -49.63mA
2.56V     -32.88mA   -13.48mA   -52.9mA
3.28V     -34.19mA   -25.5mA    -54.18mA
3.6V      -41.31mA   -30.8mA    -54.97mA
4.32V     -62.5mA    -30.8mA    -77.8mA
4.72V     -62.5mA    -30.8mA    -93mA
[GND_clamp]
|Voltage   I(typ)   I(min)   I(max)
-2.4V     -2.854A    -3.022A    -2.792A
-1.25V    -627.1mA   -809.1mA   -551.5mA
-1.2V     -535.5mA   -717.4mA   -459.3mA
-1.15V    -445.4mA   -626.8mA   -368.7mA
-1.1V     -357.2mA   -537.5mA   -280.5mA
-1.05V    -272mA     -449.9mA   -196.4mA
-950mV    -118.4mA   -282.5mA   -57.42mA
-900mV    -59.51mA   -205.1mA   -22.74mA
-850mV    -23.51mA   -134.9mA   -12.19mA
-750mV    -5.744mA   -34.86mA   -6.372mA
-600mV    -1.511mA   -2.391mA   -1.49mA
2.35V     58.09uA    37.93uA    67.25uA
[POWER_clamp]
|Voltage   I(typ)   I(min)   I(max)
-2.4V     190.2uA    61.28uA    359.9uA
-1.32V    186.6uA    60.21uA    351.2uA
-1.29V    186.5uA    60.2uA     339.6uA
-1.2V     185.4uA    60.18uA    292.6uA
-1.17V    179.2uA    60.17uA    276.3uA
-960mV    110.2uA    58.68uA    167.5uA
-870mV    82.45uA    44.05uA    126.3uA
-750mV    50.58uA    26.98uA    78.64uA
-630mV    25.95uA    13.47uA    41.02uA
-510mV    9.222uA    4.578uA    14.97uA
-420mV    2.426uA    1.429uA    3.749uA
0V        0A         0A         0A
[Ramp]
| variable   typ   min   max
dV/dt_r  0.82110/1.65009n   0.36395/1.47481n   1.11030/1.31153n
dV/dt_f  0.83262/1.64564n   0.33168/1.21786n   1.13539/1.39804n
R_load = 50.000000
[Rising Waveform]
R_fixture= 50.000000
V_fixture= 2.400000
V_fixture_min= 1.800000
V_fixture_max= 2.700000
|time   V(typ)   V(min)   V(max)
0s        1.005V     1.245V     804.3mV
300.3ps   1.004V     1.245V     907.7mV
520.5ps   1.004V     1.245V     1.855V
660.7ps   1.057V     1.246V     2.217V
981ps     1.924V     1.245V     2.566V
1.201ns   2.192V     1.244V     2.649V
1.822ns   2.371V     1.272V     2.69V
2.342ns   2.389V     1.668V     2.695V
2.783ns   2.394V     1.769V     2.696V
9.97ns    2.399V     1.799V     2.698V
[Rising Waveform]
R_fixture= 50.000000
V_fixture= 0.0
V_fixture_min= 0.0
V_fixture_max= 0.0
|time   V(typ)   V(min)   V(max)
0s        77.12uV    36.86uV    780.6uV
520.5ps   -2.093mV   18.57uV    -16.39mV
880.9ps   -17.63mV   68.94uV    89.54mV
1.522ns   91.18mV    -350.7uV   597.1mV
2.462ns   596mV      -3.628mV   1.399V
2.823ns   791.8mV    38.23mV    1.606V
3.223ns   974mV      133mV      1.722V
3.984ns   1.205V     352.6mV    1.805V
5.145ns   1.326V     540.4mV    1.839V
9.97ns    1.369V     608.5mV    1.851V
[Falling Waveform]
R_fixture= 50.000000
V_fixture= 2.400000
V_fixture_min= 1.800000
V_fixture_max= 2.700000
|time   V(typ)   V(min)   V(max)
0s        2.399V     1.799V     2.698V
981ps     2.409V     1.799V     2.676V
1.281ns   2.407V     1.799V     2.48V
1.742ns   2.354V     1.799V     2.06V
2.262ns   2.086V     1.804V     1.584V
2.783ns   1.763V     1.804V     1.232V
3.483ns   1.398V     1.734V     965.1mV
4.344ns   1.199V     1.446V     874.6mV
5.225ns   1.094V     1.319V     839.9mV
9.97ns    1.005V     1.245V     804.3mV
[Falling Waveform]
R_fixture= 50.000000
V_fixture= 0.0
V_fixture_min= 0.0
V_fixture_max= 0.0
|time   V(typ)   V(min)   V(max)
0s        1.369V     608.5mV    1.851V
360.4ps   1.37V      608.5mV    1.754V
760.8ps   1.328V     608.2mV    890.1mV
920.9ps   1.172V     608.1mV    569.6mV
1.101ns   919.9mV    608mV      350.8mV
1.662ns   270.6mV    611.1mV    30.63mV
2.322ns   24.17mV    543.4mV    3.669mV
3.303ns   2.327mV    144.1mV    1.808mV
3.964ns   1.351mV    17.96mV    1.399mV
9.97ns    77.12uV    36.86uV    780.6uV
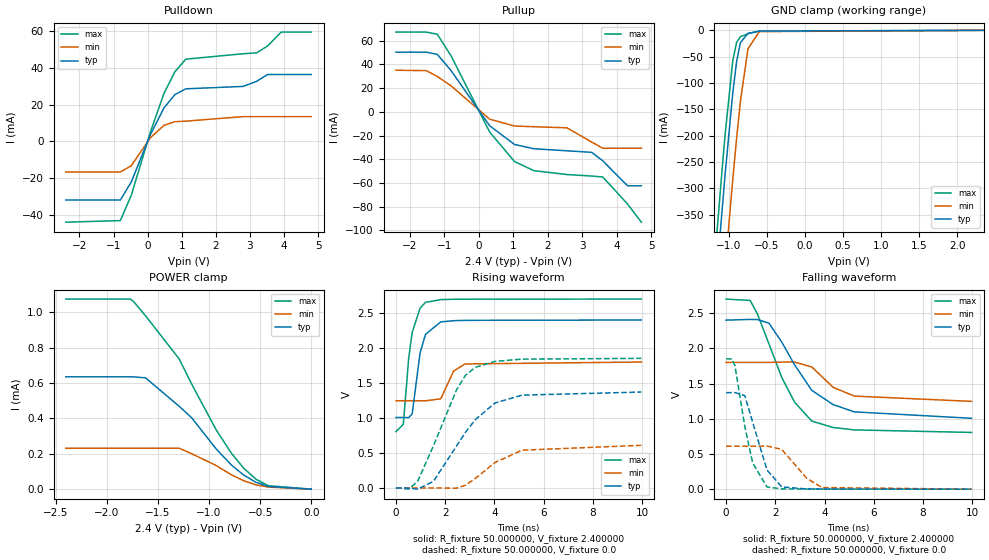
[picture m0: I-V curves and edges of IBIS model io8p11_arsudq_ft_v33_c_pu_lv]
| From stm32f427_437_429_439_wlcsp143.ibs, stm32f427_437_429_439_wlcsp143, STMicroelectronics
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|   Model io8p11_arsudq_ft_v33_c_pu_lv
[Model]  io8p11_arsudq_ft_v33_c_pu_lv
Model_type I/O
Polarity   Non-Inverting
Enable   Active-Low
Vinl =   0.720000V
Vinh =   1.680000V
Vmeas =  1.200000V
Cref =   30.000000pF
Rref =   100.000000M
Vref =   0.0V
C_comp   5.917600pF   5.759800pF   6.094800pF
[Temperature Range]   25.000000   0.125000k   -40.000000
[Pullup Reference]   2.400000V   1.800000V   2.700000V
[Pulldown Reference]   0.0V   0.0V   0.0V
[POWER Clamp Reference]   2.400000V   1.800000V   2.700000V
[GND Clamp Reference]   0.0V   0.0V   0.0V
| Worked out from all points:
|   slope of the pulldown table from 0 to 0.36 V, typ, clamps not added: 25 ohm
|   slope of the pullup table from 0 to 0.36 V, typ, clamps not added: 27.7 ohm
|   GND clamp passes 1 mA (typ) near -0.56 V on its own axis
|   rising waveform, R_fixture 50.000000, V_fixture 2.400000: 20-80 % time 341ps typ, 402ps min, 352ps max; typ from 1.01 V to 2.4 V
|   rising waveform, R_fixture 50.000000, V_fixture 0.0: 20-80 % time 1.66ns typ, 1.48ns min, 1.31ns max; typ from 0.001 V to 1.37 V
|   falling waveform, R_fixture 50.000000, V_fixture 2.400000: 20-80 % time 1.65ns typ, 1.22ns min, 1.4ns max; typ from 2.4 V to 1.01 V
|   falling waveform, R_fixture 50.000000, V_fixture 0.0: 20-80 % time 678ps typ, 915ps min, 580ps max; typ from 1.37 V to 0.001 V
[Pulldown]
|Voltage   I(typ)   I(min)   I(max)
-2.4V     -31.73mA   -16.51mA   -43.74mA
-800mV    -31.73mA   -16.51mA   -42.87mA
-480mV    -21.98mA   -13.17mA   -29.21mA
80mV      3.63mA     1.966mA    5.014mA
480mV     18.16mA    8.738mA    26.02mA
800mV     25.38mA    10.72mA    37.77mA
1.12V     28.53mA    11.02mA    44.6mA
2.8V      29.84mA    13.45mA    47.53mA
3.2V      32.59mA    13.45mA    48.03mA
3.52V     36.3mA     13.45mA    51.75mA
3.92V     36.3mA     13.45mA    59.27mA
4.8V      36.3mA     13.45mA    59.27mA
[Pullup]
|Voltage   I(typ)   I(min)   I(max)
-2.4V     50.37mA    35.09mA    67.27mA
-1.52V    50.37mA    34.75mA    67.27mA
-1.2V     48.49mA    29.88mA    65.45mA
-800mV    34.76mA    21.91mA    47.21mA
320mV     -11.75mA   -6.207mA   -17.08mA
1.04V     -27.53mA   -11.97mA   -41.91mA
1.6V      -31.13mA   -12.57mA   -49.63mA
2.56V     -32.88mA   -13.48mA   -52.9mA
3.28V     -34.18mA   -25.5mA    -54.17mA
3.6V      -41.31mA   -30.7mA    -54.97mA
4.32V     -62.4mA    -30.7mA    -77.8mA
4.72V     -62.4mA    -30.7mA    -93.1mA
[GND_clamp]
|Voltage   I(typ)   I(min)   I(max)
-2.4V     -2.854A    -3.022A    -2.792A
-1.25V    -627.1mA   -809.1mA   -551.5mA
-1.2V     -535.5mA   -717.4mA   -459.3mA
-1.15V    -445.4mA   -626.8mA   -368.7mA
-1.1V     -357.2mA   -537.5mA   -280.5mA
-1.05V    -272mA     -449.9mA   -196.4mA
-950mV    -118.4mA   -282.5mA   -57.41mA
-900mV    -59.51mA   -205.1mA   -22.73mA
-850mV    -23.5mA    -134.9mA   -12.18mA
-750mV    -5.732mA   -34.85mA   -6.358mA
-600mV    -1.5mA     -2.382mA   -1.477mA
2.35V     0A         0A         0A
[POWER_clamp]
|Voltage   I(typ)   I(min)   I(max)
-2.4V     634.6uA    231uA      1.074mA
-1.77V    634.6uA    231uA      1.074mA
-1.74V    634.6uA    231uA      1.062mA
-1.62V    628.8uA    231uA      979.4uA
-1.29V    467.4uA    231uA      734.7uA
-1.17V    404uA      200.6uA    594.5uA
-930mV    227.6uA    133.8uA    335.6uA
-780mV    136.3uA    80.83uA    202.6uA
-660mV    79.46uA    47.68uA    118uA
-540mV    38.68uA    24.22uA    56.26uA
-420mV    15.19uA    11.75uA    19.49uA
0V        0A         0A         0A
[Ramp]
| variable   typ   min   max
dV/dt_r  0.82165/1.65286n   0.36451/1.47666n   1.11071/1.31366n
dV/dt_f  0.83190/1.64425n   0.33108/1.21640n   1.13506/1.39796n
R_load = 50.000000
[Rising Waveform]
R_fixture= 50.000000
V_fixture= 2.400000
V_fixture_min= 1.800000
V_fixture_max= 2.700000
|time   V(typ)   V(min)   V(max)
0s        1.007V     1.247V     805.8mV
300.3ps   1.007V     1.247V     909.6mV
520.5ps   1.006V     1.247V     1.859V
660.7ps   1.059V     1.247V     2.221V
981ps     1.928V     1.247V     2.57V
1.201ns   2.195V     1.246V     2.652V
1.822ns   2.373V     1.274V     2.691V
2.342ns   2.39V      1.67V      2.696V
2.803ns   2.395V     1.772V     2.697V
9.97ns    2.4V       1.8V       2.699V
[Rising Waveform]
R_fixture= 50.000000
V_fixture= 0.0
V_fixture_min= 0.0
V_fixture_max= 0.0
|time   V(typ)   V(min)   V(max)
0s        957.2uV    876.9uV    1.69mV
520.5ps   -1.2mV     858.4uV    -14.08mV
880.9ps   -16.05mV   908.6uV    93.54mV
1.522ns   94.58mV    489.1uV    602.1mV
2.462ns   599.7mV    -1.915mV   1.402V
2.823ns   794.7mV    40.48mV    1.609V
3.223ns   976.4mV    135.7mV    1.724V
4.024ns   1.215V     364.4mV    1.809V
5.125ns   1.327V     540.6mV    1.841V
9.97ns    1.371V     610.3mV    1.852V
[Falling Waveform]
R_fixture= 50.000000
V_fixture= 2.400000
V_fixture_min= 1.800000
V_fixture_max= 2.700000
|time   V(typ)   V(min)   V(max)
0s        2.4V       1.8V       2.699V
981ps     2.41V      1.8V       2.679V
1.281ns   2.408V     1.8V       2.483V
1.742ns   2.357V     1.8V       2.063V
2.262ns   2.089V     1.804V     1.587V
2.783ns   1.766V     1.805V     1.236V
3.483ns   1.403V     1.735V     967.2mV
4.344ns   1.202V     1.448V     876.4mV
5.205ns   1.098V     1.322V     842.2mV
9.97ns    1.007V     1.247V     805.8mV
[Falling Waveform]
R_fixture= 50.000000
V_fixture= 0.0
V_fixture_min= 0.0
V_fixture_max= 0.0
|time   V(typ)   V(min)   V(max)
0s        1.371V     610.3mV    1.852V
240.2ps   1.371V     610.3mV    1.848V
360.4ps   1.372V     610.3mV    1.755V
760.8ps   1.329V     610mV      893.1mV
1.081ns   951.9mV    609.8mV    373.1mV
1.662ns   273.8mV    612.9mV    32.56mV
2.262ns   32.81mV    565.5mV    5.131mV
3.283ns   3.444mV    152.8mV    2.813mV
3.904ns   2.368mV    23.26mV    2.384mV
9.97ns    957.2uV    876.9uV    1.69mV
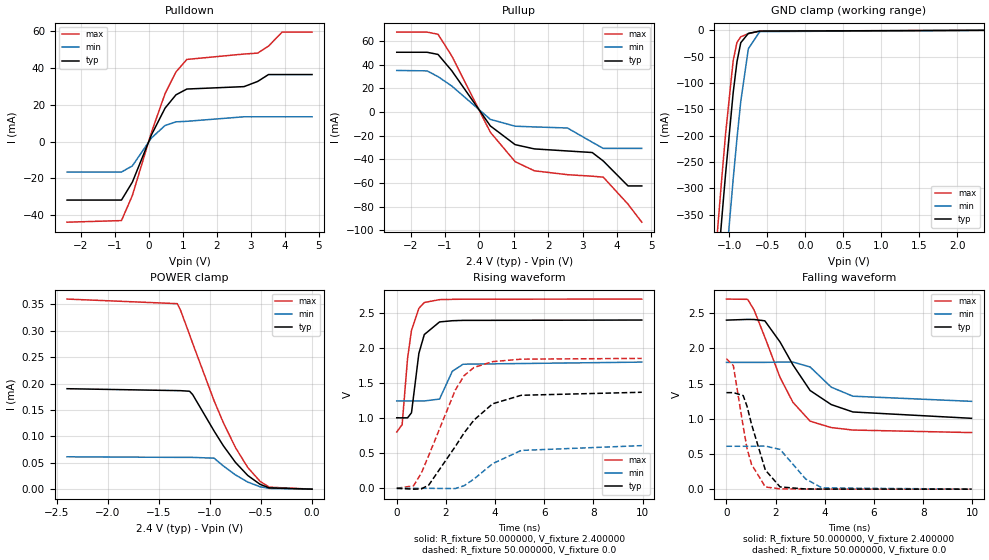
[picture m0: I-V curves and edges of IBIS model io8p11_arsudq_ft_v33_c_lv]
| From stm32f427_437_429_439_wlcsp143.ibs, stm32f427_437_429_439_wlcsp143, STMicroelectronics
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|   Model io8p11_arsudq_ft_v33_c_lv
[Model]  io8p11_arsudq_ft_v33_c_lv
Model_type I/O
Polarity   Non-Inverting
Enable   Active-Low
Vinl =   0.720000V
Vinh =   1.680000V
Vmeas =  1.200000V
Cref =   30.000000pF
Rref =   100.000000M
Vref =   0.0V
C_comp   5.917600pF   5.759800pF   6.094800pF
[Temperature Range]   25.000000   0.125000k   -40.000000
[Pullup Reference]   2.400000V   1.800000V   2.700000V
[Pulldown Reference]   0.0V   0.0V   0.0V
[POWER Clamp Reference]   2.400000V   1.800000V   2.700000V
[GND Clamp Reference]   0.0V   0.0V   0.0V
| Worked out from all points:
|   slope of the pulldown table from 0 to 0.36 V, typ, clamps not added: 25 ohm
|   slope of the pullup table from 0 to 0.36 V, typ, clamps not added: 27.7 ohm
|   GND clamp passes 1 mA (typ) near -0.56 V on its own axis
|   rising waveform, R_fixture 50.000000, V_fixture 2.400000: 20-80 % time 342ps typ, 403ps min, 354ps max; typ from 1.01 V to 2.4 V
|   rising waveform, R_fixture 50.000000, V_fixture 0.0: 20-80 % time 1.65ns typ, 1.48ns min, 1.31ns max; typ from 0 V to 1.37 V
|   falling waveform, R_fixture 50.000000, V_fixture 2.400000: 20-80 % time 1.66ns typ, 1.22ns min, 1.4ns max; typ from 2.4 V to 1.01 V
|   falling waveform, R_fixture 50.000000, V_fixture 0.0: 20-80 % time 677ps typ, 915ps min, 580ps max; typ from 1.37 V to 0 V
[Pulldown]
|Voltage   I(typ)   I(min)   I(max)
-2.4V     -31.73mA   -16.51mA   -43.74mA
-800mV    -31.73mA   -16.51mA   -42.87mA
-480mV    -21.98mA   -13.17mA   -29.21mA
80mV      3.63mA     1.966mA    5.014mA
480mV     18.16mA    8.738mA    26.02mA
800mV     25.38mA    10.72mA    37.77mA
1.12V     28.53mA    11.02mA    44.6mA
2.8V      29.84mA    13.47mA    47.53mA
3.2V      32.64mA    13.47mA    48.04mA
3.52V     36.39mA    13.47mA    51.83mA
3.92V     36.39mA    13.47mA    59.44mA
4.8V      36.39mA    13.47mA    59.44mA
[Pullup]
|Voltage   I(typ)   I(min)   I(max)
-2.4V     50.45mA    35.08mA    67.47mA
-1.52V    50.45mA    34.74mA    67.47mA
-1.2V     48.6mA     29.87mA    65.63mA
-800mV    34.81mA    21.93mA    47.29mA
320mV     -11.75mA   -6.207mA   -17.08mA
1.04V     -27.54mA   -11.97mA   -41.91mA
1.6V      -31.14mA   -12.58mA   -49.63mA
2.56V     -32.88mA   -13.48mA   -52.9mA
3.28V     -34.19mA   -25.5mA    -54.18mA
3.6V      -41.31mA   -30.7mA    -54.97mA
4.32V     -62.4mA    -30.7mA    -77.8mA
4.72V     -62.4mA    -30.7mA    -93mA
[GND_clamp]
|Voltage   I(typ)   I(min)   I(max)
-2.4V     -2.854A    -3.022A    -2.792A
-1.25V    -627.1mA   -809.1mA   -551.5mA
-1.2V     -535.5mA   -717.4mA   -459.3mA
-1.15V    -445.4mA   -626.8mA   -368.7mA
-1.1V     -357.2mA   -537.5mA   -280.5mA
-1.05V    -272mA     -449.9mA   -196.4mA
-950mV    -118.4mA   -282.5mA   -57.41mA
-900mV    -59.51mA   -205.1mA   -22.73mA
-850mV    -23.5mA    -134.9mA   -12.18mA
-750mV    -5.732mA   -34.85mA   -6.358mA
-600mV    -1.5mA     -2.382mA   -1.477mA
2.35V     0A         0A         0A
[POWER_clamp]
|Voltage   I(typ)   I(min)   I(max)
-2.4V     190.2uA    61.28uA    359.9uA
-1.32V    186.6uA    60.21uA    351.2uA
-1.29V    186.5uA    60.2uA     339.6uA
-1.2V     185.4uA    60.18uA    292.6uA
-1.17V    179.2uA    60.17uA    276.3uA
-960mV    110.2uA    58.68uA    167.5uA
-870mV    82.45uA    44.05uA    126.3uA
-750mV    50.58uA    26.98uA    78.64uA
-630mV    25.95uA    13.47uA    41.02uA
-510mV    9.222uA    4.578uA    14.97uA
-420mV    2.426uA    1.429uA    3.749uA
0V        0A         0A         0A
[Ramp]
| variable   typ   min   max
dV/dt_r  0.82170/1.65138n   0.36428/1.47653n   1.11096/1.31204n
dV/dt_f  0.83268/1.64751n   0.33144/1.21913n   1.13572/1.39798n
R_load = 50.000000
[Rising Waveform]
R_fixture= 50.000000
V_fixture= 2.400000
V_fixture_min= 1.800000
V_fixture_max= 2.700000
|time   V(typ)   V(min)   V(max)
0s        1.006V     1.247V     803.4mV
220.2ps   1.005V     1.247V     908.2mV
440.4ps   1.005V     1.247V     1.855V
600.6ps   1.078V     1.247V     2.253V
900.9ps   1.925V     1.247V     2.567V
1.121ns   2.193V     1.246V     2.65V
1.742ns   2.373V     1.273V     2.691V
2.262ns   2.39V      1.67V      2.695V
2.703ns   2.395V     1.77V      2.697V
9.97ns    2.4V       1.8V       2.699V
[Rising Waveform]
R_fixture= 50.000000
V_fixture= 0.0
V_fixture_min= 0.0
V_fixture_max= 0.0
|time   V(typ)   V(min)   V(max)
0s        124.1uV    34.13uV    462.5uV
680.7ps   -11.81mV   40.46uV    35.89mV
1.001ns   -7.808mV   160.9uV    216.9mV
1.301ns   46.04mV    199.4uV    467.6mV
2.382ns   595.9mV    -3.632mV   1.401V
2.743ns   791.7mV    38.22mV    1.608V
3.143ns   974mV      133mV      1.724V
3.904ns   1.206V     352.6mV    1.807V
5.065ns   1.327V     540.6mV    1.842V
9.97ns    1.37V      609.1mV    1.853V
[Falling Waveform]
R_fixture= 50.000000
V_fixture= 2.400000
V_fixture_min= 1.800000
V_fixture_max= 2.700000
|time   V(typ)   V(min)   V(max)
0s        2.4V       1.8V       2.699V
860.9ps   2.41V      1.8V       2.695V
1.121ns   2.409V     1.8V       2.546V
1.562ns   2.39V      1.8V       2.158V
2.182ns   2.089V     1.804V     1.586V
2.703ns   1.766V     1.805V     1.234V
3.403ns   1.401V     1.735V     965.3mV
4.264ns   1.201V     1.448V     874.3mV
5.145ns   1.096V     1.32V      839.4mV
9.97ns    1.006V     1.247V     803.4mV
[Falling Waveform]
R_fixture= 50.000000
V_fixture= 0.0
V_fixture_min= 0.0
V_fixture_max= 0.0
|time   V(typ)   V(min)   V(max)
0s        1.37V      609.1mV    1.853V
280.3ps   1.371V     609.1mV    1.755V
680.7ps   1.329V     608.9mV    892mV
840.8ps   1.173V     608.7mV    571.4mV
1.021ns   921.3mV    608.6mV    352.6mV
1.582ns   272.1mV    611.7mV    31.23mV
2.182ns   31.8mV     564.4mV    3.987mV
3.223ns   2.613mV    144.6mV    1.621mV
3.884ns   1.512mV    18.24mV    1.159mV
9.97ns    124.1uV    34.13uV    462.5uV
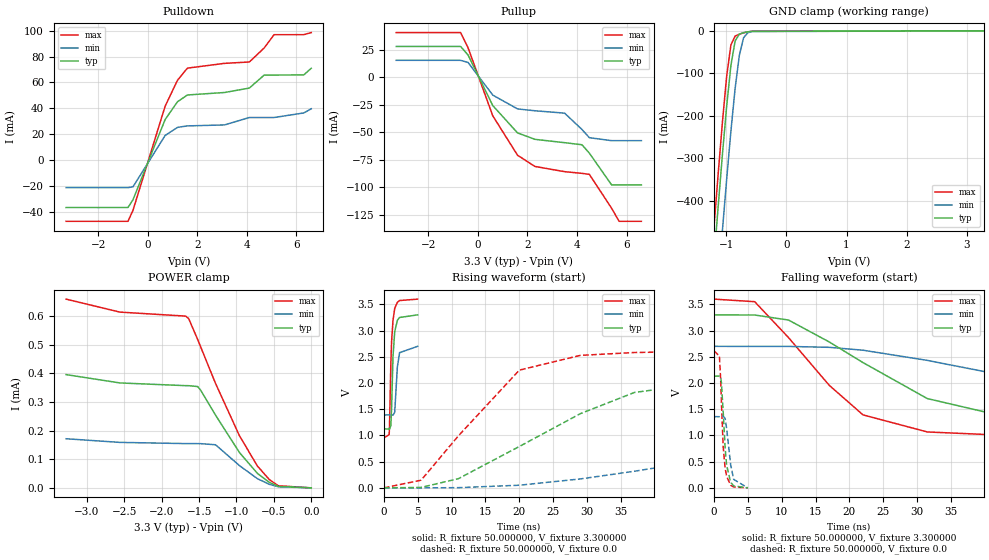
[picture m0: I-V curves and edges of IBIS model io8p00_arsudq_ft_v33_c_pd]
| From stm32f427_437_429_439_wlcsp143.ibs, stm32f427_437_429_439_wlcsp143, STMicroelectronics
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|   Model io8p00_arsudq_ft_v33_c_pd
[Model]  io8p00_arsudq_ft_v33_c_pd
Model_type I/O
Polarity   Non-Inverting
Enable   Active-Low
Vinl =   0.990000V
Vinh =   2.310000V
Vmeas =  1.650000V
Cref =   50.000000pF
Rref =   100.000000M
Vref =   0.0V
C_comp   5.986400pF   5.818600pF   6.191500pF
[Temperature Range]   25.000000   0.125000k   -40.000000
[Pullup Reference]   3.300000V   2.700000V   3.600000V
[Pulldown Reference]   0.0V   0.0V   0.0V
[POWER Clamp Reference]   3.300000V   2.700000V   3.600000V
[GND Clamp Reference]   0.0V   0.0V   0.0V
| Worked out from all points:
|   slope of the pulldown table from 0 to 0.495 V, typ, clamps not added: 20.9 ohm
|   slope of the pullup table from 0 to 0.495 V, typ, clamps not added: 22.6 ohm
|   GND clamp passes 1 mA (typ) near -0.56 V on its own axis
|   rising waveform, R_fixture 50.000000, V_fixture 3.300000: 20-80 % time 367ps typ, 350ps min, 388ps max; typ from 1.12 V to 3.3 V
|   rising waveform, R_fixture 50.000000, V_fixture 0.0: 20-80 % time 19.2ns typ, 45.2ns min, 10.2ns max; typ from 0 V to 2.13 V
|   falling waveform, R_fixture 50.000000, V_fixture 3.300000: 20-80 % time 18.2ns typ, 37.1ns min, 11.3ns max; typ from 3.3 V to 1.12 V
|   falling waveform, R_fixture 50.000000, V_fixture 0.0: 20-80 % time 608ps typ, 781ps min, 540ps max; typ from 2.13 V to 0 V
[Pulldown]
|Voltage   I(typ)   I(min)   I(max)
-3.3V     -36.46mA   -21.09mA   -47.09mA
-800mV    -36.46mA   -21.09mA   -47.09mA
-600mV    -30.5mA    -20.54mA   -38.69mA
700mV     31.4mA     19.11mA    41.71mA
1.2V      45.15mA    25.37mA    61.75mA
1.6V      50.35mA    26.5mA     71.06mA
3.1V      52.27mA    27.26mA    74.75mA
4.1V      55.69mA    32.97mA    75.8mA
4.7V      65.7mA     32.97mA    86.63mA
5.1V      65.7mA     32.97mA    96.89mA
6.3V      65.88mA    36.5mA     96.89mA
6.6V      70.93mA    39.71mA    98.5mA
[Pullup]
|Voltage   I(typ)   I(min)   I(max)
-3.3V     28.03mA    15.43mA    40.69mA
-700mV    28.03mA    15.43mA    40.69mA
-400mV    20.31mA    13.47mA    26.93mA
600mV     -25.77mA   -16.23mA   -35.13mA
1.6V      -50.64mA   -28.81mA   -70.96mA
2.3V      -56.49mA   -30.48mA   -81.16mA
3.5V      -59.53mA   -32.65mA   -85.92mA
4.2V      -61.43mA   -47.5mA    -87.46mA
4.5V      -69.06mA   -55mA      -88.38mA
5.4V      -98mA      -57.7mA    -119.3mA
5.7V      -98mA      -57.7mA    -131.1mA
6.6V      -98mA      -57.7mA    -131.1mA
[GND_clamp]
|Voltage   I(typ)   I(min)   I(max)
-3.3V     -4.64A     -4.799A    -4.587A
-1.2V     -535.6mA   -717.5mA   -459.3mA
-1.13V    -409.9mA   -591mA     -333.1mA
-1.06V    -288.9mA   -467.4mA   -212.9mA
-990mV    -176.2mA   -348mA     -105.7mA
-920mV    -81.01mA   -235.5mA   -32.97mA
-850mV    -23.67mA   -135.1mA   -12.28mA
-780mV    -7.764mA   -57.43mA   -7.776mA
-710mV    -4.197mA   -16.31mA   -4.777mA
-640mV    -2.307mA   -4.41mA    -2.453mA
-570mV    -1.059mA   -1.629mA   -967uA
3.28V     81.28uA    57.87uA    93.98uA
[POWER_clamp]
|Voltage   I(typ)   I(min)   I(max)
-3.28V    395.3uA    171.4uA    658.7uA
-2.56V    366.2uA    158.7uA    613.4uA
-1.68V    356.7uA    154.5uA    599.4uA
-1.64V    356.6uA    154.5uA    590.8uA
-1.52V    353.6uA    154.3uA    518.3uA
-1.48V    341.1uA    154.3uA    492.3uA
-1.28V    253.6uA    150.4uA    364.2uA
-960mV    123.1uA    77.62uA    181.6uA
-720mV    50.52uA    32.09uA    76.18uA
-560mV    18.94uA    12.32uA    28.65uA
-440mV    5.105uA    3.74uA     7.324uA
0V        0A         0A         0A
[Ramp]
| variable   typ   min   max
dV/dt_r  1.27680/19.15679n   0.81450/45.14316n   1.56648/10.21350n
dV/dt_f  1.30548/18.22268n   0.78468/37.03733n   1.58744/11.27292n
R_load = 50.000000
[Rising Waveform]
R_fixture= 50.000000
V_fixture= 3.300000
V_fixture_min= 2.700000
V_fixture_max= 3.600000
|time   V(typ)   V(min)   V(max)
0s        1.123V     1.39V      953.1mV
770.8ps   1.122V     1.391V     1.015V
820.8ps   1.121V     1.391V     1.168V
1.021ns   1.185V     1.39V      2.38V
1.131ns   1.533V     1.39V      2.794V
1.341ns   2.512V     1.387V     3.2V
1.592ns   2.976V     1.44V      3.422V
1.982ns   3.195V     2.305V     3.537V
2.312ns   3.249V     2.578V     3.572V
4.985ns   3.299V     2.699V     3.599V
[Rising Waveform]
R_fixture= 50.000000
V_fixture= 0.0
V_fixture_min= 0.0
V_fixture_max= 0.0
|time   V(typ)   V(min)   V(max)
0s        126.6nV    561.8nV    644.4nV
5.506ns   8.675mV    -134.8uV   146.7mV
11.01ns   175.4mV    3.657mV    992mV
20.02ns   788.6mV    50.22mV    2.245V
29.03ns   1.414V     169.7mV    2.526V
37.04ns   1.819V     316.7mV    2.581V
49.05ns   2.026V     565.4mV    2.605V
70.57ns   2.11V      968.1mV    2.611V
98.1ns    2.126V     1.234V     2.611V
249.2ns   2.128V     1.358V     2.611V
[Falling Waveform]
R_fixture= 50.000000
V_fixture= 3.300000
V_fixture_min= 2.700000
V_fixture_max= 3.600000
|time   V(typ)   V(min)   V(max)
0s        3.299V     2.699V     3.599V
6.006ns   3.296V     2.697V     3.55V
11.01ns   3.2V       2.697V     2.865V
17.02ns   2.783V     2.68V      1.957V
22.02ns   2.389V     2.625V     1.392V
31.53ns   1.703V     2.431V     1.066V
45.55ns   1.282V     2.076V     987.8mV
63.06ns   1.179V     1.714V     963.2mV
86.59ns   1.141V     1.523V     955.1mV
249.2ns   1.123V     1.39V      953.1mV
[Falling Waveform]
R_fixture= 50.000000
V_fixture= 0.0
V_fixture_min= 0.0
V_fixture_max= 0.0
|time   V(typ)   V(min)   V(max)
0s        2.128V     1.358V     2.611V
790.8ps   2.132V     1.357V     2.515V
971ps     2.111V     1.357V     2.072V
1.081ns   2.013V     1.357V     1.649V
1.351ns   1.442V     1.364V     779.1mV
1.632ns   767.2mV    1.326V     381.3mV
1.852ns   433.6mV    1.137V     222.4mV
2.452ns   106.1mV    443.9mV    48.66mV
2.903ns   36.95mV    160.4mV    17.12mV
4.985ns   126.6nV    561.8nV    644.4nV
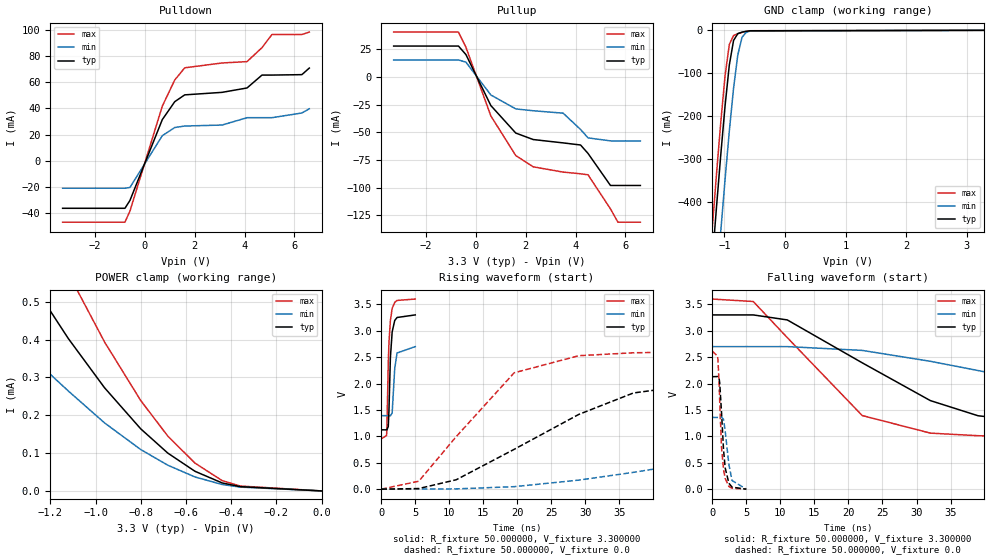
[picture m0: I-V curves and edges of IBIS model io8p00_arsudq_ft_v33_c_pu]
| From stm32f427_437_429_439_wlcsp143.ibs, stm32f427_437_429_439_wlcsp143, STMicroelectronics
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|   Model io8p00_arsudq_ft_v33_c_pu
[Model]  io8p00_arsudq_ft_v33_c_pu
Model_type I/O
Polarity   Non-Inverting
Enable   Active-Low
Vinl =   0.990000V
Vinh =   2.310000V
Vmeas =  1.650000V
Cref =   50.000000pF
Rref =   100.000000M
Vref =   0.0V
C_comp   5.986400pF   5.818600pF   6.191500pF
[Temperature Range]   25.000000   0.125000k   -40.000000
[Pullup Reference]   3.300000V   2.700000V   3.600000V
[Pulldown Reference]   0.0V   0.0V   0.0V
[POWER Clamp Reference]   3.300000V   2.700000V   3.600000V
[GND Clamp Reference]   0.0V   0.0V   0.0V
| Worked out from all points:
|   slope of the pulldown table from 0 to 0.495 V, typ, clamps not added: 20.9 ohm
|   slope of the pullup table from 0 to 0.495 V, typ, clamps not added: 22.6 ohm
|   GND clamp passes 1 mA (typ) near -0.57 V on its own axis
|   POWER clamp passes 1 mA (typ) near -1.88 V on its own axis
|   rising waveform, R_fixture 50.000000, V_fixture 3.300000: 20-80 % time 366ps typ, 350ps min, 387ps max; typ from 1.12 V to 3.3 V
|   rising waveform, R_fixture 50.000000, V_fixture 0.0: 20-80 % time 19.2ns typ, 45.2ns min, 10.2ns max; typ from 0.001 V to 2.13 V
|   falling waveform, R_fixture 50.000000, V_fixture 3.300000: 20-80 % time 18.3ns typ, 37ns min, 11.3ns max; typ from 3.3 V to 1.12 V
|   falling waveform, R_fixture 50.000000, V_fixture 0.0: 20-80 % time 608ps typ, 781ps min, 540ps max; typ from 2.13 V to 0.001 V
[Pulldown]
|Voltage   I(typ)   I(min)   I(max)
-3.3V     -36.46mA   -21.09mA   -47.09mA
-800mV    -36.46mA   -21.09mA   -47.09mA
-600mV    -30.5mA    -20.54mA   -38.69mA
700mV     31.4mA     19.11mA    41.71mA
1.2V      45.15mA    25.37mA    61.75mA
1.6V      50.35mA    26.5mA     71.06mA
3.1V      52.28mA    27.26mA    74.76mA
4.1V      55.64mA    32.89mA    75.8mA
4.7V      65.5mA     32.89mA    86.49mA
5.1V      65.5mA     32.89mA    96.54mA
6.3V      65.83mA    36.48mA    96.54mA
6.6V      70.88mA    39.69mA    98.4mA
[Pullup]
|Voltage   I(typ)   I(min)   I(max)
-3.3V     28.01mA    15.42mA    40.63mA
-700mV    28.01mA    15.42mA    40.63mA
-400mV    20.31mA    13.47mA    26.93mA
600mV     -25.77mA   -16.23mA   -35.13mA
1.6V      -50.64mA   -28.8mA    -70.96mA
2.3V      -56.49mA   -30.48mA   -81.16mA
3.5V      -59.52mA   -32.65mA   -85.91mA
4.2V      -61.43mA   -47.4mA    -87.45mA
4.5V      -69.06mA   -55mA      -88.37mA
5.4V      -98mA      -57.7mA    -119.2mA
5.7V      -98mA      -57.7mA    -131.2mA
6.6V      -98mA      -57.7mA    -131.2mA
[GND_clamp]
|Voltage   I(typ)   I(min)   I(max)
-3.3V     -4.64A     -4.799A    -4.588A
-1.2V     -535.6mA   -717.5mA   -459.3mA
-1.13V    -409.9mA   -591mA     -333.1mA
-1.06V    -288.9mA   -467.4mA   -212.9mA
-990mV    -176.2mA   -348mA     -105.7mA
-920mV    -81.01mA   -235.5mA   -32.96mA
-850mV    -23.66mA   -135.1mA   -12.27mA
-780mV    -7.753mA   -57.42mA   -7.762mA
-710mV    -4.185mA   -16.31mA   -4.763mA
-640mV    -2.295mA   -4.401mA   -2.439mA
-570mV    -1.048mA   -1.62mA    -953.6uA
3.28V     0A         0A         0A
[POWER_clamp]
|Voltage   I(typ)   I(min)   I(max)
-3.28V    1.181mA    571.7uA    1.791mA
-1.84V    973.5uA    557.9uA    1.433mA
-1.32V    587.4uA    369.9uA    827.8uA
-1.28V    548.8uA    352.3uA    775.2uA
-1.12V    402.4uA    263.9uA    574.4uA
-960mV    272.5uA    179.7uA    393.5uA
-800mV    164uA      109.3uA    238.7uA
-680mV    99.77uA    67.86uA    144.6uA
-560mV    51.85uA    36.88uA    73.46uA
-440mV    21.1uA     16.96uA    27.26uA
-360mV    11.28uA    10.1uA     12.92uA
0V        0A         0A         0A
[Ramp]
| variable   typ   min   max
dV/dt_r  1.27723/19.16041n   0.81507/45.16027n   1.56688/10.21650n
dV/dt_f  1.30506/18.21964n   0.78378/37.00905n   1.58715/11.27829n
R_load = 50.000000
[Rising Waveform]
R_fixture= 50.000000
V_fixture= 3.300000
V_fixture_min= 2.700000
V_fixture_max= 3.600000
|time   V(typ)   V(min)   V(max)
0s        1.125V     1.393V     954.7mV
770.8ps   1.124V     1.393V     1.017V
820.8ps   1.123V     1.393V     1.17V
1.021ns   1.187V     1.393V     2.383V
1.121ns   1.485V     1.392V     2.767V
1.331ns   2.482V     1.389V     3.189V
1.592ns   2.978V     1.443V     3.423V
1.972ns   3.195V     2.289V     3.537V
2.312ns   3.251V     2.579V     3.574V
4.985ns   3.3V       2.7V       3.6V
[Rising Waveform]
R_fixture= 50.000000
V_fixture= 0.0
V_fixture_min= 0.0
V_fixture_max= 0.0
|time   V(typ)   V(min)   V(max)
0s        1.089mV    1.044mV    1.137mV
5.506ns   12.74mV    2.785mV    151.5mV
11.01ns   179.3mV    6.541mV    996.4mV
19.52ns   755.1mV    48.35mV    2.204V
29.03ns   1.417V     172.5mV    2.528V
37.04ns   1.822V     319.4mV    2.583V
49.05ns   2.029V     568mV      2.606V
76.58ns   2.117V     1.052V     2.612V
100.6ns   2.128V     1.249V     2.613V
249.2ns   2.13V      1.36V      2.613V
[Falling Waveform]
R_fixture= 50.000000
V_fixture= 3.300000
V_fixture_min= 2.700000
V_fixture_max= 3.600000
|time   V(typ)   V(min)   V(max)
0s        3.3V       2.7V       3.6V
6.006ns   3.3V       2.7V       3.554V
11.01ns   3.205V     2.7V       2.87V
22.02ns   2.393V     2.628V     1.395V
32.03ns   1.678V     2.422V     1.062V
39.04ns   1.391V     2.247V     1.013V
48.05ns   1.26V      2.018V     984.1mV
65.07ns   1.175V     1.691V     963.7mV
88.09ns   1.141V     1.519V     956.6mV
249.2ns   1.125V     1.393V     954.7mV
[Falling Waveform]
R_fixture= 50.000000
V_fixture= 0.0
V_fixture_min= 0.0
V_fixture_max= 0.0
|time   V(typ)   V(min)   V(max)
0s        2.13V      1.36V      2.613V
790.8ps   2.133V     1.359V     2.517V
971ps     2.113V     1.359V     2.072V
1.081ns   2.015V     1.359V     1.649V
1.351ns   1.443V     1.366V     779.2mV
1.642ns   748.5mV    1.323V     372.6mV
1.882ns   403.6mV    1.104V     207.2mV
2.432ns   112.5mV    463.5mV    52.13mV
2.893ns   39.08mV    164.6mV    18.75mV
4.985ns   1.089mV    1.044mV    1.137mV
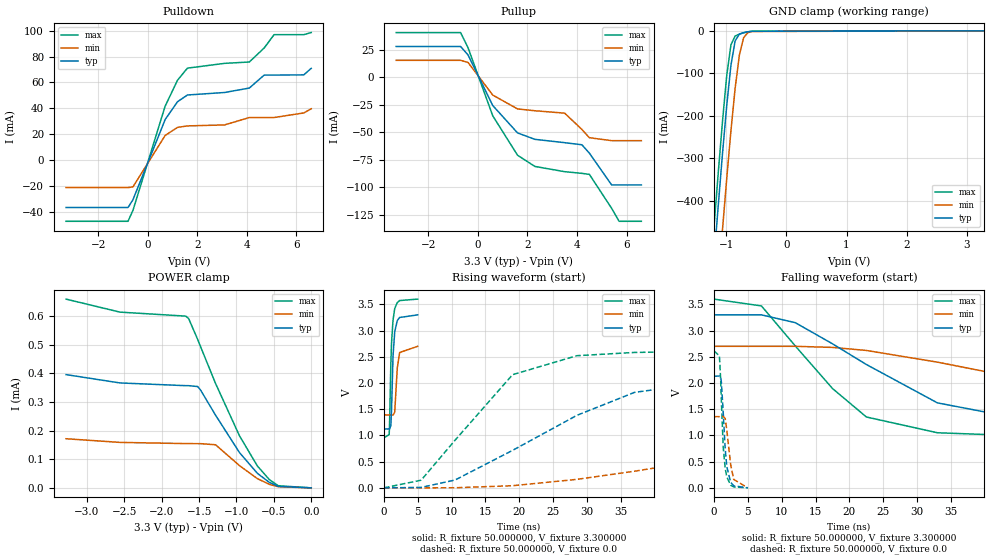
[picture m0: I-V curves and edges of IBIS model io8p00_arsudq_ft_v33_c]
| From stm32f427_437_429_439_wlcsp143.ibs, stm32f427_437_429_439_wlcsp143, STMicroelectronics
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|   Model io8p00_arsudq_ft_v33_c
[Model]  io8p00_arsudq_ft_v33_c
Model_type I/O
Polarity   Non-Inverting
Enable   Active-Low
Vinl =   0.990000V
Vinh =   2.310000V
Vmeas =  1.650000V
Cref =   50.000000pF
Rref =   100.000000M
Vref =   0.0V
C_comp   5.986400pF   5.818600pF   6.191500pF
[Temperature Range]   25.000000   0.125000k   -40.000000
[Pullup Reference]   3.300000V   2.700000V   3.600000V
[Pulldown Reference]   0.0V   0.0V   0.0V
[POWER Clamp Reference]   3.300000V   2.700000V   3.600000V
[GND Clamp Reference]   0.0V   0.0V   0.0V
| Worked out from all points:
|   slope of the pulldown table from 0 to 0.495 V, typ, clamps not added: 20.9 ohm
|   slope of the pullup table from 0 to 0.495 V, typ, clamps not added: 22.6 ohm
|   GND clamp passes 1 mA (typ) near -0.57 V on its own axis
|   rising waveform, R_fixture 50.000000, V_fixture 3.300000: 20-80 % time 368ps typ, 352ps min, 389ps max; typ from 1.12 V to 3.3 V
|   rising waveform, R_fixture 50.000000, V_fixture 0.0: 20-80 % time 19.2ns typ, 45.2ns min, 10.2ns max; typ from 0 V to 2.13 V
|   falling waveform, R_fixture 50.000000, V_fixture 3.300000: 20-80 % time 18.2ns typ, 37ns min, 11.3ns max; typ from 3.3 V to 1.12 V
|   falling waveform, R_fixture 50.000000, V_fixture 0.0: 20-80 % time 609ps typ, 781ps min, 542ps max; typ from 2.13 V to 0 V
[Pulldown]
|Voltage   I(typ)   I(min)   I(max)
-3.3V     -36.46mA   -21.09mA   -47.09mA
-800mV    -36.46mA   -21.09mA   -47.09mA
-600mV    -30.5mA    -20.54mA   -38.69mA
700mV     31.4mA     19.11mA    41.71mA
1.2V      45.15mA    25.37mA    61.75mA
1.6V      50.35mA    26.5mA     71.06mA
3.1V      52.28mA    27.26mA    74.75mA
4.1V      55.7mA     32.97mA    75.81mA
4.7V      65.71mA    32.97mA    86.64mA
5.1V      65.71mA    32.97mA    96.9mA
6.3V      65.88mA    36.51mA    96.9mA
6.6V      70.94mA    39.72mA    98.51mA
[Pullup]
|Voltage   I(typ)   I(min)   I(max)
-3.3V     28.03mA    15.43mA    40.69mA
-700mV    28.03mA    15.43mA    40.69mA
-400mV    20.31mA    13.47mA    26.93mA
600mV     -25.77mA   -16.23mA   -35.14mA
1.6V      -50.64mA   -28.81mA   -70.96mA
2.3V      -56.49mA   -30.48mA   -81.16mA
3.5V      -59.53mA   -32.65mA   -85.92mA
4.2V      -61.44mA   -47.5mA    -87.46mA
4.5V      -69.06mA   -55mA      -88.38mA
5.4V      -98mA      -57.7mA    -119.3mA
5.7V      -98mA      -57.7mA    -131.1mA
6.6V      -98mA      -57.7mA    -131.1mA
[GND_clamp]
|Voltage   I(typ)   I(min)   I(max)
-3.3V     -4.64A     -4.799A    -4.588A
-1.2V     -535.6mA   -717.5mA   -459.3mA
-1.13V    -409.9mA   -591mA     -333.1mA
-1.06V    -288.9mA   -467.4mA   -212.9mA
-990mV    -176.2mA   -348mA     -105.7mA
-920mV    -81.01mA   -235.5mA   -32.96mA
-850mV    -23.66mA   -135.1mA   -12.27mA
-780mV    -7.753mA   -57.42mA   -7.762mA
-710mV    -4.185mA   -16.31mA   -4.763mA
-640mV    -2.295mA   -4.401mA   -2.439mA
-570mV    -1.048mA   -1.62mA    -953.6uA
3.28V     0A         0A         0A
[POWER_clamp]
|Voltage   I(typ)   I(min)   I(max)
-3.28V    395.3uA    171.4uA    658.7uA
-2.56V    366.2uA    158.7uA    613.4uA
-1.68V    356.7uA    154.5uA    599.4uA
-1.64V    356.6uA    154.5uA    590.8uA
-1.52V    353.6uA    154.3uA    518.3uA
-1.48V    341.1uA    154.3uA    492.3uA
-1.28V    253.6uA    150.4uA    364.2uA
-960mV    123.1uA    77.62uA    181.6uA
-720mV    50.52uA    32.09uA    76.18uA
-560mV    18.94uA    12.32uA    28.65uA
-440mV    5.105uA    3.74uA     7.324uA
0V        0A         0A         0A
[Ramp]
| variable   typ   min   max
dV/dt_r  1.27752/19.14624n   0.81516/45.13241n   1.56726/10.20642n
dV/dt_f  1.30584/18.20926n   0.78456/37.01375n   1.58791/11.27013n
R_load = 50.000000
[Rising Waveform]
R_fixture= 50.000000
V_fixture= 3.300000
V_fixture_min= 2.700000
V_fixture_max= 3.600000
|time   V(typ)   V(min)   V(max)
0s        1.124V     1.392V     953.5mV
770.8ps   1.123V     1.392V     1.015V
820.8ps   1.122V     1.392V     1.168V
1.021ns   1.186V     1.392V     2.379V
1.121ns   1.483V     1.391V     2.763V
1.341ns   2.512V     1.388V     3.198V
1.592ns   2.975V     1.442V     3.42V
1.972ns   3.192V     2.287V     3.534V
2.322ns   3.25V      2.582V     3.573V
4.985ns   3.3V       2.7V       3.6V
[Rising Waveform]
R_fixture= 50.000000
V_fixture= 0.0
V_fixture_min= 0.0
V_fixture_max= 0.0
|time   V(typ)   V(min)   V(max)
0s        126.7nV    566.4nV    644.5nV
5.506ns   8.676mV    -136.4uV   146.7mV
10.51ns   149.2mV    2.032mV    908mV
19.02ns   714.9mV    40.85mV    2.159V
28.53ns   1.383V     161.8mV    2.521V
37.04ns   1.821V     317mV      2.583V
48.55ns   2.023V     555.1mV    2.606V
70.57ns   2.111V     968.9mV    2.612V
98.1ns    2.127V     1.235V     2.612V
249.2ns   2.129V     1.359V     2.612V
[Falling Waveform]
R_fixture= 50.000000
V_fixture= 3.300000
V_fixture_min= 2.700000
V_fixture_max= 3.600000
|time   V(typ)   V(min)   V(max)
0s        3.3V       2.7V       3.6V
7.007ns   3.3V       2.7V       3.47V
12.01ns   3.151V     2.7V       2.707V
17.52ns   2.747V     2.679V     1.894V
22.52ns   2.353V     2.621V     1.352V
33.03ns   1.621V     2.398V     1.051V
47.55ns   1.263V     2.029V     983.1mV
63.56ns   1.178V     1.709V     963.3mV
87.59ns   1.141V     1.52V      955.4mV
249.2ns   1.124V     1.392V     953.5mV
[Falling Waveform]
R_fixture= 50.000000
V_fixture= 0.0
V_fixture_min= 0.0
V_fixture_max= 0.0
|time   V(typ)   V(min)   V(max)
0s        2.129V     1.359V     2.612V
790.8ps   2.133V     1.358V     2.517V
971ps     2.112V     1.358V     2.073V
1.081ns   2.014V     1.359V     1.652V
1.351ns   1.444V     1.365V     781.7mV
1.642ns   749.3mV    1.322V     374.7mV
1.882ns   404.5mV    1.104V     208.9mV
2.452ns   107.6mV    444.9mV    50.08mV
2.903ns   37.99mV    161.1mV    18.47mV
4.985ns   126.7nV    566.4nV    644.5nV
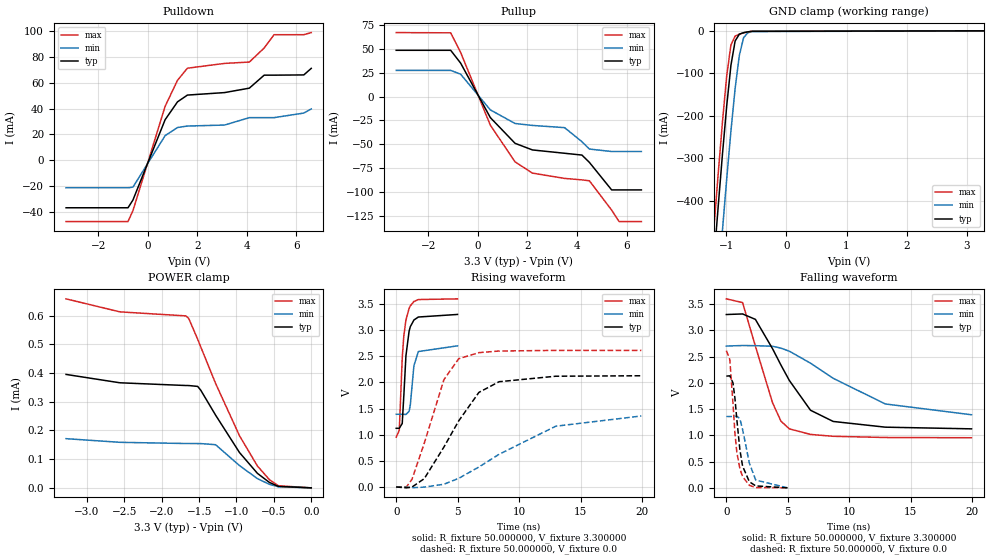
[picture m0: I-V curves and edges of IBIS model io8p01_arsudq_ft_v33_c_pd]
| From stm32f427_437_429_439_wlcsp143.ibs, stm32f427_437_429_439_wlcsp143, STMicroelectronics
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|   Model io8p01_arsudq_ft_v33_c_pd
[Model]  io8p01_arsudq_ft_v33_c_pd
Model_type I/O
Polarity   Non-Inverting
Enable   Active-Low
Vinl =   0.990000V
Vinh =   2.310000V
Vmeas =  1.650000V
Cref =   50.000000pF
Rref =   100.000000M
Vref =   0.0V
C_comp   5.986400pF   5.818600pF   6.191500pF
[Temperature Range]   25.000000   0.125000k   -40.000000
[Pullup Reference]   3.300000V   2.700000V   3.600000V
[Pulldown Reference]   0.0V   0.0V   0.0V
[POWER Clamp Reference]   3.300000V   2.700000V   3.600000V
[GND Clamp Reference]   0.0V   0.0V   0.0V
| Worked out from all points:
|   slope of the pulldown table from 0 to 0.495 V, typ, clamps not added: 20.9 ohm
|   slope of the pullup table from 0 to 0.495 V, typ, clamps not added: 22.6 ohm
|   GND clamp passes 1 mA (typ) near -0.56 V on its own axis
|   rising waveform, R_fixture 50.000000, V_fixture 3.300000: 20-80 % time 370ps typ, 352ps min, 391ps max; typ from 1.12 V to 3.3 V
|   rising waveform, R_fixture 50.000000, V_fixture 0.0: 20-80 % time 3.26ns typ, 6.15ns min, 2.07ns max; typ from 0 V to 2.13 V
|   falling waveform, R_fixture 50.000000, V_fixture 3.300000: 20-80 % time 3.24ns typ, 5.74ns min, 2.03ns max; typ from 3.3 V to 1.12 V
|   falling waveform, R_fixture 50.000000, V_fixture 0.0: 20-80 % time 610ps typ, 783ps min, 542ps max; typ from 2.13 V to 0 V
[Pulldown]
|Voltage   I(typ)   I(min)   I(max)
-3.3V     -36.46mA   -21.09mA   -47.09mA
-800mV    -36.46mA   -21.09mA   -47.09mA
-600mV    -30.5mA    -20.54mA   -38.69mA
700mV     31.4mA     19.11mA    41.71mA
1.2V      45.15mA    25.37mA    61.75mA
1.6V      50.35mA    26.5mA     71.06mA
3.1V      52.27mA    27.26mA    74.75mA
4.1V      55.69mA    32.97mA    75.8mA
4.7V      65.7mA     32.97mA    86.63mA
5.1V      65.7mA     32.97mA    96.89mA
6.3V      65.88mA    36.5mA     96.89mA
6.6V      70.93mA    39.71mA    98.5mA
[Pullup]
|Voltage   I(typ)   I(min)   I(max)
-3.3V     48.51mA    27.42mA    67.11mA
-1.1V     48.51mA    27.42mA    66.85mA
-700mV    35.13mA    23.47mA    46.35mA
500mV     -22.07mA   -14mA      -30.03mA
1.5V      -49.1mA    -28.3mA    -68.56mA
2.2V      -56.04mA   -30.32mA   -80.35mA
3.5V      -59.53mA   -32.65mA   -85.92mA
4.2V      -61.43mA   -47.4mA    -87.46mA
4.5V      -69.06mA   -55.1mA    -88.38mA
5.4V      -98mA      -57.7mA    -119.2mA
5.7V      -98mA      -57.7mA    -131.2mA
6.6V      -98mA      -57.7mA    -131.2mA
[GND_clamp]
|Voltage   I(typ)   I(min)   I(max)
-3.3V     -4.64A     -4.798A    -4.587A
-1.2V     -535.6mA   -717.5mA   -459.3mA
-1.13V    -409.9mA   -591mA     -333.1mA
-1.06V    -288.9mA   -467.4mA   -212.9mA
-990mV    -176.2mA   -348mA     -105.7mA
-920mV    -81.01mA   -235.5mA   -32.97mA
-850mV    -23.67mA   -135.1mA   -12.28mA
-780mV    -7.764mA   -57.43mA   -7.776mA
-710mV    -4.197mA   -16.31mA   -4.777mA
-640mV    -2.307mA   -4.41mA    -2.453mA
-570mV    -1.059mA   -1.629mA   -967uA
3.28V     81.28uA    57.87uA    93.98uA
[POWER_clamp]
|Voltage   I(typ)   I(min)   I(max)
-3.28V    395.3uA    171.4uA    658.7uA
-2.56V    366.2uA    158.7uA    613.4uA
-1.68V    356.7uA    154.5uA    599.4uA
-1.64V    356.6uA    154.5uA    590.8uA
-1.52V    353.6uA    154.3uA    518.3uA
-1.48V    341.1uA    154.3uA    492.3uA
-1.28V    253.6uA    150.4uA    364.2uA
-960mV    123.1uA    77.62uA    181.6uA
-720mV    50.52uA    32.09uA    76.18uA
-560mV    18.94uA    12.32uA    28.65uA
-440mV    5.105uA    3.74uA     7.324uA
0V        0A         0A         0A
[Ramp]
| variable   typ   min   max
dV/dt_r  1.27668/3.25939n   0.79866/6.12690n   1.56648/2.07069n
dV/dt_f  1.30200/3.23004n   0.74178/5.66304n   1.58724/2.03202n
R_load = 50.000000
[Rising Waveform]
R_fixture= 50.000000
V_fixture= 3.300000
V_fixture_min= 2.700000
V_fixture_max= 3.600000
|time   V(typ)   V(min)   V(max)
0s        1.123V     1.391V     953.6mV
250.2ps   1.122V     1.391V     1.084V
490.5ps   1.215V     1.39V      2.466V
620.6ps   1.75V      1.389V     2.892V
790.8ps   2.509V     1.387V     3.192V
1.051ns   2.982V     1.448V     3.418V
1.151ns   3.067V     1.578V     3.464V
1.441ns   3.193V     2.32V      3.547V
1.802ns   3.25V      2.59V      3.584V
4.985ns   3.299V     2.699V     3.597V
[Rising Waveform]
R_fixture= 50.000000
V_fixture= 0.0
V_fixture_min= 0.0
V_fixture_max= 0.0
|time   V(typ)   V(min)   V(max)
0s        225.9uV    79.13uV    1.229mV
840.8ps   -15.98mV   -547.4uV   5.669mV
1.281ns   -1.136mV   -14mV      146.2mV
2.282ns   159.6mV    -1.901mV   837.3mV
3.884ns   765.6mV    53mV       2.055V
5.085ns   1.265V     165.6mV    2.453V
6.727ns   1.809V     383.3mV    2.569V
8.368ns   2.013V     625.3mV    2.6V
12.97ns   2.118V     1.162V     2.612V
19.94ns   2.127V     1.358V     2.612V
[Falling Waveform]
R_fixture= 50.000000
V_fixture= 3.300000
V_fixture_min= 2.700000
V_fixture_max= 3.600000
|time   V(typ)   V(min)   V(max)
0s        3.299V     2.699V     3.597V
1.321ns   3.31V      2.709V     3.526V
2.362ns   3.207V     2.706V     2.699V
3.764ns   2.646V     2.695V     1.616V
4.444ns   2.336V     2.659V     1.269V
5.125ns   2.044V     2.601V     1.123V
6.847ns   1.477V     2.373V     1.017V
8.689ns   1.264V     2.085V     981.2mV
12.93ns   1.155V     1.597V     958.4mV
19.94ns   1.123V     1.391V     953.6mV
[Falling Waveform]
R_fixture= 50.000000
V_fixture= 0.0
V_fixture_min= 0.0
V_fixture_max= 0.0
|time   V(typ)   V(min)   V(max)
0s        2.127V     1.358V     2.612V
280.3ps   2.132V     1.357V     2.445V
540.5ps   1.999V     1.358V     1.609V
700.7ps   1.702V     1.36V      1.037V
850.9ps   1.308V     1.365V     682.9mV
1.101ns   728.3mV    1.314V     366.3mV
1.321ns   414mV      1.113V     215.4mV
1.872ns   116.6mV    471.5mV    47.44mV
2.392ns   36.69mV    147.8mV    5.564mV
4.985ns   225.9uV    79.13uV    1.229mV
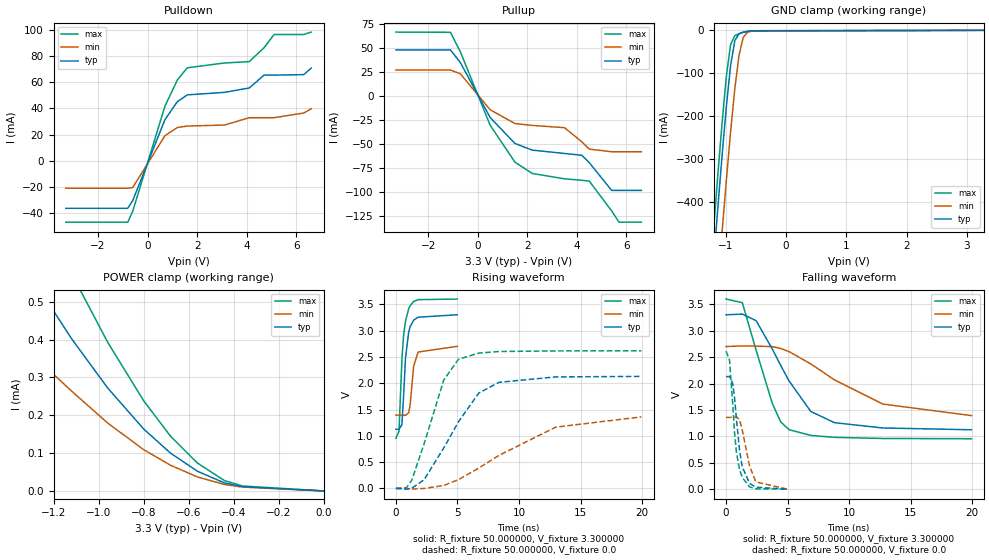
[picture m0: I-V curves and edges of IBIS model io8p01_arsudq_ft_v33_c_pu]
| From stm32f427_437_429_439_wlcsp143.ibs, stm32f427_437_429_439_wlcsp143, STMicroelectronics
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|   Model io8p01_arsudq_ft_v33_c_pu
[Model]  io8p01_arsudq_ft_v33_c_pu
Model_type I/O
Polarity   Non-Inverting
Enable   Active-Low
Vinl =   0.990000V
Vinh =   2.310000V
Vmeas =  1.650000V
Cref =   50.000000pF
Rref =   100.000000M
Vref =   0.0V
C_comp   5.986400pF   5.818600pF   6.191500pF
[Temperature Range]   25.000000   0.125000k   -40.000000
[Pullup Reference]   3.300000V   2.700000V   3.600000V
[Pulldown Reference]   0.0V   0.0V   0.0V
[POWER Clamp Reference]   3.300000V   2.700000V   3.600000V
[GND Clamp Reference]   0.0V   0.0V   0.0V
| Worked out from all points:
|   slope of the pulldown table from 0 to 0.495 V, typ, clamps not added: 20.9 ohm
|   slope of the pullup table from 0 to 0.495 V, typ, clamps not added: 22.6 ohm
|   GND clamp passes 1 mA (typ) near -0.57 V on its own axis
|   POWER clamp passes 1 mA (typ) near -1.88 V on its own axis
|   rising waveform, R_fixture 50.000000, V_fixture 3.300000: 20-80 % time 368ps typ, 351ps min, 389ps max; typ from 1.12 V to 3.3 V
|   rising waveform, R_fixture 50.000000, V_fixture 0.0: 20-80 % time 3.27ns typ, 6.16ns min, 2.08ns max; typ from 0.001 V to 2.13 V
|   falling waveform, R_fixture 50.000000, V_fixture 3.300000: 20-80 % time 3.23ns typ, 5.75ns min, 2.03ns max; typ from 3.3 V to 1.12 V
|   falling waveform, R_fixture 50.000000, V_fixture 0.0: 20-80 % time 611ps typ, 786ps min, 544ps max; typ from 2.13 V to 0.001 V
[Pulldown]
|Voltage   I(typ)   I(min)   I(max)
-3.3V     -36.46mA   -21.09mA   -47.09mA
-800mV    -36.46mA   -21.09mA   -47.09mA
-600mV    -30.5mA    -20.54mA   -38.69mA
700mV     31.4mA     19.11mA    41.71mA
1.2V      45.15mA    25.37mA    61.75mA
1.6V      50.35mA    26.5mA     71.06mA
3.1V      52.28mA    27.26mA    74.76mA
4.1V      55.64mA    32.89mA    75.8mA
4.7V      65.5mA     32.89mA    86.49mA
5.1V      65.5mA     32.89mA    96.54mA
6.3V      65.83mA    36.48mA    96.54mA
6.6V      70.88mA    39.69mA    98.4mA
[Pullup]
|Voltage   I(typ)   I(min)   I(max)
-3.3V     48.39mA    27.38mA    66.91mA
-1.1V     48.39mA    27.38mA    66.69mA
-700mV    35.09mA    23.45mA    46.29mA
500mV     -22.06mA   -14mA      -30.03mA
1.5V      -49.1mA    -28.3mA    -68.56mA
2.2V      -56.04mA   -30.32mA   -80.35mA
3.5V      -59.52mA   -32.65mA   -85.91mA
4.2V      -61.43mA   -47.4mA    -87.45mA
4.5V      -69.06mA   -55mA      -88.37mA
5.4V      -98mA      -57.7mA    -119.3mA
5.7V      -98mA      -57.7mA    -131.1mA
6.6V      -98mA      -57.7mA    -131.1mA
[GND_clamp]
|Voltage   I(typ)   I(min)   I(max)
-3.3V     -4.64A     -4.799A    -4.587A
-1.2V     -535.6mA   -717.5mA   -459.3mA
-1.13V    -409.9mA   -591mA     -333.1mA
-1.06V    -288.9mA   -467.4mA   -212.9mA
-990mV    -176.2mA   -348mA     -105.7mA
-920mV    -81.01mA   -235.5mA   -32.96mA
-850mV    -23.66mA   -135.1mA   -12.27mA
-780mV    -7.753mA   -57.42mA   -7.762mA
-710mV    -4.185mA   -16.31mA   -4.763mA
-640mV    -2.295mA   -4.401mA   -2.439mA
-570mV    -1.048mA   -1.62mA    -953.6uA
3.28V     0A         0A         0A
[POWER_clamp]
|Voltage   I(typ)   I(min)   I(max)
-3.28V    1.181mA    571.7uA    1.791mA
-1.84V    973.5uA    557.9uA    1.433mA
-1.32V    587.4uA    369.9uA    827.8uA
-1.28V    548.8uA    352.3uA    775.2uA
-1.12V    402.4uA    263.9uA    574.4uA
-960mV    272.5uA    179.7uA    393.5uA
-800mV    164uA      109.3uA    238.7uA
-680mV    99.77uA    67.86uA    144.6uA
-560mV    51.85uA    36.88uA    73.46uA
-440mV    21.1uA     16.96uA    27.26uA
-360mV    11.28uA    10.1uA     12.92uA
0V        0A         0A         0A
[Ramp]
| variable   typ   min   max
dV/dt_r  1.27711/3.26324n   0.79929/6.13405n   1.56682/2.07303n
dV/dt_f  1.30158/3.22969n   0.74082/5.68458n   1.58695/2.03162n
R_load = 50.000000
[Rising Waveform]
R_fixture= 50.000000
V_fixture= 3.300000
V_fixture_min= 2.700000
V_fixture_max= 3.600000
|time   V(typ)   V(min)   V(max)
0s        1.125V     1.393V     955.2mV
250.2ps   1.123V     1.393V     1.086V
490.5ps   1.217V     1.393V     2.472V
620.6ps   1.753V     1.392V     2.897V
780.8ps   2.482V     1.389V     3.184V
1.041ns   2.976V     1.443V     3.418V
1.151ns   3.071V     1.581V     3.469V
1.441ns   3.197V     2.322V     3.552V
1.802ns   3.253V     2.592V     3.587V
4.985ns   3.3V       2.7V       3.598V
[Rising Waveform]
R_fixture= 50.000000
V_fixture= 0.0
V_fixture_min= 0.0
V_fixture_max= 0.0
|time   V(typ)   V(min)   V(max)
0s        1.314mV    1.122mV    2.363mV
840.8ps   -13.26mV   496.4uV    10.25mV
1.281ns   2.562mV    -12.6mV    151.7mV
2.282ns   164mV      942.6uV    842.5mV
3.884ns   769.4mV    56.13mV    2.059V
5.085ns   1.268V     168.8mV    2.455V
6.727ns   1.812V     386.3mV    2.571V
8.368ns   2.016V     628mV      2.602V
12.97ns   2.119V     1.164V     2.613V
19.94ns   2.129V     1.36V      2.614V
[Falling Waveform]
R_fixture= 50.000000
V_fixture= 3.300000
V_fixture_min= 2.700000
V_fixture_max= 3.600000
|time   V(typ)   V(min)   V(max)
0s        3.3V       2.7V       3.598V
1.321ns   3.314V     2.711V     3.53V
2.442ns   3.19V      2.708V     2.631V
3.764ns   2.65V      2.698V     1.62V
4.444ns   2.34V      2.662V     1.272V
5.125ns   2.047V     2.603V     1.126V
6.887ns   1.471V     2.37V      1.018V
8.809ns   1.259V     2.069V     981.7mV
12.73ns   1.159V     1.612V     960.4mV
19.94ns   1.125V     1.393V     955.2mV
[Falling Waveform]
R_fixture= 50.000000
V_fixture= 0.0
V_fixture_min= 0.0
V_fixture_max= 0.0
|time   V(typ)   V(min)   V(max)
0s        2.129V     1.36V      2.614V
280.3ps   2.134V     1.359V     2.447V
540.5ps   2.001V     1.36V      1.611V
690.7ps   1.728V     1.362V     1.07V
850.9ps   1.31V      1.367V     686mV
1.091ns   750.1mV    1.322V     379mV
1.311ns   427.3mV    1.126V     225mV
1.912ns   109.9mV    436.6mV    43.92mV
2.422ns   38.23mV    138.9mV    7.016mV
4.985ns   1.314mV    1.122mV    2.363mV
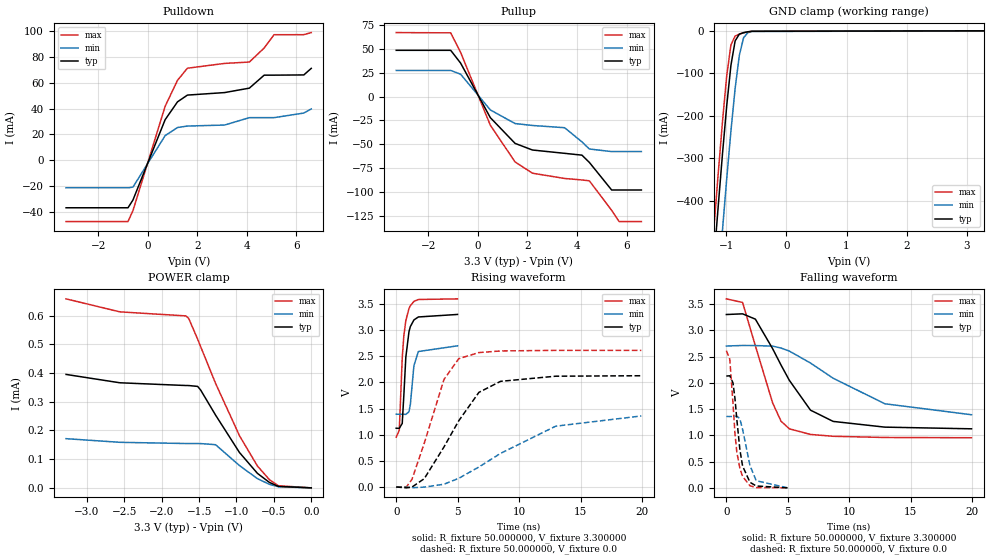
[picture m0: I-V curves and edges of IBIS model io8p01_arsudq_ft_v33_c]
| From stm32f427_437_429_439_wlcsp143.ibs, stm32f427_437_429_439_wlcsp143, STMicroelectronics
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|   Model io8p01_arsudq_ft_v33_c
[Model]  io8p01_arsudq_ft_v33_c
Model_type I/O
Polarity   Non-Inverting
Enable   Active-Low
Vinl =   0.990000V
Vinh =   2.310000V
Vmeas =  1.650000V
Cref =   50.000000pF
Rref =   100.000000M
Vref =   0.0V
C_comp   5.986400pF   5.818600pF   6.191500pF
[Temperature Range]   25.000000   0.125000k   -40.000000
[Pullup Reference]   3.300000V   2.700000V   3.600000V
[Pulldown Reference]   0.0V   0.0V   0.0V
[POWER Clamp Reference]   3.300000V   2.700000V   3.600000V
[GND Clamp Reference]   0.0V   0.0V   0.0V
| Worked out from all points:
|   slope of the pulldown table from 0 to 0.495 V, typ, clamps not added: 20.9 ohm
|   slope of the pullup table from 0 to 0.495 V, typ, clamps not added: 22.6 ohm
|   GND clamp passes 1 mA (typ) near -0.57 V on its own axis
|   rising waveform, R_fixture 50.000000, V_fixture 3.300000: 20-80 % time 369ps typ, 352ps min, 391ps max; typ from 1.12 V to 3.3 V
|   rising waveform, R_fixture 50.000000, V_fixture 0.0: 20-80 % time 3.26ns typ, 6.15ns min, 2.07ns max; typ from 0 V to 2.13 V
|   falling waveform, R_fixture 50.000000, V_fixture 3.300000: 20-80 % time 3.24ns typ, 5.73ns min, 2.03ns max; typ from 3.3 V to 1.12 V
|   falling waveform, R_fixture 50.000000, V_fixture 0.0: 20-80 % time 611ps typ, 786ps min, 543ps max; typ from 2.13 V to 0 V
[Pulldown]
|Voltage   I(typ)   I(min)   I(max)
-3.3V     -36.46mA   -21.09mA   -47.09mA
-800mV    -36.46mA   -21.09mA   -47.09mA
-600mV    -30.5mA    -20.54mA   -38.69mA
700mV     31.4mA     19.11mA    41.71mA
1.2V      45.15mA    25.37mA    61.75mA
1.6V      50.35mA    26.5mA     71.06mA
3.1V      52.28mA    27.26mA    74.75mA
4.1V      55.7mA     32.97mA    75.81mA
4.7V      65.71mA    32.97mA    86.64mA
5.1V      65.71mA    32.97mA    96.9mA
6.3V      65.88mA    36.51mA    96.9mA
6.6V      70.94mA    39.72mA    98.51mA
[Pullup]
|Voltage   I(typ)   I(min)   I(max)
-3.3V     48.51mA    27.42mA    67.12mA
-1.1V     48.51mA    27.42mA    66.85mA
-700mV    35.13mA    23.47mA    46.35mA
500mV     -22.07mA   -14mA      -30.03mA
1.5V      -49.1mA    -28.3mA    -68.56mA
2.2V      -56.05mA   -30.32mA   -80.35mA
3.5V      -59.53mA   -32.65mA   -85.92mA
4.2V      -61.44mA   -47.5mA    -87.46mA
4.5V      -69.06mA   -55mA      -88.38mA
5.4V      -98mA      -57.7mA    -119.3mA
5.7V      -98mA      -57.7mA    -131.1mA
6.6V      -98mA      -57.7mA    -131.1mA
[GND_clamp]
|Voltage   I(typ)   I(min)   I(max)
-3.3V     -4.64A     -4.799A    -4.587A
-1.2V     -535.6mA   -717.5mA   -459.3mA
-1.13V    -409.9mA   -591mA     -333.1mA
-1.06V    -288.9mA   -467.4mA   -212.9mA
-990mV    -176.2mA   -348mA     -105.7mA
-920mV    -81.01mA   -235.5mA   -32.96mA
-850mV    -23.66mA   -135.1mA   -12.27mA
-780mV    -7.753mA   -57.42mA   -7.762mA
-710mV    -4.185mA   -16.31mA   -4.763mA
-640mV    -2.295mA   -4.401mA   -2.439mA
-570mV    -1.048mA   -1.62mA    -953.6uA
3.28V     0A         0A         0A
[POWER_clamp]
|Voltage   I(typ)   I(min)   I(max)
-3.28V    395.3uA    171.4uA    658.7uA
-2.56V    366.2uA    158.7uA    613.4uA
-1.68V    356.7uA    154.5uA    599.4uA
-1.64V    356.6uA    154.5uA    590.8uA
-1.52V    353.6uA    154.3uA    518.3uA
-1.48V    341.1uA    154.3uA    492.3uA
-1.28V    253.6uA    150.4uA    364.2uA
-960mV    123.1uA    77.62uA    181.6uA
-720mV    50.52uA    32.09uA    76.18uA
-560mV    18.94uA    12.32uA    28.65uA
-440mV    5.105uA    3.74uA     7.324uA
0V        0A         0A         0A
[Ramp]
| variable   typ   min   max
dV/dt_r  1.27740/3.25943n   0.79926/6.12702n   1.56726/2.07062n
dV/dt_f  1.30236/3.22917n   0.74154/5.66541n   1.58771/2.03112n
R_load = 50.000000
[Rising Waveform]
R_fixture= 50.000000
V_fixture= 3.300000
V_fixture_min= 2.700000
V_fixture_max= 3.600000
|time   V(typ)   V(min)   V(max)
0s        1.124V     1.392V     954mV
250.2ps   1.122V     1.392V     1.084V
490.5ps   1.216V     1.392V     2.467V
620.6ps   1.751V     1.391V     2.893V
780.8ps   2.479V     1.388V     3.18V
1.041ns   2.973V     1.441V     3.415V
1.151ns   3.068V     1.579V     3.466V
1.441ns   3.195V     2.321V     3.549V
1.802ns   3.252V     2.591V     3.586V
4.985ns   3.3V       2.7V       3.598V
[Rising Waveform]
R_fixture= 50.000000
V_fixture= 0.0
V_fixture_min= 0.0
V_fixture_max= 0.0
|time   V(typ)   V(min)   V(max)
0s        225.7uV    78.87uV    1.229mV
840.8ps   -15.98mV   -547.4uV   5.657mV
1.281ns   -1.142mV   -14.01mV   146.2mV
2.282ns   159.6mV    -1.906mV   837.4mV
3.884ns   765.7mV    53.01mV    2.056V
5.085ns   1.266V     165.7mV    2.454V
6.727ns   1.81V      383.4mV    2.571V
8.488ns   2.021V     643.3mV    2.602V
12.97ns   2.119V     1.163V     2.613V
19.94ns   2.128V     1.359V     2.613V
[Falling Waveform]
R_fixture= 50.000000
V_fixture= 3.300000
V_fixture_min= 2.700000
V_fixture_max= 3.600000
|time   V(typ)   V(min)   V(max)
0s        3.3V       2.7V       3.598V
1.321ns   3.313V     2.711V     3.53V
2.362ns   3.212V     2.709V     2.704V
3.764ns   2.65V      2.698V     1.619V
4.444ns   2.34V      2.662V     1.271V
5.125ns   2.047V     2.604V     1.124V
6.847ns   1.479V     2.376V     1.017V
8.689ns   1.265V     2.087V     981.7mV
12.89ns   1.156V     1.601V     958.9mV
19.94ns   1.124V     1.392V     954mV
[Falling Waveform]
R_fixture= 50.000000
V_fixture= 0.0
V_fixture_min= 0.0
V_fixture_max= 0.0
|time   V(typ)   V(min)   V(max)
0s        2.128V     1.359V     2.613V
280.3ps   2.134V     1.358V     2.447V
540.5ps   2V         1.359V     1.612V
700.7ps   1.704V     1.361V     1.04V
850.9ps   1.31V      1.366V     685.7mV
1.101ns   730.4mV    1.315V     369.2mV
1.321ns   416.1mV    1.114V     218.2mV
1.922ns   105.9mV    426.9mV    39.97mV
2.432ns   35.3mV     135.4mV    5.435mV
4.985ns   225.7uV    78.87uV    1.229mV
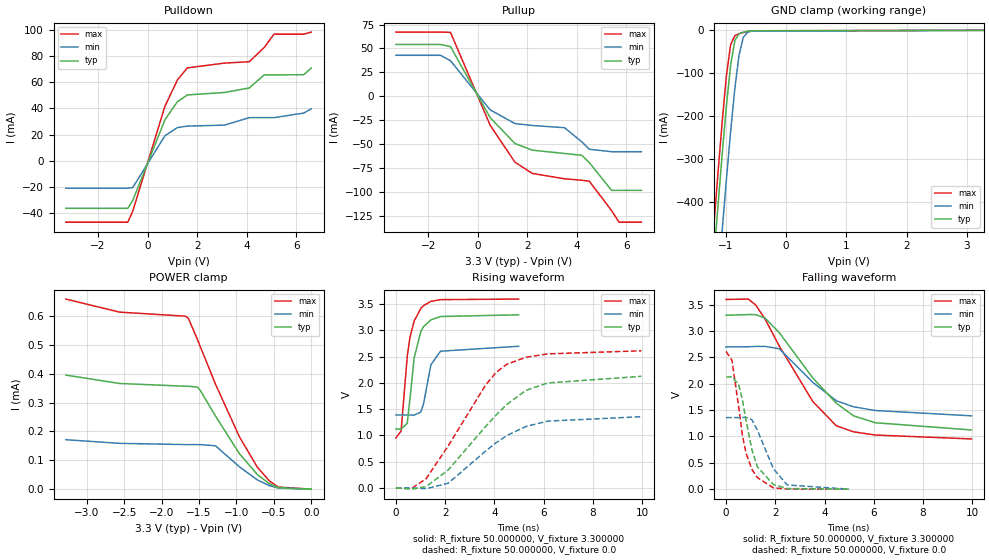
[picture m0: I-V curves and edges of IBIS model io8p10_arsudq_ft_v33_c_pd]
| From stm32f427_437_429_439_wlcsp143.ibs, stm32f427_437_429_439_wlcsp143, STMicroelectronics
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|   Model io8p10_arsudq_ft_v33_c_pd
[Model]  io8p10_arsudq_ft_v33_c_pd
Model_type I/O
Polarity   Non-Inverting
Enable   Active-Low
Vinl =   0.990000V
Vinh =   2.310000V
Vmeas =  1.650000V
Cref =   40.000000pF
Rref =   100.000000M
Vref =   0.0V
C_comp   5.986400pF   5.818600pF   6.191500pF
[Temperature Range]   25.000000   0.125000k   -40.000000
[Pullup Reference]   3.300000V   2.700000V   3.600000V
[Pulldown Reference]   0.0V   0.0V   0.0V
[POWER Clamp Reference]   3.300000V   2.700000V   3.600000V
[GND Clamp Reference]   0.0V   0.0V   0.0V
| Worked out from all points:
|   slope of the pulldown table from 0 to 0.495 V, typ, clamps not added: 20.9 ohm
|   slope of the pullup table from 0 to 0.495 V, typ, clamps not added: 22.6 ohm
|   GND clamp passes 1 mA (typ) near -0.56 V on its own axis
|   rising waveform, R_fixture 50.000000, V_fixture 3.300000: 20-80 % time 370ps typ, 357ps min, 391ps max; typ from 1.12 V to 3.3 V
|   rising waveform, R_fixture 50.000000, V_fixture 0.0: 20-80 % time 2.49ns typ, 2.21ns min, 2.1ns max; typ from 0 V to 2.13 V
|   falling waveform, R_fixture 50.000000, V_fixture 3.300000: 20-80 % time 2.31ns typ, 1.88ns min, 2.05ns max; typ from 3.3 V to 1.12 V
|   falling waveform, R_fixture 50.000000, V_fixture 0.0: 20-80 % time 610ps typ, 774ps min, 542ps max; typ from 2.13 V to 0 V
[Pulldown]
|Voltage   I(typ)   I(min)   I(max)
-3.3V     -36.46mA   -21.09mA   -47.09mA
-800mV    -36.46mA   -21.09mA   -47.09mA
-600mV    -30.5mA    -20.54mA   -38.69mA
700mV     31.4mA     19.11mA    41.71mA
1.2V      45.15mA    25.37mA    61.75mA
1.6V      50.35mA    26.5mA     71.06mA
3.1V      52.27mA    27.26mA    74.75mA
4.1V      55.69mA    32.97mA    75.8mA
4.7V      65.7mA     32.97mA    86.63mA
5.1V      65.7mA     32.97mA    96.89mA
6.3V      65.88mA    36.5mA     96.89mA
6.6V      70.93mA    39.71mA    98.5mA
[Pullup]
|Voltage   I(typ)   I(min)   I(max)
-3.3V     54.18mA    42.9mA     67.11mA
-1.5V     54.18mA    42.9mA     67.11mA
-1.1V     51.96mA    37.26mA    66.85mA
500mV     -22.07mA   -14mA      -30.03mA
1.5V      -49.1mA    -28.3mA    -68.56mA
2.2V      -56.04mA   -30.32mA   -80.35mA
3.5V      -59.53mA   -32.65mA   -85.92mA
4.2V      -61.43mA   -47.4mA    -87.46mA
4.5V      -69.06mA   -55.1mA    -88.38mA
5.4V      -98mA      -57.7mA    -119.2mA
5.7V      -98mA      -57.7mA    -131.2mA
6.6V      -98mA      -57.7mA    -131.2mA
[GND_clamp]
|Voltage   I(typ)   I(min)   I(max)
-3.3V     -4.64A     -4.798A    -4.587A
-1.2V     -535.6mA   -717.5mA   -459.3mA
-1.13V    -409.9mA   -591mA     -333.1mA
-1.06V    -288.9mA   -467.4mA   -212.9mA
-990mV    -176.2mA   -348mA     -105.7mA
-920mV    -81.01mA   -235.5mA   -32.97mA
-850mV    -23.67mA   -135.1mA   -12.28mA
-780mV    -7.764mA   -57.43mA   -7.776mA
-710mV    -4.197mA   -16.31mA   -4.777mA
-640mV    -2.307mA   -4.41mA    -2.453mA
-570mV    -1.059mA   -1.629mA   -967uA
3.28V     81.28uA    57.87uA    93.98uA
[POWER_clamp]
|Voltage   I(typ)   I(min)   I(max)
-3.28V    395.3uA    171.4uA    658.7uA
-2.56V    366.2uA    158.7uA    613.4uA
-1.68V    356.7uA    154.5uA    599.4uA
-1.64V    356.6uA    154.5uA    590.8uA
-1.52V    353.6uA    154.3uA    518.3uA
-1.48V    341.1uA    154.3uA    492.3uA
-1.28V    253.6uA    150.4uA    364.2uA
-960mV    123.1uA    77.62uA    181.6uA
-720mV    50.52uA    32.09uA    76.18uA
-560mV    18.94uA    12.32uA    28.65uA
-440mV    5.105uA    3.74uA     7.324uA
0V        0A         0A         0A
[Ramp]
| variable   typ   min   max
dV/dt_r  1.26774/2.47915n   0.81060/2.20576n   1.56330/2.09405n
dV/dt_f  1.28436/2.29830n   0.77616/1.86727n   1.57516/2.04578n
R_load = 50.000000
[Rising Waveform]
R_fixture= 50.000000
V_fixture= 3.300000
V_fixture_min= 2.700000
V_fixture_max= 3.600000
|time   V(typ)   V(min)   V(max)
0s        1.123V     1.391V     952.7mV
210.2ps   1.122V     1.391V     1.084V
460.5ps   1.233V     1.39V      2.51V
570.6ps   1.696V     1.39V      2.868V
740.7ps   2.477V     1.387V     3.179V
1.011ns   2.981V     1.447V     3.42V
1.121ns   3.072V     1.601V     3.472V
1.421ns   3.202V     2.347V     3.555V
1.812ns   3.266V     2.605V     3.587V
4.985ns   3.298V     2.699V     3.598V
[Rising Waveform]
R_fixture= 50.000000
V_fixture= 0.0
V_fixture_min= 0.0
V_fixture_max= 0.0
|time   V(typ)   V(min)   V(max)
0s        353.3uV    68.19uV    1.147mV
640.6ps   -22.42mV   556uV      -6.65mV
1.221ns   24.05mV    -14.69mV   173.6mV
2.122ns   341.1mV    90.49mV    799.8mV
3.624ns   1.161V     695.6mV    1.947V
4.064ns   1.386V     859.4mV    2.2V
4.505ns   1.591V     998.2mV    2.357V
5.285ns   1.86V      1.173V     2.489V
6.166ns   2V         1.273V     2.554V
9.97ns    2.127V     1.358V     2.613V
[Falling Waveform]
R_fixture= 50.000000
V_fixture= 3.300000
V_fixture_min= 2.700000
V_fixture_max= 3.600000
|time   V(typ)   V(min)   V(max)
0s        3.298V     2.699V     3.598V
900.9ps   3.312V     2.701V     3.606V
1.201ns   3.311V     2.708V     3.496V
1.582ns   3.246V     2.708V     3.23V
2.162ns   2.969V     2.663V     2.715V
3.524ns   2.11V      2.025V     1.663V
4.484ns   1.628V     1.676V     1.201V
5.185ns   1.39V      1.562V     1.087V
6.066ns   1.26V      1.492V     1.027V
9.97ns    1.123V     1.391V     952.7mV
[Falling Waveform]
R_fixture= 50.000000
V_fixture= 0.0
V_fixture_min= 0.0
V_fixture_max= 0.0
|time   V(typ)   V(min)   V(max)
0s        2.127V     1.358V     2.613V
240.2ps   2.132V     1.357V     2.445V
510.5ps   1.984V     1.358V     1.57V
660.7ps   1.702V     1.36V      1.037V
810.8ps   1.308V     1.364V     682.8mV
1.051ns   747.2mV    1.317V     375.2mV
1.271ns   424.7mV    1.122V     220.5mV
1.922ns   87.88mV    389.3mV    24.04mV
2.482ns   12.37mV    80.17mV    3.764mV
4.985ns   353.3uV    68.19uV    1.147mV
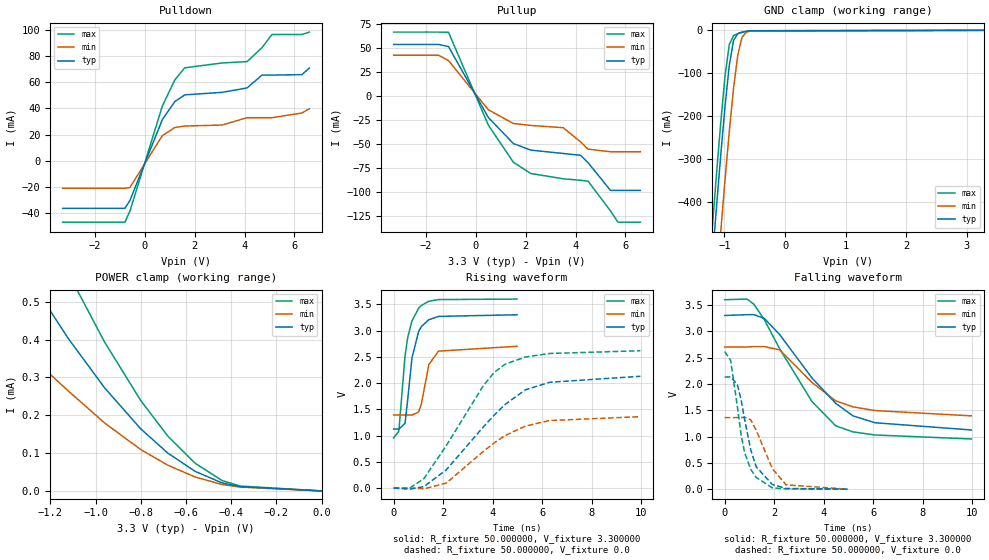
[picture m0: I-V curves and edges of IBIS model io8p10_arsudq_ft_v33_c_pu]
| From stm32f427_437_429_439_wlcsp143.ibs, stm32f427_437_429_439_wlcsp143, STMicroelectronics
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|   Model io8p10_arsudq_ft_v33_c_pu
[Model]  io8p10_arsudq_ft_v33_c_pu
Model_type I/O
Polarity   Non-Inverting
Enable   Active-Low
Vinl =   0.990000V
Vinh =   2.310000V
Vmeas =  1.650000V
Cref =   40.000000pF
Rref =   100.000000M
Vref =   0.0V
C_comp   5.986400pF   5.818600pF   6.191500pF
[Temperature Range]   25.000000   0.125000k   -40.000000
[Pullup Reference]   3.300000V   2.700000V   3.600000V
[Pulldown Reference]   0.0V   0.0V   0.0V
[POWER Clamp Reference]   3.300000V   2.700000V   3.600000V
[GND Clamp Reference]   0.0V   0.0V   0.0V
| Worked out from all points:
|   slope of the pulldown table from 0 to 0.495 V, typ, clamps not added: 20.9 ohm
|   slope of the pullup table from 0 to 0.495 V, typ, clamps not added: 22.6 ohm
|   GND clamp passes 1 mA (typ) near -0.57 V on its own axis
|   POWER clamp passes 1 mA (typ) near -1.88 V on its own axis
|   rising waveform, R_fixture 50.000000, V_fixture 3.300000: 20-80 % time 369ps typ, 355ps min, 389ps max; typ from 1.12 V to 3.3 V
|   rising waveform, R_fixture 50.000000, V_fixture 0.0: 20-80 % time 2.49ns typ, 2.22ns min, 2.1ns max; typ from 0.001 V to 2.13 V
|   falling waveform, R_fixture 50.000000, V_fixture 3.300000: 20-80 % time 2.31ns typ, 1.88ns min, 2.05ns max; typ from 3.3 V to 1.12 V
|   falling waveform, R_fixture 50.000000, V_fixture 0.0: 20-80 % time 612ps typ, 777ps min, 544ps max; typ from 2.13 V to 0.001 V
[Pulldown]
|Voltage   I(typ)   I(min)   I(max)
-3.3V     -36.46mA   -21.09mA   -47.09mA
-800mV    -36.46mA   -21.09mA   -47.09mA
-600mV    -30.5mA    -20.54mA   -38.69mA
700mV     31.4mA     19.11mA    41.71mA
1.2V      45.15mA    25.37mA    61.75mA
1.6V      50.35mA    26.5mA     71.06mA
3.1V      52.28mA    27.26mA    74.76mA
4.1V      55.64mA    32.89mA    75.8mA
4.7V      65.5mA     32.89mA    86.49mA
5.1V      65.5mA     32.89mA    96.54mA
6.3V      65.83mA    36.48mA    96.54mA
6.6V      70.88mA    39.69mA    98.4mA
[Pullup]
|Voltage   I(typ)   I(min)   I(max)
-3.3V     54.05mA    42.87mA    66.91mA
-1.5V     54.05mA    42.87mA    66.91mA
-1.1V     51.85mA    37.2mA     66.69mA
500mV     -22.06mA   -14mA      -30.03mA
1.5V      -49.1mA    -28.3mA    -68.56mA
2.2V      -56.04mA   -30.32mA   -80.35mA
3.5V      -59.52mA   -32.65mA   -85.91mA
4.2V      -61.43mA   -47.4mA    -87.45mA
4.5V      -69.06mA   -55mA      -88.37mA
5.4V      -98mA      -57.7mA    -119.3mA
5.7V      -98mA      -57.7mA    -131.1mA
6.6V      -98mA      -57.7mA    -131.1mA
[GND_clamp]
|Voltage   I(typ)   I(min)   I(max)
-3.3V     -4.64A     -4.799A    -4.587A
-1.2V     -535.6mA   -717.5mA   -459.3mA
-1.13V    -409.9mA   -591mA     -333.1mA
-1.06V    -288.9mA   -467.4mA   -212.9mA
-990mV    -176.2mA   -348mA     -105.7mA
-920mV    -81.01mA   -235.5mA   -32.96mA
-850mV    -23.66mA   -135.1mA   -12.27mA
-780mV    -7.753mA   -57.42mA   -7.762mA
-710mV    -4.185mA   -16.31mA   -4.763mA
-640mV    -2.295mA   -4.401mA   -2.439mA
-570mV    -1.048mA   -1.62mA    -953.6uA
3.28V     0A         0A         0A
[POWER_clamp]
|Voltage   I(typ)   I(min)   I(max)
-3.28V    1.181mA    571.7uA    1.791mA
-1.84V    973.5uA    557.9uA    1.433mA
-1.32V    587.4uA    369.9uA    827.8uA
-1.28V    548.8uA    352.3uA    775.2uA
-1.12V    402.4uA    263.9uA    574.4uA
-960mV    272.5uA    179.7uA    393.5uA
-800mV    164uA      109.3uA    238.7uA
-680mV    99.77uA    67.86uA    144.6uA
-560mV    51.85uA    36.88uA    73.46uA
-440mV    21.1uA     16.96uA    27.26uA
-360mV    11.28uA    10.1uA     12.92uA
0V        0A         0A         0A
[Ramp]
| variable   typ   min   max
dV/dt_r  1.26817/2.48283n   0.81123/2.21090n   1.56364/2.09660n
dV/dt_f  1.28394/2.29806n   0.77526/1.86332n   1.57483/2.04523n
R_load = 50.000000
[Rising Waveform]
R_fixture= 50.000000
V_fixture= 3.300000
V_fixture_min= 2.700000
V_fixture_max= 3.600000
|time   V(typ)   V(min)   V(max)
0s        1.125V     1.393V     954.4mV
210.2ps   1.123V     1.393V     1.086V
460.5ps   1.235V     1.393V     2.516V
570.6ps   1.7V       1.392V     2.874V
740.7ps   2.482V     1.39V      3.185V
1.011ns   2.985V     1.449V     3.425V
1.121ns   3.076V     1.604V     3.477V
1.421ns   3.206V     2.351V     3.558V
1.812ns   3.269V     2.608V     3.589V
4.985ns   3.3V       2.7V       3.599V
[Rising Waveform]
R_fixture= 50.000000
V_fixture= 0.0
V_fixture_min= 0.0
V_fixture_max= 0.0
|time   V(typ)   V(min)   V(max)
0s        1.441mV    1.111mV    2.282mV
640.6ps   -20.39mV   1.597mV    -2.448mV
1.221ns   27.95mV    -13.27mV   179mV
2.122ns   345.8mV    93.94mV    805mV
3.624ns   1.165V     699.2mV    1.951V
4.064ns   1.39V      862.2mV    2.203V
4.505ns   1.594V     1.001V     2.36V
5.325ns   1.872V     1.181V     2.496V
6.306ns   2.015V     1.286V     2.563V
9.97ns    2.129V     1.36V      2.615V
[Falling Waveform]
R_fixture= 50.000000
V_fixture= 3.300000
V_fixture_min= 2.700000
V_fixture_max= 3.600000
|time   V(typ)   V(min)   V(max)
0s        3.3V       2.7V       3.599V
900.9ps   3.314V     2.702V     3.611V
1.181ns   3.315V     2.709V     3.512V
1.602ns   3.243V     2.709V     3.218V
2.222ns   2.937V     2.646V     2.666V
3.524ns   2.114V     2.028V     1.667V
4.484ns   1.632V     1.679V     1.204V
5.185ns   1.393V     1.564V     1.089V
6.066ns   1.263V     1.494V     1.03V
9.97ns    1.125V     1.393V     954.4mV
[Falling Waveform]
R_fixture= 50.000000
V_fixture= 0.0
V_fixture_min= 0.0
V_fixture_max= 0.0
|time   V(typ)   V(min)   V(max)
0s        2.129V     1.36V      2.615V
240.2ps   2.134V     1.359V     2.447V
510.5ps   1.986V     1.36V      1.572V
660.7ps   1.703V     1.362V     1.039V
810.8ps   1.309V     1.366V     686mV
1.051ns   750.1mV    1.319V     379.1mV
1.271ns   427.9mV    1.124V     224.8mV
1.922ns   91.47mV    392.3mV    27.02mV
2.482ns   14.44mV    82.56mV    5.385mV
4.985ns   1.441mV    1.111mV    2.282mV
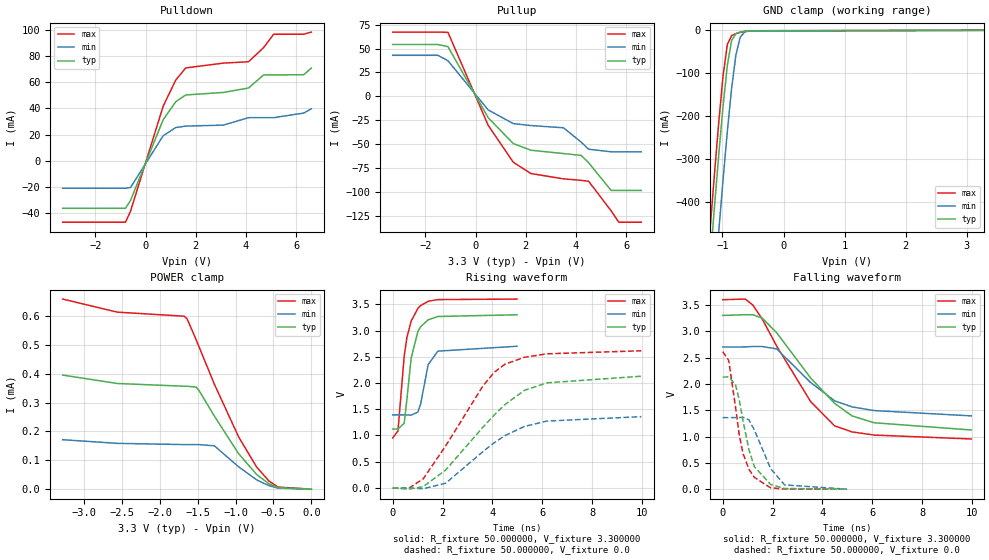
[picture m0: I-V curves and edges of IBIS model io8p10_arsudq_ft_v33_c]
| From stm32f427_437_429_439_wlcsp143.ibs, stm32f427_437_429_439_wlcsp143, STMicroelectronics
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|   Model io8p10_arsudq_ft_v33_c
[Model]  io8p10_arsudq_ft_v33_c
Model_type I/O
Polarity   Non-Inverting
Enable   Active-Low
Vinl =   0.990000V
Vinh =   2.310000V
Vmeas =  1.650000V
Cref =   40.000000pF
Rref =   100.000000M
Vref =   0.0V
C_comp   5.986400pF   5.818600pF   6.191500pF
[Temperature Range]   25.000000   0.125000k   -40.000000
[Pullup Reference]   3.300000V   2.700000V   3.600000V
[Pulldown Reference]   0.0V   0.0V   0.0V
[POWER Clamp Reference]   3.300000V   2.700000V   3.600000V
[GND Clamp Reference]   0.0V   0.0V   0.0V
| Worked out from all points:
|   slope of the pulldown table from 0 to 0.495 V, typ, clamps not added: 20.9 ohm
|   slope of the pullup table from 0 to 0.495 V, typ, clamps not added: 22.6 ohm
|   GND clamp passes 1 mA (typ) near -0.57 V on its own axis
|   rising waveform, R_fixture 50.000000, V_fixture 3.300000: 20-80 % time 370ps typ, 356ps min, 391ps max; typ from 1.12 V to 3.3 V
|   rising waveform, R_fixture 50.000000, V_fixture 0.0: 20-80 % time 2.49ns typ, 2.22ns min, 2.1ns max; typ from 0 V to 2.13 V
|   falling waveform, R_fixture 50.000000, V_fixture 3.300000: 20-80 % time 2.31ns typ, 1.88ns min, 2.05ns max; typ from 3.3 V to 1.12 V
|   falling waveform, R_fixture 50.000000, V_fixture 0.0: 20-80 % time 611ps typ, 776ps min, 544ps max; typ from 2.13 V to 0 V
[Pulldown]
|Voltage   I(typ)   I(min)   I(max)
-3.3V     -36.46mA   -21.09mA   -47.09mA
-800mV    -36.46mA   -21.09mA   -47.09mA
-600mV    -30.5mA    -20.54mA   -38.69mA
700mV     31.4mA     19.11mA    41.71mA
1.2V      45.15mA    25.37mA    61.75mA
1.6V      50.35mA    26.5mA     71.06mA
3.1V      52.28mA    27.26mA    74.75mA
4.1V      55.7mA     32.97mA    75.81mA
4.7V      65.71mA    32.97mA    86.64mA
5.1V      65.71mA    32.97mA    96.9mA
6.3V      65.88mA    36.51mA    96.9mA
6.6V      70.94mA    39.72mA    98.51mA
[Pullup]
|Voltage   I(typ)   I(min)   I(max)
-3.3V     54.18mA    42.91mA    67.12mA
-1.5V     54.18mA    42.91mA    67.12mA
-1.1V     51.96mA    37.26mA    66.85mA
500mV     -22.07mA   -14mA      -30.03mA
1.5V      -49.1mA    -28.3mA    -68.56mA
2.2V      -56.05mA   -30.32mA   -80.35mA
3.5V      -59.53mA   -32.65mA   -85.92mA
4.2V      -61.44mA   -47.5mA    -87.46mA
4.5V      -69.06mA   -55mA      -88.38mA
5.4V      -98mA      -57.7mA    -119.3mA
5.7V      -98mA      -57.7mA    -131.1mA
6.6V      -98mA      -57.7mA    -131.1mA
[GND_clamp]
|Voltage   I(typ)   I(min)   I(max)
-3.3V     -4.64A     -4.799A    -4.587A
-1.2V     -535.6mA   -717.5mA   -459.3mA
-1.13V    -409.9mA   -591mA     -333.1mA
-1.06V    -288.9mA   -467.4mA   -212.9mA
-990mV    -176.2mA   -348mA     -105.7mA
-920mV    -81.01mA   -235.5mA   -32.96mA
-850mV    -23.66mA   -135.1mA   -12.27mA
-780mV    -7.753mA   -57.42mA   -7.762mA
-710mV    -4.185mA   -16.31mA   -4.763mA
-640mV    -2.295mA   -4.401mA   -2.439mA
-570mV    -1.048mA   -1.62mA    -953.6uA
3.28V     0A         0A         0A
[POWER_clamp]
|Voltage   I(typ)   I(min)   I(max)
-3.28V    395.3uA    171.4uA    658.7uA
-2.56V    366.2uA    158.7uA    613.4uA
-1.68V    356.7uA    154.5uA    599.4uA
-1.64V    356.6uA    154.5uA    590.8uA
-1.52V    353.6uA    154.3uA    518.3uA
-1.48V    341.1uA    154.3uA    492.3uA
-1.28V    253.6uA    150.4uA    364.2uA
-960mV    123.1uA    77.62uA    181.6uA
-720mV    50.52uA    32.09uA    76.18uA
-560mV    18.94uA    12.32uA    28.65uA
-440mV    5.105uA    3.74uA     7.324uA
0V        0A         0A         0A
[Ramp]
| variable   typ   min   max
dV/dt_r  1.26840/2.47923n   0.81120/2.20746n   1.56402/2.09382n
dV/dt_f  1.28466/2.29746n   0.77598/1.86758n   1.57560/2.04466n
R_load = 50.000000
[Rising Waveform]
R_fixture= 50.000000
V_fixture= 3.300000
V_fixture_min= 2.700000
V_fixture_max= 3.600000
|time   V(typ)   V(min)   V(max)
0s        1.124V     1.392V     953.1mV
210.2ps   1.122V     1.392V     1.085V
460.5ps   1.234V     1.392V     2.511V
570.6ps   1.697V     1.391V     2.869V
740.7ps   2.478V     1.388V     3.181V
1.011ns   2.982V     1.448V     3.422V
1.121ns   3.074V     1.603V     3.474V
1.421ns   3.203V     2.349V     3.557V
1.812ns   3.267V     2.607V     3.589V
4.985ns   3.3V       2.7V       3.599V
[Rising Waveform]
R_fixture= 50.000000
V_fixture= 0.0
V_fixture_min= 0.0
V_fixture_max= 0.0
|time   V(typ)   V(min)   V(max)
0s        353.2uV    67.89uV    1.147mV
640.6ps   -22.42mV   556uV      -6.655mV
1.221ns   24.04mV    -14.69mV   173.6mV
2.122ns   341.1mV    90.49mV    799.9mV
3.624ns   1.161V     695.7mV    1.948V
4.064ns   1.387V     859.6mV    2.201V
4.505ns   1.591V     998.5mV    2.359V
5.285ns   1.861V     1.173V     2.49V
6.186ns   2.003V     1.275V     2.556V
9.97ns    2.129V     1.359V     2.614V
[Falling Waveform]
R_fixture= 50.000000
V_fixture= 3.300000
V_fixture_min= 2.700000
V_fixture_max= 3.600000
|time   V(typ)   V(min)   V(max)
0s        3.3V       2.7V       3.599V
900.9ps   3.314V     2.702V     3.611V
1.201ns   3.314V     2.71V      3.501V
1.582ns   3.25V      2.71V      3.235V
2.162ns   2.972V     2.665V     2.72V
3.524ns   2.113V     2.027V     1.665V
4.484ns   1.631V     1.678V     1.203V
5.185ns   1.392V     1.563V     1.088V
6.066ns   1.262V     1.493V     1.028V
9.97ns    1.124V     1.392V     953.1mV
[Falling Waveform]
R_fixture= 50.000000
V_fixture= 0.0
V_fixture_min= 0.0
V_fixture_max= 0.0
|time   V(typ)   V(min)   V(max)
0s        2.129V     1.359V     2.614V
240.2ps   2.134V     1.358V     2.447V
510.5ps   1.986V     1.359V     1.573V
660.7ps   1.703V     1.361V     1.04V
810.8ps   1.31V      1.365V     685.8mV
1.051ns   749.4mV    1.318V     378.1mV
1.271ns   426.8mV    1.123V     223.2mV
1.922ns   89.62mV    390.5mV    25.1mV
2.482ns   13.01mV    81.05mV    4.122mV
4.985ns   353.2uV    67.89uV    1.147mV
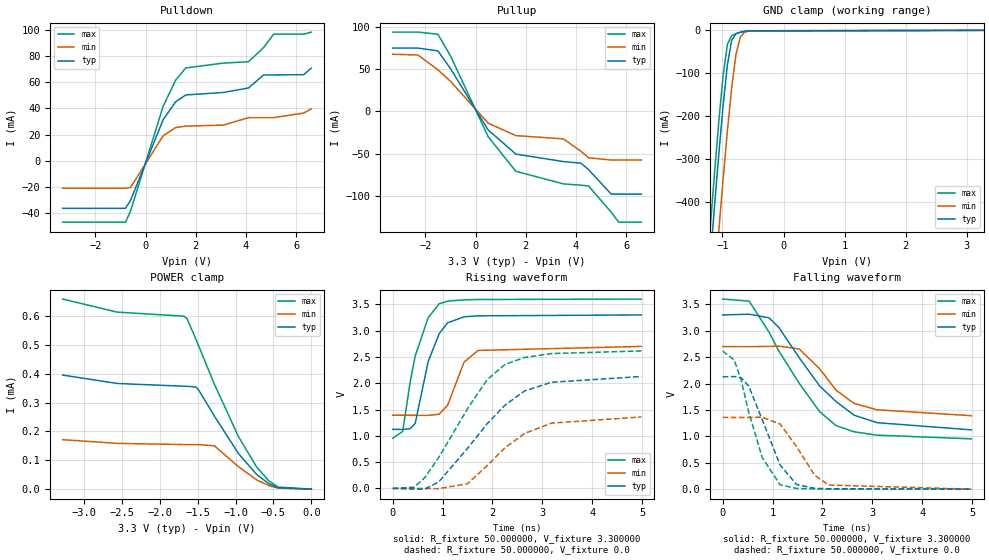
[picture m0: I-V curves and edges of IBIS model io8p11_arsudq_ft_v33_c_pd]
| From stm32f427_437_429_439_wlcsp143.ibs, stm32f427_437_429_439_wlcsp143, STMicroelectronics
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|   Model io8p11_arsudq_ft_v33_c_pd
[Model]  io8p11_arsudq_ft_v33_c_pd
Model_type I/O
Polarity   Non-Inverting
Enable   Active-Low
Vinl =   0.990000V
Vinh =   2.310000V
Vmeas =  1.650000V
Cref =   30.000000pF
Rref =   100.000000M
Vref =   0.0V
C_comp   5.986400pF   5.818600pF   6.191500pF
[Temperature Range]   25.000000   0.125000k   -40.000000
[Pullup Reference]   3.300000V   2.700000V   3.600000V
[Pulldown Reference]   0.0V   0.0V   0.0V
[POWER Clamp Reference]   3.300000V   2.700000V   3.600000V
[GND Clamp Reference]   0.0V   0.0V   0.0V
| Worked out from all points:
|   slope of the pulldown table from 0 to 0.495 V, typ, clamps not added: 20.9 ohm
|   slope of the pullup table from 0 to 0.495 V, typ, clamps not added: 22.6 ohm
|   GND clamp passes 1 mA (typ) near -0.56 V on its own axis
|   rising waveform, R_fixture 50.000000, V_fixture 3.300000: 20-80 % time 353ps typ, 328ps min, 362ps max; typ from 1.12 V to 3.3 V
|   rising waveform, R_fixture 50.000000, V_fixture 0.0: 20-80 % time 1.17ns typ, 1ns min, 1.04ns max; typ from 0 V to 2.13 V
|   falling waveform, R_fixture 50.000000, V_fixture 3.300000: 20-80 % time 1.12ns typ, 770ps min, 1.05ns max; typ from 3.3 V to 1.12 V
|   falling waveform, R_fixture 50.000000, V_fixture 0.0: 20-80 % time 519ps typ, 550ps min, 466ps max; typ from 2.13 V to 0 V
[Pulldown]
|Voltage   I(typ)   I(min)   I(max)
-3.3V     -36.46mA   -21.09mA   -47.09mA
-800mV    -36.46mA   -21.09mA   -47.09mA
-600mV    -30.5mA    -20.54mA   -38.69mA
700mV     31.4mA     19.11mA    41.71mA
1.2V      45.15mA    25.37mA    61.75mA
1.6V      50.35mA    26.5mA     71.06mA
3.1V      52.27mA    27.26mA    74.75mA
4.1V      55.69mA    32.97mA    75.8mA
4.7V      65.7mA     32.97mA    86.63mA
5.1V      65.7mA     32.97mA    96.89mA
6.3V      65.88mA    36.5mA     96.89mA
6.6V      70.93mA    39.71mA    98.5mA
[Pullup]
|Voltage   I(typ)   I(min)   I(max)
-3.3V     74.73mA    67.41mA    93.64mA
-2.3V     74.73mA    66.57mA    93.64mA
-1.5V     71.36mA    49.01mA    91.06mA
-1V       50.51mA    35.49mA    65.51mA
500mV     -22.07mA   -14mA      -30.03mA
1.6V      -50.64mA   -28.81mA   -70.96mA
3.5V      -59.53mA   -32.65mA   -85.92mA
4.2V      -61.43mA   -47.4mA    -87.46mA
4.5V      -69.06mA   -55mA      -88.38mA
5.4V      -98mA      -57.7mA    -119.3mA
5.7V      -98mA      -57.7mA    -131.2mA
6.6V      -98mA      -57.7mA    -131.2mA
[GND_clamp]
|Voltage   I(typ)   I(min)   I(max)
-3.3V     -4.639A    -4.798A    -4.587A
-1.2V     -535.6mA   -717.5mA   -459.3mA
-1.13V    -409.9mA   -591mA     -333.1mA
-1.06V    -288.9mA   -467.4mA   -212.9mA
-990mV    -176.2mA   -348mA     -105.7mA
-920mV    -81.01mA   -235.5mA   -32.97mA
-850mV    -23.67mA   -135.1mA   -12.28mA
-780mV    -7.764mA   -57.43mA   -7.776mA
-710mV    -4.197mA   -16.31mA   -4.777mA
-640mV    -2.307mA   -4.41mA    -2.453mA
-570mV    -1.059mA   -1.629mA   -967uA
3.28V     81.28uA    57.87uA    93.98uA
[POWER_clamp]
|Voltage   I(typ)   I(min)   I(max)
-3.28V    395.3uA    171.4uA    658.7uA
-2.56V    366.2uA    158.7uA    613.4uA
-1.68V    356.7uA    154.5uA    599.4uA
-1.64V    356.6uA    154.5uA    590.8uA
-1.52V    353.6uA    154.3uA    518.3uA
-1.48V    341.1uA    154.3uA    492.3uA
-1.28V    253.6uA    150.4uA    364.2uA
-960mV    123.1uA    77.62uA    181.6uA
-720mV    50.52uA    32.09uA    76.18uA
-560mV    18.94uA    12.32uA    28.65uA
-440mV    5.105uA    3.74uA     7.324uA
0V        0A         0A         0A
[Ramp]
| variable   typ   min   max
dV/dt_r  1.26282/1.15861n   0.80238/0.98366n   1.56060/1.03152n
dV/dt_f  1.27938/1.10330n   0.76644/0.74677n   1.57103/1.04810n
R_load = 50.000000
[Rising Waveform]
R_fixture= 50.000000
V_fixture= 3.300000
V_fixture_min= 2.700000
V_fixture_max= 3.600000
|time   V(typ)   V(min)   V(max)
0s        1.123V     1.391V     952.5mV
200.2ps   1.122V     1.391V     1.084V
350.4ps   1.136V     1.391V     2.023V
450.5ps   1.234V     1.39V      2.515V
710.7ps   2.408V     1.388V     3.245V
930.9ps   2.94V      1.411V     3.509V
1.101ns   3.147V     1.582V     3.56V
1.431ns   3.262V     2.401V     3.584V
1.712ns   3.28V      2.623V     3.591V
4.985ns   3.298V     2.699V     3.599V
[Rising Waveform]
R_fixture= 50.000000
V_fixture= 0.0
V_fixture_min= 0.0
V_fixture_max= 0.0
|time   V(typ)   V(min)   V(max)
0s        403.1uV    66.35uV    376.2uV
430.4ps   -11.4mV    254.6uV    23.78mV
640.6ps   -13.81mV   448.9uV    203.1mV
920.9ps   122.4mV    -5.524mV   586.3mV
1.502ns   763.4mV    90.17mV    1.518V
1.892ns   1.227V     432.6mV    2.065V
2.252ns   1.584V     773.3mV    2.357V
2.643ns   1.853V     1.044V     2.489V
3.183ns   2.018V     1.241V     2.563V
4.985ns   2.127V     1.358V     2.613V
[Falling Waveform]
R_fixture= 50.000000
V_fixture= 3.300000
V_fixture_min= 2.700000
V_fixture_max= 3.600000
|time   V(typ)   V(min)   V(max)
0s        3.298V     2.699V     3.599V
530.5ps   3.313V     2.698V     3.56V
930.9ps   3.243V     2.703V     2.969V
1.131ns   3.055V     2.708V     2.607V
1.532ns   2.491V     2.655V     2.007V
1.942ns   1.956V     2.282V     1.469V
2.272ns   1.659V     1.874V     1.204V
2.633ns   1.401V     1.625V     1.086V
3.093ns   1.259V     1.503V     1.023V
4.985ns   1.123V     1.391V     952.5mV
[Falling Waveform]
R_fixture= 50.000000
V_fixture= 0.0
V_fixture_min= 0.0
V_fixture_max= 0.0
|time   V(typ)   V(min)   V(max)
0s        2.127V     1.358V     2.613V
230.2ps   2.132V     1.357V     2.445V
370.4ps   2.109V     1.357V     2.065V
520.5ps   1.952V     1.358V     1.464V
790.8ps   1.32V      1.362V     602.6mV
1.151ns   456.1mV    1.233V     82.83mV
1.481ns   88.18mV    805.8mV    13.42mV
1.842ns   17.23mV    265.4mV    4.575mV
2.122ns   7.263mV    78.1mV     2.962mV
4.985ns   403.1uV    66.35uV    376.2uV
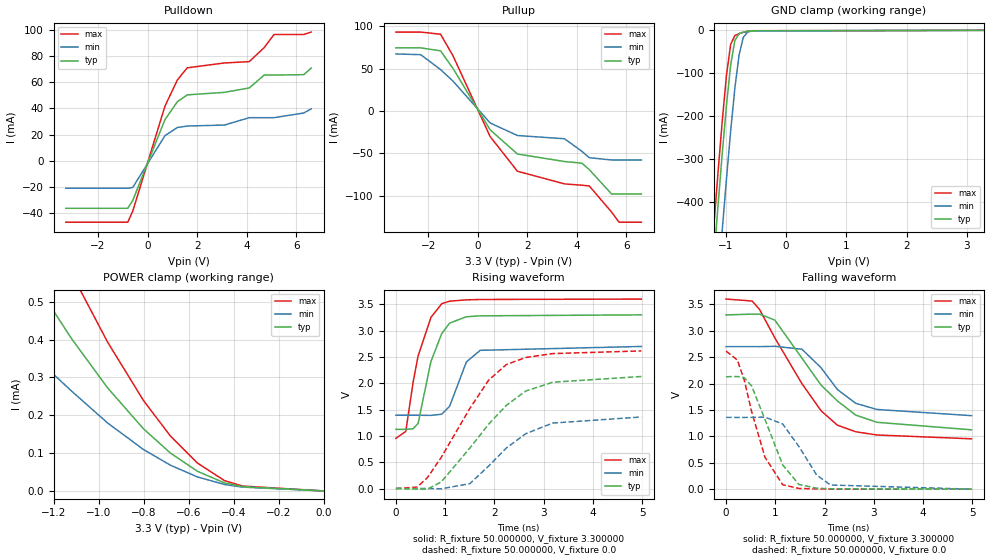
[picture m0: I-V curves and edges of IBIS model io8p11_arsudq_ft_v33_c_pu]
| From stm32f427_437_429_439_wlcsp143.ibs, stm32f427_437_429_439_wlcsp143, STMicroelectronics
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|   Model io8p11_arsudq_ft_v33_c_pu
[Model]  io8p11_arsudq_ft_v33_c_pu
Model_type I/O
Polarity   Non-Inverting
Enable   Active-Low
Vinl =   0.990000V
Vinh =   2.310000V
Vmeas =  1.650000V
Cref =   30.000000pF
Rref =   100.000000M
Vref =   0.0V
C_comp   5.986400pF   5.818600pF   6.191500pF
[Temperature Range]   25.000000   0.125000k   -40.000000
[Pullup Reference]   3.300000V   2.700000V   3.600000V
[Pulldown Reference]   0.0V   0.0V   0.0V
[POWER Clamp Reference]   3.300000V   2.700000V   3.600000V
[GND Clamp Reference]   0.0V   0.0V   0.0V
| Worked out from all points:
|   slope of the pulldown table from 0 to 0.495 V, typ, clamps not added: 20.9 ohm
|   slope of the pullup table from 0 to 0.495 V, typ, clamps not added: 22.6 ohm
|   GND clamp passes 1 mA (typ) near -0.57 V on its own axis
|   POWER clamp passes 1 mA (typ) near -1.88 V on its own axis
|   rising waveform, R_fixture 50.000000, V_fixture 3.300000: 20-80 % time 351ps typ, 326ps min, 360ps max; typ from 1.12 V to 3.3 V
|   rising waveform, R_fixture 50.000000, V_fixture 0.0: 20-80 % time 1.17ns typ, 1ns min, 1.04ns max; typ from 0.001 V to 2.13 V
|   falling waveform, R_fixture 50.000000, V_fixture 3.300000: 20-80 % time 1.12ns typ, 770ps min, 1.06ns max; typ from 3.3 V to 1.12 V
|   falling waveform, R_fixture 50.000000, V_fixture 0.0: 20-80 % time 520ps typ, 551ps min, 466ps max; typ from 2.13 V to 0.001 V
[Pulldown]
|Voltage   I(typ)   I(min)   I(max)
-3.3V     -36.46mA   -21.09mA   -47.09mA
-800mV    -36.46mA   -21.09mA   -47.09mA
-600mV    -30.5mA    -20.54mA   -38.69mA
700mV     31.4mA     19.11mA    41.71mA
1.2V      45.15mA    25.37mA    61.75mA
1.6V      50.35mA    26.5mA     71.06mA
3.1V      52.28mA    27.26mA    74.76mA
4.1V      55.64mA    32.89mA    75.8mA
4.7V      65.5mA     32.89mA    86.49mA
5.1V      65.5mA     32.89mA    96.54mA
6.3V      65.83mA    36.48mA    96.54mA
6.6V      70.88mA    39.69mA    98.4mA
[Pullup]
|Voltage   I(typ)   I(min)   I(max)
-3.3V     74.6mA     67.42mA    93.23mA
-2.3V     74.6mA     66.59mA    93.23mA
-1.5V     71.11mA    49mA       90.72mA
-1V       50.42mA    35.44mA    65.37mA
500mV     -22.06mA   -14mA      -30.03mA
1.6V      -50.64mA   -28.81mA   -70.96mA
3.5V      -59.52mA   -32.65mA   -85.91mA
4.2V      -61.43mA   -47.4mA    -87.45mA
4.5V      -69.06mA   -55mA      -88.37mA
5.4V      -97.9mA    -57.7mA    -119.2mA
5.7V      -97.9mA    -57.7mA    -131.1mA
6.6V      -97.9mA    -57.7mA    -131.1mA
[GND_clamp]
|Voltage   I(typ)   I(min)   I(max)
-3.3V     -4.64A     -4.798A    -4.587A
-1.2V     -535.6mA   -717.5mA   -459.3mA
-1.13V    -409.9mA   -591mA     -333.1mA
-1.06V    -288.9mA   -467.4mA   -212.9mA
-990mV    -176.2mA   -348mA     -105.7mA
-920mV    -81.01mA   -235.5mA   -32.96mA
-850mV    -23.66mA   -135.1mA   -12.27mA
-780mV    -7.753mA   -57.42mA   -7.762mA
-710mV    -4.185mA   -16.31mA   -4.763mA
-640mV    -2.295mA   -4.401mA   -2.439mA
-570mV    -1.048mA   -1.62mA    -953.6uA
3.28V     0A         0A         0A
[POWER_clamp]
|Voltage   I(typ)   I(min)   I(max)
-3.28V    1.181mA    571.7uA    1.791mA
-1.84V    973.5uA    557.9uA    1.433mA
-1.32V    587.4uA    369.9uA    827.8uA
-1.28V    548.8uA    352.3uA    775.2uA
-1.12V    402.4uA    263.9uA    574.4uA
-960mV    272.5uA    179.7uA    393.5uA
-800mV    164uA      109.3uA    238.7uA
-680mV    99.77uA    67.86uA    144.6uA
-560mV    51.85uA    36.88uA    73.46uA
-440mV    21.1uA     16.96uA    27.26uA
-360mV    11.28uA    10.1uA     12.92uA
0V        0A         0A         0A
[Ramp]
| variable   typ   min   max
dV/dt_r  1.26325/1.15979n   0.80289/0.98497n   1.56100/1.03222n
dV/dt_f  1.27896/1.10367n   0.76560/0.74721n   1.57070/1.04817n
R_load = 50.000000
[Rising Waveform]
R_fixture= 50.000000
V_fixture= 3.300000
V_fixture_min= 2.700000
V_fixture_max= 3.600000
|time   V(typ)   V(min)   V(max)
0s        1.125V     1.393V     954.2mV
200.2ps   1.124V     1.393V     1.086V
350.4ps   1.138V     1.393V     2.027V
450.5ps   1.237V     1.393V     2.521V
710.7ps   2.413V     1.39V      3.251V
930.9ps   2.945V     1.413V     3.512V
1.091ns   3.143V     1.564V     3.56V
1.431ns   3.264V     2.405V     3.585V
1.712ns   3.281V     2.626V     3.592V
4.985ns   3.3V       2.7V       3.6V
[Rising Waveform]
R_fixture= 50.000000
V_fixture= 0.0
V_fixture_min= 0.0
V_fixture_max= 0.0
|time   V(typ)   V(min)   V(max)
0s        1.491mV    1.109mV    1.516mV
430.4ps   -10.22mV   1.297mV    27.37mV
640.6ps   -11.5mV    1.49mV     208.6mV
920.9ps   126.8mV    -4.438mV   593.2mV
1.502ns   769.6mV    93.42mV    1.524V
1.882ns   1.222V     427.2mV    2.058V
2.242ns   1.58V      768.7mV    2.355V
2.633ns   1.851V     1.041V     2.489V
3.183ns   2.02V      1.244V     2.564V
4.985ns   2.129V     1.36V      2.615V
[Falling Waveform]
R_fixture= 50.000000
V_fixture= 3.300000
V_fixture_min= 2.700000
V_fixture_max= 3.600000
|time   V(typ)   V(min)   V(max)
0s        3.3V       2.7V       3.6V
530.5ps   3.315V     2.7V       3.563V
680.7ps   3.315V     2.699V     3.403V
991ps     3.202V     2.706V     2.865V
1.542ns   2.48V      2.65V      1.997V
1.932ns   1.969V     2.298V     1.483V
2.262ns   1.671V     1.888V     1.212V
2.633ns   1.404V     1.627V     1.088V
3.063ns   1.267V     1.51V      1.027V
4.985ns   1.125V     1.393V     954.2mV
[Falling Waveform]
R_fixture= 50.000000
V_fixture= 0.0
V_fixture_min= 0.0
V_fixture_max= 0.0
|time   V(typ)   V(min)   V(max)
0s        2.129V     1.36V      2.615V
230.2ps   2.134V     1.359V     2.446V
370.4ps   2.111V     1.359V     2.066V
520.5ps   1.954V     1.36V      1.465V
790.8ps   1.321V     1.364V     605.5mV
1.151ns   459mV      1.235V     84.89mV
1.481ns   90.1mV     807.4mV    14.87mV
1.842ns   18.67mV    267.6mV    5.864mV
2.122ns   8.394mV    79.83mV    4.199mV
4.985ns   1.491mV    1.109mV    1.516mV
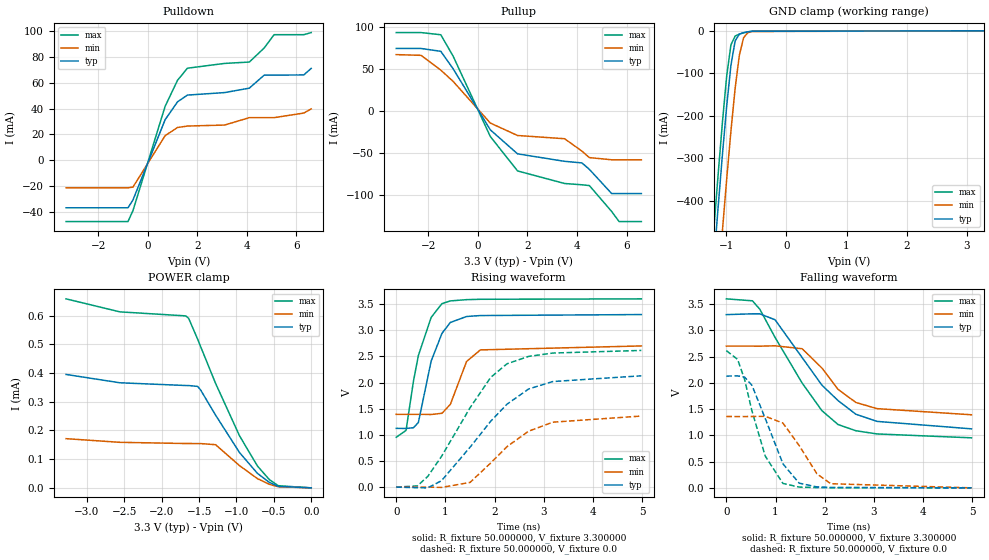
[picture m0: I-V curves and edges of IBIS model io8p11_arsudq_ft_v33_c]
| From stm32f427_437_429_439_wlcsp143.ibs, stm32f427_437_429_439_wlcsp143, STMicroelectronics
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|   Model io8p11_arsudq_ft_v33_c
[Model]  io8p11_arsudq_ft_v33_c
Model_type I/O
Polarity   Non-Inverting
Enable   Active-Low
Vinl =   0.990000V
Vinh =   2.310000V
Vmeas =  1.650000V
Cref =   30.000000pF
Rref =   100.000000M
Vref =   0.0V
C_comp   5.986400pF   5.818600pF   6.191500pF
[Temperature Range]   25.000000   0.125000k   -40.000000
[Pullup Reference]   3.300000V   2.700000V   3.600000V
[Pulldown Reference]   0.0V   0.0V   0.0V
[POWER Clamp Reference]   3.300000V   2.700000V   3.600000V
[GND Clamp Reference]   0.0V   0.0V   0.0V
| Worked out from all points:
|   slope of the pulldown table from 0 to 0.495 V, typ, clamps not added: 20.9 ohm
|   slope of the pullup table from 0 to 0.495 V, typ, clamps not added: 22.6 ohm
|   GND clamp passes 1 mA (typ) near -0.57 V on its own axis
|   rising waveform, R_fixture 50.000000, V_fixture 3.300000: 20-80 % time 353ps typ, 328ps min, 362ps max; typ from 1.12 V to 3.3 V
|   rising waveform, R_fixture 50.000000, V_fixture 0.0: 20-80 % time 1.17ns typ, 1ns min, 1.04ns max; typ from 0 V to 2.13 V
|   falling waveform, R_fixture 50.000000, V_fixture 3.300000: 20-80 % time 1.12ns typ, 771ps min, 1.06ns max; typ from 3.3 V to 1.12 V
|   falling waveform, R_fixture 50.000000, V_fixture 0.0: 20-80 % time 519ps typ, 551ps min, 466ps max; typ from 2.13 V to 0 V
[Pulldown]
|Voltage   I(typ)   I(min)   I(max)
-3.3V     -36.46mA   -21.09mA   -47.09mA
-800mV    -36.46mA   -21.09mA   -47.09mA
-600mV    -30.5mA    -20.54mA   -38.69mA
700mV     31.4mA     19.11mA    41.71mA
1.2V      45.15mA    25.37mA    61.75mA
1.6V      50.35mA    26.5mA     71.06mA
3.1V      52.28mA    27.26mA    74.75mA
4.1V      55.7mA     32.97mA    75.81mA
4.7V      65.71mA    32.97mA    86.64mA
5.1V      65.71mA    32.97mA    96.9mA
6.3V      65.88mA    36.51mA    96.9mA
6.6V      70.94mA    39.72mA    98.51mA
[Pullup]
|Voltage   I(typ)   I(min)   I(max)
-3.3V     74.74mA    67.41mA    93.64mA
-2.3V     74.74mA    66.57mA    93.64mA
-1.5V     71.36mA    49mA       91.06mA
-1V       50.51mA    35.49mA    65.51mA
500mV     -22.07mA   -14mA      -30.03mA
1.6V      -50.64mA   -28.81mA   -70.96mA
3.5V      -59.53mA   -32.65mA   -85.92mA
4.2V      -61.44mA   -47.4mA    -87.46mA
4.5V      -69.06mA   -55.1mA    -88.38mA
5.4V      -97.9mA    -57.7mA    -119.2mA
5.7V      -97.9mA    -57.7mA    -131.2mA
6.6V      -97.9mA    -57.7mA    -131.2mA
[GND_clamp]
|Voltage   I(typ)   I(min)   I(max)
-3.3V     -4.64A     -4.798A    -4.587A
-1.2V     -535.6mA   -717.5mA   -459.3mA
-1.13V    -409.9mA   -591mA     -333.1mA
-1.06V    -288.9mA   -467.4mA   -212.9mA
-990mV    -176.2mA   -348mA     -105.7mA
-920mV    -81.01mA   -235.5mA   -32.96mA
-850mV    -23.66mA   -135.1mA   -12.27mA
-780mV    -7.753mA   -57.42mA   -7.762mA
-710mV    -4.185mA   -16.31mA   -4.763mA
-640mV    -2.295mA   -4.401mA   -2.439mA
-570mV    -1.048mA   -1.62mA    -953.6uA
3.28V     0A         0A         0A
[POWER_clamp]
|Voltage   I(typ)   I(min)   I(max)
-3.28V    395.3uA    171.4uA    658.7uA
-2.56V    366.2uA    158.7uA    613.4uA
-1.68V    356.7uA    154.5uA    599.4uA
-1.64V    356.6uA    154.5uA    590.8uA
-1.52V    353.6uA    154.3uA    518.3uA
-1.48V    341.1uA    154.3uA    492.3uA
-1.28V    253.6uA    150.4uA    364.2uA
-960mV    123.1uA    77.62uA    181.6uA
-720mV    50.52uA    32.09uA    76.18uA
-560mV    18.94uA    12.32uA    28.65uA
-440mV    5.105uA    3.74uA     7.324uA
0V        0A         0A         0A
[Ramp]
| variable   typ   min   max
dV/dt_r  1.26336/1.15914n   0.80268/0.98414n   1.56126/1.03179n
dV/dt_f  1.27950/1.10382n   0.76620/0.74813n   1.57139/1.04824n
R_load = 50.000000
[Rising Waveform]
R_fixture= 50.000000
V_fixture= 3.300000
V_fixture_min= 2.700000
V_fixture_max= 3.600000
|time   V(typ)   V(min)   V(max)
0s        1.124V     1.392V     952.9mV
200.2ps   1.122V     1.392V     1.085V
350.4ps   1.136V     1.392V     2.024V
450.5ps   1.235V     1.392V     2.516V
710.7ps   2.41V      1.389V     3.246V
930.9ps   2.941V     1.412V     3.51V
1.101ns   3.149V     1.583V     3.561V
1.431ns   3.263V     2.403V     3.585V
1.712ns   3.281V     2.624V     3.592V
4.985ns   3.3V       2.7V       3.6V
[Rising Waveform]
R_fixture= 50.000000
V_fixture= 0.0
V_fixture_min= 0.0
V_fixture_max= 0.0
|time   V(typ)   V(min)   V(max)
0s        403uV      66.05uV    376.3uV
430.4ps   -11.4mV    254.6uV    23.77mV
640.6ps   -13.82mV   449uV      203.1mV
920.9ps   122.4mV    -5.526mV   586.4mV
1.502ns   763.5mV    90.19mV    1.518V
1.922ns   1.26V      462.8mV    2.099V
2.252ns   1.585V     773.5mV    2.358V
2.693ns   1.877V     1.07V      2.5V
3.183ns   2.019V     1.242V     2.564V
4.985ns   2.129V     1.359V     2.614V
[Falling Waveform]
R_fixture= 50.000000
V_fixture= 3.300000
V_fixture_min= 2.700000
V_fixture_max= 3.600000
|time   V(typ)   V(min)   V(max)
0s        3.3V       2.7V       3.6V
530.5ps   3.315V     2.7V       3.563V
680.7ps   3.315V     2.699V     3.403V
991ps     3.202V     2.706V     2.865V
1.542ns   2.481V     2.65V      1.996V
1.942ns   1.958V     2.284V     1.472V
2.272ns   1.662V     1.876V     1.206V
2.633ns   1.403V     1.627V     1.088V
3.063ns   1.266V     1.509V     1.027V
4.985ns   1.124V     1.392V     952.9mV
[Falling Waveform]
R_fixture= 50.000000
V_fixture= 0.0
V_fixture_min= 0.0
V_fixture_max= 0.0
|time   V(typ)   V(min)   V(max)
0s        2.129V     1.359V     2.614V
230.2ps   2.133V     1.358V     2.446V
370.4ps   2.11V      1.358V     2.067V
520.5ps   1.954V     1.359V     1.466V
790.8ps   1.322V     1.363V     605.2mV
1.151ns   458mV      1.234V     84.11mV
1.481ns   89.23mV    807mV      14.03mV
1.842ns   17.77mV    266.3mV    4.961mV
2.122ns   7.633mV    78.67mV    3.253mV
4.985ns   403uV      66.05uV    376.3uV
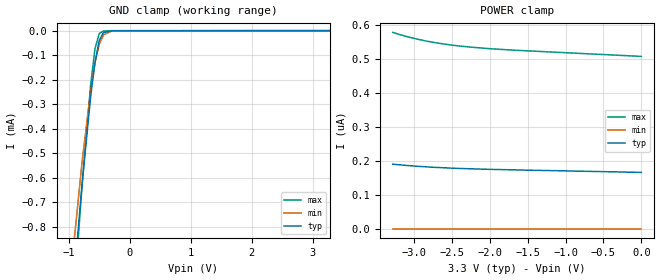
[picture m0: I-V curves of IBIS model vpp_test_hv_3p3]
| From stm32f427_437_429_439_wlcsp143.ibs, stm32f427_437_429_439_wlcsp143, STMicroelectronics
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|   Model vpp_test_hv_3p3
[Model]  vpp_test_hv_3p3
Model_type Input
Polarity   Non-Inverting
Vinl =   0.990000V
Vinh =   2.310000V
C_comp   1.449200pF   1.448200pF   1.452300pF
[Temperature Range]   25.000000   0.125000k   -40.000000
[Pullup Reference]   3.300000V   2.700000V   3.600000V
[Pulldown Reference]   0.0V   0.0V   0.0V
[POWER Clamp Reference]   3.300000V   2.700000V   3.600000V
[GND Clamp Reference]   0.0V   0.0V   0.0V
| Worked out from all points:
|   GND clamp passes 1 mA (typ) near -0.91 V on its own axis
[GND_clamp]
|Voltage   I(typ)   I(min)   I(max)
-3.3V     -8.626mA   -7.544mA   -9.866mA
-1.27V    -2.083mA   -1.784mA   -2.329mA
-1.2V     -1.865mA   -1.595mA   -2.077mA
-1.13V    -1.649mA   -1.409mA   -1.826mA
-1.06V    -1.436mA   -1.224mA   -1.578mA
-780mV    -620.3uA   -531.6uA   -626.3uA
-640mV    -267.3uA   -242.9uA   -218uA
-570mV    -128.4uA   -131.3uA   -73.54uA
-500mV    -39.7uA    -54.89uA   -11.45uA
-430mV    -7.387uA   -16.97uA   -1.191uA
-290mV    -147.5nA   -977.9nA   0A
3.28V     165.9nA    0A         504.4nA
[POWER_clamp]
|Voltage   I(typ)   I(min)   I(max)
-3.28V    190.3nA    0A         579nA
-3.2V     188.5nA    0A         573.4nA
-3.08V    186.2nA    0A         565.8nA
-2.96V    184.1nA    0A         559.3nA
-2.84V    182.4nA    0A         553.6nA
-2.72V    180.8nA    0A         548.7nA
-2.56V    179.1nA    0A         543.3nA
-2.44V    178nA      0A         539.9nA
-2.28V    176.7nA    0A         536.1nA
-2V       175nA      0A         530.9nA
-1.68V    173.4nA    0A         526.5nA
0V        166nA      0A         508.2nA
